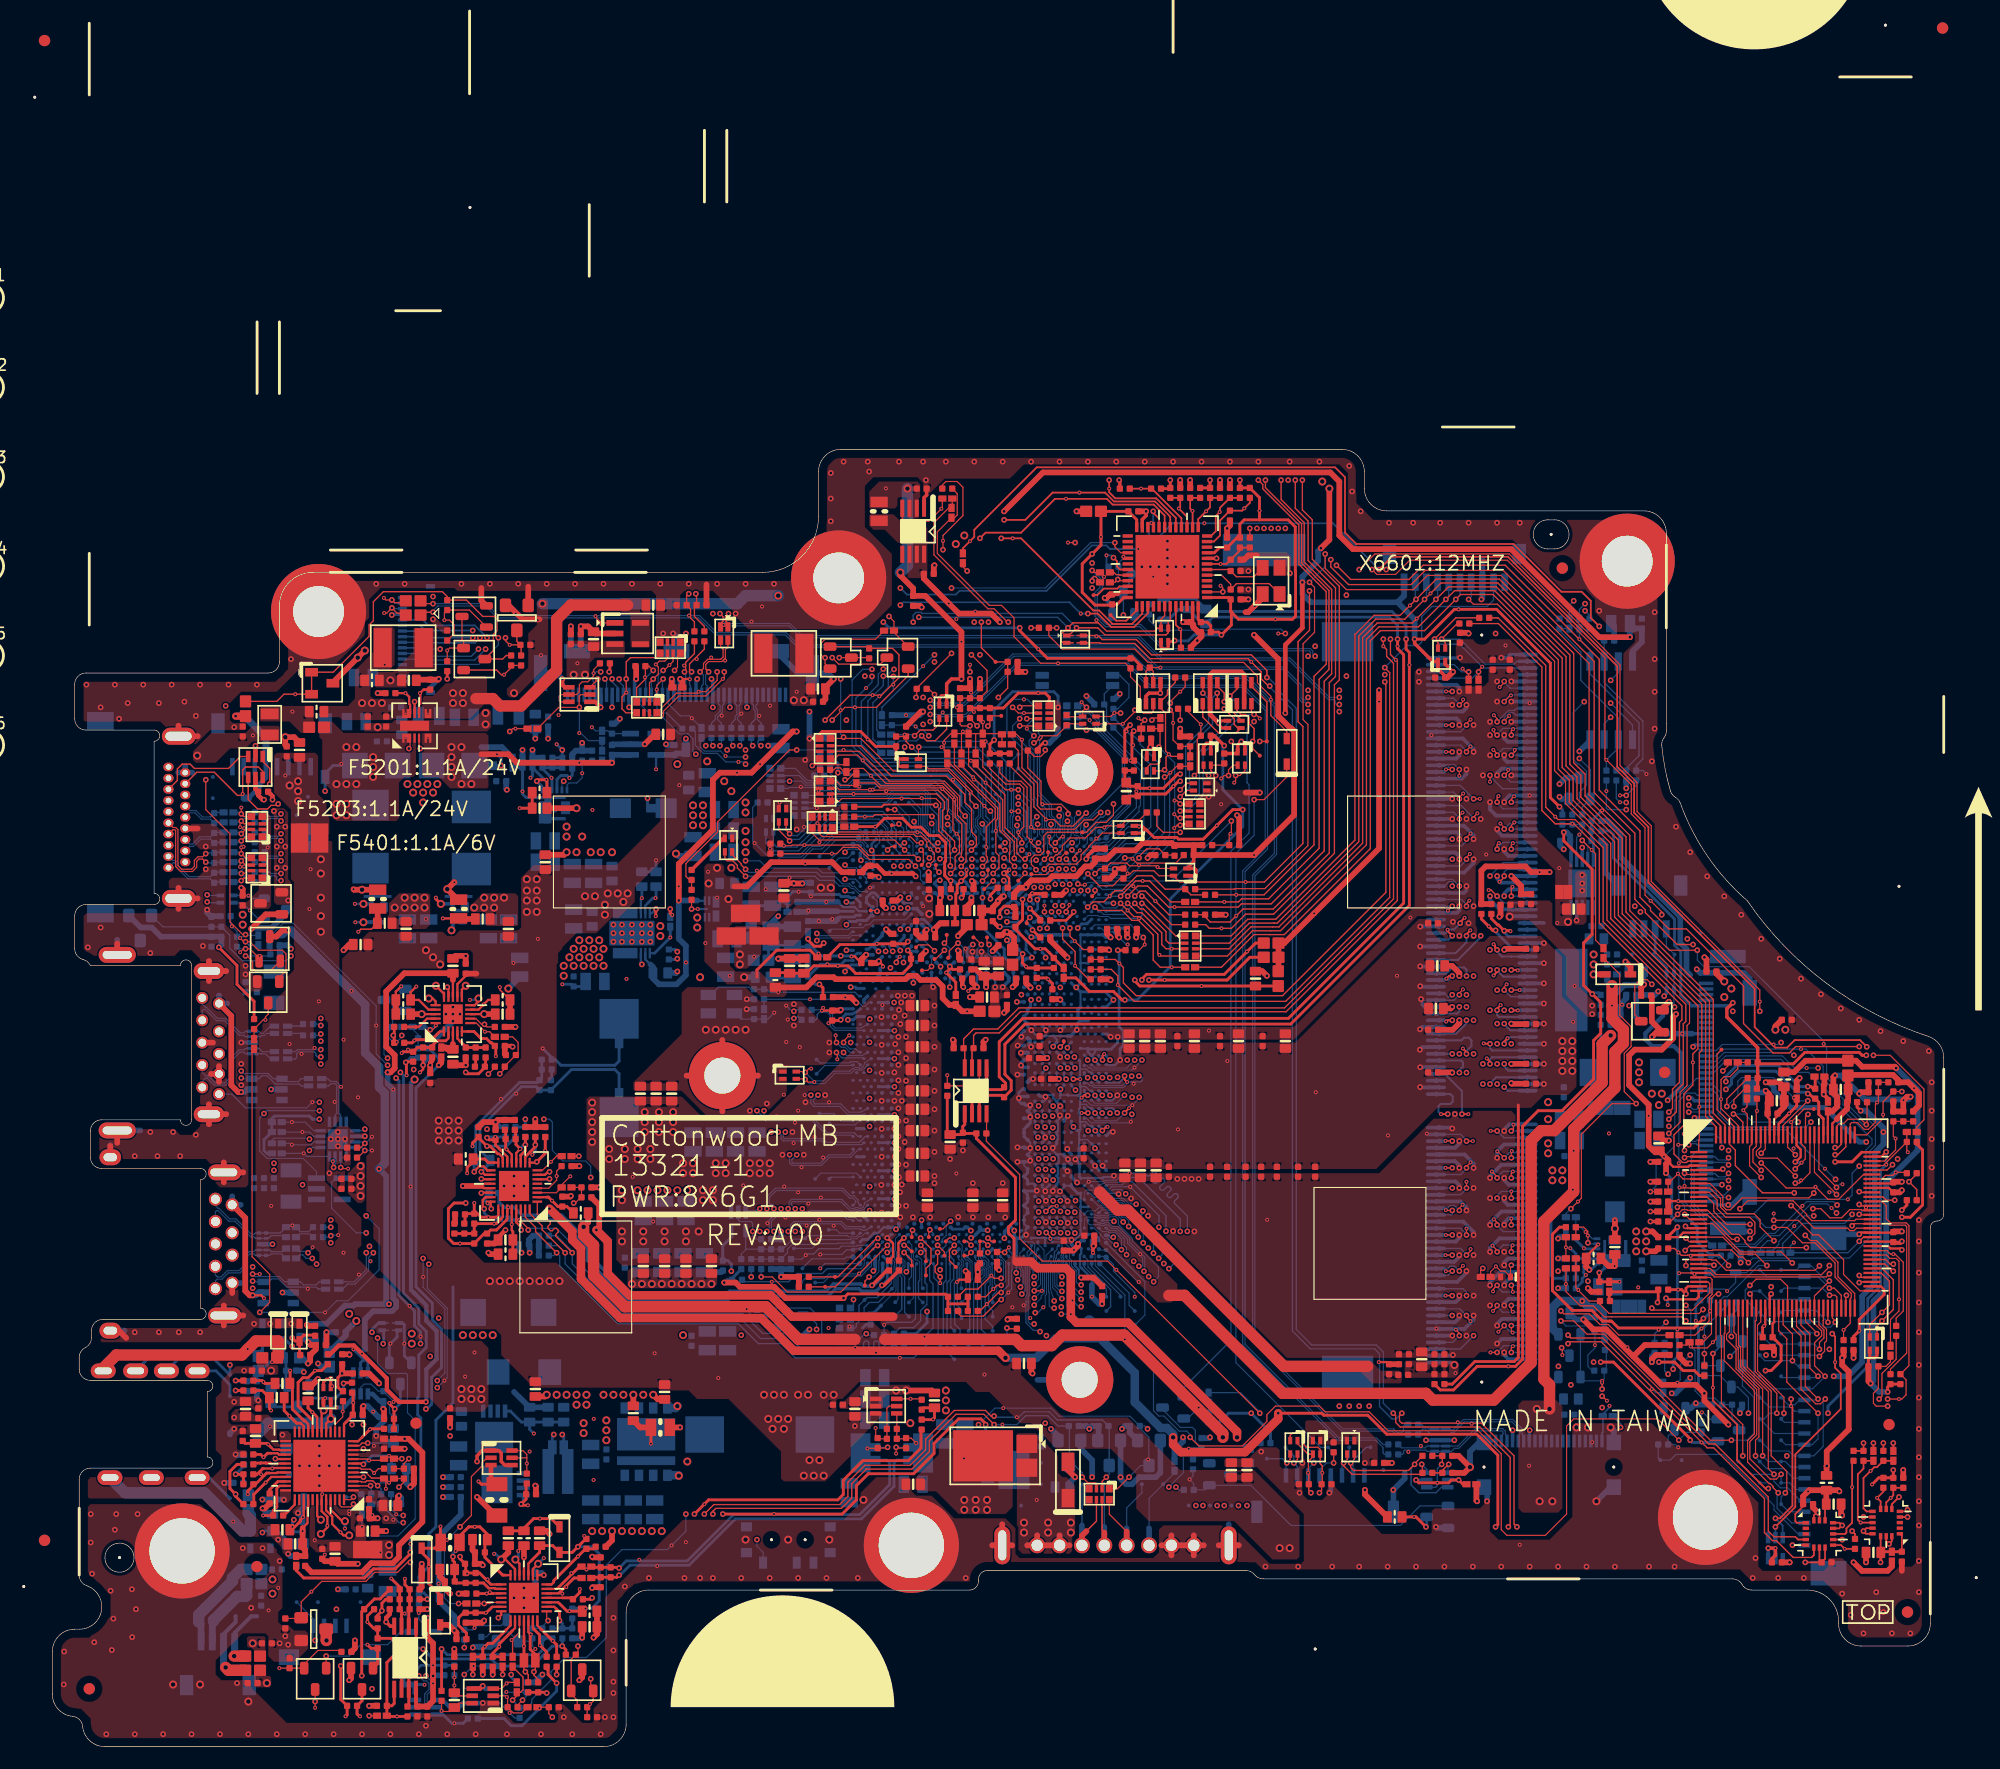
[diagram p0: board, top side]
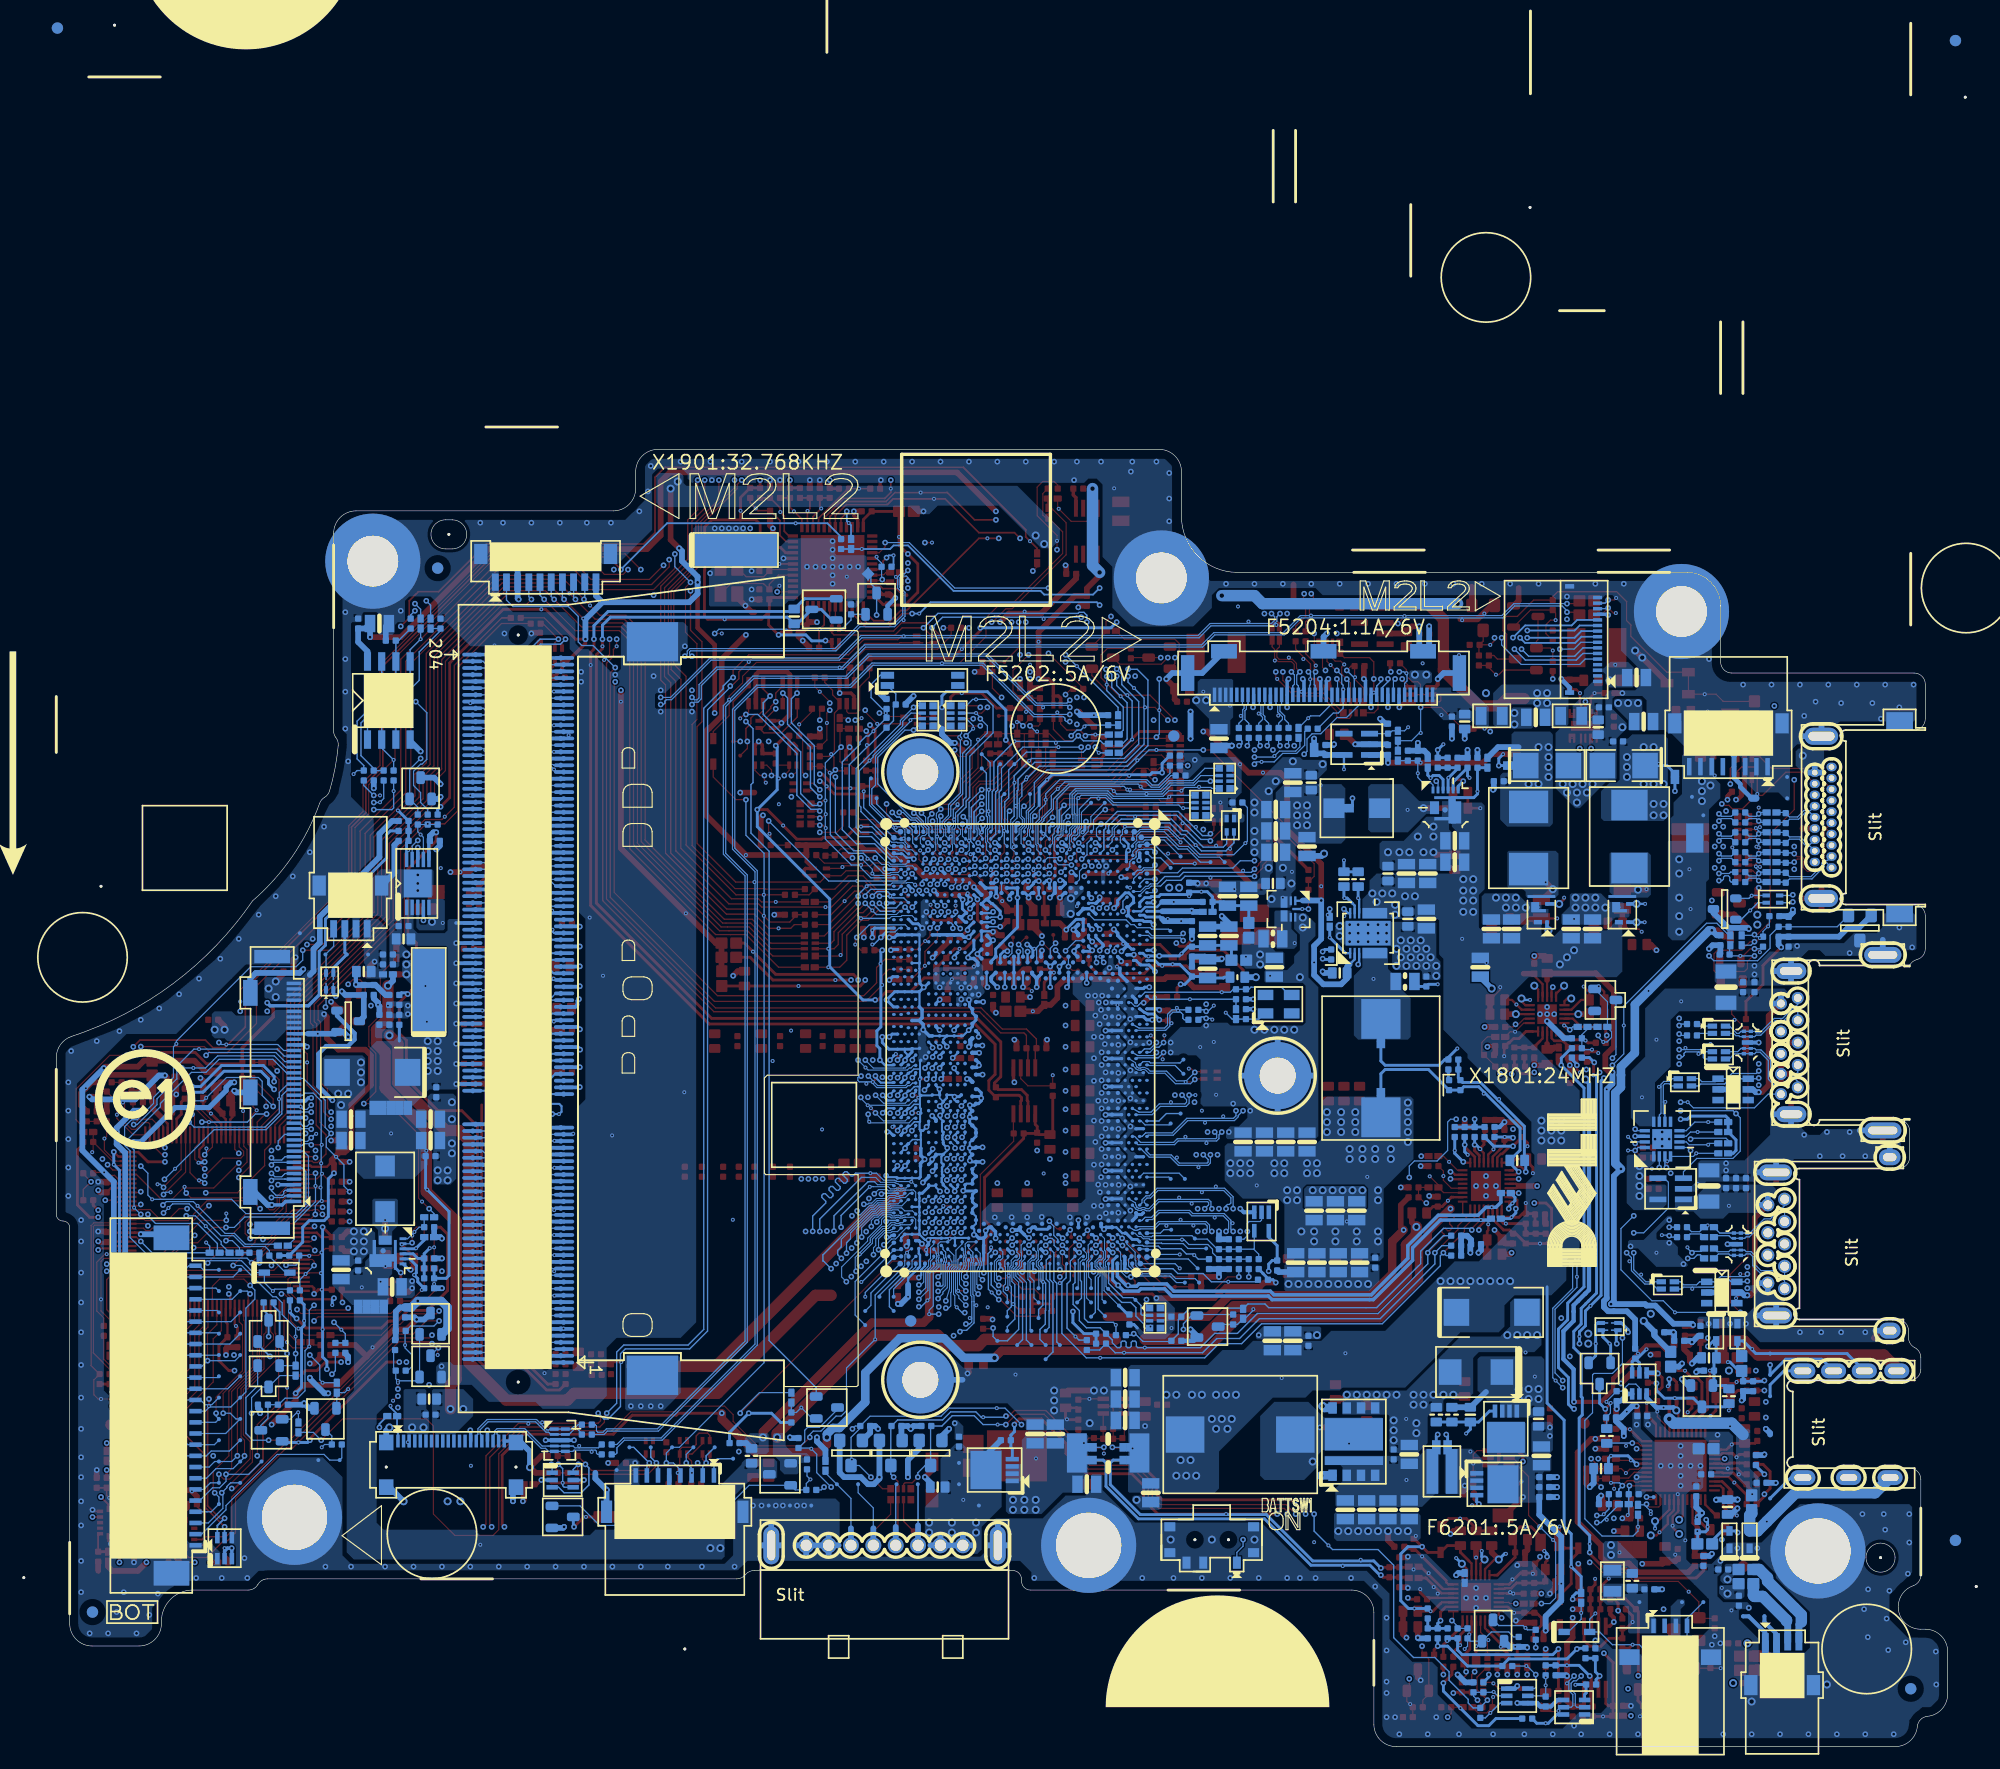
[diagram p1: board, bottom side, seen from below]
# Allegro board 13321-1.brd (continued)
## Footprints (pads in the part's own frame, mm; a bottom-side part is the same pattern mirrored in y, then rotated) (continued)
QFN48G7-G5D7H26
  rect 0.305x0.914 smd: 1(2.75,3.551) 12(-2.75,3.551) 25(-2.75,-3.551) 36(2.75,-3.551)
  rect 0.305x0.94 smd: 2(2.25,3.538) 3(1.75,3.538) 4(1.25,3.538) 5(0.75,3.538) 6(0.25,3.538) 7(-0.25,3.538) 8(-0.75,3.538) 9(-1.25,3.538) 10(-1.75,3.538) 11(-2.25,3.538) 26(-2.25,-3.538) 27(-1.75,-3.538) 28(-1.25,-3.538) 29(-0.75,-3.538) 30(-0.25,-3.538) 31(0.25,-3.538) 32(0.75,-3.538) 33(1.25,-3.538) 34(1.75,-3.538) 35(2.25,-3.538)
  rect 0.914x0.305 smd: 13(-3.551,2.75) 24(-3.551,-2.75) 37(3.551,-2.75) 48(3.551,2.75)
  rect 0.94x0.305 smd: 14(-3.538,2.25) 15(-3.538,1.75) 16(-3.538,1.25) 17(-3.538,0.75) 18(-3.538,0.25) 19(-3.538,-0.25) 20(-3.538,-0.75) 21(-3.538,-1.25) 22(-3.538,-1.75) 23(-3.538,-2.25) 38(3.538,-2.25) 39(3.538,-1.75) 40(3.538,-1.25) 41(3.538,-0.75) 42(3.538,-0.25) 43(3.538,0.25) 44(3.538,0.75) 45(3.538,1.25) 46(3.538,1.75) 47(3.538,2.25)
  rect 5.69x5.69 smd: 49(0,0)
QFN48J6-G465H40
  rect 0.203x0.965 smd: 1(2.2,3.025) 2(1.8,3.025) 3(1.4,3.025) 4(1,3.025) 5(0.6,3.025) 6(0.2,3.025) 7(-0.2,3.025) 8(-0.6,3.025) 9(-1,3.025) 10(-1.4,3.025) 11(-1.8,3.025) 12(-2.2,3.025) 25(-2.2,-3.025) 26(-1.8,-3.025) 27(-1.4,-3.025) 28(-1,-3.025) 29(-0.6,-3.025) 30(-0.2,-3.025) 31(0.2,-3.025) 32(0.6,-3.025) 33(1,-3.025) 34(1.4,-3.025) 35(1.8,-3.025) 36(2.2,-3.025)
  rect 0.965x0.203 smd: 13(-3.025,2.2) 14(-3.025,1.8) 15(-3.025,1.4) 16(-3.025,1) 17(-3.025,0.6) 18(-3.025,0.2) 19(-3.025,-0.2) 20(-3.025,-0.6) 21(-3.025,-1) 22(-3.025,-1.4) 23(-3.025,-1.8) 24(-3.025,-2.2) 37(3.025,-2.2) 38(3.025,-1.8) 39(3.025,-1.4) 40(3.025,-1) 41(3.025,-0.6) 42(3.025,-0.2) 43(3.025,0.2) 44(3.025,0.6) 45(3.025,1) 46(3.025,1.4) 47(3.025,1.8) 48(3.025,2.2)
  rect 4.648x4.648 smd: 49(0,0)
R402H14
  custom 0.14x0.14 smd: 1(0,0.445) 2(0,-0.445)
R402H16
  custom 0.14x0.14 smd: 1(0,0.445) 2(0,-0.445)
R603H22
  custom 0.197x0.197 smd: 1(0,0.66) 2(0,-0.66)
R603H24
  custom 0.197x0.197 smd: 1(0,0.66) 2(0,-0.66)
R805H24
  rect 1.549x0.94 smd: 1(0,0.838) 2(0,-0.838)
R1206H28
  rect 1.854x1.27 smd: 1(0,1.397) 2(0,-1.397)
R2512H32
  rect 3.505x1.778 smd: 1(0,2.794) 2(0,-2.794)
R3720H40
  rect 4.013x1.041 smd: 1(0,0.867) 2(0,-0.867)
SC70-5H44
  rect 0.406x1.219 smd: 1(0.65,0.826) 2(0,0.826) 3(-0.65,0.826) 4(-0.65,-0.826) 5(0.65,-0.826)
SC70-6H44
  rect 0.406x1.016 smd: 1(-0.65,-0.94) 2(0,-0.94) 3(0.65,-0.94) 4(0.65,0.94) 5(0,0.94) 6(-0.65,0.94)
SKT-HDMI23-178128-2
  oval 0.762x0.914 hole 0.508: 1(-4.5,6.08) 2(-4,7.58) 3(-3.5,6.08) 4(-3,7.58) 5(-2.5,6.08) 6(-2,7.58) 7(-1.5,6.08) 8(-1,7.58) 9(-0.5,6.08) 10(0,7.58) 11(0.5,6.08) 12(1,7.58) 13(1.5,6.08) 14(2,7.58) 15(2.5,6.08) 16(3,7.58) 17(3.5,6.08) 18(4,7.58) 19(4.5,6.08)
  oval 1.524x3.023 hole 0.813x2.362: 20(-7.25,6.98) 21(7.25,6.98)
  rect 1.6x2.388 smd: 22(-8.6,0) 23(8.6,0)
SKT-USB13-158172-1
  round 1.168 hole 0.813: 1(3.5,10.9) 2(1,10.9) 3(-1,10.9) 4(-3.5,10.9) 5(-4,9.4) 6(-2,9.4) 7(0,9.4) 8(2,9.4) 9(4,9.4)
  oval 1.422x2.972 hole 0.711x2.413: 10(6.4,10.15) 11(-6.4,10.15)
  oval 1.422x1.93 hole 0.711x1.219: 12(-7.75,0) 13(7.75,0)
SKT-USB14-160155-U
  round 1.067 hole 0.711: 1(3.5,9.1) 2(1,9.1) 3(-1,9.1) 4(-2.8,9.1) 5(-4,7.6) 6(-2,7.6) 7(0,7.6) 8(2,7.6) 9(4,7.6) D1(-4.6,9.1)
  oval 1.422x2.718 hole 0.711x2.007: 11(6.4,8.2) 12(-6.4,8.2)
  oval 1.422x3.327 hole 0.711x2.616: 13(7.85,0) 14(-7.85,0)
SMD-ARES4H18
  rect 0.356x0.66 smd: 1(-0.325,-0.599) 2(0.325,-0.599) 3(0.325,0.599) 4(-0.325,0.599)
SMD-ARES4H20
  rect 0.356x0.66 smd: 1(-0.325,-0.599) 2(0.325,-0.599) 3(0.325,0.599) 4(-0.325,0.599)
SMD-OSC2H56
  rect 1.194x0.61 smd: 1(-3.147,-0.457) 2(3.147,-0.457) 3(3.147,0.457) 4(-3.147,0.457)
SMPC4665-3P-UH48
  rect 1.626x1.854 smd: 1(1.066,0) 2(-1.066,0)
  rect 4.572x5.359 smd: 3(0,3.909)
SOD123FLAKH40
  rect 1.143x1.651 smd: A(0,1.622) K(0,-1.622)
SOD323AKH38
  rect 0.559x1.016 smd: A(0,1.143) K(0,-1.143)
SOD323AKH40
  rect 0.559x1.016 smd: A(0,1.143) K(0,-1.143)
SOD323AKH42
  rect 0.559x1.016 smd: A(0,1.143) K(0,-1.143)
SOD323AKH44
  rect 0.559x1.016 smd: A(0,1.143) K(0,-1.143)
SOD882-10D6-1H20
  custom 0.114x0.114 smd: 1(0,0.445) 2(0,-0.445)
SOD-523-4H28
  rect 0.559x0.864 smd: 1(0,0.778) 2(0,-0.778)
SOIC8-1H86
  rect 0.635x1.651 smd: 1(-1.905,-3.493) 2(-0.635,-3.493) 3(0.635,-3.493) 4(1.905,-3.493) 5(1.905,3.493) 6(0.635,3.493) 7(-0.635,3.493) 8(-1.905,3.493)
SON5Z3025H18
  rect 0.33x0.33 smd: 1(-0.923,-0.503) 4(0.713,-0.503)
  rect 0.406x0.711 smd: 2(-0.924,0.31)
  custom 0.229x0.229 smd: 3(0.417,0.254)
  rect 0.254x2.489 smd: 5(1.375,0)
SON14J3020-G2610H34
  rect 0.025x0.025 smd: 1(1.2,1.105) 6(-0.8,1.105) 9(-0.8,-1.105) 14(1.2,-1.105)
  custom 0.151x0.151 smd: 2(0.8,1.105) 7(-1.2,1.105) 8(-1.2,-1.105) 13(0.8,-1.105)
  rect 0.203x0.813 smd: 3(0.4,1.105) 4(0,1.105) 5(-0.4,1.105) 10(-0.4,-1.105) 11(0,-1.105) 12(0.4,-1.105)
  rect 2.591x0.889 smd: 15(0,0)
SOT23-2D4-312H44
  custom 0.191x0.191 smd: 1(-0.984,-0.953) 2(0.984,-0.953) 3(0,0.953)
SOT23-2D4-312H48
  custom 0.191x0.191 smd: 1(-0.984,-0.953) 2(0.984,-0.953) 3(0,0.953)
SOT23-2D8-123H52
  custom 0.254x0.254 smd: 1(0,1.118) 2(-1.016,-1.118) 3(1.016,-1.118)
SOT23-2D8-312H56
  custom 0.254x0.254 smd: 1(-1.016,-1.118) 2(1.016,-1.118) 3(0,1.118)
SOT23CBE2D4H44
  custom 0.191x0.191 smd: B(-0.984,-0.953) C(0,0.953) E(0.984,-0.953)
SOT23CBE2D6H46
  custom 0.165x0.165 smd: B(-0.95,-1.092) C(0,1.092) E(0.95,-1.092)
SOT23DGS2D4H44
  custom 0.191x0.191 smd: D(0,0.953) G(-0.984,-0.953) S(0.984,-0.953)
SOT23DGS2D4H48
  custom 0.191x0.191 smd: D(0,0.953) G(-0.984,-0.953) S(0.984,-0.953)
SOT23DGS2D8H56
  custom 0.254x0.254 smd: D(0,1.118) G(-1.016,-1.118) S(1.016,-1.118)
SOT-6H58
  rect 0.584x1.016 smd: 1(-0.953,-1.346) 2(0,-1.346) 3(0.953,-1.346) 4(0.953,1.346) 5(0,1.346) 6(-0.953,1.346)
SOT-23-5H51
  rect 0.508x1.524 smd: 1(-0.95,-1.143) 2(0,-1.143) 3(0.95,-1.143) 4(0.95,1.143) 5(-0.95,1.143)
SOT-23-5H56
  rect 0.508x1.524 smd: 1(-0.95,-1.143) 2(0,-1.143) 3(0.95,-1.143) 4(0.95,1.143) 5(-0.95,1.143)
SOT-23-5H58
  rect 0.508x1.524 smd: 1(-0.95,-1.143) 2(0,-1.143) 3(0.95,-1.143) 4(0.95,1.143) 5(-0.95,1.143)
SOT-23-9H44
  custom 0.178x0.178 smd: 1(-0.95,-0.999) 2(0.95,-0.999) 3(0,0.999)
SOT-23-10H44
  rect 0.762x1.143 smd: 1(-0.984,-0.953) 2(0.984,-0.953) 3(0,0.953)
SOT-363H44
  rect 0.406x1.016 smd: 1(-0.65,-0.94) 2(0,-0.94) 3(0.65,-0.94) 4(0.65,0.94) 5(0,0.94) 6(-0.65,0.94)
SPR7732H229
  rect 7.391x2.896 smd: 1(-1.6,0)
STF237R125H42
  round 6.02 hole 3.175: 1(0,0)
TPAD14-OP
  round 0.356 smd: 1(0,0)
TSOIC8H48
  rect 0.356x1.524 smd: 1(-0.975,-2.819) 2(-0.325,-2.819) 3(0.325,-2.819) 4(0.974,-2.819) 5(0.975,2.819) 6(0.325,2.819) 7(-0.325,2.819) 8(-0.975,2.819)
unnamed
  round 1.016 smd: (0,0)

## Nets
3V5V_CT1: C3602.1 U3601.12
3V5V_CT2: C3603.1 U3601.10
3V5V_S0_ON: R3609.2 U3601.3 U3601.5
3V_5V_EN: D3602.1 PR4506.1 PR4515.1 R3602.1 R3603.1
3V_5V_POK: PR4534.2 PU4503.7 R1728.2
3V_5V_POK#: Q1701.5 Q1701.6 R1726.1
3V_5V_POK_C: Q1701.2 R1727.2 R1728.1 R1729.1
3V_FEEDBACK: PG4535.2 PR4512.1 PR4535.1
5V_HDMI_R_S5: F5401.1 R5409.2 R5423.2
5V_HDMI_S5: C5401.1 F5401.2 HDMI1.18
5V_PWR_2: PC4524.1 PU4503.13 R2915.1
5V_S0: C3601.1 C5605.1 C5606.1 D5401.3 EC8615.1 EC8616.1 F5203.1 F6201.1 HDD1.8 HDD1.9 HDD1.10 HDD1.11 Q5403.G R2612.1 R2703.2 R2704.1 R5233.1 R5413.1 R5423.1 R6205.1 R6216.1 U3601.13 U3601.14
5V_S5: C3502.1 C3504.1 EC8612.1 EC8614.1 IOBD1.37 IOBD1.38 IOBD1.39 IOBD1.40 PC4419.1 PC4426.1 PC4518.1 PC4705.1 PG4532.1 PL4501.2 PR4203.1 PR4437.1 PR4460.1 PR4461.1 PR4624.2 PR4917.2 PT4502.1 PU4402.8 PU4701.2 Q6201.E R1208.1 R3504.1 R3505.1 R3507.1 R5409.1 U2101.1 U3502.5 U3503.1 U3601.1 U3601.2 U3601.4
+3V_1D5V_AVDD: C2715.1 HDA27.40 R2705.2 R2710.2
+3V_AVDD: C2701.1 C2716.1 C2717.1 C2719.1 HDA27.1 HDA27.9 HDA27.36 R2701.2 R2722.2 R2918.1
+5V_AVDD: C2710.1 C2711.1 HDA27.26 R2703.1
+5V_KB_BL: AFTP6248.1 C6202.1 F6201.2 KBLIT1.1 R6205.2
+5V_PVDD: C2706.1 C2707.1 C2708.1 C2709.1 HDA27.41 HDA27.46 R2704.2
+V1.05A_AOSCSUS: CPU1.AB8 TP2109.1
+V1.05A_SUS_PCH: CPU1.AD8 CPU1.AD10 TP2106.1
+V1.05A_USB2SUS: CPU1.AH13 TP2108.1
+V1.05A_VCCUSB3SUS: CPU1.J13 TP2107.1
+V1.05DX_MODPHY_PCH: C1101.1 C1102.1 CPU1.K9 CPU1.L10 CPU1.M9 R1101.2
+V1.05S_AIDLE: C2105.1 CPU1.N8 CPU1.P9 R2105.2
+V1.05S_APLLOPI: C1109.1 C1110.1 C1124.1 CPU1.AA21 CPU1.W21 R1102.2
+V1.05S_ASATA3PLL: C1105.1 C1106.1 C1107.1 CPU1.B11 L1102.2 R1904.2 R1906.2
+V1.05S_AUSB3PLL: C1103.1 C1104.1 C1123.1 CPU1.B18 CPU1.B27 L1101.2 R1601.1
+V1.05S_AXCK_DCB: C1111.1 C1112.1 C1125.1 CPU1.J18 CPU1.K19 L1103.2
+V1.05S_AXCK_LCPLL: C1113.1 C1114.1 CPU1.A20 L1104.2 R1803.2
+V1.05S_CORE_PCH: C1117.1 C1118.1 C1119.1 CPU1.AE8 CPU1.AF22 CPU1.H11 CPU1.H15 CPU1.J11 R1105.2
+V1.05S_SSCF100: C2137.1 CPU1.J17 R2117.2
+V1.05S_SSCFF: C2138.1 CPU1.R21 CPU1.T21 R2118.2
+V3.3A_1.5A_HDA: C2116.1 CPU1.AH14 R2108.2
+V3.3A_DSW_P: C2101.1 C2136.1 CPU1.AH10 R2101.2
+V3.3A_PSUS: C1108.1 CPU1.AA9 CPU1.AC9 CPU1.AE20 CPU1.AE21 R1103.2
+V3.3S_1.8S_LPSS_SDIO: C2104.1 CPU1.T9 CPU1.U8 R2103.1
+V3.3S_PCORE: C2123.1 CPU1.V8 CPU1.W9 R2112.2
+VCCIOA_OUT: CPU1.E20 R801.1
+VCCRTCEXT: C2110.1 CPU1.AE7
GND: AFTP2604.1 AFTP4204.1 AFTP4205.1 AFTP4308.1 AFTP4309.1 AFTP4310.1 AFTP6226.1 AFTP6235.1 BATSW1.2 BATSW1.3 BATSW1.4 BATSW1.5 BATSW1.6 BATSW1.7 BATT1.7 BATT1.8 BATT1.9 BATT1.10 C701.2 C702.2 C703.2 C1001.2 C1002.2 C1003.2 C1004.2 C1005.2 C1006.2 C1017.2 C1018.2 C1019.2 C1020.2 C1101.2 C1102.2 C1103.2 C1104.2 C1105.2 C1106.2 C1107.2 C1108.2 C1109.2 C1110.2 C1111.2 C1112.2 C1113.2 C1114.2 C1115.2 C1116.2 C1117.2 C1118.2 C1119.2 C1120.2 C1121.2 C1122.2 C1123.2 C1124.2 C1125.2 C1201.2 C1202.2 C1203.2 C1204.2 C1205.2 C1206.2 C1207.2 C1208.2 C1209.2 C1210.2 C1211.2 C1212.2 C1213.2 C1214.2 C1215.2 C1216.2 C1218.2 C1220.2 C1221.2 C1222.2 C1701.2 C1801.1 C1802.1 C1901.2 C1902.2 C1903.1 C1904.1 C2104.2 C2105.2 C2109.2 C2110.2 C2114.2 C2116.2 C2123.2 C2128.2 C2135.2 C2136.2 C2137.2 C2138.2 C2141.2 C2142.2 C2147.2 C2401.2 C2406.2 C2407.2 C2408.2 C2409.2 C2410.2 C2411.2 C2412.2 C2413.2 C2415.1 C2416.2 C2418.2 C2421.2 C2422.2 C2501.2 C2502.2 C2503.2 C2601.2 C2602.2 C2603.2 C2604.2 C2605.2 C2608.2 C2609.2 C2610.2 C2701.2 C2704.1 C2706.2 C2707.2 C2708.2 C2709.2 C2716.2 C2717.2 C2718.2 C2719.2 C2723.1 C2901.2 C3404.2 C3409.2 C3502.2 C3503.2 C3504.2 C3505.2 C3521.2 C3522.2 C3601.2 C3602.2 C3603.2 C3605.2 C3801.2 C3802.2 C5202.2 C5203.2 C5204.2 C5205.2 C5206.2 C5208.2 C5209.1 C5211.2 C5212.2 C5214.2 C5215.2 C5401.2 C5605.2 C5606.2 C6201.2 C6202.2 C6401.2 C6402.2 C6601.2 C6602.2 C6603.2 C6604.2 C6605.2 C6606.2 C6607.2 C6608.2 C6609.2 C6610.2 C6611.2 C6701.2 C6702.2 C6703.2 CPU1.A11 CPU1.A14 CPU1.A18 CPU1.A24 CPU1.A28 CPU1.A32 CPU1.A36 CPU1.A40 CPU1.A44 CPU1.A48 CPU1.A52 CPU1.A56 CPU1.AA1 CPU1.AA58 CPU1.AB7 CPU1.AB10 CPU1.AB20 CPU1.AB22 CPU1.AC61 CPU1.AD3 CPU1.AD21 CPU1.AD63 CPU1.AE5 CPU1.AE10 CPU1.AE58 CPU1.AF11 CPU1.AF12 CPU1.AF14 CPU1.AF15 CPU1.AF17 CPU1.AF18 CPU1.AG1 CPU1.AG11 CPU1.AG21 CPU1.AG23 CPU1.AG60 CPU1.AG61 CPU1.AG62 CPU1.AG63 CPU1.AH16 CPU1.AH17 CPU1.AH19 CPU1.AH20 CPU1.AH22 CPU1.AH24 CPU1.AH28 CPU1.AH30 CPU1.AH32 CPU1.AH34 CPU1.AH36 CPU1.AH38 CPU1.AH40 CPU1.AH42 CPU1.AH44 CPU1.AH46 CPU1.AH49 CPU1.AH51 CPU1.AH53 CPU1.AH55 CPU1.AH57 CPU1.AJ13 CPU1.AJ14 CPU1.AJ23 CPU1.AJ25 CPU1.AJ27 CPU1.AJ29 CPU1.AJ35 CPU1.AJ39 CPU1.AJ41 CPU1.AJ43 CPU1.AJ45 CPU1.AJ47 CPU1.AJ50 CPU1.AJ52 CPU1.AJ54 CPU1.AJ56 CPU1.AJ58 CPU1.AJ60 CPU1.AJ63 CPU1.AK3 CPU1.AK23 CPU1.AK52 CPU1.AL10 CPU1.AL13 CPU1.AL17 CPU1.AL20 CPU1.AL22 CPU1.AL23 CPU1.AL26 CPU1.AL29 CPU1.AL31 CPU1.AL33 CPU1.AL36 CPU1.AL39 CPU1.AL40 CPU1.AL45 CPU1.AL46 CPU1.AL51 CPU1.AL52 CPU1.AL54 CPU1.AL57 CPU1.AL60 CPU1.AL61 CPU1.AM1 CPU1.AM17 CPU1.AM23 CPU1.AM31 CPU1.AM52 CPU1.AN7 CPU1.AN17 CPU1.AN23 CPU1.AN31 CPU1.AN32 CPU1.AN35 CPU1.AN36 CPU1.AN39 CPU1.AN40 CPU1.AN42 CPU1.AN43 CPU1.AN45 CPU1.AN46 CPU1.AN48 CPU1.AN49 CPU1.AN51 CPU1.AN52 CPU1.AN60 CPU1.AN63 CPU1.AP3 CPU1.AP10 CPU1.AP17 CPU1.AP20 CPU1.AP22 CPU1.AP23 CPU1.AP26 CPU1.AP29 CPU1.AP31 CPU1.AP38 CPU1.AP39 CPU1.AP48 CPU1.AP52 CPU1.AP54 CPU1.AP57 CPU1.AR5 CPU1.AR11 CPU1.AR15 CPU1.AR17 CPU1.AR23 CPU1.AR31 CPU1.AR33 CPU1.AR39 CPU1.AR43 CPU1.AR49 CPU1.AR52 CPU1.AT13 CPU1.AT35 CPU1.AT37 CPU1.AT40 CPU1.AT42 CPU1.AT43 CPU1.AT46 CPU1.AT49 CPU1.AT61 CPU1.AT62 CPU1.AT63 CPU1.AU1 CPU1.AU16 CPU1.AU18 CPU1.AU20 CPU1.AU22 CPU1.AU24 CPU1.AU26 CPU1.AU28 CPU1.AU30 CPU1.AU33 CPU1.AU51 CPU1.AU53 CPU1.AU55 CPU1.AU57 CPU1.AU59 CPU1.AV8 CPU1.AV14 CPU1.AV16 CPU1.AV20 CPU1.AV24 CPU1.AV28 CPU1.AV33 CPU1.AV34 CPU1.AV36 CPU1.AV39 CPU1.AV41 CPU1.AV43 CPU1.AV46 CPU1.AV49 CPU1.AV51 CPU1.AV55 CPU1.AV59 CPU1.AW4 CPU1.AW16 CPU1.AW24 CPU1.AW33 CPU1.AW35 CPU1.AW37 CPU1.AW40 CPU1.AW42 CPU1.AW44 CPU1.AW47 CPU1.AW50 CPU1.AW51 CPU1.AW59 CPU1.AW60 CPU1.AY4 CPU1.AY6 CPU1.AY11 CPU1.AY16 CPU1.AY18 CPU1.AY22 CPU1.AY24 CPU1.AY26 CPU1.AY30 CPU1.AY33 CPU1.AY51 CPU1.AY53 CPU1.AY57 CPU1.AY59 CPU1.B4 CPU1.B20 CPU1.B24 CPU1.B26 CPU1.B28 CPU1.B32 CPU1.B36 CPU1.B40 CPU1.B44 CPU1.B48 CPU1.B52 CPU1.B56 CPU1.B60 CPU1.C11 CPU1.C14 CPU1.C18 CPU1.C20 CPU1.C25 CPU1.C27 CPU1.C38 CPU1.C39 CPU1.C57 CPU1.D2 CPU1.D5 CPU1.D8 CPU1.D12 CPU1.D14 CPU1.D18 CPU1.D21 CPU1.D23 CPU1.D25 CPU1.D26 CPU1.D27 CPU1.D29 CPU1.D30 CPU1.D31 CPU1.D33 CPU1.D34 CPU1.D35 CPU1.D37 CPU1.D38 CPU1.D39 CPU1.D41 CPU1.D42 CPU1.D43 CPU1.D45 CPU1.D46 CPU1.D47 CPU1.D49 CPU1.D50 CPU1.D51 CPU1.D53 CPU1.D54 CPU1.D55 CPU1.D57 CPU1.D59 CPU1.D62 CPU1.D63 CPU1.E11 CPU1.E17 CPU1.F20 CPU1.F26 CPU1.F30 CPU1.F34 CPU1.F38 CPU1.F42 CPU1.F46 CPU1.F50 CPU1.F54 CPU1.F58 CPU1.F61 CPU1.G3 CPU1.G5 CPU1.G6 CPU1.G8 CPU1.G18 CPU1.G22 CPU1.H13 CPU1.H17 CPU1.H57 CPU1.J10 CPU1.J22 CPU1.J59 CPU1.J63 CPU1.K1 CPU1.K12 CPU1.L7 CPU1.L13 CPU1.L15 CPU1.L17 CPU1.L18 CPU1.L20 CPU1.L58 CPU1.L61 CPU1.M22 CPU1.N3 CPU1.N10 CPU1.N21 CPU1.P22 CPU1.P59 CPU1.P62 CPU1.P63 CPU1.R8 CPU1.R10 CPU1.R22 CPU1.T1 CPU1.T58 CPU1.U9 CPU1.U20 CPU1.U22 CPU1.U61 CPU1.V3 CPU1.V7 CPU1.V10 CPU1.V23 CPU1.V58 CPU1.W20 CPU1.W22 CPU1.Y10 CPU1.Y59 CPU1.Y63 D2601.A D4301.1 D4302.1 D4303.1 DB1.1 DB1.3 DB1.11 DB1.12 DCIN1.1 DCIN1.2 DCIN1.3 DCIN1.9 DCIN1.10 DIMM1.2 DIMM1.3 DIMM1.8 DIMM1.9 DIMM1.11 DIMM1.13 DIMM1.14 DIMM1.19 DIMM1.20 DIMM1.25 DIMM1.26 DIMM1.28 DIMM1.31 DIMM1.32 DIMM1.37 DIMM1.38 DIMM1.43 DIMM1.44 DIMM1.46 DIMM1.48 DIMM1.49 DIMM1.54 DIMM1.55 DIMM1.60 DIMM1.61 DIMM1.63 DIMM1.65 DIMM1.66 DIMM1.71 DIMM1.72 DIMM1.127 DIMM1.128 DIMM1.133 DIMM1.134 DIMM1.136 DIMM1.138 DIMM1.139 DIMM1.144 DIMM1.145 DIMM1.150 DIMM1.151 DIMM1.153 DIMM1.155 DIMM1.156 DIMM1.161 DIMM1.162 DIMM1.167 DIMM1.168 DIMM1.170 DIMM1.172 DIMM1.173 DIMM1.178 DIMM1.179 DIMM1.184 DIMM1.185 DIMM1.187 DIMM1.189 DIMM1.190 DIMM1.195 DIMM1.196 DIMM1.205 DIMM1.206 EC701.2 EC702.2 EC1701.1 EC1702.2 EC1703.2 EC1704.2 EC1705.2 EC1706.2 EC1707.2 EC1801.2 EC1802.2 EC1901.1 EC2501.2 EC2502.2 EC2503.2 EC2701.2 EC2703.2 EC2704.2 EC2705.2 EC2706.2 EC2707.2 EC2708.2 EC2709.2 EC2901.2 EC2902.2 EC2903.2 EC2904.2 EC4201.2 EC4202.2 EC4301.2 EC4302.2 EC4303.2 EC4304.2 EC4305.1 EC4602.2 EC4701.2 EC4702.2 EC5205.2 EC5206.2 EC5207.2 EC5210.2 EC5211.2 EC6201.2 EC6202.2 EC6203.2 EC6204.2 EC8601.2 EC8602.2 EC8603.2 EC8604.2 EC8605.2 EC8606.2 EC8607.2 EC8608.2 EC8609.2 EC8610.2 EC8611.2 EC8612.2 EC8613.2 EC8614.2 EC8615.2 EC8616.2 EC8617.2 EC8618.2 EC8619.2 EC8620.2 EC8621.2 EC8622.2 EC8623.2 EC8624.2 EC8625.2 EC8626.2 EC8627.2 EC8628.2 EC8629.2 EC8630.2 EC8631.2 EC8632.2 EC8633.2 EC8634.2 EC8635.2 EC8636.2 EC8637.2 EC8638.2 ED1217.2 ED2901.1 ED2902.1 ED2903.1 ED2904.1 ED2905.1 ED2906.1 EU3401.3 EU3402.2 EU3403.3 EU3404.2 FAN1.2 FAN1.5 FAN1.6 G1901.1 H1.1 H2.1 H3.1 H4.1 H5.1 H6.1 HDA27.4 HDA27.49 HDD1.3 HDD1.4 HDD1.5 HDD1.6 HDD1.14 HDD1.17 HDD1.20 HDD1.21 HDD1.22 HDD1.23 HDD1.24 HDMI1.2 HDMI1.5 HDMI1.8 HDMI1.11 HDMI1.17 HDMI1.20 HDMI1.21 HDMI1.22 HDMI1.23 HOMBD1.13 HOMBD1.16 HOMBD1.17 HOMBD1.18 HS1.1 HS2.1 HS3.1 IOBD1.1 IOBD1.4 IOBD1.16 IOBD1.19 IOBD1.29 IOBD1.41 IOBD1.42 IOBD1.43 IOBD1.44 IOBD1.45 KB1.1 KB1.27 KB1.28 KBC24.5 KBC24.18 KBC24.45 KBC24.78 KBC24.89 KBC24.116 KBLIT1.5 KBLIT1.6 LCD1.8 LCD1.11 LCD1.14 LCD1.17 LCD1.21 LCD1.28 LCD1.29 LCD1.32 LCD1.34 LCD1.41 LCD1.42 LCD1.43 LCD1.44 LCD1.45 LIDSW1.1 PC4202.2 PC4203.2 PC4204.2 PC4205.2 PC4206.2 PC4403.2 PC4405.2 PC4406.2 PC4407.2 PC4408.2 PC4409.2 PC4411.2 PC4413.2 PC4415.2 PC4417.2 PC4419.2 PC4420.1 PC4422.2 PC4425.2 PC4426.2 PC4427.2 PC4430.2 PC4431.2 PC4434.2 PC4435.2 PC4436.2 PC4437.2 PC4438.2 PC4439.2 PC4440.2 PC4441.2 PC4442.2 PC4509.2 PC4517.2 PC4518.2 PC4519.2 PC4520.2 PC4524.2 PC4525.2 PC4526.2 PC4527.2 PC4528.2 PC4529.2 PC4530.2 PC4531.2 PC4536.2 PC4601.2 PC4602.2 PC4603.1 PC4605.2 PC4606.1 PC4607.2 PC4701.2 PC4702.2 PC4703.2 PC4704.2 PC4705.2 PC4708.2 PC4709.2 PC4710.2 PC4711.2 PC4714.2 PC4715.2 PC4716.2 PC4719.2 PC4720.2 PC4721.2 PC4722.2 PC4724.2 PC4725.2 PC4726.2 PC4727.2 PC4728.2 PC4729.2 PC4730.2 PC4731.2 PC4732.2 PC4733.2 PC4734.2 PC4735.2 PC4736.2 PC4737.2 PC4738.2 PC4739.2 PC4740.2 PC4741.2 PC4742.2 PC4743.2 PC4801.2 PC4803.2 PC4804.2 PC4805.2 PC4807.2 PC4808.2 PC4809.2 PC4810.2 PC4811.2 PC4812.2 PC4813.2 PC4901.2 PC4902.2 PC4903.2 PC4904.2 PC4905.2 PC4906.2 PC4907.2 PC4908.2 PC4909.2 PC4910.2 PC4911.2 PC4913.2 PC4914.2 PC4915.2 PC4916.2 PC4918.2 PC5101.2 PC5108.2 PC5109.2 PD4201.A PD4203.1 PD4204.3 PD4302.A PQ4202.E PQ4401.S PQ4405.1 PQ4405.4 PQ4406.S PQ4407.1 PQ4407.4 PQ4411.1 PQ4411.4 PQ4413.1 PQ4413.4 PR4202.2 PR4208.2 PR4402.1 PR4404.2 PR4405.1 PR4406.1 PR4429.2 PR4433.2 PR4440.2 PR4445.2 PR4447.2 PR4451.2 PR4471.2 PR4502.2 PR4517.2 PR4523.2 PR4526.2 PR4530.2 PR4531.2 PR4601.2 PR4607.2 PR4608.2 PR4609.2 PR4612.1 PR4626.2 PR4802.2 PR4803.2 PR4805.2 PR4904.2 PR4906.1 PT4501.2 PT4502.2 PT4702.2 PU4401.22 PU4402.4 PU4404.1 PU4404.2 PU4406.5 PU4406.6 PU4406.7 PU4501.3 PU4502.3 PU4503.21 PU4601.19 PU4601.22 PU4601.29 PU4601.33 PU4701.3 PU4701.9 PU4801.9 PU4901.9 PU4902.4 PU4902.8 PU4902.11 PU5101.2 Q1701.1 Q1701.4 Q1901.S Q2401.S Q2403.S Q2404.C Q2505.S Q3601.1 Q3601.4 Q5403.S Q5404.S Q6202.S Q6205.S Q6701.1 Q6701.4 R402.2 R405.2 R406.2 R407.1 R408.1 R409.1 R601.1 R602.2 R603.1 R604.2 R605.2 R606.2 R709.2 R712.2 R901.2 R1201.2 R1202.2 R1204.2 R1602.2 R1715.2 R1717.2 R1721.2 R1725.1 R1902.2 R1913.1 R1920.1 R2003.2 R2435.1 R2442.2 R2447.2 R2449.1 R2504.2 R2611.2 R2706.2 R2717.2 R3024.1 R3503.2 R3506.1 R3508.1 R3602.2 R3703.2 R3707.2 R3709.2 R3711.2 R4301.2 R5202.2 R5410.2 R5412.2 R5413.2 R5418.1 R6208.2 R6606.2 R6609.1 R6611.1 R6613.1 R6615.1 R6617.1 R6619.1 R6627.1 RN1703.1(A) RN1703.2(A) RN1803.1(A) RN1803.2(A) RN1804.1(A) RN1804.2(A) RN5203.1(A) RN5203.2(A) RN5203.3(A) RN5203.4(A) SPI25.4 SPK1.5 SPK1.6 SPR1.1 SPR2.1 TC1201.2 THM261.5 TP1.5 TP1.9 TP1.10 TP6604.1 U701.3 U2101.8 U2901.1 U3502.2 U3503.14 U3503.17 U3601.11 U3601.15 U3801.1 U5201.2 U5602.3 U5602.8 U6601.8 U6601.23 U6601.35 U6601.47 U6601.49 U6602.5 U6602.10 U6602.12 U6602.13 U6602.15 U6602.16 U6701.5 U6701.10 U6701.12 U6701.13 U6701.15 U6701.16 USB1.4 USB1.7 USB1.11 USB1.12 USB1.13 USB1.14 USB2.4 USB2.7 USB2.10 USB2.11 USB2.12 USB2.13 X6601.2 X6601.4
V3D3_STB: HDA27.20 R2712.1
VBAT: C2404.1 C2405.1 KBC24.102 R2402.1 R2404.1 R2405.1
VCC_BOOTR1_R: PC4706.1 PR4703.2
VCC_CORE: CPU1.AB57 CPU1.AD57 CPU1.AG57 CPU1.C24 CPU1.C28 CPU1.C32 CPU1.C36 CPU1.C40 CPU1.C44 CPU1.C48 CPU1.C52 CPU1.C56 CPU1.E23 CPU1.E25 CPU1.E27 CPU1.E29 CPU1.E31 CPU1.E33 CPU1.E35 CPU1.E37 CPU1.E39 CPU1.E41 CPU1.E43 CPU1.E45 CPU1.E47 CPU1.E49 CPU1.E51 CPU1.E53 CPU1.E55 CPU1.E57 CPU1.F24 CPU1.F28 CPU1.F32 CPU1.F36 CPU1.F40 CPU1.F44 CPU1.F48 CPU1.F52 CPU1.F56 CPU1.F59 CPU1.G23 CPU1.G25 CPU1.G27 CPU1.G29 CPU1.G31 CPU1.G33 CPU1.G35 CPU1.G37 CPU1.G39 CPU1.G41 CPU1.G43 CPU1.G45 CPU1.G47 CPU1.G49 CPU1.G51 CPU1.G53 CPU1.G55 CPU1.G57 CPU1.H23 CPU1.J23 CPU1.K23 CPU1.K57 CPU1.L22 CPU1.M23 CPU1.M57 CPU1.P57 CPU1.U57 CPU1.W57 EC4702.1 PC4709.1 PC4710.1 PC4711.1 PC4714.1 PC4715.1 PC4716.1 PC4719.1 PC4720.1 PC4721.1 PC4722.1 PC4724.1 PC4725.1 PC4726.1 PC4727.1 PC4728.1 PC4729.1 PC4730.1 PC4731.1 PC4732.1 PC4733.1 PC4734.1 PC4735.1 PC4736.1 PC4737.1 PC4738.1 PC4739.1 PC4740.1 PC4741.1 PC4742.1 PC4743.1 PG4708.2 PL4701.2 R702.1
VCC_CSN1_R: PR4706.2 PR4707.1
VCC_SENSE: CPU1.E63 PR4617.1 R702.2
VCC_VSW1_GP: PG4707.1 PR4704.1
VCC_VSW1_R: PC4701.1 PR4701.2
VSS_SENSE: CPU1.E62 PR4616.1 R901.1
0D675V_PWR: PC4914.1 PG4917.1 PG4918.1 PU4902.3 PU4902.5
0D675V_S0: C1214.1 C1215.1 C1216.1 DIMM1.203 DIMM1.204 PG4917.2 PG4918.2
1D05S_VCCST: C701.1 C703.1 CPU1.AC22 CPU1.AE22 CPU1.AE23 PC4605.1 PR4621.2 PR4622.2 PR4623.2 R401.1 R703.1 R704.1 R705.1 R706.1 R711.2 R1916.2 R1917.2 R1918.2 R1919.2 R2018.1 RN401.5(B) RN401.7(B) RN401.8(B)
1D05V_HSIO: C2142.1 L1101.1 L1102.1 R1101.1 R2114.2 R2122.2
1D5V_PWR: PC5109.1 PG5101.1 PU5101.5
1D05V_PWR_BS: PR4801.1 PU4801.6
1D05V_PWR_BS_R: PC4806.1 PR4801.2
1D05V_PWR_BYP: PC4807.1 PR4807.1 PU4801.7
1D05V_PWR_FB: PC4802.2 PR4805.1 PR4806.2 PU4801.4
1D05V_PWR_FBH: PC4802.1 PG4801.1 PR4806.1
1D05V_PWR_LDO: PC4809.1 PU4801.5
1D05V_PWR_PH: PC4806.2 PL4801.1 PU4801.10
1D05V_S0: C2135.1 C2141.1 CPU1.AG13 CPU1.AG14 CPU1.AG16 CPU1.AG17 L1103.1 L1104.1 PC4803.1 PC4805.1 PC4810.1 PC4811.1 PC4812.1 PC4813.1 PG4801.2 PL4801.2 R711.1 R1102.1 R1104.1 R1105.1 R2105.1 R2117.1 R2118.1 R2122.1 R2401.1 U2101.2 U2101.3 U2101.4
1D5V_S0: CPU1.J15 PG5101.2 R2705.1
1D05V_VTT_PWRGD: PU4801.2 R707.1 R3611.1 U701.2
1D35V_S3: C1001.1 C1002.1 C1003.1 C1004.1 C1005.1 C1006.1 C1017.1 C1018.1 C1019.1 C1020.1 C1207.1 C1208.1 C1209.1 C1210.1 C1211.1 C1212.1 C1213.1 C1220.1 C1221.1 C1222.1 CPU1.AH26 CPU1.AJ31 CPU1.AJ33 CPU1.AJ37 CPU1.AN33 CPU1.AP43 CPU1.AR48 CPU1.AY35 CPU1.AY40 CPU1.AY44 CPU1.AY50 DIMM1.75 DIMM1.76 DIMM1.81 DIMM1.82 DIMM1.87 DIMM1.88 DIMM1.93 DIMM1.94 DIMM1.99 DIMM1.100 DIMM1.105 DIMM1.106 DIMM1.111 DIMM1.112 DIMM1.117 DIMM1.118 DIMM1.123 DIMM1.124 EC8617.1 EC8618.1 EC8619.1 EC8620.1 EC8621.1 EC8622.1 EC8630.1 EC8631.1 EC8633.1 EC8634.1 EC8635.1 EC8636.1 EC8637.1 EC8638.1 PC4915.1 PC4918.1 PG4902.2 PG4904.2 PG4905.2 PG4908.2 PG4909.2 PU4902.1 PU4902.2 Q1201.G Q1202.D R410.1 R3701.1 R3706.1 TC1201.1
1D35V_VTT_PWRGD: PR4907.1 R3610.1
3D3V_AUX_KBC: D4301.2 D4302.2 D4303.2 PR4414.1 PR4432.1 Q2402.D R2402.2 R2403.2 R2413.2 R2414.2 R2418.2 R2434.1 R2436.1 R2452.1 R2454.2 R2608.1 RN2401.3(B) RN2401.4(B)
3D3V_AUX_KBC_VCC: C2406.1 C2407.1 C2408.1 C2409.1 C2410.1 C2411.1 KBC24.19 KBC24.46 KBC24.76 KBC24.88 KBC24.115 R2403.1
3D3V_AUX_S5: C2417.2 D2501.1 KBC24.75 PR4412.1 PR4428.1 PR4468.1 PR4501.1 PR4532.1 Q2402.S R1726.2 R1727.1 R2425.2 R2431.2 R2434.2 R2439.1 R2451.2 R3607.1
3D3V_CAMERA_S0: C5214.1 EC5210.1 F5202.2 LCD1.40
3D3V_GSEN2: C6610.1 C6611.1 R6622.1 R6623.1 R6626.1 U6602.1 U6602.14
3D3V_MCU: C6603.1 C6604.1 C6605.1 C6606.1 C6607.1 C6608.1 R6602.2 R6607.2 R6610.2 R6612.2 R6614.2 R6616.2 R6618.2 R6620.2 RN6601.1(A) RN6601.2(A) TP6603.1 U6601.1 U6601.9 U6601.24 U6601.36 U6601.48
3D3V_PWR_2: PC4526.1 PR4532.2 PU4503.3
3D3V_RUN_FFS: C6701.1 C6702.1 C6703.1 R6702.1 U6701.1 U6701.7 U6701.8 U6701.14
3D3V_S0: C1203.1 C2128.1 C2412.1 C2413.1 C2601.1 C2602.1 C3605.1 C5212.1 CPU1.K14 CPU1.K16 DB1.10 DIMM1.199 EC8607.1 EC8608.1 EC8613.1 F5202.1 F5204.1 IOBD1.32 IOBD1.33 IOBD1.34 IOBD1.35 KBC24.4 PR4614.1 PR4902.2 PR4909.1 Q1801.2 Q1801.5 Q2601.2 Q2601.5 Q5401.C Q5402.2 Q5402.5 R1701.1 R1714.2 R1905.1 R2006.1 R2007.2 R2011.1 R2012.1 R2013.2 R2023.1 R2024.1 R2025.1 R2103.2 R2112.1 R2415.2 R2443.2 R2446.2 R2448.2 R2603.1 R2604.1 R2607.1 R2609.1 R2701.1 R2710.1 R2916.1 R3601.1 R6211.1 R6607.1 R6622.2 R6701.1 R6702.2 RN1501.1(A) RN1501.2(A) RN1505.1(A) RN1505.2(A) RN1505.3(A) RN1505.4(A) RN1506.1(A) RN1506.2(A) RN1506.3(A) RN1506.4(A) RN1801.1(A) RN1801.2(A) RN1810.1(A) RN1810.2(A) RN1902.5(B) RN1902.6(B) RN1902.7(B) RN1902.8(B) RN2002.1(A) RN2002.2(A) RN2002.3(A) RN2002.4(A) RN2007.1(A) RN2007.2(A) RN2008.1(A) RN2008.2(A) RN2011.1(A) RN2011.2(A) RN2011.3(A) RN2011.4(A) RN2602.1(A) RN2602.2(A) THM261.1 U3601.8 U3601.9 U5201.4 U5201.5
3D3V_S5: C702.1 C2147.1 C2501.1 C2502.1 C3801.1 C6204.1 C6402.1 CPU1.Y8 EC8609.1 IOBD1.36 LIDSW1.2 PC4517.1 PC5108.1 PD4203.2 PG4535.1 PL4503.1 PR4204.1 PR4424.1 PR4431.1 PR4450.2 PR4534.1 PR4618.2 PR4807.2 PR4910.1 PR4918.2 PT4501.1 PU4601.20 PU4601.21 PU5101.1 Q6203.S R1703.1 R2101.1 R2412.2 R2421.2 R2445.2 R2450.2 R2455.2 R2501.2 R2712.2 R3801.1 R5420.1 R6401.2 RN1701.1(A) RN1701.2(A) RN1802.1(A) RN1802.2(A) RN2006.1(A) RN2006.2(A) SPI25.8 U701.5 U3601.6 U3601.7 U3801.2 U3801.3
3D3V_S5_PCH: C3802.1 R1103.1 R1724.1 R2001.1 R2004.1 R2014.1 R2017.1 R2021.1 R2022.1 R2102.2 R2108.1 R3801.2 RN1601.1(A) RN1601.2(A) RN1601.3(A) RN1601.4(A) RN1807.1(A) RN1807.2(A) RN1807.3(A) RN1807.4(A) RN1809.1(A) RN1809.2(A) RN1809.3(A) RN1809.4(A) RN1811.1(A) RN1811.2(A) RN2012.1(A) RN2012.2(A) RN2012.3(A) RN2012.4(A) U3801.6 U3801.7 U3801.8
3D3V_SEN_S0: C5215.1 EC5211.1 F5204.2 HOMBD1.1
+1.05M_ASW: C1115.1 C1116.1 CPU1.AE9 CPU1.AF9 CPU1.AG8 R1104.2
+3.3A_DSW_PRTCSUS: C2109.1 CPU1.AH11 R2102.1
+DC_IN: EC8611.1 EL4201.2 EL4203.2 EL4204.2 PC4201.1 PC4202.1 PD4201.K PR4207.1 PU4201.1 PU4201.2 PU4201.3
+DC_IN_C: AFTP4201.1 AFTP4202.1 DCIN1.6 DCIN1.7 DCIN1.8 EC4201.1 EC4202.1 EL4201.1 EL4203.1 EL4204.1
+PCH_VCCDSW: C2101.2 CPU1.AG19 CPU1.AG20 R2110.1
+RTC_VCC: D2501.2 IOBD1.31 Q2505.G R2504.1
+SDC_IN: PG4406.1 PR4426.1 PR4435.1 PR4439.1 PU4405.1 PU4405.2 PU4405.3
+V_SM_VREF_CNT: C3701.1 CPU1.AP49 R3708.2
+V_VREF_PATH1: C3702.2 R3711.1
+V_VREF_PATH3: C3701.2 R3707.1
+VCHGR: PC4415.1 PC4420.2 PC4439.1 PC4440.1 PD4402.3 PG4403.2 PG4405.2 PR4443.2 PU4403.1 PU4403.2 PU4403.3
+VCHGR_R: PG4405.1 PR4454.1
AC_IN#: PQ4413.6 PR4412.2 R2413.1 R2430.1
AC_PRESENT: CPU1.AJ8 EC1707.1 KBC24.112 RN1701.4(B)
ACAV_IN: PQ4407.2 PR4430.2
AD+: PC4203.1 PC4204.1 PC4205.1 PC4206.1 PD4406.A PR4416.1 PR4418.1 PR4444.1 PU4201.5 PU4201.6 PU4201.7 PU4201.8 PU4405.5 PU4405.6 PU4405.7 PU4405.8
AD+_G_1: PQ4407.5 PQ4407.6 PR4423.1
AD+_G_2: PR4423.2 PR4435.2 PU4405.4
AD_IA: C2414.2 KBC24.97 PR4466.2
AD_IA_HW: CPU1.AL4 PQ4411.5 R2001.2
AD_IA_HW2: CPU1.AP1 PQ4411.2 R2021.2
ALERT#: R2603.2 THM261.6
ALL_SYS_PWRGD: KBC24.10 R3601.2 R3610.2 R3611.2
ALS_INT#: CPU1.Y3 LCD1.33 RN2002.8(B) U6601.28
AMP_MUTE#: KBC24.30 R2708.1
AUD_AGND: AFTP2908.1 C2702.1 C2705.1 C2710.2 C2711.2 C2712.1 C2713.2 C2715.2 C2902.1 EC2703.1 EC2704.1 EC2705.1 EC2706.1 EC2707.1 EC2905.2 EC2906.2 EC2907.2 EC2908.2 EC8601.1 EC8602.1 EC8603.1 EC8604.1 HDA27.25 HDA27.38 HPMIC1.MS Q2901.S R2706.1 R2707.2 R2711.1 R2905.2 R2919.2 R2920.2 R2923.1 U2901.4
AUD_HP1_JACK_L: HDA27.32 R2908.1
AUD_HP1_JACK_L1: EC2907.1 R2907.1 R2908.2 R2912.2 R2919.1 R2922.2
AUD_HP1_JACK_R: HDA27.33 R2910.1
AUD_HP1_JACK_R1: EC2908.1 R2909.1 R2910.2 R2913.2 R2920.1 R2921.2
AUD_PC_BEEP: C2720.2 HDA27.12
AUD_PC_BEEP_C: C2720.1 D2701.3 R2717.1
AUD_PORTA_L_R_B: AFTP2906.1 ED2902.2 HPMIC1.1 R2907.2
AUD_PORTA_R_R_B: AFTP2907.1 ED2901.2 HPMIC1.2 R2909.2
AUD_SENSE: Q2901.D R2709.2 R2914.2
AUD_SENSE_A: HDA27.13 R2709.1 R2722.1
AUD_SPK_L+: EC2902.1 HDA27.42 R2902.1
AUD_SPK_L+_C: AFTP2902.1 R2902.2 SPK1.3
AUD_SPK_L-: EC2901.1 HDA27.43 R2901.1
AUD_SPK_L-_C: AFTP2901.1 R2901.2 SPK1.4
AUD_SPK_R+: EC2904.1 HDA27.45 R2904.1
AUD_SPK_R+_C: AFTP2904.1 R2904.2 SPK1.1
AUD_SPK_R-: EC2903.1 HDA27.44 R2903.1
AUD_SPK_R-_C: AFTP2903.1 R2903.2 SPK1.2
AUD_VREF: C2705.2 HDA27.28
BAT_IN#: D4302.3 EC4305.2 KBC24.80 PC4414.1 PR4431.2 PU4401.15 R2414.1 RN4301.1(A)
BAT_SCL: D4301.3 EC4301.1 KBC24.70 PG4401.2 PR4432.2 RN2401.1(A) RN4301.3(A)
BAT_SDA: D4303.3 EC4302.1 KBC24.69 PG4408.2 PR4414.2 RN2401.2(A) RN4301.2(A)
BATDRV#: PC4424.2 PR4409.2 PU4403.4
BATLOW#: CPU1.AN4 RN1701.3(B)
BATT_WHITE_LED#: IOBD1.21 KBC24.62
BKLT_CTRL: D5202.3 R5224.1 RN5201.5(B) RN5203.5(B)
BLON_OUT: KBC24.27 RN5201.7(B)
BLON_OUT_C: LCD1.25 RN5201.2(A) RN5203.6(B)
BLUETOOTH_EN: CPU1.J4 IOBD1.25 RN2011.5(B)
BOARD_ID1: CPU1.U4 R2023.2
BOOST_MON: KBC24.96 PR4434.2 PR4452.1
BOOST_MON_1: PC4417.1 PR4446.1 PR4452.2
BQ24770_AGND: PC4401.2 PC4402.2 PC4410.2 PC4412.2 PC4416.1 PC4418.1 PC4432.2 PC4433.2 PR4406.2 PR4411.2 PU4401.29
BQ24770_IADP: PC4435.1 PR4422.2 PR4466.1 PU4401.7 PU4402.5
BQ24770_IDCHG: PC4436.1 PR4434.1 PU4401.8
BQ24770_PMON: PC4437.1 PR4467.1 PU4401.9
BT+: AFTP4305.1 AFTP4306.1 AFTP4307.1 BATT1.1 BATT1.2 EC4303.1 EC4304.1 PC4424.1 PC4438.1 PD4302.K PD4402.1 PD4402.2 PD4405.A PR4408.1 PR4442.1 PU4403.5 PU4403.6 PU4403.7 PU4403.8
CAMERA_DET#: CPU1.J2 LCD1.27 R2013.1
CAMERA_PWR_EN: CPU1.AM4 TP2002.1
CAP_LED: AFTP6233.1 KB1.2 R6201.2
CAP_LED#: KBC24.109 R6202.1
CAP_LED_Q: Q6201.C R6201.1
CAP_LED_R#: Q6201.B R6202.2
CARD_PWR_EN: CPU1.AL2 RN1809.8(B)
CBN: C2703.1 HDA27.35
CBP: C2703.2 HDA27.37
CFG0: CPU1.AC60 TP9626.1
CFG1: CPU1.AC62 TP9627.1
CFG2: CPU1.AC63 TP9620.1
CFG3: CPU1.AA63 R604.1 TP9622.1
CFG4: CPU1.AA60 R605.1 TP9630.1
CFG5: CPU1.Y62 TP9631.1
CFG6: CPU1.Y61 TP9629.1
CFG7: CPU1.Y60 TP9628.1
CFG8: CPU1.V62 TP9633.1
CFG9: CPU1.V61 TP9632.1
CFG10: CPU1.V60 TP9637.1
CFG11: CPU1.U60 TP9639.1
CFG12: CPU1.T63 TP9640.1
CFG13: CPU1.T62 TP9643.1
CFG14: CPU1.T61 TP9642.1
CFG15: CPU1.T60 TP9641.1
CFG16: CPU1.AA62 TP9635.1
CFG17: CPU1.AA61 TP9634.1
CFG18: CPU1.U63 TP9636.1
CFG19: CPU1.U62 TP9638.1
CFG_RCOMP: CPU1.V63 R601.2
CHARGER_CELL_PIN: PR4424.2 PR4445.1 PR4449.2 PR4464.1 PR4468.2 PU4401.16
CHARGER_SRC: PC4407.1 PC4411.1 PC4413.1 PC4425.1 PC4427.1 PC4434.1 PG4402.1 PR4426.2 PU4406.2 PU4406.3 PU4406.4 PU4406.10
CHG_AMBER_LED#: IOBD1.20 KBC24.16
CHG_CMPIN_1: PR4413.2 PU4401.13
CHG_CMPOUT_1: PR4415.2 PU4401.14
CLK_PCI_KBC: EC1801.1 KBC24.2 R1805.2
CLK_PCI_KBC_R: CPU1.AP15 R1805.1
CLK_PCI_LPC: DB1.2 EC1802.1 R1804.2
CLK_PCI_LPC_R: CPU1.AN15 R1804.1
CLK_PCIE_REQ#: CPU1.N1 CPU1.T2 CPU1.U2 CPU1.U5 CPU1.Y5 RN1902.3(A)
CLK_PCIE_WLAN_N3: CPU1.C41 IOBD1.18
CLK_PCIE_WLAN_P3: CPU1.B42 IOBD1.17
CLK_PCIE_WLAN_REQ3#: CPU1.AD1 IOBD1.22 RN1801.4(B)
CODEC_BITCLK_R: HDA27.6 R2720.2
CODEC_SDOUT_R: HDA27.5 R2719.2
COLOR_ENGINE: CPU1.E3 TP2003.1
COMBO-GPI: HDA27.48 TP2702.1
CPVEE: C2704.2 HDA27.34
CTL1: R3501.2 U3503.6
CTL2: R3507.2 U3503.7
CTL3: R3504.2 U3503.8
DBC_EN: CPU1.K3 R5201.2 RN2011.6(B)
DBC_EN_R: LCD1.22 R5201.1
DC_IN_D: PQ4407.3 PR4418.2
DC_TEST_A3_B3: CPU1.A3 CPU1.B3
DC_TEST_A61_B61: CPU1.A61 CPU1.B61
DC_TEST_AY2_AW2: CPU1.AW2 CPU1.AY2
DC_TEST_AY3_AW3: CPU1.AW3 CPU1.AY3
DC_TEST_AY61_AW61: CPU1.AW61 CPU1.AY61
DC_TEST_AY62_AW62: CPU1.AW62 CPU1.AY62
DC_TEST_B62_B63: CPU1.B62 CPU1.B63
DC_TEST_C1_C2: CPU1.C1 CPU1.C2
DCBATOUT: EC4701.1 EC8605.1 EC8606.1 EC8610.1 EC8623.1 EC8624.1 EC8625.1 EC8626.1 EC8627.1 EC8628.1 EC8629.1 EC8632.1 F5201.2 PC4403.1 PC4408.1 PC4409.1 PC4430.1 PC4431.1 PC4441.1 PC4442.1 PC4509.1 PC4519.1 PC4525.1 PC4527.1 PC4528.1 PC4529.1 PC4530.1 PC4531.1 PC4702.1 PC4703.1 PC4704.1 PC4708.1 PC4804.1 PC4808.1 PG4404.2 PG4407.2 PG4901.1 PG4903.1 PG4906.1 PG4907.1 PL4401.2 PR4443.1 PR4458.1 PR4465.1 PR4613.1 PT4702.1 PU4404.3 PU4501.2 PU4502.2 PU4503.12 PU4701.5 PU4801.8
DCBATOUT_LCD: C5202.1 C5203.1 C5204.1 F5201.1 LCD1.1 LCD1.2 LCD1.3 LCD1.4
DCBATOUT_R: PG4404.1 PR4448.1
DCBATOUT_SNUB: PC4406.1 PR4427.2
DDC_CLK_HDMI: HDMI1.15 Q5402.3 RN5401.2(A)
DDC_CLK_PH1: D5401.2 RN5401.3(B)
DDC_DATA_HDMI: HDMI1.16 Q5402.6 RN5401.1(A)
DDC_DATA_PH2: D5401.1 RN5401.4(B)
DDPC_CTRLDATA: CPU1.D11 TP1502.1
DDR3_DRAMRST#: DIMM1.30 ED1217.1 R404.2
DDR_PG_CTRL: CPU1.AV61 R1205.1
DDR_PG_CTRL_R: Q1201.S R1205.2
DDR_VREF_S3: PC4916.1 PU4902.6 R3704.1 R3710.1
DDR_VTT_PG_CTRL: PR4926.1 Q1201.D Q1202.G R1204.1 R1208.2
DDR_WR_VREF01: C3702.1 CPU1.AR51 R3702.1
DIS_DTM_CELL: PR4419.1 PR4453.2 PR4460.2 PU4402.1
DMIC_CLK: C2723.2 EC5206.1 R2716.1 R5204.2
DMIC_CLK_C: LCD1.18 R5204.1
DMIC_CLK_R: HDA27.3 R2716.2
DMIC_DATA: EC5205.1 R2714.1 R5205.2
DMIC_DATA_C: LCD1.19 R5205.1
DMIC_DATA_R: EC2701.1 HDA27.2 R2714.2
DS3_PWRCTL: R3802.2 U3801.4
DSWODVREN: CPU1.AW7 R1720.1 R1721.1
E51_TXD: KBC24.111 TP2408.1
EAPD#: HDA27.47 R2708.2
EC_AGND: C2402.1 C2403.1 C2404.2 C2405.2 C2414.1 KBC24.103 R2406.2 R2407.2 R2435.2
EC_GPIO10: KBC24.124 TP2409.1
EC_SCI#: CPU1.AM2 R2408.2 RN1809.6(B)
EC_SMI#: CPU1.V1 R2409.2 RN2002.6(B)
EC_SPI_CLK_C: KBC24.92 R2420.2
EC_SPI_CS#_C: KBC24.90 R2419.2
EC_SPI_DI_C: KBC24.87 R2422.2
EC_SPI_DO_C: KBC24.86 R2423.2
EC_SWI#: CPU1.AM3 RN2012.8(B)
EC_VBKUP: KBC24.114 R2428.1
EC_VTT: C2401.1 KBC24.12 R2401.2
ECRST#: C2418.1 KBC24.85 Q2404.E R2418.1 R2424.2
ECSCI#_KBC: KBC24.29 R2408.1
ECSMI#_KBC: KBC24.6 R2409.1
EDP_AUX: C5226.1 LCD1.12
EDP_AUX#: C5225.1 LCD1.13
EDP_AUX_DN: C5225.2 CPU1.A45
EDP_AUX_DP: C5226.2 CPU1.B45
EDP_BRIGHTNESS: CPU1.A43 TP801.1
EDP_COMP: CPU1.D20 R801.2
EDP_HPD: CPU1.D6 R5203.2
EDP_HPD_CONN: LCD1.24 R5203.1 RN5203.7(B)
EDP_SPARE: CPU1.B43 TP605.1
EDP_TX0: C5229.1 LCD1.10
EDP_TX0#: C5230.1 LCD1.9
EDP_TX0_DN: C5230.2 CPU1.C45
EDP_TX0_DP: C5229.2 CPU1.B46
EDP_TX1: C5232.1 LCD1.7
EDP_TX1#: C5231.1 LCD1.6
EDP_TX1_DN: C5231.2 CPU1.A47
EDP_TX1_DP: C5232.2 CPU1.B47
EDP_VDD_EN: CPU1.C6 D5201.1
FALL_INT2: Q6701.2 Q6701.3 R6701.2
FAN_PWM1: KBC24.65 RN2601.1
FAN_PWM1_C: AFTP2602.1 FAN1.4 RN2601.4
FAN_TACH1: KBC24.31 R2415.1 RN2601.2
FAN_TACH1_C: AFTP2601.1 FAN1.3 RN2601.3
FAN_VCC_1: AFTP2603.1 C2603.1 C2604.1 C2605.1 D2601.K FAN1.1 R2612.2
FFS_INT1_D: R6706.1 U6701.11
FFS_INT2: D6701.2 R6608.1 R6705.1 R6707.2
FFS_INT2_D: R6707.1 U6701.9
FFS_INT2_Q: Q6701.6 R5601.2
FFS_INT2_Q_R: HDD1.1 R5601.1
FFS_SCL: R6708.2 U6701.4
FFS_SDA: R6709.2 U6701.6
GSEN2_INT1: R6621.2 R6628.2 U6602.11
GSEN2_INT1_C: R6628.1 U6601.17
GSEN2_INT2: R6608.2 R6629.2 U6602.9
GSEN2_INT2_C: R6629.1 U6601.38
GSEN_INT1: HOMBD1.9 U6601.18
GSEN_INT2: HOMBD1.10 U6601.19
GSENSOR_CS: R6623.2 U6602.8
GSENSOR_SDO: R6626.2 R6627.2 U6602.7
GYRO_DRDY: HOMBD1.12 U6601.39
GYRO_INT: HOMBD1.11 R6624.2 R6625.2
GYRO_INT_C: R6625.1 U6601.20
GYRO_INT_P11: D6701.1 R6624.1
H_CATERR#: CPU1.K61 TP402.1
H_CPU_SVIDALRT#: CPU1.L62 R701.2
H_CPU_SVIDCLK: CPU1.N63 PR4622.1 PU4601.31
H_CPU_SVIDDAT: CPU1.L63 PR4621.1 PU4601.1 R704.2
H_CPUPWRGD: CPU1.C61 R405.1
H_PECI: CPU1.N62 R2429.2
H_PROCHOT#: C2421.1 PR4455.2 PR4456.1 PR4457.2 PR4469.1 PU4601.30 R401.2 R403.1 R2440.2
H_PROCHOT#_EC: Q2401.D R2438.2 R2440.1
H_PROCHOT#_R: CPU1.K63 R403.2
H_RCIN#: CPU1.V4 KBC24.122 RN2002.7(B)
H_VCCST_PWRGD: CPU1.B59 EC701.1 R706.2 R707.2 R709.1 TP9648.1 U701.4
H_VR_ENABLE: CPU1.F60 PR4615.2 R710.1
HDA_BITCLK: CPU1.AW8 R1907.2
HDA_CODEC_BITCLK: EC1901.2 EC2709.1 R1907.1 R2720.1
HDA_CODEC_RST#: HDA27.11 R1911.1 R2917.1
HDA_CODEC_SDIN0: HDA27.8 R2718.2
HDA_CODEC_SDOUT: EC2708.1 R1912.1 R2719.1
HDA_CODEC_SYNC: HDA27.10 R1908.1
HDA_RST#: CPU1.AU8 R1911.2
HDA_SDIN0: CPU1.AY10 R2718.1
HDA_SDOUT: CPU1.AU11 R1909.2 R1912.2
HDA_SPKR: CPU1.V2 R2006.2 RN2701.2
HDA_SPKR_R: D2701.2 RN2701.3
HDA_SYNC: CPU1.AV11 R1908.2
HDD_DEVSLP: CPU1.P2 R2024.2
HDD_FALL_INT: R1501.1 R6621.1 R6706.2
HDMI_CLK: C5403.1 CPU1.B57
HDMI_CLK#: C5402.1 CPU1.A57
HDMI_CLK#_R: C5402.2 R5401.1 RN5402.5(B)
HDMI_CLK#_R_C: HDMI1.12 R5401.2 R5414.1
HDMI_CLK_R: C5403.2 R5402.1 RN5402.6(B)
HDMI_CLK_R_C: HDMI1.10 R5402.2 R5414.2
HDMI_DATA0: C5405.1 CPU1.A55
HDMI_DATA0#: C5404.1 CPU1.B55
HDMI_DATA0#_R: C5404.2 R5403.1 RN5403.5(B)
HDMI_DATA0#_R_C: HDMI1.9 R5403.2 R5416.1
HDMI_DATA0_R: C5405.2 R5404.1 RN5403.6(B)
HDMI_DATA0_R_C: HDMI1.7 R5404.2 R5416.2
HDMI_DATA1: C5406.1 CPU1.C58
HDMI_DATA1#: C5409.1 CPU1.B58
HDMI_DATA1#_R: C5409.2 R5407.1 RN5402.7(B)
HDMI_DATA1#_R_C: HDMI1.6 R5407.2 R5417.1
HDMI_DATA1_R: C5406.2 R5408.1 RN5402.8(B)
HDMI_DATA1_R_C: HDMI1.4 R5408.2 R5417.2
HDMI_DATA2: C5408.1 CPU1.C55
HDMI_DATA2#: C5407.1 CPU1.C54
HDMI_DATA2#_R: C5407.2 R5405.1 RN5403.7(B)
HDMI_DATA2#_R_C: HDMI1.3 R5405.2 R5415.1
HDMI_DATA2_R: C5408.2 R5406.1 RN5403.8(B)
HDMI_DATA2_R_C: HDMI1.1 R5406.2 R5415.2
HDMI_EC_DET#: KBC24.118 R5422.1
HDMI_EC_DET#_C: Q5404.D R5420.2 R5422.2
HDMI_HPD_B: Q5401.B R5411.2
HDMI_HPD_E: Q5401.E R5412.1 R5419.2
HDMI_PCH_DET: CPU1.C8 R5419.1
HDMI_PLL_GND: Q5403.D R5418.2 RN5402.1(A) RN5402.2(A) RN5402.3(A) RN5402.4(A) RN5403.1(A) RN5403.2(A) RN5403.3(A) RN5403.4(A)
HOME_BTN#: KBC24.33 R2454.1 R2457.1
HOME_BTN#_C: HOMBD1.8 R2457.2
HPD_HDMI_CON: HDMI1.19 R5410.1 R5411.1 R5421.2
HPD_HDMI_CON_C: Q5404.G R5421.1
HSIO_OUT: R2114.1 U2101.5 U2101.6 U2101.7
HSIOPC: CPU1.Y2 R2007.1 R2123.1
HSIOPC_R: R2123.2 U2101.9
HUB_PA1: R6619.2 R6620.1 U6601.11
HUB_PA2: R6617.2 R6618.1 U6601.12
HUB_PA3: R6615.2 R6616.1 U6601.13
HUB_PA4: R6613.2 R6614.1 U6601.14
HUB_PA5: R6611.2 R6612.1 U6601.15
HUB_PA6: R6609.2 R6610.1 U6601.16
HVM_CLK: CPU1.R20 TP620.1
HVM_CLK#: CPU1.P20 TP619.1
I2C0_SCL: CPU1.F3 RN2007.4(B)
I2C0_SDA: CPU1.F2 RN2007.3(B)
I2C1_SCL: CPU1.F1 EC6203.1 Q6204.1 R6212.1 RN2008.3(B)
I2C1_SCL_R: AFTP6237.1 Q6204.6 R6212.2 RN6204.3(B) TP1.6
I2C1_SDA: CPU1.G4 EC6204.1 Q6204.4 R6213.1 RN2008.4(B)
I2C1_SDA_R: AFTP6240.1 Q6204.3 R6213.2 RN6204.4(B) TP1.7
ILIM_HI: R3508.2 U3503.16
ILIM_LO: R3506.2 U3503.15
ILIM_SEL: R3505.2 U3503.4
IMVP_PWRGD: EC4602.1 KBC24.107 PR4614.2 PR4625.2 R713.1
IMVP_PWRGD_R: CPU1.C59 EC702.1 R710.2 R712.1 R713.2
IMVP_VRON: PR4615.1 PU4601.8
INT2_SELECT: CPU1.P1 D6701.3 Q6701.5 R2025.2 R6705.2
INT_SERIRQ: CPU1.T4 KBC24.125 RN1902.2(A)
INT_TP#: AFTP6241.1 D2001.K R2426.1 R6203.2 TP1.4
INT_TP#_C: D2001.A R2008.2 R2026.2 R2027.2
JACK_PLUG: AFTP2909.1 C2902.2 ED2904.2 HPMIC1.6 Q2901.G R2905.1 R2914.1
JACK_POWER: AFTP2910.1 ED2906.2 HPMIC1.5 R2916.2 R2923.2
JDREF: HDA27.15 R2707.1
KB_BL_CTRL: KBC24.22 Q6202.G R6208.1
KB_BL_CTRL#: AFTP6247.1 KBLIT1.3 Q6202.D
KB_CLOSE#_2: C6401.1 KBC24.83 LIDSW1.3 R6401.1
KB_DISABLE: KBC24.11 U6601.2
KB_LED_BL_DET: CPU1.J1 TP2015.1
KBC_BEEP: KBC24.32 RN2701.1
KBC_BEEP_R: D2701.1 RN2701.4
KBC_DPWROK: EC1705.1 KBC24.81 R1718.2 R1725.2
KBC_ON#_GATE: C2417.1 Q2402.G Q2403.G R2433.2
KBC_ON#_GATE_L: D2402.2 R2431.1 R2432.2 R2433.1
KBC_PWRBTN#: IOBD1.7 R2427.1
KBC_VCORF: C2416.1 KBC24.44
KCOL0: AFTP6217.1 KB1.20 KBC24.53
KCOL1: AFTP6219.1 KB1.16 KBC24.52
KCOL2: AFTP6216.1 KB1.14 KBC24.51
KCOL3: AFTP6214.1 KB1.9 KBC24.50
KCOL4: AFTP6210.1 KB1.13 KBC24.49
KCOL5: AFTP6215.1 KB1.17 KBC24.48
KCOL6: AFTP6212.1 KB1.10 KBC24.47
KCOL7: AFTP6211.1 KB1.12 KBC24.43
KCOL8: AFTP6213.1 KB1.11 KBC24.42
KCOL9: AFTP6223.1 KB1.23 KBC24.41
KCOL10: AFTP6225.1 KB1.4 KBC24.40
KCOL11: AFTP6224.1 KB1.5 KBC24.39
KCOL12: AFTP6218.1 KB1.8 KBC24.38
KCOL13: AFTP6221.1 KB1.7 KBC24.37
KCOL14: AFTP6222.1 KB1.6 KBC24.36
KCOL15: AFTP6220.1 KB1.3 KBC24.35
KCOL16: AFTP6229.1 KBC24.34 KBLIT1.4
KROW0: AFTP6208.1 KB1.15 KBC24.54
KROW1: AFTP6228.1 KB1.26 KBC24.55
KROW2: AFTP6206.1 KB1.19 KBC24.56
KROW3: AFTP6207.1 KB1.18 KBC24.57
KROW4: AFTP6203.1 KB1.22 KBC24.58
KROW5: AFTP6227.1 KB1.21 KBC24.59
KROW6: AFTP6202.1 KB1.24 KBC24.60
KROW7: AFTP6201.1 KB1.25 KBC24.61
L_BKLT_CTRL: CPU1.B8 D5202.1 R5224.2
L_BKLT_EN: CPU1.A9 R2444.1
L_BKLT_EN_EC: KBC24.9 R2444.2 R2447.1
LCD_BRIGHTNESS: EC5207.1 LCD1.26 RN5201.4(A)
LCD_TST: D5202.2 R2417.1 RN5201.8(B)
LCD_TST_C: LCD1.23 RN5201.1(A)
LCD_TST_EN: D5201.2 KBC24.28 R2417.2
LCDVDD: C5208.1 C5209.2 C5211.1 LCD1.37 LCD1.38 U5201.3
LDO1_CAP: C2702.2 HDA27.27 R2711.2
LDO2_CAP: C2712.2 HDA27.39
LDO3_CAP: C2718.1 HDA27.7
LID_CLOSE#: D2401.K IOBD1.26 KBC24.17 R2421.1
LINE1-L_C: C2907.2 R2922.1
LINE1-L_R: C2908.2 R2921.1
LINE1_L: C2907.1 HDA27.22
LINE1_R: C2908.1 HDA27.21
LINE1_VREFO_L: HDA27.31 R2912.1
LINE1_VREFO_R: HDA27.30 R2913.1
LPC_AD0: DB1.9 KBC24.126 RN1806.8(B)
LPC_AD1: DB1.8 KBC24.127 RN1806.7(B)
LPC_AD2: DB1.7 KBC24.128 RN1806.6(B)
LPC_AD3: DB1.6 KBC24.1 RN1806.5(B)
LPC_FRAME#: DB1.5 KBC24.3 R1801.1
LPC_LAD0_PCH: CPU1.AU14 RN1806.1(A)
LPC_LAD1_PCH: CPU1.AW12 RN1806.2(A)
LPC_LAD2_PCH: CPU1.AY12 RN1806.3(A)
LPC_LAD3_PCH: CPU1.AW11 RN1806.4(A)
LPC_LFRAME#_PCH: CPU1.AV12 R1801.2
LPSS_GSPI0_MOSI_BBS0_R: CPU1.L8 R2012.2
LPSS_SDIO_D0_CMNHDR: CPU1.D3 R2011.2
LVDS_VDD_EN_R: D5201.3 RN5203.8(B) U5201.1
M_A_A0: CPU1.AU36 DIMM1.98
M_A_A1: CPU1.AY37 DIMM1.97
M_A_A2: CPU1.AR38 DIMM1.96
M_A_A3: CPU1.AP36 DIMM1.95
M_A_A4: CPU1.AU39 DIMM1.92
M_A_A5: CPU1.AR36 DIMM1.91
M_A_A6: CPU1.AV40 DIMM1.90
M_A_A7: CPU1.AW39 DIMM1.86
M_A_A8: CPU1.AY39 DIMM1.89
M_A_A9: CPU1.AU40 DIMM1.85
M_A_A10: CPU1.AP35 DIMM1.107
M_A_A11: CPU1.AW41 DIMM1.84
M_A_A12: CPU1.AU41 DIMM1.83
M_A_A13: CPU1.AR35 DIMM1.119
M_A_A14: CPU1.AV42 DIMM1.80
M_A_A15: CPU1.AU42 DIMM1.78
M_A_B_DIMM_ODT: Q1202.S R1206.1 R1207.1
M_A_BS0: CPU1.AU35 DIMM1.109
M_A_BS1: CPU1.AV35 DIMM1.108
M_A_BS2: CPU1.AY41 DIMM1.79
M_A_CAS#: CPU1.AU34 DIMM1.115
M_A_DIMA_CKE0: CPU1.AU43 DIMM1.73
M_A_DIMA_CKE1: CPU1.AW43 DIMM1.74
M_A_DIMA_CLK_DDR0: CPU1.AV37 DIMM1.101
M_A_DIMA_CLK_DDR1: CPU1.AY36 DIMM1.102
M_A_DIMA_CLK_DDR#0: CPU1.AU37 DIMM1.103
M_A_DIMA_CLK_DDR#1: CPU1.AW36 DIMM1.104
M_A_DIMA_CS#0: CPU1.AP33 DIMM1.114
M_A_DIMA_CS#1: CPU1.AR32 DIMM1.121
M_A_DIMA_ODT0: DIMM1.116 R1206.2
M_A_DIMA_ODT1: DIMM1.120 R1207.2
M_A_DQ0: CPU1.AH63 DIMM1.129
M_A_DQ1: CPU1.AH62 DIMM1.131
M_A_DQ2: CPU1.AK63 DIMM1.141
M_A_DQ3: CPU1.AK62 DIMM1.140
M_A_DQ4: CPU1.AH61 DIMM1.132
M_A_DQ5: CPU1.AH60 DIMM1.130
M_A_DQ6: CPU1.AK61 DIMM1.143
M_A_DQ7: CPU1.AK60 DIMM1.142
M_A_DQ8: CPU1.AM63 DIMM1.7
M_A_DQ9: CPU1.AM62 DIMM1.4
M_A_DQ10: CPU1.AP63 DIMM1.17
M_A_DQ11: CPU1.AP62 DIMM1.18
M_A_DQ12: CPU1.AM61 DIMM1.6
M_A_DQ13: CPU1.AM60 DIMM1.5
M_A_DQ14: CPU1.AP61 DIMM1.15
M_A_DQ15: CPU1.AP60 DIMM1.16
M_A_DQ16: CPU1.AP58 DIMM1.159
M_A_DQ17: CPU1.AR58 DIMM1.157
M_A_DQ18: CPU1.AM57 DIMM1.146
M_A_DQ19: CPU1.AK57 DIMM1.148
M_A_DQ20: CPU1.AL58 DIMM1.149
M_A_DQ21: CPU1.AK58 DIMM1.147
M_A_DQ22: CPU1.AR57 DIMM1.158
M_A_DQ23: CPU1.AN57 DIMM1.160
M_A_DQ24: CPU1.AP55 DIMM1.24
M_A_DQ25: CPU1.AR55 DIMM1.22
M_A_DQ26: CPU1.AM54 DIMM1.36
M_A_DQ27: CPU1.AK54 DIMM1.34
M_A_DQ28: CPU1.AL55 DIMM1.23
M_A_DQ29: CPU1.AK55 DIMM1.21
M_A_DQ30: CPU1.AR54 DIMM1.33
M_A_DQ31: CPU1.AN54 DIMM1.35
M_A_DQ32: CPU1.AY58 DIMM1.166
M_A_DQ33: CPU1.AW58 DIMM1.165
M_A_DQ34: CPU1.AY56 DIMM1.175
M_A_DQ35: CPU1.AW56 DIMM1.174
M_A_DQ36: CPU1.AV58 DIMM1.163
M_A_DQ37: CPU1.AU58 DIMM1.164
M_A_DQ38: CPU1.AV56 DIMM1.177
M_A_DQ39: CPU1.AU56 DIMM1.176
M_A_DQ40: CPU1.AY54 DIMM1.42
M_A_DQ41: CPU1.AW54 DIMM1.41
M_A_DQ42: CPU1.AY52 DIMM1.50
M_A_DQ43: CPU1.AW52 DIMM1.51
M_A_DQ44: CPU1.AV54 DIMM1.39
M_A_DQ45: CPU1.AU54 DIMM1.40
M_A_DQ46: CPU1.AV52 DIMM1.52
M_A_DQ47: CPU1.AU52 DIMM1.53
M_A_DQ48: CPU1.AK40 DIMM1.69
M_A_DQ49: CPU1.AK42 DIMM1.67
M_A_DQ50: CPU1.AM43 DIMM1.59
M_A_DQ51: CPU1.AM45 DIMM1.57
M_A_DQ52: CPU1.AK45 DIMM1.56
M_A_DQ53: CPU1.AK43 DIMM1.58
M_A_DQ54: CPU1.AM40 DIMM1.68
M_A_DQ55: CPU1.AM42 DIMM1.70
M_A_DQ56: CPU1.AM46 DIMM1.192
M_A_DQ57: CPU1.AK46 DIMM1.194
M_A_DQ58: CPU1.AM49 DIMM1.183
M_A_DQ59: CPU1.AK49 DIMM1.182
M_A_DQ60: CPU1.AM48 DIMM1.191
M_A_DQ61: CPU1.AK48 DIMM1.193
M_A_DQ62: CPU1.AM51 DIMM1.181
M_A_DQ63: CPU1.AK51 DIMM1.180
M_A_DQS0: CPU1.AJ62 DIMM1.137
M_A_DQS1: CPU1.AN61 DIMM1.12
M_A_DQS2: CPU1.AN58 DIMM1.154
M_A_DQS3: CPU1.AN55 DIMM1.29
M_A_DQS4: CPU1.AW57 DIMM1.171
M_A_DQS5: CPU1.AW53 DIMM1.47
M_A_DQS6: CPU1.AL42 DIMM1.64
M_A_DQS7: CPU1.AL49 DIMM1.188
M_A_DQS#0: CPU1.AJ61 DIMM1.135
M_A_DQS#1: CPU1.AN62 DIMM1.10
M_A_DQS#2: CPU1.AM58 DIMM1.152
M_A_DQS#3: CPU1.AM55 DIMM1.27
M_A_DQS#4: CPU1.AV57 DIMM1.169
M_A_DQS#5: CPU1.AV53 DIMM1.45
M_A_DQS#6: CPU1.AL43 DIMM1.62
M_A_DQS#7: CPU1.AL48 DIMM1.186
M_A_RAS#: CPU1.AY34 DIMM1.110
M_A_WE#: CPU1.AW34 DIMM1.113
M_VREF_CA_DIMMA: C1201.1 C1202.1 C1218.1 DIMM1.126 R3703.1 R3704.2 R3706.2 R3708.1
M_VREF_DQ_DIMMA: C1204.1 C1205.1 C1206.1 DIMM1.1 R3701.2 R3702.2 R3709.1 R3710.2
MCP_GPIO0: CPU1.K4 TP2007.1
MCP_GPIO1: CPU1.G2 TP2009.1
MCP_GPIO8: CPU1.AU2 R2017.2 R2027.1
MCP_GPIO11: CPU1.AN2 RN1809.5(B)
MCP_GPIO12: CPU1.AM7 RN2006.4(B)
MCP_GPIO13: CPU1.AT3 R2019.2
MCP_GPIO14: CPU1.AH4 R2015.2
MCP_GPIO15: CPU1.AD6 R2014.2
MCP_GPIO16: CPU1.Y1 TP2008.1
MCP_GPIO17: CPU1.T3 RN1505.6(B)
MCP_GPIO26: CPU1.AN3 R2009.2
MCP_GPIO27: CPU1.AN5 R2005.2 RN2006.3(B)
MCP_GPIO28: CPU1.AD7 R2016.2
MCP_GPIO35: CPU1.U1 RN1505.5(B)
MCP_GPIO36: CPU1.V6 RN2002.5(B)
MCP_GPIO37: CPU1.AC1 RN1801.3(B)
MCP_GPIO38: CPU1.L2 TP2006.1
MCP_GPIO44: CPU1.AK4 R2002.2
MCP_GPIO45: CPU1.AG5 R2028.2
MCP_GPIO46: CPU1.AG3 R2004.2 R2026.1
MCP_GPIO47: CPU1.AB6 R2020.2
MCP_GPIO50: CPU1.P3 RN2011.8(B)
MCP_GPIO51: CPU1.R5 RN2011.7(B)
MCP_GPIO52: CPU1.L1 RN1506.6(B)
MCP_GPIO54: CPU1.L3 RN1506.7(B)
MCP_GPIO55: CPU1.U7 R2008.1 RN1902.4(A)
MCP_GPIO56: CPU1.AG6 R2010.2
MCP_GPIO59: CPU1.AT5 RN2012.5(B)
MCP_GPIO68: CPU1.C3 TP2019.1
MCP_GPIO70: CPU1.C4 TP2005.1
MCP_GPIO73: CPU1.AU4 RN1601.6(B)
MCP_GPIO90: CPU1.K2 TP2014.1
MCP_R: R2002.1 R2009.1 R2010.1 R2015.1 R2016.1 R2019.1 R2020.1 R2022.2 R2028.1
MCP_TESTLOW1: CPU1.C35 RN1803.3(B)
MCP_TESTLOW2: CPU1.C34 RN1803.4(B)
MCP_TESTLOW3: CPU1.AK8 RN1804.4(B)
MCP_TESTLOW4: CPU1.AL8 RN1804.3(B)
MCU_BOOT0: R6606.1 U6601.44
MCU_OSCI: C6601.1 U6601.5 X6601.1
MCU_OSCO: C6609.1 U6601.6 X6601.3
MCU_RST#: C6602.1 R6602.1 R6603.1 U6601.7
ME_UNLOCK: KBC24.23 R1909.1
MIC2_VREFO: HDA27.29 RN2901.1(A) RN2901.2(A)
MIC_CAP: C2713.1 HDA27.19
MIC_GND: LCD1.20 R5202.1
MODEL_ID_DET: C2403.2 KBC24.94 R2405.2 R2407.1
MPWROK: CPU1.AB5 R1707.2
MUTE_CTRL: C2901.1 R2917.2 R2918.2 U2901.2
NC#4: PR4626.1 PU4601.4
NCT7718_DXN: C2606.2 C2607.2 Q2603.E THM261.3
NCT7718_DXP: C2606.1 C2607.1 Q2603.B Q2603.C THM261.2
P_SYS: KBC24.95 PR4467.2
PANEL_SIZE: KBC24.25 LCD1.35 R2452.2
PBAT_PRES1#: AFTP4301.1 BATT1.5 RN4301.8(B)
PBAT_SMBCLK1: AFTP4303.1 BATT1.3 RN4301.6(B)
PBAT_SMBDAT1: AFTP4302.1 BATT1.4 RN4301.7(B)
PCB_VER_AD: C2402.2 KBC24.98 R2404.2 R2406.1
PCH_DPWROK: CPU1.AV5 R1704.1 R1718.1
PCH_HDMI_CLK: CPU1.B9 Q5402.4 RN1501.3(B)
PCH_HDMI_DATA: CPU1.C9 Q5402.1 RN1501.4(B)
PCH_INTVRMEN: CPU1.AV7 R1903.2 R1913.2
PCH_JTAG_TCK: CPU1.AE62 R1920.2
PCH_JTAG_TDI: CPU1.AD61 R1916.1
PCH_JTAG_TDO: CPU1.AE61 R1917.1
PCH_JTAG_TMS: CPU1.AD62 R1918.1
PCH_JTAG_TRST#: CPU1.AU62 TP1901.1
PCH_OPIRCOMP: CPU1.AW15 R2003.1
PCH_PWROK: EC1704.1 KBC24.100 Q2602.G Q3601.3 R1706.1
PCH_SLP_S0#: CPU1.AF3 TP1706.1
PCH_SLP_WLAN#: CPU1.AM5 TP1705.1
PCH_SMBCLK: DIMM1.202 Q1801.4 R6708.1 RN1810.3(B) TP9649.1
PCH_SMBDATA: DIMM1.200 Q1801.1 R6709.1 RN1810.4(B) TP9646.1
PCH_SPI_CLK: CPU1.AA3 R1806.2
PCH_SPI_CS0#: CPU1.Y7 R1807.2
PCH_SPI_DQ2: CPU1.Y6 R1811.2 RN1802.3(B)
PCH_SPI_DQ3: CPU1.AF1 R1812.2 RN1802.4(B)
PCH_SPI_SI: CPU1.AA2 R1808.2
PCH_SPI_SO: CPU1.AA4 R1809.2
PCH_THERMTRIP: CPU1.D60 R2018.2
PCH_VCCDSW_R: C2114.1 R2110.2
PCH_WAKE#: CPU1.AJ5 R1703.2 R1705.1
PCI_PLTRST#: CPU1.AG7 R1713.2
PCI_PME#: CPU1.AD4 TP1501.1
PCIE_CLK_XDP_N: CPU1.B35 TP9651.1
PCIE_CLK_XDP_P: CPU1.A35 TP9652.1
PCIE_PRX_WLANTX_N3: CPU1.G11 IOBD1.11
PCIE_PRX_WLANTX_P3: CPU1.F11 IOBD1.12
PCIE_PTX_WLANRX_N3: C1601.2 CPU1.C29
PCIE_PTX_WLANRX_N3_C: C1601.1 IOBD1.14
PCIE_PTX_WLANRX_P3: C1602.2 CPU1.B30
PCIE_PTX_WLANRX_P3_C: C1602.1 IOBD1.15
PCIE_RCOMP: CPU1.A27 R1601.2
PCIE_WAKE#: KBC24.113 R1705.2 R2005.1 R2450.1
PD4403_A: PD4403.A PQ4408.B
PD4403_K: PD4403.K PR4458.2
PECI: C2422.1 KBC24.13 R2429.1
PIRQA#: CPU1.U6 RN1902.1(A)
PIRQB#: CPU1.P4 R1501.2 RN1505.7(B)
PIRQC#: CPU1.N4 RN1506.5(B)
PIRQD#: CPU1.N2 RN1505.8(B)
PLT_RST#: C1701.1 DB1.4 EC1703.1 IOBD1.23 R1713.1 R1715.1 R2416.2
PLT_RST#_EC: C2415.2 KBC24.7 R2416.1
PM_CLKRUN#: CPU1.V5 R1709.1 R1714.1
PM_CLKRUN#_EC: KBC24.8 R1709.2
PM_PCH_PWROK: CPU1.AY7 R1706.2 R1707.1 RN1703.3(B)
PM_PWRBTN#: CPU1.AL7 KBC24.117 TP9645.1
PM_RSMRST#: CPU1.AW6 Q1701.3 R1702.1 R1704.2 RN1703.4(B)
PM_SLP_A#: CPU1.AL5 TP1704.1
PM_SLP_LAN#: CPU1.AJ7 TP1707.1
PM_SLP_S3#: CPU1.AT4 KBC24.64 PR4804.1 PR4925.1 PR5101.1 Q3601.2 R3609.1
PM_SLP_S4#: CPU1.AJ6 KBC24.21 PR4905.1 PR4914.1
PM_SLP_S5#: CPU1.AP5 TP1703.1
PM_SLP_SUS#: CPU1.AP4 KBC24.108 R1729.2 R3802.1
PM_SUS_STAT#: CPU1.AG4 R1724.2 TP1702.1
PM_SUSACK#: KBC24.91 RN1702.1(A)
PM_SUSACK#_R: CPU1.AK2 R1708.2 RN1702.4(B)
PM_SUSWARN#: KBC24.79 RN1702.2(A)
PM_SUSWARN#_R: CPU1.AV4 R1708.1 RN1601.5(B) RN1702.3(B)
PQ3802_1: PQ4202.B PR4202.1 PR4209.2
PQ4401_D: PQ4401.D PR4464.2
PQ4401_G: PQ4401.G PR4419.2
PQ4405_2: PQ4405.2 PR4462.1 PR4463.1
PQ4405_3: PQ4405.3 PR4455.1
PQ4405_5: PC4404.1 PQ4405.5 PR4405.2
PQ4405_6: PC4404.2 PQ4405.6 PR4450.1
PQ4406_D: PQ4406.D PR4456.2
PQ4406_G: PC4414.2 PQ4406.G PR4429.1
PQ4408_C: PQ4408.C PR4451.1 PR4462.2
PQ4408_E: PQ4408.E PR4416.2 PR4433.1
PQ4411_D1: PQ4411.3 PR4401.2
PQ4411_D2: PQ4411.6 PR4420.1
PQ4413_3: PQ4413.3 PR4457.1
PQ4413_5: PC4405.1 PQ4413.5 PR4436.2
PROC_OPI_COMP: CPU1.AY15 R602.1
PROC_OPI_COMP3: CPU1.Y22 R606.1
PROCHOT#_BQ24770: PR4469.2 PU4401.10
PROCHOT_EC: KBC24.24 Q2401.G R2438.1 R2442.1
PS_ID: PQ4201.S PR4205.1 PR4206.2
PS_ID_R: AFTP4203.1 DCIN1.4 PR4217.1
PS_ID_R2: PD4204.1 PD4204.2 PQ4201.D PR4206.1 PR4209.1 PR4217.2
PS_S3CNTRL: Q3601.5 Q3601.6 R3607.2
PSID_DISABLE#_R_C: PQ4201.G PQ4202.C PR4203.2
PSID_EC: KBC24.99 PD4203.3 PR4204.2 PR4205.2
PSL_IN1#: KBC24.73 R2430.2
PSL_IN2#: KBC24.93 R2425.1 R2427.2
PSL_OUT#: KBC24.74 R2432.1
PU4401_4: PC4423.2 PR4407.2 PR4454.2 PU4404.4
PU4401_5: PC4423.1 PR4407.1 PR4448.2 PU4404.5
PU4401_6: PR4446.2 PU4404.6
PU4402_1IN+: PR4440.1 PR4441.2 PR4461.2 PU4402.3
PU4402_1IN-: PR4442.2 PR4447.1 PR4465.2 PU4402.2
PU4902_S5: PR4914.2 PU4902.9
PU4902_VCNTL: PC4911.1 PR4917.1 PR4918.1 PU4902.10
PURE_HW_SHUTDOWN#: C2610.1 D3602.3 Q2404.B Q2602.D R2424.1 R2439.2
PWR_1D5V_EN: PC5101.1 PR5101.2 PU5101.3
PWR_1D05V_PWR_EN: PC4801.1 PR4803.1 PR4804.2 PU4801.1
PWR_1D05V_PWR_ILIM: PR4802.1 PU4801.3
PWR_1D35V: PC4901.1 PC4902.1 PC4903.1 PC4904.1 PC4905.1 PC4912.1 PG4902.1 PG4904.1 PG4905.1 PG4908.1 PG4909.1 PL4901.2 PR4903.1
PWR_1D35V_BOOT: PR4901.1 PU4901.6
PWR_1D35V_BOOT_R: PC4917.1 PR4901.2
PWR_1D35V_BYP: PC4910.1 PR4902.1 PU4901.7
PWR_1D35V_EN: PC4909.1 PR4905.2 PU4901.1
PWR_1D35V_IMAX: PR4906.2 PU4901.3
PWR_1D35V_LDO_P5: PC4913.1 PU4901.5
PWR_1D35V_PGOOD: PR4907.2 PR4910.2 PU4901.2
PWR_1D35V_PHASE: PC4917.2 PL4901.1 PU4901.10
PWR_1D35V_VFB: PC4912.2 PR4903.2 PR4904.1 PU4901.4
PWR_3D3V_CS2: PR4517.1 PU4503.5
PWR_3D3V_DRVH2: PU4502.1 PU4503.10
PWR_3D3V_DRVL2: PU4502.4 PU4503.11
PWR_3D3V_EN2: PR4506.2 PU4503.6
PWR_3D3V_FB2: PC4523.2 PR4512.2 PR4523.1 PU4503.4
PWR_3D3V_FB2_R: PC4523.1 PR4535.2
PWR_3D3V_LL2: PC4535.2 PL4503.2 PR4533.1 PU4502.5 PU4503.8
PWR_3D3V_SNUB: PC4520.1 PR4533.2
PWR_3D3V_VBST2: PR4528.2 PU4503.9
PWR_3D3V_VBST2_1: PC4535.1 PR4528.1
PWR_5V_CS1: PR4531.1 PU4503.1
PWR_5V_DRVH1: PU4501.1 PU4503.16
PWR_5V_DRVL1: PU4501.4 PU4503.15
PWR_5V_EN1: PR4504.2 PU4503.20
PWR_5V_EN1_R: PR4501.2 PR4504.1 PR4515.2 PR4530.1
PWR_5V_FB1: PC4522.2 PR4526.1 PR4527.2 PU4503.2
PWR_5V_FB1_R: PC4522.1 PR4525.2
PWR_5V_LL1: PC4516.2 PL4501.1 PR4529.1 PU4501.5 PU4503.18
PWR_5V_SNUB: PC4536.1 PR4529.2
PWR_5V_VBST1: PR4524.1 PU4503.17
PWR_5V_VBST1_1: PC4516.1 PR4524.2
PWR_5V_VCLK: AFTP4501.1 PR4502.1 PU4503.19
PWR_5V_VO1: PG4532.2 PR4525.1 PR4527.1 PU4503.14
PWR_CHG_1: PD4405.K PD4406.K PR4403.1
PWR_CHG_ACDET: PC4402.1 PR4411.1 PR4444.2 PU4401.6
PWR_CHG_ACN: PC4416.2 PC4428.1 PG4402.2 PR4421.1 PU4401.1
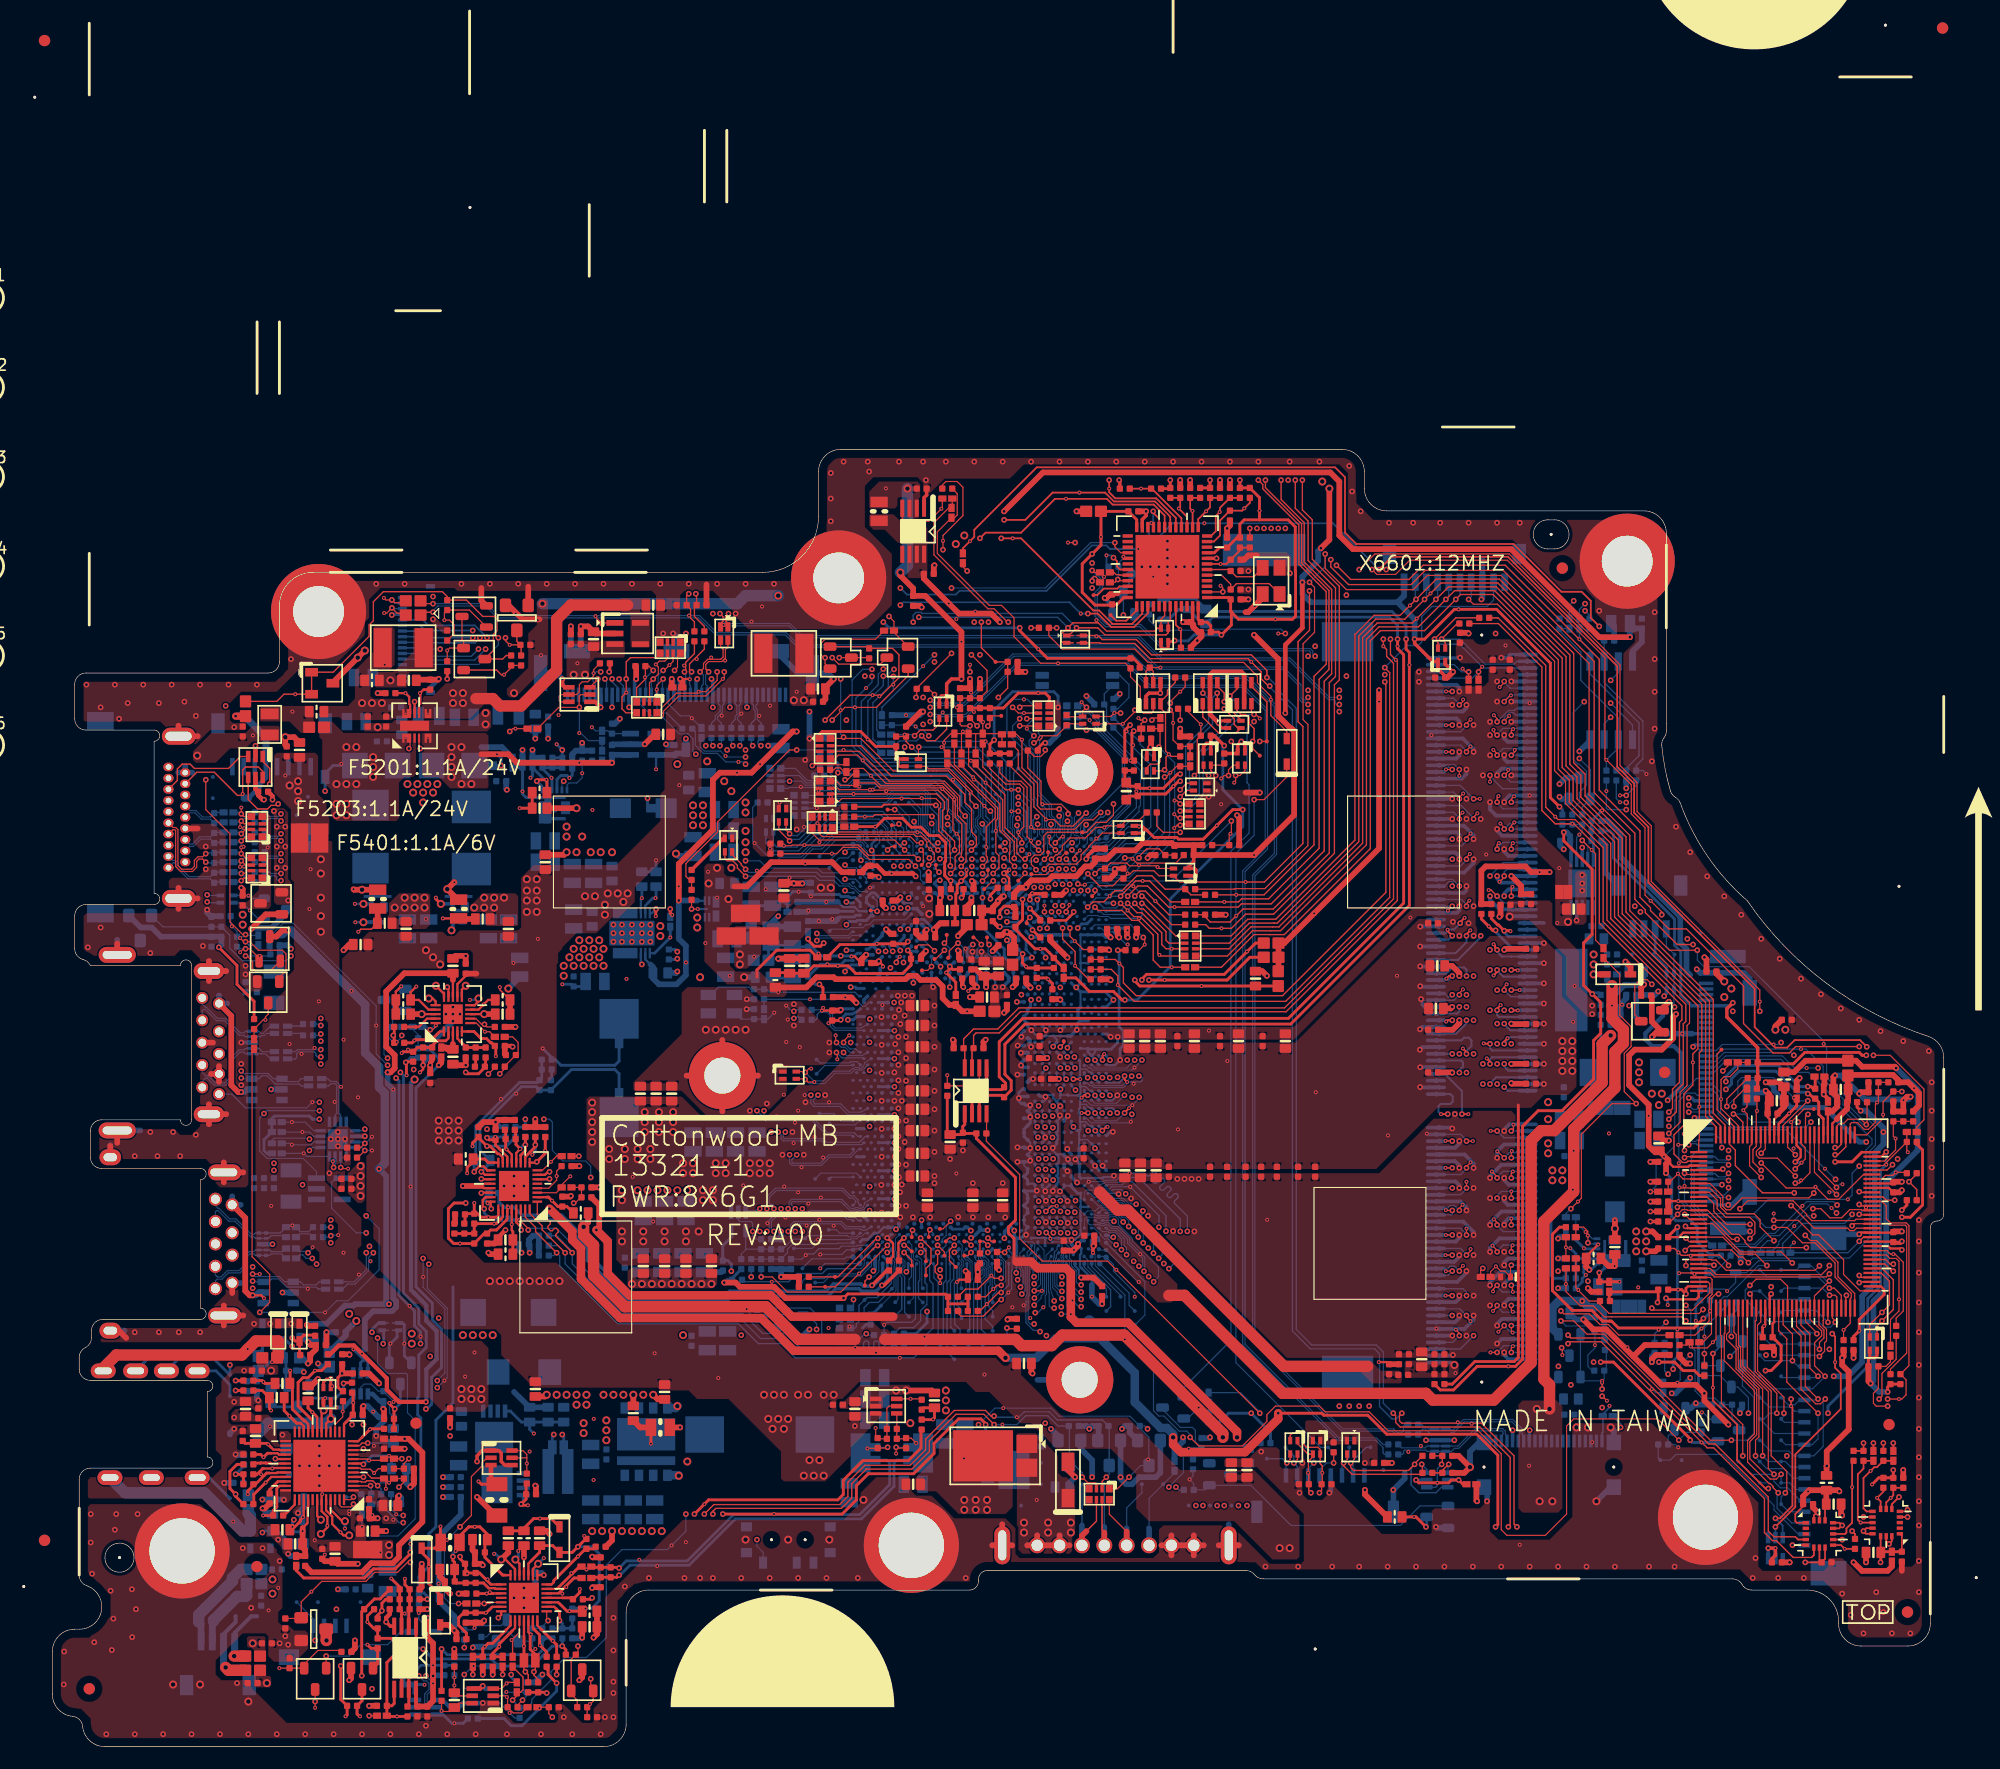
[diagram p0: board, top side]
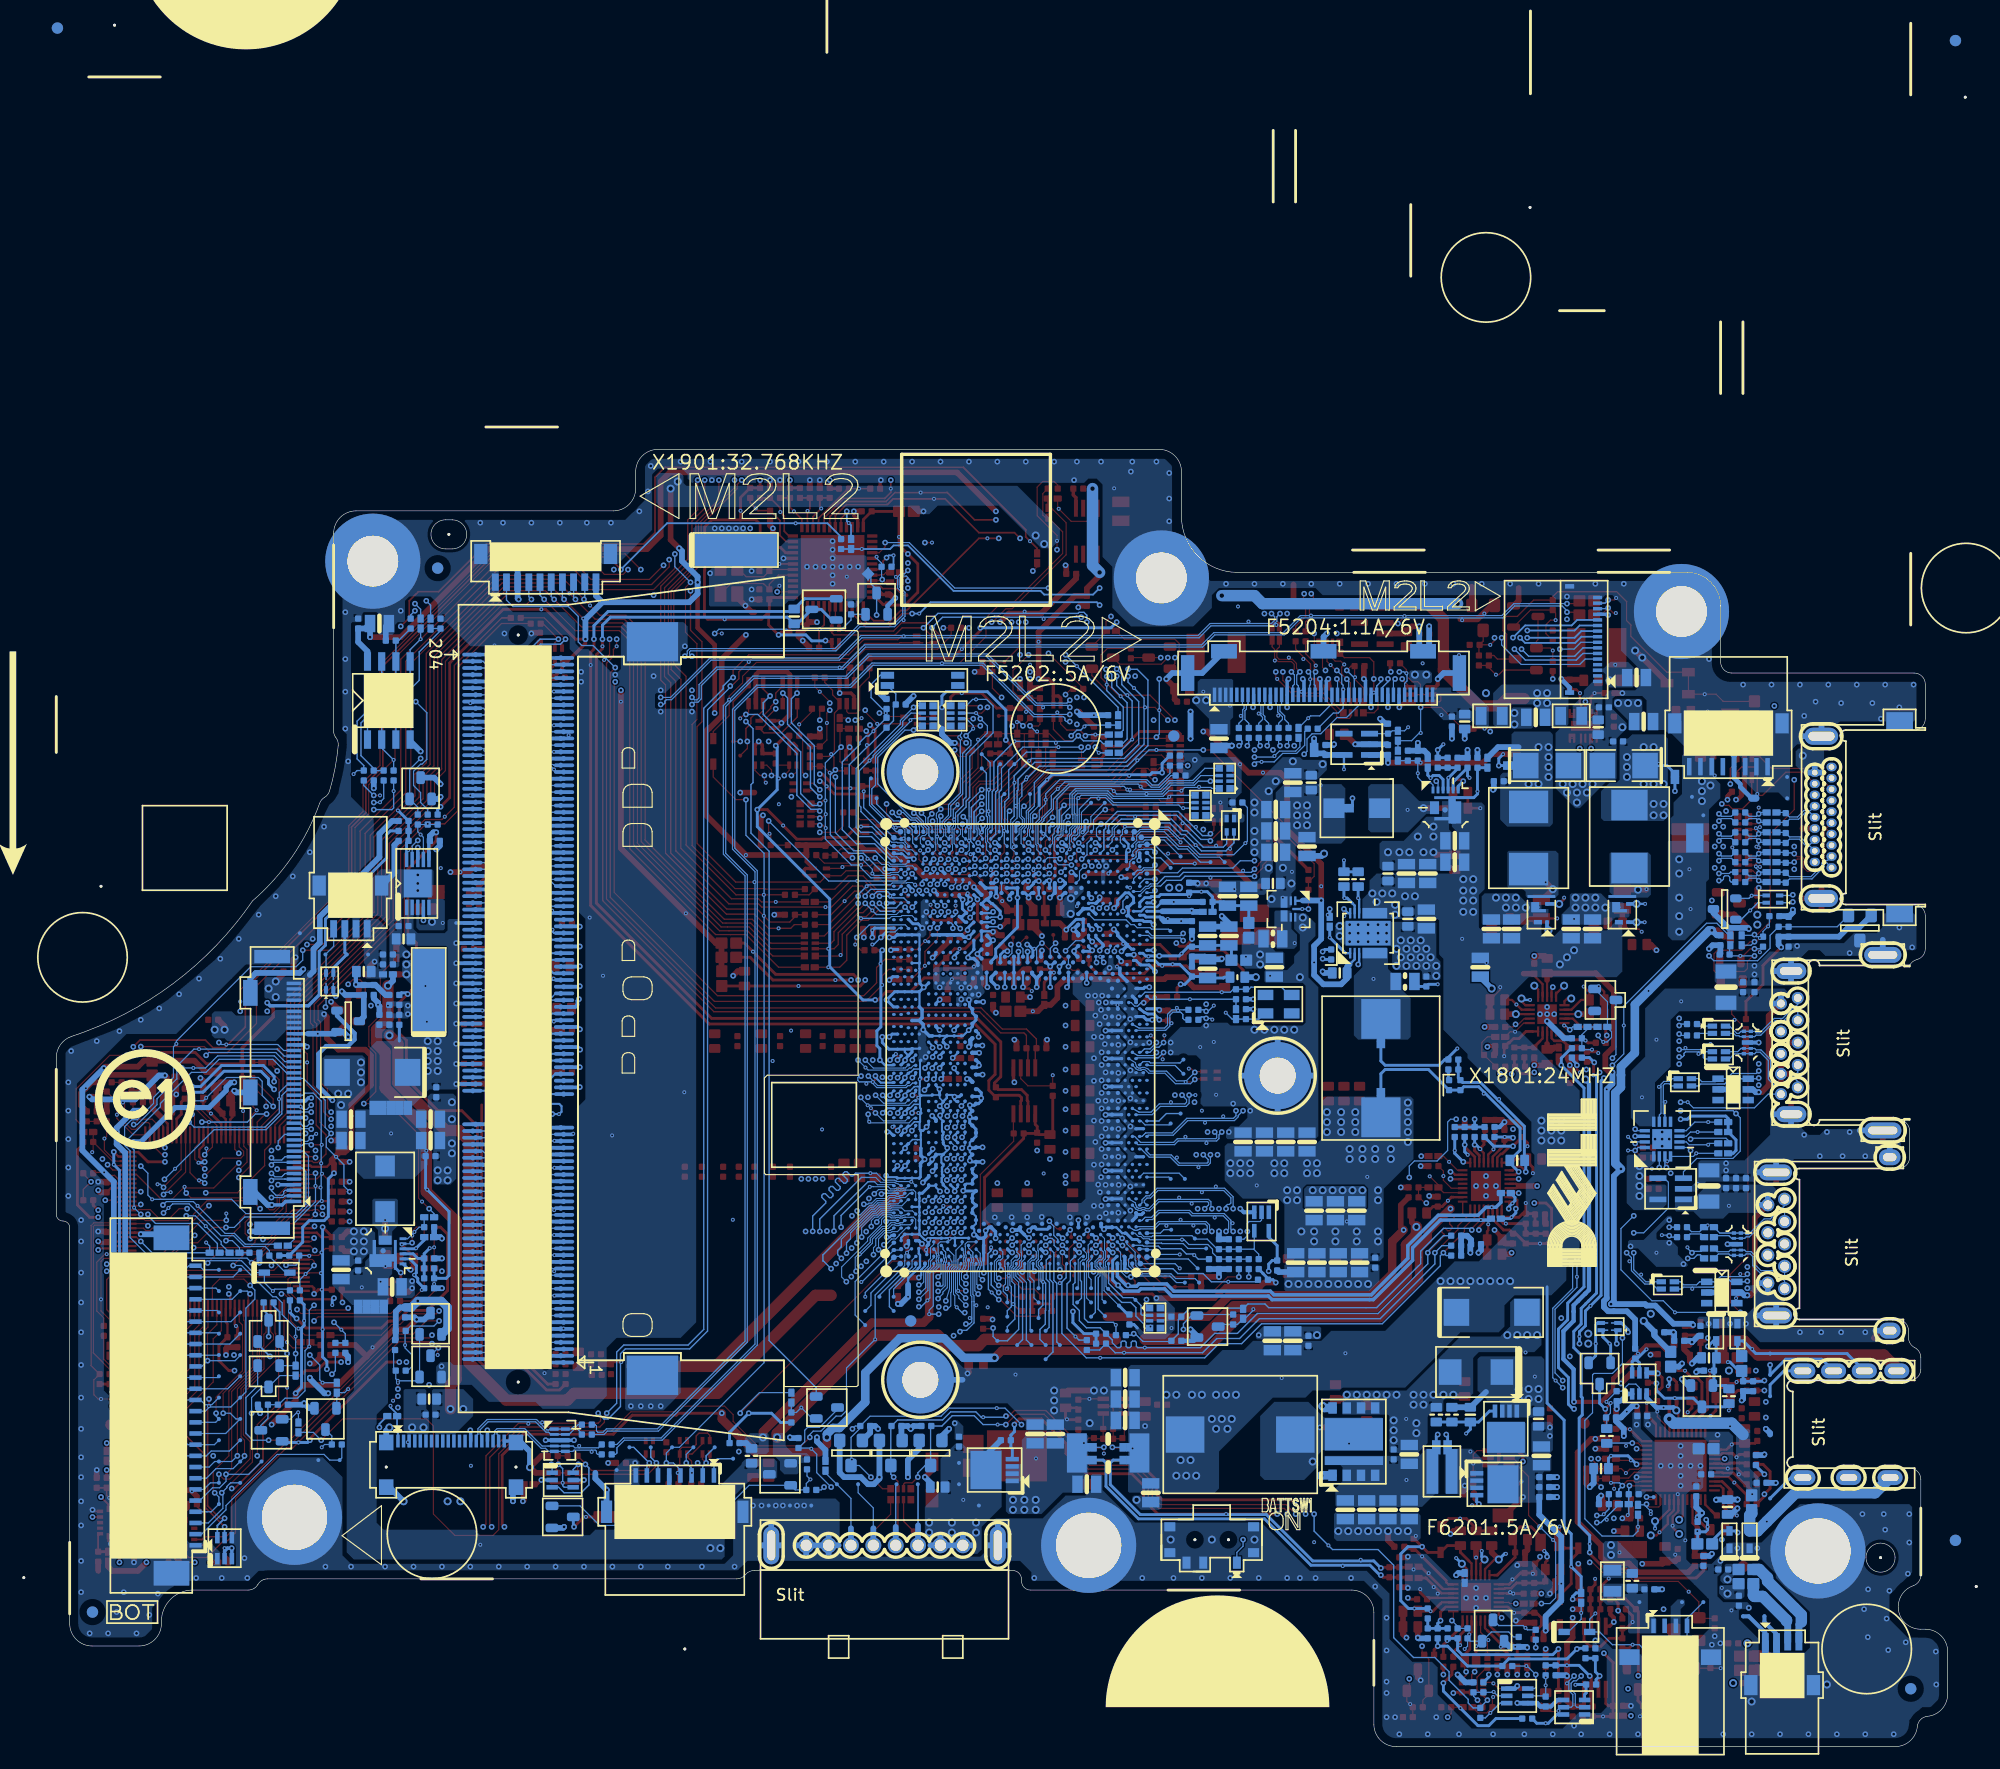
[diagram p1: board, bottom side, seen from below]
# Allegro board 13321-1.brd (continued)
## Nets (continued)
PWR_CHG_ACOK: PQ4413.2 PR4404.1 PR4410.2 PR4430.1 PR4463.2 PU4401.5
PWR_CHG_ACP: PC4418.2 PC4428.2 PC4432.1 PG4406.2 PR4421.2 PU4401.2
PWR_CHG_BAT: PR4408.2 PU4401.17
PWR_CHG_BATDRV: PR4409.1 PU4401.18
PWR_CHG_BTST: PR4425.1 PU4401.25
PWR_CHG_BTST1: PC4421.1 PD4401.K PR4425.2
PWR_CHG_CMPIN: PR4401.1 PR4402.2 PR4413.1 PR4420.2 PR4428.2 PU4402.6
PWR_CHG_CMPOUT: PR4415.1 PR4422.1 PR4436.1 PR4437.2 PU4402.7
PWR_CHG_CMSRC: PR4439.2 PU4401.3
PWR_CHG_HIDRV: PU4401.26 PU4406.1
PWR_CHG_LODRV: PU4401.23 PU4406.8
PWR_CHG_PHASE: PC4421.2 PL4401.1 PR4427.1 PU4401.27 PU4406.9
PWR_CHG_REGN: PC4422.1 PD4401.A PR4410.1 PR4441.1 PR4449.1 PR4453.1 PR4470.1 PU4401.24
PWR_CHG_SRN: PR4417.1 PU4401.19
PWR_CHG_SRN_R: PC4412.1 PC4429.2 PG4403.1 PR4417.2
PWR_CHG_SRP: PR4438.1 PU4401.20
PWR_CHG_SRP_R: PC4401.1 PC4429.1 PG4407.1 PR4438.2
PWR_CHG_VCC: PC4410.1 PC4433.1 PR4403.2 PU4401.28
PWR_DCBATOUT_1D35V: PC4906.1 PC4907.1 PC4908.1 PG4901.2 PG4903.2 PG4906.2 PG4907.2 PU4901.8
PWR_DEBUG: CPU1.H59 R705.2 TP9647.1
PWR_PG: PR4625.1 PU4601.3
PWR_SCL: PG4401.1 PU4401.12
PWR_SDA: PG4408.1 PU4401.11
PWR_VCC_B-RAMP: PR4601.1 PR4603.2 PU4601.11
PWR_VCC_BOOT1: PC4706.2 PU4701.7
PWR_VCC_BOOTR1: PR4703.1 PU4701.6
PWR_VCC_COMP: PC4604.1 PC4608.2 PR4619.2 PR4620.1 PU4601.26
PWR_VCC_COMP_1: PC4608.1 PR4627.2
PWR_VCC_CSN1: PC4707.2 PG4708.1 PR4705.2 PR4707.2 PU4601.18
PWR_VCC_CSP1: PC4707.1 PR4704.2 PR4705.1 PR4706.1 PU4601.17
PWR_VCC_DROOP: PC4604.2 PR4619.1 PR4627.1 PU4601.25
PWR_VCC_F-IMAX: PR4604.2 PR4607.1 PU4601.10
PWR_VCC_GFB: PR4616.2 PU4601.23
PWR_VCC_IMON: PC4602.1 PR4610.1 PU4601.13
PWR_VCC_O-USR: PR4605.2 PR4608.1 PU4601.9
PWR_VCC_OCP-1: PR4609.1 PR4610.2 PU4601.12
PWR_VCC_PWM1: PU4601.6 PU4701.8
PWR_VCC_SKIP#: PR4702.1 PU4601.7
PWR_VCC_SKIP#1: PR4702.2 PU4701.1
PWR_VCC_SLEWA: PR4611.2 PR4612.2 PU4601.15
PWR_VCC_THERM: PC4603.2 PR4602.2 PU4601.14 R3024.2
PWR_VCC_V5A: PC4607.1 PR4624.1 PU4601.28
PWR_VCC_VBAT: PR4613.2 PU4601.16
PWR_VCC_VDD: PC4601.1 PR4618.1 PU4601.2
PWR_VCC_VFB: PR4617.2 PU4601.24
PWR_VCC_VREF: PC4606.2 PR4602.1 PR4603.1 PR4604.1 PR4605.1 PR4611.1 PR4620.2 PU4601.27
PWR_VCC_VSW1: PG4707.2 PL4701.1 PR4701.1 PU4701.4
Q6204_G: Q6204.2 Q6204.5 R6216.2
Q6205_Q: Q6205.D R6210.2
RING2: EC2905.1 HDA27.17 R2906.1 RN2901.4(B)
RING2_R: ED2903.2 HPMIC1.3 R2906.2
RSMRST#_KBC: KBC24.15 R1702.2
RSVDA51: CPU1.A51 TP606.1
RSVDAU63: CPU1.AU63 TP602.1
RSVDAV63: CPU1.AV63 TP601.1
RSVDB51: CPU1.B51 TP607.1
RSVDC62: CPU1.C62 TP604.1
RSVDC63: CPU1.C63 TP603.1
RSVDL60: CPU1.L60 TP608.1
RSVDN59: CPU1.N59 TP704.1
RSVDN61: CPU1.N61 TP705.1
RSVDP60: CPU1.P60 TP702.1
RSVDP61: CPU1.P61 TP703.1
RTC_AUX_S5: C1120.1 C1121.1 C1122.1 C2503.1 CPU1.AG10 D2501.3 R1720.2 R1901.1 R1903.1 R2428.2 RN1901.1(A) RN1901.2(A)
RTC_DET#: CPU1.AD5 Q2505.D RN2012.6(B)
RTC_RST#: C1901.1 CPU1.AU7 G1901.2 Q1901.D RN1901.4(B)
RTC_X1: C1903.2 CPU1.AW5 R1915.1 X1901.1
RTC_X2: C1904.2 CPU1.AY5 R1915.2 X1901.4
RTCRST_ON: KBC24.120 Q1901.G R1902.1
S5_ENABLE: KBC24.14 Q2403.D R2436.2 R3603.2
SA0_DIMA: DIMM1.197 R1201.1
SA1_DIMA: DIMM1.201 R1202.1
SATA3_PRX_HDDTX_N0: C5616.1 CPU1.J5
SATA3_PRX_HDDTX_P0: C5615.1 CPU1.H5
SATA3_PTX_HDDRX_N0: C5603.1 CPU1.B15
SATA3_PTX_HDDRX_P0: C5602.1 CPU1.A15
SATA_IREF: CPU1.A12 R1904.1
SATA_LED#: CPU1.U3 R1905.2
SATA_ODD_PWRGT: CPU1.N6 TP2004.1
SATA_RCOMP: CPU1.C12 R1906.1
SATA_RXN0_R: C5616.2 HDD1.18 U5602.4 U5602.7
SATA_RXP0_R: C5615.2 HDD1.19 U5602.5 U5602.6
SATA_TXN0_R: C5603.2 HDD1.16 U5602.2 U5602.9
SATA_TXP0_R: C5602.2 HDD1.15 U5602.1 U5602.10
SENSOR_HUB_RST#: CPU1.L4 R6603.2
SENSOR_I2C_SCL: HOMBD1.7 LCD1.31 RN6601.4(B) RN6604.2 U6601.42
SENSOR_I2C_SCL_2G: RN6604.3 U6602.4
SENSOR_I2C_SDA: HOMBD1.6 LCD1.30 RN6601.3(B) RN6604.1 U6601.43
SENSOR_I2C_SDA_2G: RN6604.4 U6602.6
SLEEVE: EC2906.1 HDA27.18 R2911.1 RN2901.3(B) U2901.3
SLEEVE_CTRL: R2915.2 U2901.5 U2901.6
SLEEVE_R: ED2905.2 HPMIC1.4 R2911.2
SM_DRAMRST#: CPU1.AV15 R404.1 R410.2
SM_INTRUDER#: CPU1.AU6 R1901.2
SM_RCOMP_0: CPU1.AU60 R407.2
SM_RCOMP_1: CPU1.AV60 R408.2
SM_RCOMP_2: CPU1.AU61 R409.2
SMB_CLK: CPU1.AP2 Q1801.3 RN1807.6(B)
SMB_DATA: CPU1.AH1 Q1801.6 RN1807.5(B)
SML0_CLK: CPU1.AN1 RN1807.7(B)
SML0_DATA: CPU1.AK1 RN1807.8(B)
SML1_CLK: CPU1.AU3 KBC24.67 Q2601.3 RN1811.4(B)
SML1_DATA: CPU1.AH3 KBC24.68 Q2601.6 RN1811.3(B)
SPI_CLK_R: EC2503.1 R1806.1 R2420.1 SPI25.6
SPI_CS0#_R: R1807.1 R2419.1 R2501.1 SPI25.1
SPI_HOLD#: R1812.1 SPI25.7
SPI_SI_R: EC2501.1 R1808.1 R2422.1 SPI25.5
SPI_SO_R: EC2502.1 R1809.1 R2423.1 SPI25.2
SPI_WP#: R1811.1 SPI25.3
SRTC_RST#: C1902.1 CPU1.AV6 RN1901.3(B)
SUS_CLK: R1710.2 R2441.2
SUS_CLK_PCH: CPU1.AE6 EC1701.2 R1710.1
SUSCLK_KBC: KBC24.77 R2441.1
SWCLK: TP6602.1 U6601.37
SWDIO: TP6601.1 U6601.34
SYS_PRES1#: AFTP4304.1 BATSW1.1 BATT1.6 R4301.1
SYS_PWROK: CPU1.AG2 EC1702.1 KBC24.84 R1717.1 TP9644.1
T_CRIT#: R2601.1 R2604.2 THM261.4
TD_IREF: CPU1.B12 R603.2
THERM_SYS_SHDN#: Q2602.S R2601.2 R2602.1
THM_SML1_CLK: C2608.1 Q2601.4 RN2602.4(B) THM261.8
THM_SML1_DATA: C2609.1 Q2601.1 RN2602.3(B) THM261.7
TOUCH_PANEL_INTR#: D2401.A HOMBD1.5 R2443.1
TP_CL_CLK: CPU1.AF2 TP1801.1
TP_CL_DATA: CPU1.AD2 TP1802.1
TP_CL_RST#: CPU1.AF4 TP1803.1
TP_DC_TEST_A4: CPU1.A4 TP2202.1
TP_DC_TEST_A60: CPU1.A60 TP2203.1
TP_DC_TEST_A62: CPU1.A62 TP2205.1
TP_DC_TEST_AV1: CPU1.AV1 TP2206.1
TP_DC_TEST_AW1: CPU1.AW1 TP2207.1
TP_DC_TEST_AW63: CPU1.AW63 TP2208.1
TP_DC_TEST_AY60: CPU1.AY60 TP2201.1
TP_DC_TEST_B2: CPU1.B2 TP2204.1
TP_HDA_DOCK_EN#: CPU1.AW10 TP1902.1
TP_LOCK#: AFTP6242.1 R2437.1 TP1.3
TP_LOCK#_C: KBC24.123 R2437.2 R2455.1
TP_M_A_DIMA_ODT0: CPU1.AP32 TP501.1
TP_ON#: KBC24.119 R2445.1 R6204.1
TP_ON#_GATE: C6204.2 Q6203.G Q6205.G R6204.2
TP_V1.05S_APLLOPI: CPU1.AC20 TP2105.1
TP_V1.05S_AXCK_DCB: CPU1.M20 TP2104.1
TP_V1.05S_SSCF100: CPU1.K18 TP2103.1
TP_V1.05S_SSCFF: CPU1.V21 TP2101.1
TP_VCCAPLLOPI_VAL: CPU1.Y20 TP2102.1
TP_VCCIO_OUT: CPU1.A59 TP701.1
TP_VDD: AFTP6239.1 C6201.1 Q6203.D R6203.1 R6210.1 R6211.2 RN6201.1(A) RN6201.2(A) RN6204.1(A) RN6204.2(A) TP1.8
TP_WAKE_KBC#: KBC24.121 R2426.2
TPAN_VDD: C5205.1 C5206.1 F5203.2 HOMBD1.3 R5233.2
TPCLK: EC6201.1 KBC24.72 RN6201.4(B) RN6202.2(A)
TPCLK_C: AFTP6238.1 RN6202.3(B) TP1.1
TPDATA: EC6202.1 KBC24.71 RN6201.3(B) RN6202.1(A)
TPDATA_C: AFTP6236.1 RN6202.4(B) TP1.2
USB3_PRX_CTX_N0: CPU1.G20 R3414.1
USB3_PRX_CTX_N1: CPU1.E18 TR3405.2
USB3_PRX_CTX_P0: CPU1.H20 R3415.1
USB3_PRX_CTX_P1: CPU1.F18 TR3405.1
USB3_PTX_CRX_N0: C3407.1 CPU1.C33
USB3_PTX_CRX_N1: C3406.1 CPU1.B33
USB3_PTX_CRX_P0: C3408.1 CPU1.B34
USB3_PTX_CRX_P1: C3405.1 CPU1.A33
USB20_DN0_C: EU3404.1 TR3402.4 USB2.2
USB20_DN1_C: EU3402.1 TR3401.4 USB1.2
USB20_DP0_C: EU3404.6 TR3402.3 USB2.3
USB20_DP1_C: EU3402.6 TR3401.3 USB1.3
USB30_RXDN0_C: EU3403.1 EU3403.9 R3414.2 USB2.5
USB30_RXDN1_C: EU3401.1 EU3401.9 TR3405.3 USB1.5
USB30_RXDP0_C: EU3403.2 EU3403.8 R3415.2 USB2.6
USB30_RXDP1_C: EU3401.2 EU3401.8 TR3405.4 USB1.6
USB30_TXDN0_C: EU3403.4 EU3403.7 R3413.2 USB2.8
USB30_TXDN0_R: C3407.2 R3413.1
USB30_TXDN1_C: EU3401.4 EU3401.7 TR3404.3 USB1.8
USB30_TXDN1_R: C3406.2 TR3404.2
USB30_TXDP0_C: EU3403.5 EU3403.6 R3416.2 USB2.9
USB30_TXDP0_R: C3408.2 R3416.1
USB30_TXDP1_C: EU3401.5 EU3401.6 TR3404.4 USB1.9
USB30_TXDP1_R: C3405.2 TR3404.1
USB30_VCCA: C3404.1 C3503.1 C3505.1 EU3402.5 U3503.12 USB1.1
USB30_VCCB: C3409.1 C3521.1 C3522.1 EU3404.5 R3503.1 U3502.1 USB2.1
USB_3+: R6601.2 R6605.1 U6601.33
USB_3-: R6604.2 U6601.32
USB_CAMERA_N: LCD1.16 TR5208.3
USB_CAMERA_P: LCD1.15 TR5208.4
USB_CHG_EN: KBC24.105 U3503.5
USB_COMP: CPU1.AJ10 CPU1.AJ11 R1602.1
USB_DET#: D2402.1 KBC24.20 R2451.1 R2453.1
USB_OC#0_1: CPU1.AL3 RN1809.7(B) U3502.3 U3503.13
USB_OC#2_3: CPU1.AT1 IOBD1.28 RN1601.8(B)
USB_OC#4_5: CPU1.AH2 RN2012.7(B)
USB_OC#6_7: CPU1.AV3 RN1601.7(B)
USB_PN0: CPU1.AN8 TR3402.1
USB_PN1: CPU1.AR7 U3503.2
USB_PN1_R: TR3401.1 U3503.11
USB_PN2: CPU1.AR8 IOBD1.3
USB_PN3: CPU1.AR10 R6604.1
USB_PN4: CPU1.AM15 TR5208.2
USB_PN5: CPU1.AM13 IOBD1.9
USB_PN6: CPU1.AP11 R5230.1
USB_PN6_TPNL: HOMBD1.15 R5230.2
USB_PN7: CPU1.AR13 IOBD1.5
USB_PP0: CPU1.AM8 TR3402.2
USB_PP1: CPU1.AT7 U3503.3
USB_PP1_R: TR3401.2 U3503.10
USB_PP2: CPU1.AP8 IOBD1.2
USB_PP3: CPU1.AT10 R6601.1
USB_PP4: CPU1.AL15 TR5208.1
USB_PP5: CPU1.AN13 IOBD1.8
USB_PP6: CPU1.AN11 R5223.1
USB_PP6_TPNL: HOMBD1.14 R5223.2
USB_PP7: CPU1.AP13 IOBD1.6
USB_PWR_EN#: IOBD1.27 KBC24.101 R2412.1 U3502.4
USBCHARGER_CB0: KBC24.106 R3501.1
USBDET_CON#: D2402.3 R2453.2 USB1.D1
USBDISABLE: R6605.2 U6601.31
VD1_EN#: KBC24.66 R2449.2
VD_IN1: C2612.1 C2613.1 KBC24.104 R2608.2 R2609.2 R2610.1
VD_IN1_C: C2612.2 C2613.2 R2610.2 R2611.1
VD_OUT1#: KBC24.110 R2602.2 R2607.2
VOL_DOWN#: IOBD1.13 KBC24.26 R2448.1
VOL_UP#: IOBD1.10 KBC24.63 R2446.1
VR_SVID_ALERT#: PR4623.1 PU4601.32 R701.1 R703.2
VTT_EN: PR4909.2 PR4925.2 PR4926.2 PU4902.7
WIFI_RF_EN: IOBD1.24 KBC24.82
XCLK_BIASREF: CPU1.C26 R1803.1
XDP_BPM0: CPU1.J60 TP9612.1
XDP_BPM1: CPU1.H60 TP9613.1
XDP_BPM2: CPU1.H61 TP9614.1
XDP_BPM3: CPU1.H62 TP9615.1
XDP_BPM4: CPU1.K59 TP9616.1
XDP_BPM5: CPU1.H63 TP9617.1
XDP_BPM6: CPU1.K60 TP9618.1
XDP_BPM7: CPU1.J61 TP9619.1
XDP_DBRESET#: CPU1.AC3 EC1706.1 R1701.2 TP9653.1
XDP_PRDY#: CPU1.J62 TP9602.1
XDP_PREQ#: CPU1.K62 TP9601.1
XDP_TCK_JTAGX: CPU1.AE63 R1919.1
XDP_TCLK: CPU1.E60 R406.1 TP9650.1
XDP_TDI: CPU1.F63 RN401.2(A) TP9623.1
XDP_TDO: CPU1.F62 RN401.4(A) TP9624.1
XDP_TMS: CPU1.E61 RN401.1(A) TP9611.1
XDP_TRST#: CPU1.E59 R402.1 TP9621.1
XTAL24_IN: CPU1.A25 R1802.1 R1810.1
XTAL24_IN_R: C1801.2 R1810.2 X1801.1
XTAL24_OUT: C1802.2 CPU1.B25 R1802.2 X1801.3
N29302517: PR4470.2 PR4471.1 PU4401.21
N172633395: PC4201.2 PR4207.2 PR4208.1 PU4201.4

Pads without a net: CPU1 A5 A6 A8 A17 A21 A23 A29 A31 A37 A39 A41 A49 A53 AA23 AA59 AB21 AB23 AC2 AC4 AC58 AC59 AD23 AD59 AD60 AE59 AE60 AF20 AG58 AK18 AK20 AK21 AK22 AK25 AK26 AK28 AK29 AK32 AK33 AK35 AK36 AK38 AL1 AL11 AL18 AL21 AL25 AL28 AL32 AL35 AL38 AM10 AM11 AM18 AM20 AM21 AM22 AM25 AM26 AM28 AM29 AM32 AM33 AM35 AM36 AM38 AN10 AN18 AN20 AN21 AN22 AN25 AN26 AN28 AN29 AN38 AP7 AP18 AP21 AP25 AP28 AP40 AP42 AP45 AP46 AP51 AR18 AR20 AR21 AR22 AR25 AR26 AR28 AR29 AR40 AR42 AR45 AR46 AT2 AU10 AU12 AU15 AU17 AU19 AU21 AU23 AU25 AU27 AU29 AU31 AU44 AU46 AU47 AU49 AU50 AV2 AV10 AV17 AV18 AV19 AV21 AV22 AV23 AV25 AV26 AV27 AV29 AV30 AV31 AV44 AV47 AV50 AV62 AW14 AW17 AW18 AW19 AW21 AW22 AW23 AW25 AW26 AW27 AW29 AW30 AW31 AW46 AW49 AY8 AY14 AY17 AY19 AY21 AY23 AY25 AY27 AY29 AY31 AY42 AY43 AY46 AY47 AY49 B5 B6 B14 B17 B21 B22 B23 B29 B31 B37 B38 B39 B41 B49 B50 B53 B54 C5 C15 C17 C21 C22 C23 C30 C31 C37 C42 C43 C46 C47 C49 C50 C51 C53 D1 D9 D15 D17 D58 D61 E1 E2 E4 E5 E6 E8 E10 E13 E15 F4 F5 F6 F8 F10 F13 F15 F17 F22 G1 G10 G13 G15 G17 H6 H8 H10 H18 H22 J3 J6 J8 J20 J21 J58 K10 K21 L5 L6 L11 L59 M21 N5 N7 N23 N58 N60 R6 R7 R23 T23 T59 U10 U59 V59 W23 Y4; D3602 2; DCIN1 5; DIMM1 77 122 125 198; EU3402 3 4; EU3404 3 4; HDA27 14 16 23 24; HDD1 2 7 12 13; HDMI1 13 14; HOMBD1 2 4; IOBD1 30; KBLIT1 2; LCD1 5 36 39; PU4401 4; PU4601 5; PU5101 4; RN401 3 6; RN1506 8; RN4301 4 5; RN5201 3 6; U701 1; U3503 9; U3801 5; U6601 3 4 10 21 22 25 26 27 29 30 40 41 45 46; U6602 2 3; U6701 2 3; X1801 2 4; X1901 2 3

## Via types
v1: diameter 0.356, hole 0.178, TOP to BOTTOM, 892 vias
v2: diameter 0.508, hole 0.254, TOP to BOTTOM, 2251 vias
v3: diameter 0.711, hole 0.406, TOP to BOTTOM, 425 vias

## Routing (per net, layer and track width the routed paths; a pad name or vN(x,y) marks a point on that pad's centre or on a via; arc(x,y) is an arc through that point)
3V5V_CT1: length 2.9
  TOP w0.203: U3601.12 31.98,93.16 31.9,93.24 31.9,93.87 v1(31.57,94.2) C3602.1
3V5V_CT2: length 2.9
  TOP w0.203: 33.31,94.52 33.19,94.52 v1(32.87,94.2) 32.89,94.18 32.89,93.27 32.79,93.16 U3601.10
  TOP w0.254: C3603.1 33.31,94.52
3V5V_S0_ON: length 13.3
  TOP w0.102: U3601.5 32.79,89.36 v2(32.89,89.25) ; v2(31.88,89.25) 31.98,89.36 U3601.3 ; v2(40.89,90.77) 41.15,91.03 v1(41.4,91.03) R3609.2
  L4 w0.102: v2(31.88,89.25) v2(32.89,89.25) 34.42,90.77 v2(40.89,90.77)
3V_5V_EN: length 22.3
  TOP w0.102: PR4506.1 41.15,63.47 41.64,62.97 41.64,62.05 R3602.1 40.45,60.85 R3603.1 40.45,60.61 v2(40.01,60.17)
  L4 w0.102: v2(40.01,60.17) 39.88,60.17 39.47,60.58 38.76,60.58 38.05,59.86 36.45,59.86 34.49,61.82 33.02,61.82 v2(31.24,63.59)
  BOTTOM w0.102: v2(31.24,63.59) 31.24,63.46 v1(30.79,63.01) 30.46,63.01 30.05,63.42 30.05,63.93 30.42,64.29 PR4515.1 30.42,66.61 D3602.1
3V_5V_POK: length 118
  TOP w0.102: v2(79.63,107.03) v1(79.63,107.82) 79.63,108.3 81.41,110.08 81.41,112.62 80.9,113.12 79.88,113.12 79.57,112.81 R1728.2 ; PU4503.7 37.87,65.1 38.38,64.59 v2(38.63,64.59) 38.86,64.36 PR4534.2
  L3 w0.102: v2(38.63,64.59) 37.01,62.96 30.33,62.96 22.53,70.76 22.53,86.9 25.85,90.21 29.54,90.21 30.07,90.74 30.07,90.75 31.5,92.17 31.5,93.62 34.16,96.28 43.89,96.28 45.81,94.37 70.01,94.37 73.03,97.38 74.5,97.38 79.63,102.51 v2(79.63,107.03)
3V_5V_POK#: length 3.9
  TOP w0.102: R1726.1 97.77,96.16 Q1701.6 ; R1726.1 98.42,96.17 Q1701.5 ; R1726.1 v1(99.06,96.49)
3V_5V_POK_C: length 35.5
  TOP w0.102: R1728.1 80.9,112.05 80.9,110.13 80.66,109.89 R1729.1 79.12,108.62 79.12,106.7 83.77,102.05 84.86,102.05 85.98,100.93 85.98,99.25 88.36,96.87 v1(89.92,96.87) 95.95,96.87 R1727.2 96.39,95.66 97.27,94.79 97.27,92.69 97.55,92.41 98.28,92.41 98.42,92.55 Q1701.2
3V_FEEDBACK: length 35.2
  TOP w0.254: v2(36.96,60.29) 37.08,60.17 38.1,60.17 38.67,60.74 PR4535.1 38.73,60.86 PR4512.1
  L4 w0.254: v2(36.96,60.29) 37.03,60.29 37.16,60.42 37.59,60.42 40.51,63.34 40.51,64.99 41.53,66.01 41.53,86.58 40.39,87.72 v2(40.13,87.72)
  BOTTOM w0.254: v1(39.75,88.74) 40.13,88.36 v2(40.13,87.72) PG4535.2
5V_HDMI_R_S5:
  vias: v1(21.46,92.55)
5V_HDMI_S5: length 1.8
  BOTTOM w0.508: HDMI1.18 12.52,87.1 ; HDMI1.18 11.24,87.1 ; HDMI1.18 11.88,87.66
  vias: v1(17.93,90.42) v3(12.95,88.61)
5V_PWR_2: length 43.9
  TOP w0.203: PU4503.13 35.81,68.55
  TOP w0.508: 35.81,68.55 PC4524.1 31.47,69.16 29.84,67.53 29.84,62.59 30.61,61.83 30.61,60.66 30.24,60.29 v2(29.97,60.29)
  BOTTOM w0.508: v2(29.97,60.29) 29.97,59.28 v1(30.48,58.77) 30.48,40.09 30.73,39.83 30.73,39.31 30.36,38.93 29.84,38.93 28.68,38.93 27.94,38.19 R2915.1
5V_S0: length 55.3
  TOP w0.508: v2(17.78,73.12) 19.08,74.42 Q5403.G ; R6216.1 127.32,22 v2(127.38,21.94)
  TOP w1.016: v3(139.45,68.04) v1(139.45,66.26) 139.45,65.12 140.46,64.1 140.46,62.89 139.7,62.13 139.7,58.9 136.02,55.21 v1(136.02,53.28) 136.02,49.62 133.35,46.96 133.35,32.86 133.86,32.35 v3(133.86,30.19)
  BOTTOM w0.508: v2(17.78,73.12) 17.87,73.21 19.61,73.21 20.94,74.54 D5401.3 ; R2612.1 139,68.48 v3(139.45,68.04) ; v3(27.18,38.07) 26.23,37.12 EC8615.1 26.23,36.76 R2703.2
  vias: v1(29.34,17.37) v1(132.03,25.11) v3(17.02,74.39) v3(17.02,73.5) v3(26.54,38.7) v3(27.69,93.31) v3(28.57,93.31) v3(29.46,93.31) v3(30.1,18.03) v3(30.1,17.14) v3(32.13,36.92) v3(32.13,36.04) v3(132.72,30.19) v3(132.97,21.94) v3(134.11,21.94)
5V_S5: length 180.8
  TOP w0.254: PR4461.1 29.81,13.18 29.46,12.83 v2(29.46,12.16) 29.46,12.13 29.08,11.75 PR4460.1 ; PR4203.1 v2(35.31,95.47)
  TOP w0.356: PC4426.1 32.52,3.71 PU4402.8
  TOP w0.508: PR4624.2 39.12,44.04 v2(38.99,44.16) ; v2(66.55,90.77) 66.19,90.77 v1(63.27,87.85) 62.51,87.09 v1(61.21,87.09) 59.69,87.09 59.05,86.45 59.05,81.98 56.01,78.94 v1(56.01,76.93) v2(56.01,75.66) ; EC8614.1 145.48,34.83 146.05,34.26 v2(146.43,34.26) ; EC8612.1 148.78,69.12 v3(149.48,68.42) ; PC4426.1 PC4419.1 34.04,4.1 v1(34.04,5.66) v2(34.04,6.32) 34.04,9.24 33.53,9.75 v2(33.53,11.52)
  L3 w0.254: v3(28.68,88.49) 28.83,88.49 35.31,94.96 v2(35.31,95.47)
  L3 w0.381: v2(38.99,44.16) 38.35,43.53 36.96,43.53 31.24,49.24 v3(27.56,49.24)
  L3 w0.508: v2(34.54,38.32) 34.54,34.5 33.78,33.74 33.78,31.84 34.16,31.45 34.16,12.02 33.79,11.65 33.66,11.65 v2(33.53,11.52) 31.62,11.52 30.99,12.16 v2(29.46,12.16)
  L4 w0.508: v3(28.68,88.49) 33.53,88.49 35.18,90.14 42.16,90.14 42.9,90.87 46.89,90.87 46.99,90.77 v2(66.55,90.77)
  BOTTOM w0.203: 53.47,69.94 53.02,70.4 PU4701.2 ; 57.66,75.66 57.68,75.64 U2101.1
  BOTTOM w0.254: 26.67,87.72 25.1,87.72 PG4532.1 ; v2(23.88,56.1) 23.27,56.1 22.99,56.38 19.84,56.38 19.62,56.17 R3504.1 R3507.1 18.92,54.26 18.92,53.31 19.18,53.05 R3505.1
  BOTTOM w0.508: 57.66,75.66 v2(56.01,75.66) 56.01,72.23 56.64,71.6 v1(56.64,70.12) 56.64,68.99 55.81,68.17 54.23,68.17 53.7,68.7 PC4705.1 53.7,69.72 53.47,69.94 ; PR4917.2 139.06,82.77 140.21,81.63 140.21,79.55 145.54,74.21 145.54,71.88 146.1,71.32 146.1,69.34 146.43,69.01 ; PR4437.1 34.1,6.38 v2(34.04,6.32) ; R1208.1 147.07,30.57 v2(146.94,30.7) 146.49,30.26 Q6201.E
  vias: v1(25.83,87.88) v3(25.4,86.07) v3(25.4,84.3) v3(25.4,83.28) v3(26.29,89.38) v3(26.29,86.07) v3(26.29,84.3) v3(26.29,83.28) v3(27.18,89.38) v3(27.18,86.07) v3(27.56,51.91) v3(27.56,51.02) v3(27.56,50.13) v3(28.68,87.6) v3(28.68,86.71) v3(149.48,67.02) v3(150.11,67.79)
+3V_1D5V_AVDD: length 6.2
  TOP w0.203: 22.38,19.55 22.81,19.98 22.81,21.39 22.88,21.46 HDA27.40
  TOP w0.508: 22.38,19.55 v1(22.38,19.27) C2715.1 22.38,17.8 22.61,17.57 R2710.2 R2705.2
+3V_AVDD: length 28
  TOP w0.508: R2722.2 27.75,30.38 v2(27.81,30.45)
  L4 w0.508: v2(18.77,22.09) 19.99,23.31 23,23.31 23.82,22.5 24.89,22.5 26.47,20.92 27,20.92 28.14,19.78 29.35,19.78 29.84,20.28 v2(29.84,20.41) 29.84,25.55 29.06,26.33 29.06,27.68 v2(28.96,27.78)
  BOTTOM w0.508: v2(28.96,27.78) 28.96,28.42 29.65,29.11 R2918.1 29.21,29.43 v1(28.69,29.96) 28.19,30.45 v2(27.81,30.45) ; v2(20.7,22.07) 20.68,22.09 C2701.1 18.82,22.09 18.82,22.09 v2(18.77,22.09)
  vias: v1(28.75,26.89) v1(30.48,20.29)
+5V_AVDD: length 10.9
  L4 w0.508: v2(16.26,29.43) 19.31,29.43 23.75,33.87 v2(23.75,34.26)
  BOTTOM w0.508: R2703.1 24.03,33.98 v2(23.75,34.26)
  vias: v1(19.46,28.64)
+5V_PVDD:
  vias: v1(23.46,18.45) v1(26.54,20.8)
+V1.05A_AOSCSUS: length 1.7
  TOP w0.102: v2(83.16,77.41) 83.64,77.89 TP2109.1
  BOTTOM w0.102: CPU1.AB8 83.34,77.23 v2(83.16,77.41)
+V1.05A_SUS_PCH: length 2.6
  TOP w0.102: v2(84.12,77.42) 84.05,77.42 TP2106.1
  BOTTOM w0.102: v2(84.12,77.42) 84.31,77.23 CPU1.AD8 CPU1.AD10
+V1.05A_USB2SUS: length 1.2
  TOP w0.102: TP2108.1 87.12,73.87 v2(87.39,74.14)
  BOTTOM w0.102: v2(87.39,74.14) 87.06,74.47 CPU1.AH13
+V1.05A_VCCUSB3SUS: length 7.9
  BOTTOM w0.102: TP2107.1 69.65,73.09 71.16,73.09 71.29,73.23 72.46,73.23 72.73,73.5 73.03,73.5 73.46,73.93 76.29,73.93 CPU1.J13
+V1.05DX_MODPHY_PCH:
  vias: v1(69.72,74.01) v1(73.1,76.8) v1(77.85,75.15) v3(78.39,75.85) v3(78.41,74.47)
+V1.05S_AIDLE: length 9.1
  TOP w0.406: v2(77.19,77.82) 76.94,78.07 v1(75.03,78.07) 74.42,78.07 73.72,78.77 C2105.1
  TOP w0.508: C2105.1 72.9,78.77 R2105.2
  L3 w0.508: v2(77.19,77.82) 77.22,77.82 77.57,77.47 v2(79.35,77.47)
  BOTTOM w0.254: v2(79.35,77.47) 79.12,77.47 CPU1.N8 78.88,77.15 79.24,76.78 CPU1.P9
+V1.05S_APLLOPI: length 1.9
  BOTTOM w0.203: CPU1.AA21 v2(83.08,71.09) ; CPU1.W21 v2(82.26,71.09)
  vias: v1(81.66,71.34)
+V1.05S_ASATA3PLL: length 13.7
  BOTTOM w0.254: R1906.2 65.72,75.98 66.19,76.45 v1(66.73,76.45) 67.73,76.45 C1105.1 67.98,76.19 70.36,76.19 70.54,76.02 71.19,76.02 71.29,75.91 71.78,75.91 72.23,75.47 CPU1.B11 ; R1906.2 64.72,75.53 C1106.1 C1107.1 L1102.2 ; R1906.2 R1904.2
+V1.05S_AUSB3PLL: length 18.9
  TOP w0.254: R1601.1 70.42,64.93 v2(70.48,64.99)
  L3 w0.254: v2(70.48,64.99) 69.98,65.5 69.98,70.2 v2(70.48,70.71)
  BOTTOM w0.254: v2(70.48,64.99) 70.48,65.04 70.96,65.51 71.51,65.51 71.84,65.67 CPU1.B27 ; CPU1.B18 71.95,70.94 71.72,70.71 v2(70.48,70.71) 68.71,70.71 v1(68.5,70.91) 67.88,71.53 C1103.1 66.28,71.53 C1123.1 C1104.1 64.03,71.42 L1101.2
+V1.05S_AXCK_DCB: length 15.8
  TOP w0.254: L1103.2 65.86,69.21 C1112.1 C1125.1 67.41,69.16 68.07,69.82 v1(70.23,69.82) 71.14,69.82 71.83,69.13 76.02,69.13 76.77,69.88 C1111.1 76.77,70.9 v2(76.48,71.2)
  BOTTOM w0.254: CPU1.J18 76.81,71.53 v2(76.48,71.2) 76.56,71.12 CPU1.K19
+V1.05S_AXCK_LCPLL: length 10.7
  TOP w0.254: v2(68.58,68.17) 68.9,67.85 R1803.2
  BOTTOM w0.229: CPU1.A20 70.87,70.29
  BOTTOM w0.254: v2(68.58,68.17) 68.2,68.17 67.56,68.8 C1113.1 ; C1113.1 66.31,68.87 C1114.1 64.74,68.73 64.67,68.8 L1104.2 ; C1113.1 67.82,69.12 67.83,69.12 68.66,69.95 v1(69.29,69.95) 70.53,69.95 70.87,70.29
+V1.05S_CORE_PCH: length 19.4
  TOP w0.508: v2(75.82,75.94) 75.54,75.66 C1117.1 ; v2(85.85,67.91) 86.17,68.23 C1118.1
  L3 w0.508: v2(75.82,73.09) 75.87,73.14 75.87,73.34 76.24,73.71 80.65,73.71 81.61,72.75 81.61,70.84 82.51,69.94 83.83,69.94 85.85,67.92 v2(85.85,67.91)
  BOTTOM w0.178: CPU1.AF22 85.92,67.98 v2(85.85,67.91)
  BOTTOM w0.203: CPU1.J11 76.78,75.43 76.18,75.43 CPU1.H11
  BOTTOM w0.254: v2(75.82,73.09) 75.82,73.15 76.16,73.48 CPU1.H15
  BOTTOM w0.305: v2(85.06,77.45) 85.28,77.23 CPU1.AE8 ; CPU1.H11 75.82,75.74 v2(75.82,75.94)
  vias: v1(63.78,76.68) v1(67.82,76.04) v3(68.71,76.8) v3(69.6,76.8)
+V1.05S_SSCF100: length 8.5
  TOP w0.254: R2117.2 70.42,71.72 73.65,71.72 v1(73.71,71.79) C2137.1 76.28,71.79 v2(76.48,71.98)
  BOTTOM w0.254: v2(76.48,71.98) 76.81,72.31 CPU1.J17
+V1.05S_SSCFF: length 5.2
  TOP w0.254: C2138.1 80.49,69.5 v2(80.23,69.76) 80.23,69.53 v1(79.91,69.21) 80.77,68.34 R2118.2
  BOTTOM w0.254: CPU1.R21 79.86,70.13 v2(80.23,69.76) 80.23,69.77 80.59,70.13 CPU1.T21
+V3.3A_1.5A_HDA: length 25.9
  TOP w0.254: R2108.2 107.57,71.85 v1(106.81,71.09) 104.78,69.06 97.83,69.06 97.41,68.63 v2(97.41,68.55) ; C2116.1 88.29,72.36 v2(87.63,73.02)
  L3 w0.254: v2(87.63,73.02) 89.05,71.6 91.44,71.6 93.34,69.69 96.35,69.69 97.41,68.63 v2(97.41,68.55)
  BOTTOM w0.254: v2(87.63,73.02) 87.63,73.17 87.08,73.72 CPU1.AH14
+V3.3A_DSW_P: length 9.3
  TOP w0.254: R2101.2 C2101.1 89.53,70.58 88.77,71.34 v1(88.34,71.34) 87.85,71.34 86.11,73.09 C2136.1 86.75,73.95 v2(86.75,75.76)
  BOTTOM w0.254: CPU1.AH10 86.75,75.85 v2(86.75,75.76)
+V3.3A_PSUS: length 39.3
  TOP w0.254: R1103.2 C1108.1 v1(102.74,68.01) 97.22,68.01 96.77,68.46 v2(96.77,68.55)
  L3 w0.254: v2(96.77,68.55) 96.27,69.06 93.22,69.06 91.19,71.09 88.11,71.09 86.23,72.96 86.23,74.47 85.53,75.18 83.79,75.18 83.16,75.8 v2(83.16,75.91)
  BOTTOM w0.254: CPU1.AC9 CPU1.AA9 v2(83.16,75.91) 83.16,73.27 85.11,71.32 CPU1.AE20 85.51,70.23 CPU1.AE21
+V3.3S_1.8S_LPSS_SDIO: length 15.1
  TOP w0.254: C2104.1 80.33,77.43 v2(80.32,77.44) 80.22,77.44 79.78,77.88 79.78,78.54 79.78,78.54 79.78,79.09 79.87,79.18 79.87,80.84 79.25,81.46 78.4,81.46 77.66,82.21 76.79,82.21 76,83.01 74.41,83.01 73.66,82.26 v1(73.56,82.26) R2103.1
  BOTTOM w0.254: CPU1.T9 80.3,76.79 80.3,77.39 80.32,77.41 v2(80.32,77.44) 80.33,77.43 80.58,77.43 CPU1.U8
+V3.3S_PCORE: length 6.5
  TOP w0.178: v2(81.26,77.4) 81.26,77.4 81.74,77.88 v1(81.74,78.38)
  TOP w0.254: v2(81.26,77.4) 80.9,77.05 80.9,76.34 80.77,76.21 80.77,74.87 C2123.1 80.71,74.73 R2112.2
  BOTTOM w0.254: v2(81.26,77.4) 81.56,77.4 CPU1.V8 81.73,77.15 82.1,76.78 CPU1.W9
+VCCIOA_OUT: length 1.9
  TOP w0.203: v1(74.27,69.74) 74.27,69.84 v2(73.89,70.22)
  TOP w0.508: v2(73.89,70.22) 73.74,70.07 R801.1
  BOTTOM w0.305: v2(73.89,70.22) 73.89,70.32 CPU1.E20
+VCCRTCEXT: length 2.7
  TOP w0.203: v2(85.08,78.09) 85.1,78.09 85.54,77.65 85.54,76.93 C2110.1
  TOP w0.254: v2(85.08,78.09) 85.2,78.21 85.38,78.21 v1(85.55,78.38)
  BOTTOM w0.254: v2(85.08,78.09) 85.09,78.09 85.12,78.06 85.36,78.06 CPU1.AE7
GND: length 1158.7
  TOP w0.152: v2(161.93,20.54) 161.93,20.53 U6602.10 ; U6701.15 157.99,20.8 v2(157.86,20.92) 157.73,20.92 157.49,20.68 U6701.16 ; v2(160.02,18.51) 160.01,18.52 U6701.10 ; U6602.15 163.96,18.38 v2(164.21,18.13) 164.46,18.38 U6602.16 ; U6701.13 159.78,20.02 v2(160.02,19.78) 159.76,19.52 U6701.12 ; U6602.13 162.16,19.03 v2(161.93,19.27) 162.19,19.53 U6602.12 ; v2(165.86,21.18) 165.72,21.03 U6602.5 ; U6701.5 v2(155.57,18.02)
  TOP w0.203: KBC24.116 153.54,56.1 153.35,56.29 C2408.2 ; KBC24.5 149.27,51.56 v2(149.35,51.64) ; KBC24.18 146.18,46.36 v2(146.01,46.52) ; PU4601.22 38.39,49.53 v2(38.35,49.5) ; U3601.11 v2(32.38,93.44) ; v2(76.14,45.48) 75.99,45.33 75.94,45.33 75.64,45.03 75.64,43.51 R901.2 ; C2406.2 164.5,50.36 KBC24.89 ; C2407.2 164.55,45.96 KBC24.78 162.11,45.96 162.09,45.97 161.72,45.97 161.56,45.82 v2(161.55,45.82) ; v2(41.91,46.2) 41.91,46.45 41.47,46.89 PU4601.29 ; v2(38.35,50.77) 38.39,50.73 PU4601.19 ; KBC24.45 153.54,40.35 v2(153.67,40.48) ; v2(27.81,24.1) 27.8,24.11 HDA27.4 ; PU4401.22 v2(43.94,15.33)
  TOP w0.224: C2109.2 90.64,73.88 91.31,74.56 v2(91.31,74.65)
  TOP w0.254: v2(84.71,74.17) 84.71,74.77 85.09,75.15 85.55,75.15 85.62,75.09 C1120.2 ; v2(68.96,71.85) 68.68,71.57 68.12,71.57 67.56,72.12 v2(67.56,72.23) ; v2(83.87,75.81) 83.87,76.16 C2110.2 ; C2147.2 81.47,76.1 v2(81.28,75.91) ; PR4531.2 30.57,63.51 v2(30.48,63.59) 30.57,63.68 PR4502.2
  TOP w0.305: RN1804.1 106.62,89.56 v2(106.3,89.88) 105.97,89.56 RN1804.2 105.82,88.8 EC1707.2 ; Q1701.1 97.77,93.93 98.04,94.2 v2(99.06,94.2) 99.08,94.22 Q1701.4 ; U6601.47 101.94,100.71 C6605.2 ; C1121.2 92.99,80.07 92.94,80.07 92.56,79.68 92.56,79.5 v2(92.43,79.37) ; v2(83.44,59.4) 83.53,59.49 THM261.5 ; U6601.35 95.48,103.26 95.25,103.03 C6607.2 ; RN1703.2 97.85,89.05 v2(98.17,89.38) 98.5,89.05 RN1703.1 ; v2(97.79,110.46) 97.79,110.08 97.45,109.73 U6601.23 ; C2105.2 73.75,77.88 v2(73.89,77.74) ; v2(37.97,25.49) 37.97,26 38.45,26.48 PQ4407.1 39.91,26.48 40.13,26.26 40.13,25.49 40.45,25.17 PQ4407.4 ; PU4402.4 30.22,10.77 v2(29.84,11.14) ; v2(104.08,106.26) U6601.8 ; C3801.2 78.17,111.92 77.94,111.69 U3801.1 ; R6609.1 95.44,113.19 v2(95.38,113.25)
  TOP w0.356: R2435.1 158.75,57.94 v2(158.37,58.32) ; v2(45.59,95.47) 45.59,94.96 45.83,94.73 Q3601.4 ; Q3601.1 48.53,93.42 v2(49.02,92.93)
  TOP w0.381: PR4526.2 33.96,61.33 33.78,61.15 v2(33.78,60.93) ; PR4440.2 30.16,11.84 29.84,11.52 v2(29.84,11.14) ; C1901.2 95.02,78.52 v2(94.99,78.49) ; v2(19.68,84.68) 19.68,84.99 19.49,85.18 19.49,85.18 EC8608.2 ; PC4607.2 39.85,45.54 v2(40.51,46.2) ; C1116.2 84.58,73.32 v2(84.71,73.32) ; PR4517.2 41.07,62.66 v2(41.15,62.58) ; v2(81.45,67.91) 81.34,68.02 R606.2
  TOP w0.406: PQ4405.4 38.23,5.19 38.47,5.43 v2(38.48,5.43)
  TOP w0.508: v2(91.98,41.94) 93.09,41.94 R409.1 ; PC4607.2 39.54,44.99 PC4606.1 ; PC4436.2 v2(38.48,6.44) ; v2(94.61,68.55) 94.55,68.61 EC1802.2 ; USB1.12 14,57.44 ; USB1.12 14,55.66 ; USB1.12 15.54,56.55 ; PR4405.1 v2(35.94,8.73) ; R5418.1 17.02,76.68 v2(16.89,76.8) ; EC8625.2 26.54,71.72 v2(26.04,71.21) ; USB1.11 15.54,69.35 ; USB1.11 14,68.46 ; USB1.11 14,70.24 ; 15.33,50.46 USB2.10 ; USB2.10 17.07,51.35 ; USB2.10 15.33,52.24 ; C1124.2 C1110.2 ; C1110.2 83.19,68.9 82.6,69.5 C1109.2 ; C1110.2 83.31,68.8 83.48,68.63 v2(83.48,67.91) ; EC8629.2 44.04,31.31 v3(44.2,31.46) ; C1220.2 129.9,71.34 v2(129.8,71.25) ; USB2.11 15.33,39.44 ; USB2.11 17.07,38.55 ; USB2.11 15.33,37.66 ; BATT1.9 84.93,19.88 ; BATT1.9 85.81,18 ; BATT1.9 84.04,18 ; R2611.2 158.43,59.19 158.37,59.12 v2(158.37,58.32) ; C5203.2 69.11,93.66 C5204.2 69.11,94.71 69.85,95.45 v2(69.85,95.47) ; v2(39.62,55.85) 39.81,56.04 PC4602.2 PR4609.2 ; v2(39.62,55.85) 38.54,55.85 PR4612.1 ; v2(39.62,55.85) PC4603.1 ; R602.2 96.96,72.68 96.9,72.62 v2(96.9,72.36) ; R2449.1 v2(161.04,34.77) ; R1913.1 106.11,83.09 v2(105.92,83.28) ; v2(46.35,49.24) 46.29,49.18 PC4601.2 ; v2(80.52,63.21) 80.58,63.15 C2608.2 ; PC4437.2 v2(39.37,6.44) ; PR4523.2 v2(36.96,60.93) 35.92,60.93 PC4526.2 ; R1721.2 98.17,79.72 v2(97.92,79.47) ; C1118.2 87.06,68.27 v2(87.46,67.87) ; v2(67.06,77.18) v2(66.29,77.18) 66.27,77.21 C1119.2 ; C6611.2 v2(162.15,16.48) ; v2(129.38,74.22) 129.48,74.31 C1202.2 ; C1701.2 v2(82.93,95.47) ; v2(165.35,50.51) 164.66,50.51 C2406.2 ; v2(78.16,73.04) 78.04,72.92 C2128.2 77.6,72.36 77.22,72.74 C1102.2 ; R5202.2 55.37,94.77 v2(55.37,95.47) ; USB2.4 16.08,40.56 ; C2716.2 30.89,22.35 v2(30.99,22.45) ; v2(47.12,5.94) 47.37,6.19 Q2404.C ; PC4531.2 v2(36.96,70.71) 36.04,70.71 PC4524.2 ; v2(52.2,95.47) 52.2,96.55 EC5207.2 ; PC4910.2 137.6,40.67 v2(137.29,40.99) ; X6601.4 108.21,102.74 v2(107.49,102.03) 106.91,101.44 TP6604.1 ; v2(52.96,89.63) 53.85,90.52 EC8623.2 ; PC4422.2 44.17,19.3 v2(44.45,19.02) ; v2(90.63,76.55) 90.25,76.17 R1602.2 ; Q2505.S 143.95,66.03 v2(144.53,66.61) ; v2(26.54,5.94) 26.7,6.1 PQ4401.S ; v2(77.85,92.55) 77.66,92.55 EC1706.2 ; PD4203.1 42.55,103.73 ; C1201.2 C1218.2 131.32,76.97 v2(130.44,77.85) ; 100.05,17.11 BATT1.7 ; BATT1.7 100.94,18 ; BATT1.7 99.16,18 ; BATT1.7 100.05,18.89 ; EC2709.2 EC2708.2 32.32,23.53 v2(32,23.21) ; C2412.2 v2(142.88,52.29) ; EC8609.2 77.58,102.01 v2(77.72,101.87) ; v3(142.49,46.07) 143.07,46.07 C2409.2 ; C1216.2 126.56,99.6 v2(126.62,99.54) ; EC1704.2 98.23,89.44 v2(98.17,89.38) ; v2(34.54,95.47) 34.48,95.41 C3603.2 32.6,95.41 C5206.2 ; v2(82.04,95.47) EC1703.2 R1715.2 ; v2(143,34.38) 143,34.65 143.37,35.02 EC8614.2 ; C2104.2 79.44,75.98 v2(79.38,75.91) 79.35,75.89 C2123.2 ; v2(90.75,70.55) 89.22,72.09 C2116.2 ; PD4204.3 25.08,95.15 v3(27.3,97.38) v3(27.94,98.01) ; C1221.2 125.14,60.29 v2(125.16,60.27) ; 12.99,90.35 HDMI1.21 11.28,91.29 ; v2(119.76,25.37) C6201.2 ; v2(100.84,91.03) R1725.1 EC1705.2 ; v2(80.98,71.19) 81.04,71.12 81.04,70.5 C2138.2 ; C2137.2 74.94,72.68 v2(74.54,73.08) ; v2(125.8,68.91) 125.8,69.17 125.15,69.82 C1207.2 ; C2609.2 83.25,63.02 v2(83.44,63.21) ; EC8624.2 45.75,79.75 v3(45.97,79.98) ; v2(85.4,38.19) 85.46,38.26 R604.2 ; 106.06,18 BATT1.10 104.29,18 ; C703.2 85.34,65.88 v2(85.09,65.63) ; HS1.1 59.9,63.19 ; HS1.1 56.71,60 ; HS1.1 59.9,56.81 ; HS1.1 63.09,60 ; v3(51.94,31.46) PC4406.2 ; R605.2 82.73,43.01 v2(82.73,42.44) 82.74,42.44 R601.1 ; C701.2 v2(82.04,67.02) ; v2(65.15,42) R402.2 R406.2 ; v2(24.51,37.05) 24.51,35.97 EC2704.2 ; C2416.2 C2410.2 153.92,35.59 v2(153.92,35.02) ; v2(88.95,61.59) 88.93,61.56 C1019.2 ; 101.16,18 BATT1.8 ; BATT1.8 102.05,17.11 ; BATT1.8 102.94,18 ; BATT1.8 102.05,18.89 ; C6603.2 v2(105.03,108.93) 105.28,109.19 R6619.1 ; HDMI1.8 12.99,82.1 ; PR4471.2 50.04,18.45 v3(50.04,19.27) ; C2708.2 v2(29.84,19.27) ; R2717.2 29.65,30.13 v2(29.59,30.19) ; C3602.2 v2(29.08,94.2) ; EC4602.2 v2(48.9,50.01) ; C2135.2 84.58,71.65 v2(84.06,71.13) ; C1111.2 77.66,70.69 v2(78.1,71.13) ; EC8626.2 54.13,31.06 v3(53.72,31.46) ; 47.37,10.71 v2(47.37,9.75) ; v2(78.87,105.63) 78.8,105.57 C3802.2 ; C1222.2 130.49,59.28 v2(130.44,59.33) ; R6627.1 v2(165.48,24.73) ; EC6203.2 126.24,24.48 v3(126.75,24.99) 125.73,26 EC6204.2 ; R2504.2 142.05,67.89 v2(142.31,68.15) ; C1122.2 C1121.2 ; EC8627.2 87.53,33.47 v2(87.63,33.37) ; R2442.2 143.32,44.29 v3(142.49,44.29) ; 11.28,74.91 HDMI1.20 ; HDMI1.20 11.28,76.79 ; HDMI1.20 12.99,75.85 ; 14.19,60.15 USB1.4 ; USB1.4 14.9,59.44 ; USB1.4 14.9,60.86 ; v2(108.58,68.93) 108.18,69.34 C1108.2 ; PR4607.2 v2(43.18,56.1) ; PR4607.2 PR4608.2 ; PR4607.2 PR4601.2 ; v2(157.86,20.92) 157.42,21.37 C6701.2 ; PC4435.2 v2(28.32,3.65) ; C1101.2 78.36,78.16 v2(78.34,78.18) ; R2003.2 94.3,72.68 v2(94.61,72.36) ; USB1.7 14.36,62.95 ; C6602.2 106.55,106.14 106.93,106.52 107.7,106.52 ; USB2.13 5.18,53.72 ; R6611.1 v2(100.84,113.25) ; C5208.2 v2(46.35,100.17) ; R3602.2 40.45,61.94 PR4517.2 ; C5209.1 v2(47.24,100.17) 47.9,100.17 C5211.2 48.54,99.54 U5201.2 ; v2(160.02,20.67) 159.92,20.77 C6703.2 ; C2704.1 18.99,21.3 v2(18.8,21.3) ; D2601.A v3(137.79,69.06) ; EC8601.2 26.53,35.08 v2(26.57,35.05) ; C2136.2 86.11,74.96 C1120.2 ; PR4626.2 v2(47.12,51.91) ; v2(27.3,16.35) 25.5,16.35 C2706.2 24.35,16.58 C2707.2 ; v2(130.44,61.05) 130.44,61.05 C1211.2 ; USB1.14 5.8,53.98 ; C6607.2 94.56,103.03 94.24,102.71 v2(94.08,102.71) ; C6606.2 v2(97.79,110.46) ; R1717.2 EC1702.2 v2(87,96.11) ; C2408.2 153.35,57.59 C2411.2 153.52,58.3 v2(153.18,58.64) ; C6610.2 165.35,15.72 ; EC5206.2 58.48,103.92 ; C1020.2 v2(89.99,59.71) ; C2717.2 28.32,20.48 C2709.2 v2(29.08,20.41) ; C6604.2 v2(106.93,102.58) ; EC8604.2 28.32,33.37 v2(29.21,32.48) ; USB2.12 5.95,37.2 6.6,36.54 ; USB1.13 5.8,71.81 ; PC4417.2 78.64,31.84 v3(76.33,31.84) ; v2(94.49,71.21) 94.42,71.28 EC1801.2 ; C1209.2 125.02,66.01 v2(125.16,66.15) ; v2(74.52,74.97) 74.23,75.27 C1117.2 ; v2(130.44,64.65) 130.48,64.61 C1212.2 ; R6615.1 v2(104.39,113.25) ; EC4201.2 21.62,90.26 v3(20.83,90.26) 20.83,89.57 EC4202.2 ; EC8611.2 v2(35.56,28.54) ; v2(165.35,46.07) 164.66,46.07 C2407.2 ; R6613.1 v2(101.73,113.25) ; C1902.2 94.55,77.63 94.99,78.06 v2(94.99,78.49) ; C2413.2 144.04,54.2 v2(144.53,54.2) ; v2(91.44,24.1) 90.81,24.73 PD4302.A ; EC1901.1 v2(104.9,74.39) ; PR4447.2 v2(33.53,12.29) ; C1213.2 125.21,64.1 125.8,64.69 v2(125.8,64.95) ; v2(84.64,42.63) 84.45,42.82 R1920.1 ; v2(90.12,66.8) 90.08,66.83 C2114.2 ; 38.35,103.6 38.35,102.47 PQ4202.E ; v2(82.17,75.91) 82.17,75.53 81.76,75.13 C1115.2 ; EC8612.2 147.89,70.39 v2(147.7,70.58) ; C2719.2 v2(31.5,26.64) ; v2(64.9,70.45) 64.92,70.48 C1112.2 C1125.2 ; R6617.1 v2(105.28,113.25) ; v2(33.78,60.93) EC8610.2 ; C2401.2 v2(142.88,48.74) ; R6606.2 101.79,98.33 v2(102.36,98.9) 102.74,99.28 102.74,99.6 C6608.2 102.46,99.66 102.01,100.11 102.01,100.34 C6605.2 v2(101.09,100.55) ; C2415.1 v2(142.88,50.51)
  L3 w0.508: 14.58,45.71 USB2.7 14.58,44.19 ; 11.24,79.1 HDMI1.2 11.88,78.54 ; 16.08,40.69 USB2.4 ; USB2.4 16.08,42.21 ; USB2.4 16.84,41.45 ; BATT1.7 100.05,18.89 ; BATT1.7 100.05,17.11 ; BATT1.7 100.94,18 ; BATT1.7 99.16,18 ; 104.29,18 BATT1.10 106.06,18 ; HDMI1.5 11.06,80.6 ; 14.9,59.44 USB1.4 ; USB1.4 14.9,60.86 ; USB1.4 14.19,60.15 ; HDMI1.21 12.99,90.35 ; HDMI1.21 11.28,91.29 ; HDMI1.21 11.28,89.41 ; 15.33,37.66 USB2.11 ; USB2.11 17.07,38.55 ; USB2.11 15.33,39.44 ; 14,55.66 USB1.12 14,57.44 ; USB1.13 5.8,71.94 ; 15.33,52.24 USB2.10 15.33,50.46 ; HDMI1.17 11.16,86.6 ; USB1.14 7.86,55.1 ; 101.16,18 BATT1.8 ; BATT1.8 102.94,18 ; BATT1.8 102.05,17.11 ; BATT1.8 102.05,18.89 ; USB2.13 5.18,53.66 ; USB2.12 6.46,37.2 ; 14,68.46 USB1.11 14,70.24 ; 11.28,76.79 HDMI1.20 11.28,74.91 ; BATT1.9 85.81,18 ; BATT1.9 84.93,19.88 ; BATT1.9 84.04,18 ; USB1.7 13.4,63.66 ; HDMI1.11 11.11,83.6
  L4 w0.127: v2(67.06,46.07) v2(67.06,48.1) 66.57,47.61 65.64,47.61 v2(65.15,48.1) ; v2(129.8,71.25) 130.88,72.33 130.88,94.81 v2(130.44,95.25) 130.44,95.26 130,95.69 129.61,95.69 v2(129.17,95.25)
  L4 w0.254: 12.45,81.76 12.1,82.1 HDMI1.8 HDMI1.11
  L4 w0.508: HDMI1.8 11.56,82.1 11.22,81.76 ; 14.19,60.15 USB1.4 ; USB1.4 14.9,60.86 ; USB1.4 14.9,59.44 ; 14.58,44.19 USB2.7 14.58,45.71 ; USB1.12 15.54,56.55 ; USB1.12 14,55.66 ; USB1.12 14,57.44 ; BATT1.9 85.81,18 ; BATT1.9 84.04,18 ; BATT1.9 84.93,19.88 ; USB2.11 15.33,39.44 ; USB2.11 15.33,37.66 ; USB2.11 17.07,38.55 ; 14,68.46 USB1.11 14,70.24 ; USB2.10 15.33,52.24 ; USB2.10 17.07,51.35 ; USB2.10 15.33,50.46 ; BATT1.8 102.05,18.89 ; BATT1.8 102.94,18 ; BATT1.8 102.05,17.11 ; BATT1.8 101.16,18 ; 11.28,76.79 HDMI1.20 11.28,74.91 ; 99.16,18 BATT1.7 ; BATT1.7 100.94,18 ; BATT1.7 100.05,18.89 ; BATT1.7 100.05,17.11 ; USB1.7 14.21,62.95 ; BATT1.10 106.06,18 ; BATT1.10 105.18,19.88 ; BATT1.10 104.29,18 ; 11.88,78.54 HDMI1.2 11.24,79.1 ; USB2.12 6.46,37.2 ; HDMI1.21 12.99,90.35 ; HDMI1.21 11.28,89.41 ; HDMI1.21 11.28,91.29 ; 16.08,40.69 USB2.4 16.08,42.21 ; USB2.13 5.18,53.66 ; USB1.14 7.73,55.1 ; v2(94.87,66.77) 95.76,67.66 98.17,67.66 v2(104.9,74.39) 110.24,79.72 122.81,79.72 123.32,80.23 126.62,80.23 127.13,79.72 127.13,79.41 v2(127.07,79.35) ; HDMI1.5 11.16,80.6 ; USB1.13 5.8,72.06
  BOTTOM w0.102: CPU1.AJ63 87.54,42.69 87.69,42.55 87.69,42.1 v2(87.77,42.02) ; CPU1.AN63 90,43.48 90,42.27 v2(90.26,42.01)
  BOTTOM w0.127: 91.87,55.88 92.12,55.88 92.13,55.87 92.36,55.87 92.37,55.86 92.4,55.86 92.76,55.49 CPU1.AV43 ; v2(84.71,74.17) 85.52,74.17 85.56,74.13 CPU1.AF14 ; v2(95.33,49.41) 95.26,49.49 94.04,49.49 94.04,49.48 CPU1.AY53 ; 91.89,59.03 92.12,59.03 92.13,59.02 92.37,59.02 92.38,59.01 92.4,59.01 92.76,58.64 CPU1.AV39 ; v2(94.91,46.97) 94.83,47.05 CPU1.AY57 ; CPU1.AF15 v2(84.71,73.32) ; CPU1.AH49 86.87,52.28 86.87,51.97 CPU1.AJ50 ; 91.8,54.27 92.11,54.27 92.13,54.28 92.55,54.28 CPU1.AV46 ; CPU1.AR39 CPU1.AP39 90.12,58.27 90.12,58 CPU1.AN40 ; CPU1.AV36 92.79,60.34 92.68,60.34 92.43,60.58 91.87,60.58 91.87,60.58 ; 91.88,57.46 91.91,57.43 92.41,57.43 92.72,57.12 92.86,57.12 CPU1.AV41
  BOTTOM w0.152: CPU1.AG63 86.19,42.38 v2(86.17,42.37)
  BOTTOM w0.178: CPU1.AU59 91.93,45.82 91.93,46.22 91.92,46.23 91.92,47.03 CPU1.AU57 91.93,47.06 91.93,47.46 91.92,47.48 91.92,47.76 91.93,47.78 91.93,48.26 CPU1.AU55 ; CPU1.AU59 91.53,45.41 91.52,45.41 91.44,45.32 91.13,45.32 91.13,45.31 v2(91.12,45.31) 90.96,45.48 90.5,45.48 90.49,45.46 CPU1.AN60 89.56,45.46 89.54,45.48 89.26,45.48 89.24,45.46 CPU1.AL60 ; CPU1.AU59 CPU1.AV59 CPU1.AW59 93.56,45.49 93.56,45.49 ; CPU1.AN32 89.8,63.23 CPU1.AN31 ; 87.2,52.94 87.21,52.94 87.43,53.16 v2(87.43,53.52) 87.43,54.01 CPU1.AJ45 ; 87.2,52.94 87.2,52.94 ; 87.2,52.94 CPU1.AJ47 ; v2(89.99,59.71) 89.8,59.9 CPU1.AN36 ; CPU1.AT40 91.88,58.15 91.88,57.12 91.8,57.04 91.8,56.66 CPU1.AT42 91.87,56.59 91.87,55.88 91.91,55.84 91.91,55.19 CPU1.AT43 91.8,55.07 91.8,54.68 91.81,54.68 91.81,54.31 91.8,54.3 91.8,53.51 CPU1.AT46 ; CPU1.AT40 91.92,58.34 91.92,59 91.89,59.03 91.89,59.72 CPU1.AT37 91.87,59.87 91.87,61.31 CPU1.AT35 ; CPU1.AT40 90.82,58.23 CPU1.AR39 ; CPU1.AW4 93.45,79.84 93.1,79.49 92.56,79.49 v2(92.43,79.37) ; CPU1.AU51 CPU1.AV51 CPU1.AW51 CPU1.AY51 93.98,50.92 94.78,50.92 v2(94.91,51.05) ; CPU1.AU22 91.94,69.26 91.92,69.27 91.92,69.56 91.94,69.58 CPU1.AU20 ; CPU1.AT63 91.43,42.98 91.77,42.64 91.77,42.15 v2(91.98,41.94) ; CPU1.AV33 91.94,62.41 CPU1.AU33 ; CPU1.AU20 91.92,70.08 91.92,71.26 CPU1.AU18 91.92,71.3 91.92,72.57 CPU1.AU16 ; CPU1.AU20 CPU1.AV20 ; CPU1.AL36 88.82,60.56 v2(88.82,60.67) ; CPU1.AR52 91.08,50.23 91.01,50.15 90.53,50.15 CPU1.AP52 90.45,50.02 v2(90.09,49.65) ; CPU1.AJ60 87.57,45.49 88.73,45.49 CPU1.AL60 ; CPU1.AV36 93.21,59.92 93.21,59.85 93.23,59.83 v2(93.23,59.82) ; CPU1.AV34 93.24,62.12 CPU1.AW33 ; CPU1.AL52 88.49,50.22 88.49,50.05 88.78,49.76 v2(88.78,49.66) ; CPU1.AT61 91.28,44.76 CPU1.AT62 ; CPU1.AU55 91.94,48.75 91.92,48.77 91.92,49.06 91.94,49.07 CPU1.AU53 ; CPU1.AU55 CPU1.AV55 ; v2(84.64,42.63) 84.7,42.69 84.7,43.12 CPU1.AD63 ; CPU1.AN31 CPU1.AP31 CPU1.AR31 ; CPU1.AN31 CPU1.AM31 CPU1.AL31 88.03,63.55 v2(87.53,64.06) ; CPU1.AW42 93.56,56.31 v2(93.22,56.66) ; CPU1.Y63 82.51,43.18 82.54,43.15 82.54,42.62 82.72,42.44 v2(82.73,42.44) ; CPU1.AU24 91.92,67.48 91.92,66.16 CPU1.AU26 ; CPU1.AV39 93.21,58.34 93.21,58.23 v2(93.21,58.22) ; v2(79.12,45.46) 79.44,45.79 CPU1.P59 ; v2(88.02,49.71) 87.85,49.87 CPU1.AK52 87.75,50.34 CPU1.AJ52 ; CPU1.AH19 87.06,71.25 87.58,70.73 v2(87.58,70.55) ; CPU1.AN45 89.92,55.05 89.92,55.8 CPU1.AN43 90.08,56.2 v2(90.08,56.44) 89.8,56.72 CPU1.AN42 89.8,56.97 90.11,57.27 v2(90.12,57.27) ; CPU1.AL33 88.5,62.04 v2(88.95,61.59) ; CPU1.AN39 88.96,58.27 88.83,58.14 88.82,58.14 v2(88.79,58.12) 88.82,58.09 ; CPU1.AL61 CPU1.AL60 ; CPU1.AW47 93.56,53.1 93.56,53.17 93.24,53.49 93.23,53.49 v2(93.22,53.51) ; v2(89.44,53.54) 89.44,53.32 CPU1.AN48 89.8,52.91 89.97,52.75 89.97,52.22 CPU1.AN49 ; CPU1.AJ56 86.87,47.41 86.87,47.09 CPU1.AH57 86.87,47.08 86.87,46.77 87.2,46.44 CPU1.AJ58 87.03,46.26 87.03,45.81 v2(87.06,45.77)
  BOTTOM w0.203: CPU1.AW4 94.17,79.84 CPU1.AY4 ; v2(89.45,49.68) 89.46,49.7 89.46,49.89 CPU1.AN52 89.8,50.34 89.93,50.47 89.93,50.85 89.8,50.98 CPU1.AN51 89.8,51.07 89.91,51.17 89.91,51.42 89.91,51.43 89.91,51.8 89.8,51.91 CPU1.AN49 ; v2(73.25,80.14) 73.25,80.18 73.24,80.19 73.24,80.71 73.66,81.13 CPU1.D2 ; v2(94.86,45.55) 94.59,45.55 94.41,45.73 CPU1.AY59 ; CPU1.D8 73.81,77.66 v2(73.89,77.74) ; 88.82,58.09 88.82,57.88 88.62,57.68 CPU1.AL40 ; v2(90.78,46.84) 90.78,46.84 90.78,46.91 90.45,47.23 CPU1.AP57 ; v2(89.44,53.54) 89.45,53.54 89.8,53.89 CPU1.AN46 89.8,54.21 89.88,54.28 89.88,54.66 89.8,54.74 CPU1.AN45 ; v2(81.28,75.91) 81.25,75.94 81.25,76.54 81.26,76.54 CPU1.U9 ; CPU1.AR43 91.1,55.61 v2(91.29,55.42) 91.29,55.39 91.6,55.08 CPU1.AT43 ; CPU1.AL46 88.77,54.28 v2(88.77,54.47) 88.77,54.67 CPU1.AL45 ; v2(76.36,42.46) 76.36,42.47 76.52,42.63 CPU1.J63 ; v2(88.83,46.91) 88.5,47.23 CPU1.AL57 ; CPU1.V3 81.88,80.51 v2(82.18,80.82) ; v2(80.04,82.46) 80.31,82.19 CPU1.T1 ; CPU1.F58 74.32,46.44 74.01,46.12 73.8,45.91 CPU1.D59 73.53,45.91 ; v2(88.17,80.81) 87.87,80.51 CPU1.AK3 ; CPU1.AL51 88.5,50.99 v2(88.83,50.66) ; CPU1.AW60 93.56,45.25 93.56,45.49 ; CPU1.AL54 88.5,49.14 v2(88.83,48.81) ; v2(92.43,82.44) 92.24,82.25 CPU1.AU1 ; v2(90.13,58.78) 90.13,58.79 90.45,59.11 CPU1.AP38 ; v2(90.12,57.27) 90.12,57.3 89.8,57.62 CPU1.AN40 89.48,58.01 CPU1.AN39 ; CPU1.AM52 88.83,49.91 88.83,49.71 v2(88.78,49.66) ; CPU1.R22 v2(80.23,67.91) ; v2(52.7,69.94) 52.62,70.03 PU4701.3 ; CPU1.AE5 85.45,79.18 85.17,79.46 v2(85.09,79.46) ; CPU1.AP54 90.45,49.14 90.72,48.87 90.72,48.86 90.76,48.82 v2(90.76,48.79) ; CPU1.AN48 CPU1.AP48
  BOTTOM w0.229: v2(78.74,67.91) 78.6,68.05 78.6,68.53 78.6,68.53 78.6,68.87 78.6,68.87 78.6,69.2 CPU1.M22 ; v2(76.98,68.29) CPU1.J22 ; v2(83.48,67.91) CPU1.AB22 CPU1.AB20 ; v2(84.06,71.13) 84.37,71.13 84.7,70.8 CPU1.AD21 ; CPU1.AU51 91.83,50.94 CPU1.AT49
  BOTTOM w0.254: CPU1.AU16 CPU1.AV16 CPU1.AW16 ; CPU1.AJ14 87.85,73.72 CPU1.AL13 88.09,74.24 87.79,74.54 CPU1.AJ13 88.09,74.92 88.09,75.71 v2(88.06,75.74) ; CPU1.AW50 93.56,51.57 93.39,51.74 93.39,51.76 v2(93.22,51.93) 93.04,52.11 93.04,52.14 92.91,52.27 CPU1.AV49 ; v2(75.29,48.96) 75.26,48.98 CPU1.F54 CPU1.D54 73.86,48.98 ; v2(87.43,56.31) 87.32,56.19 CPU1.AH42 ; v2(87.43,56.31) 87.43,56.61 CPU1.AJ41 87.42,57.06 v2(87.42,57.35) 87.01,57.35 CPU1.AH40 86.65,57.49 86.4,57.74 v2(86.4,57.99) ; v2(87.43,56.31) 87.43,55.77 CPU1.AJ43 86.87,55.21 CPU1.AH44 86.87,54.56 CPU1.AJ45 ; CPU1.J59 76.44,45.79 v2(76.14,45.48) ; v2(94.61,72.36) 94.16,72.36 CPU1.AY16 ; CPU1.AW35 93.21,61.31 v2(93.21,61.38) 93.19,61.4 93.19,61.51 CPU1.AV34 92.59,62.12 CPU1.AV33 92.64,62.36 CPU1.AW33 CPU1.AY33 94.65,62.36 95.25,62.96 v2(95.25,63.47) ; v2(94.87,75.41) 94.83,75.44 CPU1.AY11 ; CPU1.AU22 91.91,68.82 91.91,68.49 91.88,68.46 91.88,68.23 v2(91.54,67.89) ; v2(75.29,64.03) 75.29,64.03 CPU1.F30 CPU1.D30 73.86,64.03 ; v2(81.26,78.07) 81.27,78.06 81.28,78.06 81.29,78.05 81.56,78.05 CPU1.V7 ; CPU1.AR23 91.5,67.89 v2(91.54,67.89) ; v2(86.25,82.37) 86.3,82.32 CPU1.AG1 ; CPU1.AJ39 86.55,58.14 v2(86.4,57.99) ; CPU1.L20 78.1,70.95 v2(78.1,71.13) 78.1,71.22 CPU1.L18 ; v2(71.37,67.91) 71.79,67.91 CPU1.A24 ; v2(87.5,66.78) 87.46,66.73 87.46,66.2 CPU1.AJ27 87.2,65.62 CPU1.AH28 86.87,64.97 CPU1.AJ29 87.2,64.39 v2(87.53,64.06) ; CPU1.AU53 91.67,49.48 91.1,50.05 CPU1.AR52 ; CPU1.AM1 89.3,82.45 v2(89.28,82.47) ; v2(82.3,71.72) 82.21,71.72 81.78,71.29 81.78,70.71 CPU1.W20 ; CPU1.N21 79.04,70.13 v2(79.41,69.75) 79.42,69.75 CPU1.P22 ; v2(75.81,71.19) 75.81,71.28 CPU1.G18 75.51,71.72 76.16,72.37 CPU1.H17 ; CPU1.AY6 94.94,78.44 v2(94.99,78.49) ; 87.2,52.94 87.43,52.71 v2(87.43,52.4) 87.32,52.29 CPU1.AH49 ; v2(94.61,68.55) 94.32,68.85 CPU1.AY22 ; CPU1.AY26 94.24,66.15 v2(94.87,66.77) 94.14,67.5 CPU1.AY24 CPU1.AW24 CPU1.AV24 CPU1.AU24 91.93,67.5 v2(91.54,67.89) ; CPU1.C18 72.97,71.31 CPU1.D18 ; v2(82.17,75.91) 82.17,76.01 ; 82.17,76.01 82.17,76.08 81.91,76.34 CPU1.V10 ; 82.17,76.01 82.5,76.34 CPU1.Y10 ; CPU1.AP3 91.06,80.82 v2(91.17,80.82) ; CPU1.AJ54 87.2,49.03 ; 87.2,49.03 87.2,49.37 CPU1.AH53 88,49.69 v2(88.02,49.71) ; 87.2,49.03 87.2,48.71 CPU1.AH55 87.2,48.07 87.2,47.74 CPU1.AJ56 ; CPU1.AJ52 87.2,50.34 87.2,50.67 CPU1.AH51 87.2,51.31 87.2,51.63 CPU1.AJ50 ; v2(87.53,72.38) 87.06,72.85 CPU1.AH16 ; CPU1.AH38 86.72,58.79 86.4,58.47 v2(86.4,57.99) ; CPU1.K1 77.14,81.98 77.14,82.62 v2(77.04,82.72) ; CPU1.AW44 93.56,54.72 93.4,54.89 93.4,54.93 v2(93.24,55.08) 93.24,55.1 93.19,55.15 93.19,55.21 CPU1.AV43 ; CPU1.AG61 CPU1.AG60 ; CPU1.AH17 CPU1.AH19 ; v2(75.29,54) 75.29,54 CPU1.F46 CPU1.D46 73.86,54 ; v2(77.64,44.19) 77.76,44.19 CPU1.L61 ; v2(93.23,59.82) 93.23,59.72 CPU1.AW37 ; CPU1.AB7 83.34,77.88 v2(83.16,78.06) ; v2(93.22,53.51) 93.21,53.51 93.21,53.62 CPU1.AV46 ; 73.86,51.49 CPU1.D50 CPU1.F50 75.29,51.49 v2(75.29,51.49) ; CPU1.A11 71.08,75.45 v2(70.99,75.53) ; CPU1.C20 72.57,70.3 CPU1.B20 72.16,69.9 71.4,69.9 70.87,69.36 v2(70.87,69.31) ; CPU1.F26 CPU1.D26 73.86,66.54 ; v2(90.66,79.35) 90.96,79.05 CPU1.AR5 ; 73.53,45.91 73.46,45.91 72.9,45.36 72.45,45.36 CPU1.B60 ; CPU1.L7 78.22,78.18 v2(78.34,78.18) ; CPU1.AP10 90.31,76.23 v2(90.63,76.55) ; v2(74.52,74.97) 74.2,75.29 CPU1.E11 74.2,75.67 73.53,76.34 73.21,76.34 72.78,75.91 CPU1.C11 72.84,75.46 73.22,75.08 CPU1.D12 73.37,75.01 73.25,74.89 73.25,74.41 CPU1.D14 73.19,74.29 CPU1.C14 72.49,73.89 72.49,73.89 71.97,73.89 71.86,73.78 CPU1.A14 71.28,73.78 v2(70.99,73.5) ; CPU1.AL39 88.2,58.27 88.36,58.12 v2(88.79,58.12) ; CPU1.AP20 90.45,70.86 v2(90.75,70.55) ; CPU1.V58 81.45,46.27 80.48,46.27 CPU1.T58 ; CPU1.AL20 88.8,70.72 v2(88.8,70.55) ; CPU1.AV14 92.51,73.58 92.05,73.58 v2(91.67,73.2) ; v2(94.61,63.47) 94.37,63.71 CPU1.AY30 ; v2(80.26,75.91) 79.84,76.34 CPU1.R10 ; CPU1.AN32 89.8,62.99 89.48,62.67 v2(89.48,62.6) ; CPU1.AF11 85.49,75.38 85.4,75.38 84.71,74.69 v2(84.71,74.17) ; CPU1.AF11 85.55,76.08 85.55,76.25 85.54,76.25 CPU1.AE10 ; CPU1.AF11 85.97,75.76 CPU1.AG11 85.97,74.94 CPU1.AF12 ; 73.86,59.01 CPU1.D38 CPU1.F38 75.29,59.01 v2(75.29,59.01) ; v2(88.83,64.06) 88.83,64.13 CPU1.AL29 ; v2(76.18,80.82) 76.18,80.81 76.07,80.81 CPU1.G3 ; CPU1.Y59 82.25,45.49 82.14,45.49 v2(82.14,45.49) ; v2(70.99,71.21) 71.5,71.21 71.51,71.21 CPU1.A18 ; v2(73.25,80.14) 73.25,80.13 73.43,79.95 CPU1.D5 ; v2(93.21,58.22) 93.21,58.16 CPU1.AW40 ; CPU1.AP26 90.45,66.46 v2(90.12,66.8) ; CPU1.AG62 CPU1.AG63 ; v2(93.22,56.66) 93.21,56.67 93.21,56.77 CPU1.AV41 ; CPU1.AA1 83.3,82.36 v2(83.15,82.52) ; CPU1.AH30 86.64,63.76 v2(86.64,63.47) ; 73.86,56.51 CPU1.D42 CPU1.F42 75.29,56.51 v2(75.29,56.5) ; v2(86.29,53.59) CPU1.AH46 ; CPU1.AY18 94.42,71.28 v2(94.49,71.21) ; v2(90.13,58.78) 90.13,58.78 CPU1.AP39 ; 73.86,61.52 CPU1.D34 CPU1.F34 75.29,61.52 v2(75.29,61.52) ; v2(90.13,60.68) 90.13,60.73 89.8,61.05 CPU1.AN35 ; v2(77.71,47.08) CPU1.L58
  BOTTOM w0.279: CPU1.AW16 93.85,72.59 CPU1.AY16 ; CPU1.A56 72.07,47.58 72.41,47.58 CPU1.B56 ; v2(92.58,76.55) 92.58,76.65 CPU1.AV8 ; v2(71.12,64.99) 71.62,64.99 CPU1.A28 CPU1.B28 ; CPU1.B24 CPU1.A24 ; CPU1.A44 CPU1.B44 ; CPU1.B48 CPU1.A48
  BOTTOM w0.305: v2(55.37,95.47) 55.55,95.29 LCD1.21 ; IOBD1.29 146.86,62.75 v2(146.69,62.58) ; LCD1.34 49.05,92.96 v2(49.02,92.93) ; HOMBD1.13 30.42,101.25 v2(30.35,101.19) ; LCD1.29 51.55,92.94 v2(51.56,92.93) ; CPU1.H57 75.69,46.51 v2(75.43,46.26) 75.25,46.43 74.71,46.43 CPU1.F58 ; CPU1.B56 72.56,47.37 CPU1.C57 ; v2(86.28,52.29) CPU1.AH49 ; HDD1.24 128.13,27.33 HDD1.20 ; v2(27.94,54.58) 27.94,54.57 U3503.14 ; CPU1.V23 81.04,69.11 CPU1.U22 ; CPU1.V23 v2(81.45,67.91) ; CPU1.V23 81.86,69.11 CPU1.W22 ; v2(59.05,92.93) 59.05,92.94 LCD1.14 59.05,95.35 v2(58.93,95.47) ; DIMM1.133 124.9,76.35 124.91,76.34 126.21,76.34 126.43,76.56 v2(126.43,76.95) ; v2(80.98,71.19) 81.04,71.12 CPU1.U20 ; v2(87.43,53.52) 86.94,53.52 CPU1.AH46 ; CPU1.C25 72.56,66.78 CPU1.B26 ; CPU1.AH34 86.61,61.13 86.61,60.92 v2(86.61,60.92) 86.63,60.92 86.8,60.74 CPU1.AJ35 ; CPU1.AU28 91.59,64.58 v2(91.59,64.1) 91.04,63.55 CPU1.AR31 ; CPU1.AU28 CPU1.AV28 ; CPU1.AU28 91.69,65.17 91.69,65.9 CPU1.AU26 ; CPU1.AP48 90.45,52.86 v2(90.8,52.52) 90.8,52.36 CPU1.AR49 ; IOBD1.19 146.81,57.75 146.55,58.01 v2(146.3,58.01) ; v2(83.63,44.19) 83.75,44.19 CPU1.AC61 ; PU4902.4 136.28,73.89 v2(136.27,73.88) ; LCD1.8 62.05,92.99 v2(62.1,92.93) ; CPU1.AD3 84.77,80.51 85.09,80.83 v2(85.18,80.83) ; CPU1.F61 75.04,44.49 74.74,44.18 v2(74.64,44.18) ; v2(50.04,92.93) 50.05,92.94 LCD1.32 ; CPU1.B4 72.24,79.31 v2(72.29,79.25) ; v2(87.06,45.77) 86.93,45.77 86.61,45.46 CPU1.AG60 86,45.65 v2(86,46.15) 85.71,46.44 CPU1.AE58 85.13,46.05 85.13,45.47 v2(85.12,45.46) ; v2(87.58,70.55) 87.5,70.47 CPU1.AH20 86.71,70.12 CPU1.AG21 ; CPU1.AH36 v2(86.28,60.09) ; v2(73.41,42.54) 73.56,42.7 CPU1.D63 73.56,43.78 CPU1.D62 ; v2(83.62,46.17) 83.42,46.17 83.39,46.19 83.16,46.19 CPU1.AA58 82.92,46.15 CPU1.Y59 ; v2(74.54,73.08) 74.2,72.74 CPU1.E17 73.37,71.71 CPU1.D18 73.37,71.61 v2(73.86,71.11) ; CPU1.AT46 91.81,52.86 v2(91.47,52.52) 91.83,52.15 CPU1.AT49 ; LCD1.11 60.55,92.96 v2(60.58,92.93) ; v2(76.56,75.89) 76.81,76.14 CPU1.J10 ; v2(122.81,27.4) U5602.8 U5602.3 v2(125.35,27.4) ; CPU1.AT61 91.12,44.91 91.12,45.31 v2(91.12,45.31) ; CPU1.AP29 90.45,64.39 v2(90.13,64.06) ; IOBD1.1 148.59,48.75 148.9,48.44 v2(149.83,48.44) ; CPU1.AN17 89.47,72.59 90.11,72.59 90.12,72.59 CPU1.AP17 CPU1.AR17 ; HDD1.14 132.05,28.26 v2(132.08,28.29) ; v2(89.99,78.48) 89.99,78.4 CPU1.AN7 ; CPU1.AG61 CPU1.AG62 ; v2(80.64,44.19) 80.77,44.19 81.05,44.48 CPU1.U61 ; v2(82.12,46.15) 81.83,46.44 CPU1.V58 ; CPU1.N10 78.95,76.34 v2(79.38,75.91) ; CPU1.AB10 83.87,76.11 v2(83.87,75.81) ; CPU1.AL10 88.36,76.04 v2(88.06,75.74) ; v2(87.53,72.38) 87.96,72.38 88.16,72.59 ; LCD1.28 52.05,95.32 v2(52.2,95.47) ; v2(149.27,50.25) IOBD1.4 ; v2(79.18,80.81) 79.03,80.67 78.93,80.67 CPU1.N3 ; CPU1.D21 74.01,69.07 CPU1.D23 ; CPU1.L13 77.29,74.89 CPU1.K12 76.53,74.93 v2(76.48,74.97) 76.48,74.77 CPU1.H13 ; CPU1.AF18 85.76,71.69 v2(85.34,72.1) 85.47,72.1 CPU1.AF17 ; HDD1.17 130.55,28.28 v2(130.56,28.29) ; IOBD1.16 146.83,56.25 v2(146.81,56.23) ; PU4902.8 v2(136.78,80.4) ; v2(57.66,95.47) 57.55,95.36 LCD1.17 ; CPU1.AH32 v2(86.3,62.69)
  BOTTOM w0.33: DIMM1.13 125.4,37.95 125.8,38.34 v2(125.8,38.55) ; v2(129.8,39.45) 129.8,39.64 130.22,40.05 DIMM1.20 ; v2(126.43,93.15) 126.43,92.87 126.11,92.55 DIMM1.187 ; DIMM1.179 126.1,90.15 127.07,89.18 v2(127.07,88.95) ; DIMM1.161 v2(125.16,84.75) ; DIMM1.66 129.79,53.85 129.17,53.23 v2(129.17,52.65) ; DIMM1.156 129.09,83.25 128.53,83.8 v2(128.53,84.45) ; CPU1.AN17 CPU1.AM17 CPU1.AL17 88.16,72.59 ; DIMM1.136 129.55,77.25 129.17,77.63 v2(129.17,77.85) ; DIMM1.54 130.21,50.25 129.8,50.65 v2(129.8,50.85) ; DIMM1.60 130.95,52.05 130.91,52.01 129.53,52.01 128.53,51.02 v2(128.53,50.85) ; v2(127.07,45.75) 127.07,46.03 126.14,46.95 DIMM1.43 ; DIMM1.26 130.26,41.85 129.8,41.39 v2(129.8,41.25) ; v2(125.8,81.15) 125.8,81.56 125.59,81.77 124.93,81.77 124.92,81.75 DIMM1.151 ; DIMM1.173 125.52,88.35 125.8,88.63 v2(125.8,88.95) ; DIMM1.38 129.38,45.45 128.53,44.6 v2(128.53,44.25) ; DIMM1.172 130.06,88.05 129.8,88.31 v2(129.8,88.65) ; v2(129.8,35.25) 129.8,35.02 130.17,34.65 DIMM1.2 ; DIMM1.184 130.45,91.65 v2(130.44,91.64) ; v2(127.07,51.75) 127.07,52.15 126.27,52.95 DIMM1.63 ; DIMM1.31 125.33,43.35 125.8,43.81 v2(125.8,43.95) ; v2(129.8,80.25) 129.8,80.02 130.18,79.65 DIMM1.144 ; v2(125.8,49.95) 125.8,50.19 125.44,50.55 DIMM1.55 ; DIMM1.190 v2(130.44,93.45) ; DIMM1.48 130.12,48.45 130.12,48.45 129.8,48.77 v2(129.8,49.05) ; DIMM1.19 125.47,39.75 125.8,40.08 v2(125.8,40.33) ; DIMM1.134 130.18,76.65 129.8,76.28 v2(129.8,76.05) ; DIMM1.196 v2(130.44,95.25) ; DIMM1.9 v2(125.16,36.75) ; DIMM1.162 130.27,85.05 129.8,84.59 v2(129.8,84.45) ; v2(129.17,86.85) 129.17,87.05 129.57,87.45 DIMM1.170 ; DIMM1.3 125.15,34.95 v2(125.22,35.02) ; DIMM1.65 125.44,53.55 125.8,53.91 v2(125.8,54.15) ; v2(126.43,47.95) 126.43,48.21 125.89,48.75 DIMM1.49 ; DIMM1.72 130.27,55.65 129.89,55.28 129.89,55.14 v2(129.8,55.05) ; DIMM1.128 130.61,74.85 130.61,74.86 130.51,74.86 130.5,74.86 129.4,74.86 128.53,75.73 v2(128.53,76.05) ; DIMM1.138 v2(130.44,77.85) ; DIMM1.139 126.21,78.15 127.07,79 v2(127.07,79.35) ; v2(129.8,90.45) 129.8,90.15 130.11,89.85 DIMM1.178 ; v2(129.8,43.05) 129.8,43.31 130.14,43.65 DIMM1.32 ; DIMM1.168 v2(130.44,86.85) ; v2(128.53,46.65) 128.53,46.83 129.56,47.85 DIMM1.46 ; DIMM1.127 125.56,74.55 125.8,74.79 v2(125.8,75.15) ; DIMM1.25 125.59,41.55 126.43,42.39 v2(126.43,42.52) ; v2(127.07,81.15) 127.07,81.49 126.2,82.35 DIMM1.153 ; v2(129.17,82.05) 129.17,81.9 129.61,81.45 DIMM1.150 ; DIMM1.195 125.54,94.95 125.8,94.7 v2(125.8,94.35) ; DIMM1.61 125.42,52.35 125.8,51.97 v2(125.8,51.75) ; DIMM1.185 125.54,91.95 125.8,91.7 v2(125.8,91.35) ; DIMM1.28 129.44,42.45 128.53,41.54 v2(128.53,41.25) ; DIMM1.71 125.08,55.35 v2(125.16,55.27) ; DIMM1.44 130.22,47.25 129.8,46.84 v2(129.8,46.65) ; DIMM1.11 126.24,37.35 127.07,38.17 v2(127.07,38.55) ; DIMM1.8 129.57,36.45 v2(129.16,36.04) ; DIMM1.14 129.61,38.25 129.17,37.81 v2(129.17,37.65) ; DIMM1.189 v2(125.16,93.15) ; DIMM1.145 125.45,79.95 125.8,79.61 v2(125.8,79.35) ; DIMM1.155 v2(125.16,82.95) ; DIMM1.167 126,86.55 126.43,86.98 v2(126.43,87.37) ; DIMM1.37 125.47,45.15 125.8,45.48 v2(125.8,45.75)
  BOTTOM w0.356: 78.16,73.12 78.11,73.12 CPU1.L15 ; 78.16,73.12 77.73,72.69 CPU1.L17 ; 78.16,73.12 v2(78.16,73.04) ; v2(63.25,48.1) 62.93,47.78 U701.3 ; PC4405.2 35.47,3.59 34.88,4.17 PQ4411.4 ; EU3401.3 v2(16.89,62.96) ; CPU1.R8 CPU1.R10
  BOTTOM w0.381: C1802.1 v2(62.08,66.83) ; C1801.1 v2(62.07,65.94) ; R3024.1 40.07,55.4 v2(39.62,55.85) ; v2(94.08,102.71) 94.77,102.02 Q1901.S ; C2604.2 142.31,69.26 v2(142.31,68.15) ; Q2401.S 67.41,36.29 C2421.2
  BOTTOM w0.406: v2(38.48,5.43) 38.48,5.41 38.7,5.19 PQ4413.1 ; v2(114.17,22.7) 114.3,22.83 TP1.5 ; C2901.2 29.27,30.89 28.63,31.54 U2901.1 ; v2(34.54,95.47) 34.54,95.45 33.8,94.71 HOMBD1.17 ; PC4405.2 36.41,3.59 36.71,3.89 PQ4413.4 38.47,3.89 v2(38.48,3.9) ; EU3403.3 v2(19.68,44.93)
  BOTTOM w0.508: PR4904.2 v2(134.62,43.66) ; R712.2 EC702.2 ; EC702.2 R405.2 ; EC702.2 v2(65.15,42) ; IOBD1.42 151.36,49.6 150.2,48.44 v2(149.83,48.44) ; PC4801.2 46.8,89.06 46.48,88.74 PR4802.2 ; PC4801.2 PR4803.2 ; PC4801.2 v2(47.37,89.76) ; PC4807.2 v2(42.04,89.12) ; BATT1.9 84.93,19.88 ; BATT1.9 84.04,18 ; BATT1.9 85.81,18 ; 14,55.66 USB1.12 15.54,56.55 ; C2723.1 31.18,22.26 v2(30.99,22.45) ; 16.84,41.45 USB2.4 16.08,40.69 ; KB1.28 159.12,45.82 v2(161.55,45.82) ; USB2.11 15.33,39.44 ; USB2.11 15.33,37.66 ; USB2.11 17.07,38.55 ; C1113.2 C1103.2 66.41,70.64 C1114.2 64.95,70.4 v2(64.9,70.45) ; R3703.2 139.66,67.21 140.55,68.1 R3707.2 C2503.2 142.27,68.1 v2(142.31,68.15) ; HS1.1 59.9,63.19 ; HS1.1 59.9,56.81 ; HS1.1 63.09,60 ; HS1.1 56.71,60 ; USB2.13 5.18,53.79 ; R1204.2 151.07,30.27 150.88,30.08 v2(150.88,29.81) ; BATT1.8 102.94,18 ; BATT1.8 102.05,18.89 ; BATT1.8 101.16,18 ; BATT1.8 102.05,17.11 ; C1903.1 93.15,93.25 v2(92.46,93.95) ; v2(127.76,102.58) 127.85,102.67 DB1.3 127.85,106.18 ; v2(103.5,27.65) 103.44,27.59 C2610.2 ; EC8615.2 v2(24.51,37.05) 24.45,36.99 EC2703.2 ; v2(67.69,37.31) 67.12,36.73 Q2401.S ; v2(55.5,99.54) 55.8,99.24 LCD1.43 ; PC4517.2 40.58,85.63 v2(40.64,85.57) ; EC1701.1 v1(76.33,92.23) 77.53,92.23 v2(77.85,92.55) ; BATT1.7 100.94,18 ; BATT1.7 100.05,17.11 ; BATT1.7 99.16,18 ; BATT1.7 100.05,18.89 ; v2(47.37,9.75) 47.31,9.68 PR4445.2 ; v2(41.95,44.16) 41.72,44.39 PC4605.2 ; PC5101.2 50.29,91.47 v2(50.74,91.92) ; v2(43.81,6.44) 43.12,5.75 PR4404.2 ; USB1.14 7.86,55.1 ; EU3402.2 v2(19.56,58.77) ; v2(134.62,45.43) 134.75,45.56 PR4906.1 PC4909.2 ; v2(143,34.38) 143,34.89 143.26,35.15 C2422.2 ; v2(69.85,95.47) 69.32,96 LCD1.41 66.65,96 LCD1.42 ; 17.07,51.35 USB2.10 15.33,52.24 ; PC4527.2 41.78,68.8 v3(40.77,67.79) ; LCD1.45 45.06,96 v2(45.59,95.47) ; D4301.1 89.92,27.78 v2(89.28,28.42) ; PC4813.2 55.96,79.65 v3(55.75,79.85) ; C1904.1 94.97,93.68 v2(95.43,94.15) ; 12.99,90.35 HDMI1.21 11.28,91.29 ; Q6205.S 123.79,19.56 v2(123.7,19.65) ; v2(32,23.21) 31.65,23.56 C2718.2 ; v2(153.18,58.64) 153.16,58.64 153.02,58.5 IOBD1.43 ; USB2.12 6.46,37.2 ; R4301.2 100.33,26.52 101.09,27.29 v2(101.09,27.65) ; BATT1.10 105.18,19.88 ; BATT1.10 106.06,18 ; BATT1.10 104.29,18 ; PC5109.2 54.93,89.57 v2(54.86,89.63) ; PC4737.2 59.8,42.44 C702.2 ; v2(151.78,46.07) 151.14,46.07 150.86,46.35 IOBD1.41 ; PQ4406.S 39.15,8.92 PR4429.2 37.66,8.92 v2(37.59,8.86) ; v2(95.63,28.42) 95.89,28.67 EC4305.1 96.33,28.07 D4302.1 ; v2(136.53,88.99) 137.46,89.93 SPI25.4 ; v3(138.05,21.94) 139.31,23.2 HDD1.21 ; PR4406.1 43.75,15.53 v2(43.94,15.33) ; v3(126.75,24.99) 126.75,26.38 127.56,27.2 HDD1.24 ; v2(18.8,21.3) 19.33,20.77 C2701.2 ; v2(128.27,21.94) 128.27,22.93 HDD1.23 ; v2(64,89.51) 64,89.51 64.01,89.5 64.95,89.5 C5202.2 ; R709.2 EC701.2 v2(65.15,46.07) ; PR4805.2 PC4809.2 v2(42.93,89.12) ; EU3404.2 v2(20.57,40.61) ; v2(67.06,77.18) 67.12,77.25 C1105.2 ; v2(47.24,100.17) 47.24,98.29 LCD1.44 46.35,98.5 v2(46.35,100.17) ; FAN1.5 138.87,78.13 138.87,80.61 PC4911.2 ; v2(13.84,74.83) 13.84,74.58 C6401.2 14.29,74.26 R5410.2 ; v2(91.44,24.1) 90.96,23.62 EC4304.2 ; EC2501.2 v2(140.72,85.69) ; v3(139.32,28.54) 139.6,28.26 HDD1.22 ; USB1.11 15.54,69.35 ; USB1.11 14,68.46 ; USB1.11 14,70.24 ; EC5210.2 v2(44.32,90.14) ; PC4203.2 v2(34.92,23.21) ; TP1.10 119.9,22.94 v2(119.89,22.95) 120.9,23.97 AFTP6235.1 ; v2(147.02,69.51) 147.35,69.18 151.26,69.18 151.75,68.69 IOBD1.44 ; C6202.2 v2(25.53,14.06) ; v2(64.9,74.26) 64.26,73.63 C1104.2 C1123.2 ; EC4301.2 92.46,28.67 v2(92.71,28.42) 92.96,28.67 EC4302.2 93.54,27.44 D4303.1 ; C2501.2 139.64,100.16 EC2503.2 ; PR4530.2 34.29,63.34 v2(35.81,64.86) ; v2(21.34,71.34) 21.02,71.66 EC8607.2 20.32,70.9 R5412.2 ; PC4913.2 v2(134.62,40.99) ; PC4205.2 v2(34.92,24.1) ; USB1.13 5.8,72.15 ; PC4705.2 55.75,69.18 v2(55.88,69.31) ; C2901.2 v2(29.59,30.19) ; C5214.2 v2(43.18,90.14) ; R2447.2 v2(150.94,43.27) ; PC4916.2 134.81,80.55 v2(135.13,80.23) ; v2(52.96,89.63) PU5101.2 50.1,89.63 PC5108.2 ; R603.1 v2(67.56,72.23) ; PC4204.2 v2(34.92,22.32) ; HS3.1 88.08,32.8
  vias: v1(19.33,12.19) v1(24.13,22.57) v1(24.36,17.16) v1(26.04,44.16) v1(33.4,74.01) v1(47.55,18.84) v1(48.06,3.8) v1(48.41,29.3) v1(56.64,18.28) v1(63.45,101.95) v1(65.41,58.29) v1(65.61,63.01) v1(66.83,62.55) v1(80.82,51.25) v1(83.34,33.27) v1(98.42,104.62) v1(103.4,64.03) v1(108.61,47.11) v1(121.41,74.14) v1(122.89,54.81) v1(123.29,90.44) v1(123.75,37.38) v1(128.19,79.77) v1(137.67,27.22) v2(1.02,5.56) v2(1.06,8.5) v2(3.05,94.96) v2(3.17,71.47) v2(3.43,20.8) v2(3.43,18.26) v2(3.56,15.46) v2(3.75,9.33) v2(4.32,92.93) v2(4.32,73.25) v2(4.83,1.11) v2(5.21,13.94) v2(5.31,8.64) v2(5.46,11.45) v2(5.59,94.96) v2(5.59,19.4) v2(5.71,20.8) v2(5.97,91.92) v2(6.73,93.31) v2(7.11,14.06) v2(7.14,9.79) v2(7.37,52.8) v2(7.37,37.05) v2(7.37,1.11) v2(7.47,12.29) v2(7.62,20.8) v2(8.13,94.96) v2(8.76,70.96) v2(8.76,54.96) v2(9.4,52.8) v2(9.53,93.31) v2(9.53,37.05) v2(9.91,1.11) v2(10.67,94.96) v2(10.79,54.96) v2(11.3,37.05) v2(11.43,52.8) v2(11.81,93.44) v2(12.45,1.11) v2(12.83,92.17) v2(12.83,54.7) v2(13.21,94.96) v2(13.21,37.05) v2(13.46,71.6) v2(13.72,80.49) v2(13.72,78.45) v2(14.99,1.11) v2(15.75,94.96) v2(16.26,91.15) v2(16.51,5.68) v2(16.89,61.05) v2(16.89,59.15) v2(17.02,17.75) v2(17.27,69.82) v2(17.27,69.06) v2(17.53,1.11) v2(17.78,12.41) v2(17.91,42.89) v2(17.91,40.99) v2(18.03,37.81) v2(18.29,94.96) v2(18.8,17.75) v2(19.46,37.81) v2(19.81,83.66) v2(19.81,52.16) v2(19.81,51.53) v2(20.07,82.26) v2(20.07,80.49) v2(20.07,78.58) v2(20.07,1.11) v2(20.32,16.6) v2(20.32,9.24) v2(20.83,82.26) v2(20.83,80.49) v2(20.83,78.58) v2(20.83,9.87) v2(21.08,75.66) v2(21.08,9.11) v2(21.34,97.25) v2(21.36,37.81) v2(22.1,25.11) v2(22.37,50.24) v2(22.61,1.11) v2(22.99,25.11) v2(23.62,43.15) v2(23.88,26.89) v2(23.88,26) v2(23.88,25.11) v2(23.88,24.22) v2(23.88,23.34) v2(24,65.12) v2(24,63.09) v2(24,61.04) v2(24.77,51.28) v2(24.77,25.11) v2(24.89,54.32) v2(24.89,47.08) v2(24.89,45.05) v2(25.15,1.11) v2(25.4,12.29) v2(25.53,54.96) v2(25.53,54.32) v2(25.53,53.69) v2(25.65,25.11) v2(26.16,54.32) v2(27.69,1.11) v2(27.81,28.8) v2(28.35,44.73) v2(28.96,103.98) v2(30.23,1.11) v2(31.5,103.98) v2(31.5,9.49) v2(32.77,1.11) v2(33.4,1.87) v2(34.04,102.84) v2(34.04,100.81) v2(35.18,65.5) v2(35.31,1.11) v2(35.56,27.78) v2(35.81,66.13) v2(35.81,65.5) v2(36.45,65.5) v2(36.58,103.98) v2(37.85,1.11) v2(39.12,103.98) v2(40.39,50.13) v2(40.64,1.11) v2(41.27,51.02) v2(41.27,50.13) v2(41.27,49.24) v2(41.66,103.98) v2(42.16,50.13) v2(43.69,1.11) v2(44.2,103.98) v2(45.72,2.63) v2(46.48,1.11) v2(46.74,103.98) v2(49.02,1.11) v2(49.28,103.98) v2(49.4,2.63) v2(50.16,73.5) v2(50.16,72.74) v2(50.16,71.98) v2(50.16,11.52) v2(50.16,8.6) v2(50.16,5.81) v2(50.16,4.79) v2(50.16,2.63) v2(50.93,73.5) v2(50.93,72.74) v2(50.93,71.98) v2(51.18,14.32) v2(51.82,103.98) v2(51.82,73.5) v2(51.82,72.74) v2(51.82,71.98) v2(52.7,73.5) v2(52.7,72.74) v2(52.7,71.98) v2(53.34,15.08) v2(53.47,73.5) v2(53.47,72.74) v2(53.47,71.98) v2(54.36,103.98) v2(54.61,99.54) v2(56.52,15.08) v2(56.9,103.98) v2(57.91,15.08) v2(58.42,89.5) v2(59.05,101.31) v2(59.05,15.08) v2(59.44,103.98) v2(60.33,89.12) v2(61.09,101.31) v2(61.59,36.8) v2(61.59,15.08) v2(61.98,103.98) v2(61.98,89.12) v2(62.36,56.86) v2(63.25,46.07) v2(63.88,57.5) v2(64.14,15.08) v2(64.26,54.96) v2(64.52,103.98) v2(66.29,66.39) v2(66.29,64.48) v2(66.67,15.08) v2(69.22,15.08) v2(69.47,62.96) v2(69.47,62.07) v2(69.6,113.89) v2(69.6,111.6) v2(69.6,109.57) v2(70.74,114.9) v2(71.37,62.96) v2(72.01,15.08) v2(72.64,95.73) v2(72.9,114.9) v2(73.03,114.01) v2(73.09,65.06) v2(73.06,62.98) v2(73.06,60.47) v2(73.06,57.96) v2(73.06,55.46) v2(73.08,50.09) v2(73.06,47.94) v2(74.93,69.64) v2(75.23,78.73) v2(75.26,66.54) v2(75.69,114.9) v2(77.85,114.9) v2(77.85,93.82) v2(77.85,91.41) v2(78.11,113.25) v2(78.87,97) v2(78.87,66.26) v2(78.87,64.48) v2(78.87,62.58) v2(78.87,60.55) v2(78.87,58.64) v2(78.87,56.99) v2(78.87,55.09) v2(78.87,53.18) v2(78.87,51.02) v2(78.87,50.39) v2(79.38,42.64) v2(79.88,114.9) v2(80.26,52.55) v2(81.41,53.31) v2(81.66,15.08) v2(82.3,50.39) v2(82.42,114.9) v2(84.96,114.9) v2(84.96,50.39) v2(86.64,67.24) v2(87.5,114.9) v2(88.18,67.87) v2(88.19,66.82) v2(88.77,28.92) v2(88.87,36.75) v2(90.04,114.9) v2(90.12,67.89) v2(90.2,39.32) v2(91.38,61.66) v2(92.58,114.9) v2(92.96,105.84) v2(92.96,103.6) v2(94.56,56.64) v2(95.12,114.9) v2(95.24,59.85) v2(96.11,61.39) v2(96.44,49.02) v2(96.54,58.07) v2(96.69,46.06) v2(96.67,43.4) v2(97.41,105.5) v2(97.66,114.9) v2(97.96,47.46) v2(97.99,44.58) v2(98.02,42.03) v2(98.17,105.5) v2(98.93,105.5) v2(99.37,43.2) v2(99.69,107.79) v2(99.69,107.03) v2(99.69,106.27) v2(99.69,105.5) v2(99.69,104.74) v2(99.69,103.98) v2(100.2,114.9) v2(100.2,46.1) v2(100.46,105.5) v2(100.58,50.77) v2(101.22,105.5) v2(101.22,50.77) v2(101.85,50.77) v2(101.98,105.5) v2(102.11,46.07) v2(102.23,21.56) v2(102.49,50.77) v2(102.74,114.9) v2(102.87,21.56) v2(104.14,21.56) v2(104.78,21.56) v2(105.28,114.9) v2(106.05,21.56) v2(106.81,21.56) v2(106.93,105.12) v2(106.93,103.47) v2(107.7,108.93) v2(107.82,114.9) v2(108.08,26.38) v2(108.33,108.93) v2(108.46,16.1) v2(108.97,108.93) v2(109.6,108.93) v2(110.24,108.93) v2(110.49,113.25) v2(110.62,114.9) v2(110.64,104.92) v2(111.38,16.1) v2(111.51,22.7) v2(111.76,25.37) v2(112.27,94.46) v2(112.27,92.55) v2(112.9,98.39) v2(113.28,114.9) v2(114.43,16.1) v2(115.06,94.46) v2(115.06,92.55) v2(115.06,30.45) v2(115.7,95.73) v2(115.95,114.52) v2(115.95,30.45) v2(116.2,112.24) v2(116.84,30.45) v2(116.84,16.1) v2(116.97,110.46) v2(117.73,30.45) v2(119.13,95.85) v2(119.38,16.1) v2(119.51,109.44) v2(121.67,109.44) v2(121.92,16.1) v2(122.17,96.11) v2(122.17,95.22) v2(124.08,109.44) v2(124.46,16.1) v2(125.22,73.75) v2(125.39,56.56) v2(125.8,72.51) v2(125.8,61.95) v2(126.43,84.75) v2(126.43,82.95) v2(126.43,67.23) v2(126.43,66.15) v2(126.43,60.27) v2(126.43,36.75) v2(126.62,109.44) v2(126.62,73.63) v2(127,16.1) v2(127.07,91.35) v2(127.07,75.15) v2(127.07,72.51) v2(127.07,68.91) v2(127.07,64.95) v2(127.07,61.95) v2(127.07,49.95) v2(127.07,43.95) v2(127.07,40.33) v2(127.7,82.95) v2(127.9,86.85) v2(127.9,61.05) v2(127.9,59.25) v2(128.53,91.64) v2(128.53,90.45) v2(128.53,88.65) v2(128.53,71.25) v2(128.53,69.45) v2(128.53,65.85) v2(128.53,49.05) v2(128.53,39.45) v2(129.03,99.54) v2(129.16,109.44) v2(129.17,93.45) v2(129.17,67.65) v2(129.17,64.65) v2(129.17,62.85) v2(129.17,61.05) v2(129.17,59.25) v2(129.54,16.1) v2(129.8,69.45) v2(129.8,65.85) v2(129.8,44.25) v2(130.44,62.85) v2(131.19,109.44) v2(132.08,16.1) v2(134.62,16.1) v2(134.65,34) v2(136.78,77.95) v2(136.78,77.18) v2(136.78,76.55) v2(137.16,16.1) v2(137.29,41.62) v2(138.3,101.57) v2(139.7,16.1) v2(140.97,66.26) v2(141.48,75.15) v2(141.99,74.64) v2(142.75,16.1) v2(143,88.11) v2(143.26,101.44) v2(143.26,97.25) v2(143.26,94.33) v2(143.26,91.03) v2(144.53,55.47) v2(145.03,16.1) v2(145.16,82.26) v2(145.92,53.31) v2(146.18,72.23) v2(146.43,79.98) v2(146.81,54.83) v2(147.96,77.82) v2(149.48,76.04) v2(149.86,53.31) v2(151,74.39) v2(152.02,15.08) v2(152.27,16.86) v2(152.78,72.23) v2(154.31,15.08) v2(154.43,70.45) v2(155.07,26) v2(156.34,68.67) v2(156.59,15.08) v2(158.12,67.28) v2(159.89,66.01) v2(160.02,13.68) v2(160.78,11.78) v2(161.54,64.99) v2(161.93,10.13) v2(163.07,13.81) v2(163.45,63.98) v2(163.7,12.03) v2(164.47,10.13) v2(164.97,52.55) v2(165.48,63.09) v2(166.12,10.13) v2(166.88,47.08) v2(166.88,45.18) v2(166.88,42.39) v2(166.88,39.72) v2(166.88,37.05) v2(166.88,34.13) v2(166.88,31.21) v2(166.88,28.42) v2(166.88,25.88) v2(166.88,24.1) v2(166.88,21.94) v2(166.88,19.78) v2(166.88,16.6) v2(166.88,13.81) v2(167.77,62.2) v2(168.02,59.4) v2(168.02,56.86) v2(168.02,54.32) v2(168.02,51.78) v2(168.02,49.24) v3(10.79,5.56) v3(13.21,5.56) v3(17.53,4.03) v3(29.08,91.15) v3(30.61,75.02) v3(31.5,75.91) v3(31.5,75.02) v3(31.75,86.07) v3(32.26,85.31) v3(32.38,75.91) v3(32.38,75.02) v3(32.64,86.07) v3(33.15,85.31) v3(33.15,84.42) v3(33.27,75.91) v3(33.27,75.02) v3(33.53,86.07) v3(34.04,85.31) v3(34.42,86.07) v3(36.7,36.8) v3(37.59,36.8) v3(37.72,75.02) v3(38.48,36.8) v3(38.61,75.91) v3(38.61,75.02) v3(38.73,92.42) v3(38.73,91.41) v3(39.37,36.8) v3(39.5,75.91) v3(39.5,75.02) v3(40.39,75.91) v3(45.09,31.46) v3(45.72,69.82) v3(45.72,68.93) v3(45.97,82.26) v3(45.97,81.37) v3(45.97,31.46) v3(46.23,70.58) v3(46.61,71.34) v3(46.61,69.82) v3(46.86,79.98) v3(46.86,31.46) v3(46.86,30.57) v3(47.12,72.1) v3(47.12,70.58) v3(47.37,81.37) v3(47.5,71.34) v3(47.5,69.82) v3(47.5,28.92) v3(47.5,28.03) v3(47.75,31.46) v3(47.75,30.57) v3(48.01,72.1) v3(48.01,70.58) v3(48.13,79.98) v3(48.26,19.27) v3(48.39,71.34) v3(48.39,69.82) v3(48.9,72.1) v3(48.9,70.58) v3(49.02,79.98) v3(49.15,19.27) v3(49.28,71.34) v3(49.28,69.82) v3(49.28,31.46) v3(49.53,29.18) v3(49.53,28.29) v3(49.53,27.4) v3(50.04,79.98) v3(50.16,31.46) v3(50.93,19.27) v3(51.05,31.46) v3(51.82,41.37) v3(51.82,19.27) v3(52.32,49.75) v3(52.7,41.37) v3(52.7,19.27) v3(52.83,31.46) v3(53.21,49.75) v3(53.59,41.37) v3(53.59,19.27) v3(54.1,49.75) v3(54.36,73.37) v3(54.36,72.48) v3(54.48,41.37) v3(54.48,19.27) v3(54.99,49.75) v3(55.37,41.37) v3(55.88,87.85) v3(55.88,49.75) v3(56.26,41.37) v3(56.39,36.8) v3(56.77,49.75) v3(57.15,41.37) v3(57.66,74.14) v3(57.66,73.25) v3(57.91,68.8) v3(58.04,41.37) v3(58.42,64.1) v3(58.55,88.11) v3(58.93,41.37) v3(59.31,64.1) v3(60.07,86.33) v3(60.2,64.1) v3(60.71,85.44) v3(60.71,78.58) v3(61.09,64.1) v3(61.98,84.42) v3(61.98,83.53) v3(61.98,81.88) v3(61.98,80.87) v3(61.98,79.98) v3(61.98,64.1) v3(61.98,18.51) v3(65.79,18.51) v3(69.47,18.51) v3(72.52,22.07) v3(75.44,31.84) v3(76.71,28.92) v3(79.88,31.84) v3(79.88,30.96) v3(79.88,30.07) v3(133.73,57.63) v3(133.73,56.1) v3(133.73,53.94) v3(133.73,53.05) v3(134.11,51.53) v3(134.11,50.64) v3(135,51.53) v3(135,50.64) v3(136.27,28.54) v3(137.29,28.54) v3(137.79,70.83) v3(137.79,69.94) v3(141.6,46.07) v3(141.6,45.18) v3(141.6,44.29) v3(141.86,61.18) v3(141.86,60.29) v3(141.86,59.4) v3(142.49,45.18) v3(143,58.39) v3(143.64,57.37) v3(143.89,58.39)
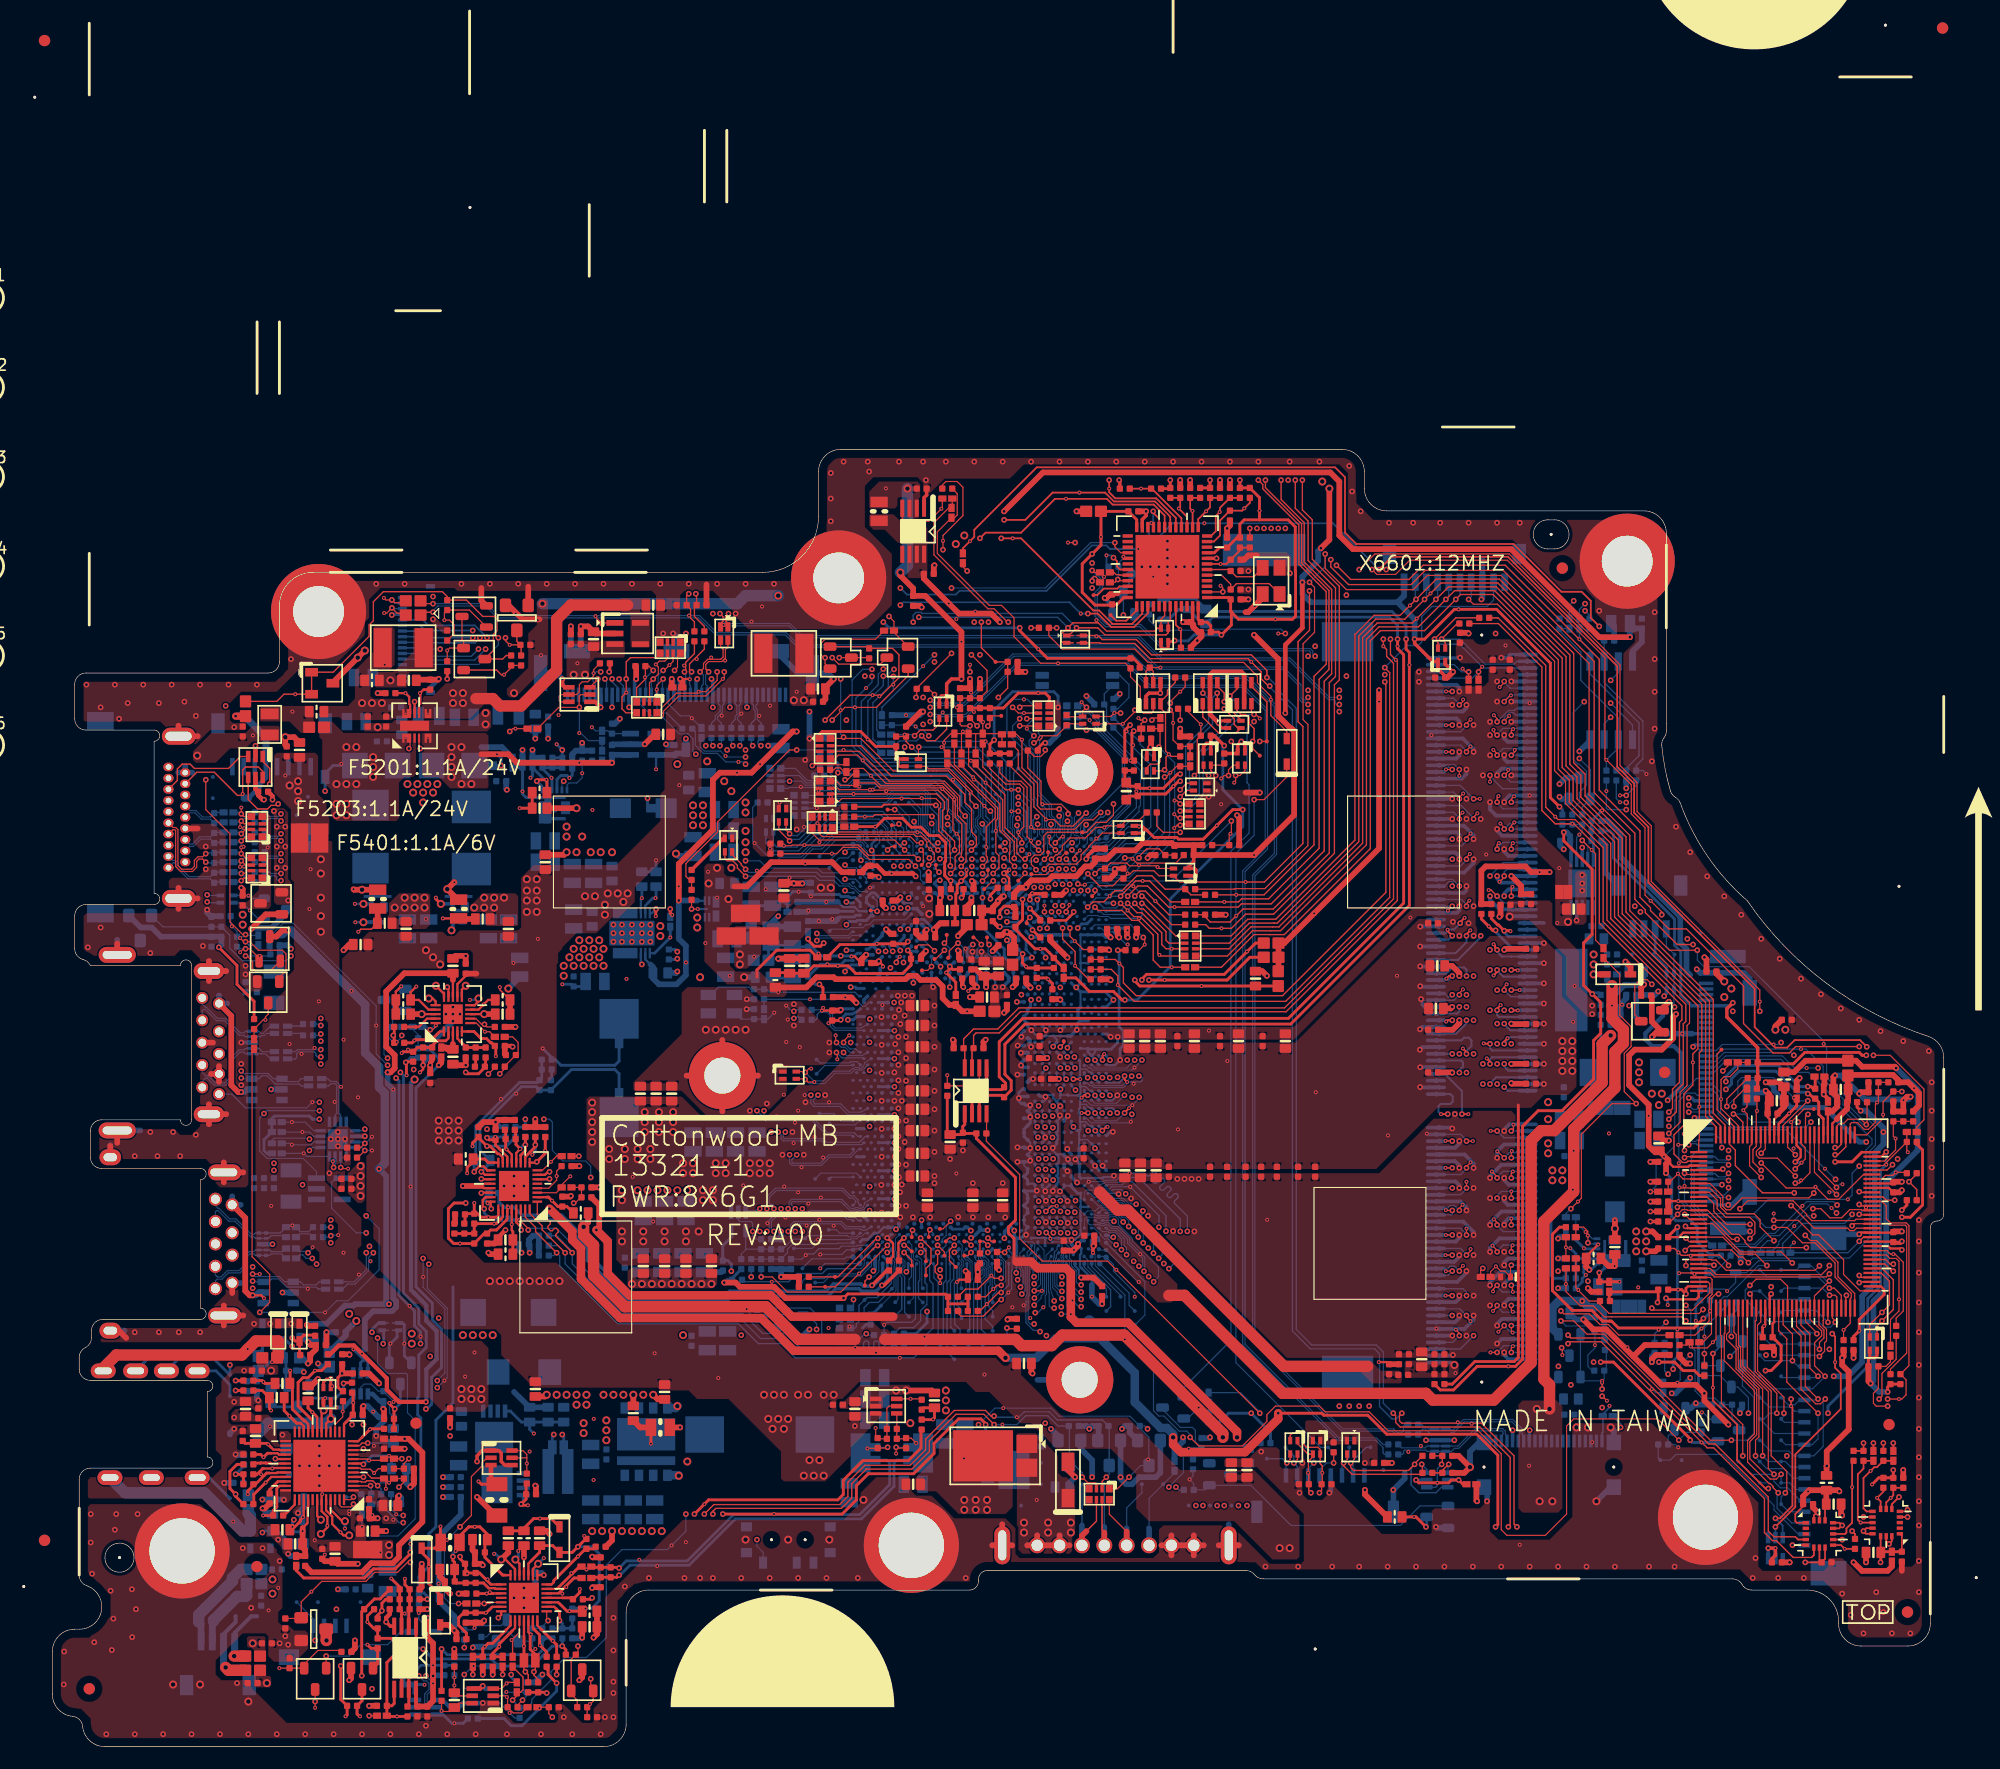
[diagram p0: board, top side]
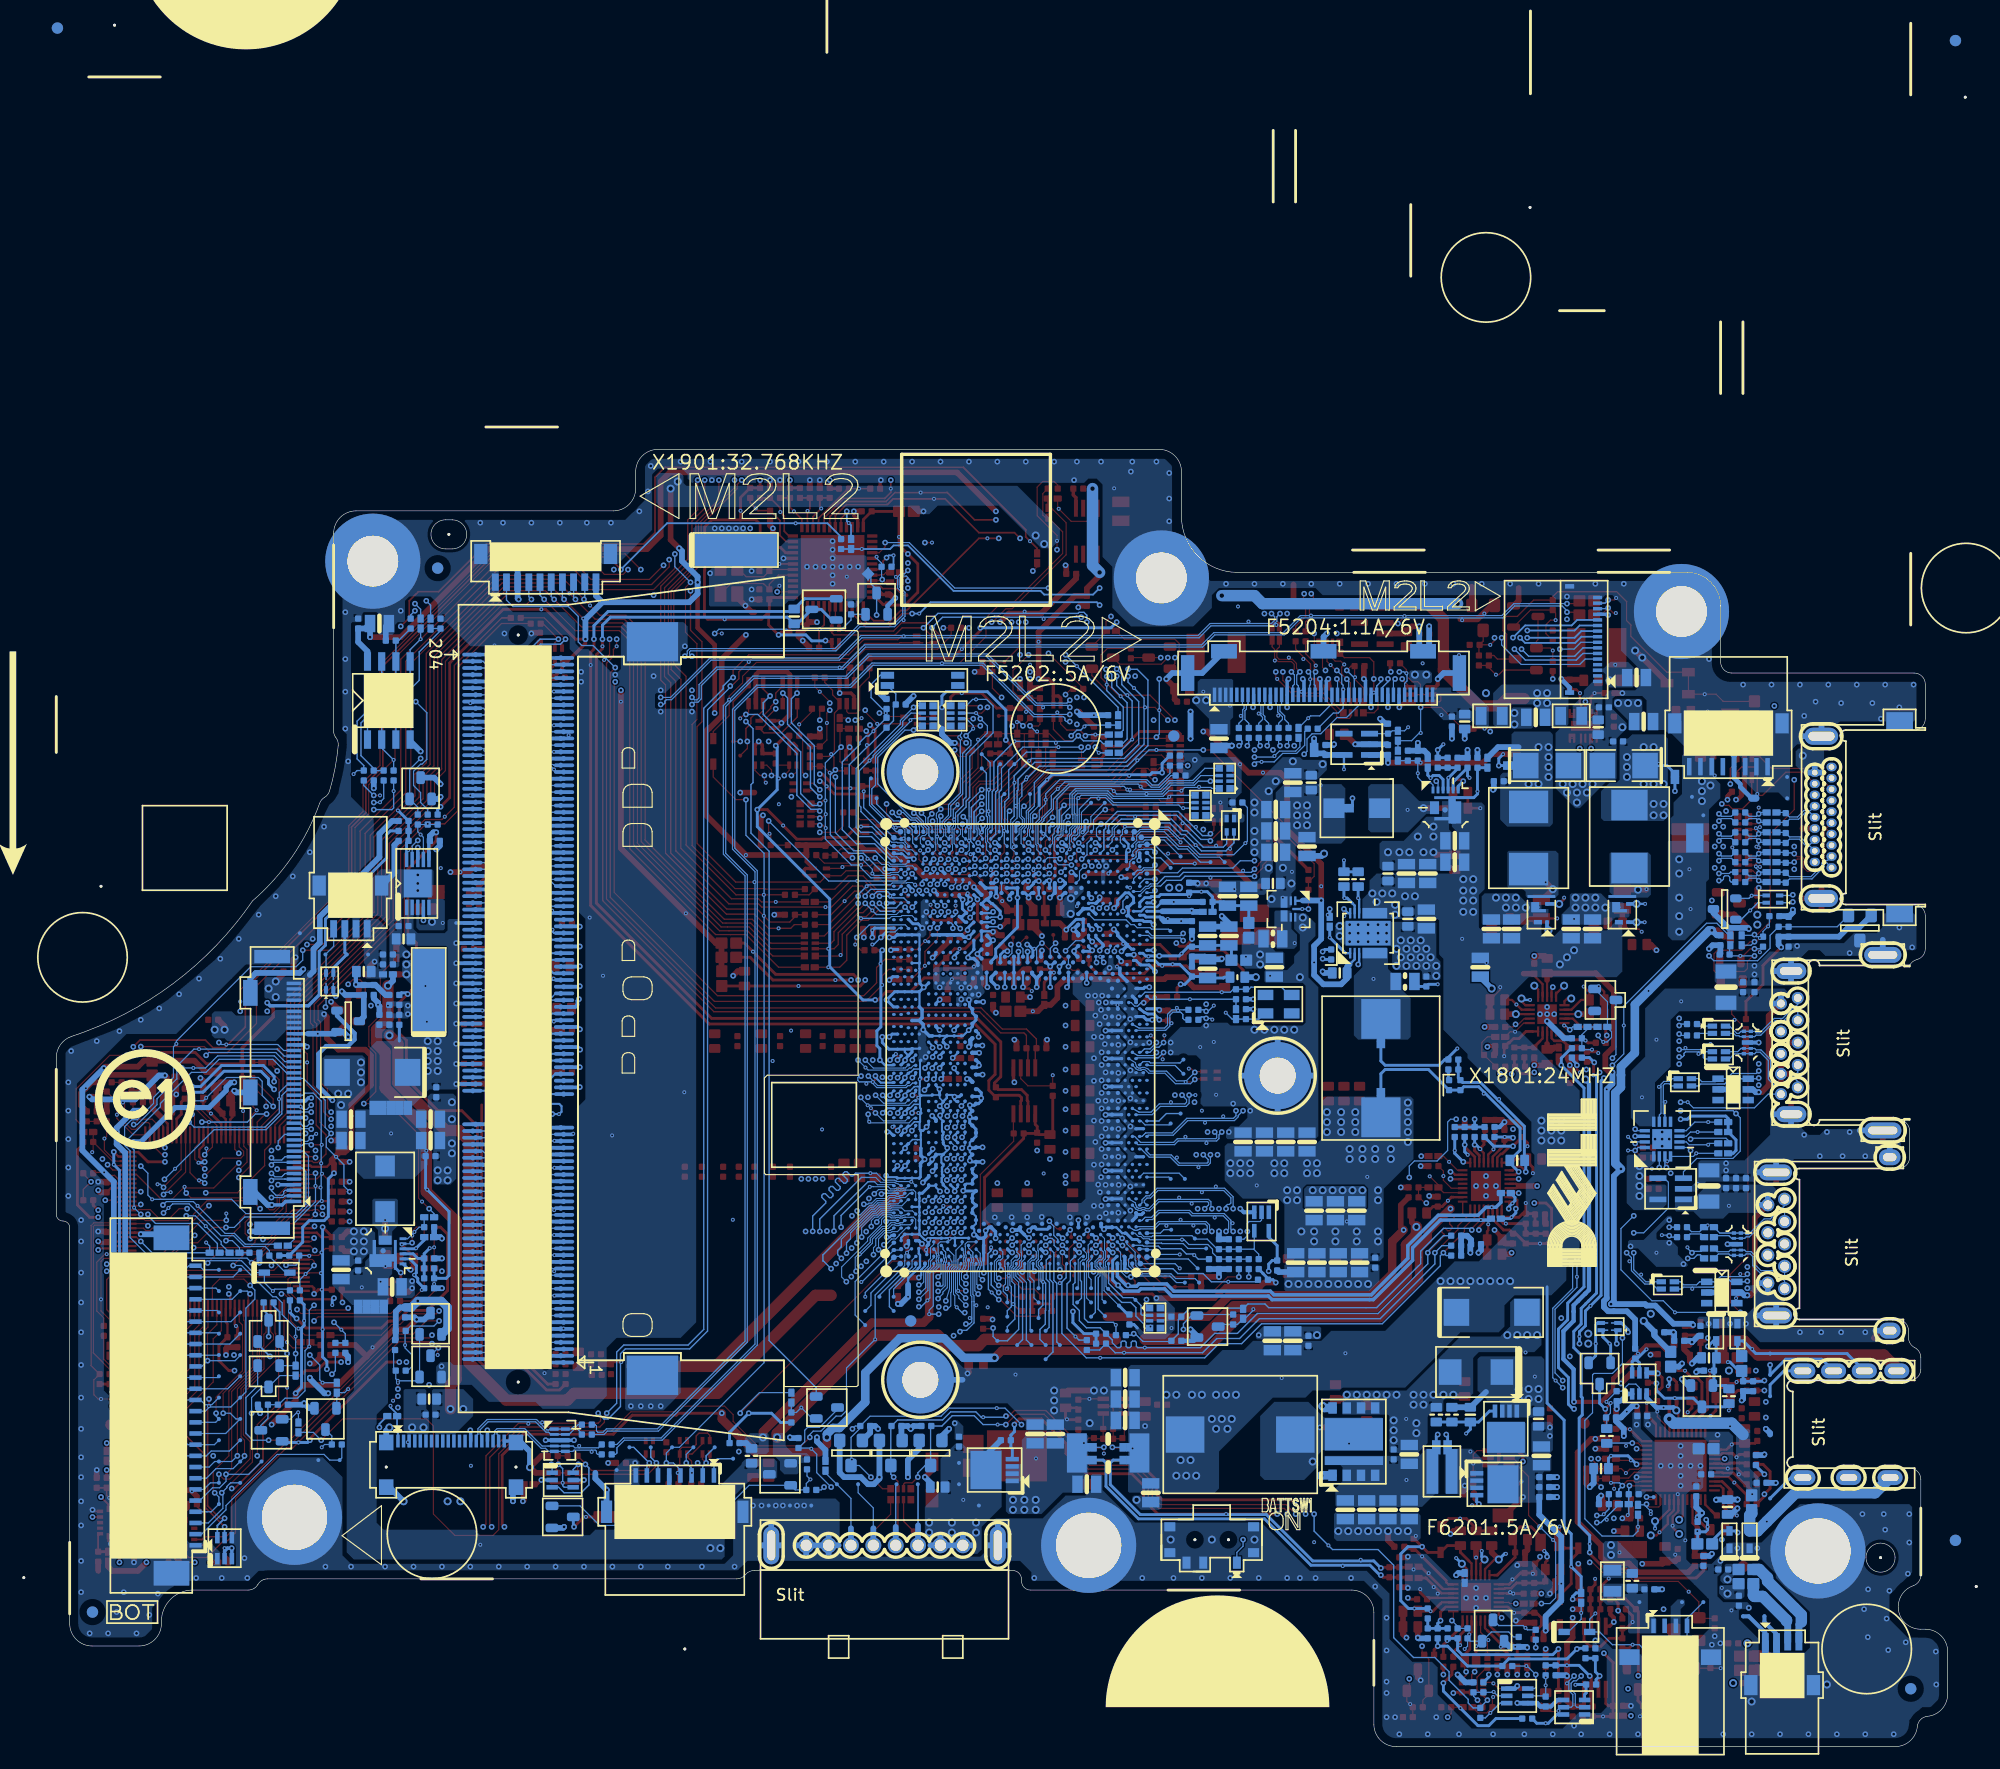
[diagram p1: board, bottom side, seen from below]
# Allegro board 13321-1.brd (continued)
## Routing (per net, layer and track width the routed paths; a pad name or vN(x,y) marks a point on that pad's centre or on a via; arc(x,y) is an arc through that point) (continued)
V3D3_STB: length 8.3
  TOP w0.203: HDA27.20 23.28,29.15 23.2,29.23
  TOP w0.254: R2712.1 24.07,33.62 23.5,33.62 v1(23.49,33.61) 22.86,32.99 22.4,32.99 21.97,32.56 21.97,30.45 23.2,29.23
VBAT: length 14.9
  TOP w0.203: KBC24.102 159.14,55.71 159.54,56.11
  TOP w0.508: 159.54,56.11 160.46,57.04 C2404.1 160.55,57.71 C2405.1 160.53,58.79 R2402.1 160.58,60.06 164.57,60.06 165.04,59.59 R2404.1 165.92,59.4 v1(166.45,58.87) 166.9,58.43 166.9,57.33 R2405.1
VCC_BOOTR1_R: length 2.3
  BOTTOM w0.254: PR4703.2 PC4706.1 v1(53.98,79.25)
VCC_CORE: length 2.9
  TOP w0.203: R702.1 75.17,43.83 75.17,45 74.83,45.33 74.8,45.33 v2(74.64,45.49)
  BOTTOM w0.254: CPU1.F59 74.94,45.79 74.64,45.49 v2(74.64,45.49)
  vias: v1(51.89,50.95) v1(53.72,46.96) v1(61.77,50.18) v1(66.67,56.86) v1(69.85,46.58) v1(74.22,66.31) v2(65.28,52.93) v2(66.17,54.96) v2(67.18,52.93) v2(67.34,57.63) v2(69.09,58.26) v2(74.13,65.24) v2(74.14,62.76) v2(74.14,60.24) v2(74.14,57.75) v2(74.14,55.24) v2(74.14,52.75) v2(74.12,50.23) v2(74.14,47.75) v2(75.31,65.25) v2(75.29,60.29) v2(75.29,57.75) v2(75.29,55.26) v2(75.31,52.75) v2(75.29,50.23) v2(75.26,47.69) v2(75.35,62.82) v2(75.59,67.15) v2(75.64,63.47) v2(75.64,62.09) v2(75.64,60.96) v2(75.64,59.58) v2(75.64,58.45) v2(75.64,57.07) v2(75.64,55.94) v2(75.64,54.56) v2(75.64,53.44) v2(75.64,52.06) v2(75.69,65.88) v2(75.69,50.92) v2(75.67,48.35) v2(75.82,64.61) v2(75.8,49.58) v2(75.82,47.34) v2(75.9,66.54) v2(75.95,57.75) v2(75.95,50.26) v2(76.23,67.15) v2(76.2,65.37) v2(76.2,54.07) v2(76.33,63.47) v2(76.33,61.56) v2(76.33,59.53) v2(76.33,55.97) v2(76.33,52.04) v2(76.33,48.35) v2(76.86,67.15) v2(76.94,47.34) v2(78.48,47.34) v2(80.99,47.37) v2(82.3,47.34) v2(83.68,47.34) v2(85.19,47.33) v3(48.26,57.59) v3(48.26,56.74) v3(48.26,55.85) v3(48.26,54.96) v3(48.26,54.07) v3(49.78,53.43) v3(49.78,52.55) v3(50.93,49.75) v3(50.93,48.86) v3(50.93,46.07) v3(50.93,45.18) v3(51.18,53.43) v3(51.18,52.55) v3(52.32,53.43) v3(52.32,52.55) v3(52.83,46.07) v3(52.83,45.18) v3(52.96,56.74) v3(52.96,55.85) v3(52.96,54.96) v3(53.47,53.43) v3(53.47,52.55) v3(54.23,56.74) v3(54.23,55.85) v3(54.23,54.96) v3(54.74,46.07) v3(54.74,45.18) v3(55.5,56.74) v3(55.5,55.85) v3(55.5,54.96) v3(56.39,52.16) v3(56.39,51.28) v3(56.64,46.07) v3(56.64,45.18) v3(57.28,52.16) v3(57.28,51.28) v3(57.78,46.07) v3(58.17,49.75) v3(58.17,48.86) v3(59.05,49.75) v3(59.05,48.86) v3(59.31,52.16) v3(59.31,51.28) v3(60.2,52.16) v3(60.2,51.28) v3(62.36,52.16) v3(62.36,51.28) v3(63.25,52.16) v3(63.25,51.28) v3(64.14,52.16) v3(64.14,51.28)
VCC_CSN1_R: length 1
  BOTTOM w0.254: PR4706.2 44.64,59.66 PR4707.1
VCC_SENSE: length 43.3
  TOP w0.305: v2(73.28,41.24) 74.61,42.58 R702.2
  BOTTOM w0.305: CPU1.E63 74.23,42.04 73.43,41.24 v2(73.28,41.24) 73.2,41.17 72.52,41.17 72.31,41.37 69.83,41.37 69.18,40.73 60.55,40.73 60.23,40.4 51.52,40.4 48.27,43.66 48.27,44.79 45.54,47.52 41.99,47.52 41.27,48.23 v1(40.77,48.23) 40.38,48.23 39.94,48.67 PR4617.1
VCC_VSW1_GP: length 9.2
  BOTTOM w0.254: PG4707.1 50.67,61.31 50.29,60.93 45.47,60.93 44.96,61.44 PR4704.1 44.64,61.63 v1(43.84,62.43)
VCC_VSW1_R: length 2.3
  BOTTOM w0.254: PR4701.2 47.23,67.98 PC4701.1 46.42,68.17 v1(45.59,68.17)
VSS_SENSE: length 42.7
  TOP w0.305: R901.1 74.36,41.24 v2(74.17,41.24)
  BOTTOM w0.254: CPU1.E62 74.65,43.46 74.65,41.73 v2(74.17,41.24)
  BOTTOM w0.305: v2(74.17,41.24) 73.66,40.73 72.34,40.73 72.13,40.94 70.01,40.94 69.36,40.29 60.73,40.29 60.41,39.97 51.7,39.97 51.34,39.97 47.83,43.48 47.83,44.61 45.36,47.08 v1(41.73,47.08) 40.96,47.08 PR4616.1
0D675V_PWR:
  vias: v1(134.54,73.65) v3(135.51,73.75)
0D675V_S0: length 4.6
  BOTTOM w0.305: v2(125.86,97.38) 125.83,97.35 DIMM1.203 ; v2(129.54,97.38) 130.05,97.38 130.32,97.65 DIMM1.204
  vias: v1(129.92,98.47) v1(132.08,93.31) v1(132.08,85.06) v1(134.72,78.56)
1D05S_VCCST: length 97.9
  TOP w0.254: 80.07,39.59 R1917.2 ; 80.07,39.59 81.85,39.59 ; 80.07,39.59 R1916.2 79.84,40.46 73.84,40.46 73.82,40.48 71.12,40.48 v2(70.74,40.1) ; 81.85,39.59 R1919.2 ; 81.85,39.59 R1918.2
  TOP w0.508: v2(70.74,40.1) 65.55,40.1 64.53,41.12 61.47,41.12 61.09,41.5 v2(60.07,41.5)
  L3 w0.508: v2(60.07,41.5) 59.44,42.13 50.93,42.13 50.29,42.77 44.07,42.77 v2(42.67,44.16)
  L4 w0.508: v2(84.29,67.91) 84.29,51.49 81.66,48.85 81.66,46.59 81.48,46.41 81.48,43.73 80.77,43.02 80.77,41.47 v2(78.21,38.91) 76.25,38.91 74.55,40.61 71.25,40.61 v2(70.74,40.1)
  BOTTOM w0.203: CPU1.AC22 v2(84.29,67.91)
  BOTTOM w0.254: v2(78.21,38.91) 78.21,37.92 77.22,36.92 R704.1 R703.1 ; R706.1 61.21,42.32 61.21,42.3 60.77,41.86 R2018.1 60.33,41.75 v2(60.07,41.5) ; R705.1 72.76,37.75 72.44,37.43
  BOTTOM w0.305: v2(84.96,67.91) 85.51,68.46 CPU1.AE23 85.51,68.8 CPU1.AE22
  BOTTOM w0.508: v2(42.67,44.16) 42.67,44.86 PC4605.1 42.61,45.33 42.96,45.69 PR4621.2 PR4623.2 PR4622.2
  vias: v1(69.39,37.43)
1D05V_HSIO:
  vias: v1(62.74,70.63) v3(61.47,70.83) v3(61.47,69.94)
1D5V_PWR: length 4
  BOTTOM w0.203: v1(53.98,87.39) PU5101.5
  BOTTOM w0.508: PG5101.1 55.77,88.82 PC5109.1 55.62,88.68 PU5101.5
1D05V_PWR_BS: length 3.1
  TOP w0.254: PR4801.1 44.22,86.4 v1(44.17,86.45) 43.43,86.45 v2(43.31,86.33)
  BOTTOM w0.254: PU4801.6 43.76,85.87 v2(43.31,86.33)
1D05V_PWR_BS_R: length 2.5
  TOP w0.254: v1(41.78,83.91) PC4806.1 PR4801.2
1D05V_PWR_BYP: length 5.2
  BOTTOM w0.254: PU4801.7 42.37,84.86 42.04,85.18 v1(42.04,85.41) PC4807.1 PR4807.1
1D05V_PWR_FB: length 4.1
  BOTTOM w0.254: PC4802.2 PR4806.2 PR4805.1 43.81,87.45 v1(44.63,86.63) 44.66,86.6 PU4801.4
1D05V_PWR_FBH: length 14.3
  L4 w0.254: v2(53.21,84.8) 53.21,87.6 51.69,89.12 v2(45.59,89.12)
  BOTTOM w0.254: v1(45.09,89.63) v2(45.59,89.12) PC4802.1 PR4806.1 ; PG4801.1 53.21,84.12 v2(53.21,84.8)
1D05V_PWR_LDO: length 3.5
  BOTTOM w0.254: PU4801.5 44.21,86.25 PC4809.1 42.93,86.81 v1(42.75,86.63)
1D05V_PWR_PH: length 2.6
  TOP w0.508: PC4806.2 v3(46.86,83.91)
  vias: v1(48.29,83.76)
1D5V_S0: length 144.3
  TOP w0.254: v2(32,17.37) 32,17.25 30.65,15.89 28.71,15.89 27.9,15.08 22.48,15.08 21.79,15.77 R2705.1
  L3 w0.381: 75.61,72.44 75.98,72.44 76.5,72.97 v2(76.5,73.08)
  L3 w0.508: v2(56.64,90.14) 56.41,89.91 56.41,88.93 58.22,87.12 60.43,87.12 64.9,82.64 66.81,82.64 67.69,81.77 67.69,76.29 69.85,74.14 71.46,74.14 73.15,72.44 75.61,72.44
  L4 w0.254: v2(56.64,90.14) 56.52,90.01 56.52,78.96 56.13,78.58 46.77,78.58 45.21,77.02 45.21,73.95 43.81,72.55 43.81,61.64 40.21,58.03 32.93,58.03 31.62,59.34 31.62,59.79 v2(31.12,60.29)
  BOTTOM w0.254: v2(32,17.37) v1(32,18.13) 32,18.89 32.94,19.83 32.94,29.38 32.66,29.66 32.66,31.2 32.77,31.3 32.77,35.02 33.43,35.68 33.43,37.13 32.77,37.79 32.77,39.18 32.37,39.58 32.37,39.59 32.11,39.84 32.11,39.84 31.39,40.56 31.39,60.01 v2(31.12,60.29) ; CPU1.J15 76.81,73.42 76.5,73.12 v2(76.5,73.08)
  BOTTOM w0.508: PG5101.2 v2(56.64,90.14)
1D05V_S0: length 250.2
  TOP w0.254: R2117.1 67.75,71.21 64.76,71.21 62.99,69.45 62.99,68.8 ; R2401.1 v2(142.88,47.85)
  TOP w0.508: R711.1 v1(81.79,65.75) 81.34,65.75 R2118.1 80.2,66.33 79.6,66.93 79.6,67.98 79.02,68.55 77.62,68.55 77.24,68.93 76.58,68.93 76.28,68.62 70.03,68.62 69.85,68.8 68.32,68.8 67.4,67.89 L1103.1 ; C2135.1 84.89,72.55 85.21,72.87 v2(85.34,72.87) 85.47,72.74 85.61,72.74 85.98,72.37 85.98,71.84 85.85,71.71 R1102.1 ; R2105.1 70.6,78.2 69.71,79.09 64.26,79.09 62.1,76.93 60.96,76.93 ; R1104.1 81.76,73.27 v2(80.98,72.48)
  L4 w0.254: v2(32.92,36.04) 33.53,36.04 34.16,35.4 67.31,35.4 71.12,39.21 75.01,39.21 78.44,35.78 82.8,35.78 89.53,29.05 109.46,29.05 110.1,28.42 121.27,28.42 121.78,28.92 128.36,28.92 134.43,34.99 134.43,36.73 135.38,37.69 138.56,37.69 143.64,42.77 143.64,47.08 v2(142.88,47.85) ; v3(59.44,78.58) 57.78,78.58 57.4,78.2 46.93,78.2 45.59,76.87 45.59,73.79 44.2,72.39 44.2,61.34 40.5,57.65 32.64,57.65 30.99,59.31 30.99,59.53 v2(30.73,59.78)
  BOTTOM w0.203: v2(85.34,72.87) 85.39,72.91 CPU1.AG16 CPU1.AG17 ; v2(85.34,73.75) 85.38,73.72 CPU1.AG14 ; CPU1.AG13 85.45,74.54 v2(85.34,74.64)
  BOTTOM w0.254: v2(30.73,59.78) 30.99,59.53 30.99,40.35 v1(31.93,39.41) 32.38,38.96 32.38,37.63 32.92,37.1 v1(32.92,36.67) v2(32.92,36.04)
  BOTTOM w0.508: v3(61.85,68.8) L1104.1
  vias: v1(58.62,78.23) v1(59.44,75.91) v1(60.58,68.93) v3(57.28,84.17) v3(57.28,83.28) v3(57.28,82.39) v3(58.17,84.17) v3(58.17,83.28) v3(58.17,82.39) v3(58.67,77.18) v3(60.45,75.79)
1D05V_VTT_PWRGD: length 199.6
  TOP w0.102: v2(146.05,38.07) 145.69,38.43 139.39,38.43 138.76,38.43 137.78,39.41 136.6,39.41 135.32,40.7 v1(135.32,41.37) R3611.1
  L3 w0.102: 78.11,40.62 79.01,39.72 79.01,36.52 89.26,26.27 97.27,26.27 99.15,24.39 107.73,24.39 108.15,23.97 121.03,23.97 121.67,23.34 125.98,23.34 126.16,23.52 126.45,23.81 128.67,23.81 131.38,26.51 134.3,26.51 134.3,26.51 141.11,26.51 145.92,31.32 145.92,37.94 v2(146.05,38.07) ; 78.11,40.62 77.03,39.54 69.14,39.54 65.79,42.89 64.52,42.89 62.61,44.8 v2(62.61,46.07) ; 78.11,40.62 78.11,45.18 78.99,46.07 78.99,48.23 77.47,49.75 77.47,67.18 76.73,67.91 73.41,67.91 71.42,69.89 71.42,71.44 71.15,71.72 69.67,71.72 69.29,71.34 66.83,71.34 61.34,76.83 61.34,83.28 55.63,88.99 48.39,88.99 v2(45.72,86.33)
  BOTTOM w0.102: PU4801.2 45.56,86.17 v2(45.72,86.33) ; U701.2 61.34,47.08 61.47,46.96 62.45,46.96 62.61,46.79 v2(62.61,46.07) 62.61,45.69 62.93,45.37 R707.1
1D35V_S3: length 135.2
  TOP w0.254: 131.06,57.37 131.06,34.8 130.7,34.44 127.18,34.44 125.16,32.42 R3701.1 ; R410.1 v2(95.25,71.21) ; v2(138.43,34.38) 139.57,34.38 146.43,27.53 v2(146.43,27.4)
  L3 w0.254: v3(135.89,60.42) 135.89,50.01 136.58,49.32 136.58,40.4 136.27,40.1 136.27,37.56 138.43,35.4 v2(138.43,34.38)
  L3 w0.508: v2(134.75,86.07) 133.22,84.55 133.22,71.98 v2(133.35,71.85)
  BOTTOM w0.203: CPU1.AY35 94.34,60.96 94.37,60.93 95.01,60.93 v2(95.47,61.39) ; v2(95.22,58.24) 94.75,57.78 94.25,57.78 CPU1.AY40
  BOTTOM w0.254: CPU1.AH26 v2(86.23,66.59) ; v2(94.82,54.98) 94.61,54.98 94.29,54.67 CPU1.AY44 ; v2(93.9,51.94) 93.9,51.9 94.21,51.58 CPU1.AY50 ; CPU1.AN33 90.1,61.79 v2(90.1,61.66) ; v2(90.75,53.45) 90.75,53.31 CPU1.AR48 ; v2(95.47,61.39) 95.47,62.41 95.73,62.68 95.73,64 95.38,64.36 95.38,71.09 v2(95.25,71.21) ; Q1201.G 148.8,27.2 v1(147.45,27.2) 146.63,27.2 v2(146.43,27.4) ; R3706.1 138.43,63.09
  BOTTOM w0.305: v2(90.79,56.4) 90.45,56.07 CPU1.AP43
  BOTTOM w0.33: DIMM1.81 122.3,60.75 v2(122.29,60.76) ; v2(122.37,66.84) 122.37,66.83 122.51,66.69 122.51,66.33 122.69,66.15 DIMM1.99 ; DIMM1.87 122.49,62.55 v2(122.26,62.32) ; DIMM1.93 122.49,64.35 v2(122.28,64.14) ; v2(122.29,73.33) 122.32,73.35 DIMM1.123 ; v2(133.35,64.65) DIMM1.94 ; v2(133.35,59.25) DIMM1.76 ; v2(133.35,66.45) DIMM1.100 ; v2(133.35,71.85) DIMM1.118 ; DIMM1.105 122.34,67.95 v2(122.29,67.99) ; v2(122.29,69.77) 122.32,69.75 DIMM1.111 ; DIMM1.106 v2(133.35,68.25) ; DIMM1.112 v2(133.35,70.05) ; DIMM1.124 133.35,73.65 ; v2(122.29,58.98) 122.32,58.95 DIMM1.75 ; DIMM1.117 v2(122.29,71.55) ; v2(133.35,62.85) DIMM1.88 ; v2(133.35,61.05) DIMM1.82
  BOTTOM w0.381: v2(87.5,62.58) 87.38,62.71 87.38,63.17 CPU1.AJ31 ; v2(87.68,59.71) 87.47,59.71 CPU1.AJ37 ; v2(86.59,62.04) CPU1.AJ33
  BOTTOM w0.508: v2(134.75,86.07) 135.32,86.65 Q1202.D
  vias: v1(100.63,55.19) v1(105.05,61.31) v1(112.95,58.51) v1(119.41,54.65) v1(120.22,68.93) v1(135.97,64.81) v3(135,63.09) v3(135,62.2) v3(135,61.31) v3(135,60.42) v3(135.89,63.09) v3(135.89,62.2) v3(135.89,61.31)
1D35V_VTT_PWRGD: length 1.9
  TOP w0.102: PR4907.1 v1(135.32,44.65) R3610.1
3D3V_AUX_KBC: length 376.9
  TOP w0.254: R2418.2 R2414.2 164.08,32.16 v2(164.08,31.72) ; R2413.2 162.37,34.64 162.49,34.76 162.49,34.77 ; v2(96.35,91.35) 95.89,90.89 R2608.1 ; 162.49,34.77 RN2401.3 ; 162.49,34.77 162.94,34.77 163.14,34.96 RN2401.4 ; PR4414.1 PR4432.1 44.13,4.86 v2(44.2,4.79)
  TOP w0.305: R2436.1 v2(142.88,46.96)
  TOP w0.508: v2(136.88,38.19) 137.76,37.31 138.93,37.31 141.35,34.89 ; 141.35,34.89 142.37,35.91 R2454.2 ; 141.35,34.89 143.89,32.35 146.94,32.35 v2(147.7,31.59) 147.7,30.94 v2(149.85,28.8) ; v2(162.56,32.48) 162.37,32.67 R2413.2 ; R2403.2 155.73,60.32 156.74,61.33 R2402.2 161.26,61.33 161.8,60.8 164.72,60.8 v2(164.85,60.67)
  L3 w0.254: v2(96.35,91.35) 98.55,93.55 98.55,94.41 98.85,94.71 98.89,94.71 103.78,99.6 103.78,104.56 106.48,107.26 111.73,107.26 114.88,104.11 128.17,104.11 135.76,96.51 135.76,91.69 137.87,89.58 137.87,82.2 138.53,81.54 138.53,74.35 139.57,73.3 139.57,69.5 140.67,68.41 140.67,67.57 141.44,66.8 141.66,66.57 142.24,66.57 145.7,63.11 149.36,63.11 151.73,60.74 151.73,48.31 152.29,47.75 152.29,38.08 149.48,35.27 149.48,33.37 v2(147.7,31.59)
  L4 w0.254: 91.95,23.46 88.9,23.46 88.37,24 80.11,24 79.04,22.93 74.3,22.93 71.65,20.29 62.23,20.29 59.72,17.77 49.81,17.77 46.48,14.45 46.48,6.36 44.91,4.79 v2(44.2,4.79) ; v2(142.88,46.96) 143.26,46.58 143.26,42.92 138.53,38.19 v2(136.88,38.19)
  L4 w0.508: v2(162.56,32.48) 158.88,28.8 v2(149.85,28.8) 143.64,28.8 141.41,26.57 135.15,26.57 132.1,23.53 126.86,23.53 125.59,22.26 116.4,22.26 115.19,23.46 101.94,23.46 101.3,24.1 98.04,24.1 97.41,23.46 95.63,23.46
  BOTTOM w0.254: R2452.1 146.94,39.53 v1(146.94,38.07) 146.94,37.66 147.17,37.43 147.17,32.12 v2(147.7,31.59)
  BOTTOM w0.508: v2(164.85,60.67) 166.77,58.75 166.77,53.33 163.96,50.51 163.96,40.99 162.81,39.85 162.81,32.73 v2(162.56,32.48) 163.32,31.72 v2(164.08,31.72) ; D4302.2 99.06,24.5 98.66,24.1 97.16,24.1 96.53,23.46 96,23.46 95.5,23.96 v2(95.5,24.1) D4303.2 ; R2434.1 137.07,38.39 v2(136.88,38.19) 136.21,38.19 Q2402.D ; D4301.2 91.95,26.64 92.96,25.62 v2(92.96,24.1)
3D3V_AUX_KBC_VCC: length 87.6
  TOP w0.203: KBC24.88 164.2,49.96 C2406.1 ; C2410.1 153.8,37.81 153.94,37.96 KBC24.46 ; C2408.1 154.24,56.4 153.94,56.1 KBC24.115 ; KBC24.76 164.55,45.16 C2407.1 ; KBC24.19 145.81,45.96 145.41,45.56 C2409.1
  TOP w0.254: C2410.1 154.05,36.35 154.06,36.35 154.56,35.85 154.56,34.51 153.67,33.62 v2(153.16,33.62) ; C2409.1 144.46,45.62 v2(145.29,46.45)
  TOP w0.356: C2407.1 164.66,45.05 165.23,45.05 v2(165.35,45.18)
  TOP w0.508: C2408.1 154.84,57.21 C2411.1 154.81,57.78 R2403.1 154.41,59.4 v2(153.18,59.4) ; v2(165.35,49.75) 165.16,49.56 C2406.1
  L3 w0.254: v2(153.16,33.62) 156.08,33.62 156.46,34 159.98,34 160.53,34.56 160.53,34.98 162.94,37.39 162.94,43.66 164.47,45.18
  L3 w0.508: 164.34,49.75 162.94,51.15 162.94,53.31 v2(162.18,54.07) ; 164.34,49.75 v2(165.35,49.75) ; 164.34,49.75 164.08,49.5 164.08,45.56 164.47,45.18 v2(165.35,45.18)
  L4 w0.254: v2(153.16,33.62) 145.03,33.62 v2(144.91,33.75)
  BOTTOM w0.254: v2(145.29,46.45) v1(145.29,37.31) 145.29,34.84 144.91,34.46 v2(144.91,33.75)
  BOTTOM w0.457: v2(153.18,59.4) 153.2,59.38 153.49,59.38 153.92,58.95 153.92,58.67 155.44,57.14 158.47,57.14 161.54,54.07 v2(162.18,54.07)
3D3V_AUX_S5: length 491.1
  TOP w0.203: v2(165.35,44.42) 165.23,44.54 164.34,44.54 164.12,44.76 KBC24.75
  TOP w0.254: R2425.2 166.69,53.88 167.21,53.36 167.21,48.43 166.12,47.34 v2(165.35,47.34) ; R2439.1 45.91,8.67 v2(45.59,8.98) ; R2451.2 147.26,33.18 146.81,33.62 145.8,33.62 145.03,34.38 v2(143.64,34.38) ; v2(129.03,19.65) 129.24,19.86 129.24,26.06 127.35,27.94 119.3,27.94 117.6,29.64 113.67,29.64 113.49,29.81 v2(109.6,29.81) ; R1726.2 97.22,96.74 96.65,97.31 R1727.1 88.96,97.31 v1(88.14,98.14) 86.49,99.79 v2(86.49,100.04) ; R3607.1 49.85,96.17 v2(49.78,96.11)
  TOP w0.508: v2(34.54,60.93) 34.77,61.16 PR4532.1
  TOP w0.762: v3(100.2,27.65) 100.2,27.02 100.89,26.33 106.63,26.33 109.6,29.3 v2(109.6,29.81) ; v2(44.45,48.1) 46.48,46.07 46.48,45.31 47.26,44.53 47.26,41.82 47.97,41.11 50.76,38.32 63.37,38.32 66.29,35.4 84.58,35.4 v3(85.22,34.77)
  L3 w0.254: v2(165.35,47.34) 165.86,46.83 165.86,44.67 165.61,44.42 v2(165.35,44.42) 165.86,43.91 165.86,38.87 160.61,33.62 156.62,33.62 156.24,33.24 154.56,33.24 152.65,31.34 152.65,29.56 151,27.91 149.1,27.91 140.34,19.14 129.54,19.14 v2(129.03,19.65) ; v2(49.78,96.11) 49.23,96.67 33.89,96.67 31.04,93.81 31.04,92.25 30.59,91.8 28.64,91.8 27.43,90.6 25.69,90.6 22.18,87.09 21.29,87.09 20.45,86.24 20.45,85.18 22.15,83.48 22.15,71.17 22.15,70.12 29.69,62.58 33.02,62.58 34.54,61.05 v2(34.54,60.93) ; v2(136.78,39.85) 136.78,39.21 140.97,35.02 143.09,35.02 143.51,34.6 143.51,34.51 v2(143.64,34.38)
  L3 w0.381: v2(144.41,57.8) 145.1,57.11 145.1,53.96 143.7,52.56 143.7,41.31 142.24,39.85 v2(136.78,39.85)
  L3 w0.762: v2(34.54,60.93) 34.54,60.04 32.26,57.75 32.26,53.56 34.42,51.4 36.64,51.4 37.47,50.58 37.47,49.31 37.72,49.06 37.72,47.91 38.29,47.34 39.56,47.34 40.32,48.1 v2(44.45,48.1)
  L4 w0.254: v2(33.15,8.73) 34.04,9.62 34.04,19.21 34.04,19.53 35.43,20.92 35.43,24.7 34.67,25.46 34.67,28.92 v2(33.4,30.19) ; v2(49.78,96.11) 51.46,97.78 58.27,97.78 59.39,98.9 72.64,98.9 v2(74.3,100.55)
  L4 w0.762: v2(109.6,29.81) 110.36,29.05 121.01,29.05 121.52,29.56 128.1,29.56 133.79,35.25 133.79,39.15 134.49,39.85 v2(136.78,39.85)
  BOTTOM w0.254: v2(33.4,30.19) 33.53,30.32 33.61,30.32 33.91,30.62 33.91,33.01 34.8,33.9 34.8,37.34 33.97,38.16 33.97,39.66 32.51,41.12 32.51,58.9 v2(34.54,60.93) 34.54,61.56 33.66,62.45 PR4501.1 ; PR4468.1 v2(45.59,8.98) 44.7,8.98 42.93,7.21 PR4412.1 39.81,7.27 39.24,7.84 34.04,7.84 v2(33.15,8.73) 33.08,8.79 PR4428.1 ; v2(74.3,100.55) 74.8,100.04 v2(86.49,100.04)
  BOTTOM w0.381: D2501.1 144,65.36 142.43,63.79 142.43,63.23 143.02,62.64 144.97,62.64 145.67,61.94 145.67,59.05 v2(144.41,57.8)
  BOTTOM w0.508: R2434.2 138.37,39.27 138.75,38.89 R2431.2 138.75,36.42 C2417.2
  BOTTOM w0.762: v3(85.22,34.77) 87.97,34.77 89.72,36.52 93.68,36.52 96.77,33.42 96.77,30.8 99.08,28.49 99.66,28.49 100.2,27.95 v3(100.2,27.65) ; R2434.2 137.35,39.27 v2(136.78,39.85) 134.69,39.85 134.11,39.27 134.11,37.4 Q2402.S
3D3V_CAMERA_S0:
  vias: v1(45.26,92.25)
3D3V_GSEN2: length 19.3
  TOP w0.152: C6611.1 163.46,17.38 U6602.14 ; C6610.1 165.35,18.86 U6602.1
  TOP w0.254: v2(163.45,16.48) 163.47,16.5 C6611.1 163.54,17.43 R6622.1 C6610.1 ; v2(164.59,24.73) R6626.1 R6623.1 163.28,24.03 v1(162.69,23.44)
  L4 w0.254: v2(163.45,16.48) 163.32,16.48 161.42,18.38 161.42,21.56 v2(164.59,24.73)
3D3V_MCU: length 86.6
  TOP w0.254: TP6603.1 105.41,100.3 v2(104.52,99.41) 104.27,99.66 C6608.1 103.57,100.23 103.25,100.55 C6605.1 102.45,100.79 U6601.48 ; TP6603.1 105.35,101.5 C6604.1 105.18,102.75 U6601.1 ; TP6603.1 106.05,100.81 v1(109.35,100.81) 110.87,100.81 111.15,101.09 111.15,105.13 111.12,105.16 111.12,109.06 110.49,109.7 107.92,109.7 ; R6610.2 99.89,112.49 R6612.2 v2(99.95,113.25) ; 107.92,109.7 v1(107.92,110.51) 107.92,111.69 R6620.2 R6618.2 v2(106.17,113.25) ; 107.92,109.7 106.55,109.7 106.17,109.31 R6602.2 105.92,108.11 C6603.1 104.35,107.22 103.89,106.75 U6601.9 ; v2(100.33,98.9) 100.24,98.81 RN6601.2 99.77,98.34 99.58,98.16 99.3,98.16 99.12,98.34 RN6601.1 ; U6601.36 95.8,102.75 95.19,102.14 C6607.1 94.57,102.14 94.51,102.08 93.22,102.08 92.08,103.22 92.08,105.76 v2(92.96,106.65) 93.75,107.44 v1(93.75,108.17) R6607.2 C6606.1 96.94,109.72 U6601.24 ; v2(103.5,113.25) R6616.2 R6614.2
  L3 w0.254: v2(100.33,98.9) 98.68,100.55 94.23,100.55 92.46,102.33 92.46,106.14 v2(92.96,106.65)
  L4 w0.254: v2(106.17,113.25) 105.66,113.76 104.01,113.76 v2(103.5,113.25) 103,113.76 100.46,113.76 v2(99.95,113.25)
  BOTTOM w0.254: v2(100.33,98.9) 100.36,98.88 101.55,98.88 102.08,99.41 v2(104.52,99.41)
3D3V_PWR_2: length 2.7
  TOP w0.203: 35.81,62.83 PU4503.3
  TOP w0.508: 35.81,62.83 PC4526.1 35.34,62.35 35.18,62.52 PR4532.2
3D3V_RUN_FFS: length 23
  TOP w0.152: C6701.1 156.53,21.49 155.83,20.8 155.83,20.16 155.97,20.02 U6701.1 ; C6702.1 158.49,16.79 U6701.8 ; C6702.1 157.99,16.67 U6701.7 ; C6702.1 v2(156.72,16.48) ; C6703.1 158.49,21.58 U6701.14
  TOP w0.508: v2(159.77,22.83) 159.66,22.93 R6702.1 ; C6701.1 156.53,22.38 v1(156.97,22.83) 157.07,22.93 R6702.1 ; C6703.1 158.6,22.9 R6702.1
  L3 w0.508: v2(159.77,22.83) 158.24,22.83 156.21,20.8 156.21,16.99 v2(156.72,16.48)
3D3V_S0: length 533
  TOP w0.203: C2412.1 144.91,51.85 146.27,51.85 146.38,51.96 KBC24.4
  TOP w0.254: R2603.1 80.01,54.98 C2601.1 81.24,54.73 C2602.1 ; 75.75,88.3 75.64,88.19 75.64,87.79 75.78,87.65 RN1801.2 ; 75.75,88.3 75.44,88.61 R1701.1 73.6,89.44 72.26,90.77 68.83,90.77 68.6,90.54 RN2002.1 ; 75.75,88.3 RN1801.1 ; THM261.1 81.57,55.63 81.39,55.45 81.39,54.91 C2602.1 ; R3601.1 139.19,39.91 PR4902.2 143.38,40.67 R2415.2 143.57,39.78 v2(143.51,39.72) ; RN2602.1 104.47,91.73 v2(104.27,91.53) 104.27,91.41 104.59,91.08 RN2602.2 ; 86.19,43.36 85.98,43.58 85.98,45.43 85.47,45.94 85.47,46.45 86.11,47.08 86.11,50.9 82.61,54.39 R2604.1 81.47,54.83 C2602.1 ; v2(121.79,99.03) 122.68,99.03 125.35,101.69 v1(125.73,101.69) 129.12,101.69 133.93,96.89 133.93,84.86 v2(134.75,84.04) ; v2(96.68,90.81) 96.52,90.65 96.52,88.35 R2609.1
  TOP w0.305: R2007.2 59.97,81.21 RN1501.2 ; C1203.1 124.52,95.73 123.88,96.37 RN1810.1 123.41,97.03 121.79,98.65 v2(121.79,99.03) ; v2(125.22,96.11) 124.53,96.8 RN1810.2
  TOP w0.406: Q1801.2 Q1801.5 106.55,95.85 106.3,96.11 103.76,96.11 103.5,95.85 Q2601.5 Q2601.2 103.5,92.3 v2(104.27,91.53) ; v2(110.24,92.42) 110.24,98.52 111.76,100.04 v2(111.76,104.11) ; v2(18.16,89.5) Q5402.2 ; Q5402.5 18.16,85.63 EC8608.1 18.4,85.07 18.8,84.68 v2(18.92,84.68)
  TOP w0.508: v2(145.16,65.5) 144.91,65.25 144.91,63.34 143.89,62.32 141.48,62.32 140.97,61.82 140.97,59.15 142.72,57.4 v1(142.72,56.41) 142.72,53.71 143.15,53.28 C2413.1 144.46,52.46 C2412.1 144.27,52.1 v2(144.27,51.28) ; R2446.2 160.15,34.89 v2(160.02,34.77) 160.02,34.12 160.6,33.54 160.6,28.37 158.64,26.4 v2(158.64,25.1) 158.62,25.08 R6702.2 ; C2128.1 78.93,72.91 v2(78.8,73.04) 79.38,73.63 R2112.1 ; R6701.1 v2(155.32,16.48) ; v2(161.04,16.48) 161.8,15.72 164.08,15.72 164.47,16.1 R6622.2 ; v2(48.64,46.2) 48.9,46.45 48.9,48.42 PR4614.1 ; v2(22.76,37.71) 22.85,37.62 R2916.1 ; R6607.1 v2(91.57,110.46) ; Q5401.C 20.02,72.43 20.57,72.99 v2(21.08,72.99) ; v3(114.17,112.49) 114.17,107.92 v2(113.41,107.16) ; v3(154.05,64.1) 154.05,64.42 EC8613.1 ; R2701.1 v2(31.5,27.53) 31.85,27.53 33.08,26.3 33.08,20.1 30.99,18 30.99,16.96 30.43,16.4 28.5,16.4 27.69,15.59 23.18,15.59 R2710.1 ; C1203.1 124.71,95.6 v2(125.22,96.11)
  TOP w0.762: v3(105.92,27.65) 105.92,28.16 96.17,37.91 91.57,37.91 91.06,38.42 91.06,42.34 90.61,42.78 88.09,42.78 87.5,43.36 86.19,43.36 ; v2(48.64,46.2) 49.66,45.18 49.66,42.3 51.6,40.35 64.22,40.35 66.12,38.45 75.18,38.45
  TOP w1.016: 37.87,93.72 39.37,93.72 40.03,93.06 41.91,93.06 45.09,96.23 45.09,100.81 46.35,102.08 51.44,102.08
  L3 w0.254: v2(143.51,39.72) 143.51,40.35 144.27,41.12 v2(144.27,51.28) ; v2(78.8,73.04) 78.67,72.92 78.67,72.83 77.22,71.38 77.22,70.52 75.83,69.13 73.88,69.13 73.27,69.74 73.27,71.29 71.56,72.99 69.87,72.99 66.19,76.68 66.08,76.68 65.79,76.97 65.79,78.2 66.87,79.28 66.87,81.31 66.55,81.62 v2(66.55,82.01)
  L3 w0.508: v2(161.04,16.48) 160.4,15.84 155.95,15.84 v2(155.32,16.48) 154.94,16.86 154.94,20.67 158.64,24.37 v2(158.64,25.1) ; v2(30.1,39.57) 30.1,36.54 30.23,36.42 30.23,35.53 31.08,34.68 31.08,31.81 31.85,31.03 31.85,27.88 v2(31.5,27.53)
  L3 w0.762: v2(29.21,51.66) 29.89,51.66 36.62,44.93 47.45,44.93 48.64,46.11 v2(48.64,46.2) ; v2(21.08,72.99) 21.08,74.58 20.32,75.34 20.32,76.42 19.3,77.44 19.3,83.09 18.92,83.47 v2(18.92,84.68)
  L4 w0.254: v2(67.31,88.23) 67.31,85.82 66.55,85.06 v2(66.55,82.01) ; v2(104.27,91.53) 104.27,91.15 103.63,90.52 96.97,90.52 v2(96.68,90.81)
  L4 w0.508: v2(104.27,91.53) 105.54,91.53 106.05,91.03 108.84,91.03 v2(110.24,92.42) ; v2(160.02,34.77) 160.02,34.89 160.32,35.19 160.32,38.78 159.64,39.46 159.64,45.38 160.27,46.02 160.27,57.38 157.24,60.42 157.24,61.66 154.94,63.96 v3(154.94,64.1)
  L4 w0.762: v2(18.92,84.68) 18.16,85.44 v2(18.16,89.5) 18.26,89.4 24.66,89.4 25.53,90.26 32.77,90.26 v3(35.81,93.31)
  BOTTOM w0.254: PR4909.1 135,83.79 v2(134.75,84.04) ; R2443.2 R2448.2 147.07,45.12 147.07,46.45 146.48,47.03 145.15,47.03 144.78,47.4 144.78,50.77 v2(144.27,51.28) ; CPU1.K16 77.28,73.02 77.28,73.97 CPU1.K14 77.91,73.97 78.8,73.09 v2(78.8,73.04)
  BOTTOM w0.33: v2(125.22,96.11) 125.18,96.15 DIMM1.199
  BOTTOM w0.508: 120.27,102.33 121.79,100.81 v2(121.79,99.03) ; 120.27,102.33 120.85,102.91 DB1.10 ; 120.27,102.33 112.51,102.33 111.76,103.08 v2(111.76,104.11) 111.76,104.62 113.16,106.01 113.16,106.9 v2(113.41,107.16) ; R2607.1 107.42,27.15 R6211.1 ; v2(67.69,90.14) v2(67.69,92.55) ; v2(22.76,37.71) 22.86,37.81 24.51,37.81 26.14,39.44 26.92,39.44 27.05,39.57 v2(30.1,39.57) 29.84,39.82 29.84,51.02 v2(29.21,51.66) ; v2(21.08,72.99) 20.64,72.55 EC8607.1
  BOTTOM w0.762: v2(29.21,51.66) 29.72,52.16 29.72,58.45 29.21,58.96 29.21,60.04 29.21,60.79 27.97,62.03 27.97,66.35 v1(26.74,67.57) 21.32,72.99 v2(21.08,72.99)
  vias: v1(65.02,84.42) v1(66.93,85.82) v1(85.83,39.29) v3(35.81,94.2) v3(36.7,94.2) v3(36.7,93.31) v3(80.77,107.54) v3(81.53,108.3) v3(113.54,113.12)
3D3V_S5: length 726.5
  TOP w0.203: PU4601.21 38.6,49.93 38.55,49.98 38.51,49.98 38.35,50.13 38.51,50.29 38.55,50.29 38.6,50.33 PU4601.20
  TOP w0.254: v2(14.89,71.47) 16.51,69.85 16.51,68.17 18.03,66.64 R5420.1 ; v2(95.89,66.77) 95.63,66.77 94.87,67.53 92.71,67.53 91.5,68.74 R2101.1 ; R2455.2 152.59,61.05 155.66,61.05 156.67,62.07 161.54,62.07 161.8,61.82 v2(162.18,61.82) ; v2(165.35,47.97) 165.8,48.42 R2501.2 ; PR4910.1 134.75,46.45 134.11,45.81 134.11,40.78 135.88,39.01 137.64,39.01 138.6,38.05 139.23,38.05 139.4,38.05 140.01,37.43 146.77,37.43 v2(147.61,38.28) ; 97.73,82.01 97.79,82.01 98.5,81.3 100.53,81.3 100.69,81.15 102.9,81.15 v1(104.11,82.37) 105.54,83.79 v2(106.43,83.79) ; 97.73,82.01 97.41,82.34 RN2006.2 ; 97.73,82.01 97.41,81.68 RN2006.1 ; PR4450.2 v2(34.8,8.73) ; v2(161.67,56.86) 161.35,57.18 R2412.2
  TOP w0.305: 103.58,89.71 103.58,90.38 R1703.1 103.89,90.39 v2(104.78,89.5) ; 103.58,89.71 RN1701.1 ; 103.58,89.71 103.18,89.71 102.93,89.45 RN1701.2 ; RN1802.2 79.3,93.75 79.5,93.95 79.95,93.95 ; R2445.2 152.46,58.9 R2450.2 R2455.2 152.46,62.49 149.71,65.25 149.71,65.98 v2(150.24,66.52) ; RN1802.1 79.95,93.95 ; 79.95,93.95 79.95,95.04 80.39,95.47 v2(81.28,95.47)
  TOP w0.381: v2(33.4,30.83) 30.99,30.83 29.91,31.91 29.91,32.92 v1(27.69,35.15) 26.96,35.87 25.62,35.87 24.83,35.08 R2712.2
  TOP w0.508: v2(81.28,95.47) v1(81.28,98.8) 81.28,99.66 78.04,102.9 EC8609.1 76.96,103.57 75.82,104.71 v3(75.82,105) ; C2147.1 82.36,77.26 v2(82.21,77.41) ; v2(85.09,110.46) 88.57,113.94 114.25,113.94 115.06,113.12 115.06,108.3 116.28,107.08 130.42,107.08 138.3,99.21 v2(141.05,99.21) ; PR4618.2 47.9,46.88 v3(47.5,46.48) ; v2(50.04,87.98) v1(47.12,87.98) 41.53,87.98 40.77,88.74 38.35,88.74 ; 43.56,100.81 42.04,100.81 40.79,102.05 40.51,102.05 ; v2(36.7,50.13) 38.35,50.13 ; v2(41.4,64.36) PR4534.1
  TOP w1.016: v3(104.65,27.65) 104.65,28 95.85,36.8 90.3,36.8 89.36,35.86 86.66,35.86 86.11,36.42 74.42,36.42 ; v3(47.5,46.48) 47.5,45.73 48.39,44.84 48.39,42.13 51.18,39.34 63.79,39.34 66.72,36.42 71.75,36.42
  L3 w0.178: v2(81.28,95.47) 81.28,84.55 82.16,83.67 82.16,82.11 82.71,81.56 82.71,79.57 82.69,79.55 82.69,77.87 82.4,77.59 82.39,77.59 v2(82.21,77.41)
  L3 w0.254: v2(163.7,54.96) 166.5,52.16 166.5,49.12 v2(165.35,47.97) ; v2(146.43,32.99) 147.07,33.62 147.07,37.73 v2(147.61,38.28) ; v3(47.5,46.48) 47.85,46.83 48.9,46.83 49.28,46.46 49.28,44.55 51.18,42.64 60.58,42.64 v2(60.71,42.51)
  L3 w0.508: v2(161.67,56.86) 162.18,57.37 v2(162.18,61.82) ; v3(104.65,27.65) 104.65,27.4 105.16,26.89 106.43,26.89 106.55,27.02 109.35,27.02 109.6,26.76 125.61,26.76 126.37,27.53 140.72,27.53 v2(144.78,31.59) ; v2(14.89,71.47) 13.21,73.15 13.21,77.44 13.08,77.56 13.08,87.6 13.78,88.3 13.78,91.34 v2(15.49,93.06)
  L4 w0.254: v2(33.4,30.83) 33.53,30.83 35.05,29.3 35.05,25.62 35.81,24.86 35.81,20.77 34.42,19.37 34.42,9.11 v2(34.8,8.73)
  L4 w0.508: v2(85.09,110.46) 81.28,110.46 v3(75.82,105) ; v2(81.28,95.47) 81.28,95.34 81.78,94.84 84,94.84 84.11,94.95 86.12,94.95 89.41,91.66 94.36,91.66 96.01,90.01 104.27,90.01 v2(104.78,89.5) ; v2(15.49,93.06) 15.94,93.5 22.16,93.5 27.61,98.95 35.53,98.95 38.79,102.2 v3(43.81,102.2) ; v2(146.43,32.99) 155.96,32.99 156.72,33.75 158.76,33.75 159.13,33.38 159.13,33.24 v2(159.26,33.11)
  L4 w1.016: v3(75.82,105) 71.63,100.81 67.01,100.81 v3(64.9,102.92) ; v3(32.38,59.66) 33.25,58.79 39.89,58.79 42.04,60.94 42.04,63.72 v2(41.4,64.36) 43.05,66.01 43.05,72.87 44.45,74.26 44.45,79.09 42.42,81.12 42.42,87.22 40.77,88.87 38.48,88.87
  BOTTOM w0.254: v2(82.21,77.41) 82.21,77.4 82.51,77.4 CPU1.Y8 ; v2(104.78,89.5) 104.65,89.38 104.65,85.57 v2(106.43,83.79) 106.43,82.26 99.95,75.79 99.95,69.73 96.98,66.77 v2(95.89,66.77) ; PR4424.1 PR4431.1 43.81,8.63 43.4,8.22 35.31,8.22 v2(34.8,8.73) ; R2421.2 v1(148.21,38.96) 148.21,38.82 147.67,38.28 v2(147.61,38.28) ; v2(60.71,42.51) 60.71,43.15 60.39,43.47 C702.1 59.94,44.8 60.69,45.55 U701.5 ; PR4918.2 139.24,81.88 139.57,81.55 139.57,79.46 145.03,74 145.03,71.66 145.59,71.1 145.59,67.21
  BOTTOM w0.305: v2(150.24,66.52) 149.98,66.25 IOBD1.36 146.56,66.25 145.59,67.21
  BOTTOM w0.381: v2(33.4,30.83) 33.44,30.87 33.44,33.74 34.35,34.66 34.35,37.15 33.44,38.07 33.44,38.91 33.44,39.46 33.04,39.86 33.04,39.87 32.39,40.51 32.39,40.51 32.07,40.84 32.07,59.34 v3(32.38,59.66)
  BOTTOM w0.508: v2(161.67,56.86) 162.16,56.86 163.7,55.32 v2(163.7,54.96) 163.7,53.87 162.93,53.1 162.93,41.4 161.8,40.27 161.8,34.38 160.53,33.11 v2(159.26,33.11) ; PU5101.1 51.69,88.68 PC5108.1 v2(50.04,87.98) ; LIDSW1.2 7.9,73.25 8.89,73.25 9.72,72.42 C6402.1 R6401.2 15.11,71.7 v2(14.89,71.47) ; PR4807.2 40.2,89.38 38.35,89.38 ; SPI25.8 141.27,97.94 142.11,98.77 C2502.1 141.49,99.98 C2501.1 v2(141.05,99.21) ; v2(146.43,32.99) 146.43,32.9 145.13,31.59 v2(144.78,31.59)
  BOTTOM w1.016: v3(64.9,102.92) 61.98,102.92 61.26,102.2 v3(43.81,102.2) ; v3(75.82,105) 76.45,105.63 v3(76.45,112.49)
  vias: v1(43.69,97.61) v1(71.27,37.56) v1(74.52,112.52) v3(35.69,89.38) v3(35.69,88.49) v3(35.69,87.6) v3(35.69,86.71) v3(36.58,89.38) v3(36.58,86.07) v3(37.47,86.07) v3(41.27,94.2)
3D3V_S5_PCH: length 109.6
  TOP w0.254: R2017.1 R2001.1 R2004.1 83.82,89.63 v2(84.2,90.01) ; RN2012.4 89.13,93.84 88.77,94.2 v1(88.14,94.2) 86.36,94.2 85.03,92.87 R1724.1 R2022.1 R2014.1 ; R2021.1 88.1,89.26 88.6,89.76 v2(88.77,89.76)
  TOP w0.508: R1103.1 109.63,69.36 R2102.2 R2108.1 110.15,71.85 v1(112.81,74.51) 118.62,80.32 v1(118.62,93.44) v2(118.62,94.46) ; v2(84.71,100.55) 83.95,101.31 81.06,101.31 v1(80.15,102.22) 77.91,104.46 C3802.1 ; 106.68,85.31 v2(107.95,85.31)
  L3 w0.508: v2(84.71,100.55) 84.71,95.75 87.53,92.93 v2(89.92,92.93) ; v2(118.62,94.46) 117.6,94.46 116.97,95.09 114.8,95.09 113.54,93.83 113.54,90.9 v2(107.95,85.31)
  L4 w0.508: v2(103.38,84.93) 102.74,85.57 102.74,87.1 101.41,88.44 96.34,88.44 95.02,89.76 v2(88.77,89.76)
  BOTTOM w0.254: v2(84.2,90.01) 84.2,92.68 85.85,94.33 89.53,94.33 89.92,93.95 v2(89.92,92.93)
  BOTTOM w0.508: 89.92,91.03 89.92,90.52 89.15,89.76 v2(88.77,89.76)
  vias: v1(104.5,84.27)
+1.05M_ASW: length 6.5
  TOP w0.508: R1104.2 C1115.1 84.01,74.77 C1116.1 84.07,75.03 84.53,75.49 v1(84.53,75.61) 84.95,76.02 v2(85.06,76.02)
  BOTTOM w0.254: CPU1.AF9 CPU1.AE9
  BOTTOM w0.305: CPU1.AE9 85.07,76.03 v2(85.06,76.02) ; CPU1.AF9 86.46,77.23 CPU1.AG8
+3.3A_DSW_PRTCSUS: length 26.8
  TOP w0.254: R2102.1 107.06,70.58 105.03,68.55 v1(99.44,68.55) v2(98.04,68.55) ; C2109.1 88.33,74.02 v2(87.41,74.94)
  L3 w0.254: v2(87.41,74.94) 87.96,74.39 87.96,74.34 88.57,73.73 89.53,73.73 89.81,73.45 89.81,72.89 90.53,72.18 91.74,72.18 93.6,70.33 96.35,70.33 98.04,68.63 v2(98.04,68.55)
  BOTTOM w0.254: CPU1.AH11 87.06,75.28 v2(87.41,74.94)
+DC_IN: length 3.6
  BOTTOM w0.508: PR4207.1 PC4201.1 42.65,30.35 41.27,31.72
  vias: v1(21.21,62.83) v1(21.46,46.6) v1(22.99,74.9) v1(23.09,78.45) v1(36.91,33.09) v1(37.74,35.25) v3(24,79.34) v3(24,78.07) v3(24,75.91) v3(24,74.26) v3(24,72.87) v3(36.58,31.97) v3(36.58,31.08) v3(37.47,31.97) v3(37.47,31.08) v3(38.35,31.97) v3(38.35,31.08)
+DC_IN_C:
  vias: v1(20.83,86.84) v3(21.21,85.95) v3(21.97,86.33) v3(21.97,85.44) v3(21.97,84.55)
+PCH_VCCDSW: length 4.9
  TOP w0.254: C2101.2 R2110.1 87.17,69.63 v1(87.06,69.74) 86.74,70.06 86.74,70.87 v2(86.75,70.88)
  BOTTOM w0.254: CPU1.AG20 86.75,70.84 v2(86.75,70.88) 86.75,70.92 CPU1.AG19
+RTC_VCC: length 9.9
  TOP w0.508: v2(143,63.47) 143.41,63.88 Q2505.G 143,64.83 143,67.09 R2504.1
  BOTTOM w0.305: IOBD1.31 146.59,63.75
  BOTTOM w0.508: 146.59,63.75 v1(145.72,63.75) 144.17,63.75 D2501.2 143.46,63.92 143.14,63.59 143.13,63.59 v2(143,63.47)
+SDC_IN: length 14.3
  TOP w0.508: v2(43.18,23.34) 43.24,23.27 PR4435.1 ; PR4439.1 v2(36.32,13.68)
  L4 w0.508: v2(43.18,23.34) 42.66,23.34 37.21,17.88 37.21,14.57 v2(36.32,13.68)
  vias: v1(42.67,26.38)
+V_SM_VREF_CNT: length 71.3
  TOP w1.016: v3(139.32,63.59) 138.56,62.83 138.56,59.37 134.27,55.09 133.1,55.09 132.21,54.2 132.21,34.32 128.87,30.99 123.41,30.99 122.81,31.59 109.98,31.59 101.22,40.35 99.82,40.35
  BOTTOM w0.305: v2(90.76,51.46) 90.45,51.76 CPU1.AP49
  vias: v1(97.26,44.04)
+V_VREF_PATH1: length 1.9
  TOP w0.203: C3702.2 119.32,34.38 v1(118.59,34.38)
  TOP w0.508: R3711.1 C3702.2
+V_VREF_PATH3: length 2
  BOTTOM w0.508: R3707.1 140.72,66.91 140.34,66.53 v1(140.34,66.34) 140.21,66.21 C3701.2
+VCHGR:
  vias: v1(81.51,25.77) v3(81.53,22.07) v3(81.53,21.18) v3(82.55,22.07) v3(82.55,21.18) v3(83.57,22.07) v3(83.57,21.18)
+VCHGR_R: length 2.4
  TOP w0.102: v1(75.44,26.21) v2(75.44,26.76) 75.5,26.7 PR4454.1
  BOTTOM w0.102: v2(75.44,26.76) PG4405.1
AC_IN#: length 159.4
  TOP w0.102: v2(164.08,30.45) 163.07,30.45 162.81,30.7 162.81,31.59 163.26,32.04 R2413.1 163.92,34 164.34,34.42 R2430.1
  L4 w0.102: v2(164.08,30.45) 163.7,30.45 159.97,26.71 144.05,26.71 138.03,20.69 112.5,20.69 110.62,22.57 101.49,22.57 100.96,22.04 88.99,22.04 87.93,23.11 80.48,23.11 79.41,22.04 74.71,22.04 69.55,16.88 50.38,16.88 49.1,15.61 49.1,6.27 46.76,3.93 44.03,3.93 43.57,3.47 38.3,3.47 36.83,4.95 v2(36.83,6.44)
  BOTTOM w0.102: PR4412.2 v1(37.67,7.21) 37.59,7.21 v2(36.83,6.44) 36.83,5.3 36.94,5.19 PQ4413.6
AC_PRESENT: length 162.6
  TOP w0.102: v2(104.01,86.84) 103.58,87.27 RN1701.4 104.62,87.76 EC1707.1 ; KBC24.112 155.14,53.62 v2(155.83,52.93)
  L3 w0.102: v2(137.79,34.38) 137.79,35.6 135.89,37.51 135.89,40.15 136.27,40.53 136.27,45.94 132.78,49.43 132.78,95.88 130.17,98.49 126.73,98.49 124.77,100.45 124.6,100.45 112.98,100.45 111.47,98.93 109.34,98.93 106.72,96.31 103.99,96.31 102.21,94.53 102.21,92.94 102.69,92.46 102.69,88.16 v2(104.01,86.84) 102.62,85.44 102.62,82.31 97.51,77.21 92.28,77.21 91.92,77.57 88.53,77.57 v2(87.78,76.83)
  L4 w0.102: v2(155.83,52.93) 155.77,52.93 153.24,50.4 153.24,49.85 147.19,43.81 147.19,42.99 145.11,40.9 145.11,39.63 140.4,34.92 138.33,34.92 v2(137.79,34.38)
  BOTTOM w0.102: v1(155.68,53.49) 155.68,53.08 v2(155.83,52.93) ; CPU1.AJ8 87.45,77.16 v2(87.78,76.83)
ACAV_IN: length 16.6
  TOP w0.102: PQ4407.2 38.86,25.83 38.43,25.39 38.43,25.11 37.47,24.15 37.47,20.67 v2(36.45,19.65) ; PR4430.2 v2(36.32,12.79)
  BOTTOM w0.102: v2(36.45,19.65) v1(35.28,18.48) 35.05,18.26 35.05,13.3 35.56,12.79 v2(36.32,12.79)
AD+: length 28.5
  TOP w0.508: PR4416.1 27.05,8.79 v2(27.05,9.49) ; PR4418.1 39.62,20.67 v2(37.97,22.32) ; PR4444.1 36.13,10.19 v2(35.94,10.38) 35.43,10.89 PD4406.A
  L3 w0.508: v2(27.05,9.49) 27.94,10.38 v2(35.94,10.38)
  BOTTOM w0.508: v2(35.94,10.38) 35.94,11.65 34.54,13.05 v1(34.54,14.57) 34.54,18.76 36.51,20.73 PC4204.1
AD+_G_1: length 4.5
  TOP w0.102: PQ4407.6 42.07,26.48 42.42,26.13 42.42,25.8 ; PQ4407.5 42.39,25.83 42.42,25.8 ; 42.42,25.8 v1(42.42,25.32) PR4423.1
AD+_G_2: length 3.6
  TOP w0.254: PR4423.2 42.35,23.46 PR4435.2 42.35,22.13 v2(41.91,21.68) 42.01,21.58 v1(42.52,21.58)
  BOTTOM w0.254: v2(41.91,21.68) 42.1,21.88 PU4405.4
AD_IA: length 193.1
  TOP w0.102: KBC24.97 162.21,54.7 163.68,56.17 163.68,56.5 v1(163.68,56.5) 163.68,56.51 163.68,57.66 C2414.2 v2(165.35,58.58) ; PR4466.2 v2(28.32,2.76)
  L4 w0.102: v2(28.32,2.76) 28.78,3.22 43.6,3.22 44.11,3.73 46.94,3.73 49.3,6.09 49.3,15.52 50.46,16.68 69.64,16.68 74.79,21.84 79.49,21.84 80.56,22.9 87.84,22.9 88.91,21.84 101.04,21.84 101.57,22.37 110.44,22.37 112.32,20.49 138.12,20.49 144.14,26.51 160.15,26.51 163.19,29.56 163.88,29.56 165.1,30.78 165.1,43.78 164.72,44.16 164.72,48.23 166.78,50.29 166.78,55.82 165.35,57.24 v2(165.35,58.58)
AD_IA_HW: length 195.5
  TOP w0.102: R2001.2 84.71,87.09 85.47,86.33 86.61,86.33 87.15,85.79 87.15,81.36 v1(87.5,81.01) 87.5,80.83 v2(88.17,80.16)
  L4 w0.102: v2(88.17,80.16) 87.94,80.16 86.86,81.25 86.48,81.25 85.17,82.56 85.17,89.97 84.45,90.68 84.45,91.57 82.51,93.52 81.58,93.52 80.49,94.61 77.37,94.61 76.33,93.57 67.94,93.57 66.79,92.42 44.83,92.42 41.15,96.11 25.95,96.11 22.45,92.6 19.01,92.6 16.27,89.86 16.27,84.37 15.77,83.87 15.77,73.62 16.76,72.63 16.76,68.8 20.02,65.55 20.02,53.77 19.28,53.03 19.28,51.07 21.15,49.2 21.15,42.58 30.73,32.99 30.73,31.97 34.37,28.34 34.37,20.62 33.66,19.91 33.66,14.06 32.26,12.67 32.26,7.59 33.4,6.44 v2(33.4,6.32)
  BOTTOM w0.102: PQ4411.5 33.66,3.52 33.51,3.67 33.51,4.65 33.87,5.01 33.87,5.85 v2(33.4,6.32) ; CPU1.AL4 88.29,80.16 v2(88.17,80.16)
AD_IA_HW2: length 191.1
  TOP w0.102: v2(88.77,89.12) 88.77,88.95 88.36,88.54 87.78,88.54 87.25,89.07 R2021.2 87.21,87.51 88.39,86.33 88.39,84.4 v1(88.52,84.27) 90.2,84.27 90.82,83.65 v2(90.82,83.41)
  L4 w0.102: v2(32.77,6.32) 32.77,6.7 32.05,7.41 32.05,12.75 33.45,14.15 33.45,19.99 34.16,20.7 34.16,28.26 30.53,31.89 30.53,32.9 20.94,42.49 20.94,49.12 19.08,50.99 19.08,53.11 19.81,53.85 19.81,56.48 19.05,57.24 19.05,66.23 16.56,68.72 16.56,72.54 15.36,73.75 15.36,83.75 16.07,84.45 16.07,89.95 18.92,92.8 22.36,92.8 25.92,96.36 41.18,96.36 43.72,93.82 53.53,93.82 53.54,93.83 60.53,93.83 61.3,94.61 67.73,94.61 68.37,93.97 76.16,93.97 77.2,95.01 80.66,95.01 81.47,94.2 84.26,94.2 84.38,94.32 84.79,94.32 85.2,93.9 85.2,92.63 85.71,92.12 85.71,91.19 87.78,89.12 v2(88.77,89.12)
  BOTTOM w0.102: PQ4411.2 33.15,3.52 33.29,3.67 33.29,4.72 33.67,5.09 33.67,5.67 33.45,5.89 33.2,5.89 v2(32.77,6.32) ; v2(90.82,83.41) 90.82,83.4 91.16,83.05 91.16,82.59 90.8,82.22 CPU1.AP1
ALERT#: length 5.1
  TOP w0.102: v1(80.01,60.04) R2603.2 82.23,59.09 82.88,59.73 THM261.6
ALL_SYS_PWRGD: length 31.6
  TOP w0.102: v2(151.76,45.43) 152.21,45.88 152.21,46.88 151.76,47.34 149.61,47.34 148.84,48.1 148.84,48.86 148.15,49.56 KBC24.10 ; v2(147.57,39.08) 147.22,38.73 145.82,38.73 145.81,38.74 139.52,38.74 139.52,38.74 139.18,38.74 138.37,39.55 R3601.2 137.39,39.85 136.42,40.81 v1(136.42,40.84) 136.21,41.05 R3611.2 R3610.2
  L3 w0.102: v2(151.76,45.43) 150.37,44.04 150.26,44.04 148.54,42.31 148.54,40.05 v2(147.57,39.08)
ALS_INT#: length 80.2
  TOP w0.102: v2(82.58,84.09) 82.03,84.64 82.03,85.33 80.12,87.24 79.06,87.24 78.76,87.24 78.76,87.24 75.18,87.24 73.71,88.72 72.28,90.15 70.85,90.15 v2(70.74,90.26) 70.62,90.15 RN2002.8 ; U6601.28 95.52,106.75 95,107.28 v2(95,107.66)
  L4 w0.102: v2(80.39,103.6) 80.39,103.24 77.06,99.92 75.49,99.92 71.04,95.47 v2(70.48,95.47) 70.05,95.9 60.91,95.9 60.03,95.03 49.87,95.03 49.43,95.47 v2(49.4,95.47)
  BOTTOM w0.089: CPU1.Y3 82.84,80.76 82.84,82 82.72,82.12 82.72,82.13 82.55,82.3 82.55,82.96 82.82,83.23 82.82,83.85 v2(82.58,84.09)
  BOTTOM w0.102: v2(70.74,90.26) 70.48,90.52 v1(70.48,92.68) v2(70.48,95.47) ; v2(80.39,103.6) 88.77,103.6 92.84,107.66 v2(95,107.66) ; v2(49.4,95.47) 49.55,95.32 LCD1.33
AMP_MUTE#: length 160
  TOP w0.102: v2(143,39.21) 143.17,39.04 145.94,39.04 145.95,39.03 146.63,39.03 148.18,40.58 148.18,41.4 148.02,41.56 KBC24.30
  L4 w0.102: v2(29.08,36.54) 29.68,36.54 31.84,34.38 34.16,34.38 34.67,34.89 67.52,34.89 71.33,38.7 74.8,38.7 78.23,35.27 81.45,35.27 89.27,27.45 97.98,27.45 99.07,28.54 109.25,28.54 109.89,27.91 121.48,27.91 121.99,28.42 128.57,28.42 131.85,31.69 133.24,31.69 137.53,35.99 139.84,35.99 143,39.15 v2(143,39.21)
  BOTTOM w0.102: R2708.1 v1(27.69,19.65) 27.69,19.27 28.13,18.83 30.9,18.83 32.44,20.37 32.44,29.17 31.75,29.86 31.75,33.24 31.62,33.37 29.97,33.37 29.08,34.27 v2(29.08,36.54)
AUD_AGND: length 20.8
  TOP w0.254: R2707.2 25.9,31.78 25.53,32.15 25.53,32.99 v2(25.91,33.37)
  TOP w0.508: v2(23.75,32.86) 23.14,32.25 C2713.2 ; v2(22.86,34.26) 23.05,34.45 R2923.1 23.56,35.53 EC2704.1 23.11,35.91 v2(22.86,36.16) ; EC8601.1 v2(25.91,33.37) EC8604.1
  BOTTOM w0.406: U2901.4 25.96,33.42 v2(25.91,33.37)
  BOTTOM w0.508: v2(21.08,17.24) 21.27,17.05 EC2706.1 ; EC2907.2 22.35,20.5 v2(21.96,20.89) 22.48,21.41 EC2707.1 ; v2(23.75,32.86) 23.18,32.29 Q2901.S ; v2(16.26,28.42) 15.88,28.03 AFTP2908.1 ; EC2705.1 22.29,36.73 v2(22.86,36.16) 22.99,36.29 EC2703.1 ; R2920.2 EC2908.2 18.29,31.08 v2(18.41,30.96) ; C2902.1 22.35,34.77 v2(22.86,34.26) ; v2(16.38,26.13) 16.45,26.07 R2919.2 ; EC2905.2 v2(15.37,23.59) ; R2905.2 22.35,33.62 v2(22.48,33.5)
  vias: v2(16.26,30.83) v2(17.14,33.62) v2(20.19,18.51) v2(20.57,27.89) v2(26.8,28.8)
AUD_HP1_JACK_L: length 4.4
  TOP w0.203: 19.41,24.46 20.06,24.46 20.12,24.51 HDA27.32
  TOP w0.254: 19.41,24.46 19.16,24.46 18.16,23.46 R2908.1 17.97,23.35 17.48,22.85 v1(17.48,22.57)
AUD_HP1_JACK_L1: length 24
  TOP w0.254: v2(16.38,24.35) R2912.2 R2908.2 ; R2922.2 v2(16.38,31.84)
  L3 w0.254: v2(21.59,20.29) 21.59,20.03 21.21,19.65 18.41,19.65 15.88,22.19 15.88,23.84 v2(16.38,24.35) 17.02,24.99 17.02,31.21 v2(16.38,31.84)
  BOTTOM w0.254: R2919.1 17.14,25.11 v2(16.38,24.35) ; v2(21.59,20.29) 21.46,20.16 v1(21.46,19.65) 21.46,19.4 21.65,19.21 EC2907.1 22.35,18.15 R2907.1
AUD_HP1_JACK_R: length 4.4
  TOP w0.203: HDA27.33 19.57,24.11 v1(19.08,23.62)
  TOP w0.254: R2910.1 18.01,21.72 18.01,22.55 v1(19.08,23.62)
AUD_HP1_JACK_R1: length 21.2
  TOP w0.254: R2921.2 v2(16.38,32.73) ; R2913.2 16.51,25.24 15.88,24.61 15.88,23.08 v2(16.38,22.57) 16.38,22.38 R2910.2
  L3 w0.254: v2(16.38,22.57) 16.38,23.63 17.53,24.78 17.53,31.59 v2(16.38,32.73)
  BOTTOM w0.254: v1(19.65,34.38) 19.46,34.38 18.67,33.6 R2909.1 18.29,33.47 EC2908.1 R2920.1 16.45,32.67 v2(16.38,32.73)
AUD_PC_BEEP: length 3.2
  TOP w0.203: 27.69,27.65 27.35,27.31 HDA27.12
  TOP w0.254: 27.69,27.65 v1(28.41,28.38) 28.45,28.42 C2720.2
AUD_PC_BEEP_C: length 5
  TOP w0.254: v1(30.12,30.73) 30.12,30.68 v2(30.61,30.19) 30.54,30.13 R2717.1 C2720.1
  BOTTOM w0.254: v2(30.61,30.19) 31.11,30.7 D2701.3
AUD_PORTA_L_R_B: length 14.5
  L4 w0.254: HPMIC1.1 17.86,19.14 v2(18.78,19.14)
  BOTTOM w0.254: AFTP2906.1 14.02,24.05 HPMIC1.1 ; v2(18.78,19.14) 18.92,19.29 ED2902.2 19.52,19.3 20.17,19.3 21.06,18.41 R2907.2
AUD_PORTA_R_R_B: length 14
  BOTTOM w0.254: R2909.2 18.41,35.15 18.8,35.53 ED2901.2 18.27,36.27 17.14,35.15 AFTP2907.1 9,35.15 HPMIC1.2
AUD_SENSE: length 8.6
  TOP w0.254: v2(26.04,32.48) 26.1,32.54 R2709.2
  BOTTOM w0.254: R2914.2 19.85,30.38 Q2901.D 22.75,31.16 v1(24.39,31.16) 25.33,31.16 26.04,31.86 v2(26.04,32.48)
AUD_SENSE_A: length 3.9
  TOP w0.203: 26.16,28.92 26.08,28.84 HDA27.13
  TOP w0.254: 26.16,28.92 26.86,29.62 R2722.1 26.9,29.72 v1(26.9,30.75) 26.9,31.55 R2709.1
AUD_SPK_L+: length 13.6
  TOP w0.203: v3(24,20.29) 23.68,20.61 HDA27.42
  L4 w1.016: v3(19.68,13.68) 22.88,13.68 25.27,16.08 25.27,19.54 24.53,20.29 v3(24,20.29)
  vias: v1(20.19,14.19)
AUD_SPK_L+_C: length 6.9
  BOTTOM w0.61: SPK1.3 14.3,11.11
  BOTTOM w0.635: 14.3,11.11 14.41,11.22
  BOTTOM w1.016: R2902.2 17.37,13.53 AFTP2902.1 16.53,13.43 14.41,11.31 14.41,11.22
AUD_SPK_L-: length 10.9
  TOP w0.203: HDA27.43 24.08,21.06 24.59,20.55 v1(24.59,19.75) 24.59,19.6 v3(24,19.02)
  L4 w1.016: v3(19.68,14.95) 22.35,14.95 24,16.6 v3(24,19.02)
AUD_SPK_L-_C: length 8.6
  BOTTOM w0.61: SPK1.4 13.3,10.92 13.08,11.14
  BOTTOM w1.016: 13.08,11.14 13.08,11.78 AFTP2901.1 16.1,14.8 16.1,15.1 16.85,15.84 R2901.2
AUD_SPK_R+: length 17.7
  TOP w0.203: v3(26.16,20.16) 25.91,20.16 24.88,21.19 HDA27.45
  L3 w1.016: v3(26.16,20.16) 26.02,20.16 25.27,19.42 25.27,17.37 17.91,10.01 v3(17.91,9.24)
  BOTTOM w0.254: v1(26.16,19.5) v3(26.16,20.16)
AUD_SPK_R+_C: length 5.7
  TOP w1.016: R2904.2 v3(16.26,8.1)
  BOTTOM w0.356: SPK1.1 16.3,10.17 17.78,11.65 AFTP2904.1
  BOTTOM w0.61: SPK1.1 16.3,8.14 v3(16.26,8.1)
AUD_SPK_R-: length 20.6
  TOP w0.203: v3(26.54,18.89) 26.04,18.89 v1(25.76,19.17) 25.02,19.91 25.02,20.58 24.48,21.13 HDA27.44
  L3 w1.016: v3(19.18,5.68) 19.18,9.48 26.54,16.85 v3(26.54,18.89)
AUD_SPK_R-_C: length 7
  TOP w1.016: v3(15.49,7.08) 15.75,6.83 R2903.2
  BOTTOM w0.356: AFTP2903.1 16.38,11.14 15.3,10.06 SPK1.2
  BOTTOM w0.61: v3(15.49,7.08) 15.3,7.27 SPK1.2
AUD_VREF: length 3.2
  TOP w0.203: 19.53,26.23 20.14,26.23 20.26,26.11 HDA27.28
  TOP w0.254: C2705.2 18.63,26.13 v1(18.88,25.88) 19.23,26.23 19.53,26.23
BAT_IN#: length 176.3
  TOP w0.102: v2(96.27,24.1) 95.23,23.06 RN4301.1 ; R2414.1 164.34,33.75 165.79,35.2 165.79,46.5 165.66,46.63 164.25,46.63 164.12,46.76 KBC24.80 161.09,46.76 v2(160.91,46.58) ; v2(44.32,11.27) 44.2,11.4 PU4401.15
  L3 w0.102: v2(138.56,30.32) 137.85,31.03 130.18,31.03 129.2,30.05 124.95,30.05 123.62,28.72 98.22,28.72 v2(97.92,28.42)
  L4 w0.102: v2(82.8,28.8) 80.77,28.8 79.55,27.58 79.55,24.41 78.76,23.62 72.77,23.62 70.12,20.97 61.95,20.97 59.43,18.46 48.58,18.46 45.8,15.67 45.8,12.74 v2(44.32,11.27) ; v2(138.56,30.32) 139.37,31.13 146.4,31.13 146.65,31.39 147.22,31.39 147.48,31.13 149.14,31.13 149.59,31.59 159.72,31.59 162.42,34.29 162.42,42.4 160.91,43.91 v2(160.91,46.58)
  BOTTOM w0.102: v2(97.92,28.42) 97.66,28.67 EC4305.2 ; v2(96.27,24.1) 97.31,25.14 D4302.3 98.04,27.65 97.22,28.48 EC4305.2 ; EC4305.2 96.34,29.55 90,29.55 89.28,30.27 v1(85.01,30.27) 84.28,30.27 v2(82.8,28.8) ; v2(44.32,11.27) 43.81,10.76 PR4431.2 PC4414.1
BAT_SCL: length 171.5
  TOP w0.114: v2(84.2,28.8) 83.28,29.72 80.78,29.72 78.42,27.35 78.42,26.39 76.84,24.82 72.78,24.82 71.47,23.51 71.47,22.24 70.54,21.3 59.31,21.3 59.05,21.05 v2(59.05,20.8) ; RN2401.1 163.14,37.63 v2(163.58,38.07) 164.59,39.08 164.59,41.75 163.58,42.76 KBC24.70 ; PG4401.2 43.18,6.83 v2(43.05,6.7) 43.05,6.39 43.43,6.01 PR4432.2 ; v2(92.08,24.1) 92.58,23.59 93.22,23.59 93.35,23.46 RN4301.3
  L3 w0.127: v2(43.05,6.7) 42.8,6.95 42.8,7.21 43.56,7.97 45.85,7.97 46.48,8.6 46.48,9.59 47.24,10.35 47.24,16.73 48.21,17.7 56.72,17.7 58.85,19.83 58.85,20.59 v2(59.05,20.8)
  L4 w0.127: v2(163.58,38.07) 163.45,37.94 163.45,34.26 159.45,30.26 149.75,30.26 149.3,29.81 142.87,29.81 140.65,27.59 134.46,27.59 132.89,26.02 126.91,26.02 125.31,24.42 102.33,24.42 101.7,25.05 88.26,25.05 84.51,28.8 v2(84.2,28.8)
  BOTTOM w0.114: v2(92.08,24.1) 92.08,24.48 91.41,25.14 D4301.3 90.93,28.61 EC4301.1 89.92,28.67 89,29.59 87.03,29.59 86.23,28.8 v1(84.94,28.8) v2(84.2,28.8)
BAT_SDA: length 174.2
  TOP w0.114: PG4408.2 42.16,6.83 v2(42.29,6.7) 42.55,6.44 PR4414.2 ; RN2401.2 162.49,37.74 v2(163.58,38.83) 164.25,39.5 164.25,41.61 163.5,42.36 KBC24.69 ; v2(94.23,24.1) 93.85,23.71 RN4301.2 ; v2(84.19,29.56) 83.92,29.56 83.42,30.06 80.64,30.06 78.07,27.49 78.07,26.53 76.7,25.16 72.64,25.16 71.13,23.65 71.13,22.38 70.39,21.65 59.14,21.65 v2(58.29,20.8)
  L3 w0.127: v2(58.29,20.8) 58.47,20.62 58.47,19.99 56.56,18.08 48.05,18.08 46.86,16.89 46.86,10.51 46.1,9.75 46.1,8.76 45.69,8.35 43.4,8.35 42.42,7.36 42.42,6.83 v2(42.29,6.7)
  L4 w0.127: v2(84.19,29.56) 84.29,29.56 88.42,25.43 101.85,25.43 102.49,24.8 125.15,24.8 126.75,26.4 132.73,26.4 134.3,27.97 140.49,27.97 142.71,30.19 149.14,30.19 149.59,30.64 159.29,30.64 163.07,34.42 163.07,38.32 v2(163.58,38.83)
  BOTTOM w0.114: v2(94.23,24.1) 94.49,24.35 D4303.3 94.49,28.61 EC4302.1 93.88,29.21 89.86,29.21 89.14,29.93 86.88,29.93 86.41,29.46 v1(86.23,29.46) 84.29,29.46 v2(84.19,29.56)
BATDRV#: length 50
  TOP w0.254: v2(48.26,13.3) 48.13,13.18 PR4409.2 ; v2(59.94,20.8) v1(64.52,20.8) 70.61,20.8 71.88,22.07 71.88,23.34 72.95,24.4 77.01,24.4 78.83,26.22 78.83,27.11 81.02,29.3 83.01,29.3 83.44,28.88 v2(83.44,28.8)
  L3 w0.254: v2(59.94,20.8) 59.94,19.53 57.66,17.24 49.91,17.24 47.75,15.08 47.75,13.81 v2(48.26,13.3)
  BOTTOM w0.254: PU4403.4 83.63,26.64 83.76,26.76 PC4424.2 83.76,27.84 83.44,28.16 v2(83.44,28.8)
BATLOW#: length 28.9
  TOP w0.102: v1(89.13,81.37) 89.13,80.73 v2(89.67,80.18) ; RN1701.3 102.93,87.16 103.25,86.84 v2(103.38,86.84)
  L3 w0.102: v2(89.67,80.18) 88.85,80.18 88.4,79.73 87.81,79.73 87.51,79.43 87.51,78.23 87.76,77.98 91.89,77.98 92.35,77.51 97.51,77.51 102.41,82.42 102.41,85.52 103.38,86.49 v2(103.38,86.84)
  BOTTOM w0.102: v2(89.67,80.18) 89.69,80.17 89.78,80.17 CPU1.AN4
BATT_WHITE_LED#: length 27.8
  TOP w0.102: KBC24.62 160.34,40.29 v2(160.4,40.35)
  L3 w0.102: v2(159.43,50.73) 160.4,49.75 160.4,43.19 160.35,43.14 160.35,40.4 v2(160.4,40.35)
  BOTTOM w0.102: v2(159.43,50.73) v1(158.48,51.67) 154.98,55.17 150.34,55.17 148.93,56.58 148.93,58.22 148.4,58.75 IOBD1.21
BKLT_CTRL: length 32.6
  TOP w0.114: v2(70.36,97.38) D5202.3 72.96,97.38 R5224.1 ; RN5203.5 53.94,97.38 51.69,97.38 51.31,97 v2(51.31,95.47) v1(51.31,94.25) 50.93,93.88 50.93,92.8 51.28,92.45 RN5201.5
  L3 w0.127: v2(51.31,95.47) 53.24,97.4 59.6,97.4 60.58,98.38 69.48,98.38 70.36,97.5 v2(70.36,97.38)
BLON_OUT: length 181
  TOP w0.102: KBC24.27 148.22,42.76 148.77,42.21 158.17,42.21 158.88,42.92 v2(158.88,43.02) ; v2(60.07,96.11) 60.07,95.6 v1(59.94,95.47) 58.42,93.95 56.01,93.95 54.64,92.57 54.64,92.16 54.42,91.94 53.5,91.94 53.39,92.05 RN5201.7
  L3 w0.102: v2(60.07,96.11) 60.33,96.11 60.71,96.49 71.13,96.49 76.89,102.24 76.89,105.95 82.24,111.3 114.45,111.3 117.65,108.1 130.19,108.1 131.39,106.92 131.47,106.85 131.57,106.75 131.57,106.75 131.75,106.58 131.97,106.36 132.47,105.83 132.51,105.79 135.85,104.28 136.45,104.03 138.32,103.04 138.74,102.82 140.96,100.59 141.74,99.82 141.74,99.65 141.74,87.11 142.37,86.48 142.37,80.36 159.82,62.91 159.82,58.64 158.55,57.37 158.55,43.35 v2(158.88,43.02)
BLON_OUT_C: length 7
  TOP w0.102: RN5201.2 53.39,95.13 v2(53.72,95.46) 54.18,95.92 54.18,96.54 v1(53.95,96.77) 53.97,96.77 54.26,97.06 54.75,97.06 54.99,97.3 RN5203.6
  BOTTOM w0.102: v2(53.72,95.46) 53.72,95.43 53.55,95.26 LCD1.25
BLUETOOTH_EN: length 158.2
  TOP w0.102: v2(76.2,80.18) 75.31,81.07 68.55,81.07 67.93,81.68 RN2011.5
  L3 w0.102: v2(76.2,80.18) 75.26,81.12 75.26,82.72 75.74,83.2 75.74,84.85 74.49,86.1 74.49,93.64 77.27,96.41 77.27,98.52 81.55,102.8 85.85,102.8 92.77,109.72 100.91,109.72 101.5,110.31 113.99,110.31 117.11,107.18 129.81,107.18 140.82,96.17 140.82,86.73 141.45,86.1 141.45,79.98 157.87,63.56 v2(157.87,60.68)
  BOTTOM w0.102: CPU1.J4 76.52,79.86 v2(76.2,80.18) ; v2(157.87,60.68) v1(156.84,60.68) 155.76,60.68 154.68,61.76 149.6,61.76 148.59,60.75 IOBD1.25
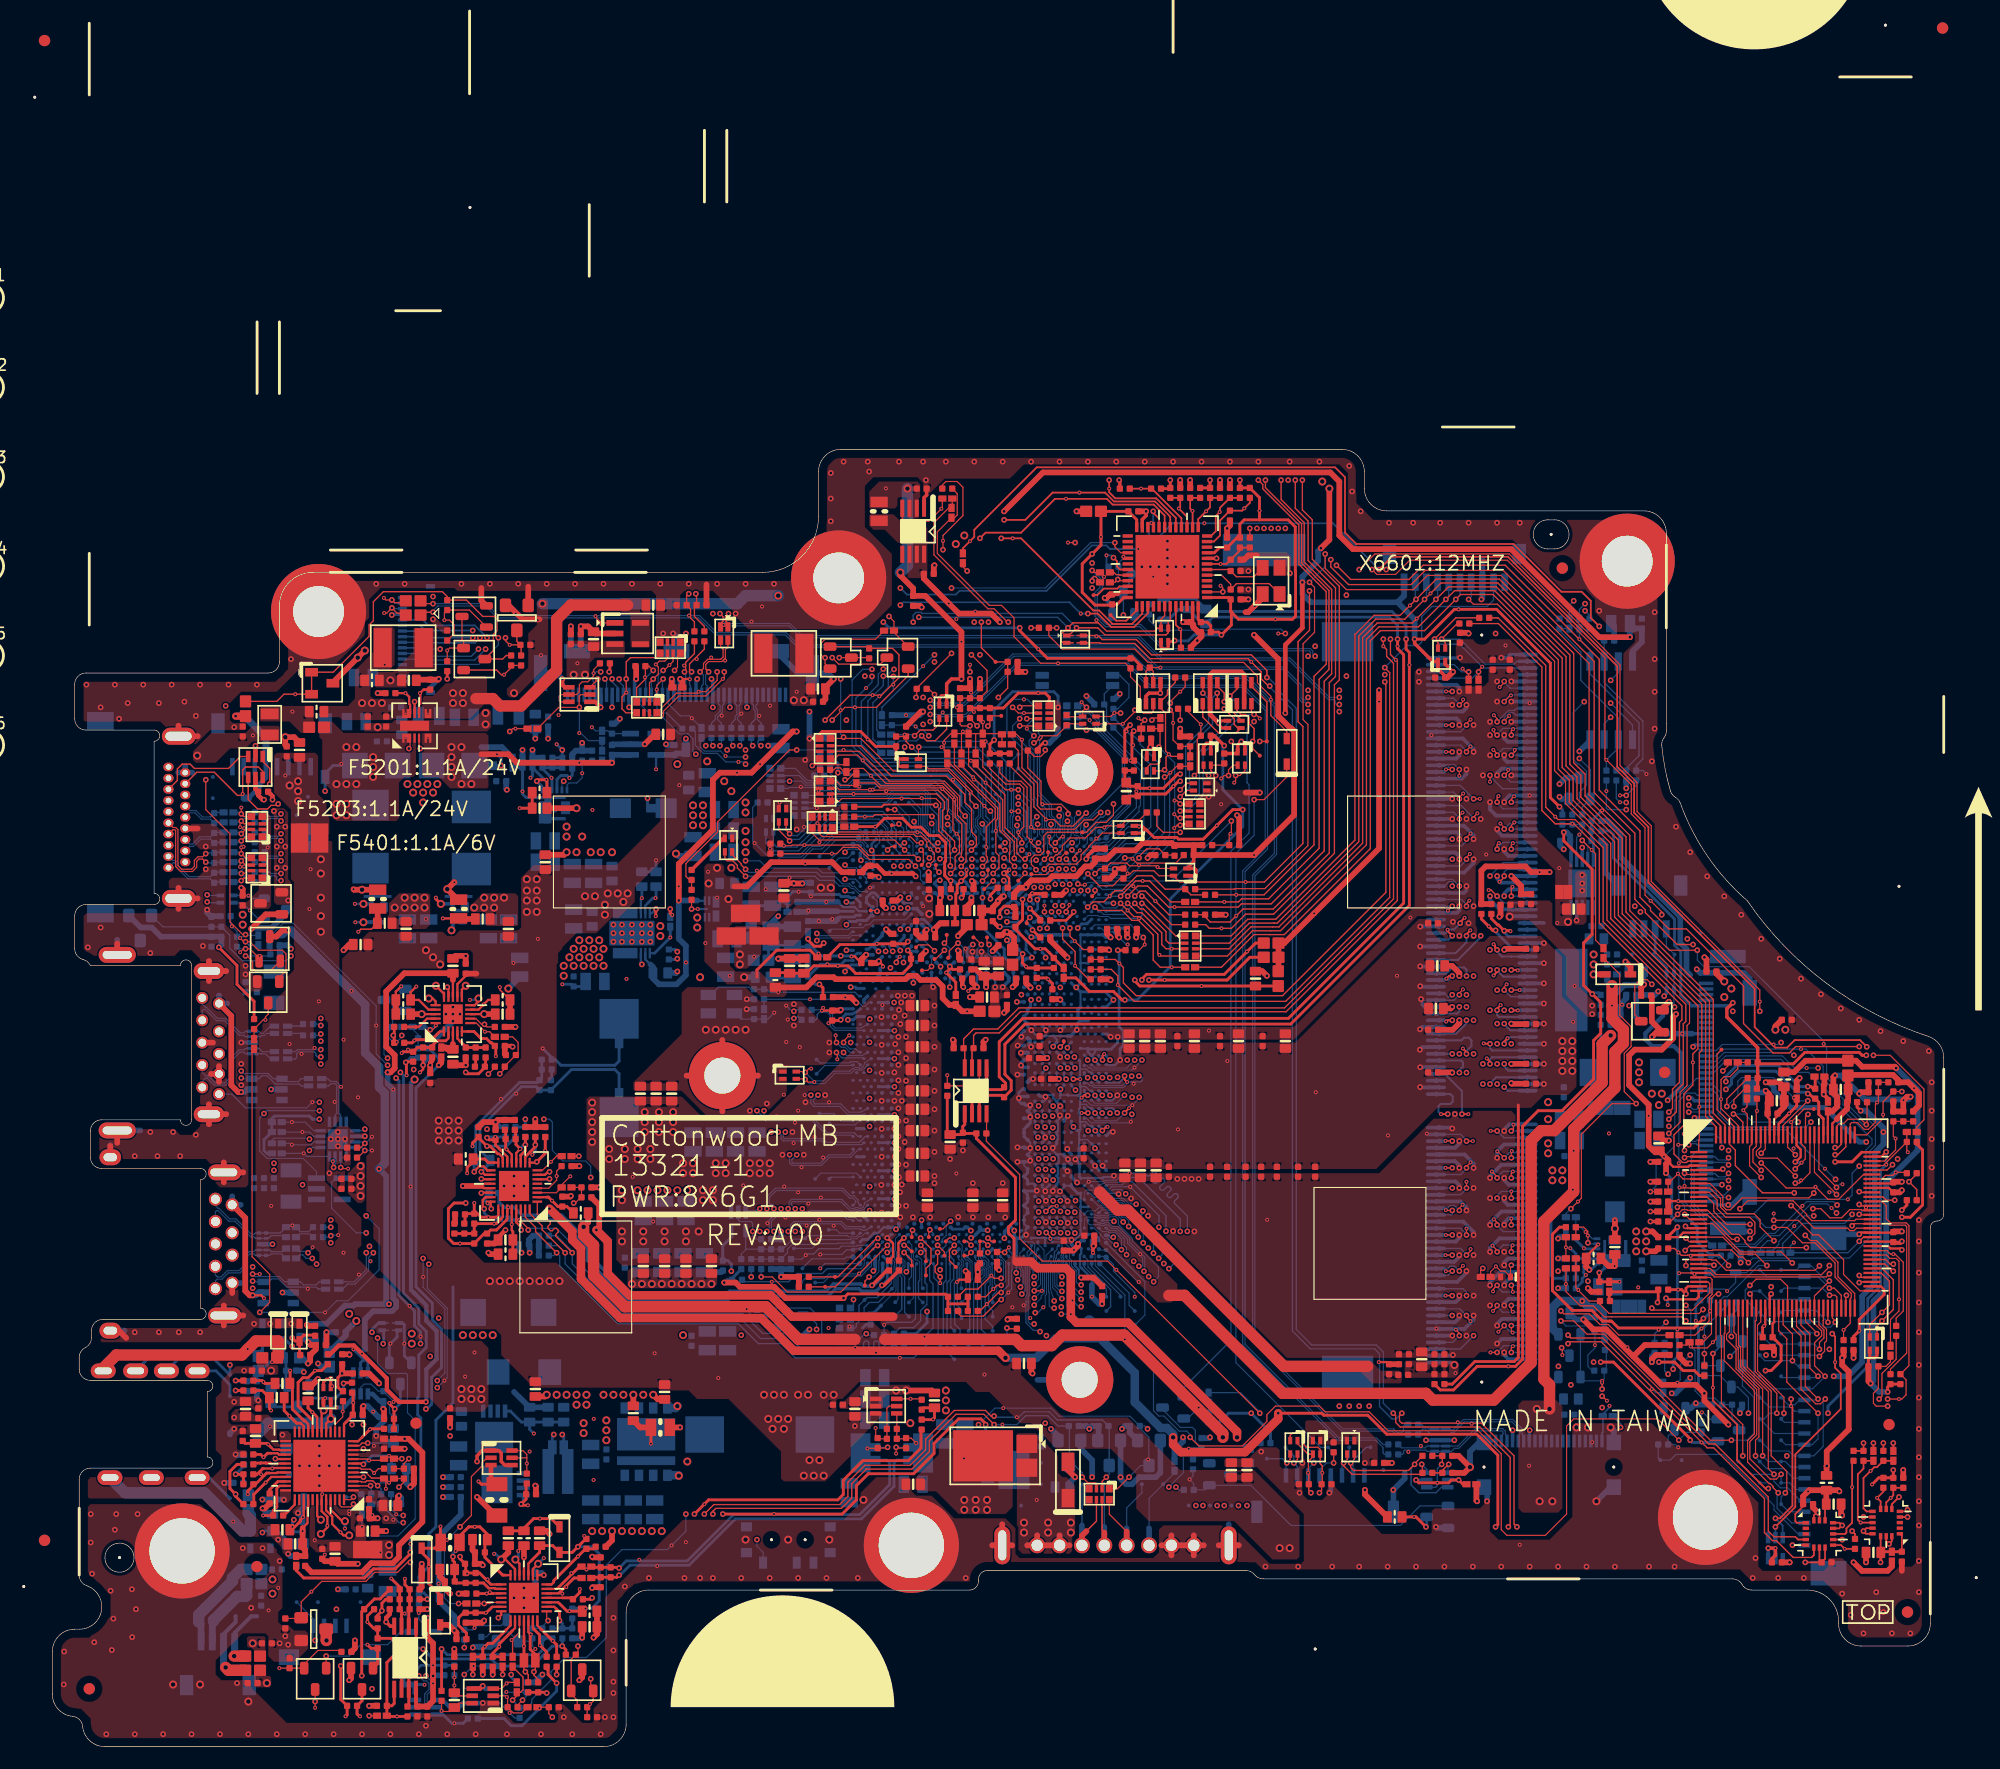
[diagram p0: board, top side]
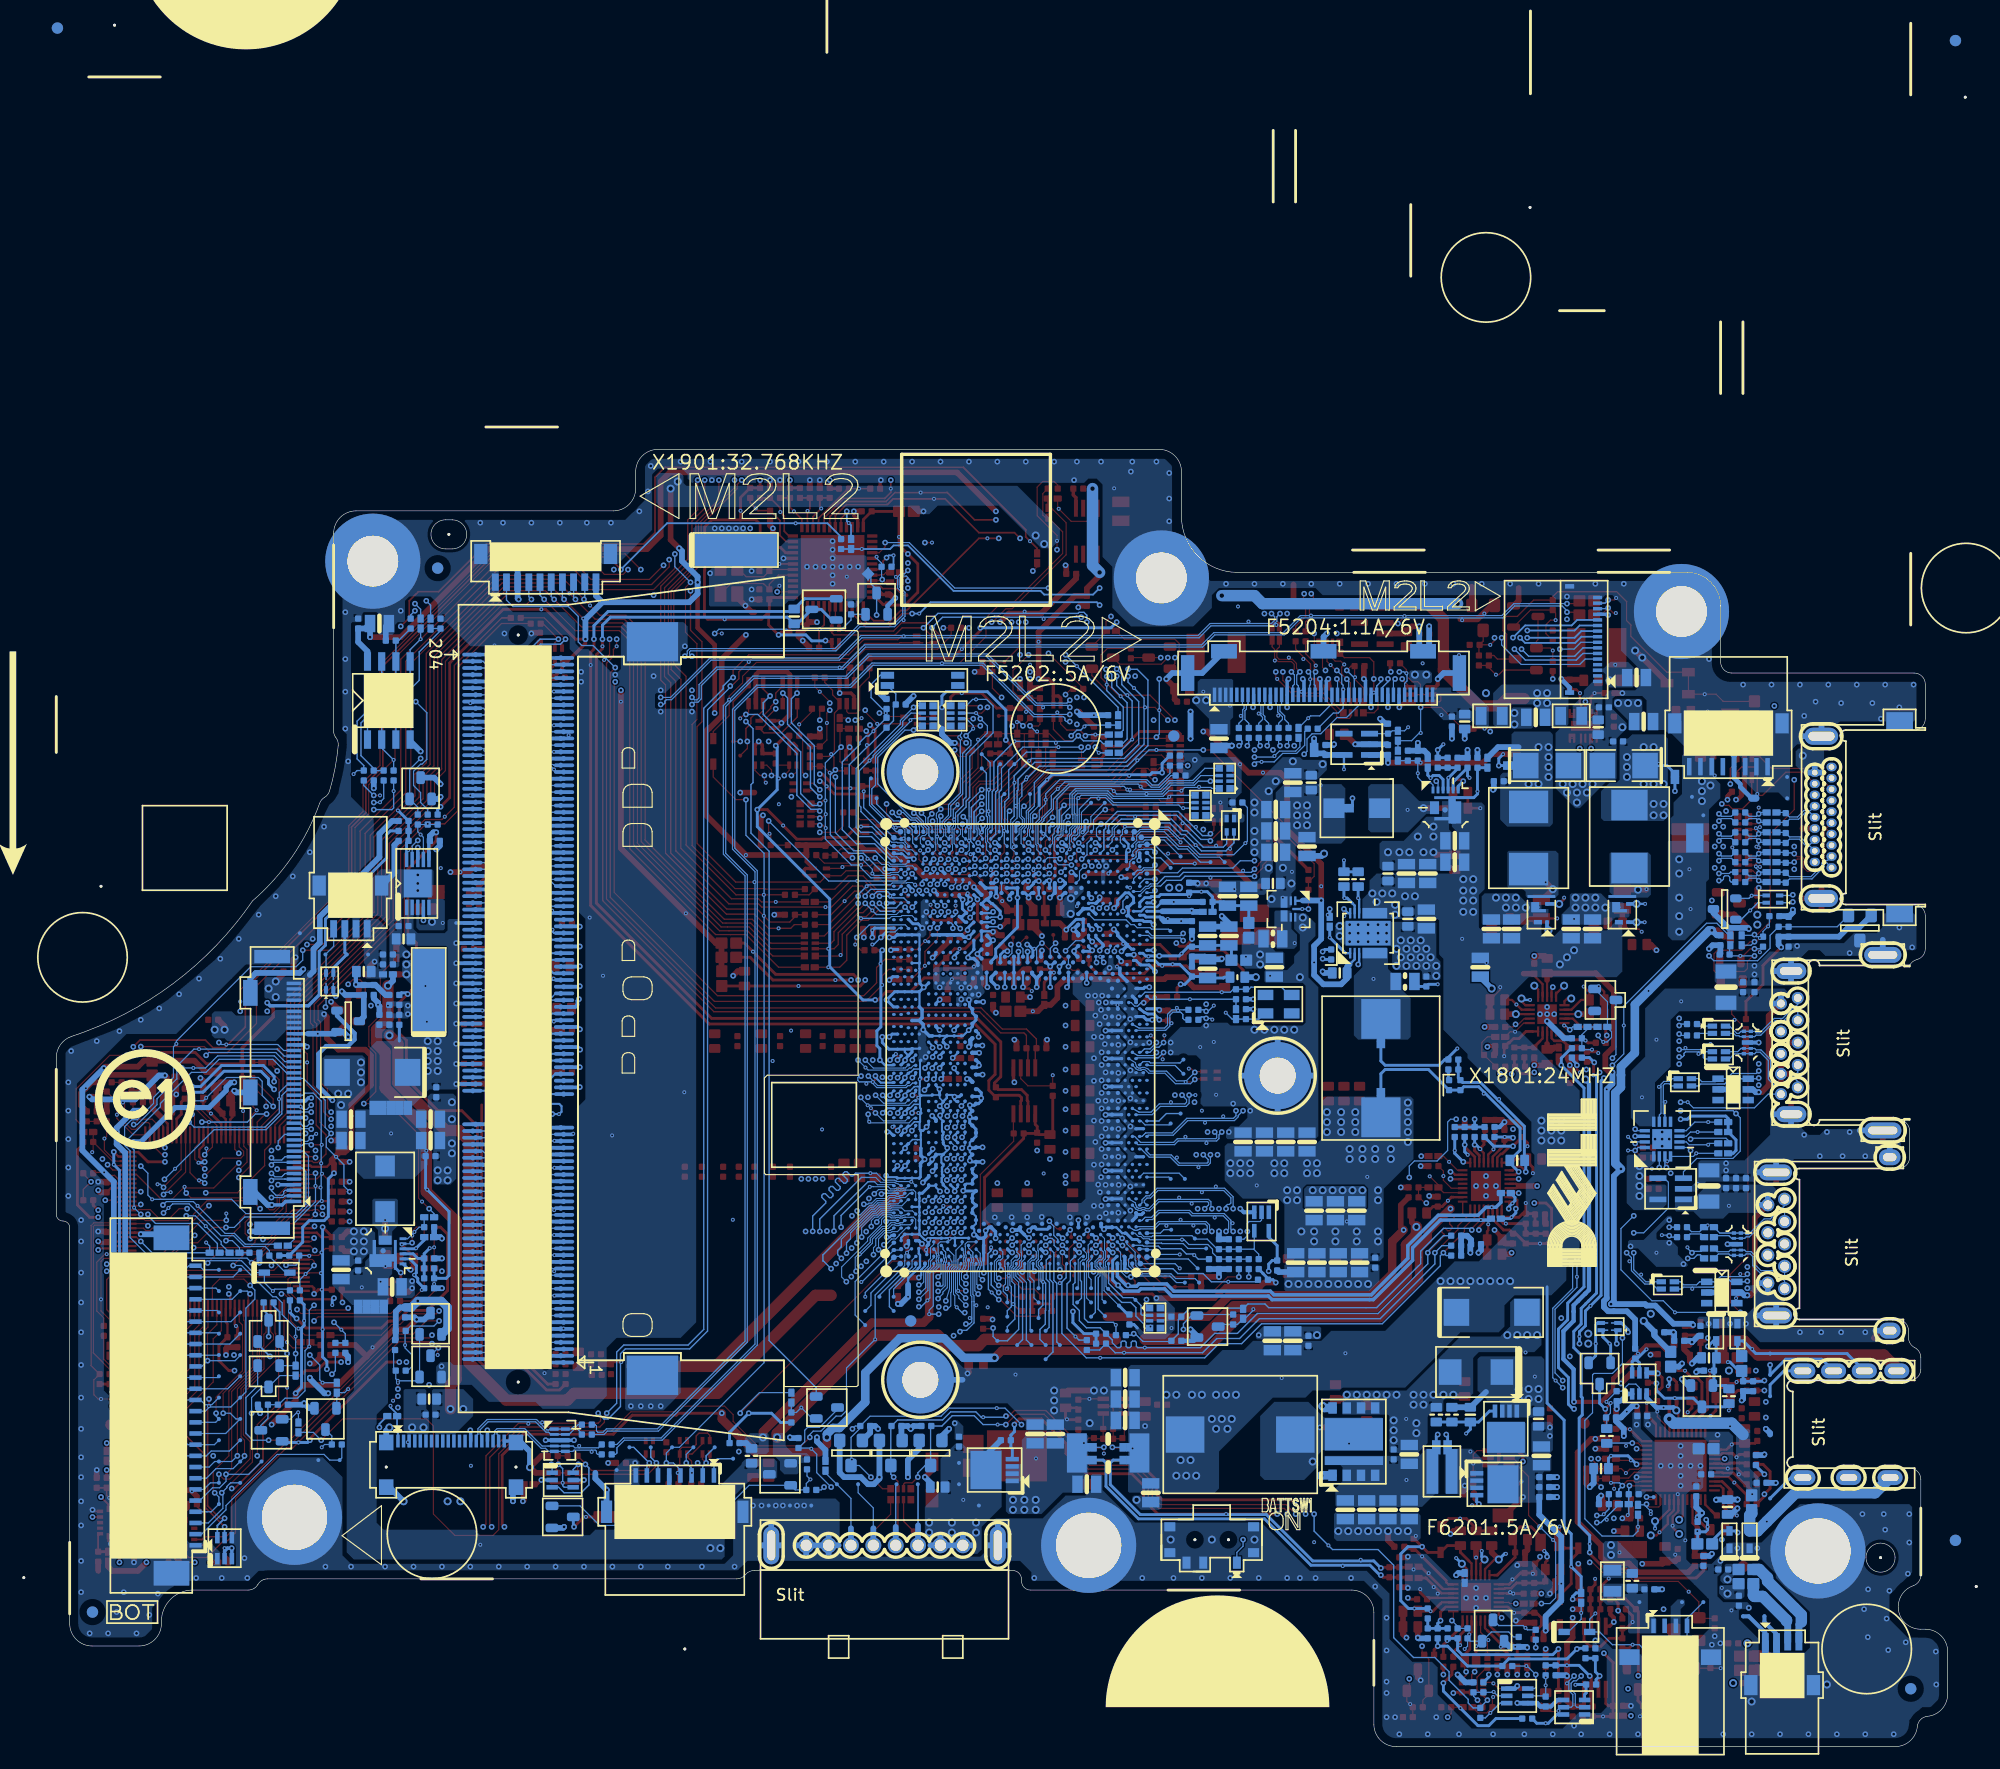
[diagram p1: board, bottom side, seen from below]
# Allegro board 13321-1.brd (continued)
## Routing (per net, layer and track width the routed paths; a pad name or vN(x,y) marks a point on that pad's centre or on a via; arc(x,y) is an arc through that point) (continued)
BOARD_ID1: length 18.8
  BOTTOM w0.089: CPU1.U4 81.43,80.2 81.43,80.58 81.52,80.67 81.52,82.63 81.21,82.93 81.21,83.73 81.15,83.79
  BOTTOM w0.102: 81.15,83.79 80.64,84.3 v1(80.64,84.68) 80.64,85.21 79.38,86.47 71.6,86.47 71.12,85.99 70.57,85.99 69.53,87.03 R2023.2
BOOST_MON: length 184
  TOP w0.203: 161.78,53.16 KBC24.96
  TOP w0.254: 161.78,53.16 160.91,52.29 v2(159.38,52.29) ; v2(57.4,20.8) v1(58.29,21.68) 58.67,22.07 70.23,22.07 70.71,22.55 70.71,23.82 72.46,25.57 76.53,25.57 77.66,26.7 77.66,28.29 PR4452.1 ; PR4434.2 v2(37.59,6.44)
  L3 w0.254: v2(57.4,20.8) 55.13,18.53 46.75,18.53 45.97,17.75 45.97,11.06 44.28,9.37 40.51,9.37 v2(37.59,6.44)
  L4 w0.254: v2(159.38,52.29) 157.99,50.89 157.99,44.54 155.12,41.68 155.12,40.61 154.05,39.54 149.94,39.54 143.27,32.87 138.58,32.87 132.55,26.84 126.41,26.84 125.44,25.88 106.73,25.88 88.6,25.88 84.29,30.19 81.66,30.19 79.25,27.78 79.25,24.54 78.67,23.96 72.68,23.96 70.02,21.3 57.91,21.3 v2(57.4,20.8)
BOOST_MON_1: length 3.3
  TOP w0.254: PR4452.2 78.71,29.24 v1(78.74,29.27) 78.87,29.39 PC4417.1 77.89,30.3 PR4446.1
BQ24770_AGND: length 8.8
  TOP w0.508: PC4410.2 37.57,17.58 PC4433.2 PC4416.1 38.35,16.35 v2(38.48,16.22) ; v2(48.26,16.99) 48.32,16.92 PC4401.2 ; v2(48.26,14.19) 48.32,14.26 PC4412.2 ; PR4411.2 PC4402.2 38.42,11.08 v2(38.61,11.27) ; PC4432.2 34.65,15.22 PC4418.1 35.09,14.15 v2(35.56,13.68)
  vias: v1(37.08,15.46) v1(39.12,13.81) v1(45.59,13.68) v1(47.75,15.84) v2(41.27,13.3) v2(42.16,14.19) v2(42.16,13.3) v2(42.16,12.41) v2(43.05,13.3)
BQ24770_IADP: length 22
  TOP w0.203: PU4401.7 40.13,11.78 v2(39.88,11.52)
  TOP w0.254: PC4435.1 PR4466.1 29.97,2.7 v1(30.81,2.7) PR4422.2 ; PC4435.1 30.35,3.65 30.57,3.86 PU4402.5 ; PC4435.1 29.91,7.52 v2(30.73,8.35)
  L3 w0.254: v2(30.73,8.35) 30.86,8.22 38.1,8.22 39.88,10 v2(39.88,11.52)
BQ24770_IDCHG: length 5.4
  TOP w0.203: 40.58,10.45 40.96,10.83 PU4401.8
  TOP w0.254: PR4434.1 PC4436.1 38.48,8.76 v1(38.66,8.93) 38.96,9.24 39.37,9.24 40.58,10.45
BQ24770_PMON: length 5
  TOP w0.203: PU4401.9 41.36,10.6 41.15,10.38
  TOP w0.254: 41.15,10.38 39.95,9.19 v1(39.95,8.93) 39.37,8.35 PC4437.1 PR4467.1
BT+: length 104
  TOP w0.508: BATT1.1 88.05,18.89 ; BATT1.1 88.94,18 ; BATT1.1 87.16,18 ; v2(48.39,9.75) 48.69,10.05 PC4438.1 PR4408.1 ; v2(33.02,16.35) PD4405.A 33.02,14.26 PR4442.1 ; 89.16,18 BATT1.2 ; BATT1.2 90.94,18 ; BATT1.2 90.05,18.89
  L3 w0.508: v3(86.87,20.03) 86.74,20.03 83.97,22.8 75.29,22.8 69.09,16.6 50.41,16.6 48.9,15.09 48.9,10.25 v2(48.39,9.75) 48.38,9.75 47.72,9.09 47.72,8.32 45.85,6.44 45.85,5.55 43.44,3.14 33.02,3.14 30.99,5.17 v2(28.57,5.17)
  L4 w0.508: v2(28.57,5.17) 29.84,6.44 29.84,9.49 31.5,11.14 31.5,13.3 33.02,14.83 v2(33.02,16.35)
  BOTTOM w0.508: PU4403.5 85.98,26.07 PC4424.1 ; 89.16,18 BATT1.2 ; BATT1.2 90.94,18 ; BATT1.2 90.05,18.89 ; 87.16,18 BATT1.1 ; BATT1.1 88.94,18 ; BATT1.1 88.05,18.89
  vias: v1(88.01,22.07) v3(86.87,19.14) v3(89.03,20.03) v3(89.03,19.14) v3(91.06,20.03) v3(91.06,19.14)
CAMERA_DET#: length 47.4
  TOP w0.102: R2013.1 65.27,80.56 66.09,80.56 66.14,80.61 v1(67.23,80.61) 72.07,80.61 72.98,79.7 77.08,79.7 v2(77.42,79.37)
  L3 w0.102: v2(77.42,79.37) 73.08,79.37 72.76,79.69 71.23,79.69 71.09,79.55 70.52,79.55 66.99,83.08 66.12,83.08 60.5,88.69 57.58,88.69 v2(57.53,88.74)
  BOTTOM w0.102: v2(57.53,88.74) 57.28,88.99 57.28,90.11 56.82,90.57 56.04,90.57 54.59,92.02 53.74,92.02 52.55,93.21 LCD1.27 ; CPU1.J2 76.95,80.78 76.95,79.75 77.33,79.37 v2(77.42,79.37)
CAMERA_PWR_EN: length 4.7
  BOTTOM w0.089: 88.9,82.69 88.88,82.67 88.88,82.3 89.01,82.17 89.01,80.68 88.97,80.64 88.97,80.15 CPU1.AM4
  BOTTOM w0.102: TP2002.1 88.9,83.79 88.9,82.69
CAP_LED: length 17.7
  BOTTOM w0.102: KB1.2 156.1,19 153.92,21.18 153.92,21.56 149.35,26.13 145.16,26.13 144.65,25.62 AFTP6233.1 143.57,25.81 R6201.2
CAP_LED#: length 34.1
  TOP w0.102: v2(155.83,51.66) 156.72,52.55 156.72,53.56 156.34,53.94 KBC24.109
  L3 w0.102: v2(153.21,35.02) 153.21,35.96 156.97,39.72 156.97,43.75 157.45,44.23 157.45,45.88 156.69,46.64 156.69,50.79 v2(155.83,51.66)
  L4 w0.102: v2(153.21,35.02) 152.65,34.46 146.99,34.46 v2(146.43,35.02)
  BOTTOM w0.102: R6202.1 v1(145.29,32.54) 145.54,32.8 145.54,34.13 v2(146.43,35.02)
CAP_LED_Q: length 2.6
  BOTTOM w0.102: Q6201.C 144.46,27.78 R6201.1 145.11,27.02 v1(145.36,26.76)
CAP_LED_R#: length 2.6
  BOTTOM w0.102: v1(143,31.97) 143.32,31.65 R6202.2 144.02,30.29 Q6201.B
CARD_PWR_EN: length 16.7
  BOTTOM w0.089: 88.49,82.78 88.49,82.22 88.26,81.99 88.26,81.59 88.55,81.3 CPU1.AL2
  BOTTOM w0.102: RN1809.8 87.75,93.07 87.17,93.64 v1(86.87,93.64) 85.93,93.64 85.34,93.06 85.34,90.65 87.43,88.56 87.43,84.88 87.76,84.55 87.76,84.02 88.49,83.28 88.49,82.78
CBN: length 4.3
  TOP w0.203: 20.07,23.07 20.31,23.31 HDA27.35
  TOP w0.254: 20.07,23.07 20.07,21.43 19.75,21.11 C2703.1 v1(18.85,20.67)
CBP: length 1.9
  TOP w0.203: HDA27.37 21.68,21.64 21.15,21.11
  TOP w0.254: C2703.2 20.7,20.67 21.15,21.11
CFG0: length 1.2
  TOP w0.114: v2(83.65,45.47) 83.94,45.18 TP9626.1
  BOTTOM w0.089: CPU1.AC60 83.71,45.47 v2(83.65,45.47)
CFG1: length 4.5
  BOTTOM w0.089: 84.33,40.61 84.44,40.72 84.44,41.17 84.24,41.37 84.24,42.88 84.3,42.94 84.3,43.41 84.01,43.7 CPU1.AC62
  BOTTOM w0.114: TP9627.1 84.07,40.35 84.33,40.61
CFG2: length 2.2
  BOTTOM w0.089: TP9620.1 84.02,41.04 84.02,42.97 84.01,42.98 CPU1.AC63
CFG3: length 10.7
  TOP w0.114: v2(85.34,37.43) 85.41,37.37 R604.1
  BOTTOM w0.089: CPU1.AA63 83.26,42.98 83.49,42.76 83.49,42.75 83.49,41.95 83.06,41.52 83.06,41.18
  BOTTOM w0.114: v2(85.34,37.43) 85.34,36.67 TP9622.1 84.07,36.29 83.06,37.31 83.06,41.18
CFG4: length 2.5
  TOP w0.114: v2(83.63,44.84) 83.29,45.18 TP9630.1 R605.1
  BOTTOM w0.089: v2(83.63,44.84) 83.33,45.14 CPU1.AA60
CFG5: length 8.7
  BOTTOM w0.089: CPU1.Y62 82.51,43.61 82.8,43.32 82.8,42.94 83.13,42.61 83.13,42.6 83.13,42.27 82.37,41.5 82.37,41.16
  BOTTOM w0.114: 82.37,41.16 82.37,36.36 TP9631.1
CFG6: length 1.3
  TOP w0.114: v2(82.14,44.19) 81.86,43.91 TP9629.1
  BOTTOM w0.102: v2(82.14,44.19) 82.14,44.19 82.43,44.49 CPU1.Y61
CFG7: length 10
  BOTTOM w0.089: CPU1.Y60 82.84,44.85 82.84,44.19 82.8,44.15 82.8,43.57 82.98,43.39 82.98,43.02 83.31,42.68 83.31,42.67 83.31,42.09 82.71,41.49 82.71,41.12
  BOTTOM w0.114: TP9628.1 82.71,36.39 82.71,41.12
CFG8: length 7
  BOTTOM w0.089: CPU1.V62 81.92,43.68 81.94,43.68 82.23,43.39 82.23,41.78 82.02,41.57
  BOTTOM w0.114: TP9633.1 82.02,37.29 82.02,41.57
CFG9: length 5.5
  BOTTOM w0.089: TP9632.1 81.69,40.13 81.69,41.66 82.05,42.01 82.05,43.32 81.87,43.5 81.68,43.5 81.48,43.7 81.48,44.24 CPU1.V61
CFG10: length 1.3
  TOP w0.114: TP9637.1 81.79,45.18 v2(82.14,44.84)
  BOTTOM w0.102: CPU1.V60 81.83,45.14 v2(82.14,44.84)
CFG11: length 4.5
  BOTTOM w0.089: CPU1.U60 81.34,44.85 81.34,44.36 81.3,44.32 81.3,43.58 81.48,43.4 81.48,42.98 81.25,42.75 81.25,41.02 TP9639.1
CFG12: length 8.9
  BOTTOM w0.114: TP9640.1 79.99,35.29 79.99,41.49 80.27,41.76 CPU1.T63
CFG13: length 7.1
  BOTTOM w0.114: TP9643.1 80.33,37.49 80.33,38.97 80.3,39 80.3,41.51 80.59,41.8 80.59,43.51 CPU1.T62
CFG14: length 8.9
  BOTTOM w0.114: TP9642.1 79.65,36.18 79.65,41.43 79.91,41.69 79.91,44.17 CPU1.T61
CFG15: length 2.9
  TOP w0.114: TP9641.1 80.21,43.46 80.21,44.4 v2(80.64,44.83)
  BOTTOM w0.114: v2(80.64,44.83) 80.33,45.14 CPU1.T60
CFG16: length 5.9
  BOTTOM w0.089: CPU1.AA62 83.38,43.84 83.73,43.49 83.73,43.02 83.84,42.9 83.84,41.27 83.71,41.14
  BOTTOM w0.114: TP9635.1 84.07,38.98 83.71,39.34 83.71,41.14
CFG17: length 8.2
  BOTTOM w0.089: CPU1.AA61 83.22,44.21 83.22,44.21 82.98,43.97 82.98,43.7 83.18,43.5 83.37,43.5 83.55,43.32 83.55,42.95 83.67,42.83 83.67,41.6 83.4,41.33
  BOTTOM w0.114: TP9634.1 84.07,37.56 83.4,38.23 83.4,41.33
CFG18: length 7.9
  BOTTOM w0.114: TP9636.1 81.15,36.42 81.15,37.31 80.68,37.78 80.68,38.97 80.64,39 80.64,41.44 80.88,41.68 80.88,42.9 81.01,43.03 CPU1.U63
CFG19: length 6
  BOTTOM w0.089: CPU1.U62 81.01,43.6 81.02,43.6 81.3,43.32 81.3,43.05 81.07,42.82 81.07,41.58 80.9,41.41
  BOTTOM w0.114: 80.9,41.41 80.9,39.46 81.28,39.08 TP9638.1
CFG_RCOMP: length 2.6
  TOP w0.203: v1(80.87,41.55) 81.08,41.75 R601.2
  TOP w0.508: R601.2 81.85,42.31 v2(81.65,42.51)
  BOTTOM w0.178: CPU1.V63 81.76,42.63 v2(81.65,42.51)
CHARGER_CELL_PIN: length 31.6
  TOP w0.203: 45.02,12.35 44.87,12.5 PU4401.16
  TOP w0.254: v2(25.78,7.21) 25.78,4.22 PR4464.1 26.35,2.85 v1(26.21,2.71) ; v2(45.34,11.27) 45.34,12.03 45.02,12.35
  L3 w0.254: v2(25.78,7.21) 26.42,7.84 38.38,7.84 40.42,9.87 43.94,9.87 v2(45.34,11.27)
  BOTTOM w0.254: v2(45.34,11.27) 45.59,11.02 PR4468.2 ; PR4449.2 PR4445.1 PR4468.2 ; PR4424.2 PR4468.2
CHARGER_SRC:
  vias: v1(48.39,23.84)
CHG_AMBER_LED#: length 14.6
  TOP w0.102: v2(145.94,47.59) 146.38,47.16 KBC24.16
  BOTTOM w0.102: IOBD1.20 147.05,58.25 146.86,58.44 146.12,58.44 145.41,57.73 v1(145.41,52.16) 145.41,48.91 145.94,48.38 v2(145.94,47.59)
CHG_CMPIN_1: length 3.7
  TOP w0.203: 43.05,10.51 42.96,10.6 PU4401.13
  TOP w0.254: 43.05,10.51 43.56,10 43.56,9.1 v1(43.59,9.07) 44.2,8.47 PR4413.2
CHG_CMPOUT_1: length 4
  TOP w0.203: PU4401.14 43.36,10.83 43.69,10.51
  TOP w0.254: PR4415.2 45.09,9.11 v1(44.75,9.45) 43.69,10.51
CLK_PCI_KBC: length 120.1
  TOP w0.114: R1805.2 EC1801.1 95.03,70.39 v1(95.4,70.02) 95.76,69.67 95.76,68.29 96.9,67.15 109.98,67.15 119.22,76.39 119.22,95.12 v2(119.13,95.22) ; v2(145.92,52.67) 146.01,52.76 KBC24.2
  L4 w0.127: v2(119.13,95.22) 119.57,95.66 128.46,95.66 128.87,96.08 130.24,96.08 131.65,94.67 131.65,73.5 132.74,72.41 132.74,60.83 134.76,58.81 142.15,58.81 142.62,59.28 144.15,59.28 145.36,58.06 145.36,53.23 v2(145.92,52.67)
CLK_PCI_KBC_R: length 3.7
  TOP w0.114: R1805.1 92.16,71.28 v1(91.41,72.03) 90.98,72.46 v2(90.98,73.2)
  BOTTOM w0.114: CPU1.AP15 90.64,73.54 v2(90.98,73.2)
CLK_PCI_LPC: length 68.1
  TOP w0.114: v2(119.13,96.49) 119.13,96.47 119.56,96.03 119.56,75.94 110.26,66.64 96.72,66.64 v1(95.26,68.1) 95.26,68.92 94.68,69.5 EC1802.1 R1804.2
  BOTTOM w0.114: DB1.2 128.85,102.53 128.27,101.95 123.32,101.95 122.43,101.06 122.43,98.77 122.12,98.46 121.1,98.46 v2(119.13,96.49)
CLK_PCI_LPC_R: length 6.4
  TOP w0.114: R1804.1 92.65,68.61 v1(91.44,69.82) 91.44,71.09 90.32,72.21 v2(90.32,73.2)
  BOTTOM w0.114: CPU1.AN15 89.99,73.53 v2(90.32,73.2)
CLK_PCIE_REQ#: length 26.7
  TOP w0.102: v2(80.03,83.09) 80.03,83.64 80.1,83.71 80.1,84.63 79.2,85.53 73.14,85.53 v1(73.1,85.57) 70.35,85.57 70.23,85.69 RN1902.3
  L3 w0.102: v2(82.21,79.36) 81.77,79.79 80.97,79.79 80.57,79.39 v2(79.36,79.39)
  L4 w0.102: v2(80.03,83.09) 79.54,83.09 78.99,82.54 v2(78.61,82.54) 78.61,80.12 79.35,79.39 v2(79.36,79.39)
  BOTTOM w0.102: v2(78.61,82.54) 78.81,82.35 CPU1.N1 ; v2(80.03,83.09) 80.63,82.49 80.63,81.49 ; v2(82.21,79.36) 82.51,79.36 CPU1.Y5 ; CPU1.T2 80.63,81.49 ; 80.63,81.49 80.96,81.16 CPU1.U2 ; CPU1.U5 80.46,79.5 79.46,79.5 v2(79.36,79.39)
CLK_PCIE_WLAN_N3: length 151.9
  L4 w0.102: v2(68.45,58.26) 68.45,58.57 68.33,58.69 68.17,58.69 68.05,58.82 68.05,60.7 67.54,61.2 67.54,63.89 70.83,67.18 71.98,67.18 73.42,68.62 73.42,71.39 74.45,72.42 76.71,72.42 76.99,72.14 76.99,69.34 77.93,68.4 92.3,68.4 92.96,69.06 98.43,69.06 118.08,88.72 118.08,96.49 118.73,97.14 119.63,97.14 120.14,96.63 130.47,96.63 132.17,94.93 132.17,73.79 132.74,73.22 133.99,71.98 133.99,65.88 138.05,61.82 143.18,61.82 146.77,58.23 146.77,57.3 146.67,57.19 146.48,57.19 v2(146.3,57.37)
  BOTTOM w0.102: 69.44,57.47 70.48,57.47 71.22,56.74 72.29,56.74 CPU1.C41 ; 69.44,57.47 68.19,57.47 68.05,57.62 68.05,57.85 v2(68.45,58.26) ; 69.44,57.47 v1(69.44,57.63) ; IOBD1.18 147.27,57.25 147,56.98 146.7,56.98 v2(146.3,57.37)
CLK_PCIE_WLAN_P3: length 152.7
  L4 w0.102: v2(146.3,56.74) 146.53,56.97 146.76,56.97 147,57.2 147,58.32 143.27,62.05 138.14,62.05 137.64,62.55 134.21,65.98 134.21,72.07 132.83,73.45 132.4,73.89 132.4,95.02 130.56,96.86 120.24,96.86 119.73,97.36 118.64,97.36 117.86,96.58 117.86,88.81 98.34,69.29 92.87,69.29 92.2,68.62 78.03,68.62 77.22,69.44 77.22,72.23 76.8,72.64 74.35,72.64 73.19,71.48 73.19,68.71 71.88,67.4 70.74,67.4 67.32,63.98 67.32,61.11 67.82,60.6 v2(67.82,58.26)
  BOTTOM w0.102: CPU1.B42 71.13,56.51 70.39,57.24 68.1,57.24 67.82,57.52 v2(67.82,58.26) v1(67.26,58.26) ; v2(146.3,56.74) 146.32,56.75 IOBD1.17
CLK_PCIE_WLAN_REQ3#: length 157.2
  TOP w0.102: RN1801.4 77.43,89.34 v2(77.47,89.38)
  L3 w0.102: v2(77.47,89.38) 76.66,90.19 76.66,94.79 78.41,96.54 78.41,98.7 81.72,102.01 86.58,102.01 93.98,109.42 101.04,109.42 101.63,110 113.86,110 116.98,106.88 129.68,106.88 140.52,96.04 140.52,86.53 141.15,85.9 141.15,79.85 157.39,63.61 157.39,56.01 v2(157.23,55.85)
  BOTTOM w0.102: CPU1.AD1 84.8,85.36 84.59,85.57 84.59,87.46 82.68,89.38 v1(79.5,89.38) v2(77.47,89.38) ; IOBD1.22 148.4,59.25 149.16,58.49 149.16,56.68 150.44,55.4 155.9,55.4 155.9,55.4 156.77,55.4 v2(157.23,55.85)
CODEC_BITCLK_R: length 3.1
  TOP w0.114: HDA27.6 27.52,24.91 27.63,24.8 28.43,24.8 v1(28.77,24.46) 29.17,24.86 R2720.2
CODEC_SDOUT_R: length 4
  TOP w0.114: HDA27.5 27.61,24.51 27.63,24.54 28.01,24.54 28.53,24.02 29.61,24.02 R2719.2 29.82,23.81 v1(29.82,23.06)
COLOR_ENGINE: length 1.3
  TOP w0.102: TP2003.1 74.98,80.49 v2(74.68,80.18)
  BOTTOM w0.102: v2(74.68,80.18) 74.34,80.51 CPU1.E3
COMBO-GPI: length 1.6
  TOP w0.102: HDA27.48 26.69,22.09 v2(26.92,22.32)
  BOTTOM w0.102: TP2702.1 v2(26.92,22.32)
CPVEE: length 2.1
  TOP w0.203: 20.16,23.71 HDA27.34
  TOP w0.254: 20.16,23.71 19.43,22.98 C2704.2
CTL1: length 3.6
  BOTTOM w0.102: U3503.6 23.37,54.07 23.11,53.82 v1(21.41,53.82) 21.29,53.94 R3501.2
CTL2: length 3.6
  BOTTOM w0.102: R3507.2 v1(22.35,54.96) 22.99,54.96 23.37,54.57 U3503.7
CTL3: length 3.8
  BOTTOM w0.102: U3503.8 23.38,55.07 22.61,55.85 v1(21.41,55.85) R3504.2
DBC_EN: length 35.6
  TOP w0.102: v2(77.69,80.81) 77.27,80.81 76.71,81.37 68.83,81.37 68.58,81.63 RN2011.6
  L3 w0.102: v2(61.98,88.49) 66.98,83.48 70.66,83.48 74.4,79.75 76.62,79.75 v2(77.69,80.81)
  BOTTOM w0.102: CPU1.K3 77.39,80.51 v2(77.69,80.81) ; v2(61.98,88.49) 60.28,88.49 v1(60.19,88.58) 59.75,89.02 58.29,89.02 57.91,89.4 57.91,90.07 R5201.2
DBC_EN_R: length 4.7
  BOTTOM w0.102: R5201.1 v1(57.17,91.96) 56.96,92.17 56.13,92.17 55.05,93.25 LCD1.22
DC_IN_D: length 3.7
  TOP w0.254: 39.75,23.46 38.35,23.46 v1(38.1,23.72)
  TOP w0.406: PQ4407.3 39.22,24 39.75,23.46
DC_TEST_A3_B3: length 5.7
  BOTTOM w0.102: v1(67.31,78.96) 69.22,78.96 70.93,80.68 CPU1.A3 72.11,80.68 CPU1.B3
DC_TEST_A61_B61: length 3.8
  BOTTOM w0.102: v1(68.66,44.01) 70.59,44.01 71,44.43 CPU1.A61 71.66,44.5 CPU1.B61
DC_TEST_AY2_AW2: length 6
  BOTTOM w0.102: CPU1.AW2 94.1,81.15 CPU1.AY2 96.91,83.97 v1(96.91,85.42)
DC_TEST_AY3_AW3: length 4.3
  BOTTOM w0.102: v1(97.16,82.26) 96.19,82.26 94.47,80.55 CPU1.AY3 93.61,80.55 CPU1.AW3
DC_TEST_AY61_AW61: length 4.8
  BOTTOM w0.102: CPU1.AW61 93.64,44.41 CPU1.AY61 97.07,41.55 v1(97.13,41.55)
DC_TEST_AY62_AW62: length 5.3
  BOTTOM w0.102: CPU1.AW62 94.13,43.84 CPU1.AY62 94.87,43.1 94.87,42.51 96.77,40.61 v1(96.77,40.23)
DC_TEST_B62_B63: length 4.4
  BOTTOM w0.102: CPU1.B62 72.31,43.32 CPU1.B63 69.08,43.19 v1(68.66,42.77)
DC_TEST_C1_C2: length 5.4
  BOTTOM w0.102: CPU1.C2 72.84,81.69 CPU1.C1 72.41,81.81 72.22,82 69.72,82 v1(68.58,80.87)
DCBATOUT: length 33.8
  TOP w0.203: PC4531.1 36.96,68.93 36.21,68.19 PU4503.12
  TOP w0.254: PR4465.1 v2(33.53,13.18)
  TOP w0.508: PC4531.1 37.91,69.12
  BOTTOM w0.254: 35.81,41.12 35.81,30.72 34.29,29.19 34.29,19.65 33.66,19.02 v1(33.66,16.1) 32.77,15.21 PR4458.1 33.21,13.75 33.53,13.43 v2(33.53,13.18)
  vias: v1(32.03,50.08) v1(41.22,70.07) v1(43.41,72.23) v1(53.85,35.17) v1(56.06,85.97) v1(59.54,32.96) v1(64.16,93.08) v1(97.97,25.67) v1(131.19,18.05) v1(140.82,35.71) v2(71.75,28.67) v3(33.4,71.21) v3(34.04,70.58) v3(34.54,55.97) v3(34.54,55.09) v3(34.54,54.2) v3(34.67,69.94) v3(35.43,55.97) v3(35.43,55.09) v3(35.43,54.2) v3(36.32,55.97) v3(36.32,55.09) v3(36.32,54.2) v3(39.12,41.62) v3(40.01,41.62) v3(40.89,41.62) v3(41.78,41.62) v3(42.42,77.56) v3(42.42,76.55) v3(42.42,75.66) v3(42.42,74.64) v3(42.67,41.62) v3(43.31,77.56) v3(43.31,76.55) v3(43.31,75.66) v3(43.31,74.64) v3(43.56,41.62) v3(44.45,41.62) v3(45.34,41.62) v3(47.62,76.04) v3(48.51,76.04) v3(49.4,75.28) v3(49.4,74.39) v3(49.66,76.29) v3(50.55,76.29) v3(51.05,75.53) v3(51.44,76.29) v3(63.63,31.46) v3(64.01,29.3) v3(64.39,28.42) v3(64.52,31.46) v3(64.9,29.3) v3(65.41,31.46) v3(65.41,28.42) v3(65.79,29.3) v3(66.67,31.46) v3(67.18,24.22) v3(67.56,31.46) v3(67.69,25.62) v3(68.07,24.22) v3(68.58,25.62) v3(68.96,31.46) v3(68.96,24.22) v3(69.85,31.46) v3(109.73,17.75) v3(110.62,17.75)
DCBATOUT_LCD:
  vias: v1(66.55,94.33) v3(66.29,93.57) v3(67.18,93.57)
DCBATOUT_R: length 2.8
  TOP w0.102: v2(74.68,26.76) 74.61,26.7 PR4448.1 73.75,26.66 v1(72.87,26.66)
  BOTTOM w0.102: v2(74.68,26.76) PG4404.1
DCBATOUT_SNUB: length 3.3
  TOP w0.254: v1(53.52,27.1) PR4427.2
  TOP w0.508: PR4427.2 52.55,28.54 PC4406.1
DDC_CLK_HDMI: length 26.1
  TOP w0.114: Q5402.3 16.81,88.54 15.75,87.47 12.7,87.47 12.32,87.85 11.6,87.85 11.18,87.43 11.18,86.4 HDMI1.15
  L4 w0.127: HDMI1.15 11.05,86.27 11.05,87.34 11.43,87.72 12.32,87.72 13.27,86.77 13.27,77.88 13.72,77.44 13.72,76.29 v2(13.84,76.17)
  BOTTOM w0.114: v2(13.84,76.17) 13.9,76.11 RN5401.2
DDC_CLK_PH1: length 2.8
  BOTTOM w0.114: D5401.2 17.77,75.85 v1(17.53,76.09) 17.51,76.11 RN5401.3
DDC_DATA_HDMI: length 24.6
  TOP w0.114: HDMI1.16 12.91,87.13 14.48,87.13 16.55,85.06 16.89,85.06 v1(17.02,85.18) 17.02,87.34 17.27,87.6 18.41,87.6 18.81,87.2 Q5402.6
  L4 w0.127: v2(13.84,75.53) 13.72,75.66 13.72,75.67 13.34,76.05 13.34,77.28 12.89,77.72 12.89,86.03 12.71,86.21 12.53,86.39 12.17,86.39 HDMI1.16
  BOTTOM w0.114: RN5401.1 13.91,75.46 v2(13.84,75.53)
DDC_DATA_PH2: length 3.3
  BOTTOM w0.114: D5401.1 18.47,73.95 17.65,74.77 v1(17.65,74.77) 17.65,74.77 16.96,75.46 RN5401.4
DDPC_CTRLDATA: length 2
  TOP w0.102: TP1502.1 73.66,74.77 v2(73.74,74.69)
  BOTTOM w0.102: CPU1.D11 73.74,75.6 v2(73.74,74.69)
DDR3_DRAMRST#: length 5.4
  TOP w0.102: R404.2 128.59,42.47 v1(129.06,42.94) 129.49,42.51 129.86,42.51 ED1217.1 130.37,42.98 v2(130.44,43.05)
  BOTTOM w0.102: DIMM1.30 v2(130.44,43.05)
DDR_PG_CTRL: length 88
  TOP w0.102: v2(145.41,27.4) 143.51,29.3 136.02,29.3 135.38,28.67 135.38,20.8 133.48,18.89 130.05,18.89 129.54,19.4 129.54,26.18 127.48,28.24 119.42,28.24 117.73,29.94 113.79,29.94 113.28,30.45 109.35,30.45 108.58,29.69 108.58,29.08 106.4,26.89 102.49,26.89 v2(101.73,27.65)
  BOTTOM w0.089: 93.62,42.64 93.24,43.02 93.24,43.45 93.23,43.47 93.23,44 92.71,44.51 CPU1.AV61
  BOTTOM w0.102: v2(145.41,27.4) 146.11,28.1 R1205.1 ; 93.62,42.64 95.89,40.38 v1(95.89,36.42) 98.45,33.85 98.45,30.04 98.93,29.56 99.38,29.56 100.73,28.21 101.42,28.21 101.73,27.91 v2(101.73,27.65)
DDR_PG_CTRL_R: length 2.6
  BOTTOM w0.102: R1205.2 147.45,29.86 v1(147.47,29.89) 147.57,29.89 148.19,29.27 Q1201.S
DDR_VREF_S3: length 66.2
  TOP w0.254: v2(135.13,81.76) 135.13,80.99 137.67,78.45 137.67,72.64 136.91,71.88 136.91,68.07 v2(137.68,67.29) 138.43,66.55 138.43,63.78 137.79,63.15 137.79,59.69 134.97,56.86 132.84,56.86 131.44,55.47 131.44,34.64 130.81,34 v1(130.18,34) 127.38,34 125.27,31.9 124.09,31.9 R3710.1
  BOTTOM w0.254: v2(137.68,67.29) 137.79,67.4 138.24,67.4 R3704.1
  BOTTOM w0.305: PC4916.1 135.79,80.9 135.79,79.96 135.78,79.95 PU4902.6
  BOTTOM w0.508: v2(135.13,81.76) 135.38,81.76 135.7,81.44 PC4916.1
DDR_VTT_PG_CTRL: length 79.4
  L3 w0.102: v2(136.53,88.36) 136.75,88.13 136.75,81.74 137.41,81.08 137.41,73.63 138.43,72.61 138.43,67.04 144.29,61.18 149.2,61.18 150.37,60.01 150.37,58.52 147.45,55.6 147.45,41.24 146.05,39.85 v2(146.05,39.46)
  BOTTOM w0.102: Q1201.D 150.81,28.72 150.18,29.36 R1204.1 R1208.2 149.22,30.57 148.64,31.16 147.52,31.16 146.86,31.82 146.86,35.4 v1(146.48,35.78) 146.48,39.03 v2(146.05,39.46) ; v2(136.53,88.36) 137.51,87.38 Q1202.G 136.78,84.01 PR4926.1
DDR_WR_VREF01: length 31.3
  TOP w1.016: 117.6,34 110.11,34 96.14,47.97 95.25,47.97 93.62,49.6
  BOTTOM w0.305: v2(91.62,50.44) 91.1,50.95 CPU1.AR51
  vias: v1(92.66,50.51)
DIS_DTM_CELL: length 8.6
  TOP w0.254: PU4402.1 32.52,9.5 32,8.98 30.99,8.98 30.29,9.68 PR4419.1 PR4460.2 28.74,10.57 v1(28.17,11.14) 28.17,11.69 PR4453.2
DMIC_CLK: length 135.4
  TOP w0.114: R5204.2 58.29,100.17 57.4,101.06 57.4,101.89 EC5206.1 57.59,103.03 v2(57.53,103.09)
  L4 w0.127: v2(31.37,20.67) 31.37,21.3 32.83,22.76 32.83,27.59 30.86,29.56 29.37,29.56 29.13,29.79 29.13,31.37 28.55,31.95 28.55,34.31 20.57,42.29 20.57,48.97 18.57,50.97 18.57,52.37 18.31,52.62 18.31,65.96 15.95,68.32 15.95,72.13 14.68,73.4 14.68,93.61 15.14,94.07 21.92,94.07 27.41,99.56 35.34,99.56 38.55,102.77 56.29,102.77 56.5,102.57 57.01,102.57 v2(57.53,103.09)
  BOTTOM w0.114: R2716.1 C2723.2 30.29,21.24 v1(30.75,20.78) 30.86,20.67 v2(31.37,20.67)
DMIC_CLK_C: length 5.7
  TOP w0.114: v2(57.15,96.11) 56.97,96.29 56.97,96.81 57.51,97.35 ; 57.51,97.35 58.29,98.14 R5204.1 ; 57.51,97.35 v1(57.61,97.25)
  BOTTOM w0.114: v2(57.15,96.11) 56.97,95.93 56.97,94.96 57.05,94.88 LCD1.18
DMIC_CLK_R: length 4.4
  TOP w0.114: HDA27.3 27.58,23.71 27.63,23.66 27.99,23.66 28.11,23.77 28.64,23.77 v2(29.08,23.34)
  BOTTOM w0.114: R2716.2 29.4,23.02 v2(29.08,23.34) 29.34,23.59 v1(30.1,23.59)
DMIC_DATA: length 136
  TOP w0.114: v2(56.9,103.09) 56.71,102.9 EC5205.1 57.06,101.72 57.06,101.14 ; R5205.2 57.4,100.57 57.06,100.92 57.06,101.14 ; v1(56.92,101.14) 57.06,101.14
  L4 w0.127: v2(56.9,103.09) 56.83,103.16 38.39,103.16 35.18,99.94 27.25,99.94 21.77,94.46 15.3,94.46 14.99,94.46 14.3,93.77 14.3,73.24 15.57,71.97 15.57,68.16 17.93,65.8 17.93,52.78 17.93,52.46 18.19,52.21 18.19,50.82 20.19,48.81 20.19,42.13 28.17,34.16 28.17,31.79 28.75,31.21 28.75,29.64 29.21,29.18 30.7,29.18 32.45,27.43 32.45,22.92 30.92,21.4 30.92,20.48 v2(31.37,20.03)
  BOTTOM w0.114: R2714.1 29.4,21.62 30.39,20.64 30.39,20.63 30.6,20.42 30.6,20.42 30.99,20.03 v2(31.37,20.03)
DMIC_DATA_C: length 5.4
  TOP w0.114: R5205.1 57.4,97.74 56.62,96.95 56.62,96.67 ; v2(56.52,96.11) 56.62,96.21 56.62,96.67 ; 56.62,96.67 v1(56.49,96.67)
  BOTTOM w0.114: LCD1.19 56.55,94.88 56.63,94.96 56.63,95.99 v2(56.52,96.11)
DMIC_DATA_R: length 4.3
  TOP w0.114: HDA27.2 27.45,23.31 27.45,23.32 28.43,23.32 v2(28.45,23.34)
  BOTTOM w0.114: v2(28.45,23.34) 28.51,23.27 EC2701.1 R2714.2 28.51,20.8 v1(28.6,20.7)
DS3_PWRCTL: length 5.9
  TOP w0.102: U3801.4 75.99,109.82 76.24,109.57 78.36,109.57 v1(79.48,110.69) 79.57,110.78 R3802.2
DSWODVREN: length 8.4
  TOP w0.102: v2(97.16,79.47) 97.16,79.6 97.84,80.28 98.95,80.28 R1721.1 100.27,79.72 R1720.1
  BOTTOM w0.089: CPU1.AW7 93.85,77.98 94.44,77.98 94.51,77.91 95.98,77.91 v1(96.14,78.07) 96.14,78.45 v2(97.16,79.47)
E51_TXD: length 3.6
  TOP w0.102: KBC24.111 155.54,55.94 156.62,57.02 TP2408.1
EAPD#: length 3.5
  TOP w0.102: v2(26.92,21.68) 26.67,21.43 25.83,21.43 25.68,21.59 HDA27.47
  BOTTOM w0.102: v1(26.54,21.05) 26.92,21.43 v2(26.92,21.68) 26.99,21.62 R2708.2
EC_AGND: length 19.1
  TOP w0.203: KBC24.103 158.74,56.79 R2435.2
  TOP w0.508: v2(159.38,60.01) 159.23,59.86 C2405.2 159.23,58.43 159.58,58.09 C2404.2 159.58,57.23 159.15,56.8 R2435.2 ; C2414.1 C2403.1 R2407.2 165.48,57.78 v1(165.51,57.8) 165.82,58.11 v2(166.14,58.11) ; R2406.2 C2402.1 161.67,58.51 v2(161.54,58.39)
  BOTTOM w0.508: v2(159.38,60.01) 159.92,60.01 v2(161.54,58.39) 162.05,57.88 165.9,57.88 v2(166.14,58.11)
EC_GPIO10: length 8.4
  TOP w0.102: KBC24.124 150.34,55.45 148.83,56.96 148.83,61.93 TP2409.1
EC_SCI#: length 142.6
  TOP w0.102: R2408.2 140.05,36.8 139.11,37.74 138.37,37.74 137.41,38.7 135.13,38.7 v2(134.87,38.96)
  L3 w0.102: v2(134.87,38.96) 134.87,39.42 136.07,40.62 136.07,45.86 132.58,49.35 132.58,95.8 130.16,98.22 126.71,98.22 124.68,100.24 113.07,100.24 111.55,98.73 109.43,98.73 106.81,96.11 104.07,96.11 102.41,94.44 102.41,93.03 102.89,92.55 102.89,90.77 103.26,90.4 104.89,90.4 v2(105.41,89.88)
  L4 w0.102: v2(87.76,90.39) 95,90.39 96.52,88.87 105.03,88.87 105.41,89.25 v2(105.41,89.88)
  BOTTOM w0.089: 89.13,83.23 89.13,83.22 89.68,82.67 89.68,82.3 89.58,82.2 89.58,81.45 CPU1.AM2
  BOTTOM w0.102: 89.13,83.23 89.13,84.12 88.06,85.18 88.06,88.82 87.33,89.55 87.33,89.96 v2(87.76,90.39) v1(87.12,91.03) 87.12,91.31 87.74,91.92 RN1809.6
EC_SMI#: length 163.1
  TOP w0.102: v2(81.62,83.21) 81.13,83.7 81.13,84.96 79.75,86.34 74.81,86.34 72.81,88.34 72.15,89 RN2002.6
  L3 w0.102: v2(81.62,83.21) 80.85,83.98 80.85,95.65 82.07,96.87 82.17,96.87 v2(82.93,97.63)
  L4 w0.102: v2(159.56,48.43) 159,49 159,51.22 159.84,52.06 159.84,56.24 157.73,58.35 157.73,59.17 153.16,63.75 153.16,65.95 139.14,79.97 139.14,89.21 138.06,90.29 138.06,96.61 130.46,104.21 121,104.21 120.37,103.58 117.13,103.58 114.23,100.68 109.86,100.68 107.27,98.09 83.39,98.09 v2(82.93,97.63)
  BOTTOM w0.102: R2409.2 149.42,44.93 152.2,44.93 153.16,45.89 154,45.89 156.46,48.35 v1(156.46,48.35) 156.84,48.74 159.26,48.74 v2(159.56,48.43) ; v2(81.62,83.21) 81.8,83.02 CPU1.V1
EC_SPI_CLK_C: length 48.4
  TOP w0.114: v2(164.52,52.04) 164.04,51.56 KBC24.92 ; v2(140.72,85.06) v1(140.16,85.06)
  L4 w0.127: v2(164.52,52.04) 164.52,55.66 162.68,57.49 161.81,57.49 160.66,58.65 160.66,59.72 139.89,80.48 139.89,84.23 v2(140.72,85.06)
  BOTTOM w0.114: R2420.2 141.6,85.95 v2(140.72,85.06)
EC_SPI_CS#_C: length 3.4
  TOP w0.114: KBC24.90 163.57,50.76 163.89,51.08 164.55,51.08 v1(164.82,51.35) 165.72,51.35 R2419.2
EC_SPI_DI_C: length 51.7
  TOP w0.114: KBC24.87 161.61,49.56 v2(161.54,49.62)
  L4 w0.127: v2(140.72,84.42) 140.27,83.98 140.27,80.64 165.65,55.27 165.65,52.49 162.78,49.62 v2(161.54,49.62)
  BOTTOM w0.114: v2(140.72,84.42) 140.18,84.42 v1(140.16,84.45) 139.83,84.78 R2422.2
EC_SPI_DO_C: length 52.4
  TOP w0.114: KBC24.86 163.66,49.16 163.96,48.86 v2(164.72,48.86)
  L4 w0.127: v2(164.72,48.86) 164.72,51.02 166.03,52.33 166.03,55.43 140.72,80.74 v2(140.72,83.79)
  BOTTOM w0.114: R2423.2 v1(138.94,85.44) 138.94,83.94 139.09,83.79 v2(140.72,83.79)
EC_SWI#: length 17.2
  TOP w0.102: v2(89.67,80.82) 90.23,81.37 v1(90.35,81.37) ; RN2012.8 86.5,91.27 v2(86.49,91.28)
  L3 w0.102: v2(89.67,80.82) 89.1,81.39 86.62,81.39 85.47,82.54 85.47,90.26 v2(86.49,91.28)
  BOTTOM w0.102: CPU1.AM3 89.37,80.51 v2(89.67,80.82)
EC_VBKUP: length 3.9
  TOP w0.203: 154.46,55.8 154.34,55.68 KBC24.114
  TOP w0.254: R2428.1 155.96,57.3 v1(155.27,56.61) 154.46,55.8
EC_VTT: length 3.7
  TOP w0.203: KBC24.12 145.39,48.76 v1(145.36,48.78) 144.51,48.78 C2401.1
  TOP w0.508: R2401.2 C2401.1
ECRST#: length 160
  TOP w0.102: v2(164.08,31.08) v1(165.1,31.08) 165.35,31.08 165.74,31.46 165.74,32.8 R2418.1 165.99,34.07 165.99,46.59 165.74,46.83 164.34,46.83 163.96,47.21 163.96,48.35 163.55,48.76 KBC24.85 ; v2(48.13,6.06) 48.13,5.21 Q2404.E 48.36,4.06 R2424.2 C2418.1
  L4 w0.102: v2(164.08,31.08) 163.96,31.08 159.79,26.92 143.97,26.92 137.97,20.92 112.56,20.92 110.7,22.78 101.41,22.78 100.88,22.25 89.07,22.25 88.01,23.31 80.39,23.31 79.33,22.24 74.63,22.24 69.47,17.09 50.29,17.09 48.89,15.69 48.89,15.35 48.9,15.35 48.9,6.83 v2(48.13,6.06)
ECSCI#_KBC: length 8.3
  TOP w0.102: KBC24.29 148.21,41.96 148.39,41.78 148.39,40.44 148.13,40.18 148.13,38.07 v1(147.45,37.38) 146.86,36.8 R2408.1
ECSMI#_KBC: length 8.8
  TOP w0.102: v2(145.92,51.28) 146.04,51.16 KBC24.6
  BOTTOM w0.102: v2(145.92,51.28) v1(145.92,50.13) 145.92,48.72 147.83,46.82 147.83,45.37 R2409.1
EDP_AUX: length 3.5
  BOTTOM w0.102: v1(59.84,92.2) 59.72,92.32 ; 59.72,92.32 59.47,92.08 59.47,91.85 59.82,91.51 C5226.1 ; 59.72,92.32 59.9,92.51 59.9,93.11 60.05,93.25 LCD1.12
EDP_AUX#: length 3.3
  BOTTOM w0.102: C5225.1 58.93,91.51 59.27,91.85 59.27,92.17 59.7,92.59 59.7,93.11 59.55,93.25 LCD1.13
EDP_AUX_DN: length 45.2
  L4 w0.114: v2(62.99,56.86) 63.2,57.07 63.2,57.88 63.48,58.17 63.48,62.12 62.64,62.96 62.64,84.61 59.46,87.78 59.46,89.1 v2(59.05,89.5)
  BOTTOM w0.102: v2(59.05,89.5) 58.93,89.63 C5225.2 ; 66.4,55.98 67.94,55.98 69.24,54.68 71.47,54.68 CPU1.A45 ; 66.4,55.98 63.77,55.98 63.42,56.32 63.42,56.43 v2(62.99,56.86) ; 66.4,55.98 v1(66.4,55.8)
EDP_AUX_DP: length 45.3
  L4 w0.114: v2(59.69,89.5) 59.69,87.88 62.87,84.7 62.87,63.06 63.71,62.21 63.71,58.07 63.42,57.79 63.42,57.07 v2(63.63,56.86)
  BOTTOM w0.102: v2(59.69,89.5) 59.82,89.63 C5226.2 ; v2(63.63,56.86) 63.63,56.41 63.85,56.18 64.77,56.18 ; CPU1.B45 72.02,54.56 71.71,54.88 69.33,54.88 68.03,56.18 64.77,56.18 ; 64.77,56.18 v1(64.77,56.36)
EDP_BRIGHTNESS: length 3.3
  BOTTOM w0.114: TP801.1 69.85,56.61 70.52,55.94 CPU1.A43
EDP_COMP: length 2.7
  TOP w0.203: R801.2 71.74,70.66 v1(71.45,70.66)
  TOP w0.508: v2(72.76,70.81) 72.33,70.38 R801.2
  BOTTOM w0.305: CPU1.D20 72.78,70.81 72.77,70.81 v2(72.76,70.81)
EDP_HPD: length 22.8
  L3 w0.102: v2(70.87,79.98) 67.56,83.28 66.9,83.28 62.32,87.85 v2(61.98,87.85)
  BOTTOM w0.102: v2(61.98,87.85) 61.77,88.06 v1(61.34,88.06) 60.21,88.06 59.45,88.82 58.21,88.82 57.48,89.54 57.48,90.76 R5203.2 ; v2(70.87,79.98) 71.14,80.25 71.85,80.25 71.89,80.21 72.35,80.21 72.55,80.01 72.55,79.57 72.73,79.39 72.86,79.39 73.12,79.13 73.12,78.69 CPU1.D6
EDP_HPD_CONN: length 8.6
  TOP w0.102: v2(54.61,96.23) 54.69,96.23 v1(55.17,96.72) 55.5,97.04 RN5203.7
  BOTTOM w0.102: v2(54.61,96.23) 54.17,95.8 54.17,95.03 54.05,94.91 LCD1.24 54.05,92.86 54.48,92.42 54.93,92.42 R5203.1
EDP_SPARE: length 3
  BOTTOM w0.102: CPU1.B43 72.11,55.94 71.76,55.59 69.6,55.59 TP605.1
EDP_TX0: length 3.2
  BOTTOM w0.102: C5229.1 60.71,91.51 61.05,91.85 61.05,92.13 61.2,92.28 61.2,93.11 61.05,93.25 LCD1.10
EDP_TX0#: length 3.4
  BOTTOM w0.102: v1(61.59,92.37) 61.4,92.37 ; 61.4,92.37 61.4,93.11 61.55,93.25 LCD1.9 ; 61.4,92.37 61.4,92.19 61.25,92.04 61.25,91.85 61.59,91.51 C5230.1
EDP_TX0_DN: length 45.8
  L4 w0.114: v2(61.47,89.5) 61.26,89.3 61.26,87.65 63.59,85.32 63.59,63.36 64.55,62.39 64.55,56.38 65.37,55.56 65.37,55.12 v2(65.53,54.96)
  BOTTOM w0.102: CPU1.C45 72.69,54.56 72.16,54.03 69.21,54.03 68.87,54.36 68.15,54.36 ; v1(68.15,54.53) 68.15,54.36 ; 68.15,54.36 65.44,54.36 65.35,54.45 65.35,54.78 v2(65.53,54.96) ; v2(61.47,89.5) 61.59,89.63 C5230.2
EDP_TX0_DP: length 45.8
  L4 w0.114: v2(64.9,54.96) 65.14,55.21 65.14,55.47 64.33,56.28 64.33,62.3 63.36,63.26 63.36,85.23 61.04,87.55 61.04,89.3 v2(60.83,89.5)
  BOTTOM w0.102: 66.27,54.16 68.79,54.16 69.12,53.83 72.39,53.83 CPU1.B46 ; 66.27,54.16 v1(66.27,53.97) ; 66.27,54.16 65.36,54.16 65.15,54.37 65.15,54.7 v2(64.9,54.96) ; v2(60.83,89.5) 60.71,89.63 C5229.2
EDP_TX1: length 3.2
  BOTTOM w0.102: C5232.1 62.48,91.51 62.83,91.85 62.83,92.63 62.7,92.76 62.7,93.11 62.55,93.25 LCD1.7
EDP_TX1#: length 3.4
  BOTTOM w0.102: 63.03,92.17 63.03,92.72 62.9,92.84 62.9,93.11 63.05,93.25 LCD1.6 ; 63.03,92.17 v1(63.2,92.17) ; 63.03,92.17 63.03,91.85 63.37,91.51 C5231.1
EDP_TX1_DN: length 47.2
  L4 w0.114: v2(63.35,89.5) 63.25,89.5 62.84,89.1 62.84,87.17 64.31,85.69 64.31,63.66 65.28,62.69 65.28,56.85 66.85,55.27 66.85,54.32 66.14,53.61 66.14,53.33 v2(66.55,52.93)
  BOTTOM w0.102: v1(68.91,52.67) 69.05,52.54 ; 69.05,52.54 68.69,52.18 66.21,52.18 66.12,52.27 66.12,52.5 v2(66.55,52.93) ; 69.05,52.54 69.42,52.91 71.29,52.91 71.66,53.28 71.66,53.36 CPU1.A47 ; C5231.2 63.09,89.92 63.09,89.66 63.25,89.5 v2(63.35,89.5)
EDP_TX1_DP: length 47.2
  L4 w0.114: v2(65.91,52.93) 65.91,53.71 66.62,54.42 66.62,55.18 65.05,56.75 65.05,62.6 64.08,63.56 64.08,85.6 62.88,86.8 62.61,87.07 v2(62.61,89.5)
  BOTTOM w0.102: 66.98,51.98 68.77,51.98 69.5,52.71 71.38,52.71 72.11,53.44 CPU1.B47 ; 66.98,51.98 66.12,51.98 65.91,52.19 v2(65.91,52.93) ; 66.98,51.98 v1(66.98,51.81) ; C5232.2 62.48,89.63 v2(62.61,89.5)
EDP_VDD_EN: length 24.7
  TOP w0.102: v2(69.72,91.79) 70.87,92.93 v1(71.75,92.93) 73.68,92.93 76.52,95.77 D5201.1
  L4 w0.102: v2(70.87,78.83) 69.71,79.99 69.71,91.78 v2(69.72,91.79)
  BOTTOM w0.102: CPU1.C6 72.45,78.37 72.1,78.37 71.89,78.58 71.12,78.58 v2(70.87,78.83)
FALL_INT2: length 4.4
  TOP w0.305: R6701.2 153.73,16.8 154.05,17.11 v1(154.05,17.75) v2(153.42,17.75)
  BOTTOM w0.305: Q6701.3 153.4,17.73 v2(153.42,17.75) 153.8,17.75 154.05,17.49 Q6701.2
FAN_PWM1: length 38.9
  TOP w0.102: v2(153.9,47.06) 156.09,47.06 157.39,45.76 157.91,45.76 160.15,43.53 160.15,42.22 161.61,40.76 KBC24.65
  L3 w0.102: v2(153.9,47.06) 153.29,47.67 153.29,53.82 152.75,54.36 152.75,61.34 149.84,64.26 147.45,64.26 145.57,66.13 v2(145.03,66.13)
  BOTTOM w0.102: v1(153.9,47.67) 153.9,47.67 v2(153.9,47.06) ; v2(145.03,66.13) 144.98,66.19 RN2601.1
FAN_PWM1_C: length 4.4
  BOTTOM w0.102: RN2601.4 144.98,70.78 AFTP2602.1 144.3,71.57 FAN1.4
FAN_TACH1: length 45.5
  TOP w0.203: KBC24.31 146.22,41.16 146.05,40.99
  TOP w0.254: 146.05,40.99 v2(146.05,40.48) 145.67,40.86 v1(145.36,40.86) R2415.1
  L3 w0.254: v2(153.67,41.12) 154.43,41.88 154.43,47.72 154,48.15 154,60.92 150.08,64.84 147.69,64.84 145.41,67.11 144.11,67.11 v2(144.11,67.11)
  L4 w0.254: v2(146.05,40.48) 147.46,41.89 152.9,41.89 v2(153.67,41.12)
  BOTTOM w0.254: RN2601.2 144.33,67.33 144.11,67.11 v2(144.11,67.11)
FAN_TACH1_C: length 4.7
  BOTTOM w0.254: RN2601.3 144.33,69.64 AFTP2601.1 143.3,71.01 FAN1.3
FAN_VCC_1: length 1.3
  TOP w0.508: D2601.K 141.1,69.74 v2(140.64,70.2)
FFS_INT1_D: length 7.9
  TOP w0.152: R6706.1 160.91,25.43 v1(160.91,23.21) 160.91,20.02 160.4,19.51 160.4,19.14 160.27,19.02 U6701.11
FFS_INT2: length 37.8
  TOP w0.152: R6707.2 161.16,19.02 v2(160.91,19.27) ; v2(148.46,35.15) v1(148.46,32.1) 148.46,30.96 150.62,28.8 150.62,25.62 153.16,23.08 v2(153.42,23.08) ; R6608.1 v2(163.7,27.15)
  L4 w0.152: 160.91,22.83 163.7,25.62 v2(163.7,27.15) ; 160.91,22.83 v2(160.91,19.27) ; 160.91,22.83 160.27,23.46 153.8,23.46 v2(153.42,23.08)
  BOTTOM w0.152: v2(148.46,35.15) 149.13,35.81 D6701.2 149.13,38.86 149.67,39.4 R6705.1
FFS_INT2_D: length 2.1
  TOP w0.152: R6707.1 v1(160.25,17.68) 159.92,18.02 U6701.9
FFS_INT2_Q: length 31.4
  TOP w0.152: v2(155.45,31.08) v1(155.45,30.45) 155.57,30.32 155.57,21.54 154.45,20.41 v2(154.05,20.41)
  L4 w0.152: v2(155.45,31.08) 149.48,31.08 149.3,30.91 147.38,30.91 147.13,31.16 146.75,31.16 146.29,30.7 142.37,30.7 v2(140.21,28.54)
  BOTTOM w0.152: Q6701.6 154.7,19.76 v2(154.05,20.41) ; v2(140.21,28.54) 140.21,28.86 R5601.2
FFS_INT2_Q_R: length 3.4
  BOTTOM w0.152: v1(139.22,30.47) 139.22,30.33 138.62,29.74 R5601.1 138.63,29.55 138.63,28.11 138.55,28.03 HDD1.1
FFS_SCL: length 111.4
  TOP w0.114: v2(144.53,56.74) 144.85,57.06 144.85,58.78 145.47,59.4 145.47,64.77 145.69,64.99 145.69,66.24 138.31,73.62 138.31,80.25 136.04,82.52 v1(135.89,82.52) 134.37,82.52 133.17,83.71 133.17,96.54 129.29,100.42 R6708.2 ; 155.96,18.64 155.83,18.76 153.92,18.76 153.42,19.27 153.42,22.32 148.67,27.06 148.09,27.06 138.61,36.54 138.32,36.54 135.76,36.54 v2(135.51,36.8)
  TOP w0.152: U6701.4 156.08,18.52 155.96,18.64
  L4 w0.127: v2(135.51,36.8) 135.83,36.48 136.2,36.48 136.96,37.24 138.74,37.24 144.08,42.58 144.08,50.07 143.38,50.77 143.38,55.75 144.37,56.74 v2(144.53,56.74)
FFS_SDA: length 112.7
  TOP w0.114: v2(135.51,36.04) 135.67,36.2 138.47,36.2 147.95,26.72 148.53,26.72 153.07,22.17 153.07,19.13 153.78,18.42 154.14,18.42 155.64,16.92 157.28,16.92 157.35,16.99 ; R6709.2 129.26,100.93 133.51,96.68 133.51,84 v1(134.37,83.15) 134.62,82.9 136.14,82.9 138.65,80.39 138.65,73.76 146.04,66.38 146.04,64.85 145.81,64.62 145.81,59.26 145.19,58.64 145.19,56.77 v2(144.53,56.1)
  TOP w0.152: 157.35,16.99 157.49,17.12 U6701.6
  L4 w0.127: v2(135.51,36.04) 135.57,36.1 136.36,36.1 137.12,36.86 138.9,36.86 144.46,42.42 144.46,50.23 143.76,50.93 143.76,55.59 144.27,56.1 v2(144.53,56.1)
GSEN2_INT1: length 7.8
  TOP w0.152: R6628.2 R6621.2 161.93,24.86 161.42,24.35 161.42,20.29 v1(161.67,20.03) U6602.11
GSEN2_INT1_C: length 150.2
  TOP w0.152: U6601.17 100.45,109.88 98.7,111.62 95.03,111.62 94.49,112.16 v1(94.49,112.49) v2(94.49,113.25) ; R6628.1 v2(162.81,27.15)
  L4 w0.152: v2(94.49,113.25) 95.36,114.13 113.79,114.13 115,112.92 115,110.93 117.24,108.69 130.29,108.69 135.23,103.75 136.88,103.75 138.93,101.71 138.93,98.9 141.91,95.92 141.91,81.03 163.56,59.38 166,59.38 167.28,58.09 167.28,49.36 166.09,48.17 166.09,30.42 v2(162.81,27.15)
GSEN2_INT2: length 6.9
  TOP w0.152: R6629.2 R6608.2 163.13,24.99 162.89,24.99 v1(162.56,24.66) 161.93,24.02 161.93,21.3 162.2,21.03 U6602.9
GSEN2_INT2_C: length 170
  TOP w0.152: U6601.38 97.45,101.31 96.52,100.39 94.79,100.39 93.59,101.59 93.07,101.59 86.61,108.04 v1(85.85,108.04) v2(84.84,108.04) ; R6629.1 v2(164.59,27.15)
  L4 w0.152: v2(84.84,108.04) 91.2,114.41 113.91,114.41 115.28,113.04 115.28,111.05 117.36,108.97 130.4,108.97 135.34,104.03 137,104.03 139.2,101.83 139.2,99.02 142.19,96.03 142.19,81.15 163.68,59.66 166.12,59.66 167.56,58.21 167.56,49.25 166.37,48.05 166.37,28.92 v2(164.59,27.15)
GSEN_INT1: length 77.5
  TOP w0.152: U6601.18 99.94,109.98 98.58,111.34 94.91,111.34 94.12,112.13 v1(91.82,112.13) 89.43,112.13 87,109.7 v2(85.09,109.7)
  L4 w0.152: v2(85.09,109.7) 85.09,109.44 78.21,102.56 75.18,102.56 72.15,99.54 59.16,99.54 58.02,98.39 42.31,98.39 41.02,99.69 38.74,99.69 38.23,99.18 v2(38.23,99.15)
  BOTTOM w0.152: HOMBD1.9 32.75,99.25 33.3,98.7 37.78,98.7 38.05,98.97 38.05,98.98 v2(38.23,99.15)
GSEN_INT2: length 76.3
  TOP w0.152: v2(82.93,108.04) 83.44,108.55 86.61,108.55 89.64,111.58 v1(90.63,111.58) 94.28,111.58 94.8,111.06 98.47,111.06 99.45,110.08 U6601.19
  L4 w0.152: v2(82.93,108.04) 77.72,102.84 75.06,102.84 72.04,99.82 59.04,99.82 57.9,98.67 42.43,98.67 41.13,99.97 38.39,99.97 37.59,99.17 v2(37.59,99.15)
  BOTTOM w0.152: v2(37.59,99.15) 33.35,99.15 32.76,99.75 HOMBD1.10
GSENSOR_CS: length 2.3
  TOP w0.152: R6623.2 163.7,22.8 v1(163.14,22.24) 163.46,21.93 U6602.8
GSENSOR_SDO: length 3
  TOP w0.152: R6627.2 R6626.2 164.59,22.47 v1(164.36,22.24) 163.96,21.84 U6602.7
GYRO_DRDY: length 71.5
  TOP w0.152: U6601.39 97.94,101.34 96.72,100.11 94.67,100.11 93.47,101.31 v2(92.58,101.31)
  L4 w0.152: v2(38.86,99.17) 39.92,98.11 58.13,98.11 59.28,99.26 72.27,99.26 75.09,102.08 v2(75.82,102.08)
  BOTTOM w0.152: v2(75.82,102.08) 76.07,102.33 90.93,102.33 v1(91.95,101.31) v2(92.58,101.31) ; v2(38.86,99.17) 37.77,100.26 33.61,100.26 33.12,100.75 HOMBD1.12
GYRO_INT: length 72.7
  L4 w0.152: v2(75.82,103.6) 75.43,103.6 71.92,100.09 58.93,100.09 57.78,98.95 42.55,98.95 41.25,100.25 38.03,100.25 v2(37.58,99.8)
  BOTTOM w0.152: v2(37.58,99.8) 33.35,99.8 32.9,100.25 HOMBD1.11 ; v2(75.82,103.6) 76.4,103.02 80.77,103.02 81.1,103.35 88.88,103.35 92.94,107.41 94.23,107.41 94.55,107.09 v1(97.08,107.09) R6625.2 R6624.2
GYRO_INT_C: length 4.3
  TOP w0.152: v2(98.42,110.46) 98.42,110.33 98.94,109.81 U6601.20
  BOTTOM w0.152: v2(98.42,110.46) 98.42,109.59 v1(98.25,109.42) 98.04,109.21 R6625.1
GYRO_INT_P11: length 139.2
  TOP w0.152: v2(118.62,105.25) 118.8,105.43 118.8,105.44 119.75,106.39 130.14,106.39 139.9,96.63 139.9,87.63 141.42,86.11 141.42,83.51 142.7,82.23 142.7,77.26 152.2,67.76 152.2,64.34 154.03,62.5 155.09,62.5 155.77,63.18 161.61,63.18 v2(162.21,62.58)
  L3 w0.152: v2(158.88,35.53) 159.77,35.53 162.43,38.19 162.43,52.67 161.72,53.38 161.72,54.37 163.91,56.56 163.91,61.37 162.7,62.58 v2(162.21,62.58)
  L4 w0.152: v2(158.88,35.53) 158.42,35.99 151.08,35.99 v2(149.99,34.89)
  BOTTOM w0.152: R6624.1 98.93,108.17 100.15,109.39 v1(103,109.39) 114.49,109.39 118.62,105.26 v2(118.62,105.25) ; v2(149.99,34.89) 151.1,36 D6701.1
H_CATERR#: length 5.4
  BOTTOM w0.089: CPU1.K61 77.23,44.35 76.98,44.11 76.98,43.7 77.16,43.52 77.35,43.52 77.55,43.32 77.55,41.7 77.51,41.66
  BOTTOM w0.114: 77.51,41.66 77.44,41.59 77.44,40.1 TP402.1
H_CPU_SVIDALRT#: length 8.9
  BOTTOM w0.114: R701.2 77.66,36.35 v1(77.98,36.67) 78.73,37.43 78.73,41.38 78.44,41.67 78.44,43.42 CPU1.L62
H_CPU_SVIDCLK: length 51.7
  TOP w0.114: PU4601.31 42.27,47.35 43.21,46.42 43.21,46.04 v2(45.09,44.16)
  BOTTOM w0.114: CPU1.N63 78.82,43.14 78.82,41.93 79.19,41.55 79.19,36.95 77.01,34.77 v1(75.77,34.77) 66.42,34.77 65.15,36.04 63.12,36.04 61.34,37.81 50.55,37.81 45.36,43 45.36,43.89 v2(45.09,44.16) 44.83,43.91 PR4622.1
H_CPU_SVIDDAT: length 53.5
  TOP w0.114: v2(46.48,44.16) 46.3,44.34 46.3,44.35 45.01,45.65 45.01,45.81 45.23,46.02 45.23,46.18 45.06,46.34 44.9,46.34 44.69,46.13 44.52,46.13 44.31,46.35 44.31,46.52 44.53,46.74 44.53,46.92 44,47.44 43.56,47.44 43.36,47.64 PU4601.1
  BOTTOM w0.114: CPU1.L63 78.02,41.5 78.19,41.33 78.19,39.55 77.63,38.99 77.63,38.08 77,37.45 75.77,37.45 R704.2 74.68,36.36 74.68,36.12 74.25,35.68 74.02,35.68 73.91,35.79 73.91,36.15 73.79,36.26 73.56,36.26 73.45,36.15 73.45,35.79 73.33,35.68 73.11,35.68 72.99,35.79 72.99,36.15 72.88,36.26 72.65,36.26 72.53,36.15 72.53,35.79 72.42,35.68 v1(71.78,35.68) 66.8,35.68 65.53,36.95 63.5,36.95 62.26,38.19 62.26,38.19 61.72,38.73 50.92,38.73 46.48,43.17 v2(46.48,44.16) 46.48,44.29 45.09,45.69 PR4621.1
H_CPUPWRGD: length 7.3
  BOTTOM w0.102: 70.57,44.76 71.91,44.76 71.98,44.83 72.81,44.83 CPU1.C61
  BOTTOM w0.114: 70.57,44.76 70.34,44.53 68.53,44.53 68.06,44.06 67.47,44.06 v1(67.36,43.95) 67,43.59 R405.1
H_PECI: length 80.4
  TOP w0.114: v1(79.38,41.45) v2(79.38,42) 78.94,42.44 78.94,42.95 79.15,43.16 v2(79.15,44.19)
  L3 w0.127: v2(79.38,42) 84.39,36.99 84.39,36.48 87.12,33.75 87.12,31.34 90.54,27.92 98.42,27.92 98.73,28.23 123.83,28.23 125.16,29.56 139.06,29.56 142.81,33.3 v2(144.46,33.3)
  BOTTOM w0.114: R2429.2 144.15,33.61 v2(144.46,33.3) ; CPU1.N62 78.79,43.84 v2(79.15,44.19)
H_PROCHOT#: length 109.9
  TOP w0.114: PU4601.30 41.87,46.99 42.55,46.32 v2(42.55,46.2) ; v2(41.15,4.16) 41.53,4.54 PR4455.2 41.85,4.86 42.08,5.09 42.08,6.21 PR4469.1
  L4 w0.127: v2(36.83,8.86) 36.83,7.97 38.04,6.76 38.04,5.24 39.12,4.16 v2(41.15,4.16) ; v2(72.77,36.92) 70.74,34.89 70.74,22.83 69.79,21.88 57.68,21.88 56.64,20.84 v2(56.64,20.8)
  BOTTOM w0.114: v2(56.64,20.8) 56.64,19.27 v1(55.36,17.99) 54.99,17.62 50.93,17.62 49.53,16.22 49.53,9.75 47.75,7.97 45.85,7.97 44.58,6.7 44.58,5.94 42.86,4.22 42.86,3.9 42.42,3.46 PR4457.2 41.78,3.52 v2(41.15,4.16) ; v2(42.55,46.2) 42.69,46.34 45.08,46.34 47.12,44.3 47.12,43.78 47.12,43.18 51.04,39.26 52,39.26 60.71,39.26 61.03,39.58 62.56,39.58 R2440.2 63.06,39.21 67.75,39.21 R401.2 68.78,38.18 68.78,36.91 C2421.1 69.47,36.23 71.95,36.23 72.64,36.92 v2(72.77,36.92) 72.9,36.8 R403.1 ; PR4456.1 v2(36.83,8.86)
H_PROCHOT#_EC: length 3.8
  BOTTOM w0.114: v1(62.08,39.12) 62.08,39.02 62.84,38.26 R2440.1 63.5,37.75 R2438.2 65.02,37.75 Q2401.D
H_PROCHOT#_R: length 8.9
  BOTTOM w0.114: CPU1.K63 77.17,43.09 77.17,38.27 76.84,37.94 74.6,37.94 v1(74.37,37.71) 74.36,37.7 R403.2
H_RCIN#: length 165.6
  TOP w0.114: RN2002.7 72.29,89.5 72.79,89 73.26,88.53 73.26,88.53 75,86.79 78.57,86.79 78.58,86.79 79.93,86.79 81.58,85.14 81.58,84.45 82.18,83.85 82.18,81.81 82.62,81.37 82.62,80.62 82.44,80.44 82.44,80.43 v2(82.17,80.17) ; v2(114.3,106.14) 114.3,105.49 115.88,103.91 121.47,103.91 122.74,105.18 129.71,105.18 137.85,97.04 137.85,85.31 141.48,81.67 141.48,75.77 142.42,74.83 142.42,74.57 145.27,71.72 v2(146.69,71.72) ; v2(150.3,56.57) 150.41,56.57 151.14,55.84 KBC24.122
  L3 w0.127: v2(82.42,100.55) 82.42,98.77 80.35,96.7 80.35,83.77 81.62,82.5 81.62,80.74 82.17,80.19 v2(82.17,80.17)
  L4 w0.127: v2(114.3,106.14) 114.3,106.91 112.77,108.44 104.38,108.44 104.06,108.76 93.61,108.76 86.66,101.8 83.54,101.8 82.42,100.68 v2(82.42,100.55) ; v2(156.08,55.85) 155.19,56.74 155.19,59.71 146.53,68.37 146.53,71.57 v2(146.69,71.72)
  BOTTOM w0.102: CPU1.V4 81.87,79.86 v2(82.17,80.17)
  BOTTOM w0.114: v2(150.3,56.57) 151.3,56.57 152.02,55.85 v1(155.45,55.85) v2(156.08,55.85)
H_VCCST_PWRGD: length 13.6
  BOTTOM w0.089: CPU1.B59 72.17,45.91 71.85,45.59 71.17,45.59
  BOTTOM w0.102: U701.4 61.99,44.53 62.04,44.48 ; 71.17,45.59 71.07,45.69 67.56,45.69 TP9648.1 67.26,45.39 66.2,45.39 65.3,44.48 EC701.1 R709.1 R707.2 62.04,44.48 ; 62.04,44.48 61.59,44.04 R706.2
H_VR_ENABLE: length 39.2
  TOP w0.102: PR4615.2 v2(47.07,52.8) ; v2(63.37,42) 64.36,42 65.71,40.66 70.5,40.66 v1(72.14,42.3) v2(74.66,44.82)
  L3 w0.102: v2(63.37,42) 62.05,43.33 51.47,43.33 49.96,44.83 49.96,47.72 47.62,50.06 47.62,52.24 v2(47.07,52.8)
  BOTTOM w0.102: CPU1.F60 74.97,45.14 v2(74.66,44.82) ; v2(63.37,42) R710.1
HDA_BITCLK: length 9.2
  TOP w0.114: R1907.2 99.83,74.39 v1(98.62,75.6) 97.73,76.5 97.23,76.5 v2(96.77,76.04)
  BOTTOM w0.114: v2(96.77,76.04) 96.77,76.17 96.29,76.66 94.43,76.66 94.41,76.64 93.86,76.64 CPU1.AW8
HDA_CODEC_BITCLK: length 234.9
  TOP w0.114: R1907.1 EC1901.2 103.06,74.2 103.52,73.74 105.29,73.74 v1(105.84,74.29) 106.45,74.9 109.16,74.9 114.17,79.91 114.17,95.13 114.72,95.69 114.72,103.62 112.27,106.07 112.27,109.59 111.12,110.73 v2(111.12,113.25) ; v2(31.88,25.75) 31.43,25.3 EC2709.1 R2720.1
  L3 w0.127: v2(111.12,113.25) 111.12,113.38 110.81,113.7 109.54,113.7 108.64,112.79 81.91,112.79 74.31,105.19 74.31,102.7 72.25,100.64 63.14,100.64 61.27,102.51 58.93,102.51 57.87,101.44 45.98,101.44 45.2,100.65 36.67,100.65 35.42,99.41 32.88,99.41 29.32,95.85 22.91,95.85 15.19,88.14 15.19,73.19 16.45,71.94 16.45,68.56 16.8,68.21 16.8,63.77 17.34,63.24 17.34,52.8 17.98,52.15 17.98,44.72 19.28,43.42 19.28,40.05 20.16,39.16 24.47,39.16 28.75,34.87 28.75,32.27 30.04,30.99 30.04,26.02 30.81,25.24 31.37,25.24 v2(31.88,25.75)
HDA_CODEC_RST#: length 235.4
  TOP w0.114: v2(28.19,27.15) 27.69,27.15 27.45,26.91 HDA27.11 ; R1911.1 103.11,73.5 103.44,73.17 v1(104.52,73.17) 105.41,73.17 106.68,74.44 109.19,74.44 114.62,79.88 114.62,94.94 115.06,95.38 115.06,103.76 112.65,106.17 112.65,109.7 111.76,110.58 v2(111.76,113.25)
  L3 w0.127: v2(111.76,113.25) 111.76,113.28 110.67,114.37 82.17,114.37 73.41,105.61 73.41,103.07 71.9,101.57 63.48,101.57 61.65,103.4 58.56,103.4 57.5,102.33 45.61,102.33 44.83,101.54 36.3,101.54 35.05,100.3 32.51,100.3 28.96,96.74 22.54,96.74 14.3,88.5 14.3,72.82 15.56,71.57 15.56,68.13 15.91,67.77 15.91,53.69 15.91,52.94 17.09,51.76 17.09,44.35 17.22,44.22 18.39,43.05 18.39,39.68 19.79,38.27 24.01,38.27 27.86,34.42 27.86,31.54 28.38,31.02 28.38,28.33 28.19,28.14 v2(28.19,27.15)
  BOTTOM w0.114: R2917.1 30.45,27.15 v2(28.19,27.15)
HDA_CODEC_SDIN0: length 2.9
  TOP w0.114: R2718.2 29.5,25.6 28.44,25.6 v1(28.32,25.6) 28.2,25.71 HDA27.8
HDA_CODEC_SDOUT: length 229.2
  TOP w0.114: v2(30.99,23.21) 31.43,23.65 EC2708.1 R2719.1 ; v2(107.82,113.25) 108.22,112.86 108.22,112.48 111.44,109.25 111.44,107.14 111.44,105.73 113.89,103.28 113.89,96.8 112.8,95.7 112.8,80.63 108.33,76.17 v1(105.84,76.17) R1912.1
  L3 w0.127: v2(30.99,23.21) 29.4,24.8 29.4,28.06 28.89,28.56 28.89,30.81 28.89,31.23 28.37,31.75 28.37,34.72 24.31,38.78 20.01,38.78 18.9,39.89 18.9,43.27 17.6,44.56 17.6,51.97 16.42,53.15 16.42,68.05 16.07,68.4 16.07,71.78 14.81,73.03 14.81,88.29 22.75,96.23 29.17,96.23 32.72,99.79 35.26,99.79 36.51,101.03 45.04,101.03 45.83,101.82 57.71,101.82 58.78,102.89 61.43,102.89 63.29,101.02 72.09,101.02 73.93,102.86 73.93,105.35 82.27,113.7 107.38,113.7 v2(107.82,113.25)
HDA_CODEC_SYNC: length 228.5
  TOP w0.114: R1908.1 v1(104.78,75.53) 106.05,75.53 106.32,75.81 108.74,75.81 113.25,80.33 113.25,95.44 114.13,96.32 114.13,103.38 111.68,105.83 111.68,109.35 108.46,112.58 v2(108.46,113.25) ; v2(27.81,26.64) 27.69,26.51 HDA27.10
  L3 w0.127: v2(108.46,113.25) 107.59,114.12 82.27,114.12 73.66,105.5 73.66,102.96 72.01,101.31 63.37,101.31 61.54,103.14 58.67,103.14 57.6,102.08 45.72,102.08 44.93,101.29 36.4,101.29 35.16,100.04 32.62,100.04 29.06,96.49 22.64,96.49 14.55,88.4 14.55,72.93 15.81,71.67 15.81,68.23 16.17,67.88 16.17,53.05 17.35,51.86 17.35,44.46 18.64,43.16 18.64,39.78 19.9,38.53 24.12,38.53 28.12,34.52 28.12,31.65 28.64,31.12 28.64,28.09 28.51,27.97 28.51,27.46 28.7,27.27 28.7,26.89 28.45,26.64 v2(27.81,26.64)
HDA_RST#: length 10.8
  TOP w0.114: v2(97.41,76.04) 97.54,76.04 100.08,73.5 R1911.2
  BOTTOM w0.089: CPU1.AU8 92.55,77.26 93.05,77.26 93.09,77.23 94.36,77.23 94.53,77.06
  BOTTOM w0.114: v2(97.41,76.04) 97.41,76.17 v1(96.65,76.93) 96.52,77.06 94.53,77.06
HDA_SDIN0: length 238
  TOP w0.114: v2(96.14,76.04) 96.14,76.05 97.04,76.96 97.91,76.96 99.8,75.07 v1(100.33,75.07) 106.02,75.07 106.3,75.36 108.97,75.36 113.71,80.1 113.71,95.26 114.38,95.93 114.38,103.48 111.93,105.93 111.93,109.45 109.86,111.52 v2(109.86,113.25) ; v2(31.24,25.75) R2718.1
  L3 w0.127: v2(109.86,113.25) 109.02,112.41 82.07,112.41 74.69,105.04 74.69,102.54 72.4,100.26 62.98,100.26 61.11,102.13 59.09,102.13 58.02,101.06 46.14,101.06 45.35,100.27 36.82,100.27 35.58,99.03 33.04,99.03 29.48,95.47 23.06,95.47 15.57,87.98 15.57,73.35 15.99,72.93 16.83,72.09 16.83,68.72 17.18,68.36 17.18,68.05 17.18,68.05 17.18,63.93 17.72,63.4 17.72,52.96 18.36,52.31 18.36,44.88 19.44,43.8 19.66,43.58 19.66,40.2 20.32,39.54 24.62,39.54 29.69,34.47 29.69,31.88 31.05,30.52 31.05,25.94 v2(31.24,25.75)
  BOTTOM w0.114: v2(96.14,76.04) 95.73,76.45 94.77,76.45 94.51,76.19 CPU1.AY10
HDA_SDOUT: length 12.9
  TOP w0.114: R1912.2 101.79,76.17 R1909.2 99.49,76.68 98.29,77.87 96.97,77.87 95.64,76.54 95.01,76.54 v1(94.54,76.07) 94.01,75.53 93.03,75.53 v2(92.56,75.07)
  BOTTOM w0.114: v2(92.56,75.07) 92.26,75.36 CPU1.AU11
HDA_SPKR: length 140.9
  L4 w0.254: v2(70.23,87.09) 70.23,92 69.93,92.3 68.71,92.3 67.82,91.41 50.53,91.41 50.27,91.66 44.83,91.66 41.66,94.84 33.66,94.84 33.53,94.71 25.16,94.71 22.62,92.17 19.56,92.17 16.7,89.31 16.7,84.19 16.31,83.8 16.31,75.99 18.29,74.01 18.29,69.06 20.45,66.9 20.45,50.51 21.72,49.24 21.72,42.64 27.3,37.05 v2(28.57,37.05)
  BOTTOM w0.089: 81.23,84.16 82.02,83.38 82.02,83.04 81.99,83.02 81.99,82.09 82.09,81.99 82.09,81.45 CPU1.V2
  BOTTOM w0.254: v2(28.57,37.05) 28.57,37.29 29.17,37.89 RN2701.2 ; R2006.2 70.23,87.92 v2(70.23,87.09) 71.12,87.09 71.3,86.91 80.07,86.91 v1(80.52,86.45) 81.23,85.74 81.23,84.16
HDA_SPKR_R: length 4.4
  BOTTOM w0.254: RN2701.3 31.3,37.89 31.47,37.71 v1(31.47,36.04) 31.47,34.95 D2701.2
HDA_SYNC: length 10
  TOP w0.114: v2(95.5,76.04) 95.68,76.22 95.68,76.24 96.85,77.41 v1(97.49,77.41) 98.1,77.41 99.98,75.53 R1908.2
  BOTTOM w0.114: CPU1.AV11 93.33,75.89 94.59,75.89 94.74,76.04 v2(95.5,76.04)
HDD_DEVSLP: length 9.6
  TOP w0.102: v2(78.64,83.18) 78.48,83.34 73.53,83.34 73.35,83.15 v1(72.64,83.15) R2024.2
  BOTTOM w0.089: CPU1.P2 79.41,81.31 79.29,81.31 79.09,81.51 79.09,81.96 79.02,82.03 79.02,82.8 v2(78.64,83.18)
HDD_FALL_INT: length 160.4
  TOP w0.152: v2(138.3,100.17) 137.54,100.93 137.54,102.46 136.73,103.27 134.92,103.27 130.65,107.54 116.59,107.54 115.57,108.55 115.57,113.51 114.68,114.39 88.01,114.39 82.42,108.81 82.42,108.17 v1(82.04,107.79) 81.41,107.16 R1501.1 ; v2(161.93,27.15) R6621.1 R6706.2
  L4 w0.152: v2(161.93,27.15) 165.81,31.03 165.81,48.3 167,49.5 167,57.98 165.88,59.1 163.45,59.1 141.63,80.92 141.63,81.18 141.63,95.8 138.3,99.13 v2(138.3,100.17)
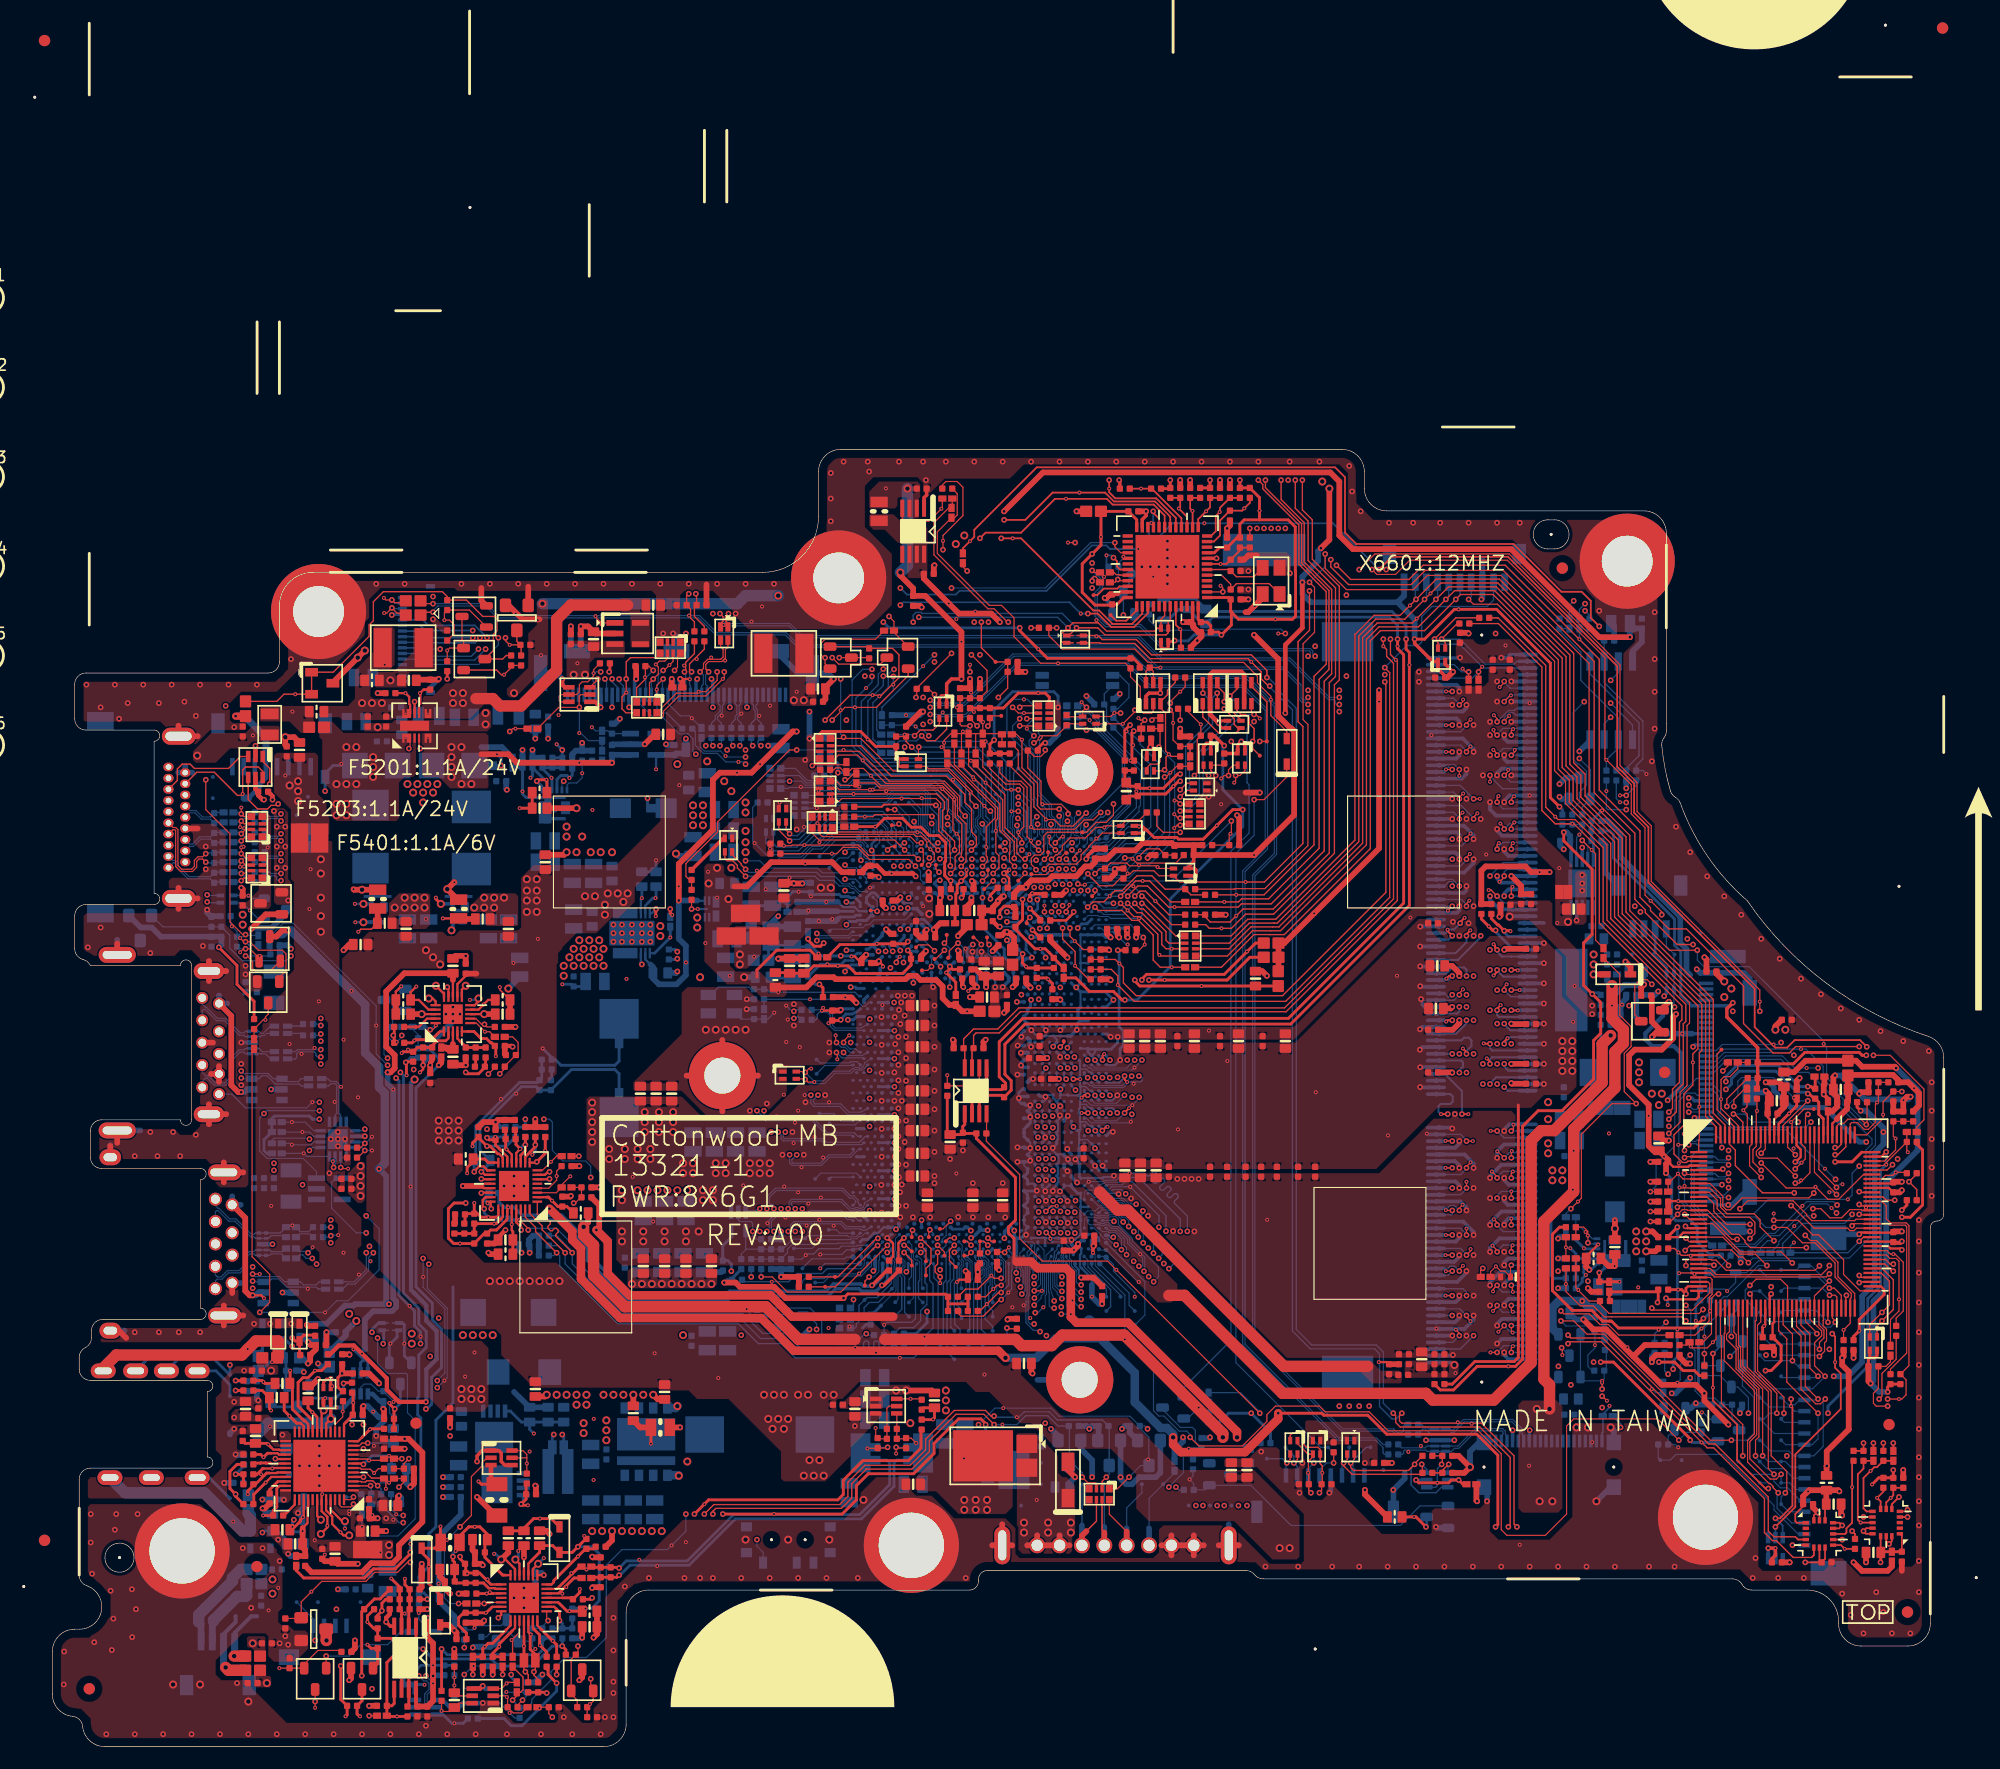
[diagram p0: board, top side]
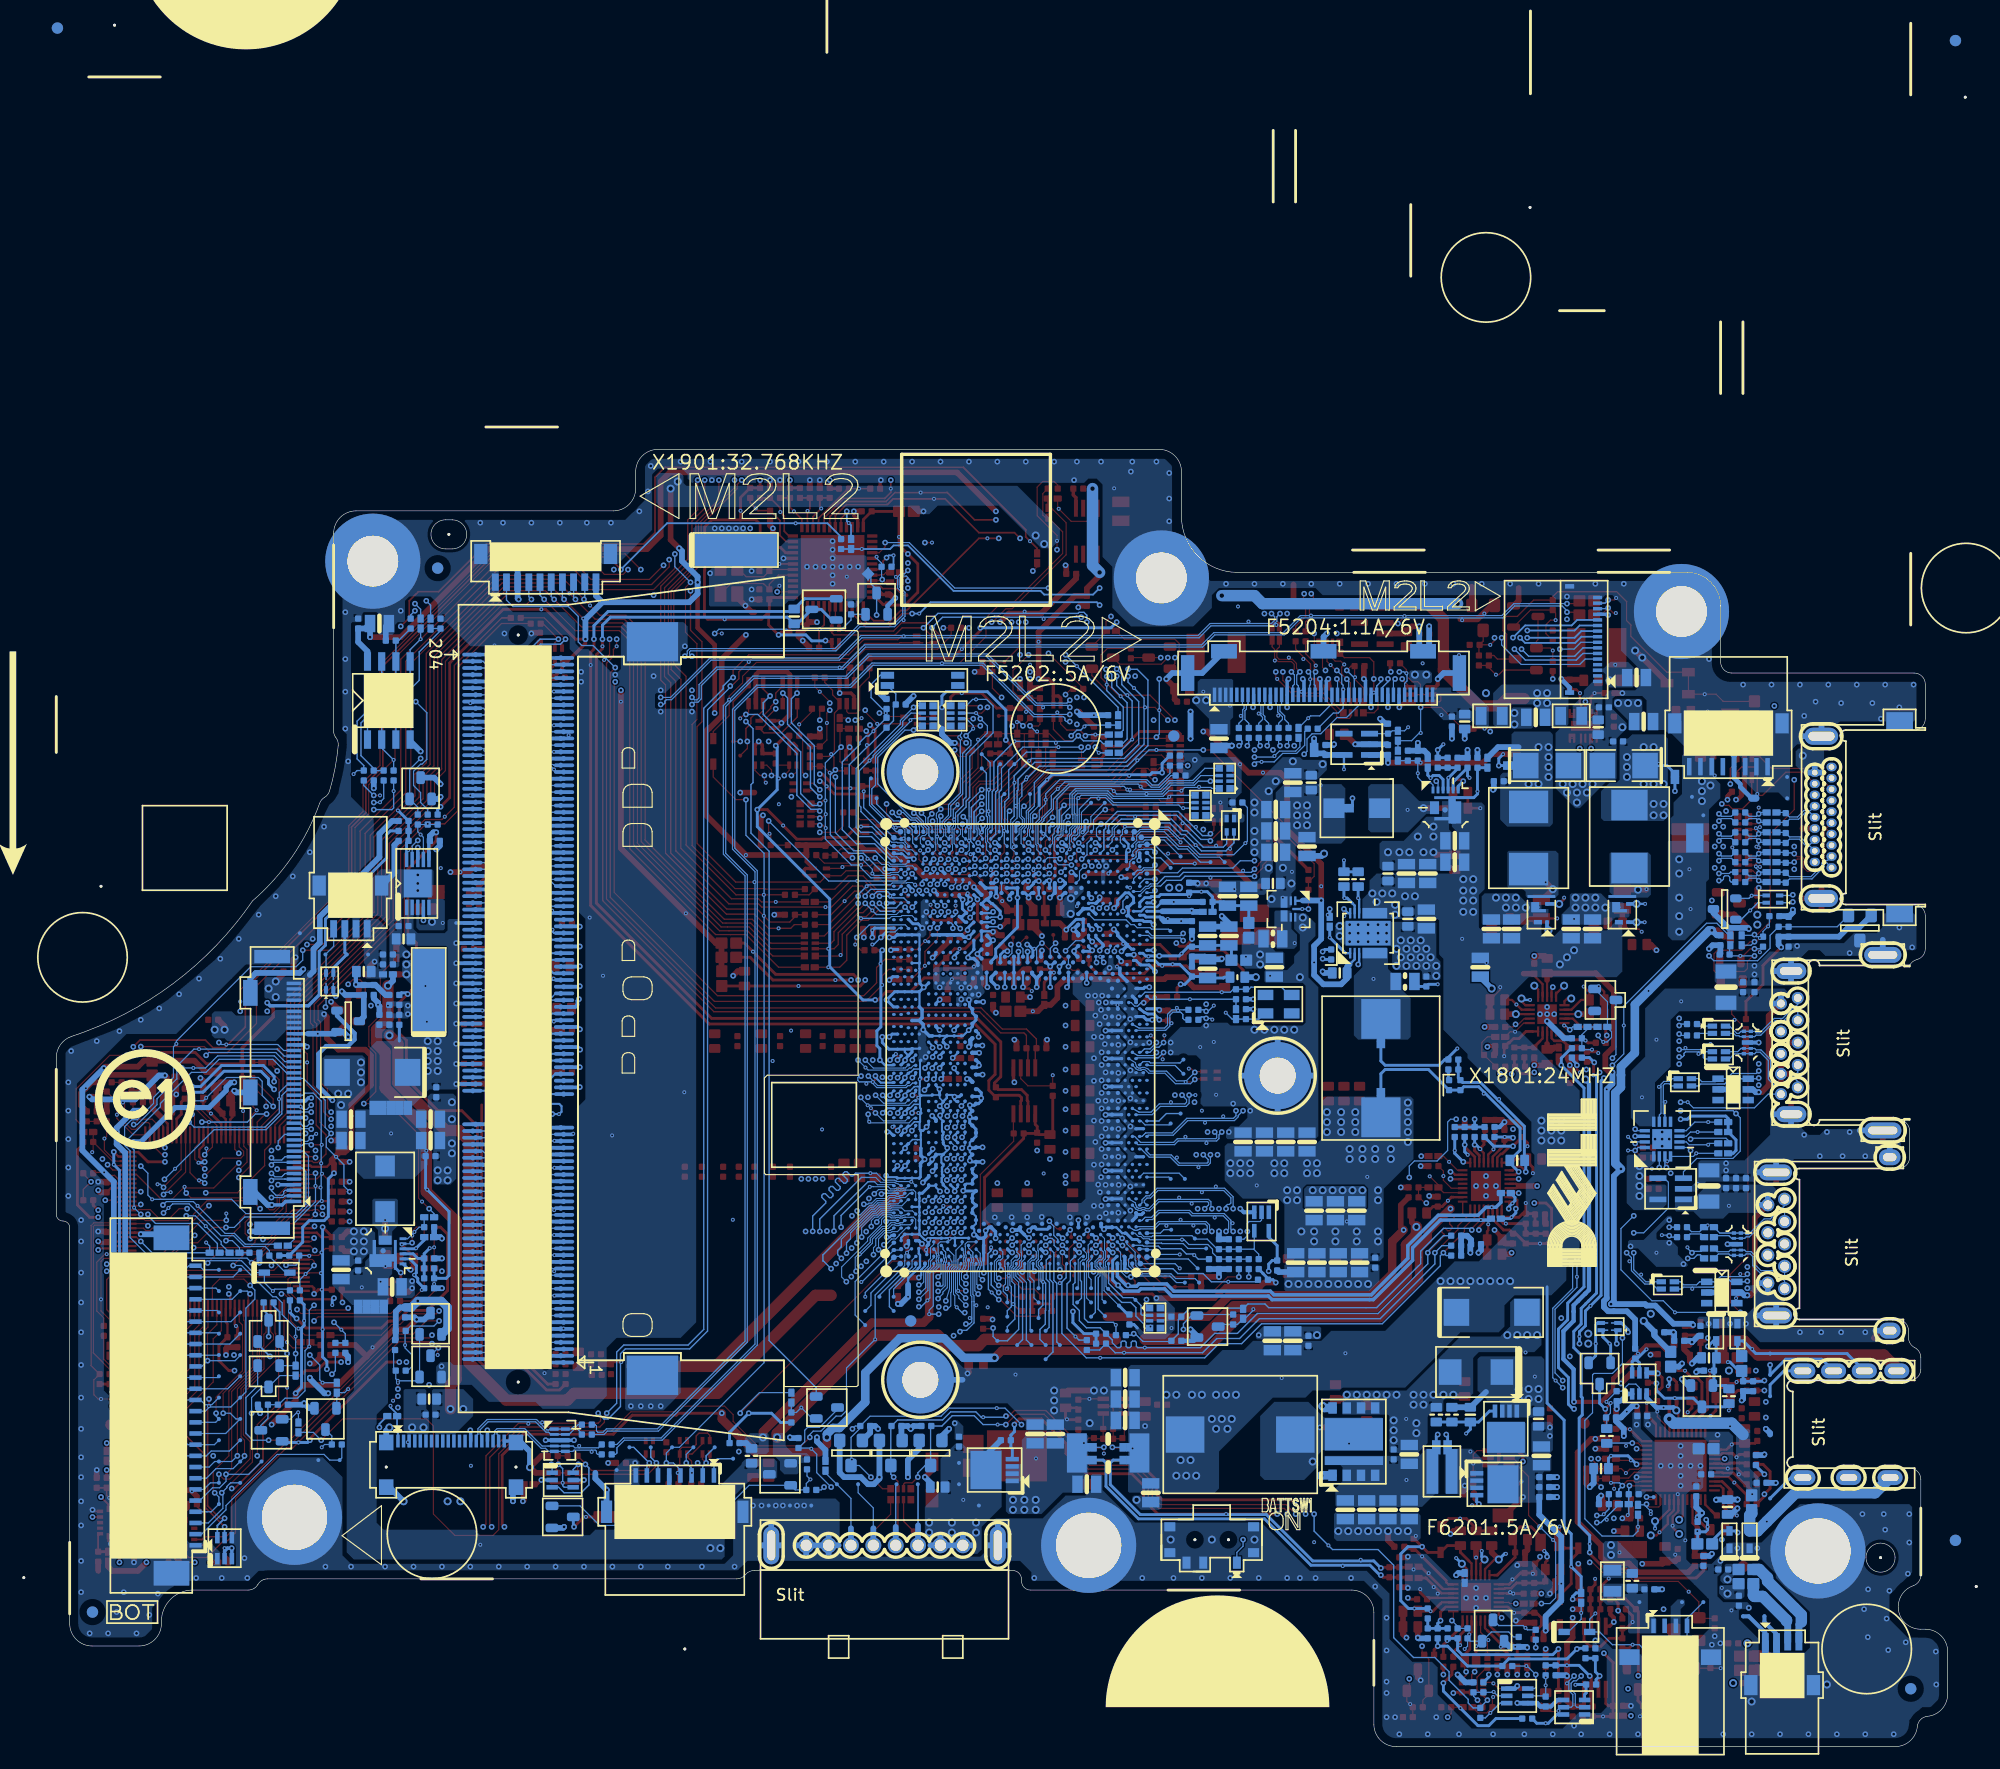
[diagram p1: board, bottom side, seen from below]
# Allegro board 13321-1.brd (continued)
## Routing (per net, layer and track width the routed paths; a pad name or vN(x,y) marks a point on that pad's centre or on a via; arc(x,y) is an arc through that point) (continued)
HDMI_CLK: length 93.2
  L4 w0.114: v2(63.88,46.07) 64.08,45.87 64.08,45.55 63.84,45.31 61.43,45.31 58.28,42.16 48.06,42.16 47.21,43 35.96,43 28.7,50.26 28.7,55.49 25.2,58.99 25.2,65.7 23.28,67.61 20.86,67.61 19.2,69.28 19.2,74.6 17.58,76.22 17.58,81.18 19.37,82.98 20.24,82.98 v2(20.45,82.77)
  BOTTOM w0.102: 64.08,46.81 64.08,47.07 64.69,47.67 67.49,47.67 67.77,47.95 70.56,47.95 71.18,47.33 71.75,47.33 72.05,47.04 CPU1.B57 ; 64.08,46.81 64.08,46.27 v2(63.88,46.07) ; 64.08,46.81 v1(63.93,46.81) ; C5403.1 19.33,82.99 20.23,82.99 v2(20.45,82.77)
HDMI_CLK#: length 93.3
  L4 w0.114: v2(64.52,46.07) 64.31,45.87 64.31,45.46 63.94,45.08 61.53,45.08 58.38,41.93 47.96,41.93 47.12,42.77 35.87,42.77 28.47,50.17 28.47,55.39 24.97,58.9 24.97,65.6 23.19,67.38 20.77,67.38 18.97,69.18 18.97,74.51 17.35,76.13 17.35,81.27 19.28,83.2 20.24,83.2 v2(20.45,83.41)
  BOTTOM w0.102: v2(64.52,46.07) 64.29,46.3 64.29,46.98 64.77,47.47 65.53,47.47 ; v2(20.45,83.41) 20.23,83.19 19.33,83.19 C5402.1 ; 65.53,47.47 67.57,47.47 67.85,47.75 70.48,47.75 71.09,47.13 71.5,47.13 CPU1.A57 ; 65.53,47.47 v1(65.53,47.31)
HDMI_CLK#_R: length 3.8
  TOP w0.102: RN5402.5 17.13,83.16 v2(16.89,83.41) v1(16.89,83.97)
  BOTTOM w0.102: C5402.2 17.75,83.19 17.11,83.19 v2(16.89,83.41) 16.76,83.53 R5401.1
HDMI_CLK#_R_C: length 4
  BOTTOM w0.102: R5401.2 14.54,83.53 R5414.1 14.14,83.13 13.42,83.13 12.85,83.7 12.28,83.7 HDMI1.12
HDMI_CLK_R: length 3.8
  TOP w0.102: v1(16.79,82.22) 16.79,82.67 v2(16.89,82.77) 17.15,82.51 RN5402.6
  BOTTOM w0.102: R5402.1 16.76,82.64 v2(16.89,82.77) 17.11,82.99 17.75,82.99 C5403.2
HDMI_CLK_R_C: length 4
  BOTTOM w0.102: HDMI1.10 12.28,83.5 12.76,83.5 13.34,82.92 14.14,82.92 R5414.2 14.54,82.64 R5402.2
HDMI_DATA0: length 87.6
  L4 w0.114: v2(64.52,48.1) 64.52,48.38 64.34,48.56 63.75,48.56 63.45,48.85 63.27,48.85 62.93,48.85 57.68,43.61 48.66,43.61 47.23,45.03 36.21,45.03 30.81,50.44 30.81,55.51 26.85,59.47 26.85,66.09 22.74,70.2 20.88,70.2 20.64,70.43 20.64,75.2 19.02,76.82 19.02,79.14 19.51,79.62 20.04,79.62 v2(20.45,79.22)
  BOTTOM w0.102: CPU1.A55 71.83,48.66 71.83,48.81 71.58,49.05 71.27,49.05 70.6,49.73 66.67,49.73 ; v2(64.52,48.1) 64.52,48.35 64.39,48.48 64.21,48.48 64.08,48.61 64.08,49.08 64.73,49.73 66.67,49.73 ; 66.67,49.73 v1(66.67,49.57) ; v2(20.45,79.22) 20.23,79.43 19.33,79.43 C5405.1
HDMI_DATA0#: length 87.7
  L4 w0.114: v2(63.88,48.1) 63.36,48.62 63.03,48.62 57.78,43.38 48.56,43.38 47.14,44.81 36.12,44.81 30.58,50.34 30.58,55.42 26.62,59.38 26.62,66 22.65,69.97 20.78,69.97 20.42,70.34 20.42,75.11 18.8,76.73 18.8,79.23 19.41,79.85 v2(20.45,79.85)
  BOTTOM w0.102: 65.43,49.93 v1(65.43,50.08) ; 65.43,49.93 70.68,49.93 71.36,49.26 71.67,49.26 72.03,48.89 72.03,48.63 CPU1.B55 ; 65.43,49.93 64.64,49.93 63.88,49.17 v2(63.88,48.1) ; v2(20.45,79.85) 20.23,79.64 19.33,79.64 C5404.1
HDMI_DATA0#_R: length 3.8
  TOP w0.102: RN5403.5 17.26,79.48 v2(16.89,79.85) v1(16.89,80.41)
  BOTTOM w0.102: C5404.2 17.75,79.64 17.11,79.64 v2(16.89,79.85) 16.76,79.98 R5403.1
HDMI_DATA0#_R_C: length 9.5
  TOP w0.102: HDMI1.9 10.79,82.19 11.03,82.19 11.23,81.99 11.23,78.78 11.56,78.45 12.45,78.45 12.7,78.71 12.7,79.25 13.02,79.57 13.44,79.57 v2(13.72,79.85)
  BOTTOM w0.102: R5403.2 14.54,79.98 R5416.1 13.78,79.91 v2(13.72,79.85)
HDMI_DATA0_R: length 3.9
  TOP w0.102: v1(16.79,78.67) 16.79,79.11 v2(16.89,79.22) 17.28,78.83 RN5403.6
  BOTTOM w0.102: C5405.2 17.75,79.43 17.11,79.43 v2(16.89,79.22) 16.76,79.09 R5404.1
HDMI_DATA0_R_C: length 9.5
  TOP w0.102: HDMI1.7 10.76,81.98 10.95,81.98 11.02,81.91 11.02,78.7 11.47,78.25 12.53,78.25 12.9,78.62 12.9,79.17 13.11,79.37 13.44,79.37 v2(13.72,79.09)
  BOTTOM w0.102: v2(13.72,79.09) 13.78,79.03 R5416.2 14.54,79.09 R5404.2
HDMI_DATA1: length 90.3
  L4 w0.114: v2(66.42,46.07) 66.22,46.27 66.22,46.67 65.78,47.11 62.21,47.11 57.98,42.88 48.36,42.88 47.51,43.73 36.3,43.73 30.07,49.95 30.07,55.18 26.11,59.14 26.11,65.8 22.44,69.48 20.4,69.48 19.92,69.96 19.92,74.9 18.3,76.52 18.3,79.92 19.58,81.2 20.24,81.2 v2(20.45,80.99)
  BOTTOM w0.102: v2(66.42,46.07) 66.19,46.3 66.19,46.55 66.4,46.75 67.44,46.75 ; CPU1.C58 72.74,46.2 72.61,46.16 72.54,46.16 72.49,46.17 72.24,46.26 72.2,46.29 70.91,46.29 70.46,46.75 67.44,46.75 ; C5406.1 19.33,81.21 20.23,81.21 v2(20.45,80.99) ; 67.44,46.75 v1(67.44,46.6)
HDMI_DATA1#: length 90.3
  L4 w0.114: v2(65.79,46.07) 65.99,46.27 65.99,46.58 65.68,46.88 62.31,46.88 58.08,42.65 48.26,42.65 47.42,43.5 36.21,43.5 29.84,49.86 29.84,55.09 25.88,59.05 25.88,65.71 22.35,69.25 20.31,69.25 19.69,69.86 19.69,74.81 18.07,76.43 18.07,80.02 19.48,81.43 20.24,81.43 v2(20.45,81.63)
  BOTTOM w0.102: 68.58,46.95 66.31,46.95 65.99,46.63 65.99,46.27 v2(65.79,46.07) ; 68.58,46.95 70.54,46.95 71,46.5 72.54,46.5 CPU1.B58 ; 68.58,46.95 v1(68.58,47.11) ; v2(20.45,81.63) 20.23,81.41 19.33,81.41 C5409.1
HDMI_DATA1#_R: length 3.9
  TOP w0.102: v2(16.89,81.63) 17.28,82.01 RN5402.7
  BOTTOM w0.102: R5407.1 16.76,81.76 v2(16.89,81.63) ; v2(16.89,81.63) 17.11,81.41 17.75,81.41 C5409.2 ; v2(16.89,81.63) 16.89,81.88 v1(17.14,82.14)
HDMI_DATA1#_R_C: length 4
  BOTTOM w0.102: R5407.2 14.54,81.76 R5417.1 14.14,81.35 13.18,81.35 12.53,80.7 12.28,80.7 HDMI1.6
HDMI_DATA1_R: length 3.9
  TOP w0.102: RN5402.8 17.26,81.36 v2(16.89,80.99)
  BOTTOM w0.102: R5408.1 16.76,80.87 v2(16.89,80.99) ; v1(17.09,80.47) 16.89,80.67 v2(16.89,80.99) ; v2(16.89,80.99) 17.11,81.21 17.75,81.21 C5406.2
HDMI_DATA1_R_C: length 4
  BOTTOM w0.102: R5408.2 14.54,80.87 R5417.2 14.14,81.15 13.27,81.15 12.62,80.5 12.28,80.5 HDMI1.4
HDMI_DATA2: length 84.5
  L4 w0.114: v2(66.42,48.1) 66.42,48.38 66.29,48.51 66.14,48.51 66.01,48.63 66.01,48.98 65.25,49.75 62.81,49.75 57.38,44.33 48.96,44.33 47.53,45.76 36.54,45.76 31.55,50.75 31.55,55.84 27.84,59.55 27.84,66.2 21.91,72.13 21.91,75.96 21.33,76.55 20.32,76.55 19.75,77.12 19.75,77.6 19.86,77.72 20.17,77.72 v2(20.45,77.44)
  BOTTOM w0.089: CPU1.C55 72.63,48.14 72.57,48.06 72.38,47.97 72.22,47.95 72.13,47.96 72.11,47.96 72.11,47.96 71.97,48.02 71.87,48.02 71.73,47.97 71.7,47.95 71.6,47.91 71.34,47.91 70.82,48.42 70.81,48.42 70.8,48.44
  BOTTOM w0.102: 67.59,48.73 70.51,48.73 70.8,48.44 ; 67.59,48.73 66.17,48.73 66.07,48.63 66.07,48.45 v2(66.42,48.1) ; 67.59,48.73 v1(67.59,48.56) ; v2(20.45,77.44) 20.17,77.44 20.04,77.56 20.04,77.74 19.91,77.87 19.61,77.87 19.48,77.74 19.48,77.44 19.35,77.31 C5408.1
HDMI_DATA2#: length 84.6
  L4 w0.114: v2(65.79,48.1) 65.79,48.89 65.15,49.52 62.9,49.52 57.48,44.1 48.86,44.1 47.44,45.53 36.44,45.53 31.32,50.65 31.32,55.75 27.61,59.45 27.61,66.11 21.69,72.03 21.69,75.87 21.23,76.32 20.23,76.32 19.52,77.03 19.52,77.7 19.77,77.95 20.32,77.95 v2(20.45,78.07)
  BOTTOM w0.089: CPU1.C54 72.63,48.63 72.53,48.3 72.49,48.25 72.45,48.2 72.33,48.14 72.29,48.14 72.15,48.14 72.01,48.2 71.83,48.2 71.66,48.13 71.59,48.1 71.42,48.1 70.96,48.56 70.96,48.57 70.94,48.58
  BOTTOM w0.102: v1(68.71,49.09) 68.71,48.93 ; 68.71,48.93 66.08,48.93 65.87,48.72 65.87,48.18 v2(65.79,48.1) ; 68.71,48.93 70.59,48.93 70.94,48.58 ; v2(20.45,78.07) 19.53,78.07 19.4,78.2 C5407.1
HDMI_DATA2#_R: length 3.9
  TOP w0.102: v2(16.89,78.07) 17.17,78.07 17.42,78.33 RN5403.7
  BOTTOM w0.102: v2(16.89,78.07) 17.11,77.86 17.75,77.86 C5407.2 ; v2(16.89,78.07) 16.89,78.33 17.14,78.58 v1(17.14,78.71) ; v2(16.89,78.07) 16.76,78.2 R5405.1
HDMI_DATA2#_R_C: length 6
  BOTTOM w0.102: HDMI1.3 10.74,79.24 11.01,79.24 11.25,79 11.25,78.77 12.22,77.79 14.14,77.79 R5415.1 14.54,78.2 R5405.2
HDMI_DATA2_R: length 3.2
  TOP w0.102: RN5403.8 17.13,77.68 v2(16.89,77.44)
  BOTTOM w0.102: C5408.2 17.75,77.65 17.11,77.65 v2(16.89,77.44) 16.76,77.31 R5406.1
HDMI_DATA2_R_C: length 6
  BOTTOM w0.102: R5406.2 14.54,77.31 R5415.2 14.14,77.59 12.13,77.59 11.04,78.68 11.04,78.92 10.92,79.04 10.82,79.04 HDMI1.1
HDMI_EC_DET#: length 209.7
  TOP w0.102: R5422.1 17.86,62.21 17.86,43.81 19.43,42.23 19.43,39.72 v2(18.54,38.83) ; KBC24.118 152.74,53.62 152.35,53.23 152.35,52.87 152.6,52.62 154.23,52.62 v2(155.83,51.02)
  L3 w0.102: v2(155.83,51.02) 156.49,50.36 156.49,46.56 157.25,45.8 157.25,44.32 156.77,43.84 156.77,40.61 151.49,35.32 151.49,34.35 151.49,33.24 146.07,27.83 145.24,27.83 138.48,21.08 98.77,21.08 97.7,22.14 87.05,22.14 78.77,30.43 78.77,32.3 75.97,35.1 66.54,35.1 61.77,39.87 38.94,39.87 31.34,47.47 v2(28.07,47.47)
  BOTTOM w0.102: v2(18.54,38.83) v1(24.38,38.83) 25.43,39.87 26.44,39.87 29.21,42.64 29.21,46.32 v2(28.07,47.47)
HDMI_EC_DET#_C: length 3.9
  TOP w0.102: R5422.2 R5420.2 18.86,64.99 v1(19.05,64.99) 19.05,65.25 19.3,65.5 Q5404.D
HDMI_HPD_B: length 3.3
  TOP w0.102: v1(16.79,71.04) 17.09,71.34 v2(17.27,71.34) 17.65,71.34 18.48,70.51 Q5401.B
  BOTTOM w0.102: v2(17.27,71.34) 16.7,71.34 R5411.2
HDMI_HPD_E: length 7.6
  TOP w0.102: Q5401.E 19.44,69.31 18.16,69.31 17.91,69.56 17.91,70.2 17.4,70.71 v2(17.27,70.71)
  BOTTOM w0.102: v2(17.27,70.71) v1(18.54,70.71) 19.37,70.71 R5412.1 19.49,71.6 R5419.2
HDMI_PCH_DET: length 108.7
  L4 w0.102: v2(29.97,60.93) 29.47,60.43 29.47,59.85 33.45,55.88 33.45,51.23 37.16,47.52 45.14,47.52 45.72,48.1 46.03,48.1 46.03,48.1 59.39,48.1 60.85,49.56 60.85,57.3 62.23,58.69 62.23,61.14 61.03,62.34 58.24,62.34 56.4,64.17 56.4,70.76 61.1,75.46 61.1,78.21 61.98,79.09 v2(61.98,79.22)
  BOTTOM w0.102: R5419.1 19.56,72.55 20.64,73.63 21.55,73.63 28.96,66.23 v1(28.96,64.48) 28.96,61.94 v2(29.97,60.93) ; CPU1.C8 72.78,77.61 72.24,78.15 72.05,78.15 71.81,78.39 70.61,78.39 70.36,78.14 68.84,78.14 68.41,78.56 63.9,78.56 63.25,79.22 v2(61.98,79.22)
HDMI_PLL_GND:
  vias: v1(19.25,80.4)
HOME_BTN#: length 6.8
  TOP w0.102: KBC24.33 148.74,36.44 v1(148.46,36.16) 147.96,35.65 146.63,35.65 146.37,35.92 R2457.1 146.11,35.91 R2454.1
HOME_BTN#_C: length 220
  TOP w0.102: R2457.2 147.57,36.16 148.33,36.92 148.33,40.1 148.72,40.48 v2(148.97,40.48)
  L3 w0.102: v2(33.15,43.66) 31.37,45.43 27.69,45.43 26.26,46.86 26.26,48.03 22.3,52 22.3,69.36 21.84,69.82 21.84,71.29 21.84,83.36 20.14,85.06 20.14,86.37 21.17,87.39 22.06,87.39 25.56,90.9 27.31,90.9 28.51,92.11 30.47,92.11 30.73,92.38 30.73,93.94 34.67,97.88 v2(34.67,98.14)
  L4 w0.102: v2(34.42,32.73) 35.51,33.83 67.96,33.83 71.77,37.64 74.35,37.64 77.78,34.21 80.99,34.21 88.81,26.38 106.52,26.38 107.23,27.1 109.19,27.1 109.57,26.71 125.56,26.71 126.2,27.35 132.33,27.35 138.37,33.38 141.11,33.38 143.89,36.16 144.91,36.16 146.69,37.94 146.69,39.34 147.83,40.48 v2(148.97,40.48)
  BOTTOM w0.102: HOMBD1.8 32.79,98.75 33.4,98.14 v2(34.67,98.14) ; v2(34.42,32.73) 35.1,33.42 35.1,39.11 33.15,41.07 v1(33.15,42) v2(33.15,43.66)
HPD_HDMI_CON: length 24.2
  TOP w0.102: v2(17.27,72.61) 17.02,72.61 15.88,73.75 15.88,81.63 13.72,83.79 v2(13.72,86.45)
  L4 w0.102: HDMI1.19 11.01,88.23 12.45,88.23 13.72,86.96 v2(13.72,86.45)
  BOTTOM w0.102: R5421.2 17.34,72.55 v2(17.27,72.61) 17.08,72.42 R5411.1 16.51,72.89 v1(16.05,73.35) 15.94,73.46 R5410.1
HPD_HDMI_CON_C: length 8.7
  TOP w0.102: Q5404.G 20.29,68.77 20.89,69.37 20.89,70.9 20.57,71.21 18.41,71.21 17.65,71.98 v2(17.27,71.98) 17.12,71.98 v1(16.79,72.31)
  BOTTOM w0.102: v2(17.27,71.98) 17.59,71.66 R5421.1
HSIO_OUT:
  vias: v1(58.38,71.85)
HSIOPC: length 39.1
  TOP w0.102: v2(66.55,89.12) 65.91,89.12 59.49,82.7 59.49,81.81 56.64,78.96 56.64,77.82 56.96,77.5 R2007.1 R2123.1
  BOTTOM w0.089: CPU1.Y2 82.27,81.45 82.27,82.06 82.17,82.16 82.17,82.94 82.19,82.97 82.19,83.57
  BOTTOM w0.102: v2(66.55,89.12) v1(70.74,89.12) 71.41,89.12 73.19,87.34 80.52,87.34 81.66,86.2 81.66,84.1 82.19,83.57
HSIOPC_R: length 2.3
  TOP w0.102: v1(57.71,74.9) v2(57.15,74.9) R2123.2
  BOTTOM w0.102: U2101.9 v2(57.15,74.9)
HUB_PA1: length 6.5
  TOP w0.152: R6620.1 107.06,111.22 v1(106.57,110.72) 106.36,110.52 R6619.2 104.39,109.63 104.39,108.3 103.85,107.75 U6601.11
HUB_PA2: length 5.3
  TOP w0.152: R6618.1 R6617.2 104.39,110.78 104.39,110.42 v1(104.37,110.39) 104.01,110.04 104.01,108.68 103.59,108.26 U6601.12
HUB_PA3: length 3.9
  TOP w0.152: R6615.2 R6616.1 103.5,110.82 v1(103.15,110.46) 102.45,109.76 U6601.13
HUB_PA4: length 3.6
  TOP w0.152: R6614.1 R6613.2 101.73,110.7 v1(101.93,110.49) 101.94,110.48 U6601.14
HUB_PA5: length 3.9
  TOP w0.152: R6612.1 R6611.2 100.84,110.84 v1(100.71,110.71) 101.45,109.98 U6601.15
HUB_PA6: length 6.5
  TOP w0.152: U6601.16 100.94,109.84 98.3,112.49 R6610.1 v1(97.33,112.49) R6609.2
HVM_CLK: length 2.2
  TOP w0.102: TP620.1 79.96,72.05 v2(79.76,71.85)
  BOTTOM w0.102: CPU1.R20 80.23,71.38 v2(79.76,71.85)
HVM_CLK#: length 1.9
  TOP w0.102: v2(79.76,71.21) 78.97,70.43 TP619.1
  BOTTOM w0.102: CPU1.P20 79.42,70.88 v2(79.76,71.21)
I2C0_SCL: length 15.1
  BOTTOM w0.089: 73.72,82.59 73.97,82.59 74.51,82.06 74.51,81.39 74.7,81.2 74.7,80.91 CPU1.F3
  BOTTOM w0.114: 64.25,80.37 63.81,80.81 RN2007.4 ; 64.25,80.37 64.53,80.09 66.71,80.09 68.17,81.56 68.51,81.56 69.54,82.59 73.72,82.59 ; 64.25,80.37 v1(64.16,80.28)
I2C0_SDA: length 14
  BOTTOM w0.089: 73.88,82.94 73.9,82.94 74.7,82.14 74.7,81.53 74.86,81.36 CPU1.F2
  BOTTOM w0.114: 73.88,82.94 69.4,82.94 68.37,81.9 68.03,81.9 66.57,80.44 65.41,80.44 ; RN2007.3 64.46,80.75 64.77,80.44 65.41,80.44 ; 65.41,80.44 v1(65.41,80.56)
I2C1_SCL: length 122.7
  TOP w0.114: R6212.1 EC6203.1 124.27,24.68 124.83,25.24 v2(124.84,25.24) ; v2(65.91,80.99) 64.95,81.95 RN2008.3
  L3 w0.127: v2(124.84,25.24) 123.95,24.35 108.67,24.35 108.11,24.91 99.15,24.91 97.43,26.64 89.41,26.64 79.38,36.67 79.38,40.07 78.47,40.97 78.47,43.04 79.18,43.75 79.34,43.75 79.81,44.22 79.81,45.88 79.36,46.34 79.36,48.38 77.91,49.83 77.91,68.33 77.5,68.74 76.8,68.74 76.34,68.28 73.56,68.28 71.79,70.05 71.79,71.6 71.3,72.09 69.6,72.09 65.84,75.85 65.74,75.85 64.96,76.63 64.96,79.41 65.91,80.36 v2(65.91,80.99)
  BOTTOM w0.114: v2(124.84,25.24) 124.76,25.16 Q6204.1 ; CPU1.F1 75.02,82.35 74.09,83.28 68.93,83.28 68.31,82.66 ; 68.31,82.66 66.77,81.12 66.04,81.12 v2(65.91,80.99) ; 68.31,82.66 v1(68.4,82.57)
I2C1_SCL_R: length 13.1
  TOP w0.114: v2(122.43,25.24) 122.49,25.18 R6212.2 122.36,24.35 116.2,24.35 115.44,25.11 v2(115.44,25.37) 115.75,25.68 RN6204.3
  BOTTOM w0.114: v2(122.43,25.24) 122.89,24.78 Q6204.6 ; TP1.6 115.3,25.22 v2(115.44,25.37) 115.95,25.88 AFTP6237.1
I2C1_SDA: length 126
  TOP w0.114: RN2008.4 65.6,81.94 v2(65.91,81.63) ; R6213.1 EC6204.1 124.27,25.3 v2(124.21,25.24)
  L3 w0.127: v2(124.21,25.24) 123.7,24.73 108.83,24.73 108.27,25.29 99.31,25.29 97.58,27.02 89.57,27.02 79.76,36.83 79.76,40.23 78.85,41.13 78.85,42.88 79.34,43.37 79.5,43.37 80.19,44.06 80.19,46.04 79.74,46.49 79.74,48.54 78.3,49.99 78.3,68.48 77.66,69.12 76.64,69.12 76.18,68.66 73.72,68.66 72.17,70.2 72.17,71.75 71.46,72.47 69.76,72.47 66,76.23 65.9,76.23 65.34,76.79 65.34,79.25 66.42,80.33 66.42,81.12 v2(65.91,81.63)
  BOTTOM w0.114: Q6204.4 123.68,23.19 123.83,23.34 123.83,24.86 v2(124.21,25.24) ; 67.3,82.14 68.78,83.62 74.23,83.62 75.28,82.58 75.28,82.12 75.44,81.96 75.44,80.2 CPU1.G4 ; 67.3,82.14 v1(67.21,82.24) ; 67.3,82.14 66.62,81.46 66.08,81.46 v2(65.91,81.63)
I2C1_SDA_R: length 17.8
  TOP w0.114: R6213.2 121.79,25.3 v2(121.79,25.24) 121.25,24.69 116.35,24.69 116.08,24.96 v2(116.08,25.37) 116.4,25.69 RN6204.4
  BOTTOM w0.114: Q6204.3 124.19,23.19 123.7,22.7 122.17,22.7 121.48,23.39 121.48,24.93 v2(121.79,25.24) ; TP1.7 116.3,25.15 v2(116.08,25.37) 117.47,26.76 AFTP6240.1
ILIM_HI: length 2.6
  TOP w0.102: R3508.2 27.3,52.67 v2(27.94,53.31)
  BOTTOM w0.102: v1(28.57,53.31) v2(27.94,53.31) 27.67,53.57 U3503.16
ILIM_LO: length 2.6
  TOP w0.102: v2(27.94,53.94) 27.56,53.56 R3506.2
  BOTTOM w0.102: v1(28.57,54.53) 27.99,53.94 v2(27.94,53.94) 27.81,54.07 U3503.15
ILIM_SEL: length 4.4
  BOTTOM w0.102: U3503.4 22.73,52.77 22.48,53.03 v1(22.48,53.05) R3505.2
IMVP_PWRGD: length 152.8
  TOP w0.102: KBC24.107 157.14,51.32 156.21,50.39 v2(155.83,50.39) ; v2(46.61,48.61) 46.74,48.61 47.24,49.12 PR4614.2 EC4602.1 PR4625.2
  L3 w0.102: v2(46.61,48.61) 48.64,48.61 49.66,47.59 49.66,44.7 51.34,43.02 61.47,43.02 v2(62.48,42) 62.48,40.56 66.95,36.09 77.37,36.09 81.36,32.1 81.36,28.97 85.42,24.91 96.72,24.91 98.98,22.65 107.64,22.65 108.33,21.96 126.45,21.96 126.99,22.51 139.05,22.51 145.01,28.47 145.85,28.47 150.88,33.5 150.88,35.58 156.16,40.86 156.16,48.05 156.18,48.07 156.18,50.03 v2(155.83,50.39)
  BOTTOM w0.102: v2(62.48,42) R713.1 ; v2(155.83,50.39) 156.08,50.64 v1(156.34,50.64)
IMVP_PWRGD_R: length 11.5
  BOTTOM w0.089: CPU1.C59 72.66,45.91 72.36,45.62 72.13,45.62 71.92,45.41 71.4,45.41 71.36,45.37
  BOTTOM w0.102: R713.2 R710.2 R712.1 EC702.1 65.72,44.16 65.72,44.48 66.15,44.9 67.84,44.9 68.27,45.33 v1(68.45,45.33) 71.32,45.33 71.36,45.37
IMVP_VRON: length 2.7
  TOP w0.102: PR4615.1 45.09,52.8 v1(44.58,52.29) 43.82,51.53 PU4601.8
INT2_SELECT: length 197.1
  TOP w0.152: v2(78.99,84.17) 78.92,84.25 74.37,84.25 74.17,84.04 R2025.2 ; v2(154.05,19.65) 155.83,21.43 155.83,26.13 159.89,30.19 159.89,33.37 159.38,33.88 v1(159.38,34.38) 159.38,36.67 v2(159.13,36.92)
  L3 w0.152: v2(159.13,36.92) 158.88,36.92 157.4,38.4 157.4,43.86 157.68,44.14 157.68,45.98 156.92,46.74 156.92,55.51 156.77,55.66 156.77,55.8 156.49,56.08 156.49,59.3 156.67,59.48 156.67,64.01 140.92,79.76 140.92,82.46 140.21,83.17 140.21,96.03 129.59,106.65 116.89,106.65 113.76,109.77 101.83,109.77 101,108.95 93.83,108.95 86.67,101.78 81.84,101.78 79.35,99.3 79.35,90.17 78.99,89.81 v2(78.99,84.17)
  L4 w0.152: v2(159.13,36.92) 158.67,36.47 150.32,36.47 v2(150.11,36.67)
  BOTTOM w0.152: v2(150.11,36.67) D6701.3 150.11,38.58 150.56,39.02 R6705.2 ; CPU1.P1 79.56,82.08 79.42,82.21 79.42,83.75 v2(78.99,84.17) ; Q6701.5 v2(154.05,19.65)
INT_SERIRQ: length 167.9
  TOP w0.114: v2(80.67,80.18) 80.67,80.95 79.59,82.03 79.59,83.68 79.76,83.85 79.76,84.49 79.06,85.19 v1(71.63,85.19) RN1902.2 ; v2(155.74,49.52) 152.9,49.52 150.47,51.95 150.47,53.33 149.94,53.86 KBC24.125
  L3 w0.127: v2(155.74,49.52) 155.38,49.87 155.38,59.98 156.15,60.74 156.15,63.97 140.53,79.59 140.53,82.3 139.81,83.01 139.81,95.66 129.22,106.25 116.73,106.25 113.6,109.38 102.04,109.38 101.22,108.55 94,108.55 86.83,101.39 82,101.39 79.74,99.13 79.74,90.01 79.58,89.85 79.58,82.28 80.67,81.2 v2(80.67,80.18)
  BOTTOM w0.114: v2(80.67,80.18) 80.35,79.86 CPU1.T4
INT_TP#: length 135.4
  TOP w0.102: R2426.1 151.32,58.83 150.34,57.85 v2(150.34,57.24) ; D2001.K 110.36,86.71 108.33,84.68 v2(107.44,84.68) ; R6203.2 v2(114.55,25.37)
  L3 w0.102: v2(114.55,25.37) 115.06,25.88 125.86,25.88 126.8,26.82 140.99,26.82 145.62,31.45 145.62,38.27 146.56,39.21 146.56,40.07 147.65,41.16 147.65,54.55 v2(150.34,57.24)
  BOTTOM w0.102: TP1.4 113.3,24.75 113.92,25.37 v2(114.55,25.37) 114.55,26.26 AFTP6241.1 113.39,26.76 105.82,34.33 105.82,79.87 107.44,81.5 v2(107.44,84.68)
INT_TP#_C: length 55.1
  TOP w0.102: v2(89.79,100.04) R2027.2 89.09,99.35 90.3,98.14 96.77,98.14 97.96,96.95 106.5,96.95 107.74,95.71 107.74,95.12 108.94,93.92 v1(108.94,93.62) 108.94,92.2 110.36,90.77 D2001.A ; R2008.2 71.66,87.03 71.09,86.45 v2(70.87,86.45) ; v2(80.39,97.76) 77.28,94.65 R2026.2 77.28,93.88 v2(77.22,93.82)
  L4 w0.102: v2(80.39,97.76) 80.39,97.88 81.66,99.15 88.9,99.15 v2(89.79,100.04) ; v2(77.22,93.82) 71.75,88.36 71.75,87.34 v2(70.87,86.45)
JACK_PLUG: length 20.5
  L3 w0.254: v2(15.88,34.13) 16.85,34.13 18.63,35.91 21.32,35.91 v2(21.44,35.78)
  BOTTOM w0.254: v2(21.44,35.78) 20.95,36.27 ED2904.2 20.7,34.79 C2902.2 20.89,34.55 R2905.1 20.89,32.38 Q2901.G 19.85,32.29 R2914.1 ; v2(15.88,34.13) AFTP2909.1 14.48,34.64 11.24,34.64 HPMIC1.6
JACK_POWER: length 17.9
  TOP w0.254: R2923.2 22.1,35.08 ED2906.2 ; R2916.2 23.43,36.8 22.48,36.8 22.1,36.42 ED2906.2 ; ED2906.2 21.71,36.27 v2(21.44,36.54)
  L3 w0.254: v2(21.44,36.54) 21.31,36.42 18.41,36.42 16.76,34.77 14.12,34.77 HPMIC1.5
  BOTTOM w0.254: AFTP2910.1 15.88,32.35 14.63,33.6 HPMIC1.5
JDREF: length 3
  TOP w0.102: R2707.1 25.98,29.99 v1(25.96,29.97) 25.96,29.48 25.28,28.8 HDA27.15
KB_BL_CTRL: length 161.4
  TOP w0.102: v2(32,16.48) 31.75,16.48 30.86,15.59 28.84,15.59 28.02,14.78 24.08,14.78 v1(23.16,13.85) 22.25,12.95 Q6202.G 22.19,11.46 R6208.1 ; KBC24.22 146.38,44.76 v2(145.99,44.37)
  L3 w0.102: v2(32,16.48) 32.73,17.2 32.73,17.91 32.97,18.15 32.97,33.83 33.78,34.64 v2(33.78,34.89)
  L4 w0.102: v2(145.99,44.37) 145.29,43.67 145.29,42.3 139.18,36.19 137.45,36.19 133.15,31.9 131.76,31.9 128.49,28.62 121.91,28.62 121.4,28.11 109.97,28.11 109.34,28.75 98.98,28.75 97.89,27.65 89.36,27.65 81.53,35.48 78.31,35.48 74.88,38.91 71.25,38.91 67.44,35.1 33.99,35.1 v2(33.78,34.89)
KB_BL_CTRL#: length 1
  TOP w1.016: v3(24.51,9.49) 24.49,9.52 Q6202.D
KB_CLOSE#_2: length 210.4
  TOP w0.102: v2(157.4,48.1) 158.12,48.1 158.93,47.29 159.97,47.29 160.71,48.02 161.72,48.02 161.79,47.96 KBC24.83
  L3 w0.102: v2(33.66,43.15) 33.02,43.15 30.94,45.23 27.6,45.23 26.06,46.77 26.06,47.95 22.1,51.91 22.1,69.26 21.34,70.02 v2(21.34,70.71)
  L4 w0.102: v2(157.4,48.1) 157.05,47.75 157.05,47.29 157.35,46.98 157.35,44.34 154.81,41.8 154.81,40.73 153.92,39.85 149.81,39.85 143.14,33.18 138.45,33.18 132.42,27.15 126.28,27.15 125.65,26.51 109.49,26.51 109.11,26.89 107.31,26.89 106.6,26.18 88.73,26.18 80.91,34 77.7,34 74.27,37.43 71.86,37.43 68.05,33.62 35.94,33.62 v2(34.42,32.1)
  BOTTOM w0.102: LIDSW1.3 9.87,73.31 C6401.1 R6401.1 15.88,72.55 15.88,71.39 16.99,70.28 20.9,70.28 v2(21.34,70.71) ; v2(34.42,32.1) v1(35.05,32.73) 35.31,32.99 35.31,39.2 33.53,40.98 33.53,43.02 v2(33.66,43.15)
KB_DISABLE: length 104.5
  TOP w0.102: U6601.2 104.64,103.26 v2(104.65,103.26) 104.65,103.61 v1(104.45,103.81) ; v2(151.78,46.7) 149.68,46.7 148.54,47.85 148.54,48.55 147.93,49.16 KBC24.11
  L3 w0.102: v2(151.78,46.7) 151.43,47.06 151.43,60.11 149.49,62.05 146.34,62.05 142.55,65.83 140.79,65.83 140.36,66.26 140.36,68.28 139.27,69.37 139.27,73.18 138.23,74.22 138.23,81.42 137.57,82.08 137.57,89.45 135.46,91.56 135.46,96.39 128.04,103.8 114.75,103.8 111.85,106.7 106.99,106.7 104.65,104.36 v2(104.65,103.26)
KB_LED_BL_DET: length 3.2
  TOP w0.102: TP2015.1 v2(75.31,83.79)
  BOTTOM w0.102: CPU1.J1 76.37,82.01 76.37,82.86 75.44,83.79 v2(75.31,83.79)
KBC_BEEP: length 133.4
  TOP w0.203: KBC24.32 147.19,40.23 146.96,40 144.37,40 v2(144.27,40.1)
  L4 w0.254: v2(29.58,36.03) 31.66,33.95 34.34,33.95 34.85,34.46 67.7,34.46 71.51,38.27 74.62,38.27 78.05,34.84 81.25,34.84 89.08,27.02 106.26,27.02 106.97,27.73 109.46,27.73 109.71,27.48 120.88,27.48 121.66,27.48 122.17,27.98 128.75,27.98 132.03,31.26 133.42,31.26 137.71,35.55 140.14,35.55 144.27,39.69 v2(144.27,40.1)
  BOTTOM w0.254: RN2701.1 29.63,36.07 v2(29.58,36.03) ; v1(144.42,39.49) 144.42,39.95 v2(144.27,40.1)
KBC_BEEP_R: length 3.2
  BOTTOM w0.254: RN2701.4 30.83,36.64 v1(30.23,36.04) 30.13,35.94 D2701.1
KBC_DPWROK: length 120.7
  TOP w0.102: v2(150.88,48.1) 151.58,48.81 155.63,48.81 156.84,47.59 156.84,47.49 157.3,47.03 161.14,47.03 161.26,47.16 161.72,47.16 161.73,47.16 KBC24.81 ; v2(99.95,92.68) 100.2,92.42 v1(100.2,91.53) 100.2,90.01 100.77,89.44 R1725.2 EC1705.1 R1718.2
  L3 w0.102: v2(150.88,48.1) 150.98,48.2 150.98,60.27 149.4,61.84 146.25,61.84 142.47,65.63 140.71,65.63 140.16,66.18 140.16,68.2 139.04,69.31 139.04,73.07 138.02,74.09 138.02,81.33 137.36,81.99 137.36,89.37 135.2,91.53 135.2,96.34 127.94,103.6 113.83,103.6 112.81,102.58 112.14,102.58 111.12,101.57 108.55,101.57 108.08,101.57 105.31,98.8 103.46,98.8 99.52,94.85 99.52,93.11 v2(99.95,92.68)
KBC_ON#_GATE: length 8.9
  BOTTOM w0.102: C2417.1 138.94,35.34 138.94,33.81 R2433.2 138.75,32.9 v1(138.56,32.71) 136.96,32.71 Q2403.G Q2402.G
KBC_ON#_GATE_L: length 57
  TOP w0.102: v2(150.11,27.4) 148.23,27.4 138.75,36.88 138.18,36.88 138.18,36.88 137.2,36.88 136.02,38.07 v2(134.87,38.07) ; v2(163.32,31.08) 163.58,31.34 163.58,33.37 164.85,34.64 R2432.2
  L4 w0.102: v2(163.32,31.08) 159.64,27.4 v2(150.11,27.4)
  BOTTOM w0.102: R2433.1 137.67,33.62 137.29,34 137.29,35.02 137.92,35.65 v1(137.92,35.91) 137.92,37.12 R2431.1 137.43,37.61 135.33,37.61 v2(134.87,38.07) ; D2402.2 151.1,32.26 152.15,31.21 152.15,28.03 151.51,27.4 v2(150.11,27.4)
KBC_PWRBTN#: length 42.8
  TOP w0.102: v2(162.81,61.82) 164.31,61.82 167.33,58.8 167.33,56.05 166.69,55.4 R2427.1
  L3 w0.102: v2(161.54,51.91) 161.09,52.37 161.09,55.15 162.81,56.87 v2(162.81,61.82)
  BOTTOM w0.102: IOBD1.7 147.12,51.75 146.78,51.4 146.78,48.52 147.63,47.67 152.15,47.67 153.42,48.94 v1(160.53,48.94) 160.91,49.32 160.91,51.28 v2(161.54,51.91)
KBC_VCORF: length 2.7
  TOP w0.203: v1(153.03,37.61) 153.14,37.72 KBC24.44
  TOP w0.254: v1(153.03,37.61) 152.91,37.48 C2416.1
KCOL0: length 6
  TOP w0.102: KBC24.53 156.74,38.02 157.73,37.02 157.73,36.95 v2(157.75,36.92)
  BOTTOM w0.102: AFTP6217.1 154.63,37 KB1.20 157.66,37 157.73,36.92 v2(157.75,36.92)
KCOL1: length 10.1
  TOP w0.102: KBC24.52 156.34,37.68 157.12,36.9 157.12,33.85 v2(157.86,33.11)
  BOTTOM w0.102: AFTP6219.1 154.67,33 KB1.16 157.75,33 v2(157.86,33.11)
KCOL2: length 12.7
  TOP w0.102: v2(157.86,31.08) 156.72,32.23 156.72,36.8 155.94,37.58 KBC24.51
  BOTTOM w0.102: AFTP6216.1 155.19,30.57 155.78,30.57 156.21,31 KB1.14 157.78,31 v2(157.86,31.08)
KCOL3: length 21.4
  TOP w0.102: v2(158.51,31.08) 158.08,30.65 157.66,30.65 156.34,31.97 156.34,36.7 155.54,37.5 KBC24.50
  BOTTOM w0.102: AFTP6214.1 153.62,26.43 155.25,26.43 155.68,26 KB1.9 157.48,26 158.32,26.84 158.32,30.89 v2(158.51,31.08)
KCOL4: length 21.1
  TOP w0.102: KBC24.49 155.14,41.17 154.51,41.8 152.32,41.8 v2(151.76,41.24)
  BOTTOM w0.102: KB1.13 155.77,30 155.4,30.37 153.49,30.37 AFTP6210.1 152.15,31.72 152.15,39.21 151.35,40.01 151.35,40.82 v2(151.76,41.24)
KCOL5: length 9.5
  TOP w0.102: v2(155.57,34.51) 155.57,36.89 154.74,37.73 KBC24.48
  BOTTOM w0.102: AFTP6215.1 152.65,34.97 153.11,34.51 v2(155.57,34.51) 156.09,34 KB1.17
KCOL6: length 16.8
  TOP w0.102: v2(157.86,29.81) 155.07,32.61 155.07,36.47 154.34,37.19 KBC24.47
  BOTTOM w0.102: v2(157.86,29.81) 157.86,27.53 157.33,27 KB1.10 154.96,27 AFTP6212.1
KCOL7: length 13.3
  TOP w0.102: v2(154.81,29.81) 154.81,31.24 152.45,33.61 152.45,37.69 152.74,37.98 KBC24.43
  BOTTOM w0.102: KB1.12 154.85,29 154.56,29.29 AFTP6211.1 154.81,29.56 v2(154.81,29.81)
KCOL8: length 16.5
  TOP w0.102: v2(154.18,29.81) 154.18,31.59 152.25,33.52 152.25,38.04 152.34,38.14 KBC24.42
  BOTTOM w0.102: v2(154.18,29.81) 153.54,29.81 153.03,29.3 AFTP6213.1 153.96,28 KB1.11
KCOL9: length 6.6
  TOP w0.102: v2(151.78,40.48) 151.94,40.32 KBC24.41
  BOTTOM w0.102: KB1.23 153.39,40 AFTP6223.1 152.03,40.73 v2(151.78,40.48)
KCOL10: length 21.6
  TOP w0.102: v2(154.94,22.7) 155.07,22.83 155.07,24.61 153.67,26 153.67,31.79 151.54,33.92 KBC24.40
  BOTTOM w0.102: KB1.4 155.63,21 155.24,21 AFTP6225.1 154.56,22.32 v2(154.94,22.7)
KCOL11: length 23.7
  TOP w0.102: KBC24.39 151.14,34.03 153.42,31.76 153.42,24.86 v2(153.92,24.35)
  BOTTOM w0.102: KB1.5 156.28,22 155.13,23.15 154.5,23.15 153.92,23.72 v2(153.92,24.35) 151.89,24.35 AFTP6224.1
KCOL12: length 18.3
  TOP w0.102: KBC24.38 150.74,36.94 150.75,36.93 150.75,35.92 150.94,35.73 150.94,33.95 152.91,31.98 v2(152.91,26)
  BOTTOM w0.102: KB1.8 155.44,25 154.94,25.49 AFTP6218.1 153.42,25.49 v2(152.91,26)
KCOL13: length 19.5
  TOP w0.102: v2(152.27,26) 152.27,27.4 152.58,27.7 152.58,32.02 150.73,33.87 150.73,35.64 150.55,35.83 150.55,36.85 150.34,37.06 KBC24.37
  BOTTOM w0.102: KB1.7 155.67,24 154.81,24.86 153.29,24.86 AFTP6221.1 152.27,25.88 v2(152.27,26)
KCOL14: length 21.8
  TOP w0.102: v2(154.56,24.35) 154.13,23.92 153.59,23.92 151.76,25.75 151.76,27.27 152.37,27.88 152.37,31.94 150.53,33.78 150.53,35.56 149.68,36.41 149.68,36.85 149.94,37.11 KBC24.36
  BOTTOM w0.102: v2(154.56,24.35) AFTP6222.1 155.32,23.59 155.91,23 KB1.6
KCOL15: length 25.6
  TOP w0.102: v2(154.31,22.7) 153.85,23.16 153.85,23.26 153.6,23.51 153.49,23.51 151.56,25.44 151.56,27.36 152.17,27.97 152.17,31.82 149.48,34.51 149.48,36.93 149.54,37 KBC24.35
  BOTTOM w0.102: AFTP6220.1 153.52,23.59 153.85,23.26 153.85,23.16 v2(154.31,22.7) 154.2,22.6 154.2,21.3 155.51,20 KB1.3
KCOL16: length 168
  TOP w0.102: v2(151.13,26) 151.13,28.8 149.22,30.7 149.22,36.71 149.14,36.8 KBC24.34
  L4 w0.102: v2(151.13,26) 143.92,26 138.2,20.29 112.23,20.29 110.35,22.17 101.7,22.17 101.17,21.64 88.82,21.64 87.76,22.7 80.64,22.7 79.58,21.63 74.88,21.63 69.72,16.48 50.55,16.48 49.53,15.46 49.53,5.94 47.12,3.52 44.2,3.52 43,2.33 28.14,2.33 23.5,6.98 v2(23.5,9.49)
  BOTTOM w0.102: v2(23.5,9.49) 23.3,9.69 KBLIT1.4 23.3,11.47 AFTP6229.1
KROW0: length 13.9
  TOP w0.102: v2(158.5,33.11) 157.56,34.05 157.56,36.11 158.19,36.74 158.19,37.18 157.14,38.23 KBC24.54
  BOTTOM w0.102: AFTP6208.1 153.77,32 KB1.15 157.38,32 v2(158.5,33.11)
KROW1: length 8
  TOP w0.102: v2(158.88,41.64) 157.54,40.3 KBC24.55
  BOTTOM w0.102: AFTP6228.1 155.96,42.64 156.32,43 KB1.26 157.25,43 158.61,41.64 v2(158.88,41.64)
KROW2: length 9.9
  TOP w0.102: v2(157.99,35.53) 157.99,36.14 158.39,36.54 158.39,37.26 157.94,37.71 KBC24.56
  BOTTOM w0.102: AFTP6206.1 153.58,36 KB1.19 157.52,36 v2(157.99,35.53)
KROW3: length 8.2
  TOP w0.102: KBC24.57 158.34,38.14 158.32,38.12 158.32,37.62 158.62,37.32 158.62,36.29 158.45,36.11 158.45,35.35 v2(157.99,34.89)
  BOTTOM w0.102: AFTP6207.1 154.58,35 KB1.18 157.88,35 v2(157.99,34.89)
KROW4: length 6
  TOP w0.102: KBC24.58 158.74,37.95 v2(158.75,37.94)
  BOTTOM w0.102: AFTP6203.1 154.73,39 KB1.22 157.69,39 v2(158.75,37.94)
KROW5: length 8.9
  TOP w0.102: v2(159.41,37.95) 159.41,38.06 159.14,38.32 KBC24.59
  BOTTOM w0.102: AFTP6227.1 153.48,38 KB1.21 157.93,38 158.42,37.51 158.97,37.51 v2(159.41,37.95)
KROW6: length 6.4
  TOP w0.102: v2(158.89,40.37) 159.38,40.37 159.54,40.21 KBC24.60
  BOTTOM w0.102: v2(158.89,40.37) 158.25,41 KB1.24 154.82,41 AFTP6202.1
KROW7: length 9.4
  TOP w0.102: KBC24.61 159.94,40.36 159.3,41 v2(158.88,41)
  BOTTOM w0.102: v2(158.88,41) 157.88,42 KB1.25 153.29,42 AFTP6201.1
L_BKLT_CTRL: length 33.4
  TOP w0.114: v2(69.09,91.79) 69.09,91.79 71.32,94.02 v1(73.34,94.02) 74.13,94.02 75.69,95.58 75.69,97.64 75.12,98.2 R5224.2 72.87,98.36 D5202.1
  L4 w0.127: v2(70.87,77.56) 69.09,79.34 v2(69.09,91.79)
  BOTTOM w0.114: CPU1.B8 72.23,77.14 71.8,77.57 70.88,77.57 v2(70.87,77.56)
L_BKLT_EN: length 165.7
  L3 w0.102: v2(157.48,47.47) 157.91,47.9 157.91,59.25 158.51,59.84 158.51,63.65 141.96,80.19 141.96,86.31 141.33,86.94 141.33,98.31 140.61,99.03 140.61,100.2 140.61,100.37 138.49,102.49 138.13,102.68 136.52,103.53 132.27,105.45 131.54,106.17 130.02,107.69 117.32,107.69 114.12,110.89 93.22,110.89 85.64,103.31 81.32,103.31 76.71,98.7 76.71,96.61 71.89,91.79 v2(70.99,91.79)
  L4 w0.102: v2(70.99,91.79) 71.25,91.53 71.25,87.5 70.43,86.68 70.43,81.68 71.3,80.82 71.3,76.98 v2(70.87,76.55)
  BOTTOM w0.102: v2(70.87,76.55) 71.05,76.36 CPU1.A9 ; v2(157.48,47.47) 156.66,47.47 v1(155.74,46.54) 154.36,45.16 154.36,44.91 R2444.1
L_BKLT_EN_EC: length 14
  TOP w0.102: v2(153.92,45.24) 152.68,46.48 152.68,47.11 152.15,47.64 149.73,47.64 149.15,48.23 149.15,48.99 148.18,49.96 KBC24.9 145.52,49.96 v1(145.48,50)
  BOTTOM w0.102: v2(153.92,45.24) 153.35,45.24 152.72,44.61 R2444.2 R2447.1
LCD_BRIGHTNESS: length 6.8
  TOP w0.114: v2(53.72,96.23) 53.34,96.61 EC5207.1 53.02,95.66 v1(52.98,95.62) 52.98,95.43 52.24,94.68 RN5201.4
  BOTTOM w0.114: v2(53.72,96.23) 53.05,95.56 LCD1.26
LCD_TST: length 26.3
  TOP w0.102: RN5201.8 55.79,94.2 57.66,94.2 v1(57.78,94.33) 58.42,94.33 59.44,95.34 v2(59.44,96.11) ; R2417.1 73.6,99.03 69.09,99.03 68.71,98.65 68.71,97.63 68.96,97.38 v2(69.09,97.38) 69.09,96.84 D5202.2
  L3 w0.102: v2(59.44,96.11) 60.71,97.38 v2(69.09,97.38)
LCD_TST_C: length 3.7
  TOP w0.102: v2(54.61,95.47) 54.04,94.9 v1(54.04,94.52) RN5201.1
  BOTTOM w0.102: LCD1.23 54.55,95.41 v2(54.61,95.47)
LCD_TST_EN: length 161.1
  TOP w0.102: v1(145.44,42.34) 145.46,42.36 KBC24.28 148.24,42.36 148.59,42 158.6,42 158.87,42.27 v2(158.88,42.27) ; v2(74.8,101.06) 75.25,100.62 R2417.2 75.25,99.63 D5201.2
  L3 w0.102: v2(74.8,101.06) 75.41,101.06 76.66,102.31 76.66,106.01 82.15,111.5 114.53,111.5 117.73,108.3 130.27,108.3 131.47,107.13 131.61,107 131.66,106.95 131.66,106.95 131.91,106.7 132.02,106.59 132.05,106.57 132.61,105.97 132.62,105.96 132.7,105.92 136.41,104.3 138.86,102.98 141.11,100.74 141.94,99.9 141.94,99.65 141.94,99.56 141.94,87.19 142.57,86.56 142.57,80.44 160.05,62.97 160.05,58.58 158.75,57.29 158.75,43.91 159.31,43.35 159.31,42.7 v2(158.88,42.27)
LCDVDD:
  vias: v1(46.94,96.87) v3(46.61,95.85) v3(47.62,95.85)
LDO1_CAP: length 4.2
  TOP w0.203: HDA27.27 20.32,26.51 20.28,26.56 19.76,26.56 19.57,26.75
  TOP w0.254: R2711.2 17.23,27.12 C2702.2 19.2,27.12 v1(19.3,27.02) 19.57,26.75
LDO2_CAP: length 3.3
  TOP w0.203: v1(22.4,20.52) 22.48,20.59 HDA27.39
  TOP w0.254: C2712.2 21.42,19.4 22.17,20.14 22.17,20.28 v1(22.4,20.52)
LDO3_CAP: length 4.8
  TOP w0.203: v2(27.81,25.24) 27.74,25.31 HDA27.7
  BOTTOM w0.254: v2(27.81,25.24) 28.57,26 v1(30.1,26) 30.33,25.77 C2718.1
LID_CLOSE#: length 46.7
  TOP w0.102: KBC24.17 148.44,46.76 150.96,44.24 154.57,44.24 v2(155.56,43.25)
  L3 w0.102: v2(155.56,43.25) 155.56,47.88 155.88,48.2 155.88,48.56 155.02,49.42 155.02,61.13 v2(155.7,61.82)
  BOTTOM w0.102: R2421.1 148.32,40.91 149.56,40.91 v1(149.73,40.73) 150.5,41.5 D2401.K 151.48,42.39 152.54,43.45 155.36,43.45 v2(155.56,43.25) ; IOBD1.26 148.66,61.25 149.47,62.07 155.45,62.07 v2(155.7,61.82)
LINE1-L_C: length 2.9
  TOP w0.254: v1(19.56,30.07) 19.41,30.22 C2907.2 18.77,31.84 R2922.1
LINE1-L_R: length 2
  TOP w0.254: C2908.2 19,32.48 v1(18.87,32.61) 18.75,32.73 R2921.1
LINE1_L: length 4
  TOP w0.203: 22.17,28.92 22.2,28.92 22.48,28.65 HDA27.22
  TOP w0.254: C2907.1 20.73,30.04 v1(21.2,29.57) 21.84,28.92 22.17,28.92
LINE1_R: length 6.2
  TOP w0.203: HDA27.21 22.88,28.83 22.58,29.13
  TOP w0.254: v1(21.26,33.62) 21.26,32.51 C2908.1 21.46,32.25 21.46,30.17 22.5,29.13 22.57,29.13 22.58,29.13
LINE1_VREFO_L: length 3.1
  TOP w0.203: 18.88,24.86 18.89,24.87 v1(19.66,24.87) 19.76,24.87 19.81,24.91 HDA27.31
  TOP w0.254: R2912.1 18.3,24.35 18.81,24.86 18.88,24.86
LINE1_VREFO_R: length 3
  TOP w0.203: HDA27.30 20.19,25.31 20.14,25.27 19.84,25.27 19.83,25.28 19.57,25.28 19.51,25.34
  TOP w0.254: 19.51,25.34 19.5,25.35 19.11,25.35 19.09,25.37 18.63,25.37 18.61,25.35 18.08,25.35 R2913.1
LPC_AD0: length 110.8
  TOP w0.114: RN1806.8 105.39,72.5 106.87,73.98 109.37,73.98 116.46,81.07 116.46,99.44 118.18,101.16 120.5,101.16 v1(121.38,102.04) v2(121.92,102.58) 123.73,104.39 129.38,104.39 136.02,97.76 136.02,87.98 137.03,86.96 137.03,85.01 140.7,81.34 140.7,74.61 148.49,66.81 148.49,56.64 149.54,55.59 KBC24.126
  BOTTOM w0.114: DB1.9 121.85,102.66 v2(121.92,102.58)
LPC_AD1: length 110.3
  TOP w0.114: RN1806.7 105.22,71.85 107.02,73.64 109.23,73.64 109.52,73.64 116.8,80.93 116.8,99.3 118.32,100.82 120.92,100.82 v2(122.68,102.58) v1(123.22,103.12) 124.15,104.05 129.24,104.05 135.67,97.61 135.67,87.84 136.65,86.86 136.65,84.9 140.35,81.2 140.35,74.47 148.15,66.67 148.15,56.5 149.14,55.51 KBC24.127
  BOTTOM w0.114: v2(122.68,102.58) 122.85,102.75 DB1.8
LPC_AD2: length 109.8
  TOP w0.114: KBC24.128 148.74,55.42 147.81,56.35 147.81,66.53 140.01,74.33 140.01,81.06 136.31,84.76 136.31,86.72 135.33,87.69 135.33,97.47 129.1,103.71 124.82,103.71 v2(123.7,102.58) v1(121.98,100.87) 121.59,100.48 118.46,100.48 117.14,99.16 117.14,80.78 109.66,73.3 109.09,73.3 107.16,73.3 105.21,71.35 RN1806.6
  BOTTOM w0.114: DB1.7 123.85,102.73 v2(123.7,102.58)
LPC_AD3: length 110.7
  TOP w0.114: RN1806.5 105.04,70.7 107.3,72.95 108.95,72.95 109.8,72.95 117.49,80.64 117.49,99.02 118.6,100.13 122.14,100.13 v2(124.59,102.58) 125.37,103.37 128.95,103.37 134.99,97.33 134.99,87.55 135.97,86.57 135.97,84.62 139.67,80.92 139.67,74.19 147.47,66.39 147.47,62.26 147.25,62.04 v1(147.25,57.22) 147.25,54.25 147.19,54.2 KBC24.1
  BOTTOM w0.114: DB1.6 124.85,102.85 v2(124.59,102.58)
LPC_FRAME#: length 114.1
  TOP w0.114: R1801.1 104.52,69.69 107.44,72.61 108.81,72.61 110.14,72.61 117.83,80.3 117.83,98.88 118.75,99.79 122.68,99.79 v2(125.48,102.58) 125.91,103.02 128.81,103.02 134.65,97.19 134.65,87.41 135.62,86.43 135.62,84.48 139.33,80.77 139.33,74.04 147.12,66.24 147.12,62.4 146.67,61.94 v1(146.67,61.18) 146.67,59.17 145.87,58.36 145.87,55.58 144.98,54.7 144.98,52.99 145.74,52.23 146.1,52.23 146.23,52.36 KBC24.3
  BOTTOM w0.114: v2(125.48,102.58) 125.85,102.96 DB1.5
LPC_LAD0_PCH: length 11.6
  TOP w0.114: RN1806.1 100.43,72.5 97.52,75.41 v2(97.41,75.41)
  BOTTOM w0.089: CPU1.AU14 92.6,74.31 93.49,74.31 93.57,74.23 94.43,74.23 94.6,74.06
  BOTTOM w0.114: 94.6,74.06 v1(97.16,74.06) 97.41,74.31 v2(97.41,75.41)
LPC_LAD1_PCH: length 10.1
  TOP w0.114: RN1806.2 99.83,71.85 99.57,72.1 99.57,72.88 97.53,74.91 97.27,74.91 v2(96.77,75.41)
  BOTTOM w0.089: 94.77,74.41 93.99,74.41 93.7,74.69 CPU1.AW12
  BOTTOM w0.114: v2(96.77,75.41) v1(96.14,74.77) 95.77,74.41 94.77,74.41
LPC_LAD2_PCH: length 9.6
  TOP w0.114: RN1806.3 v1(100.08,71.35) 99.56,71.35 99.19,71.72 99.19,72.77 97.39,74.57 96.98,74.57 v2(96.14,75.41)
  BOTTOM w0.114: v2(96.14,75.41) 95.43,74.69 CPU1.AY12
LPC_LAD3_PCH: length 11
  TOP w0.114: v2(95.5,75.41) 96.69,74.22 97.25,74.22 98.83,72.64 98.83,70.93 v1(98.98,70.79) 99.07,70.7 RN1806.4
  BOTTOM w0.114: CPU1.AW11 94.01,74.99 95.09,74.99 v2(95.5,75.41)
LPC_LFRAME#_PCH: length 12.1
  TOP w0.114: R1801.2 v1(100.08,69.69) 99.06,69.69 98.42,70.33 98.42,72.56 97.11,73.88 96.52,73.88 95.63,74.77 93.51,74.77 v2(93.22,75.06)
  BOTTOM w0.114: v2(93.22,75.06) 92.91,74.76 CPU1.AV12
LPSS_GSPI0_MOSI_BBS0_R: length 14.8
  TOP w0.102: v2(77.17,78.73) 76.57,79.33 73.06,79.33 71.98,80.41 70.69,80.41 70.13,79.85 v1(69.7,79.85) R2012.2
  BOTTOM w0.102: v2(77.17,78.73) 77.62,78.28 77.62,77.53 CPU1.L8
LPSS_SDIO_D0_CMNHDR: length 18.1
  BOTTOM w0.102: CPU1.D3 73.97,80.86 73.97,81.4 73.78,81.59 73.78,81.98 73.54,82.22 69.65,82.22 68.65,81.22 68.31,81.22 66.85,79.76 63.82,79.76 v1(62.79,80.79) 62.61,80.97 62.61,83.98 R2011.2
LVDS_VDD_EN_R: length 34.2
  TOP w0.102: v2(55.63,96.23) 55.89,96.5 55.89,97.53 RN5203.8 56.41,97.78 56.63,98 56.63,99.52 v2(56.64,99.54) ; v1(48.56,101.09) 48.56,101.01 v2(49.15,100.42) 49.21,100.49 U5201.1 ; D5201.3 74.03,96.8 70.3,96.8 v2(69.72,97.38)
  L3 w0.102: v2(69.72,97.38) 69.22,97.88 60.78,97.88 59.79,96.89 56.29,96.89 v2(55.63,96.23)
  L4 w0.102: v2(49.15,100.42) 55.75,100.42 v2(56.64,99.54)
M_A_A0: length 44
  TOP w0.178: v2(130.44,65.85) 130.46,65.83 v1(131.01,65.83)
  L4 w0.089: 100.79,59.73 100.61,59.73 100.26,59.38 93,59.38 v2(92.56,59.82)
  L4 w0.203: v2(130.44,65.85) 130.44,65.9 129.98,66.36 128.28,66.36 127.44,65.52 124.12,65.52 123.87,65.77 107.18,65.77 101.14,59.73 100.79,59.73
  BOTTOM w0.178: v2(130.44,65.85) 130.44,65.85 131.9,65.85 DIMM1.98 ; v2(92.56,59.82) 92.26,60.11 CPU1.AU36
M_A_A1: length 46.2
  TOP w0.178: v1(96.09,59.43) 95.86,59.66 v2(95.86,59.97)
  L4 w0.089: v2(95.86,59.97) 96.28,59.56 99.62,59.56 100.37,60.3 100.74,60.3
  L4 w0.203: 100.74,60.3 100.99,60.3 107.04,66.35 108.14,66.35 108.35,66.56 108.35,67.25 108.55,67.46 108.96,67.46 109.16,67.25 109.16,66.56 109.36,66.35 109.77,66.35 109.97,66.56 109.97,67.25 110.18,67.46 110.58,67.46 110.79,67.25 110.79,66.56 110.99,66.35 111.4,66.35 111.6,66.56 111.6,67.25 111.8,67.46 112.21,67.46 112.41,67.25 112.41,66.56 112.61,66.35 113.14,66.35 113.34,66.56 113.34,66.71 113.54,66.92 113.95,66.92 114.15,66.71 114.15,66.56 114.36,66.35 114.76,66.35 114.96,66.56 114.96,66.71 115.17,66.92 115.57,66.92 115.78,66.71 115.78,66.56 115.98,66.35 118.01,66.35 118.22,66.56 118.22,66.71 118.42,66.92 119.06,66.92 119.27,66.71 119.27,66.49 119.39,66.36 119.95,66.36 120.08,66.49 120.08,66.71 120.28,66.92 121.28,66.92 121.84,66.35 122.57,66.35 122.86,66.64 125.38,66.64 125.8,66.22 v2(125.8,66.15)
  BOTTOM w0.178: v2(95.86,59.97) 95.86,59.85 95.39,59.37 94.35,59.37 94.33,59.39 CPU1.AY37 ; v2(125.8,66.15) 125.8,65.74 125.6,65.55 DIMM1.97
M_A_A2: length 47.5
  TOP w0.178: v2(129.17,65.85) 129.17,65.99 v1(129.49,66.31)
  L4 w0.089: 100.49,58.02 100.3,58.02 99.5,58.82 91.68,58.82 91.56,58.71 v2(91.48,58.71)
  L4 w0.203: v2(129.17,65.85) 129.17,65.32 129.16,65.32 128.3,64.47 127.2,64.47 126.39,63.65 121.47,63.65 121.26,63.85 121.26,64.05 121.06,64.25 120.66,64.25 120.45,64.05 120.45,63.85 120.25,63.65 119.74,63.65 119.54,63.85 119.54,64.05 119.33,64.25 118.93,64.25 118.72,64.05 118.72,63.85 118.52,63.65 108.67,63.65 103.03,58.02 100.49,58.02
  BOTTOM w0.178: CPU1.AR38 91.1,59.08 v2(91.48,58.71) ; DIMM1.96 129.33,65.25 129.17,65.41 v2(129.17,65.85)
M_A_A3: length 47.2
  TOP w0.178: v2(125.16,64.95) 124.72,64.95 v1(124.61,64.84)
  L4 w0.089: v2(90.64,59.68) 91.04,60.09 91.72,60.09 92.63,59.18 100.88,59.18 100.9,59.16
  L4 w0.203: v2(125.16,64.95) 122.97,64.95 122.65,65.26 110.39,65.26 110.19,65.06 110.19,64.87 109.98,64.67 109.58,64.67 109.37,64.87 109.37,65.06 109.17,65.26 107.39,65.26 106.26,64.13 106.26,63.84 106.66,63.43 106.66,63.15 106.38,62.86 106.09,62.86 105.68,63.27 105.39,63.27 105.11,62.98 105.11,62.69 105.53,62.27 105.53,61.98 105.24,61.7 104.95,61.7 104.53,62.12 104.24,62.12 103.96,61.83 103.96,61.54 104.38,61.12 104.38,60.84 104.09,60.55 103.8,60.55 103.38,60.97 103.09,60.97 102.81,60.68 102.81,60.39 103.23,59.97 103.23,59.69 102.94,59.4 102.65,59.4 102.23,59.82 101.94,59.82 101.29,59.16 100.9,59.16
  BOTTOM w0.178: CPU1.AP36 90.45,59.87 v2(90.64,59.68) ; DIMM1.95 v2(125.16,64.95)
M_A_A4: length 47.4
  TOP w0.178: v1(92.02,58.03) 92.24,58.24 v2(92.56,58.24)
  L4 w0.089: 100.49,57.45 100.36,57.45 99.16,58.64 92.96,58.64 v2(92.56,58.24)
  L4 w0.203: v2(129.8,64.65) 129.8,64.7 130.24,65.13 130.64,65.13 130.94,64.84 130.94,64.47 130.38,63.91 127.66,63.91 126.83,63.08 108.81,63.08 103.18,57.45 100.49,57.45
  BOTTOM w0.178: v2(92.56,58.24) 92.26,58.54 CPU1.AU39 ; v2(129.8,64.65) 129.82,64.63 129.82,64.58 130.35,64.05 DIMM1.92
M_A_A5: length 47.2
  TOP w0.178: v1(91.9,59.68) 91.29,59.68 v2(91.29,59.69)
  L4 w0.089: v2(91.29,59.69) 91.72,59.69 92.41,59 99.89,59 100.3,58.59 100.49,58.59
  L4 w0.203: 100.49,58.59 102.87,58.59 107.49,63.21 107.49,64.1 108.15,64.76 108.72,64.76 109.32,64.16 111.04,64.16 111.25,64.36 111.25,64.55 111.45,64.76 111.86,64.76 112.06,64.55 112.06,64.36 112.26,64.16 112.67,64.16 112.87,64.36 112.87,64.55 113.08,64.76 113.48,64.76 113.68,64.55 113.68,64.36 113.89,64.16 114.29,64.16 114.5,64.36 114.5,64.55 114.7,64.76 115.11,64.76 115.31,64.55 115.31,64.36 115.51,64.16 115.92,64.16 116.12,64.36 116.12,64.55 116.33,64.76 116.73,64.76 116.94,64.55 116.94,64.36 117.14,64.16 117.55,64.16 117.75,64.36 117.75,64.55 117.95,64.76 122.35,64.76 122.73,64.38 125.92,64.38 126.43,64.89 v2(126.43,64.95)
  BOTTOM w0.178: DIMM1.91 125.5,63.75 126.43,64.68 v2(126.43,64.95) ; v2(91.29,59.69) 91.1,59.87 CPU1.AR36
M_A_A6: length 47.5
  TOP w0.178: v2(129.8,62.85) 129.8,63.05 v1(130.1,63.34)
  L4 w0.089: 100.49,56.87 100.31,56.87 98.72,58.47 96.07,58.47 v2(95.85,58.24)
  L4 w0.203: 100.49,56.87 103.33,56.87 109.02,62.57 121.09,62.57 121.83,61.84 122.52,61.84 123.2,62.52 127.47,62.52 128.35,63.4 130.57,63.4 130.92,63.05 130.92,62.65 130.64,62.37 130.24,62.37 129.8,62.8 v2(129.8,62.85)
  BOTTOM w0.089: v2(95.85,58.24) 95.14,57.53 93.2,57.53 CPU1.AV40
  BOTTOM w0.178: DIMM1.90 130.35,63.45 129.8,62.91 v2(129.8,62.85)
M_A_A7: length 46.7
  TOP w0.178: v1(127.97,62.88) 128,62.85 v2(128.53,62.85)
  L4 w0.089: 100.61,55.29 100.02,55.29 97.83,57.48 94.63,57.48 v2(93.87,58.24)
  L4 w0.203: 100.61,55.29 103.96,55.29 108.37,59.69 111.94,59.69 112.15,59.9 112.15,60.84 112.35,61.05 112.75,61.05 112.96,60.84 112.96,59.9 113.16,59.69 122.98,59.69 124.08,60.79 126.82,60.79 127.66,61.64 128.17,61.64 128.53,62.01 v2(128.53,62.85)
  BOTTOM w0.178: CPU1.AW39 93.87,58.33 v2(93.87,58.24) ; DIMM1.86 128.73,62.25 128.53,62.44 v2(128.53,62.85)
M_A_A8: length 45.9
  TOP w0.178: v2(126.43,61.95) 126.43,62.11 v1(126.11,62.43)
  L4 w0.089: 100.61,55.86 100.05,55.86 98.26,57.66 95.14,57.66 v2(94.56,58.24)
  L4 w0.203: 100.61,55.86 103.75,55.86 108.16,60.27 109.48,60.27 109.68,60.47 109.68,61.35 109.88,61.56 110.29,61.56 110.49,61.35 110.49,60.47 110.69,60.27 111.1,60.27 111.3,60.47 111.3,61.35 111.51,61.56 113.54,61.56 113.74,61.35 113.74,60.47 113.95,60.27 120.19,60.27 120.68,60.76 121.51,60.76 122,60.27 122.58,60.27 123.69,61.38 125.92,61.38 126.43,61.89 v2(126.43,61.95)
  BOTTOM w0.178: CPU1.AY39 94.56,58.29 v2(94.56,58.24) ; v2(126.43,61.95) 126.43,62.21 126.87,62.66 126.87,63.16 126.64,63.39 126.21,63.39 125.97,63.15 DIMM1.89
M_A_A9: length 47
  L4 w0.089: v2(97.17,58.06) 98.46,58.06 100.15,56.37 100.4,56.37
  L4 w0.203: 100.4,56.37 103.54,56.37 109.24,62.06 114.27,62.06 114.48,61.86 114.48,60.98 114.68,60.78 115.09,60.78 115.29,60.98 115.29,61.86 115.49,62.06 115.9,62.06 116.1,61.86 116.1,60.98 116.31,60.77 116.71,60.77 116.92,60.98 116.92,61.86 117.12,62.06 117.53,62.06 117.73,61.86 117.73,60.98 117.93,60.77 118.34,60.77 118.54,60.98 118.54,61.86 118.74,62.06 119.15,62.06 119.35,61.86 119.35,60.98 119.56,60.77 119.96,60.77 120.17,60.98 120.17,61.86 120.37,62.06 120.88,62.06 121.68,61.26 122.77,61.26 123.46,61.95 v2(125.16,61.95)
  BOTTOM w0.089: CPU1.AU40 92.46,57.77 92.87,57.35 v1(96.55,57.35) 97.17,57.97 v2(97.17,58.06)
  BOTTOM w0.178: DIMM1.85 v2(125.16,61.95)
M_A_A10: length 47.6
  TOP w0.178: v2(125.16,68.91) 124.87,68.91 v1(124.64,68.67)
  L4 w0.091: v2(90.78,60.68) 91.17,60.28 92.84,60.28 93.55,60.99 94.39,60.99 94.39,60.99 94.73,60.99 94.73,60.99 97.69,60.99 98.71,62.01
  L4 w0.203: v2(125.16,68.91) 125.03,69.04 123,69.04 122.81,69.23 122.14,69.23 121.81,69.56 121.81,70.55 120.48,71.88 120.16,71.88 119.95,72.08 119.95,72.54 119.75,72.74 119.34,72.74 119.14,72.54 119.14,72.08 118.94,71.88 118.53,71.88 118.33,72.08 118.33,72.54 118.12,72.74 117.72,72.74 117.51,72.54 117.51,72.08 117.31,71.88 116.9,71.88 116.7,72.08 116.7,72.54 116.5,72.74 116.09,72.74 115.89,72.54 115.89,72.08 115.69,71.88 109.59,71.88 100.13,62.42 99.12,62.42 98.71,62.01
  BOTTOM w0.178: v2(90.78,60.68) 90.78,60.76 CPU1.AP35 ; DIMM1.107 124.8,68.55 v2(125.16,68.91)
M_A_A11: length 46.1
  TOP w0.178: v1(128.24,61.54) 128.53,61.25 v2(128.53,61.05)
  L4 w0.089: v2(93.87,56.66) 94.33,57.12 97.03,57.12 100.01,54.14 100.61,54.14
  L4 w0.203: v2(128.53,61.05) 128.53,61 127.98,60.45 127.3,60.45 125.7,58.85 123.58,58.85 122.67,57.94 114.93,57.94 114.2,58.68 110.52,58.68 110.31,58.48 110.31,58.01 110.11,57.8 109.7,57.8 109.5,58.01 109.5,58.48 109.3,58.68 108.84,58.68 108.64,58.48 108.64,58.01 108.43,57.8 107.91,57.8 104.26,54.14 100.61,54.14
  BOTTOM w0.178: DIMM1.84 131.9,61.65 128.74,61.65 128.53,61.45 v2(128.53,61.05) ; CPU1.AW41 93.87,56.76 v2(93.87,56.66)
M_A_A12: length 46.4
  TOP w0.178: v1(92.02,56.66) 92.58,56.66 v2(92.59,56.67)
  L4 w0.089: v2(92.59,56.67) 93.22,57.3 97.43,57.3 100.02,54.72 100.61,54.72
  L4 w0.203: 100.61,54.72 104.11,54.72 108.58,59.19 115,59.19 115.37,58.82 115.85,58.82 116.22,59.19 116.63,59.19 116.83,58.98 116.83,58.65 117.03,58.45 117.44,58.45 117.64,58.65 117.64,58.98 117.84,59.19 118.25,59.19 118.45,58.98 118.45,58.65 118.66,58.45 119.06,58.45 119.27,58.65 119.27,58.98 119.47,59.19 119.88,59.19 120.08,58.98 120.08,58.65 120.28,58.45 120.69,58.45 120.89,58.65 120.89,58.98 121.1,59.19 121.6,59.19 121.79,59 121.79,58.67 122.01,58.45 122.46,58.45 124,59.99 124.51,59.99 125.02,59.48 125.61,59.48 125.8,59.67 v2(125.8,60.27)
  BOTTOM w0.178: v2(92.59,56.67) 92.59,56.79 CPU1.AU41 ; DIMM1.83 125.97,61.35 126.11,61.21 126.11,60.8 125.8,60.48 v2(125.8,60.27)
M_A_A13: length 47.9
  TOP w0.178: v2(125.16,72.51) 124.74,72.93 v1(124.74,73.04)
  L4 w0.203: v2(125.16,72.51) 124.9,72.51 124,73.4 124,73.97 122.19,75.79 112.75,75.79 112.55,75.99 112.55,76.47 112.35,76.68 111.94,76.68 111.74,76.47 111.74,75.99 111.53,75.79 111.05,75.79 110.85,75.99 110.85,76.5 110.65,76.7 110.24,76.7 110.04,76.5 110.04,75.99 109.83,75.79 109.18,75.79 99,65.6 97.93,65.6 96.36,64.03 94.46,64.03 94.07,63.64 93.59,63.64 93.26,63.3 93.26,62.83 92.92,62.49 92.44,62.49 92.11,62.15 92.11,61.68 91.43,61 v2(91.43,60.68)
  BOTTOM w0.178: v2(125.16,72.51) 124.8,72.15 DIMM1.119 ; CPU1.AR35 91.43,60.76 v2(91.43,60.68)
M_A_A14: length 46.7
  TOP w0.178: v1(96.27,57.09) 95.86,56.69 v2(95.86,56.67)
  L4 w0.089: 100.4,53.57 100.09,53.57 96.72,56.94 96.14,56.94 v2(95.86,56.67)
  L4 w0.203: v2(129.8,61.05) 129.8,60.12 129.57,59.88 127.54,59.88 127.03,59.37 127.03,58.57 126.8,58.35 124.15,58.35 123.1,57.29 114.82,57.29 113.94,58.17 111.21,58.17 110.34,57.29 108.12,57.29 104.4,53.57 100.4,53.57
  BOTTOM w0.089: CPU1.AV42 93.2,55.95 95.15,55.95 v2(95.86,56.67)
  BOTTOM w0.178: v2(129.8,61.05) 129.8,60.82 130.17,60.45 DIMM1.80
M_A_A15: length 46.9
  L4 w0.089: 100.52,53.05 100,53.05 v2(96.51,56.54)
  L4 w0.203: 100.52,53.05 104.6,53.05 108.34,56.79 110.55,56.79 111.42,57.66 113.73,57.66 114.61,56.79 123.31,56.79 124.36,57.84 127.17,57.84 127.36,57.65 128.63,57.65 128.83,57.85 128.83,58.4 128.53,58.69 v2(128.53,59.25)
  BOTTOM w0.089: v2(96.51,56.54) 96.51,55.97 v1(96.42,55.87) 96.32,55.78 92.86,55.78 92.45,56.19 CPU1.AU42
  BOTTOM w0.178: DIMM1.78 129.08,59.85 128.53,59.31 v2(128.53,59.25)
M_A_B_DIMM_ODT: length 18.4
  TOP w0.508: v2(133.86,78.2) v1(132.97,78.2) 132.21,78.2 131.7,78.71 128.14,78.71 127.76,78.33 R1206.1 R1207.1
  L3 w0.508: v2(134.75,84.93) 134.62,84.93 133.86,84.17 v2(133.86,78.2)
  BOTTOM w0.508: Q1202.S 134.94,84.74 v2(134.75,84.93)
M_A_BS0: length 47.4
  L4 w0.203: v2(126.43,68.91) 126.43,69.29 126.11,69.61 123.55,69.61 121.65,71.51 121.65,71.74 120.14,73.25 115.88,73.25 115.02,72.39 114.48,72.39 114.28,72.59 114.28,73.04 114.07,73.25 113.67,73.25 113.46,73.04 113.46,72.59 113.26,72.39 112.85,72.39 112.65,72.59 112.65,72.76 112.45,72.97 112.04,72.97 111.84,72.76 111.84,72.59 111.64,72.39 109.38,72.39 99.98,63 98.92,63 97.39,61.47 97.39,61.42 v2(97.42,61.39)
  BOTTOM w0.089: v2(97.42,61.39) 96.75,60.73 v1(96.75,60.72) 96.74,60.72 96.52,60.5 93.01,60.5 92.84,60.68 92.69,60.68 92.45,60.92 CPU1.AU35
  BOTTOM w0.178: DIMM1.109 124.64,69.15 125.15,69.67 126.23,69.67 126.43,69.46 v2(126.43,68.91)
M_A_BS1: length 48.7
  TOP w0.178: v1(128.85,68.95) 129.17,69.27 v2(129.17,69.45)
  L4 w0.203: v2(96.77,61.39) 96.72,61.44 96.72,61.51 98.77,63.57 99.84,63.57 109.17,72.9 111.25,72.9 112.11,73.75 120.35,73.75 121.92,72.19 122.35,72.19 124.34,70.19 126.83,70.19 127.04,69.97 127.04,69.59 127.24,69.39 127.7,69.39 127.91,69.59 127.91,69.97 128.12,70.19 128.87,70.19 129.17,69.89 v2(129.17,69.45)
  BOTTOM w0.089: v2(96.77,61.39) 96.05,60.68 93.34,60.68 93.33,60.69 93.19,60.69 CPU1.AV35
  BOTTOM w0.178: v2(129.17,69.45) 129.17,69.39 129.71,68.85 DIMM1.108
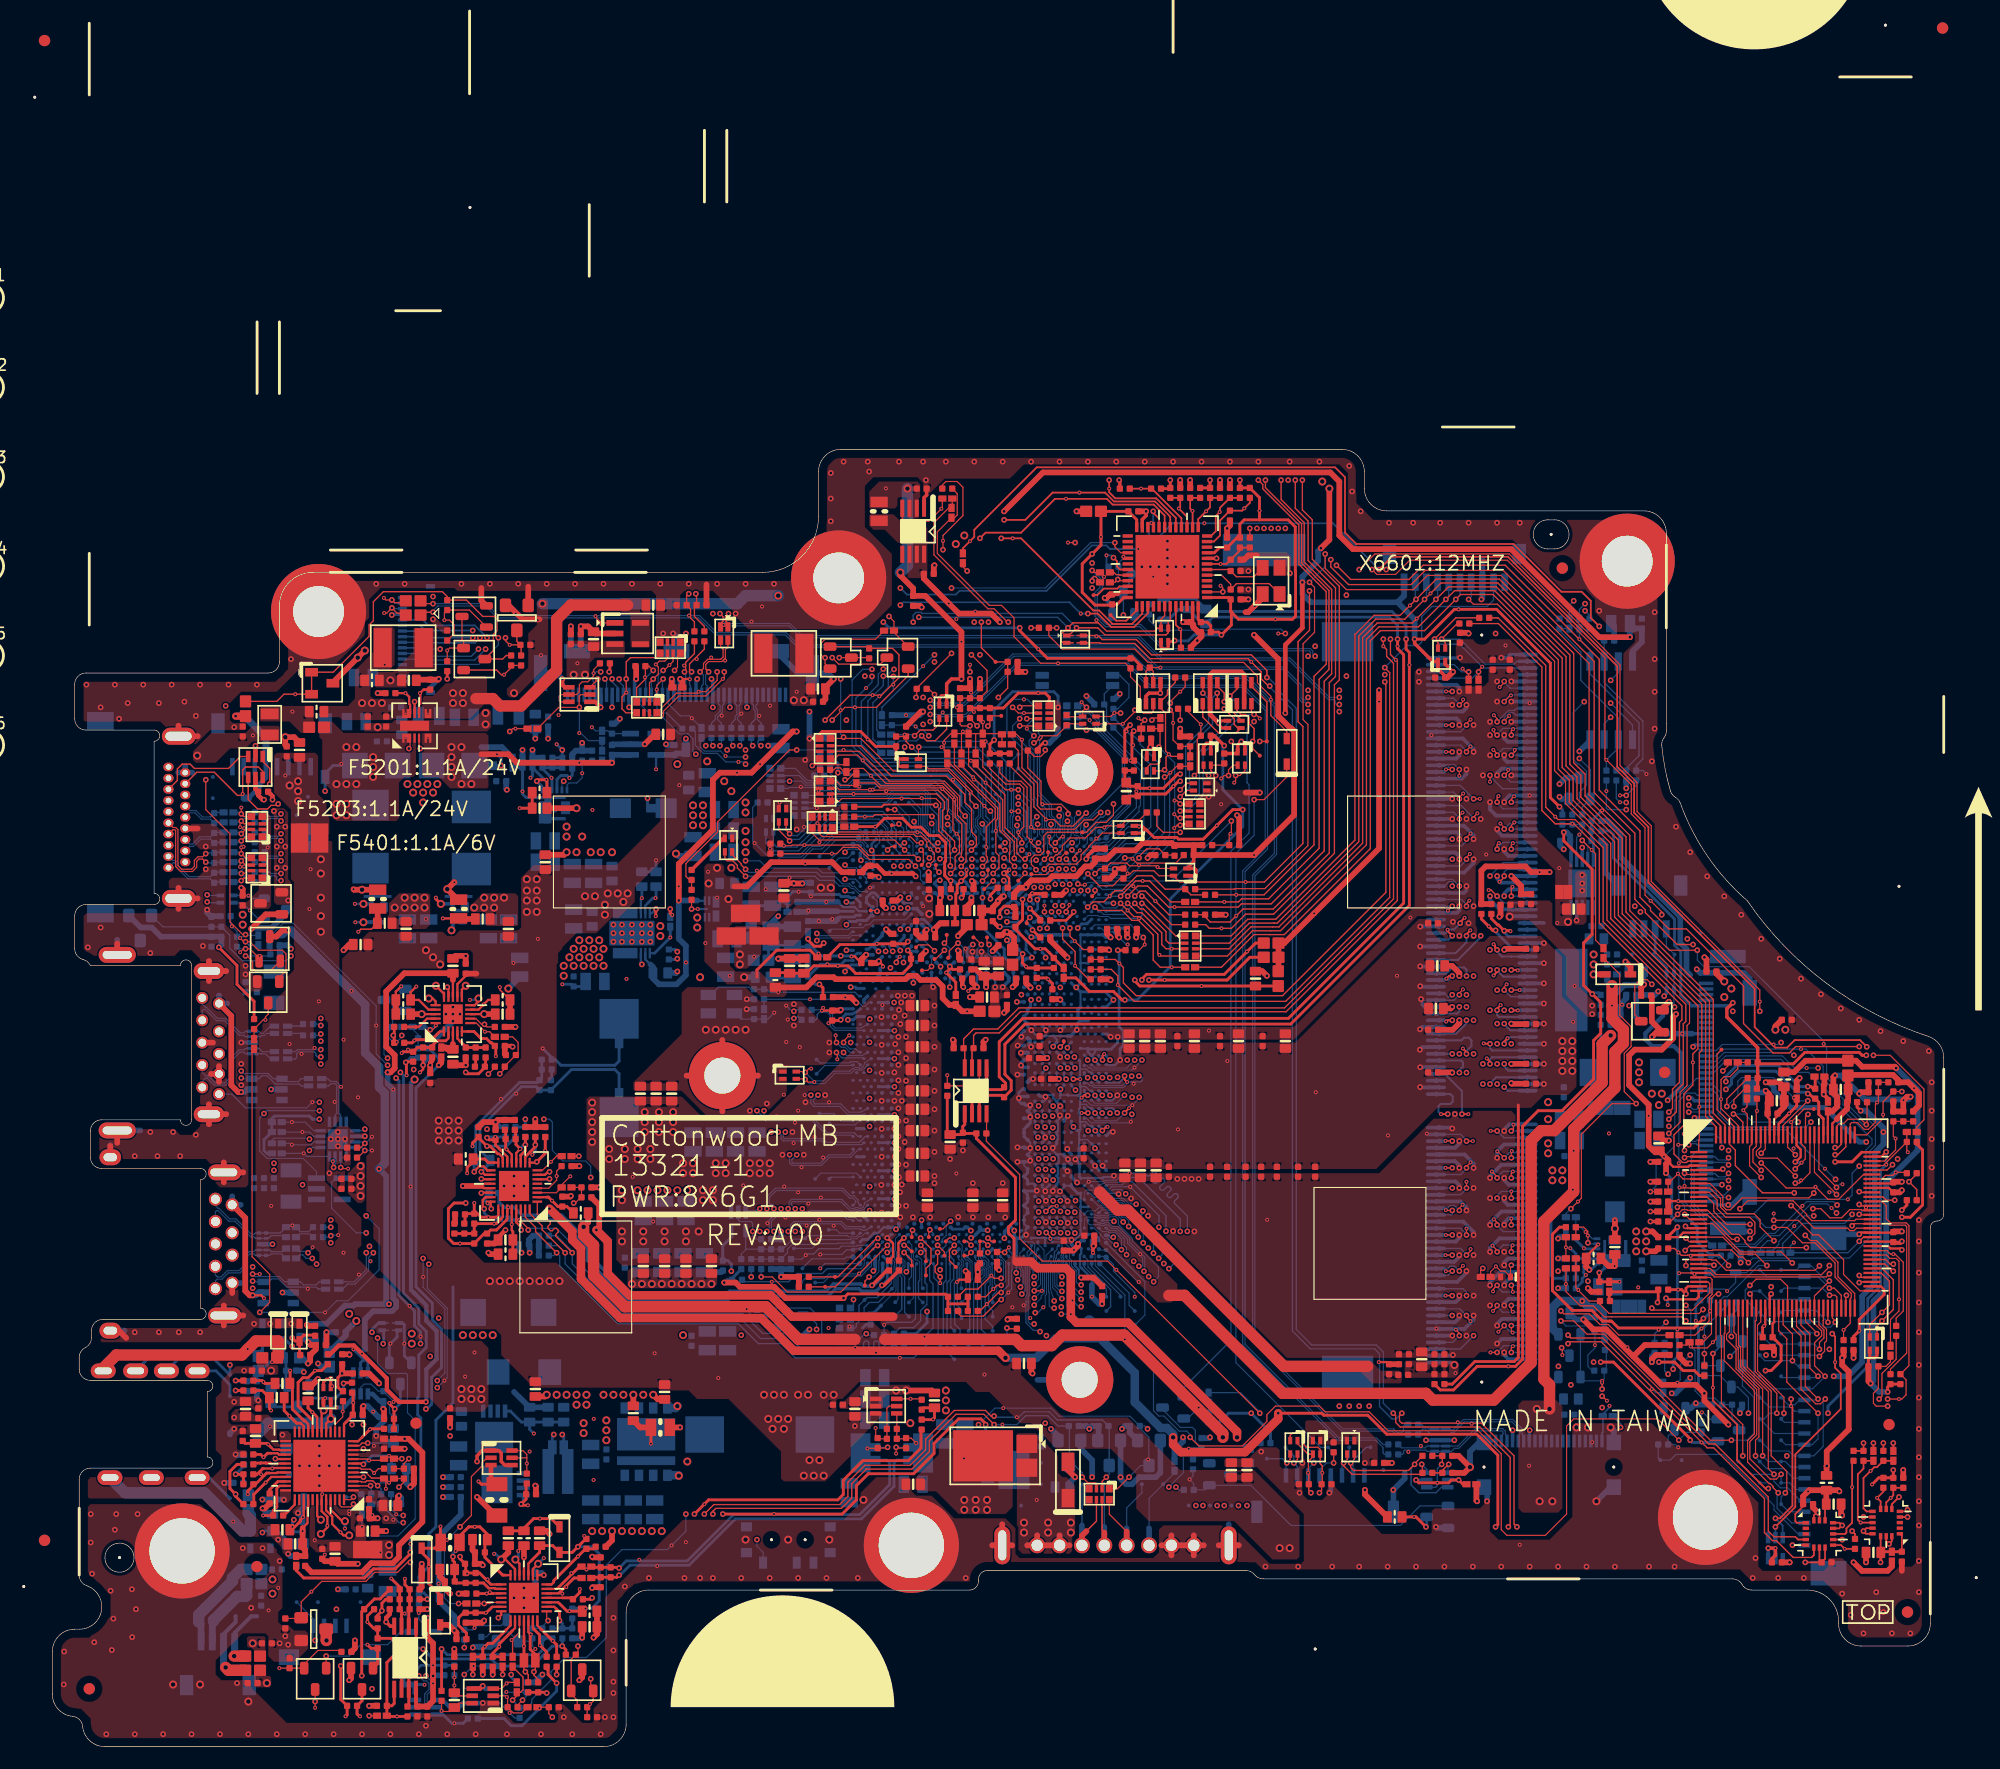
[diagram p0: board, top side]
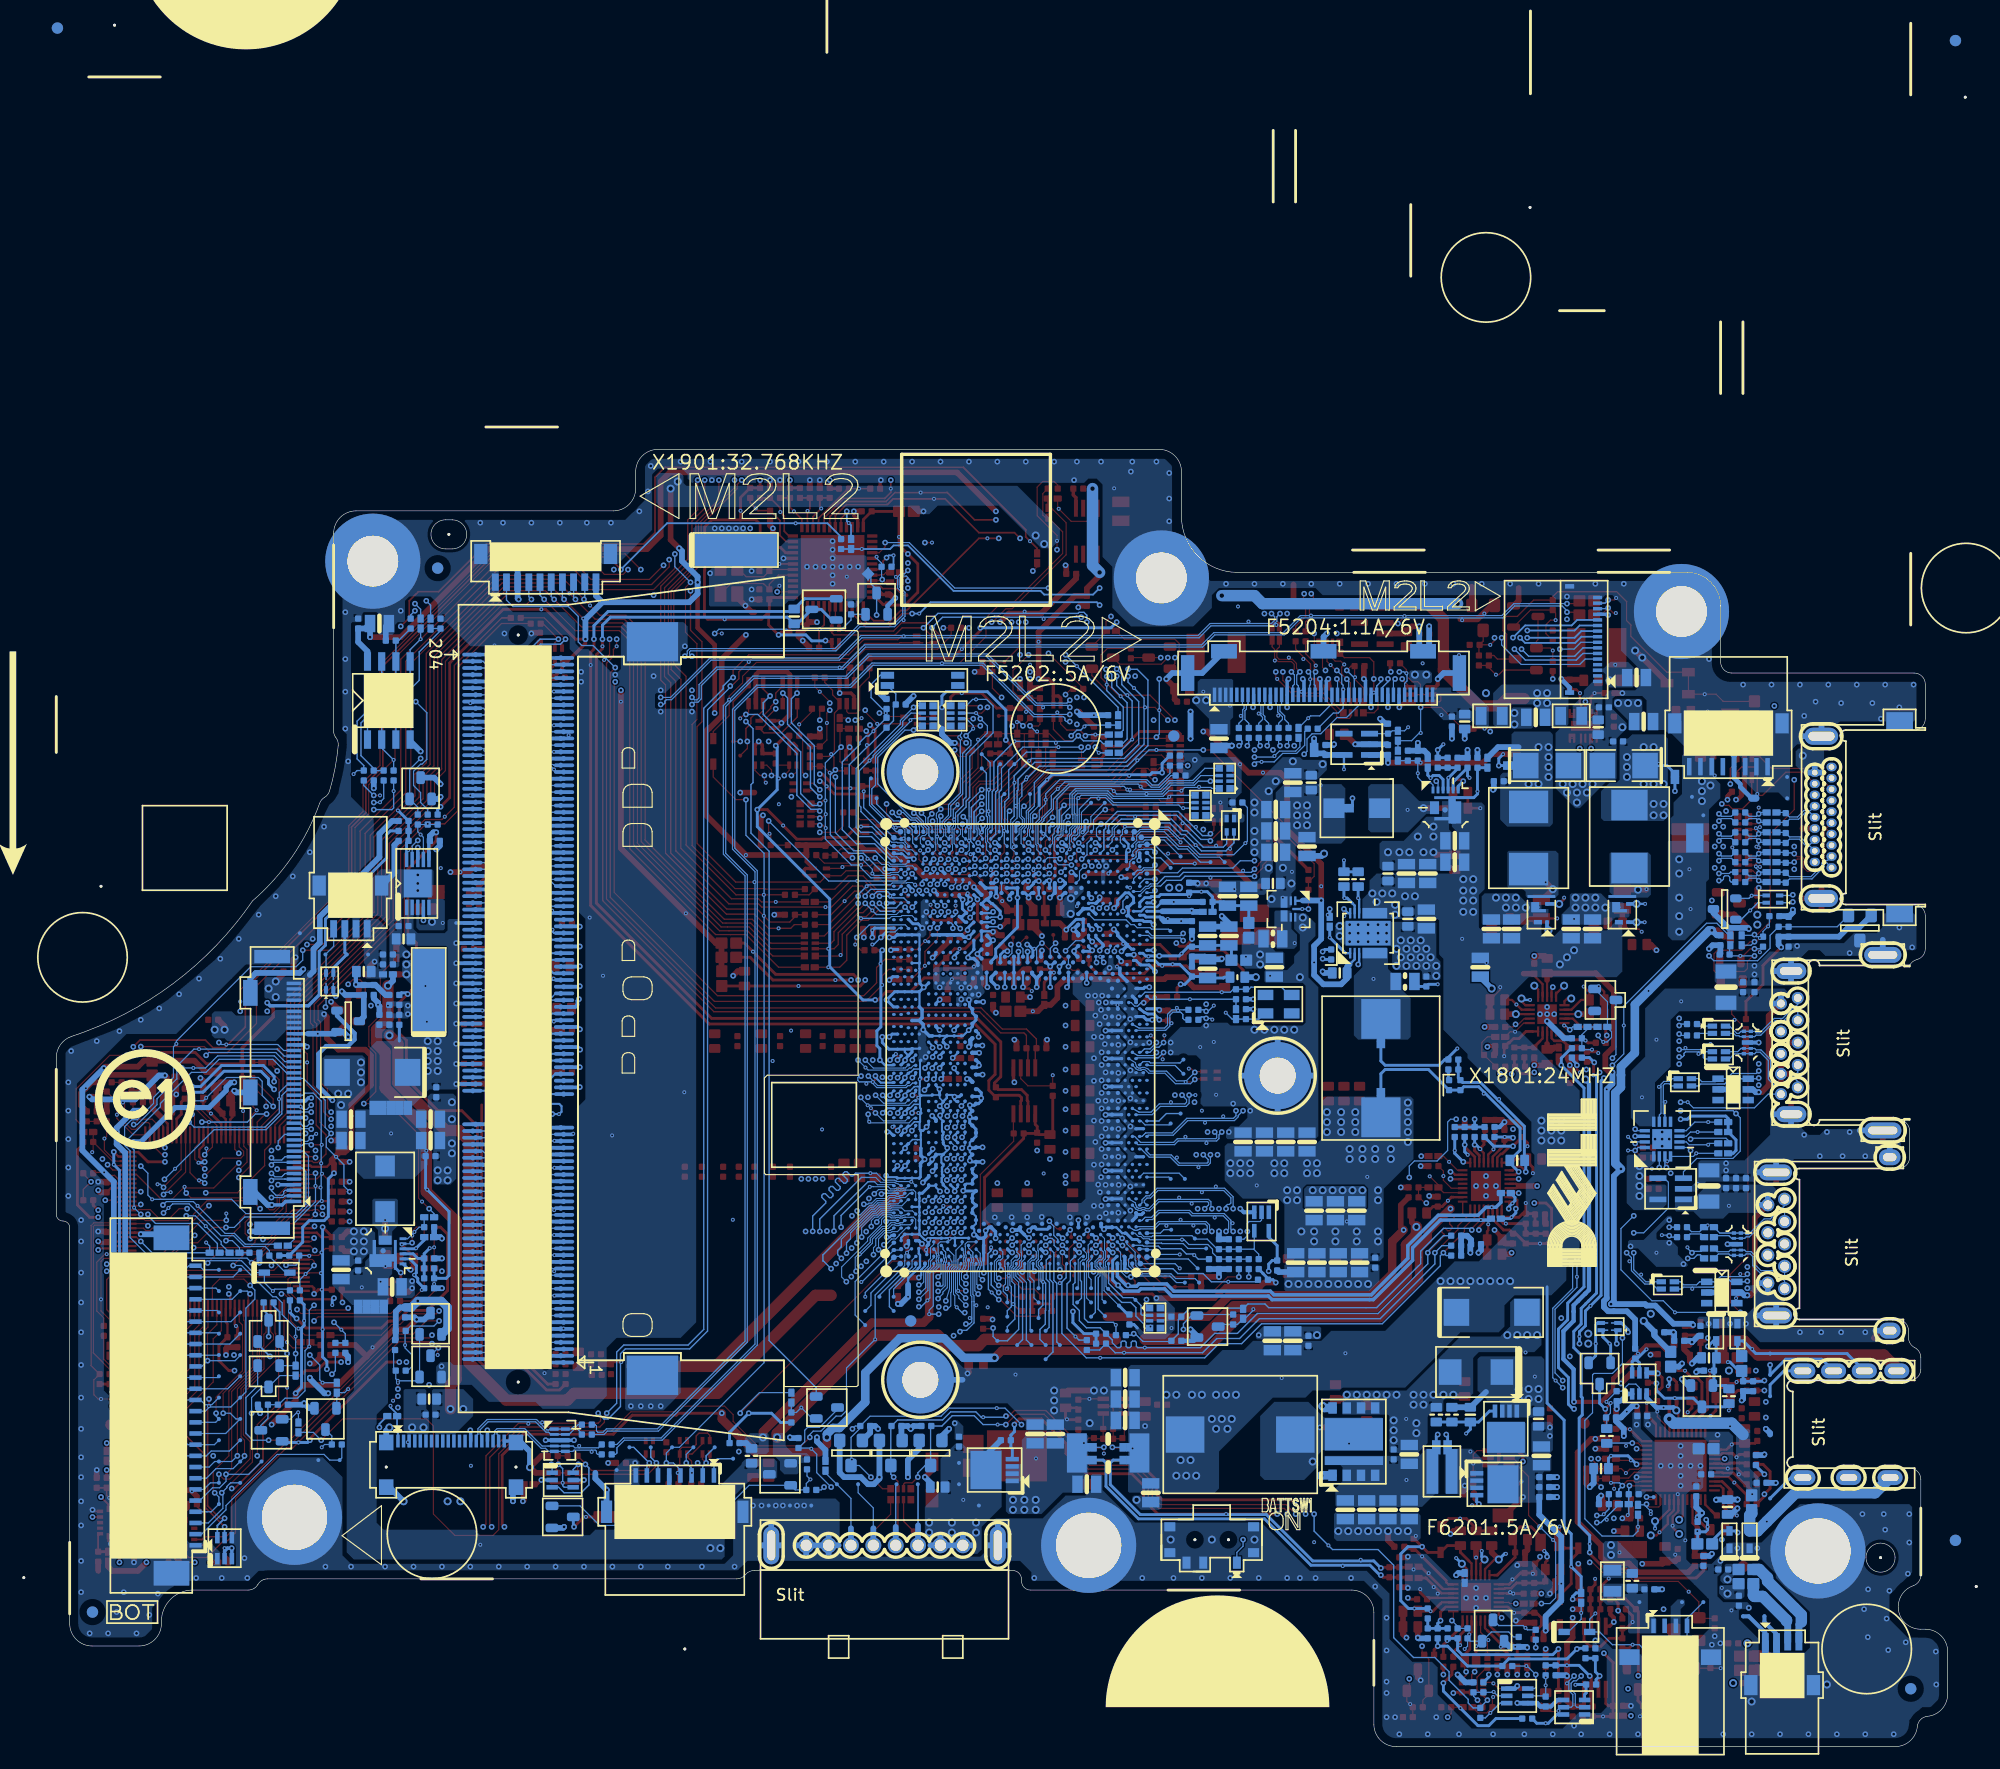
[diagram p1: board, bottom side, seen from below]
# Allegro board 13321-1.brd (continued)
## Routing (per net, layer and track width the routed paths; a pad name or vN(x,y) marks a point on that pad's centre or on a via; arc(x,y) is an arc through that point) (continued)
M_A_BS2: length 45.3
  TOP w0.178: v1(126.59,56.56) 126.03,56.56 v2(126.02,56.56)
  L4 w0.089: 100.58,52.52 99.92,52.52 96.18,56.26 95.62,56.26 v2(95.21,56.67)
  L4 w0.203: v2(126.02,56.56) 126.02,57.03 125.82,57.23 124.47,57.23 123.52,56.28 114.4,56.28 113.52,57.15 111.64,57.15 110.76,56.28 108.55,56.28 107.45,55.19 107.45,54.9 107.82,54.53 107.82,54.25 107.53,53.96 107.25,53.96 106.88,54.32 106.59,54.32 106.3,54.04 106.3,53.75 106.67,53.38 106.67,53.1 106.38,52.81 106.1,52.81 105.73,53.17 105.44,53.17 104.79,52.52 100.58,52.52
  BOTTOM w0.178: v2(95.21,56.67) 94.79,57.09 94.24,57.09 CPU1.AY41 ; DIMM1.79 124.5,60.15 126.02,58.63 v2(126.02,56.56)
M_A_CAS#: length 47.9
  TOP w0.178: v1(126.77,72.99) 126.43,72.65 v2(126.43,72.51)
  L4 w0.203: v2(92.56,61.39) 92.56,61.41 94.04,62.89 95.94,62.89 98.14,65.09 99.21,65.09 109.39,75.28 109.71,75.28 109.91,75.08 109.91,74.64 110.12,74.44 110.52,74.44 110.73,74.64 110.73,75.08 110.93,75.28 121.98,75.28 123.49,73.76 123.49,73.19 124.76,71.93 126.11,71.93 126.43,72.25 v2(126.43,72.51)
  BOTTOM w0.178: DIMM1.115 125.45,70.95 126.43,71.93 v2(126.43,72.51) ; CPU1.AU34 92.56,61.54 v2(92.56,61.39)
M_A_DIMA_CKE0: length 56.9
  TOP w0.178: v2(124.75,56.56) 124.16,56.56 v1(124.16,56.56)
  L4 w0.089: v2(92.61,55.08) 92.61,55.77 92.79,55.96 96.04,55.96 100.09,51.91 100.56,51.91
  L4 w0.203: v2(124.75,56.56) 123.86,55.67 113.67,55.67 113.46,55.87 113.46,56.34 113.26,56.54 112.04,56.54 111.85,56.36 111.85,55.87 111.65,55.67 108.8,55.67 108.58,55.46 108.58,55.01 108.76,54.83 109.22,54.83 109.88,54.18 110.17,54.18 110.78,54.79 111.07,54.79 111.35,54.5 111.35,54.21 110.74,53.6 110.74,53.31 111.44,52.62 111.44,52.33 111.15,52.04 110.87,52.04 108.91,54 108.62,54 108.33,53.71 108.33,53.43 109.25,52.51 109.25,52.22 108.96,51.93 108.67,51.93 107.77,52.84 107.48,52.84 107.14,52.5 107.14,52.09 106.96,51.91 100.56,51.91
  BOTTOM w0.089: CPU1.AU43 92.26,55.42 v2(92.61,55.08)
  BOTTOM w0.178: DIMM1.73 124.99,58.35 125.2,58.15 125.2,57.68 124.99,57.47 124.13,57.47 123.93,57.27 123.93,56.77 124.13,56.56 v2(124.75,56.56)
M_A_DIMA_CKE1: length 55.2
  TOP w0.178: v2(93.88,55.09) 94.2,55.42 v1(94.34,55.42)
  L4 w0.089: 100.19,51.3 95.93,55.57 94.08,55.57 93.88,55.37 v2(93.88,55.09)
  L4 w0.203: 100.19,51.3 111.3,51.3 113.17,53.17 113.17,53.46 111.95,54.68 111.95,54.97 112.23,55.25 112.52,55.25 113.74,54.03 114.03,54.03 115.06,55.06 124.18,55.06 125.07,55.95 126.28,55.95 127.36,57.04 131.67,57.04 132.28,57.65 132.28,59.1 132.08,59.3 131.53,59.3 131.33,59.1 131.33,58.68 130.99,58.34 130.44,58.34 v2(129.8,58.98)
  BOTTOM w0.178: v2(129.8,58.98) 130.13,58.65 DIMM1.74 ; CPU1.AW43 93.88,55.18 v2(93.88,55.09)
M_A_DIMA_CLK_DDR0: length 59.2
  TOP w0.102: v2(125.8,67.23) 125.8,67.39 v1(126.11,67.71)
  L4 w0.089: v2(96.5,59.96) 96.9,60.36 98.92,60.36 98.94,60.38
  L4 w0.114: 98.94,60.38 99.27,60.38 100,61.1 100.67,61.1 107.86,68.29 109.2,68.29 109.32,68.41 109.32,69.3 109.58,69.56 110.08,69.56 110.34,69.3 110.34,68.41 110.46,68.29 110.8,68.29 110.92,68.41 110.92,69.28 111.18,69.54 111.68,69.54 111.94,69.28 111.94,68.41 112.06,68.29 112.4,68.29 112.52,68.41 112.52,69.28 112.78,69.54 113.28,69.54 113.55,69.28 113.55,67.86 113.67,67.74 113.99,67.74 114.12,67.86 114.12,69.2 114.38,69.46 114.88,69.46 115.15,69.2 115.15,67.86 115.27,67.74 115.59,67.74 115.72,67.86 115.72,69.18 115.98,69.44 116.48,69.44 116.75,69.18 116.75,67.3 116.87,67.18 117.19,67.18 117.32,67.3 117.32,69.1 117.58,69.36 118.08,69.36 118.35,69.1 118.35,67.84 118.47,67.71 118.79,67.71 118.92,67.84 118.92,69.13 119.18,69.39 119.69,69.39 119.95,69.13 119.95,68.41 120.06,68.29 121.08,68.29 121.82,67.56 124.33,67.56 124.44,67.67 125.36,67.67 v2(125.8,67.23)
  BOTTOM w0.089: v2(96.5,59.96) 95.64,59.1 93.2,59.1 CPU1.AV37
  BOTTOM w0.102: v2(125.8,67.23) 125.31,66.75 DIMM1.101
M_A_DIMA_CLK_DDR1: length 58.2
  TOP w0.102: v1(130.02,68.17) 129.8,67.95 v2(129.8,67.65)
  L4 w0.089: 98.63,61 98.61,61.02 98.45,61.02 98.03,60.61 96.1,60.61 95.99,60.49 94.45,60.49 94.35,60.39 94.35,60.01 v2(94.54,59.82)
  L4 w0.114: 98.63,61 99.08,61 99.7,61.62 100.45,61.62 109.92,71.09 110.54,71.09 110.66,70.97 110.66,70.41 110.92,70.15 111.43,70.15 111.69,70.41 111.69,70.97 111.8,71.09 112.14,71.09 112.26,70.97 112.26,70.32 112.51,70.07 113.04,70.07 113.29,70.32 113.29,70.97 113.4,71.09 113.74,71.09 113.86,70.97 113.86,70.32 114.11,70.07 114.64,70.07 114.89,70.32 114.89,70.97 115,71.09 115.34,71.09 115.46,70.97 115.46,70.32 115.71,70.07 116.24,70.07 116.49,70.32 116.49,70.86 116.61,70.99 116.93,70.99 117.06,70.86 117.06,70.32 117.31,70.07 117.84,70.07 118.09,70.32 118.09,70.88 118.22,71.01 118.53,71.01 118.66,70.88 118.66,70.32 118.91,70.07 119.44,70.07 119.69,70.32 119.69,70.97 119.8,71.09 120.15,71.09 121.01,70.23 121.01,69.11 121.68,68.43 122.48,68.43 122.67,68.24 125.53,68.24 125.66,68.11 127,68.11 127.11,67.99 127.11,67.01 127.37,66.74 127.83,66.74 128.09,67.01 128.09,68.32 128.3,68.52 129.24,68.52 129.8,67.96 v2(129.8,67.65)
  BOTTOM w0.102: CPU1.AY36 94.21,60.14 v2(94.54,59.82) ; v2(129.8,67.65) 130.4,67.05 131.9,67.05 DIMM1.102
M_A_DIMA_CLK_DDR#0: length 58.9
  L4 w0.089: v2(97.15,59.96) 97.15,60.04 97.27,60.17 98.92,60.17 98.94,60.15
  L4 w0.114: 98.94,60.15 99.37,60.15 100.1,60.88 100.76,60.88 107.95,68.07 109.3,68.07 109.54,68.31 109.54,69.21 109.67,69.34 109.99,69.34 110.12,69.21 110.12,68.31 110.36,68.07 110.9,68.07 111.14,68.31 111.14,69.18 111.27,69.31 111.59,69.31 111.72,69.18 111.72,68.31 111.96,68.07 112.5,68.07 112.75,68.31 112.75,69.18 112.87,69.31 113.19,69.31 113.32,69.18 113.32,67.77 113.58,67.51 114.08,67.51 114.35,67.77 114.35,69.11 114.47,69.23 114.79,69.23 114.92,69.11 114.92,67.77 115.18,67.51 115.68,67.51 115.95,67.77 115.95,69.08 116.07,69.21 116.39,69.21 116.52,69.08 116.52,67.21 116.78,66.95 117.28,66.95 117.55,67.21 117.55,69.01 117.67,69.13 117.99,69.13 118.12,69.01 118.12,67.74 118.38,67.48 118.88,67.48 119.15,67.74 119.15,69.03 119.27,69.16 119.59,69.16 119.72,69.03 119.72,68.31 119.97,68.07 120.99,68.07 121.73,67.33 124.42,67.33 124.53,67.44 124.95,67.44 v2(125.16,67.23)
  BOTTOM w0.089: CPU1.AU37 92.54,59.34 92.78,59.1 92.95,59.1 93.13,58.93 95.73,58.93 96.25,59.44 96.67,59.44 ; 96.67,59.44 97.31,59.44 97.43,59.56 97.43,59.83 97.31,59.96 v2(97.15,59.96) ; 96.67,59.44 v1(96.67,59.28)
  BOTTOM w0.102: v2(125.16,67.23) 124.96,67.03 124.77,67.03 124.45,67.35 DIMM1.103
M_A_DIMA_CLK_DDR#1: length 58.4
  TOP w0.102: v2(130.44,67.65) 130.45,67.66 v1(131.19,67.66)
  L4 w0.089: 98.63,61.23 98.61,61.21 98.37,61.21 97.95,60.8 96.02,60.8 95.91,60.68 94.37,60.68 94.16,60.47 94.16,60.09 v2(93.89,59.82)
  L4 w0.114: 98.63,61.23 98.98,61.23 99.61,61.85 100.36,61.85 109.82,71.32 110.64,71.32 110.89,71.07 110.89,70.5 111.01,70.38 111.33,70.38 111.46,70.5 111.46,71.07 111.71,71.32 112.24,71.32 112.49,71.07 112.49,70.41 112.6,70.3 112.94,70.3 113.06,70.41 113.06,71.07 113.31,71.32 113.84,71.32 114.09,71.07 114.09,70.41 114.2,70.3 114.54,70.3 114.66,70.41 114.66,71.07 114.91,71.32 115.44,71.32 115.69,71.07 115.69,70.41 115.8,70.3 116.15,70.3 116.26,70.41 116.26,70.95 116.52,71.21 117.03,71.21 117.29,70.95 117.29,70.41 117.4,70.3 117.75,70.3 117.86,70.41 117.86,70.98 118.12,71.24 118.63,71.24 118.89,70.98 118.89,70.41 119,70.3 119.35,70.3 119.46,70.41 119.46,71.07 119.71,71.32 120.24,71.32 121.23,70.33 121.23,69.2 121.78,68.66 122.57,68.66 122.77,68.46 125.62,68.46 125.75,68.34 127.09,68.34 127.34,68.09 127.34,67.1 127.47,66.97 127.74,66.97 127.86,67.1 127.86,68.41 128.2,68.75 129.34,68.75 v2(130.44,67.65)
  BOTTOM w0.102: DIMM1.104 v2(130.44,67.65) ; CPU1.AW36 93.56,60.14 v2(93.89,59.82)
M_A_DIMA_CS#0: length 58.3
  TOP w0.178: v2(129.17,71.25) 128.99,71.43 128.99,71.61 v1(128.85,71.75)
  L4 w0.203: v2(90.75,61.66) 90.75,61.67 93.73,64.66 96.13,64.66 97.68,66.21 98.74,66.21 109.84,77.31 113.17,77.31 113.37,77.11 113.37,76.6 113.58,76.4 113.98,76.4 114.19,76.6 114.19,77.06 114.39,77.26 114.8,77.26 115,77.06 115,76.6 115.2,76.4 115.61,76.4 115.81,76.6 115.81,77.08 116.02,77.29 116.42,77.29 116.63,77.08 116.63,76.6 116.83,76.4 117.24,76.4 117.44,76.6 117.44,77.01 117.64,77.21 118.05,77.21 118.25,77.01 118.25,76.6 118.45,76.4 118.86,76.4 119.06,76.6 119.06,76.85 119.27,77.06 119.67,77.06 119.88,76.85 119.88,76.6 120.08,76.4 120.49,76.4 120.69,76.6 120.69,76.93 120.89,77.13 121.3,77.13 121.5,76.93 121.5,76.6 121.71,76.4 122.44,76.4 124.61,74.23 124.61,73.66 125.15,73.12 125.41,73.12 125.49,73.04 128.1,73.04 129.17,71.97 v2(129.17,71.25)
  BOTTOM w0.178: v2(129.17,71.25) 129.17,71.06 129.58,70.65 130.43,70.65 130.43,70.65 DIMM1.114 ; CPU1.AP33 90.75,61.8 v2(90.75,61.66)
M_A_DIMA_CS#1: length 59.2
  TOP w0.178: v2(125.87,73.62) 125.87,73.72 v1(126.26,74.11)
  L4 w0.203: v2(125.87,73.62) 125.87,73.7 126.61,74.44 127.25,74.44 127.74,74.92 127.76,74.92 127.76,77.41 127.25,77.92 124.45,77.92 124.25,77.72 124.25,76.4 124.04,76.19 123.64,76.19 123.43,76.4 123.43,77.72 123.23,77.92 114.8,77.92 114.6,78.12 114.6,78.45 114.4,78.66 113.99,78.66 113.79,78.45 113.79,78.12 113.58,77.92 113.18,77.92 112.98,78.12 112.98,78.45 112.77,78.66 112.37,78.66 112.16,78.45 112.16,78.12 111.96,77.92 111.55,77.92 111.35,78.12 111.35,78.38 111.15,78.58 110.74,78.58 110.54,78.38 110.54,78.12 110.33,77.92 109.59,77.92 98.49,66.82 97.42,66.82 95.88,65.27 91.9,65.27 90.75,64.13 v2(90.75,62.5)
  BOTTOM w0.178: v2(90.75,62.5) 90.75,62.64 CPU1.AR32 ; DIMM1.121 124.6,72.75 124.92,73.08 125.33,73.08 125.71,73.46 125.71,73.46 v2(125.87,73.62)
M_A_DIMA_ODT0: length 5.8
  TOP w0.254: v2(129.03,72.99) 128.78,72.99 v1(128.43,73.35) 127.76,74.01 R1206.2
  BOTTOM w0.254: v2(129.03,72.99) 129.03,72.87 130.65,71.25 DIMM1.116
M_A_DIMA_ODT1: length 5
  TOP w0.254: R1207.2 128.65,74.05 129.21,73.49 129.27,73.49 v2(129.8,72.96) 130.32,72.96 v1(130.36,72.92)
  BOTTOM w0.254: DIMM1.120 131.9,72.45 130.17,72.45 129.8,72.81 v2(129.8,72.96)
M_A_DQ0: length 91.5
  TOP w0.114: v2(125.16,75.15) 125.16,75.14 v1(124.77,74.75)
  L3 w0.127: v2(125.16,75.15) 124.89,75.15 124.36,74.62 124.18,74.62 123.8,75 123.62,75 123.44,74.82 123.44,74.64 123.82,74.26 123.82,74.08 122.61,72.87 121.49,72.87 120.98,72.35 120.98,47.05 113.08,39.16 113.08,38.93 112.77,38.62 112.54,38.62 112.36,38.44 112.36,38.26 112.46,38.16 112.46,37.98 112.28,37.8 112.1,37.8 112,37.9 111.82,37.9 111.64,37.72 111.64,37.54 111.74,37.44 111.74,37.26 111.56,37.08 111.38,37.08 111.28,37.18 111.1,37.18 110.93,37 110.93,36.82 111.02,36.72 111.02,36.54 110.84,36.36 110.66,36.36 110.57,36.46 110.39,36.46 110.21,36.28 110.21,36.1 110.3,36 110.3,35.82 110.12,35.64 109.94,35.64 109.85,35.74 109.67,35.74 109.49,35.56 109.49,35.38 109.58,35.28 109.58,35.1 109.41,34.93 109.23,34.93 109.13,35.02 108.95,35.02 108.77,34.84 108.77,34.66 108.87,34.57 108.87,34.39 108.69,34.21 108.51,34.21 108.41,34.3 108.23,34.3 108.05,34.12 108.05,33.94 108.15,33.85 108.15,33.67 107.97,33.49 107.79,33.49 107.69,33.58 107.51,33.58 107.33,33.41 107.33,33.23 107.43,33.13 107.43,32.95 107.25,32.77 107.07,32.77 106.97,32.87 106.79,32.87 106.61,32.69 106.61,32.51 106.71,32.41 106.71,32.23 106.53,32.05 106.35,32.05 106.25,32.15 106.07,32.15 105.89,31.97 105.89,31.79 105.99,31.69 105.99,31.51 105.81,31.33 105.63,31.33 105.53,31.43 105.35,31.43 105.17,31.25 105.17,31.07 105.27,30.97 105.27,30.79 105.09,30.61 104.91,30.61 104.82,30.71 104.64,30.71 104.16,30.24 90.63,30.24 89.13,31.74 89.13,34.22 86.68,36.68 v2(86.68,40.47)
  BOTTOM w0.089: CPU1.AH63 86.89,43.16 86.89,43.13 86.97,43.05 86.97,40.77 v2(86.68,40.47)
  BOTTOM w0.114: DIMM1.129 v2(125.16,75.15)
M_A_DQ1: length 92.2
  TOP w0.114: v2(126.43,75.15) 126.43,75.39 v1(126.69,75.65)
  L3 w0.127: v2(86.55,41.09) 86.23,40.78 86.23,36.56 88.74,34.05 88.74,31.57 90.46,29.86 104.88,29.86 114.52,39.5 114.52,39.83 114.72,40.03 114.88,40.03 115.05,40.03 115.44,40.42 115.44,40.6 115.34,40.7 115.34,40.88 115.53,41.06 115.7,41.06 115.8,40.96 115.98,40.96 116.25,41.23 116.25,41.41 116.15,41.51 116.15,41.69 116.33,41.87 116.51,41.87 116.61,41.77 116.79,41.77 116.97,41.95 116.97,42.13 116.87,42.23 116.87,42.41 117.05,42.59 117.23,42.59 117.33,42.49 117.51,42.49 117.69,42.67 117.69,42.85 117.59,42.95 117.59,43.13 117.77,43.31 117.95,43.31 118.05,43.21 118.23,43.21 118.41,43.39 118.41,43.57 118.31,43.67 118.31,43.85 118.49,44.02 118.67,44.02 118.77,43.93 118.95,43.93 119.27,44.25 119.27,44.42 119.17,44.52 119.17,44.7 119.35,44.88 119.53,44.88 119.62,44.78 119.8,44.78 121.37,46.35 121.37,71.35 122.01,71.99 122.83,71.99 125.48,74.65 125.93,74.65 v2(126.43,75.15)
  BOTTOM w0.089: v2(86.55,41.09) 86.79,41.34 86.79,42.57 86.66,42.87 86.66,42.88 86.58,43.1 86.58,43.24 86.61,43.31 86.66,43.45 86.75,43.6 CPU1.AH62
  BOTTOM w0.114: DIMM1.131 125.98,75.75 126.43,75.3 v2(126.43,75.15)
M_A_DQ2: length 90.5
  TOP w0.114: v2(126.43,79.35) 126.43,79.52 v1(126.73,79.82)
  L3 w0.127: v2(87.8,40.11) 88.06,40.11 88.72,39.45 88.72,38.67 90.74,36.65 93.43,36.65 96.09,33.98 103.65,33.98 108.13,38.47 108.48,38.47 108.67,38.66 108.67,39.01 108.85,39.19 109.03,39.19 109.25,38.97 109.43,38.97 109.61,39.15 109.61,39.33 109.39,39.55 109.39,39.73 109.57,39.91 109.75,39.91 109.97,39.69 110.15,39.69 110.33,39.87 110.33,40.05 110.11,40.27 110.11,40.45 110.29,40.63 110.47,40.63 110.69,40.41 110.87,40.41 111.04,40.59 111.04,40.77 110.83,40.98 110.83,41.16 111.01,41.34 111.19,41.34 111.4,41.13 111.58,41.13 111.76,41.31 111.76,41.49 111.55,41.7 111.55,41.88 111.73,42.06 111.91,42.06 112.12,41.85 112.3,41.85 112.48,42.03 112.48,42.21 112.27,42.42 112.27,42.6 112.45,42.78 112.63,42.78 112.84,42.57 113.02,42.57 113.2,42.75 113.2,42.93 112.99,43.14 112.99,43.32 113.17,43.5 113.35,43.5 113.56,43.29 113.74,43.29 113.92,43.47 113.92,43.65 113.71,43.86 113.71,44.04 113.89,44.22 114.07,44.22 114.28,44 114.46,44 114.64,44.18 114.64,44.36 114.42,44.58 114.42,44.76 114.6,44.94 114.78,44.94 115,44.72 115.18,44.72 115.36,44.9 115.36,45.08 115.14,45.3 115.14,45.48 115.32,45.66 115.5,45.66 115.72,45.44 115.9,45.44 118.54,48.09 118.54,73.45 123.7,78.61 126.27,78.61 126.43,78.77 v2(126.43,79.35)
  BOTTOM w0.089: v2(87.8,40.11) 88.53,40.84 88.53,42.5 88.3,42.74 88.3,43.11 CPU1.AK63
  BOTTOM w0.114: v2(126.43,79.35) 126.43,79.28 125.91,78.75 DIMM1.141
M_A_DQ3: length 91.3
  TOP w0.114: v2(129.8,77.85) 129.8,77.74 v1(129.39,77.33)
  L3 w0.127: v2(87.79,39.48) 87.99,39.48 88.33,39.14 88.33,38.52 90.59,36.26 93.25,36.26 95.92,33.59 104.59,33.59 105.66,34.67 105.66,34.99 105.88,35.21 106.2,35.21 106.38,35.39 106.38,35.57 106.16,35.78 106.16,35.96 106.34,36.14 106.52,36.14 106.74,35.92 106.92,35.92 107.19,36.19 107.19,36.37 106.97,36.59 106.97,36.77 107.15,36.95 107.33,36.95 107.55,36.73 107.73,36.73 118.92,47.93 118.92,73.3 123.84,78.21 127.47,78.21 127.67,78.42 127.67,79.04 127.82,79.19 128.03,79.19 128.18,79.04 128.18,78.42 128.31,78.29 128.56,78.29 128.69,78.42 128.69,78.94 128.84,79.09 129.05,79.09 129.2,78.94 129.2,78.42 129.33,78.29 129.67,78.29 129.8,78.17 129.8,77.85 v2(129.8,77.85)
  BOTTOM w0.089: v2(87.79,39.48) 88.41,40.1 88.41,40.3 88.71,40.6 88.71,42.58 88.49,42.8 88.49,43.56 CPU1.AK62
  BOTTOM w0.114: DIMM1.140 130.04,78.45 129.8,78.21 v2(129.8,77.85)
M_A_DQ4: length 92.6
  TOP w0.114: v2(130.44,76.05) 130.44,76.79 v1(130.53,76.88)
  L3 w0.127: v2(130.44,76.05) 130.43,76.05 128.5,74.11 128.5,72.48 127.76,71.75 126.01,71.75 123.06,68.8 123.06,66.62 121.79,65.35 121.79,46.22 105.04,29.46 90.27,29.46 88.35,31.38 88.35,33.87 85.84,36.38 85.84,41.29 v2(86.29,41.75)
  BOTTOM w0.089: v2(86.29,41.75) 86.59,42.04 86.59,42.53 86.49,42.82 86.4,43.07 86.4,43.27 86.44,43.38 86.49,43.5 86.49,44.11 CPU1.AH61
  BOTTOM w0.114: DIMM1.132 v2(130.44,76.05)
M_A_DQ5: length 93.5
  TOP w0.114: v1(128.42,76.6) 128.62,76.6 v2(129.17,76.05)
  L3 w0.127: v2(87.78,41.38) 87.22,40.83 87.22,36.69 89.53,34.38 89.53,31.9 90.81,30.62 93.95,30.62 94.07,30.75 94.58,30.75 94.71,30.62 104.01,30.62 120.59,47.2 120.59,72.52 123.67,75.61 128.72,75.61 129.16,76.05 v2(129.17,76.05)
  BOTTOM w0.089: v2(87.78,41.38) 88.17,41.78 88.17,42.36 87.93,42.6 87.82,42.79 87.75,43.03 87.75,43.28 87.8,43.4 87.83,43.46 87.83,43.57 87.77,43.69 87.75,43.73 87.75,43.93 87.8,44.06 87.83,44.11 87.83,44.26 87.82,44.26 87.82,44.71 87.84,44.73 87.84,44.94 87.64,45.14 CPU1.AH60
  BOTTOM w0.114: DIMM1.130 129.77,75.45 129.29,75.93 129.29,75.93 v2(129.17,76.05)
M_A_DQ6: length 91.8
  TOP w0.114: v2(87.78,40.75) 87.79,40.76 v1(88.47,40.76)
  L3 w0.127: v2(87.78,40.75) 87.98,40.75 89.12,39.61 89.12,38.81 90.9,37.03 93.62,37.03 96.27,34.38 103.5,34.38 116.25,47.12 116.55,47.12 116.79,47.36 116.79,47.66 116.97,47.84 117.15,47.84 117.36,47.63 117.54,47.63 117.72,47.81 117.72,47.98 117.51,48.2 117.51,48.38 118.16,49.03 118.16,49.43 118.03,49.56 117.88,49.56 117.75,49.68 117.75,49.94 117.88,50.07 118.03,50.07 118.16,50.19 118.16,50.45 118.03,50.57 117.88,50.57 117.75,50.7 117.75,50.95 117.88,51.08 118.03,51.08 118.16,51.21 118.16,51.46 118.03,51.59 117.88,51.59 117.75,51.72 117.75,51.97 117.88,52.1 118.03,52.1 118.16,52.22 118.16,52.48 118.03,52.61 117.88,52.61 117.75,52.73 117.75,52.99 117.88,53.11 118.03,53.11 118.16,53.24 118.16,53.49 118.03,53.62 117.88,53.62 117.75,53.75 117.75,54 117.88,54.13 118.03,54.13 118.16,54.26 118.16,54.51 118.03,54.64 117.88,54.64 117.75,54.76 117.75,55.02 117.88,55.15 118.03,55.15 118.16,55.27 118.16,55.53 118.03,55.65 117.88,55.65 117.75,55.78 117.75,56.03 117.88,56.16 118.03,56.16 118.16,56.29 118.16,56.54 118.03,56.67 117.88,56.67 117.75,56.8 117.75,57.05 117.88,57.18 118.03,57.18 118.16,57.3 118.16,57.56 118.03,57.69 117.88,57.69 117.75,57.81 117.75,58.07 117.88,58.19 118.03,58.19 118.16,58.32 118.16,58.57 118.03,58.7 117.88,58.7 117.75,58.83 117.75,59.08 117.88,59.21 118.03,59.21 118.16,59.34 118.16,59.59 118.03,59.72 117.88,59.72 117.75,59.84 117.75,60.1 117.88,60.23 118.03,60.23 118.16,60.35 118.16,60.61 118.03,60.73 117.88,60.73 117.75,60.86 117.75,61.11 117.88,61.24 118.03,61.24 118.16,61.37 118.16,61.62 118.03,61.75 117.88,61.75 117.75,61.88 117.75,62.13 117.88,62.26 118.03,62.26 118.16,62.38 118.16,62.64 118.03,62.77 117.88,62.77 117.75,62.89 117.75,63.15 117.88,63.27 118.03,63.27 118.16,63.4 118.16,63.65 118.03,63.78 117.88,63.78 117.75,63.91 117.75,64.16 117.88,64.29 118.03,64.29 118.16,64.42 118.16,64.67 118.03,64.8 117.88,64.8 117.75,64.92 117.75,65.18 117.88,65.31 118.03,65.31 118.16,65.43 118.16,65.69 118.03,65.81 117.88,65.81 117.75,65.94 117.75,66.19 117.88,66.32 118.03,66.32 118.16,66.45 118.16,66.7 118.03,66.83 117.88,66.83 117.75,66.96 117.75,67.21 117.88,67.34 118.03,67.34 118.16,67.46 118.16,67.72 118.03,67.85 117.88,67.85 117.75,67.97 117.75,68.23 117.88,68.35 118.03,68.35 118.16,68.48 118.16,68.73 118.03,68.86 117.88,68.86 117.75,68.99 117.75,69.24 117.88,69.37 118.03,69.37 118.16,69.5 118.16,69.75 118.03,69.88 117.88,69.88 117.75,70 117.75,70.26 117.88,70.39 118.03,70.39 118.16,70.51 118.16,70.74 118.01,70.89 118.01,71.33 118.16,71.48 118.16,73.61 123.55,79 124.81,79 v2(125.16,79.35)
  BOTTOM w0.089: v2(87.78,40.75) 88.35,41.31 88.35,42.44 88.07,42.71 88.03,42.79 arc(87.99,42.86) 87.97,42.94 87.95,42.99 arc(87.94,43.02) 87.94,43.05 87.94,43.27 87.97,43.34 87.99,43.4 arc(88,43.42) 88,43.45 88,43.62 87.97,43.68 arc(87.97,43.69) 87.96,43.7 87.94,43.74 arc(87.93,43.77) 87.93,43.8 87.93,43.87 arc(87.93,43.89) 87.94,43.91 87.97,43.99 87.99,44.05 arc(88,44.07) 88,44.1 88,44.31 arc(88.02,44.38) 88.06,44.43 CPU1.AK61
  BOTTOM w0.114: DIMM1.143 v2(125.16,79.35)
M_A_DQ7: length 91.9
  L3 w0.127: v2(87.88,38.81) 87.88,38.44 90.43,35.88 93.09,35.88 95.68,33.29 95.68,33.29 95.81,33.17 102.34,33.17 102.47,33.04 102.47,32.94 102.59,32.81 102.87,32.81 103,32.94 103,33.04 103.13,33.17 104.7,33.17 119.3,47.77 119.3,73.12 123.95,77.77 125.33,77.77 125.53,77.56 125.83,77.56 126.04,77.77 126.34,77.77 126.55,77.56 126.85,77.56 127.05,77.77 127.44,77.77 127.56,77.64 127.56,76.65 127.69,76.52 128.68,76.52 128.8,76.65 128.8,76.97 128.68,77.1 128.21,77.1 128.07,77.23 128.07,77.64 128.2,77.77 128.45,77.77 v2(128.53,77.85)
  BOTTOM w0.089: CPU1.AK60 88.11,44.95 88.67,44.39 88.67,42.87 88.88,42.65 88.88,40.45 88.77,40.33 88.77,39.46 v1(88.6,39.29)
  BOTTOM w0.114: v2(128.53,77.85) 129.73,79.05 DIMM1.142 ; v1(88.6,39.29) 88.12,38.81 v2(87.88,38.81)
M_A_DQ8: length 53.9
  TOP w0.114: v2(125.8,36.75) 125.8,36.96 v1(125.48,37.28)
  L4 w0.127: v2(90.26,40.06) 90.7,39.62 90.7,37.9 92.28,36.32 93.02,36.32 93.02,36.33 93.34,36.33 97.33,32.33 120.84,32.33 121.13,32.62 121.31,32.62 121.53,32.4 121.71,32.4 121.89,32.58 121.89,32.76 121.67,32.98 121.67,33.16 121.85,33.34 122.03,33.34 122.47,32.9 122.65,32.9 122.83,33.08 122.83,33.26 122.39,33.7 122.39,33.88 122.57,34.06 122.75,34.06 123.25,33.56 123.43,33.56 123.61,33.74 123.61,33.92 123.11,34.42 123.11,34.6 123.29,34.78 123.47,34.78 124.06,34.19 124.24,34.19 124.42,34.37 124.42,34.55 123.83,35.14 123.83,35.32 124.74,36.23 125.28,36.23 v2(125.8,36.75)
  BOTTOM w0.089: v2(90.26,40.06) 89.83,40.49 89.83,40.64 89.44,41.03 89.44,42.85 89.42,42.88 89.42,42.88 89.29,43 CPU1.AM63
  BOTTOM w0.114: DIMM1.7 125.2,36.15 v2(125.8,36.75)
M_A_DQ9: length 54.9
  TOP w0.114: v2(130.44,35.25) 130.44,35.67 v1(130.58,35.81)
  L4 w0.127: v2(89.57,39.86) 89.55,39.86 89.1,39.41 89.1,37.88 91.8,35.18 92.86,35.18 96.85,31.19 123.96,31.19 124.42,31.66 124.42,31.84 124.26,32 124.26,32.18 124.44,32.36 124.62,32.36 124.78,32.2 125.5,32.2 127.86,34.56 129.75,34.56 v2(130.44,35.25)
  BOTTOM w0.089: CPU1.AM62 89.02,43.34 89.02,43.02 89.24,42.8 89.24,40.93 v2(89.57,39.86)
  BOTTOM w0.114: DIMM1.4 v2(130.44,35.25)
M_A_DQ10: length 53.1
  TOP w0.114: v2(126.43,38.55) 126.43,38.41 v1(126.8,38.04)
  L4 w0.127: v2(91.98,39.99) 92.42,39.55 92.42,38.56 92.99,37.99 94.04,37.99 97.54,34.49 109.61,34.49 109.82,34.28 110.16,34.28 110.37,34.49 110.62,34.49 110.75,34.37 110.75,34.13 110.88,34 111.13,34 111.26,34.13 111.26,34.37 111.38,34.49 111.64,34.49 111.77,34.37 111.77,34.13 111.89,34 112.15,34 112.27,34.13 112.27,34.37 112.4,34.49 112.65,34.49 112.78,34.37 112.78,34.13 112.91,34 113.16,34 113.29,34.13 113.29,34.37 113.42,34.49 113.67,34.49 113.8,34.37 113.8,34.13 113.92,34 114.18,34 114.31,34.13 114.31,34.37 114.43,34.49 114.69,34.49 114.81,34.37 114.81,34.13 114.94,34 115.19,34 115.32,34.13 115.32,34.37 115.45,34.49 115.7,34.49 115.83,34.37 115.83,34.13 115.96,34 116.21,34 116.34,34.13 116.34,34.37 116.46,34.49 116.72,34.49 116.85,34.37 116.85,34.13 116.97,34 117.23,34 117.35,34.13 117.35,34.37 117.48,34.49 117.73,34.49 117.86,34.37 117.86,34.13 117.99,34 118.24,34 118.37,34.13 118.37,34.37 118.5,34.49 118.75,34.49 118.88,34.37 118.88,34.13 119,34 119.26,34 119.39,34.13 119.39,34.37 119.51,34.49 120.37,34.49 124.87,38.99 125.98,38.99 126.27,38.7 126.28,38.7 v2(126.43,38.55)
  BOTTOM w0.089: v2(91.98,39.99) 91.17,40.8 91.17,42.42 90.65,42.95 CPU1.AP63
  BOTTOM w0.114: v2(126.43,38.55) 125.83,39.15 DIMM1.17
M_A_DQ11: length 54.1
  TOP w0.114: v2(130.44,39.45) 130.44,39.02 v1(130.58,38.88)
  L4 w0.127: v2(91.98,40.64) 92.82,39.8 92.82,38.85 93.28,38.39 94.19,38.39 97.7,34.89 120.21,34.89 124.71,39.39 126.57,39.39 126.69,39.26 126.69,39.12 126.82,38.99 127.07,38.99 127.2,39.12 127.2,39.26 127.33,39.39 127.99,39.39 128.13,39.24 128.13,38.54 128.13,38.54 128.13,37.74 128.26,37.61 128.51,37.61 128.64,37.74 128.64,38.83 128.77,38.96 129.02,38.96 129.15,38.83 129.15,38.35 129.28,38.22 129.53,38.22 129.66,38.35 129.66,38.54 129.78,38.66 130.21,38.66 130.44,38.89 v2(130.44,39.45)
  BOTTOM w0.089: v2(91.98,40.64) 91.76,40.64 91.37,41.03 91.37,42.47 91.35,42.49 90.93,42.91 90.93,43.41 90.65,43.7 CPU1.AP62
  BOTTOM w0.114: DIMM1.18 v2(130.44,39.45)
M_A_DQ12: length 55
  TOP w0.114: v2(129.17,35.25) v1(128.57,35.25)
  L4 w0.127: v2(89.57,39.21) 89.57,37.95 91.96,35.56 93.02,35.56 97.01,31.57 122.74,31.57 123.14,31.97 123.32,31.97 123.4,31.88 123.58,31.88 123.76,32.06 123.76,32.24 123.68,32.33 123.68,32.51 124.14,32.98 125.69,32.98 127.97,35.25 v2(129.17,35.25)
  BOTTOM w0.089: CPU1.AM61 88.84,43.93 88.84,42.94 89.06,42.73 89.06,40.68 89.12,40.62 89.12,39.41 89.32,39.21 v2(89.57,39.21)
  BOTTOM w0.114: DIMM1.6 129.77,35.85 v2(129.17,35.25)
M_A_DQ13: length 55.5
  L4 w0.127: v2(127.07,36.75) 126.11,35.79 126.11,34.05 125.63,33.57 124.2,33.57 122.58,31.95 97.17,31.95 93.18,35.94 92.12,35.94 90.21,37.85 v2(90.21,38.67)
  BOTTOM w0.089: CPU1.AM60 90.07,45.14 90.27,44.94 90.27,44.69 90.26,44.68 90.26,44.11 90.24,44.06 90.18,43.93 90.18,43.73 90.2,43.69 90.26,43.57 90.26,43.46 90.24,43.4 90.18,43.28 90.18,42.91 90.69,42.4 90.69,39.41 91.06,39.03 v1(91.06,38.67)
  BOTTOM w0.114: v2(127.07,36.75) 125.87,35.55 DIMM1.5 ; v1(91.06,38.67) v2(90.21,38.67)
M_A_DQ14: length 53.4
  L4 w0.127: v2(91.98,39.34) 91.98,38.43 92.8,37.61 93.86,37.61 97.86,33.62 98.33,33.62 98.46,33.74 98.46,33.99 98.58,34.11 98.84,34.11 98.96,33.99 98.96,33.74 99.09,33.62 99.34,33.62 99.47,33.74 99.47,33.99 99.6,34.11 99.85,34.11 99.98,33.99 99.98,33.74 100.11,33.62 100.36,33.62 100.49,33.74 100.49,33.99 100.61,34.11 100.87,34.11 101,33.99 101,33.74 101.12,33.62 101.38,33.62 101.5,33.74 101.5,33.99 101.63,34.11 101.88,34.11 102.01,33.99 102.01,33.74 102.14,33.62 102.39,33.62 102.52,33.74 102.52,33.99 102.65,34.11 102.9,34.11 103.03,33.99 103.03,33.74 103.15,33.62 103.41,33.62 103.54,33.74 103.54,33.99 103.66,34.11 103.92,34.11 104.04,33.99 104.04,33.74 104.17,33.62 104.42,33.62 104.55,33.74 104.55,33.99 104.68,34.11 104.93,34.11 105.06,33.99 105.06,33.74 105.19,33.62 105.44,33.62 105.57,33.74 105.57,33.99 105.69,34.11 105.95,34.11 106.08,33.99 106.08,33.74 106.2,33.62 106.46,33.62 106.58,33.74 106.58,33.99 106.71,34.11 106.96,34.11 107.09,33.99 107.09,33.74 107.22,33.62 107.47,33.62 107.6,33.74 107.6,33.99 107.73,34.11 107.98,34.11 108.11,33.99 108.11,33.74 108.23,33.62 108.49,33.62 108.62,33.74 108.62,33.99 108.74,34.11 109,34.11 109.12,33.99 109.12,33.74 109.25,33.62 109.73,33.62 109.91,33.8 110.39,33.8 110.57,33.62 120.23,33.62 v2(125.16,38.55)
  BOTTOM w0.089: v1(91.21,39.9) 90.99,40.11 90.99,42.35 90.36,42.98 90.36,43.22 arc(90.36,43.24) 90.37,43.26 90.4,43.34 90.42,43.4 arc(90.43,43.42) 90.43,43.45 90.43,43.62 90.4,43.68 arc(90.4,43.69) 90.39,43.7 90.37,43.74 arc(90.36,43.77) 90.36,43.8 90.36,43.87 arc(90.36,43.89) 90.37,43.91 90.4,43.99 90.42,44.05 arc(90.43,44.07) 90.43,44.1 90.43,44.12 arc(90.46,44.26) 90.54,44.38 CPU1.AP61
  BOTTOM w0.114: DIMM1.15 v2(125.16,38.55) ; v1(91.21,39.9) 91.77,39.34 v2(91.98,39.34)
M_A_DQ15: length 55
  TOP w0.114: v1(128.8,38.96) 129.17,39.32 v2(129.17,39.45)
  L4 w0.127: v2(129.17,39.45) 128.66,39.96 128.19,39.96 128.05,39.82 124.59,39.82 120.24,35.48 119.15,35.48 118.94,35.27 118.64,35.27 118.43,35.48 118.13,35.48 117.92,35.27 117.63,35.27 117.42,35.48 117.12,35.48 116.91,35.27 116.61,35.27 116.4,35.48 116.1,35.48 115.89,35.27 115.59,35.27 115.38,35.48 115.09,35.48 114.88,35.27 114.58,35.27 114.37,35.48 114.07,35.48 113.86,35.27 113.56,35.27 113.35,35.48 113.05,35.48 112.84,35.27 112.55,35.27 112.34,35.48 112.04,35.48 111.83,35.27 111.53,35.27 111.32,35.48 111.02,35.48 110.81,35.27 110.51,35.27 110.3,35.48 110.01,35.48 109.8,35.27 109.5,35.27 109.29,35.48 108.99,35.48 108.78,35.27 108.48,35.27 108.27,35.48 107.97,35.48 107.76,35.27 107.47,35.27 107.26,35.48 106.96,35.48 106.75,35.27 106.45,35.27 106.24,35.48 105.94,35.48 105.73,35.27 105.43,35.27 105.22,35.48 104.93,35.48 104.72,35.27 104.42,35.27 104.21,35.48 103.91,35.48 103.7,35.27 103.4,35.27 103.19,35.48 102.89,35.48 102.68,35.27 102.39,35.27 102.18,35.48 101.88,35.48 101.67,35.27 101.37,35.27 101.16,35.48 100.86,35.48 100.65,35.27 100.35,35.27 100.14,35.48 99.85,35.48 99.64,35.27 99.34,35.27 99.13,35.48 98.83,35.48 98.62,35.27 98.32,35.27 98.11,35.48 97.73,35.48 97.29,35.92 97.29,36.26 97.1,36.45 96.76,36.45 96.57,36.64 96.57,36.98 96.38,37.17 96.04,37.17 95.85,37.36 95.85,37.7 95.66,37.89 95.32,37.89 95.13,38.08 95.13,38.42 94.94,38.61 94.6,38.61 94.33,38.88 93.55,38.88 93.29,39.14 93.29,39.98 92.87,40.4 92.87,40.73 92.67,40.92 92.35,40.92 v2(91.98,41.29)
  BOTTOM w0.089: CPU1.AP60 90.65,44.91 90.94,44.62 90.94,43.66 91.11,43.49 91.11,42.99 91.22,42.88 91.55,42.55 91.55,41.54 91.79,41.29 v2(91.98,41.29)
  BOTTOM w0.114: v2(129.17,39.45) 129.17,39.35 129.67,38.85 DIMM1.16
M_A_DQ16: length 85.8
  TOP w0.114: v2(127.07,82.95) 127.07,83.12 v1(127.41,83.46)
  L3 w0.127: v2(127.07,82.95) 126.62,83.39 122.68,83.39 114.25,74.96 114.25,73.52 114.12,73.39 113.87,73.39 113.74,73.27 113.74,73.01 113.87,72.89 114.12,72.89 114.25,72.76 114.25,72.51 114.12,72.38 113.82,72.38 113.69,72.25 113.69,72 113.82,71.87 114.12,71.87 114.25,71.74 114.25,71.49 114.12,71.36 113.82,71.36 113.69,71.24 113.69,70.98 113.82,70.85 114.12,70.85 114.25,70.73 114.25,70.47 114.12,70.35 113.82,70.35 113.69,70.22 113.69,69.97 113.82,69.84 114.12,69.84 114.25,69.71 114.25,69.46 114.12,69.33 113.82,69.33 113.69,69.2 113.69,68.95 113.82,68.82 114.12,68.82 114.25,68.7 114.25,68.44 114.12,68.31 113.82,68.31 113.69,68.19 113.69,67.93 113.82,67.81 114.12,67.81 114.25,67.68 114.25,67.43 114.12,67.3 113.82,67.3 113.69,67.17 113.69,66.92 113.82,66.79 114.12,66.79 114.25,66.66 114.25,66.41 114.12,66.28 113.82,66.28 113.69,66.16 113.69,65.9 113.82,65.77 114.12,65.77 114.25,65.65 114.25,65.39 114.12,65.27 113.82,65.27 113.69,65.14 113.69,64.89 113.82,64.76 114.12,64.76 114.25,64.63 114.25,64.08 113.69,63.52 113.69,50.99 101.51,38.8 97.06,38.8 94.19,41.67 94.19,42.75 92.63,44.31 92.63,45.47 91.7,46.41 91.21,46.41 90.78,45.98 v2(90.78,45.92)
  BOTTOM w0.089: CPU1.AP58 90.45,46.28 90.78,45.96 v2(90.78,45.92)
  BOTTOM w0.114: DIMM1.159 125.95,84.15 127.07,83.03 v2(127.07,82.95)
M_A_DQ17: length 85.3
  TOP w0.114: v1(126.08,83.52) 125.8,83.24 v2(125.8,82.95)
  L3 w0.127: v2(91.42,45.93) 92.24,45.11 92.24,44.15 93.8,42.59 93.8,41.5 96.88,38.42 101.67,38.42 114.63,51.39 114.63,51.77 114.5,51.89 114.2,51.89 114.07,52.02 114.07,52.28 114.2,52.4 114.5,52.4 114.63,52.53 114.63,52.78 114.5,52.91 114.2,52.91 114.07,53.04 114.07,53.29 114.2,53.42 114.5,53.42 114.63,53.55 114.63,53.8 114.5,53.93 114.2,53.93 114.07,54.05 114.07,54.31 114.2,54.43 114.5,54.43 114.63,54.56 114.63,54.82 114.5,54.94 114.2,54.94 114.07,55.07 114.07,55.32 114.2,55.45 114.5,55.45 114.63,55.58 114.63,55.83 114.5,55.96 114.2,55.96 114.07,56.09 114.07,56.34 114.2,56.47 114.5,56.47 114.63,56.59 114.63,56.85 114.5,56.97 114.2,56.97 114.07,57.1 114.07,57.36 114.2,57.48 114.5,57.48 114.63,57.61 114.63,57.86 114.5,57.99 114.2,57.99 114.07,58.12 114.07,58.37 114.2,58.5 114.5,58.5 114.63,58.63 114.63,58.88 114.5,59.01 114.2,59.01 114.07,59.13 114.07,59.39 114.2,59.51 114.5,59.51 114.63,59.64 114.63,59.9 114.5,60.02 114.2,60.02 114.07,60.15 114.07,60.4 114.2,60.53 114.5,60.53 114.63,60.66 114.63,60.91 114.5,61.04 114.2,61.04 114.07,61.17 114.07,61.42 114.2,61.55 114.5,61.55 114.63,61.67 114.63,61.93 114.5,62.05 114.33,62.05 114.2,62.18 114.2,62.44 114.33,62.56 114.5,62.56 114.63,62.69 114.63,62.94 114.5,63.07 114.33,63.07 114.2,63.2 114.2,63.45 114.33,63.58 114.5,63.58 114.63,63.71 114.63,74.77 122.36,82.51 122.88,82.51 123,82.63 123,82.89 123.13,83.01 123.38,83.01 123.51,82.89 123.51,82.63 123.64,82.51 123.89,82.51 124.02,82.63 124.02,82.89 124.15,83.01 124.4,83.01 124.53,82.89 124.53,82.63 124.65,82.51 125.35,82.51 v2(125.8,82.95)
  BOTTOM w0.089: CPU1.AR58 91.1,46.23 91.41,45.93 v2(91.42,45.93)
  BOTTOM w0.114: v2(125.8,82.95) 125.8,83.02 125.27,83.55 DIMM1.157
M_A_DQ18: length 87.6
  TOP w0.114: v2(130.44,80.25) 130.44,80.65 v1(130.58,80.79)
  L3 w0.127: v2(89.47,46.84) 89.08,46.44 87.98,46.44 87.69,46.16 87.69,44.65 89.5,42.85 90.61,42.85 91.1,42.36 91.1,42.36 91.11,42.35 91.11,38.96 91.83,38.24 94.13,38.24 96.36,36.01 103.61,36.01 116.73,49.12 116.73,73.69 123.31,80.28 126.82,80.28 127.24,80.69 130,80.69 v2(130.44,80.25)
  BOTTOM w0.089: CPU1.AM57 89.15,47.19 89.47,46.86 v2(89.47,46.84)
  BOTTOM w0.114: DIMM1.146 v2(130.44,80.25)
M_A_DQ19: length 89.1
  TOP w0.114: v2(129.17,80.25) 129.17,80.64 v1(129.33,80.8)
  L3 w0.127: v2(129.17,80.25) 127.35,80.25 126.99,79.89 123.48,79.89 117.12,73.53 117.12,48.98 103.45,35.31 100.07,35.31 99.9,35.48 99.56,35.48 99.39,35.31 99.05,35.31 98.88,35.48 98.54,35.48 98.37,35.31 97.83,35.31 97.63,35.5 97.29,35.5 97.1,35.31 96.51,35.31 93.97,37.85 91.66,37.85 90.72,38.8 90.72,42.18 90.7,42.19 90.7,42.2 90.44,42.46 89.33,42.46 86.56,45.23 86.56,46.02 87.43,46.89 v2(88.17,46.89)
  BOTTOM w0.089: v2(88.17,46.89) 88.15,46.89 87.85,47.18 CPU1.AK57
  BOTTOM w0.114: DIMM1.148 129.7,80.85 129.17,80.32 v2(129.17,80.25)
M_A_DQ20: length 88.1
  TOP w0.114: v2(88.86,45.97) 89.23,45.59 v1(89.23,45.41)
  L3 w0.127: v2(125.16,81.15) 122.84,81.15 115.94,74.24 115.94,50.09 115.67,49.82 115.49,49.82 115.28,50.04 115.1,50.04 114.92,49.86 114.92,49.68 115.46,49.13 115.46,48.95 115.28,48.77 115.1,48.77 114.56,49.32 114.38,49.32 114.2,49.14 114.2,48.96 114.41,48.74 114.41,48.56 114.23,48.38 114.05,48.38 113.84,48.6 113.66,48.6 113.48,48.42 113.48,48.24 113.69,48.03 113.69,47.85 113.51,47.67 113.33,47.67 113.12,47.88 112.94,47.88 112.76,47.7 112.76,47.52 112.97,47.31 112.97,47.13 112.79,46.95 112.61,46.95 112.4,47.16 112.22,47.16 112.04,46.98 112.04,46.8 112.25,46.59 112.25,46.41 112.07,46.23 111.89,46.23 111.68,46.44 111.5,46.44 111.32,46.26 111.32,46.08 111.53,45.87 111.53,45.69 111.36,45.51 111.18,45.51 110.96,45.72 110.78,45.72 110.6,45.54 110.6,45.36 110.82,45.15 110.82,44.97 110.64,44.79 110.46,44.79 110.24,45 110.06,45 109.88,44.82 109.88,44.64 110.1,44.43 110.1,44.25 109.92,44.07 109.74,44.07 109.52,44.29 109.34,44.29 109.17,44.11 109.17,43.93 109.38,43.71 109.38,43.53 109.2,43.35 109.02,43.35 108.81,43.57 108.63,43.57 108.45,43.39 108.45,43.21 108.66,42.99 108.66,42.81 107.26,41.42 107.26,40.74 104,37.48 103.82,37.48 103.73,37.57 103.55,37.57 103.37,37.39 103.37,37.21 103.46,37.12 103.46,36.94 103.3,36.77 99.79,36.77 99.59,36.97 99.28,36.97 99.08,36.77 98.77,36.77 98.57,36.97 98.27,36.97 98.07,36.77 96.72,36.77 94.43,39.06 92.79,39.06 92.42,39.43 92.42,42.15 90.93,43.64 89.84,43.64 88.86,44.62 v2(88.86,45.97)
  BOTTOM w0.089: v2(88.86,45.97) 88.5,46.32 CPU1.AL58
  BOTTOM w0.114: DIMM1.149 v2(125.16,81.15)
M_A_DQ21: length 88.7
  TOP w0.114: v2(126.43,81.15) 126.43,81.29 v1(126.8,81.65)
  L3 w0.127: v2(126.43,81.15) 125.96,80.68 122.93,80.68 116.33,74.08 116.33,49.27 115.16,48.1 114.98,48.1 114.89,48.19 114.71,48.19 114.53,48.01 114.53,47.83 114.62,47.74 114.62,47.56 114.44,47.38 114.26,47.38 114.1,47.54 113.92,47.54 113.74,47.36 113.74,47.18 113.9,47.02 113.9,46.84 113.72,46.66 113.54,46.66 113.38,46.82 113.2,46.82 113.02,46.64 113.02,46.46 113.18,46.3 113.18,46.12 113,45.94 112.82,45.94 112.66,46.1 112.48,46.1 112.31,45.92 112.31,45.74 112.46,45.58 112.46,45.4 112.28,45.22 112.1,45.22 111.95,45.38 111.77,45.38 111.59,45.2 111.59,45.02 111.75,44.86 111.75,44.68 111.57,44.5 111.39,44.5 111.23,44.66 111.05,44.66 110.87,44.48 110.87,44.3 111.03,44.14 111.03,43.96 110.85,43.78 110.67,43.78 110.51,43.94 110.33,43.94 110.15,43.76 110.15,43.58 110.31,43.43 110.31,43.25 110.13,43.07 109.95,43.07 109.79,43.22 109.61,43.22 109.43,43.05 109.43,42.87 109.59,42.71 109.59,42.53 109.41,42.35 109.23,42.35 109.07,42.51 108.89,42.51 108.71,42.33 108.71,42.15 108.87,41.99 108.87,41.81 108.69,41.63 108.51,41.63 108.35,41.79 108.17,41.79 107.99,41.61 107.99,41.43 108.15,41.27 108.15,41.09 103.45,36.39 96.54,36.39 94.29,38.64 91.99,38.64 91.51,39.12 91.51,42.19 91.5,42.19 91.5,42.51 90.77,43.25 89.67,43.25 88.21,44.71 v2(88.21,45.95)
  BOTTOM w0.089: CPU1.AK58 87.85,46.3 v2(88.21,45.95)
  BOTTOM w0.114: DIMM1.147 126,80.55 126.43,80.98 v2(126.43,81.15)
M_A_DQ22: length 86.1
  TOP w0.114: v1(129.29,85) 129.17,84.87 v2(129.17,84.45)
  L3 w0.127: v2(91.46,46.88) 91.93,46.88 93.73,45.08 93.73,43.77 94.59,42.91 94.59,41.83 97.23,39.19 101.35,39.19 113.31,51.14 113.31,51.91 113.18,52.04 112.93,52.04 112.8,52.16 112.8,52.42 112.93,52.55 113.18,52.55 113.31,52.67 113.31,52.93 113.18,53.05 112.93,53.05 112.8,53.18 112.8,53.43 112.93,53.56 113.18,53.56 113.31,53.69 113.31,53.94 113.18,54.07 112.93,54.07 112.8,54.2 112.8,54.45 112.93,54.58 113.18,54.58 113.31,54.7 113.31,54.96 113.18,55.09 112.93,55.09 112.8,55.21 112.8,55.47 112.93,55.59 113.18,55.59 113.31,55.72 113.31,55.97 113.18,56.1 112.93,56.1 112.8,56.23 112.8,56.48 112.93,56.61 113.18,56.61 113.31,56.74 113.31,56.99 113.18,57.12 112.93,57.12 112.8,57.24 112.8,57.5 112.93,57.63 113.18,57.63 113.31,57.75 113.31,58.01 113.18,58.13 112.93,58.13 112.8,58.26 112.8,58.51 112.93,58.64 113.18,58.64 113.31,58.77 113.31,59.02 113.18,59.15 112.93,59.15 112.8,59.28 112.8,59.53 112.93,59.66 113.18,59.66 113.31,59.78 113.31,60.04 113.18,60.17 112.93,60.17 112.8,60.29 112.8,60.55 112.93,60.67 113.18,60.67 113.31,60.8 113.31,61.05 113.18,61.18 112.95,61.18 112.83,61.31 112.83,61.56 112.95,61.69 113.18,61.69 113.31,61.82 113.31,74.56 122.53,83.79 128.51,83.79 v2(129.17,84.45)
  BOTTOM w0.089: v2(91.46,46.88) 91.46,46.89 91.1,47.24 CPU1.AR57
  BOTTOM w0.114: DIMM1.158 129.69,83.85 129.17,84.38 v2(129.17,84.45)
M_A_DQ23: length 87.6
  TOP w0.114: v2(130.44,84.45) 130.44,84.74 v1(130.68,84.98)
  L3 w0.127: v2(90.14,46.86) 90.14,46.88 90.59,47.33 92.14,47.33 92.52,46.95 92.7,46.95 92.96,47.21 93.14,47.21 93.32,47.03 93.32,46.85 93.06,46.59 93.06,46.41 93.24,46.23 93.42,46.23 93.68,46.49 93.86,46.49 94.04,46.31 94.04,46.13 93.78,45.87 93.78,45.69 94.19,45.28 94.19,43.87 94.98,43.08 94.98,41.99 97.41,39.57 101.19,39.57 112.42,50.79 112.42,65.83 112.55,65.96 112.55,66.39 112.42,66.51 112.42,66.84 112.55,66.97 112.8,66.97 112.93,67.1 112.93,67.35 112.8,67.48 112.55,67.48 112.42,67.61 112.42,67.86 112.55,67.99 112.8,67.99 112.93,68.11 112.93,68.37 112.8,68.5 112.55,68.5 112.42,68.62 112.42,68.88 112.55,69 112.8,69 112.93,69.13 112.93,69.38 112.8,69.51 112.55,69.51 112.42,69.64 112.42,69.89 112.55,70.02 112.8,70.02 112.93,70.15 112.93,70.4 112.8,70.53 112.55,70.53 112.42,70.65 112.42,70.91 112.55,71.04 112.8,71.04 112.93,71.16 112.93,71.42 112.8,71.54 112.55,71.54 112.42,71.67 112.42,71.92 112.55,72.05 112.8,72.05 112.93,72.18 112.93,72.43 112.8,72.56 112.55,72.56 112.42,72.69 112.42,72.94 112.55,73.07 112.8,73.07 112.93,73.19 112.93,73.45 112.8,73.58 112.55,73.58 112.42,73.7 112.42,74.23 122.39,84.2 127.65,84.2 128.35,84.89 130,84.89 v2(130.44,84.45)
  BOTTOM w0.089: CPU1.AN57 89.8,47.23 90.14,46.89 v2(90.14,46.86)
  BOTTOM w0.114: DIMM1.160 v2(130.44,84.45)
M_A_DQ24: length 50.8
  TOP w0.114: v1(130.58,40.66) 130.53,40.71 130.53,41.16 v2(130.44,41.25)
  L4 w0.127: v2(130.44,41.25) 130,40.8 127.59,40.8 127.23,41.17 123.91,41.17 119.62,36.87 99.01,36.87 92.23,43.65 92.23,45.08 91.9,45.41 91.9,47.1 91.66,47.34 91.22,47.34 v2(90.77,47.78)
  BOTTOM w0.089: v2(90.77,47.78) 90.77,47.78 90.77,47.94 90.45,48.25 CPU1.AP55
  BOTTOM w0.114: DIMM1.24 130.44,41.25 v2(130.44,41.25)
M_A_DQ25: length 50.3
  TOP w0.114: v1(128.8,40.71) 128.8,40.88 v2(129.17,41.25)
  L4 w0.127: v2(91.41,47.78) 91.41,47.78 91.63,47.78 92.28,47.13 92.28,45.57 92.61,45.24 92.61,43.81 99.17,37.26 119.46,37.26 123.77,41.56 126.02,41.56 126.21,41.75 128.67,41.75 v2(129.17,41.25)
  BOTTOM w0.089: v2(91.41,47.78) 91.41,47.79 91.41,47.88 91.1,48.19 CPU1.AR55
  BOTTOM w0.114: v2(129.17,41.25) 129.17,41.13 129.65,40.65 DIMM1.22
M_A_DQ26: length 53.4
  TOP w0.114: v2(129.17,44.25) 129.17,44.38 v1(128.75,44.8)
  L4 w0.089: 96.25,43.11 96.25,43.57 96.47,43.8 96.47,44.52 94.16,46.83 94.16,47.46 92.13,49.49 90.52,49.49 90.26,49.23 89.9,49.23 v2(89.48,48.81)
  L4 w0.127: v2(129.17,44.25) 129.17,43.57 128.93,43.33 128.07,43.33 127.74,43.66 127.74,44.54 127.49,44.79 124.81,44.79 123.63,43.6 122.77,43.6 119.33,40.16 99.19,40.16 96.25,43.11
  BOTTOM w0.089: CPU1.AM54 89.15,49.14 v2(89.48,48.81)
  BOTTOM w0.114: DIMM1.36 129.71,44.85 129.17,44.31 v2(129.17,44.25)
M_A_DQ27: length 54.5
  TOP w0.114: v2(130.44,44.25) 130.44,44.71 v1(130.56,44.82)
  L4 w0.089: v2(88.18,48.76) 87.6,49.34 87.6,49.9 87.81,50.11 90.27,50.11 90.63,49.75 92.2,49.75 94.41,47.54 94.41,46.88 94.89,46.4 95.33,46.4
  L4 w0.127: v2(130.44,44.25) 129.51,45.18 124.65,45.18 123.45,43.98 122.61,43.98 119.18,40.56 99.57,40.56 99.01,41.12 99.01,41.72 97.29,43.44 97.29,44.44 95.33,46.4
  BOTTOM w0.089: CPU1.AK54 88.18,48.88 v2(88.18,48.76)
  BOTTOM w0.114: DIMM1.34 v2(130.44,44.25)
M_A_DQ28: length 53.7
  TOP w0.114: v2(88.83,47.86) 89.32,48.35 v1(89.79,48.35)
  L4 w0.127: v2(88.83,47.86) 88.28,47.31 87.91,47.31 87.63,47.03 87.63,45.56 88.85,44.34 91.16,44.34 91.29,44.22 91.29,43.96 91.16,43.84 90.91,43.84 90.78,43.71 90.78,43.46 90.91,43.33 92.02,43.33 98.85,36.49 119.78,36.49 124.06,40.77 125.99,40.77 v2(126.43,40.33)
  BOTTOM w0.089: CPU1.AL55 88.5,48.19 v2(88.83,47.86)
  BOTTOM w0.114: DIMM1.23 126.11,40.95 126.43,40.63 v2(126.43,40.33)
M_A_DQ29: length 53.9
  TOP w0.114: v2(125.16,40.33) v1(124.56,40.33)
  L4 w0.127: v2(125.16,40.33) 124.15,40.33 119.94,36.11 98.48,36.11 91.74,42.85 88.29,42.85 88.16,42.98 88.16,43.23 88.29,43.36 89.84,43.36 89.97,43.49 89.97,43.74 89.84,43.87 88.28,43.87 86.61,45.54 86.61,46.7 87.72,47.81 v2(88.18,47.81)
  BOTTOM w0.089: CPU1.AK55 87.85,48.14 v2(88.18,47.81)
  BOTTOM w0.114: DIMM1.21 125.14,40.35 v2(125.16,40.33)
M_A_DQ30: length 51.3
  TOP w0.114: v1(124.56,43.95) v2(125.16,43.95)
  L4 w0.091: 94.66,43.58 94.17,44.07 94.17,45.47 93.55,46.09 93.55,47.28 92,48.83 v2(91.48,48.83)
  L4 w0.127: 94.66,43.58 99.12,39.12 109.3,39.12 109.88,38.54 110.25,38.54 110.37,38.66 110.37,39.01 110.5,39.13 110.75,39.13 110.88,39.01 110.88,38.66 111.01,38.54 111.26,38.54 111.39,38.66 111.39,39.01 111.52,39.13 111.77,39.13 111.9,39.01 111.9,38.66 112.02,38.54 112.28,38.54 112.41,38.66 112.41,39.01 112.53,39.13 112.79,39.13 112.91,39.01 112.91,38.66 113.04,38.54 113.29,38.54 113.42,38.66 113.42,39.01 113.55,39.13 113.8,39.13 113.93,39.01 113.93,38.66 114.06,38.54 114.31,38.54 114.44,38.66 114.44,39.01 114.56,39.13 114.82,39.13 114.95,39.01 114.95,38.66 115.07,38.54 115.33,38.54 115.45,38.66 115.45,39.01 115.58,39.13 115.83,39.13 115.96,39.01 115.96,38.66 116.09,38.54 116.34,38.54 116.47,38.66 116.47,39.01 116.6,39.13 116.85,39.13 116.98,39.01 116.98,38.66 117.1,38.54 117.47,38.54 117.6,38.66 117.6,38.78 117.73,38.91 117.99,38.91 118.12,38.78 118.12,38.66 118.25,38.54 118.78,38.54 123.09,42.84 124.64,42.84 125.16,43.37 v2(125.16,43.95)
  BOTTOM w0.089: v2(91.48,48.83) 91.1,49.2 CPU1.AR54
  BOTTOM w0.114: v2(125.16,43.95) DIMM1.33
M_A_DQ31: length 52.9
  TOP w0.114: v1(126.8,44.49) 126.8,44.32 v2(126.43,43.95)
  L4 w0.089: v2(90.13,48.81) 90.17,48.81 90.62,49.27 91.97,49.27 93.83,47.41 93.83,46.25 94.42,45.65 94.42,44.38 94.98,43.82
  L4 w0.127: v2(126.43,43.95) 126.21,44.17 126.21,44.17 125.98,44.39 124.98,44.39 124.64,44.06 124.64,43.4 124.46,43.22 122.93,43.22 119.49,39.78 118.5,39.78 118.38,39.65 118.38,39.41 118.25,39.29 118,39.29 117.87,39.41 117.87,39.65 117.74,39.78 117.36,39.78 117.09,39.51 116.7,39.51 116.47,39.74 116.19,39.74 115.96,39.51 115.68,39.51 115.45,39.74 115.17,39.74 114.95,39.51 114.67,39.51 114.44,39.74 114.16,39.74 113.93,39.51 113.65,39.51 113.42,39.74 113.14,39.74 112.91,39.51 112.63,39.51 112.41,39.74 112.13,39.74 111.9,39.51 111.62,39.51 111.39,39.74 111.11,39.74 110.88,39.51 110.6,39.51 110.37,39.74 110.11,39.74 109.86,39.49 109.6,39.49 109.35,39.74 109.08,39.74 108.85,39.51 108.57,39.51 108.34,39.74 108.06,39.74 107.83,39.51 107.55,39.51 107.33,39.74 107.05,39.74 106.82,39.51 106.54,39.51 106.31,39.74 106.03,39.74 105.8,39.51 105.52,39.51 105.29,39.74 105.01,39.74 104.79,39.51 104.51,39.51 104.28,39.74 104,39.74 103.77,39.51 103.49,39.51 103.26,39.74 102.98,39.74 102.75,39.51 102.47,39.51 102.25,39.74 101.97,39.74 101.74,39.51 101.46,39.51 101.23,39.74 100.95,39.74 100.72,39.51 100.44,39.51 100.21,39.74 99.93,39.74 99.71,39.51 99.28,39.51 94.98,43.82
  BOTTOM w0.089: CPU1.AN54 89.82,49.23 90.03,49.23 90.13,49.13 v2(90.13,48.81)
  BOTTOM w0.114: DIMM1.35 125.91,44.55 126.43,44.02 v2(126.43,43.95)
M_A_DQ32: length 76.3
  TOP w0.114: v1(130.16,87.34) 130.16,87.21 v2(129.8,86.85)
  L3 w0.127: v2(129.8,86.85) 128.97,86.01 121.97,86.01 111,75.04 111,65.32 110.87,65.2 110.64,65.2 110.52,65.07 110.52,64.82 110.64,64.69 110.87,64.69 111,64.56 111,64.31 110.87,64.18 110.53,64.18 110.41,64.05 110.41,63.8 110.53,63.67 110.87,63.67 111,63.55 111,63.1 110.41,62.51 110.41,50.8 100.65,41.05 98.21,41.05 96.23,43.03 96.23,43.81 v2(96.04,43.99)
  BOTTOM w0.089: v2(96.04,43.99) 96.04,44.6 95.83,44.81 95.83,45.4 95.09,46.14 94.54,46.14 94.46,46.23 94.36,46.23 CPU1.AY58
  BOTTOM w0.114: DIMM1.166 130.4,86.25 129.99,86.66 129.99,86.67 v2(129.8,86.85)
M_A_DQ33: length 77.1
  TOP w0.114: v1(127.62,84.75) 127.56,84.75 127.56,84.75 127.07,84.75 v2(127.07,84.75)
  L3 w0.127: v2(95.58,44.43) 95.58,43.8 95.83,43.56 95.83,42.87 98.04,40.66 100.8,40.66 110.79,50.65 110.79,57.98 111.38,58.57 111.38,59.13 111.25,59.26 110.92,59.26 110.79,59.39 110.79,59.64 110.92,59.77 111.25,59.77 111.38,59.9 111.38,60.15 111.25,60.28 110.92,60.28 110.79,60.4 110.79,60.66 110.92,60.78 111.25,60.78 111.38,60.91 111.38,61.17 111.25,61.29 110.97,61.29 110.85,61.42 110.85,61.67 110.97,61.8 111.25,61.8 111.38,61.93 111.38,62.28 111.25,62.41 111.25,62.82 111.38,62.94 111.38,74.88 122.12,85.62 126.2,85.62 v2(127.07,84.75)
  BOTTOM w0.089: v2(95.58,44.43) 95.58,45.4 95.02,45.96 94.48,45.96 94.39,46.05 93.89,46.05 CPU1.AW58
  BOTTOM w0.114: DIMM1.165 125.87,85.95 126.88,84.94 126.88,84.93 v2(127.07,84.75)
M_A_DQ34: length 76.7
  TOP w0.114: v2(125.16,88.95) v1(124.6,88.95)
  L3 w0.127: v2(96.23,46.51) 98.18,46.51 98.7,47.03 101.66,47.03 103.23,48.6 103.23,48.78 102.72,49.29 102.72,49.47 102.9,49.65 103.08,49.65 103.59,49.14 103.77,49.14 103.94,49.32 103.94,49.5 103.44,50.01 103.44,50.19 103.62,50.37 103.8,50.37 104.3,49.86 104.48,49.86 104.66,50.04 104.66,50.22 104.16,50.73 104.16,50.91 104.34,51.09 104.52,51.09 105.02,50.58 105.2,50.58 105.38,50.76 105.38,50.94 104.88,51.45 104.88,51.63 105.06,51.81 105.24,51.81 105.74,51.3 105.92,51.3 106.1,51.48 106.1,51.66 105.6,52.16 105.6,52.34 105.78,52.52 105.96,52.52 106.46,52.02 106.64,52.02 106.82,52.2 106.82,52.38 106.31,52.88 106.31,53.06 106.49,53.24 107.18,53.24 107.65,53.71 107.65,73.38 107.74,73.48 108.46,73.48 108.57,73.59 108.57,73.87 108.46,73.98 107.74,73.98 107.65,74.08 107.65,74.4 107.74,74.49 108.43,74.49 108.56,74.62 108.56,74.87 108.43,75 107.74,75 107.65,75.09 107.65,75.49 120.69,88.53 124.05,88.53 124.47,88.95 v2(125.16,88.95)
  BOTTOM w0.089: v2(96.23,46.51) 96.23,47.03 95.92,47.34 95.65,47.34 95.25,47.74 94.23,47.74 CPU1.AY56
  BOTTOM w0.114: DIMM1.175 v2(125.16,88.95)
M_A_DQ35: length 77.6
  TOP w0.114: v1(130.75,89.12) 130.75,88.96 v2(130.44,88.65)
  L3 w0.127: v2(130.44,88.65) 129.89,89.2 128.14,89.2 127.23,88.29 124.37,88.29 124.21,88.14 120.96,88.14 108.95,76.12 108.95,72.41 108.83,72.29 108.18,72.29 108.05,72.16 108.05,71.91 108.18,71.78 108.83,71.78 108.95,71.65 108.95,71.27 108.84,71.16 108.15,71.16 108.03,71.03 108.03,70.78 108.15,70.65 108.83,70.65 108.95,70.52 108.95,70.27 108.83,70.14 108.37,70.14 108.03,69.8 108.03,67.76 108.19,67.6 108.83,67.6 108.95,67.47 108.95,67.22 108.83,67.09 108.37,67.09 108.24,66.97 108.24,53.08 102.63,47.47 102.63,45.93 102.28,45.58 97.11,45.58 v2(97.09,45.57)
  BOTTOM w0.089: CPU1.AW56 93.84,48 94.37,48 94.45,47.92 95.33,47.92 95.72,47.52 96,47.52 97.09,46.42 v2(97.09,45.57)
  BOTTOM w0.114: v2(130.44,88.65) DIMM1.174
M_A_DQ36: length 77.4
  TOP w0.114: v1(126.14,85.23) 125.8,84.88 v2(125.8,84.75)
  L3 w0.127: v2(95.11,44.88) 95.11,43.72 95.43,43.39 95.43,42.58 97.74,40.28 100.96,40.28 111.76,51.08 111.76,51.52 111.63,51.65 111.43,51.65 111.3,51.78 111.3,52.03 111.43,52.16 111.63,52.16 111.76,52.29 111.76,52.54 111.63,52.67 111.3,52.67 111.17,52.79 111.17,53.05 111.3,53.17 111.63,53.17 111.76,53.3 111.76,53.56 111.63,53.68 111.3,53.68 111.17,53.81 111.17,54.06 111.3,54.19 111.63,54.19 111.76,54.32 111.76,54.57 111.63,54.7 111.3,54.7 111.17,54.83 111.17,55.08 111.3,55.21 111.63,55.21 111.76,55.33 111.76,55.59 111.63,55.71 111.3,55.71 111.17,55.84 111.17,56.1 111.3,56.22 111.63,56.22 111.76,56.35 111.76,56.6 111.63,56.73 111.3,56.73 111.17,56.86 111.17,57.11 111.3,57.24 111.63,57.24 111.76,57.37 111.76,57.62 111.63,57.75 111.63,58.13 111.76,58.25 111.76,74.72 122.26,85.22 125.32,85.22 v2(125.8,84.75)
  BOTTOM w0.089: CPU1.AV58 93.12,46.38 93.73,45.76 93.73,45.72 94.06,45.4 94.41,45.4 94.93,44.88 v2(95.11,44.88)
  BOTTOM w0.114: v2(125.8,84.75) 125.8,84.82 125.27,85.35 DIMM1.163
M_A_DQ37: length 78.5
  TOP w0.114: v2(128.53,86.85) v1(128.53,86.28)
  L3 w0.127: v2(98.46,41.58) 98.56,41.48 100.54,41.48 110.03,50.96 110.03,65.16 110.62,65.75 110.62,75.19 121.83,86.41 128.09,86.41 v2(128.53,86.85)
  BOTTOM w0.089: v2(98.46,41.58) 98.88,42 98.88,42.89 96.56,45.21 96.56,45.46 95.31,46.71 95.31,47.14 95.07,47.38 94.56,47.38 94.46,47.28 94.09,47.28 94,47.32 93.94,47.34 93.83,47.34 93.67,47.26 93.47,47.26 93.34,47.32 93.29,47.34 93.18,47.34 93.17,47.34 92.69,47.34 92.67,47.35 92.46,47.35 92.26,47.15 CPU1.AU58
  BOTTOM w0.114: DIMM1.164 129.66,85.65 128.53,86.78 v2(128.53,86.85)
M_A_DQ38: length 78.6
  TOP w0.114: v2(126.43,88.95) 126.43,89.08 v1(126.79,89.44)
  L3 w0.127: v2(95.74,46.92) 95.82,47 98.12,47 99,47.88 100.59,47.88 101.54,48.83 101.54,49.01 101.34,49.21 101.34,49.39 101.52,49.57 101.7,49.57 101.9,49.37 102.08,49.37 103.42,50.71 103.42,50.89 102.79,51.52 102.79,51.7 102.97,51.88 103.15,51.88 103.78,51.25 103.96,51.25 104.14,51.43 104.14,51.61 103.51,52.24 103.51,52.42 103.69,52.6 103.87,52.6 104.5,51.97 104.68,51.97 104.86,52.15 104.86,52.33 104.23,52.96 104.23,53.14 104.41,53.32 104.59,53.32 105.22,52.69 105.4,52.69 105.58,52.87 105.58,53.05 104.95,53.68 104.95,53.86 105.13,54.04 105.31,54.04 105.94,53.41 106.12,53.41 106.3,53.59 106.3,53.77 105.67,54.4 105.67,54.58 105.85,54.76 106.03,54.76 106.66,54.13 106.84,54.13 107.26,54.55 107.26,75.7 120.49,88.92 123.88,88.92 124.42,89.46 125.92,89.46 v2(126.43,88.95)
  BOTTOM w0.089: v2(95.74,46.92) 95.74,46.99 95.17,47.56 94.48,47.56 94.37,47.45 94.13,47.45 93.98,47.52 93.79,47.52 93.63,47.44 93.51,47.44 93.41,47.48 93.33,47.52 CPU1.AV56
  BOTTOM w0.114: v2(126.43,88.95) 126.43,89.02 125.91,89.55 DIMM1.177
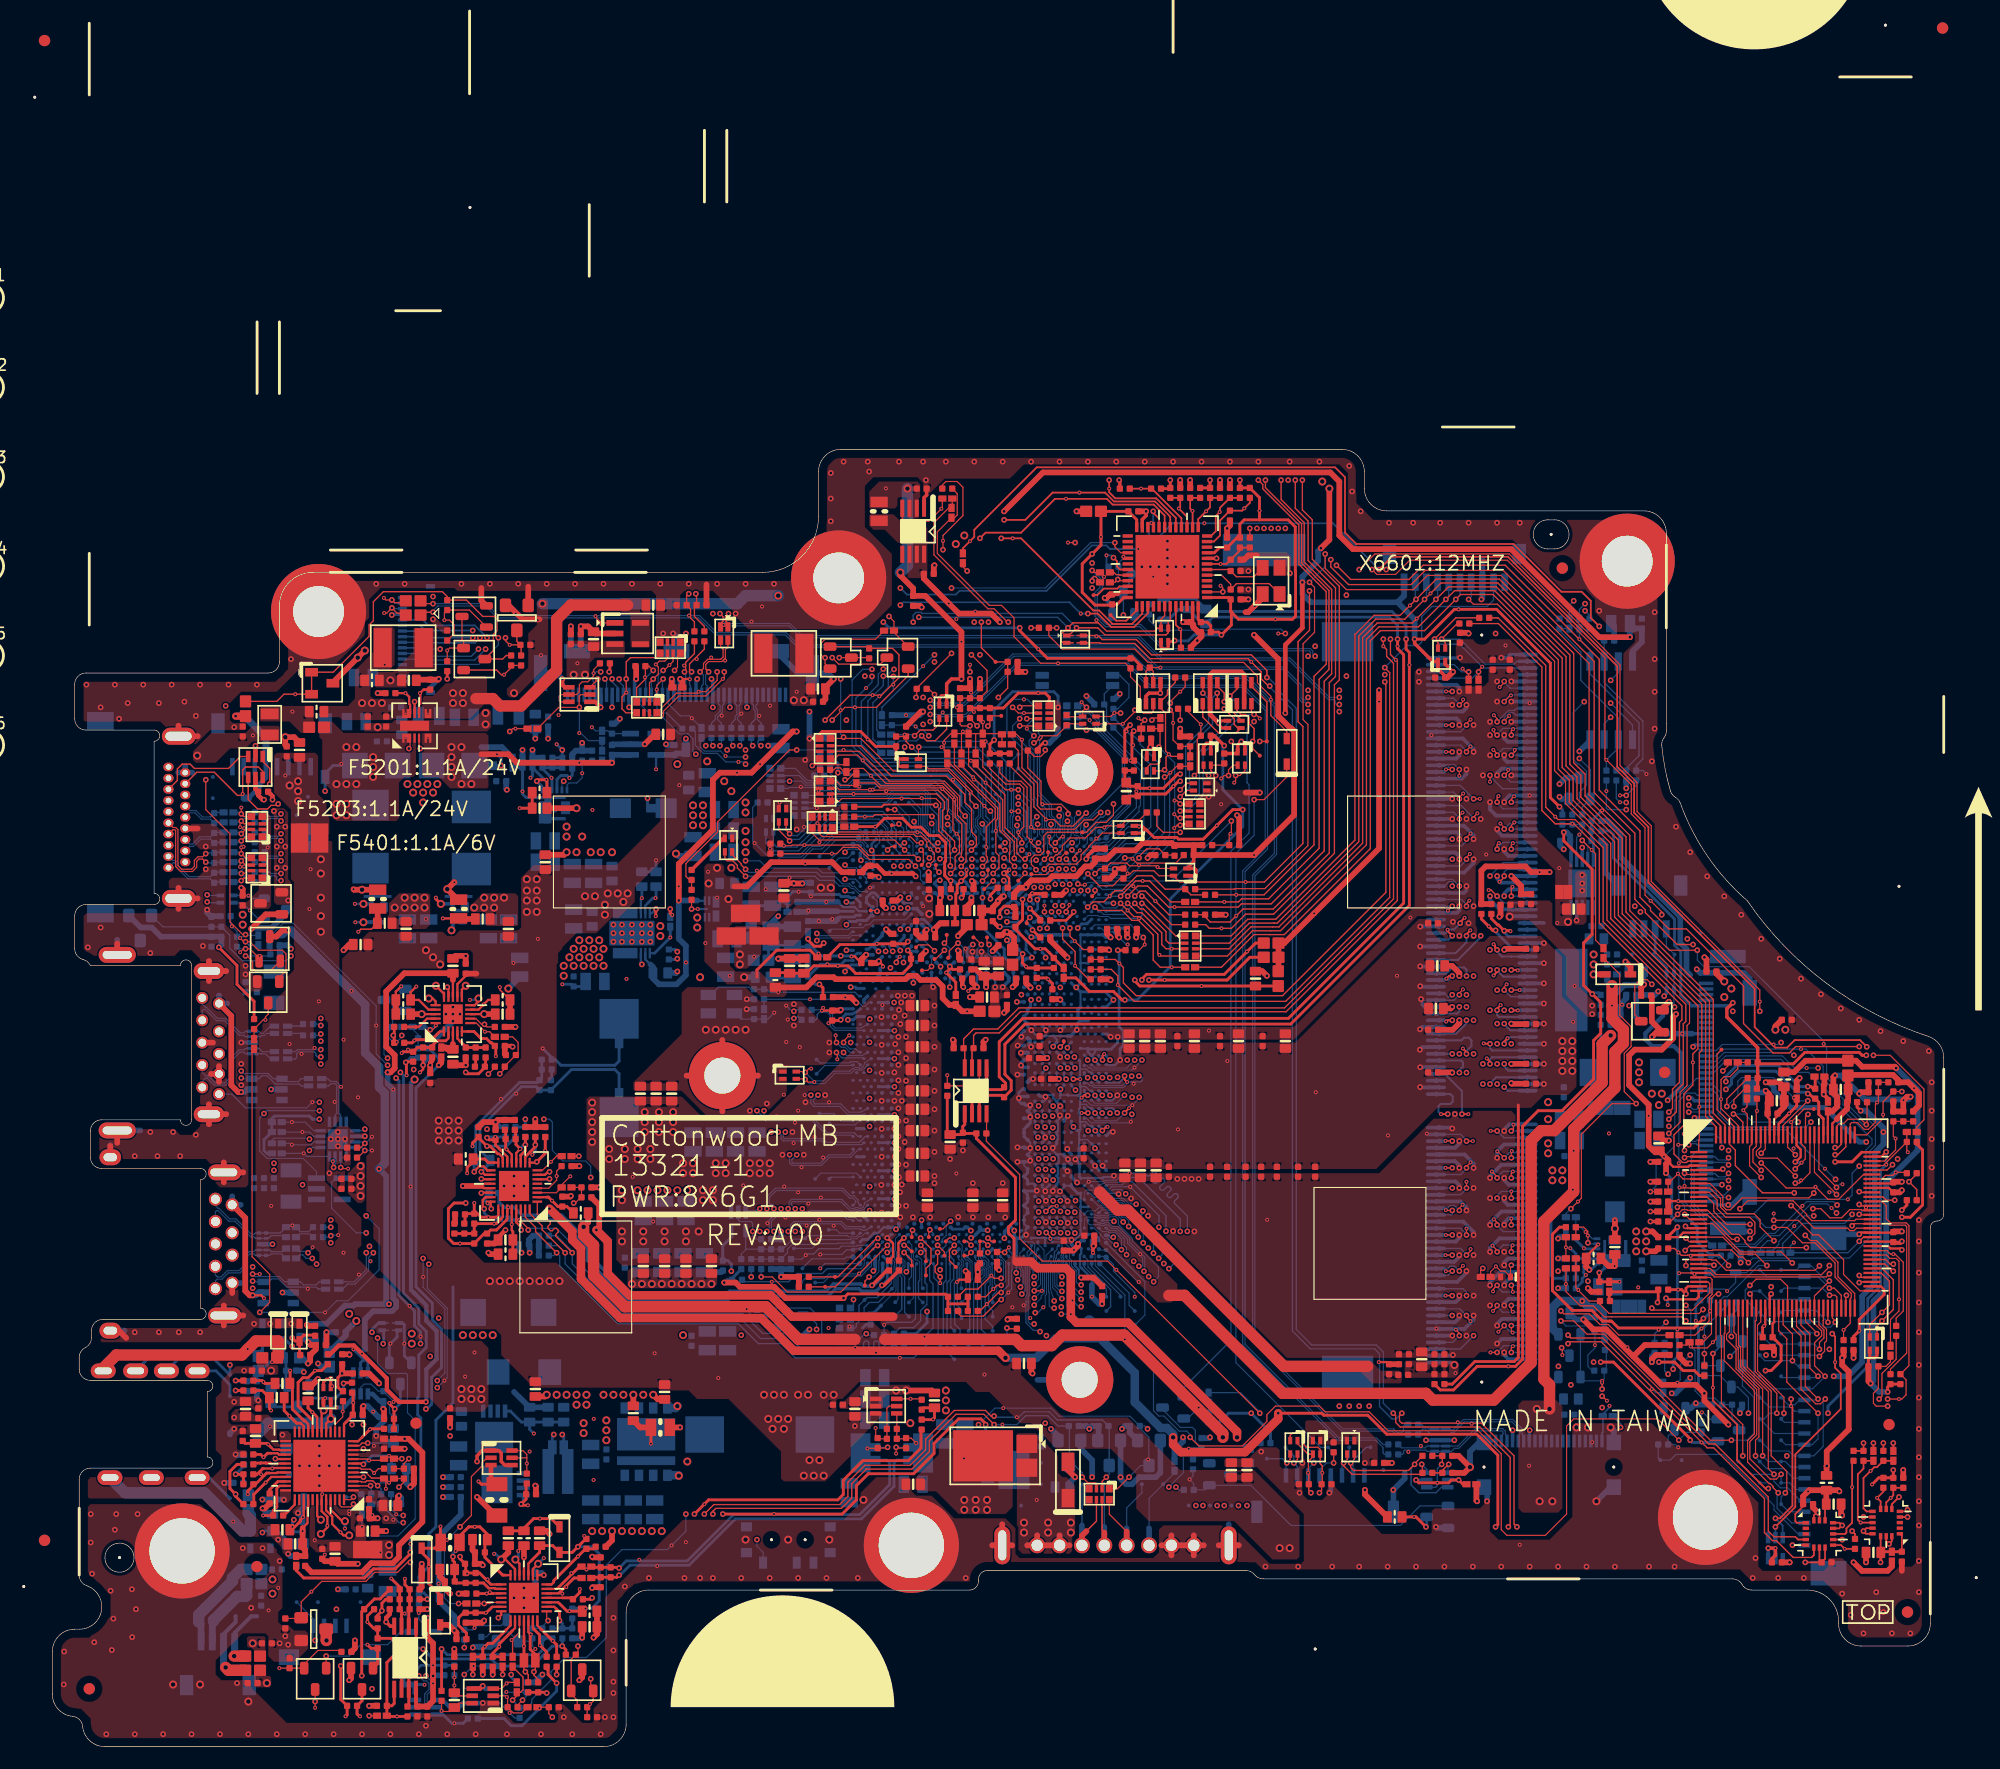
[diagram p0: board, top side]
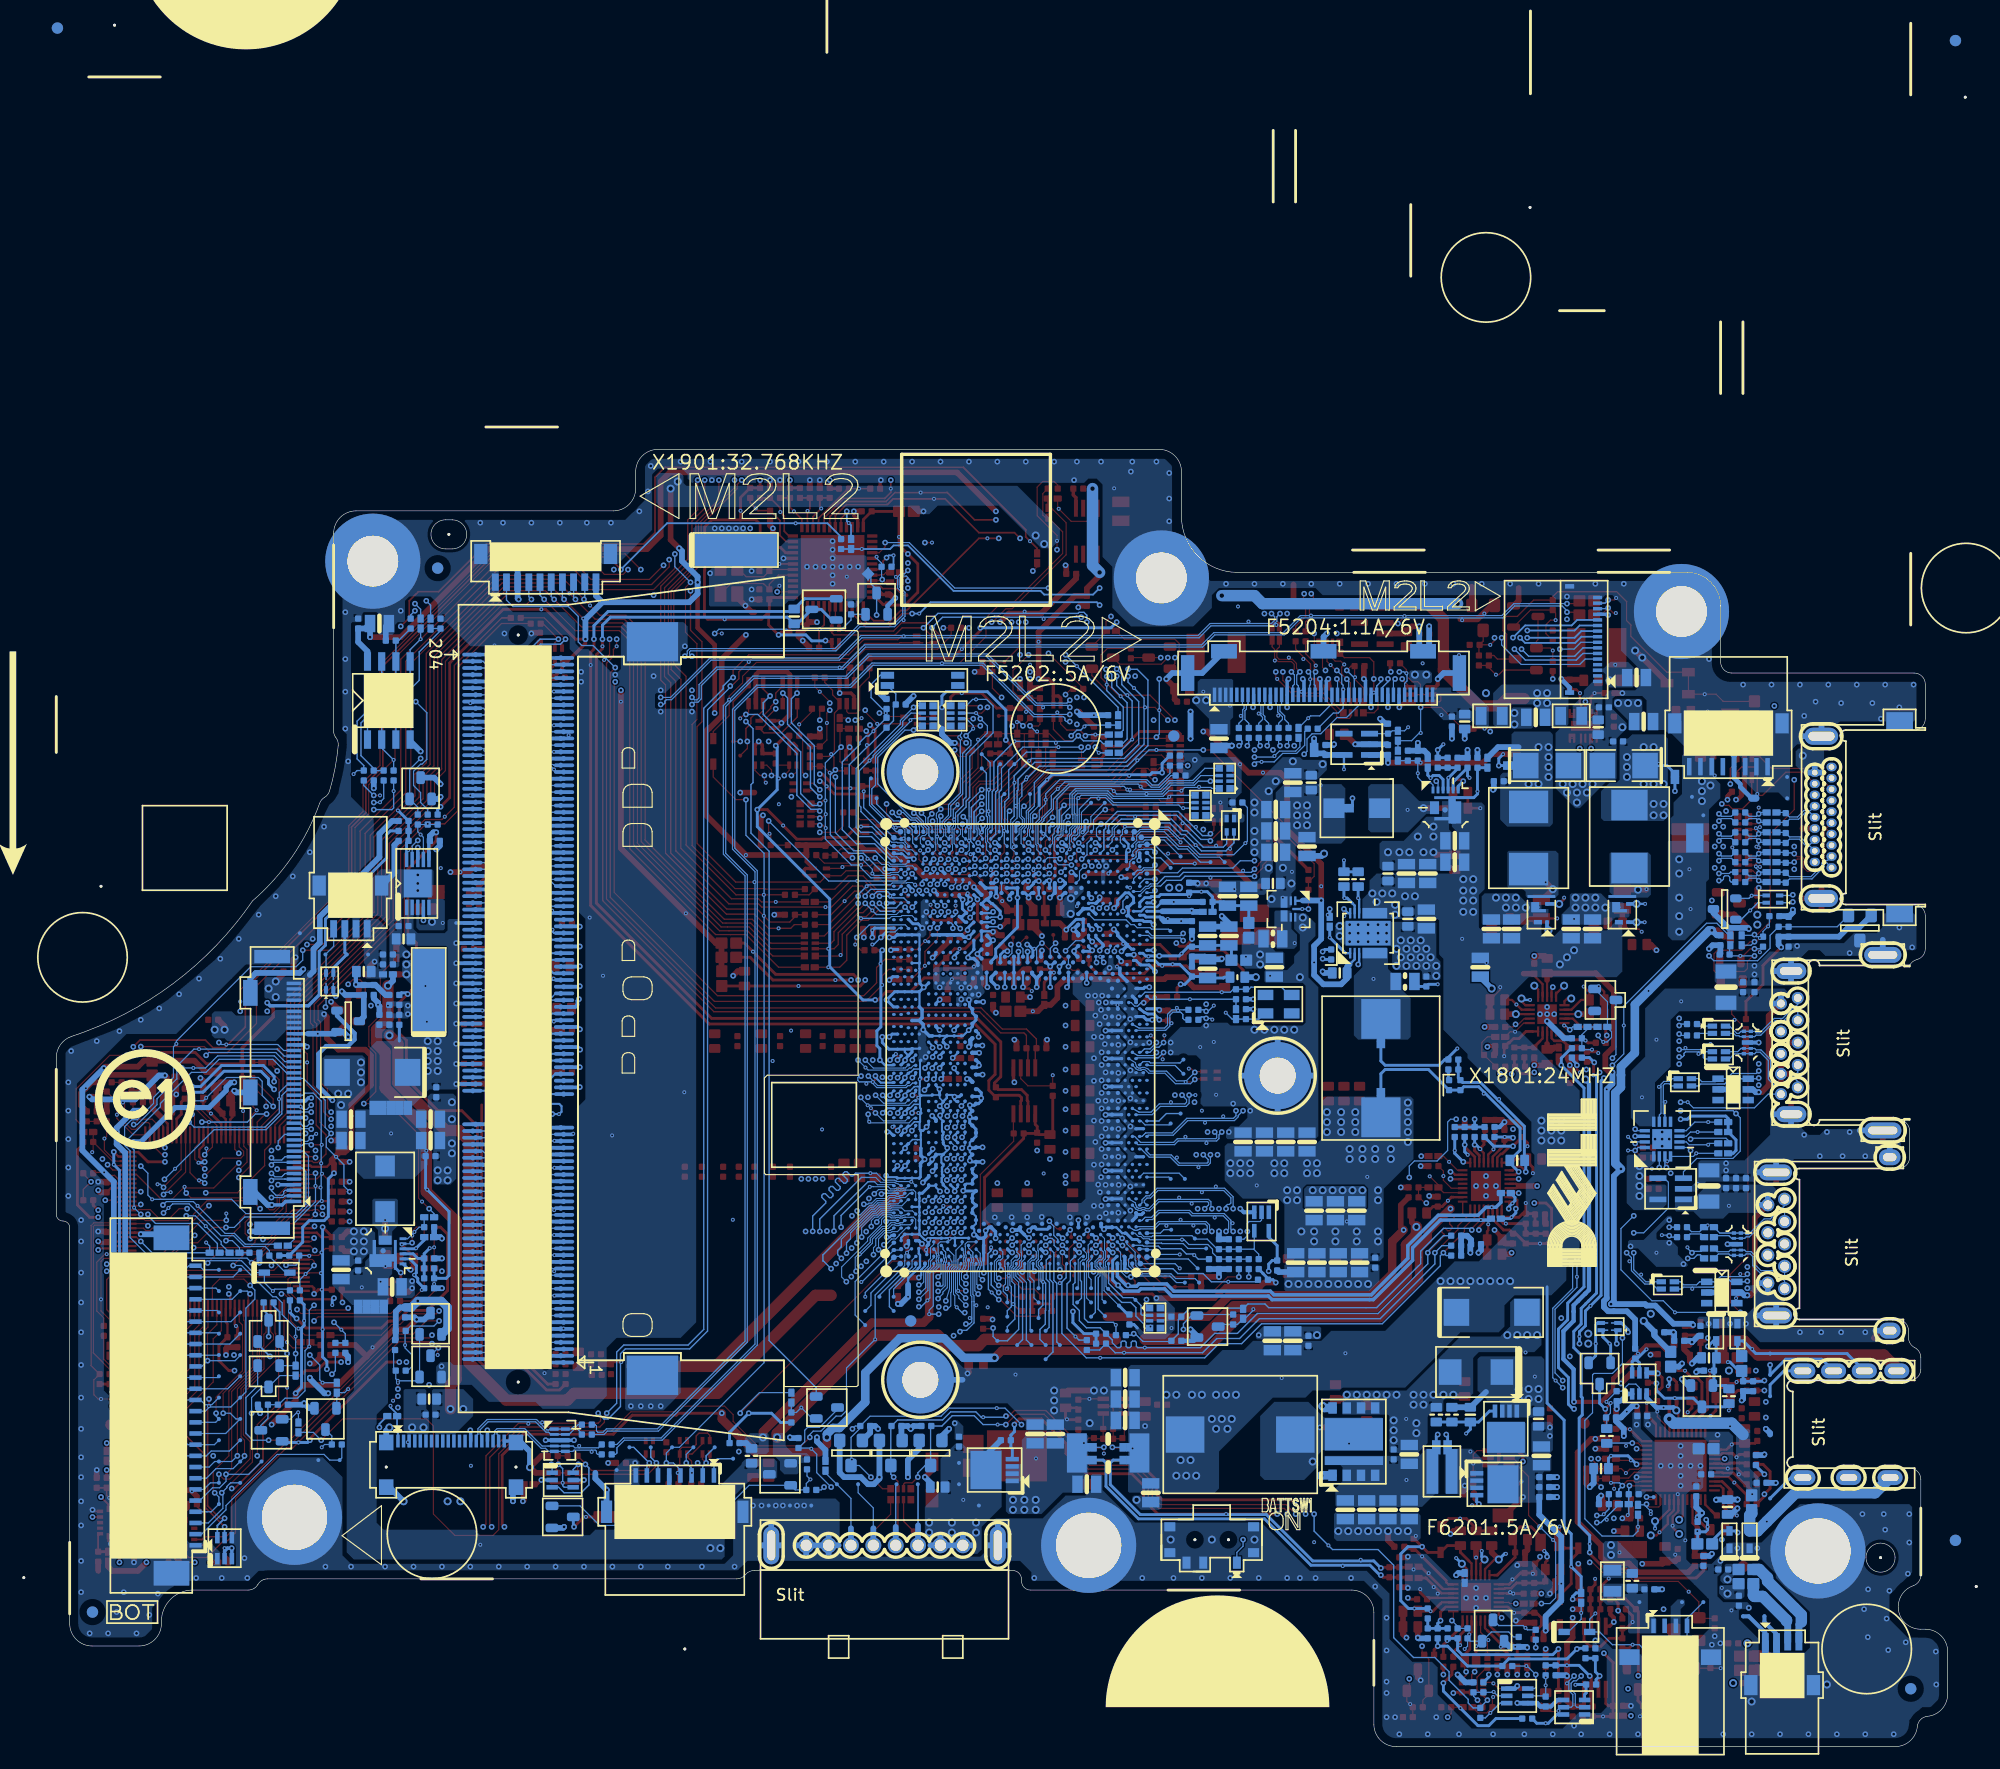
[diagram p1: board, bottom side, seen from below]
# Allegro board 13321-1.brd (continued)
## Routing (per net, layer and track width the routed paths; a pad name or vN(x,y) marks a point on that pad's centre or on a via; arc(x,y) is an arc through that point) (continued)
M_A_DQ39: length 79.5
  TOP w0.114: v1(128.83,89.12) 129.17,88.79 v2(129.17,88.65)
  L3 w0.127: v2(97.53,45.04) 98.96,45.04 99.11,44.89 99.11,44.57 99.24,44.44 99.5,44.44 99.62,44.57 99.62,44.89 99.78,45.04 102.28,45.04 103.05,45.81 103.05,47.35 106.71,51.01 106.89,51.01 107.49,50.42 107.67,50.42 107.84,50.6 107.84,50.78 107.25,51.37 107.25,51.55 107.43,51.73 107.61,51.73 108.2,51.14 108.38,51.14 108.56,51.31 108.56,51.49 107.97,52.09 107.97,52.27 108.67,52.97 108.67,65.65 109.33,66.31 109.33,75.73 121.3,87.69 124.4,87.69 124.61,87.9 128.73,87.9 129.17,88.34 v2(129.17,88.65)
  BOTTOM w0.089: v2(97.53,45.04) 97.53,46.24 96.07,47.7 95.8,47.7 95.4,48.09 94.52,48.09 94.44,48.18 93.52,48.18 93.25,47.91 92.55,47.91 CPU1.AU56
  BOTTOM w0.114: v2(129.17,88.65) 129.17,88.72 129.7,89.25 DIMM1.176
M_A_DQ40: length 45.2
  TOP w0.114: v2(130.44,46.65) v1(130.44,47.21)
  L4 w0.127: v2(130.44,46.65) 129.93,46.14 128.16,46.14 127.71,46.59 123.79,46.59 122.67,45.46 122.09,45.46 119.11,42.49 114.47,42.49 114.34,42.36 114.34,42.23 114.21,42.11 113.96,42.11 113.83,42.23 113.83,42.36 113.7,42.49 100.08,42.49 v2(99.83,42.74)
  BOTTOM w0.089: CPU1.AY54 94.56,48.81 94.74,48.63 95.64,48.63 96.04,48.23 96.29,48.23 99.14,45.38
  BOTTOM w0.114: 99.14,45.38 100.56,43.96 100.56,43.43 100.51,43.43 v2(99.83,42.74) ; DIMM1.42 v2(130.44,46.65)
M_A_DQ41: length 46
  TOP w0.114: v2(126.43,45.75) v1(126.43,46.32)
  L4 w0.127: v2(98.91,43.66) 98.91,43.03 99.83,42.11 108.8,42.11 108.93,41.98 108.93,41.73 109.06,41.6 109.31,41.6 109.44,41.73 109.44,41.98 109.56,42.11 109.82,42.11 109.94,41.98 109.94,41.73 110.07,41.6 110.33,41.6 110.45,41.73 110.45,41.98 110.58,42.11 110.83,42.11 110.96,41.98 110.96,41.73 111.09,41.6 111.34,41.6 111.47,41.73 111.47,41.98 111.6,42.11 111.85,42.11 111.98,41.98 111.98,41.8 112.1,41.67 112.36,41.67 112.48,41.8 112.48,41.98 112.61,42.11 112.9,42.11 113.03,41.98 113.03,41.8 113.23,41.6 118.76,41.6 122.24,45.07 122.81,45.07 123.94,46.19 125.99,46.19 v2(126.43,45.75)
  BOTTOM w0.089: CPU1.AW54 93.84,48.53 94.59,48.53 94.67,48.45 95.57,48.45 95.96,48.05 96.22,48.05 98.91,45.36 98.91,45.21
  BOTTOM w0.114: 98.91,45.21 98.91,44.7 99.24,44.37 99.24,43.99 v2(98.91,43.66) ; v2(126.43,45.75) 126.43,45.82 125.9,46.35 DIMM1.41
M_A_DQ42: length 45.7
  TOP w0.114: v2(130.44,49.05) v1(130.44,49.65)
  L4 w0.127: v2(130.44,49.05) 130,49.49 128.17,49.49 127.93,49.25 127.93,48.85 128.21,48.57 128.21,48.16 128.04,48 127.56,48 126.65,48.91 124.71,48.91 124.46,48.66 121.43,48.66 117.3,44.53 113.8,44.53 113.47,44.85 100.81,44.85 v2(99.57,46.09)
  BOTTOM w0.089: CPU1.AY52 94.3,50.25 95.68,50.25 95.95,50.51
  BOTTOM w0.114: DIMM1.50 v2(130.44,49.05) ; v2(99.57,46.09) 99.57,47.47 96.52,50.51 95.95,50.51
M_A_DQ43: length 46.5
  TOP w0.114: v2(126.43,49.95) v1(126.43,50.51)
  L4 w0.127: v2(100.84,46.07) 100.84,45.51 101.11,45.23 102.93,45.23 103.06,45.36 103.06,45.51 103.18,45.64 103.44,45.64 103.56,45.51 103.56,45.36 103.69,45.23 103.94,45.23 104.07,45.36 104.07,45.51 104.2,45.64 104.45,45.64 104.58,45.51 104.58,45.36 104.71,45.23 104.96,45.23 105.09,45.36 105.09,45.51 105.21,45.64 105.47,45.64 105.6,45.51 105.6,45.36 105.72,45.23 105.98,45.23 106.1,45.36 106.1,45.51 106.23,45.64 106.48,45.64 106.61,45.51 106.61,45.36 106.74,45.23 106.99,45.23 107.12,45.36 107.12,45.51 107.25,45.64 107.5,45.64 107.63,45.51 107.63,45.36 107.75,45.23 108.01,45.23 108.14,45.36 108.14,45.51 108.26,45.64 108.52,45.64 108.64,45.51 108.64,45.36 108.77,45.23 109.02,45.23 109.15,45.36 109.15,45.51 109.28,45.64 109.53,45.64 109.66,45.51 109.66,45.36 109.79,45.23 110.04,45.23 110.17,45.36 110.17,45.51 110.29,45.64 110.55,45.64 110.68,45.51 110.68,45.36 110.8,45.23 111.18,45.23 111.31,45.36 111.31,45.51 111.44,45.64 111.69,45.64 111.82,45.51 111.82,45.36 111.95,45.23 117.47,45.23 121.28,49.05 124.29,49.05 124.64,49.4 125.88,49.4 v2(126.43,49.95)
  BOTTOM w0.089: CPU1.AW52 93.84,50.32 94.04,50.4 94.11,50.43 94.17,50.46 95.41,50.46 95.84,50.89 96.41,50.89
  BOTTOM w0.114: v2(100.84,46.07) 100.84,47.18 97.12,50.89 96.41,50.89 ; v2(126.43,49.95) 126.43,49.88 125.91,49.35 DIMM1.51
M_A_DQ44: length 46.6
  TOP w0.114: v2(125.16,45.75) v1(124.59,45.75)
  L4 w0.127: v2(98.45,44.12) 98.45,42.95 100.18,41.22 100.57,41.22 100.69,41.34 100.69,41.6 100.82,41.73 101.07,41.73 101.2,41.6 101.2,41.34 101.33,41.22 101.58,41.22 101.71,41.34 101.71,41.6 101.84,41.73 102.09,41.73 102.22,41.6 102.22,41.34 102.34,41.22 102.6,41.22 102.72,41.34 102.72,41.6 102.85,41.73 103.11,41.73 103.23,41.6 103.23,41.34 103.36,41.22 103.61,41.22 103.74,41.34 103.74,41.6 103.87,41.73 104.12,41.73 104.25,41.6 104.25,41.34 104.38,41.22 104.63,41.22 104.76,41.34 104.76,41.6 104.88,41.73 105.14,41.73 105.26,41.6 105.26,41.34 105.39,41.22 105.65,41.22 105.77,41.34 105.77,41.6 105.9,41.73 106.15,41.73 106.28,41.6 106.28,41.34 106.41,41.22 106.66,41.22 106.79,41.34 106.79,41.6 106.92,41.73 107.17,41.73 107.3,41.6 107.3,41.34 107.42,41.22 107.68,41.22 107.8,41.34 107.8,41.6 107.93,41.73 108.19,41.73 108.31,41.6 108.31,41.34 108.44,41.22 118.92,41.22 122.38,44.68 123.09,44.68 124.16,45.75 v2(125.16,45.75)
  BOTTOM w0.089: 98.12,45.38 98.09,45.42 98.09,45.93 96.14,47.88 95.88,47.88 95.48,48.27 94.6,48.27 94.51,48.36 93.5,48.36 92.95,48.91 CPU1.AV54
  BOTTOM w0.114: 98.12,45.38 98.45,45.06 v2(98.45,44.12) ; DIMM1.39 125.16,45.75 v2(125.16,45.75)
M_A_DQ45: length 47.5
  TOP w0.114: v1(128.88,47.16) 129.17,46.87 v2(129.17,46.65)
  L4 w0.089: v2(95.96,49.43) 95.96,49.43 95.96,47.39 97.52,45.83 97.52,45.69 100.02,43.2
  L4 w0.127: 100.02,43.2 100.35,42.87 118.96,42.87 121.93,45.85 122.51,45.85 123.65,46.98 125.68,46.98 125.79,47.09 128.73,47.09 v2(129.17,46.65)
  BOTTOM w0.089: v2(95.96,49.43) 95.58,49.81 94.81,49.81 94.69,49.69 94.13,49.69 94,49.75 93.94,49.77 93.83,49.77 93.67,49.7 93.67,49.69 93.47,49.69 93.34,49.75 93.29,49.77 93.18,49.77 93.17,49.77 92.69,49.77 92.67,49.78 92.46,49.78 92.26,49.58 CPU1.AU54
  BOTTOM w0.114: v2(129.17,46.65) 129.17,46.59 129.71,46.05 DIMM1.40
M_A_DQ46: length 46.4
  L4 w0.127: v2(98.93,46.45) 98.93,46.1 100.56,44.47 113.32,44.47 113.64,44.15 117.46,44.15 121.57,48.26 124.62,48.26 124.88,48.52 126.5,48.52 127.46,47.57 128.96,47.57 129.17,47.78 v2(129.17,49.05)
  BOTTOM w0.089: CPU1.AV52 93.13,49.95 93.33,49.95 93.41,49.91 93.51,49.87 93.63,49.87 93.79,49.95 93.98,49.95 94.16,49.87 94.51,49.87 94.71,50.07 96.02,50.07 96.04,50.08
  BOTTOM w0.114: DIMM1.52 129.56,49.65 129.17,49.26 v2(129.17,49.05) ; v2(98.93,46.45) 98.93,47.49 v1(96.37,50.06) 96.34,50.08 96.04,50.08
M_A_DQ47: length 48.3
  L4 w0.127: v2(101.47,46.08) 101.93,45.62 102.28,45.62 102.69,46.02 112.2,46.02 112.32,45.89 112.32,45.74 112.45,45.62 112.7,45.62 112.83,45.74 112.83,45.89 112.96,46.02 113.21,46.02 113.34,45.89 113.34,45.74 113.47,45.62 113.72,45.62 113.85,45.74 113.85,45.89 113.97,46.02 114.23,46.02 114.35,45.89 114.35,45.76 114.48,45.64 114.74,45.64 114.86,45.76 114.86,45.89 114.99,46.02 115.24,46.02 115.37,45.89 115.37,45.74 115.5,45.62 115.75,45.62 115.88,45.74 115.88,45.89 116.01,46.02 116.26,46.02 116.39,45.89 116.39,45.74 116.51,45.62 116.77,45.62 116.89,45.74 116.89,45.89 117.02,46.02 117.71,46.02 121.52,49.83 121.9,49.83 122.03,49.7 122.03,49.56 122.16,49.43 122.41,49.43 122.54,49.56 122.54,49.7 122.67,49.83 122.92,49.83 123.05,49.7 123.05,49.56 123.17,49.43 123.43,49.43 123.55,49.56 123.55,49.7 123.68,49.83 125.04,49.83 v2(125.16,49.95)
  BOTTOM w0.089: CPU1.AU52 92.63,50.53 93.81,50.53 93.97,50.56 94.03,50.58 94.15,50.65 95.13,50.65 95.76,51.28
  BOTTOM w0.114: DIMM1.53 v2(125.16,49.95) ; 95.76,51.28 v1(96.32,51.28) 97.64,51.28 97.88,51.03 98.04,51.03 98.42,51.41 98.6,51.41 98.74,51.26 98.74,51.08 98.37,50.71 98.37,50.55 98.53,50.39 98.69,50.39 99.12,50.81 99.3,50.81 99.44,50.67 99.44,50.49 99.01,50.06 99.01,49.9 99.17,49.74 99.34,49.74 99.69,50.09 99.87,50.09 100.01,49.95 100.01,49.77 99.66,49.42 99.66,49.25 99.82,49.09 99.98,49.09 100.33,49.44 100.51,49.44 100.66,49.3 100.66,49.12 100.31,48.77 100.31,48.61 101.47,47.44 v2(101.47,46.08)
M_A_DQ48: length 55.9
  TOP w0.114: v1(127,54.15) 126.44,54.15 v2(126.43,54.15)
  L4 w0.089: 93.21,54.65 92.4,54.65 92.16,54.89 92.16,56.94 90.78,58.31 89.97,58.31 89.33,58.95 88.38,58.95 87.95,58.52 87.95,57.52 v2(88.17,57.29)
  L4 w0.127: v2(126.43,54.15) 128.16,55.88 128.16,56.06 127.88,56.34 127.7,56.34 125.95,54.6 124.79,54.6 124.57,54.37 115.54,54.37 111.79,50.62 103.32,50.62 102.95,50.24 100.44,50.24 96.31,54.37 94.47,54.37 94.2,54.65 93.21,54.65
  BOTTOM w0.089: v2(88.17,57.29) 87.85,57.61 CPU1.AK40
  BOTTOM w0.114: DIMM1.69 125.91,54.75 126.43,54.23 v2(126.43,54.15)
M_A_DQ49: length 55.6
  TOP w0.114: v1(124.56,54.17) 125.14,54.17 v2(125.16,54.15)
  L4 w0.089: v2(88.08,56.39) 88.08,56.63 88.26,56.81 88.85,56.81 88.98,56.93 88.98,57.47 88.85,57.6 88.57,57.6 88.29,57.88 88.29,58.38 88.52,58.6 89.17,58.6 89.76,58.01 90.68,58.01 91.93,56.76 91.93,54.79 92.41,54.31 93.25,54.31
  L4 w0.127: v2(125.16,54.15) 124.8,53.8 124.31,53.8 124.31,53.79 123.26,53.79 123.06,53.99 122.75,53.99 122.55,53.79 122.24,53.79 122.04,53.99 121.73,53.99 121.53,53.79 121.22,53.79 121.02,53.99 120.72,53.99 120.52,53.79 120.21,53.79 120.01,53.99 119.7,53.99 119.5,53.79 119.19,53.79 118.99,53.99 118.68,53.99 118.48,53.79 118.18,53.79 117.98,53.99 117.67,53.99 117.47,53.79 117.16,53.79 116.96,53.99 116.65,53.99 116.45,53.79 116.07,53.79 115.21,52.93 115.03,52.93 114.92,53.03 114.74,53.03 114.56,52.85 114.56,52.67 114.67,52.57 114.67,52.39 114.49,52.21 114.31,52.21 114.2,52.31 114.02,52.31 113.84,52.14 113.84,51.96 113.95,51.85 113.95,51.67 113.77,51.49 113.59,51.49 113.49,51.6 113.31,51.6 113.13,51.42 113.13,51.24 113.23,51.13 113.23,50.95 113.05,50.77 112.87,50.77 112.77,50.88 112.59,50.88 112.41,50.7 112.41,50.52 112.51,50.41 112.51,50.23 112.13,49.86 111.32,49.86 111.19,49.99 111.19,50.07 111.07,50.2 110.81,50.2 110.69,50.07 110.69,49.99 110.56,49.86 110.31,49.86 110.18,49.99 110.18,50.07 110.05,50.2 109.8,50.2 109.67,50.07 109.67,49.99 109.54,49.86 109.29,49.86 109.16,49.99 109.16,50.07 109.04,50.2 108.78,50.2 108.65,50.07 108.65,49.99 108.53,49.86 108.27,49.86 108.15,49.99 108.15,50.07 108.02,50.2 107.77,50.2 107.64,50.07 107.64,49.99 107.51,49.86 107.26,49.86 107.13,49.99 107.13,50.07 107,50.2 106.75,50.2 106.62,50.07 106.62,49.99 106.5,49.86 106.24,49.86 106.11,49.99 106.11,50.07 105.99,50.2 105.73,50.2 105.61,50.07 105.61,49.99 105.48,49.86 105.23,49.86 105.1,49.99 105.1,50.07 104.97,50.2 104.72,50.2 104.59,50.07 104.59,49.99 104.46,49.86 104.21,49.86 104.08,49.99 104.08,50.07 103.96,50.2 103.7,50.2 103.57,50.07 103.57,49.99 103.45,49.86 100.31,49.86 96.24,53.93 94.28,53.93 93.9,54.31 93.25,54.31
  BOTTOM w0.089: CPU1.AK42 87.85,56.61 v2(88.08,56.39)
  BOTTOM w0.114: v2(125.16,54.15) 123.7,54.15 DIMM1.67
M_A_DQ50: length 53.3
  TOP w0.114: v1(124.56,51.76) 124.57,51.75 v2(125.16,51.75)
  L4 w0.089: v2(89.45,55.35) 89.45,55.04 90.31,54.18 90.31,52.43 90.62,52.12 92.25,52.12 92.85,51.52 93.32,51.52
  L4 w0.127: v2(125.16,51.75) 125.14,51.72 120.58,51.72 119.97,51.12 119.42,51.12 118.84,51.71 118.59,51.71 118.41,51.53 118.41,51.35 118.59,51.17 118.59,50.99 118.41,50.81 118.24,50.81 117.65,51.4 117.47,51.4 117.29,51.22 117.29,51.04 117.88,50.45 117.88,50.27 117.7,50.09 117.52,50.09 116.93,50.68 116.75,50.68 116.57,50.5 116.57,50.32 117.16,49.73 117.16,49.55 116.98,49.37 116.8,49.37 116.21,49.96 116.03,49.96 115.85,49.78 115.85,49.6 116.44,49.01 116.44,48.83 116.26,48.65 116.08,48.65 115.49,49.24 115.31,49.24 115.13,49.06 115.13,48.88 115.72,48.29 115.72,48.11 115.42,47.81 115.16,47.81 114.72,48.25 114.31,48.25 113.87,47.81 99.64,47.81 95.94,51.52 93.32,51.52
  BOTTOM w0.089: v2(89.45,55.35) 89.44,55.37 89.15,55.65 CPU1.AM43
  BOTTOM w0.114: v2(125.16,51.75) DIMM1.59
M_A_DQ51: length 52.7
  TOP w0.114: v2(126.43,51.75) 126.43,51.87 v1(126.8,52.24)
  L4 w0.089: v2(89.42,54.47) 90.09,53.81 90.09,52.25 90.25,52.09
  L4 w0.127: 90.25,52.09 90.45,51.89 92.05,51.89 93.35,50.58 96.41,50.58 99.56,47.43 115.58,47.43 116.03,47.89 116.24,47.89 116.66,47.47 116.84,47.47 117.08,47.71 117.08,47.89 116.68,48.3 116.68,48.47 116.86,48.65 117.04,48.65 117.45,48.24 117.63,48.24 117.81,48.42 117.81,48.6 117.4,49.01 117.4,49.19 117.58,49.37 117.76,49.37 118.17,48.96 118.35,48.96 118.53,49.14 118.53,49.32 118.12,49.73 118.12,49.91 118.3,50.09 118.48,50.09 118.89,49.68 119.07,49.68 119.25,49.86 119.25,50.04 118.84,50.45 118.84,50.63 119.02,50.81 119.2,50.81 119.61,50.4 119.79,50.4 120.67,51.28 125.96,51.28 v2(126.43,51.75)
  BOTTOM w0.089: v2(89.42,54.47) 89.15,54.74 CPU1.AM45
  BOTTOM w0.114: DIMM1.57 125.91,51.15 126.43,51.68 v2(126.43,51.75)
M_A_DQ52: length 53.3
  TOP w0.114: v2(130.44,50.85) 130.44,51.29 v1(130.58,51.43)
  L4 w0.089: 89.9,51.92 89.9,53.65 89.56,53.98 88.62,53.98 v2(88.12,54.49)
  L4 w0.127: v2(130.44,50.85) 130.57,50.72 131.06,50.72 131.19,50.85 131.19,51.17 131.06,51.3 128.06,51.3 127.64,50.89 120.83,50.89 117,47.05 99.5,47.05 96.3,50.25 93.14,50.25 92.03,51.36 91.3,51.36 90.94,51.01 90.47,51.01 89.9,51.58 89.9,51.92
  BOTTOM w0.089: CPU1.AK45 87.85,54.75 v2(88.12,54.49)
  BOTTOM w0.114: DIMM1.56 v2(130.44,50.85)
M_A_DQ53: length 54.6
  TOP w0.114: v1(128.7,51.43) 129.17,50.96 v2(129.17,50.85)
  L4 w0.127: v2(88.05,55.43) 86.97,54.34 86.97,52.15 88.04,51.08 89.84,51.08 90.3,50.62 91.02,50.62 91.34,50.94 91.92,50.94 92.99,49.86 96.2,49.86 99.41,46.66 117.16,46.66 121,50.49 128.26,50.49 128.35,50.41 128.73,50.41 v2(129.17,50.85)
  BOTTOM w0.089: v2(88.05,55.43) 87.85,55.62 CPU1.AK43
  BOTTOM w0.114: v2(129.17,50.85) 129.17,50.92 129.7,51.45 DIMM1.58
M_A_DQ54: length 54.6
  TOP w0.114: v2(129.17,55.05) 128.61,55.05 v1(128.6,55.06)
  L4 w0.089: 93.24,53.95 92.44,53.95 91.69,54.69 91.69,56.51 90.47,57.73 89.91,57.73 v2(89.47,57.28)
  L4 w0.127: v2(129.17,55.05) 129.74,55.62 130.35,55.62 130.48,55.75 130.48,56.13 130.35,56.25 129.22,56.25 126.37,53.4 116.3,53.4 116.29,53.39 116.2,53.39 112.29,49.48 100.16,49.48 96.16,53.48 94.03,53.48 93.55,53.95 93.24,53.95
  BOTTOM w0.089: v2(89.47,57.28) 89.15,57.6 CPU1.AM40
  BOTTOM w0.114: v2(129.17,55.05) 129.77,54.45 DIMM1.68
M_A_DQ55: length 54.1
  TOP w0.114: v2(130.44,55.05) 130.63,55.24 v1(130.63,55.62)
  L4 w0.089: v2(89.43,56.38) 89.92,56.86 90.96,56.86 91.21,56.61 91.21,56.08 90.88,55.75 90.88,55.12 92.18,53.82
  L4 w0.127: v2(130.44,55.05) 130.02,54.63 130.02,54.27 130.18,54.12 131.06,54.12 131.19,53.99 131.19,53.64 131.06,53.51 129.08,53.51 128.54,54.05 127.55,54.05 127.24,53.74 126.51,53.01 116.36,53.01 112.45,49.1 99.98,49.1 96.01,53.07 92.93,53.07 92.18,53.82
  BOTTOM w0.089: CPU1.AM42 89.15,56.69 89.43,56.41 v2(89.43,56.38)
  BOTTOM w0.114: DIMM1.70 v2(130.44,55.05)
M_A_DQ56: length 81.2
  TOP w0.114: v2(129.8,93.45) 130.36,94.01 v1(130.4,94.01)
  L3 w0.127: v2(88.75,53.52) 89.26,54.03 89.6,54.03 90.19,54.61 91.34,54.61 92.41,55.68 94.82,55.68 95.58,54.92 97.7,54.92 102.44,59.66 102.44,77.97 113.71,89.23 115.19,89.23 115.46,89.5 115.46,89.68 114.9,90.25 114.9,90.43 115.08,90.61 115.26,90.61 115.82,90.04 116,90.04 116.18,90.22 116.18,90.4 115.62,90.97 115.62,91.15 115.8,91.33 115.98,91.33 116.54,90.76 116.72,90.76 116.9,90.94 116.9,91.12 116.34,91.68 116.34,91.86 116.52,92.04 116.7,92.04 117.26,91.48 117.44,91.48 117.62,91.66 117.62,91.84 117.06,92.4 117.06,92.58 117.24,92.76 117.42,92.76 117.98,92.2 118.16,92.2 119.71,93.75 123.32,93.75 124.36,94.79 128.14,94.79 128.52,94.41 128.84,94.41 v2(129.8,93.45)
  BOTTOM w0.089: CPU1.AM46 89.09,54.01 88.75,53.67 v2(88.75,53.52)
  BOTTOM w0.114: v2(129.8,93.45) 129.8,93.52 130.33,94.05 DIMM1.192
M_A_DQ57: length 80.7
  TOP w0.114: v1(129.4,94.74) 129.8,95.15 v2(129.8,95.25)
  L3 w0.127: v2(88.11,53.52) 87.37,54.26 87.37,55.46 87.84,55.93 91.09,55.93 91.24,56.08 94.98,56.08 95.74,55.32 97.54,55.32 99,56.78 99,56.96 98.71,57.25 98.71,57.43 98.89,57.61 99.07,57.61 99.36,57.32 99.54,57.32 99.72,57.5 99.72,57.68 99.43,57.97 99.43,58.15 99.61,58.33 99.79,58.33 100.08,58.04 100.26,58.04 100.44,58.22 100.44,58.4 100.15,58.69 100.15,58.86 100.33,59.04 100.51,59.04 100.8,58.76 100.98,58.76 101.16,58.94 101.16,59.11 100.87,59.4 100.87,59.58 101.05,59.76 101.23,59.76 101.51,59.47 101.69,59.47 102.06,59.84 102.06,78.12 116.79,92.86 117.08,93.14 118.56,93.14 119.57,94.15 123.16,94.15 124.26,95.25 128.33,95.25 128.78,94.81 129.36,94.81 v2(129.8,95.25)
  BOTTOM w0.089: v2(88.11,53.52) 87.85,53.78 CPU1.AK46
  BOTTOM w0.114: DIMM1.194 130.33,94.65 129.8,95.18 v2(129.8,95.25)
M_A_DQ58: length 78.2
  TOP w0.114: v2(125.16,91.35) 124.62,91.35 v1(124.6,91.33)
  L3 w0.127: v2(89.45,51.5) 89.94,51.02 93.67,51.02 94.58,51.93 99.27,51.93 104.67,57.33 104.67,65.34 104.8,65.46 105.28,65.46 105.41,65.59 105.41,65.85 105.28,65.97 104.8,65.97 104.67,66.1 104.67,66.53 104.8,66.66 105.18,66.66 105.31,66.79 105.31,67.04 105.18,67.17 104.8,67.17 104.67,67.29 104.67,67.55 104.8,67.68 105.35,67.68 105.47,67.8 105.47,68.06 105.35,68.18 104.8,68.18 104.67,68.31 104.67,68.56 104.8,68.69 105.35,68.69 105.47,68.82 105.47,69.07 105.35,69.2 104.8,69.2 104.67,69.33 104.67,69.58 104.8,69.71 105.35,69.71 105.47,69.83 105.47,70.09 105.35,70.22 104.8,70.22 104.67,70.34 104.67,70.6 104.8,70.72 105.35,70.72 105.47,70.85 105.47,71.1 105.35,71.23 104.8,71.23 104.67,71.36 104.67,71.61 104.8,71.74 105.35,71.74 105.47,71.87 105.47,72.12 105.35,72.25 104.8,72.25 104.67,72.37 104.67,72.63 104.8,72.76 105.35,72.76 105.47,72.88 105.47,73.14 105.35,73.26 104.8,73.26 104.67,73.39 104.67,73.64 104.8,73.77 105.35,73.77 105.47,73.9 105.47,75.17 105.35,75.3 104.8,75.3 104.67,75.42 104.67,75.8 120.22,91.35 120.6,91.35 120.83,91.59 121.1,91.59 121.34,91.35 121.61,91.35 121.85,91.59 122.12,91.59 122.36,91.35 122.63,91.35 122.86,91.59 123.14,91.59 123.37,91.35 123.64,91.35 123.88,91.59 124.15,91.59 124.39,91.35 v2(125.16,91.35)
  BOTTOM w0.089: CPU1.AM49 89.45,51.76 v2(89.45,51.5)
  BOTTOM w0.114: DIMM1.183 v2(125.16,91.35)
M_A_DQ59: length 77.5
  TOP w0.114: v2(129.17,90.45) 128.85,90.77 v1(128.85,90.91)
  L3 w0.127: v2(88.15,51.62) 87.57,51.04 87.57,48.63 87.88,48.32 93.42,48.32 94.99,49.89 98.89,49.89 106.62,57.61 106.62,76.13 120.49,90.01 128.72,90.01 128.83,90.11 128.83,90.11 v2(129.17,90.45)
  BOTTOM w0.089: CPU1.AK49 87.85,51.91 v2(88.15,51.62)
  BOTTOM w0.114: v2(129.17,90.45) 129.17,90.52 129.69,91.05 DIMM1.182
M_A_DQ60: length 79.9
  TOP w0.114: v1(126.13,93.62) 126.13,93.49 v2(125.8,93.15)
  L3 w0.127: v2(89.48,52.57) 89.85,52.57 90.28,53 91.34,53 92.34,54 97.96,54 103.38,59.42 103.38,76.32 103.91,76.85 103.91,77.03 103.38,77.56 103.38,77.74 103.56,77.92 103.74,77.92 104.27,77.39 104.45,77.39 104.63,77.57 104.63,77.75 104.1,78.28 104.1,78.46 104.28,78.64 104.46,78.64 104.99,78.11 105.17,78.11 105.35,78.29 105.35,78.47 104.82,79 104.82,79.18 105,79.36 105.18,79.36 105.71,78.83 105.89,78.83 106.07,79.01 106.07,79.19 105.54,79.72 105.54,79.9 105.72,80.08 105.9,80.08 106.43,79.55 106.61,79.55 106.79,79.73 106.79,79.91 106.26,80.44 106.26,80.62 106.44,80.8 106.61,80.8 107.14,80.27 107.32,80.27 107.5,80.45 107.5,80.63 106.97,81.16 106.97,81.34 107.15,81.52 107.33,81.52 107.86,80.99 108.04,80.99 108.22,81.17 108.22,81.35 107.69,81.88 107.69,82.06 107.87,82.24 108.05,82.24 108.58,81.71 108.76,81.71 108.94,81.89 108.94,82.07 108.65,82.35 108.65,82.53 108.83,82.71 109.01,82.71 109.3,82.43 109.48,82.43 120.02,92.96 124.01,92.96 124.64,93.59 125.34,93.59 125.79,93.15 v2(125.8,93.15)
  BOTTOM w0.089: v2(89.48,52.57) 89.15,52.89 CPU1.AM48
  BOTTOM w0.114: v2(125.8,93.15) 125.8,93.22 125.27,93.75 DIMM1.191
M_A_DQ61: length 79.2
  TOP w0.114: v2(125.16,94.35) v1(124.6,94.35)
  L3 w0.127: v2(88.18,52.57) 88.68,53.07 89.61,53.07 90.49,53.95 91.52,53.95 92.1,54.53 97.9,54.53 102.82,59.44 102.82,77.81 108.95,83.94 109.13,83.94 109.7,83.37 109.88,83.37 110.06,83.55 110.06,83.73 109.49,84.3 109.49,84.48 109.67,84.66 109.85,84.66 110.42,84.08 110.6,84.08 110.78,84.26 110.78,84.44 110.21,85.02 110.21,85.2 110.39,85.38 110.57,85.38 111.14,84.8 111.32,84.8 111.5,84.98 111.5,85.16 110.93,85.74 110.93,85.92 111.11,86.1 111.29,86.1 111.86,85.52 112.04,85.52 112.22,85.7 112.22,85.88 111.65,86.45 111.65,86.63 111.83,86.81 112.01,86.81 112.58,86.24 112.76,86.24 112.94,86.42 112.94,86.6 112.36,87.17 112.36,87.35 112.54,87.53 112.72,87.53 113.3,86.96 113.48,86.96 113.66,87.14 113.66,87.32 113.28,87.69 113.28,87.87 113.46,88.05 113.64,88.05 114.01,87.69 114.19,87.69 114.5,88 114.5,88.18 114.33,88.34 114.33,88.52 114.51,88.7 114.69,88.7 114.86,88.54 115.04,88.54 119.86,93.36 123.61,93.36 124.61,94.35 v2(125.16,94.35)
  BOTTOM w0.089: v2(88.18,52.57) 87.85,52.89 CPU1.AK48
  BOTTOM w0.114: DIMM1.193 v2(125.16,94.35)
M_A_DQ62: length 77.1
  TOP w0.114: v1(126.8,91.84) 126.43,91.47 v2(126.43,91.35)
  L3 w0.127: v2(126.43,91.35) 126.43,91.13 126.2,90.9 120.31,90.9 105.85,76.45 105.85,64.19 105.73,64.06 105.28,64.06 105.16,63.94 105.16,63.68 105.28,63.56 105.73,63.56 105.85,63.43 105.85,63.18 105.73,63.05 105.18,63.05 105.05,62.92 105.05,62.67 105.18,62.54 105.73,62.54 105.85,62.41 105.85,62.16 105.73,62.03 105.18,62.03 105.05,61.91 105.05,61.65 105.18,61.52 105.73,61.52 105.85,61.4 105.85,61.14 105.73,61.02 105.18,61.02 105.05,60.89 105.05,60.64 105.18,60.51 105.73,60.51 105.85,60.38 105.85,60.13 105.73,60 105.18,60 105.05,59.87 105.05,59.62 105.18,59.49 105.73,59.49 105.85,59.37 105.85,59.11 105.73,58.98 105.18,58.98 105.05,58.86 105.05,58.6 105.18,58.48 105.73,58.48 105.85,58.35 105.85,57.97 99.43,51.55 94.77,51.55 93.21,49.99 90.94,49.99 90.31,50.61 89.53,50.61 v2(89.48,50.66)
  BOTTOM w0.089: v2(89.48,50.66) 89.15,50.99 CPU1.AM51
  BOTTOM w0.114: DIMM1.181 125.91,90.75 126.43,91.28 v2(126.43,91.35)
M_A_DQ63: length 76.4
  TOP w0.114: v1(130.6,90.99) 130.44,90.83 v2(130.44,90.45)
  L3 w0.127: v2(88.18,50.66) 88.2,50.66 88.64,50.22 90.15,50.22 91.08,49.29 93.35,49.29 94.35,50.28 96.57,50.28 96.69,50.41 96.69,50.89 96.82,51.02 97.08,51.02 97.2,50.89 97.2,50.41 97.33,50.28 97.58,50.28 97.71,50.41 97.71,50.95 97.84,51.07 98.09,51.07 98.22,50.95 98.22,50.41 98.35,50.28 98.75,50.28 106.24,57.77 106.24,76.29 120.35,90.4 127.01,90.4 127.69,91.07 129.98,91.07 130.44,90.61 v2(130.44,90.45)
  BOTTOM w0.089: CPU1.AK51 87.85,50.99 v2(88.18,50.66)
  BOTTOM w0.114: DIMM1.180 v2(130.44,90.45)
M_A_DQS0: length 91.6
  L3 w0.114: v2(125.8,76.95) 125.64,76.8 125.64,76.4 125.42,76.17 123.5,76.17 120.06,72.74 120.06,47.46 104.51,31.91 102.98,31.91 102.87,31.79 102.87,31.39 102.62,31.15 102.09,31.15 101.84,31.39 101.84,31.87 101.71,32 101.4,32 101.27,31.87 101.27,31.39 101.02,31.15 100.49,31.15 100.24,31.39 100.24,31.92 100.11,32.05 99.8,32.05 99.67,31.92 99.67,31.39 99.42,31.15 98.89,31.15 98.64,31.39 98.64,32 98.51,32.12 98.2,32.12 98.07,32 98.07,31.39 97.82,31.15 97.29,31.15 97.04,31.39 97.04,32 96.91,32.12 96.6,32.12 96.47,32 96.47,31.39 96.22,31.15 95.69,31.15 95.44,31.39 95.44,31.79 95.33,31.91 94.81,31.91 94.31,32.4 94.31,33.5 92.68,35.13 89.53,35.13 87.77,36.88 v2(87.77,37.79)
  BOTTOM w0.089: CPU1.AJ62 87.33,43.95 87.33,43.75 87.29,43.66 87.25,43.57 87.25,43.45 87.33,43.29 87.34,43.26 87.34,40.34 87.24,40.24 87.24,39.8 87.25,39.8 87.25,39.77
  BOTTOM w0.102: v2(87.77,37.79) 87.43,37.79 87.25,37.98 87.25,38.32 ; 87.25,39.77 87.25,38.32 ; 87.25,38.32 v1(87.43,38.32) ; v2(125.8,76.95) 125.2,77.55 DIMM1.137
M_A_DQS1: length 54.3
  TOP w0.102: v2(130.44,37.65) 130.44,37.14 v1(130.56,37.03)
  L4 w0.114: v2(90.26,40.71) 90.86,40.71 91.22,40.35 91.22,38.12 92.49,36.85 92.8,36.85 92.8,36.85 93.55,36.85 97.54,32.86 120.63,32.86 125.13,37.37 127.32,37.37 127.97,36.72 130.03,36.72 130.3,36.98 130.3,37.51 v2(130.44,37.65)
  BOTTOM w0.089: v2(90.26,40.71) 90.12,40.71 89.62,41.21 89.62,43.07 89.58,43.25 89.57,43.28 89.51,43.41 89.51,43.6 89.56,43.73 89.58,43.78 89.58,44.21 89.82,44.46 89.82,44.67 CPU1.AN61
  BOTTOM w0.102: DIMM1.12 v2(130.44,37.65)
M_A_DQS2: length 86.8
  TOP w0.102: v2(129.8,82.05) 129.8,82.2 v1(129.46,82.54)
  L3 w0.114: v2(90.14,45.95) 89.95,45.75 89.95,44.84 90.34,44.45 91.19,44.45 93.27,42.37 93.27,41.28 97.03,37.53 97.55,37.53 97.81,37.79 101.42,37.79 101.68,37.53 102.3,37.53 102.67,37.9 102.67,38.06 102.54,38.2 102.54,38.55 102.91,38.92 103.26,38.92 103.74,38.45 103.91,38.45 104.14,38.68 104.14,38.86 103.67,39.33 103.67,39.68 104.05,40.06 104.4,40.06 104.84,39.61 105.02,39.61 105.25,39.83 105.25,40.01 104.8,40.46 104.8,40.81 105.18,41.19 105.53,41.19 105.99,40.73 106.17,40.73 106.46,41.03 106.46,41.21 106.1,41.57 106.1,41.97 106.43,42.31 107.09,42.31 107.39,42.61 107.39,43.4 115.16,51.17 115.16,74.54 122.58,81.95 127.57,81.95 127.95,81.57 129.5,81.57 129.8,81.88 v2(129.8,82.05)
  BOTTOM w0.089: v2(90.14,45.95) 89.8,46.29 CPU1.AN58
  BOTTOM w0.102: DIMM1.154 130.82,82.65 130.68,82.51 130.27,82.51 v2(129.8,82.05)
M_A_DQS3: length 51.7
  TOP w0.102: v2(125.8,42.52) 125.8,42.68 v1(126.11,43)
  L4 w0.089: v2(90.13,47.86) 90.46,48.2 91.83,48.2 92.84,47.18 92.84,45.81 93.49,45.16 93.49,44.08 93.47,44.06 93.47,44.04
  L4 w0.114: 93.47,44.04 93.47,43.7 99.39,37.78 100.1,37.78 100.35,38.03 100.35,38.25 100.46,38.37 100.8,38.37 100.92,38.25 100.92,38.03 101.17,37.78 101.7,37.78 101.95,38.03 101.95,38.25 102.06,38.37 102.4,38.37 102.52,38.25 102.52,38.03 102.77,37.78 103.3,37.78 103.55,38.03 103.55,38.25 103.66,38.37 104,38.37 104.12,38.25 104.12,38.03 104.37,37.78 105.08,37.78 105.33,38.03 105.33,38.25 105.44,38.37 105.78,38.37 105.9,38.25 105.9,38.03 106.14,37.78 106.68,37.78 106.93,38.03 106.93,38.25 107.04,38.37 107.38,38.37 107.5,38.25 107.5,38.03 107.75,37.78 108.28,37.78 108.53,38.03 108.53,38.25 108.64,38.37 108.98,38.37 109.1,38.25 109.1,38.03 109.35,37.78 119.09,37.78 123.4,42.09 125.36,42.09 v2(125.8,42.52)
  BOTTOM w0.089: v2(90.13,47.86) 90.13,47.93 CPU1.AN55
  BOTTOM w0.102: DIMM1.29 124.76,42.75 124.98,42.97 125.34,42.97 125.59,42.72 125.6,42.72 v2(125.8,42.52)
M_A_DQS4: length 77.3
  TOP w0.102: v2(125.8,87.37) v1(125.8,86.81)
  L3 w0.114: v2(125.8,87.37) 125.36,86.94 121.61,86.94 110.09,75.41 110.09,65.97 109.5,65.38 109.5,51.18 107.6,49.28 107.25,49.28 107.01,49.52 106.83,49.52 106.61,49.3 106.61,49.12 106.85,48.88 106.85,48.53 106.47,48.15 106.12,48.15 105.6,48.67 105.44,48.67 105.2,48.43 105.2,48.27 105.71,47.75 105.71,47.4 105.34,47.02 104.99,47.02 104.47,47.54 104.31,47.54 104.06,47.29 104.06,47.13 104.58,46.61 104.58,46.26 101.88,43.56 101.53,43.56 101.1,43.99 100.94,43.99 100.7,43.75 100.7,43.59 101.13,43.16 101.13,42.81 100.32,42 98.87,42 98.37,42.5 v2(97.59,42.5)
  BOTTOM w0.089: CPU1.AW57 93.45,46.84 93.65,46.84 93.74,46.81 93.83,46.77 93.95,46.77 94.13,46.85 94.46,46.85 94.8,46.52 95.25,46.52 96.32,45.45 96.32,45.29 96.32,45.1 97.67,43.75 97.67,42.58 v2(97.59,42.5)
  BOTTOM w0.102: v2(125.8,87.37) 125.35,87.82 125.34,87.82 124.69,87.82 124.62,87.75 DIMM1.171
M_A_DQS5: length 46.3
  TOP w0.102: v2(125.8,47.95) 125.8,48.17 v1(126.09,48.46)
  L4 w0.114: v2(125.8,47.95) 125.36,47.51 122.85,47.51 122.26,46.92 121.91,46.92 121.68,47.14 121.52,47.14 121.28,46.9 121.28,46.74 121.51,46.51 121.51,46.16 121.13,45.79 120.78,45.79 120.55,46.01 120.39,46.01 120.15,45.77 120.15,45.61 120.37,45.38 120.37,45.03 120,44.65 119.65,44.65 119.42,44.88 119.26,44.88 119.02,44.64 119.02,44.47 119.24,44.25 119.24,43.9 118.74,43.4 113.32,43.4 113.09,43.63 112.65,43.63 112.41,43.4 111.95,43.4 111.63,43.72 111.36,43.72 111.04,43.4 110.58,43.4 110.26,43.72 109.99,43.72 109.67,43.4 109.21,43.4 108.89,43.72 108.62,43.72 108.3,43.4 107.84,43.4 107.52,43.72 107.25,43.72 106.93,43.4 106.47,43.4 106.15,43.72 105.88,43.72 105.55,43.4 105.1,43.4 104.77,43.72 104.5,43.72 104.18,43.4 103.72,43.4 103.4,43.72 103.13,43.72 102.81,43.4 102.35,43.4 102.03,43.72 101.76,43.72 101.44,43.4 100.57,43.4 98.18,45.79 98.18,45.89 96.55,47.52 96.55,47.92 96.9,48.28 v2(96.9,48.5)
  BOTTOM w0.089: CPU1.AW53 93.45,49.27 93.65,49.27 93.74,49.24 93.83,49.2 93.95,49.2 94.13,49.28 94.67,49.28 94.94,49.01 95.78,49.01 96.19,48.6 96.44,48.6 96.55,48.5 v2(96.9,48.5)
  BOTTOM w0.102: DIMM1.47 124.74,48.15 124.98,48.39 125.35,48.39 v2(125.8,47.95)
M_A_DQS6: length 54.5
  TOP w0.102: v1(129.18,53.23) 129.22,53.23 v2(129.8,52.65)
  L4 w0.089: 91.01,54.22 91,54.23 90.97,54.23 90.74,54.47 90.1,55.11 90.1,55.58 89.7,55.98 89.12,55.98 v2(88.73,56.37)
  L4 w0.114: v2(129.8,52.65) 129.21,52.06 128.79,52.06 128.58,52.27 128.58,53.26 128.32,53.52 127.77,53.52 127.43,53.18 127.43,52.64 127.27,52.48 126.73,52.48 117.47,52.48 117.11,52.12 116.95,52.12 116.8,52.28 116.43,52.28 116.32,52.17 116.07,51.92 116.07,51.55 116.22,51.4 116.22,51.24 115.98,50.99 115.82,50.99 115.66,51.15 115.29,51.15 114.94,50.79 114.94,50.42 115.09,50.26 115.09,50.1 114.85,49.86 114.69,49.86 114.52,50.03 114.15,50.03 113.79,49.67 113.79,49.3 113.96,49.13 113.96,48.97 113.56,48.57 99.87,48.57 95.81,52.64 92.59,52.64 91.01,54.22
  BOTTOM w0.089: CPU1.AL42 88.5,56.6 v2(88.73,56.37)
  BOTTOM w0.102: DIMM1.64 130.96,53.25 130.82,53.1 130.26,53.1 v2(129.8,52.65)
M_A_DQS7: length 78.7
  TOP w0.102: v2(129.17,91.64) 129.17,91.93 v1(128.88,92.22)
  L3 w0.089: v2(88.8,51.62) 89.09,51.9 92.04,51.9 92.21,52.08 92.21,52.08 92.39,52.25 92.42,52.25 92.43,52.27
  L3 w0.114: v2(129.17,91.64) 129.36,91.83 129.36,92.13 129.29,92.2 120.32,92.2 104.13,76.01 104.13,59.1 103.03,58 103.03,57.83 103.27,57.59 103.27,57.22 102.91,56.86 102.54,56.86 102.3,57.11 102.14,57.11 101.9,56.86 101.9,56.7 102.43,56.18 102.43,55.82 102.05,55.45 101.7,55.45 101.17,55.97 101.01,55.97 100.77,55.73 100.77,55.57 101.29,55.04 101.29,54.69 100.92,54.32 100.57,54.32 100.04,54.84 99.88,54.84 99.63,54.6 99.63,54.44 100.16,53.91 100.16,53.56 99.78,53.18 99.43,53.18 98.91,53.71 98.75,53.71 97.58,52.55 92.71,52.55 92.43,52.27
  BOTTOM w0.089: CPU1.AL49 88.5,51.91 v2(88.8,51.62)
  BOTTOM w0.102: v2(129.17,91.64) 130.19,92.66 130.72,92.66 130.91,92.85 DIMM1.188
M_A_DQS#0: length 91.6
  L3 w0.114: v2(88.31,37.11) 88.31,36.67 89.62,35.36 92.78,35.36 94.54,33.59 94.54,32.5 94.9,32.14 95.42,32.14 95.67,31.89 95.67,31.49 95.78,31.37 96.13,31.37 96.24,31.49 96.24,32.09 96.5,32.35 97.01,32.35 97.27,32.09 97.27,31.49 97.38,31.37 97.73,31.37 97.84,31.49 97.84,32.09 98.1,32.35 98.61,32.35 98.87,32.09 98.87,31.49 98.98,31.37 99.33,31.37 99.44,31.49 99.44,32.02 99.7,32.28 100.21,32.28 100.47,32.02 100.47,31.49 100.58,31.37 100.93,31.37 101.04,31.49 101.04,31.97 101.3,32.23 101.81,32.23 102.07,31.97 102.07,31.49 102.18,31.37 102.53,31.37 102.64,31.49 102.64,31.89 102.89,32.14 104.42,32.14 119.83,47.55 119.83,72.83 123.4,76.4 125.32,76.4 125.42,76.49 125.42,76.69 v2(125.16,76.95)
  BOTTOM w0.089: 87.05,39.77 87.05,39.8 87.05,39.8 87.05,40.32 87.15,40.42 87.15,43.25 87.08,43.4 87.08,43.6 87.13,43.73 87.15,43.78 87.15,44.21 87.54,44.6 CPU1.AJ61
  BOTTOM w0.102: 87.05,39.46 87.05,37.89 87.71,37.23 88.19,37.23 v2(88.31,37.11) ; 87.05,39.46 87.05,39.77 ; 87.05,39.46 v1(86.84,39.46) ; v2(125.16,76.95) 125.25,77.04 125.25,77.21 125.11,77.35 124.85,77.35 124.45,76.95 DIMM1.135
M_A_DQS#1: length 54.7
  TOP w0.102: v1(129.29,37.1) 129.8,37.62 v2(129.8,37.65)
  L4 w0.114: v2(90.26,41.36) 90.57,41.67 90.76,41.67 90.84,41.59 90.84,41.06 91.45,40.44 91.45,38.22 92.59,37.08 92.71,37.08 93.65,37.08 97.64,33.09 120.53,33.09 125.04,37.6 127.42,37.6 128.06,36.95 129.94,36.95 130.07,37.08 130.07,37.39 v2(129.8,37.65)
  BOTTOM w0.089: CPU1.AN62 89.76,43.95 89.76,43.75 89.72,43.66 89.68,43.57 89.68,43.45 89.75,43.32 89.76,43.29 89.81,43.14 89.81,41.28 89.92,41.18 90.08,41.18 v2(90.26,41.36)
  BOTTOM w0.102: v2(129.8,37.65) 130.4,37.05 DIMM1.10
M_A_DQS#2: length 87
  TOP w0.102: v1(130.71,82.64) 130.44,82.38 v2(130.44,82.05)
  L3 w0.114: v2(130.44,82.05) 130,81.61 129.86,81.61 129.59,81.34 127.86,81.34 127.48,81.72 122.67,81.72 115.39,74.44 115.39,51.08 107.62,43.31 107.62,42.52 107.18,42.08 106.53,42.08 106.32,41.88 106.32,41.67 106.69,41.3 106.69,40.93 106.26,40.5 105.89,40.5 105.43,40.96 105.27,40.96 105.03,40.72 105.03,40.55 105.47,40.11 105.47,39.74 105.12,39.38 104.75,39.38 104.3,39.83 104.14,39.83 103.9,39.58 103.9,39.42 104.37,38.95 104.37,38.59 104,38.22 103.64,38.22 103.17,38.7 103.01,38.7 102.77,38.45 102.77,38.29 102.9,38.15 102.9,37.8 102.4,37.3 101.59,37.3 101.33,37.56 97.91,37.56 97.65,37.3 96.94,37.3 93.05,41.19 93.05,42.27 91.1,44.22 90.24,44.22 89.72,44.75 89.72,45.72 89.49,45.94 v2(89.49,45.95)
  BOTTOM w0.089: CPU1.AM58 89.49,46.07 v2(89.49,45.95)
  BOTTOM w0.102: v2(130.44,82.05) 130.44,82.05 DIMM1.152
M_A_DQS#3: length 51.8
  TOP w0.102: v1(124.59,42.51) 124.6,42.52 v2(125.16,42.52)
  L4 w0.089: v2(89.48,47.86) 89.41,47.86 89.13,48.14 89.13,48.29 89.23,48.39 91.91,48.39 93.03,47.26 93.03,45.89 93.68,45.24 93.68,44.08 93.7,44.06 93.7,44.04
  L4 w0.114: 93.7,44.04 93.7,43.79 99.48,38.01 100,38.01 100.12,38.13 100.12,38.35 100.37,38.59 100.9,38.59 101.15,38.35 101.15,38.13 101.26,38.01 101.6,38.01 101.72,38.13 101.72,38.35 101.97,38.59 102.5,38.59 102.75,38.35 102.75,38.13 102.86,38.01 103.2,38.01 103.32,38.13 103.32,38.35 103.57,38.59 104.1,38.59 104.35,38.35 104.35,38.13 104.46,38.01 104.98,38.01 105.1,38.13 105.1,38.35 105.34,38.59 105.88,38.59 106.13,38.35 106.13,38.13 106.24,38.01 106.58,38.01 106.7,38.13 106.7,38.35 106.94,38.59 107.48,38.59 107.73,38.35 107.73,38.13 107.84,38.01 108.18,38.01 108.3,38.13 108.3,38.35 108.55,38.59 109.08,38.59 109.33,38.35 109.33,38.13 109.44,38.01 119,38.01 123.3,42.31 124.95,42.31 v2(125.16,42.52)
  BOTTOM w0.089: CPU1.AM55 89.35,48.25 89.53,48.08 89.53,47.91 v2(89.48,47.86)
  BOTTOM w0.102: DIMM1.27 124.79,42.15 v2(125.16,42.52)
M_A_DQS#4: length 77.6
  TOP w0.102: v2(125.16,87.37) v1(124.6,87.37)
  L3 w0.114: v2(125.16,87.37) 124.95,87.16 121.52,87.16 109.86,75.51 109.86,66.07 109.27,65.48 109.27,51.28 107.51,49.51 107.35,49.51 107.11,49.75 106.74,49.75 106.38,49.39 106.38,49.02 106.62,48.78 106.62,48.62 106.37,48.38 106.21,48.38 105.69,48.9 105.34,48.9 104.97,48.52 104.97,48.17 105.49,47.65 105.49,47.49 105.24,47.25 105.08,47.25 104.56,47.77 104.21,47.77 103.83,47.39 103.83,47.04 104.35,46.52 104.35,46.36 101.79,43.79 101.63,43.79 101.2,44.22 100.85,44.22 100.47,43.84 100.47,43.49 100.9,43.06 100.9,42.9 100.23,42.23 98.96,42.23 98.46,42.73 97.99,42.73 97.69,43.03 97.69,43.22 97.57,43.35 97.27,43.35 97.14,43.22 v2(97.14,42.95)
  BOTTOM w0.089: CPU1.AV57 92.56,47.03 92.56,46.84 92.74,46.66 93.62,46.66 93.67,46.64 93.8,46.59 94,46.59 94.15,46.66 94.39,46.66 94.72,46.33 95.17,46.33 96.13,45.37 96.13,45.02 97.48,43.67 97.48,43 97.35,42.88 97.22,42.88 v2(97.14,42.95)
  BOTTOM w0.102: v2(125.16,87.37) 124.96,87.58 124.79,87.58 124.36,87.15 DIMM1.169
M_A_DQS#5: length 46.6
  TOP w0.102: v2(125.16,47.95) 124.62,47.95 v1(124.59,47.97)
  L4 w0.114: v2(97.5,47.91) 97.32,48.08 97.03,48.08 96.78,47.83 96.78,47.62 98.41,45.99 98.41,45.88 100.66,43.62 101.34,43.62 101.67,43.95 102.13,43.95 102.45,43.62 102.72,43.62 103.04,43.95 103.5,43.95 103.82,43.62 104.09,43.62 104.41,43.95 104.87,43.95 105.19,43.62 105.46,43.62 105.78,43.95 106.24,43.95 106.56,43.62 106.83,43.62 107.15,43.95 107.61,43.95 107.93,43.62 108.2,43.62 108.52,43.95 108.98,43.95 109.3,43.62 109.57,43.62 109.9,43.95 110.35,43.95 110.68,43.62 110.95,43.62 111.27,43.95 111.73,43.95 112.05,43.62 112.32,43.62 112.55,43.86 113.18,43.86 113.42,43.62 118.64,43.62 119.01,43.99 119.01,44.15 118.79,44.38 118.79,44.73 119.16,45.11 119.52,45.11 119.74,44.88 119.9,44.88 120.14,45.13 120.14,45.29 119.92,45.51 119.92,45.86 120.3,46.24 120.65,46.24 120.87,46.01 121.03,46.01 121.28,46.26 121.28,46.42 121.05,46.64 121.05,46.99 121.43,47.37 121.78,47.37 122,47.15 122.17,47.15 122.76,47.74 124.95,47.74 v2(125.16,47.95)
  BOTTOM w0.089: CPU1.AV53 92.8,49.48 93.19,49.09 93.62,49.09 93.67,49.07 93.8,49.02 94,49.02 94.15,49.09 94.59,49.09 94.86,48.82 95.7,48.82 96.11,48.41 96.37,48.41 97.23,47.55 97.38,47.55 97.5,47.67 v2(97.5,47.91)
  BOTTOM w0.102: v2(125.16,47.95) 125.16,47.64 125.07,47.55 DIMM1.45
M_A_DQS#6: length 54.3
  TOP w0.102: v1(130.48,53.26) 130.44,53.22 v2(130.44,52.65)
  L4 w0.089: v2(88.75,55.4) 88.75,55.73 88.81,55.79 89.62,55.79 89.91,55.5 89.91,55.03 90.6,54.33 90.72,54.21 90.72,54.2 90.78,54.15 90.78,54.13 90.85,54.06
  L4 w0.114: v2(130.44,52.65) 130,52.21 129.69,52.21 129.31,51.83 128.7,51.83 128.35,52.17 128.35,53.16 128.23,53.29 127.86,53.29 127.66,53.09 127.66,52.55 127.37,52.25 126.83,52.25 126.82,52.25 126.2,52.25 126.2,52.25 117.56,52.25 117.21,51.9 116.86,51.9 116.7,52.05 116.52,52.05 116.3,51.82 116.3,51.65 116.45,51.49 116.45,51.14 116.07,50.76 115.72,50.76 115.57,50.92 115.39,50.92 115.16,50.69 115.16,50.51 115.32,50.36 115.32,50.01 114.94,49.63 114.59,49.63 114.42,49.8 114.25,49.8 114.02,49.57 114.02,49.39 114.19,49.23 114.19,48.88 113.65,48.34 99.78,48.34 95.71,52.41 92.5,52.41 90.85,54.06
  BOTTOM w0.089: v2(88.75,55.4) 88.5,55.65 CPU1.AL43
  BOTTOM w0.102: DIMM1.62 v2(130.44,52.65)
M_A_DQS#7: length 79
  TOP w0.102: v2(129.8,91.64) 129.8,91.72 v1(130.25,92.17)
  L3 w0.089: v2(88.83,52.57) 88.73,52.47 88.73,52.24 88.88,52.09 91.96,52.09 92.25,52.39 92.25,52.41 92.27,52.43
  L3 w0.114: v2(129.8,91.64) 129.59,91.86 129.59,92.22 129.38,92.43 120.23,92.43 103.91,76.1 103.91,59.19 102.8,58.09 102.8,57.74 103.04,57.5 103.04,57.32 102.82,57.09 102.64,57.09 102.4,57.33 102.05,57.33 101.67,56.96 101.67,56.61 102.2,56.08 102.2,55.92 101.95,55.68 101.79,55.68 101.27,56.2 100.91,56.2 100.54,55.83 100.54,55.48 101.06,54.95 101.06,54.79 100.82,54.54 100.66,54.54 100.13,55.07 99.78,55.07 99.41,54.69 99.41,54.34 99.93,53.82 99.93,53.66 99.69,53.41 99.53,53.41 99,53.94 98.65,53.94 97.49,52.77 92.62,52.77 92.27,52.43
  BOTTOM w0.089: v2(88.83,52.57) 88.5,52.89 CPU1.AL48
  BOTTOM w0.102: v2(129.8,91.64) 129.8,91.99 130.27,92.45 130.62,92.45 130.82,92.25 DIMM1.186
M_A_RAS#: length 47.3
  TOP w0.178: v2(130.44,69.45) 130.97,69.45 v1(131.01,69.41)
  L4 w0.203: v2(130.44,69.45) 130.81,69.45 131.01,69.65 131.01,70.15 130.4,70.76 124.49,70.76 122.56,72.69 122.13,72.69 120.56,74.26 111.9,74.26 111.04,73.41 108.96,73.41 99.63,64.08 98.56,64.08 96.36,61.88 94.99,61.88 94.56,61.44 v2(94.56,61.39)
  BOTTOM w0.178: DIMM1.110 v2(130.44,69.45) ; CPU1.AY34 94.21,61.74 v2(94.56,61.39)
M_A_WE#: length 48.1
  TOP w0.178: v1(94.04,61.93) 93.89,61.79 v2(93.89,61.39)
  L4 w0.203: v2(127.7,72.51) 127.7,71.79 127.33,71.42 124.55,71.42 122.99,72.98 122.99,73.55 121.77,74.77 111.69,74.77 110.83,73.91 108.75,73.91 99.42,64.58 98.35,64.58 96.15,62.39 94.78,62.39 93.89,61.49 v2(93.89,61.39)
  BOTTOM w0.178: v2(127.7,72.51) 127.7,72.38 125.67,70.35 DIMM1.113 ; v2(93.89,61.39) 93.56,61.72 CPU1.AW34
M_VREF_CA_DIMMA: length 1.6
  BOTTOM w0.33: DIMM1.126 130.33,74.25 v3(130.3,74.22)
  vias: v1(136.09,68.01) v2(137.67,66.26) v2(137.67,65.5)
M_VREF_DQ_DIMMA: length 1.7
  BOTTOM w0.305: v3(125.35,34.13) 125.13,34.35 DIMM1.1
  vias: v1(125.45,33.39)
MCP_GPIO0: length 2
  TOP w0.102: TP2007.1 77.87,78.98 77.87,79.98 v2(77.67,80.17)
  BOTTOM w0.102: v2(77.67,80.17) 77.37,79.86 CPU1.K4
MCP_GPIO1: length 2.3
  TOP w0.102: v2(75.69,82.5) 75.58,82.39 TP2009.1
  BOTTOM w0.102: v2(75.69,82.5) 76.1,82.09 76.1,81.46 CPU1.G2
MCP_GPIO8: length 42.6
  TOP w0.102: R2017.2 85.6,87.72 87.5,85.82 v1(87.5,82.24) 87.71,82.04 91.41,82.04 92.25,82.87 93.07,82.87 v2(93.73,83.53) ; R2027.1 v2(87.5,100.04)
  L3 w0.102: v2(87.5,100.04) 85.72,98.27 85.72,95.63 87.71,93.64 90.38,93.64 90.75,93.27 90.75,92.59 89.48,91.32 89.48,85.06 90.5,84.04 93.22,84.04 v2(93.73,83.53)
  BOTTOM w0.089: 91.96,82.42 91.96,82.25 91.92,82.21 91.92,81.55 92.23,81.24 CPU1.AU2
  BOTTOM w0.102: 91.96,82.42 91.96,82.55 92.26,82.85 92.69,82.85 93.37,83.53 v2(93.73,83.53)
MCP_GPIO11: length 11
  BOTTOM w0.089: 89.9,82.14 89.76,82.01 89.76,81.45 CPU1.AN2
  BOTTOM w0.102: 89.9,82.14 89.9,82.71 89.33,83.28 89.33,84.22 88.27,85.29 v1(88.27,90.14) 88.27,90.49 88.16,90.6 RN1809.5
MCP_GPIO12: length 9
  TOP w0.102: RN2006.4 93.87,81.68 93.38,81.2 v1(93.34,81.2) 92.66,80.51 92.66,80.43 91.97,79.74 91.97,79.33 91.56,78.92 89.81,78.92 89.8,78.9 89.12,78.9 v2(88.68,78.47)
  BOTTOM w0.102: v2(88.68,78.47) 88.68,78.4 CPU1.AM7
MCP_GPIO13: length 16.3
  TOP w0.102: v2(92.43,83.48) 91.27,82.32 90.14,82.32 89.56,82.9 v1(88.82,82.9) 88.82,82.98 87.76,84.04 87.76,86.07 86.36,87.47 86.36,89.06 R2019.2
  BOTTOM w0.089: CPU1.AT3 91.84,80.77 91.84,81.29 91.67,81.46 91.45,81.46 91.26,81.65 91.26,82.09 91.38,82.21
  BOTTOM w0.102: 91.38,82.21 91.58,82.41 91.58,82.73 92.33,83.48 v2(92.43,83.48)
MCP_GPIO14: length 11.6
  TOP w0.102: v1(87.35,79.8) 87.35,79.75 v2(86.97,79.37) 86.77,79.37 86.23,79.9 86.23,81.12 85.17,82.19 85.17,85.11 82.55,87.72 R2015.2
  BOTTOM w0.102: CPU1.AH4 87.09,79.49 v2(86.97,79.37)
MCP_GPIO15: length 15.3
  TOP w0.102: v2(82.68,91.28) 82.04,91.92 R2014.2
  L3 w0.102: v2(82.68,91.28) 82.68,90.39 83.39,89.68 83.39,82.89 83.68,82.59 83.68,79.15 v2(84.11,78.72)
  BOTTOM w0.102: v1(83.21,91.62) 83.01,91.62 v2(82.68,91.28) ; CPU1.AD6 84.31,78.53 v2(84.11,78.72)
MCP_GPIO16: length 3.6
  BOTTOM w0.089: CPU1.Y1 82.55,82.04 82.37,82.22 82.37,83.49 82.38,83.49 82.38,83.66 82.04,83.99 TP2008.1
MCP_GPIO17: length 20.3
  BOTTOM w0.089: 79.63,83.93 79.63,82.3 79.88,82.05 79.88,81.63 80.02,81.49 80.02,80.76 CPU1.T3
  BOTTOM w0.102: RN1505.6 66.77,86.83 67.43,86.18 69.52,86.18 70.31,85.38 73.15,85.38 v1(73.34,85.57) 73.63,85.86 78.5,85.86 79.63,84.74 79.63,83.93
MCP_GPIO26: length 13.3
  TOP w0.102: v2(90.02,83.84) 88.34,83.84 88.09,84.09 88.09,86.12 86.69,87.52 v1(86.69,90.04) 86.21,90.52 R2009.2
  BOTTOM w0.089: CPU1.AN3 90.33,80.76 90.33,82.95 90.42,83.04 90.42,83.24 90.42,83.24 90.42,83.44 v2(90.02,83.84)
MCP_GPIO27: length 11
  TOP w0.102: R2005.2 97.22,82.9 96.1,82.9 RN2006.3 94.2,82.34 94.06,82.19 v1(94.05,82.19) 93.29,82.19 92.35,81.25 90.99,81.25 90.3,80.56 90.3,80.2 89.85,79.75 89.74,79.75 v2(89.33,79.34)
  BOTTOM w0.102: v2(89.33,79.34) 89.66,79.01 CPU1.AN5
MCP_GPIO28: length 14.2
  TOP w0.102: R2016.2 80.64,87.81 84.51,83.95 84.51,82.97 84.35,82.81 v1(84.35,81.88) 84.35,79.95 84.63,79.67 84.63,78.59 v2(84.11,78.08)
  BOTTOM w0.102: v2(84.11,78.08) 84.31,77.88 CPU1.AD7
MCP_GPIO35: length 19.7
  BOTTOM w0.102: RN1505.5 66.41,87.48 67.5,86.39 67.78,86.39 67.8,86.38 69.61,86.38 70.4,85.59 71.89,85.59 v1(72.15,85.85) 72.38,86.07 78.59,86.07 79.95,84.71 79.95,83.81 80.8,82.96 80.8,82.8 81.05,82.55 CPU1.U1
MCP_GPIO36: length 20.2
  TOP w0.102: v2(81.26,78.71) 81.69,79.14 81.69,82.52 80.92,83.29 80.92,84.85 79.63,86.14 74.51,86.14 v1(72.45,88.19) 71.98,88.66 70.28,88.66 69.97,88.35 RN2002.5
  BOTTOM w0.102: CPU1.V6 81.44,78.53 v2(81.26,78.71)
MCP_GPIO37: length 10.1
  TOP w0.102: RN1801.3 78.13,87.65 78.33,87.45 78.84,87.45 78.85,87.44 80.2,87.44 82.23,85.41 82.23,85.21 v1(83.31,84.13) 83.78,83.66 v2(83.87,83.66)
  BOTTOM w0.102: CPU1.AC1 84.05,83.48 v2(83.87,83.66)
MCP_GPIO38: length 3.9
  BOTTOM w0.089: TP2006.1 77.44,83.53 77.44,82.11 77.46,82.09 77.59,81.96 77.59,81.51 77.94,81.16 CPU1.L2
MCP_GPIO44: length 12.4
  TOP w0.102: v2(86.36,85.57) v1(85.72,85.57) 85.22,85.57 83.19,87.6 R2002.2
  BOTTOM w0.089: CPU1.AK4 87.47,80.15 87.47,80.83 87.51,80.86 87.51,82.16 87.49,82.18 87.49,83.22
  BOTTOM w0.102: v2(86.36,85.57) 87.49,84.44 87.49,83.22
MCP_GPIO45: length 12.6
  TOP w0.102: R2028.2 81.92,87.71 v1(83.43,86.19) 84.96,84.66 84.96,81.94 86,80.9 v2(86,79.43)
  BOTTOM w0.102: CPU1.AG5 86.25,79.18 v2(86,79.43)
MCP_GPIO46: length 29
  TOP w0.102: R2004.2 83.82,87.47 85.22,86.07 86.49,86.07 86.85,85.71 86.85,82.25 v1(86.36,81.76) 86.36,81.5 86.68,81.19 v2(86.68,80.81) ; v2(78.87,94.07) 78.36,94.58 R2026.1
  L4 w0.102: v2(86.68,80.81) 86.62,80.81 84.96,82.47 84.96,89.88 84.25,90.6 84.25,91.46 82.53,93.19 79.76,93.19 v2(78.87,94.07)
  BOTTOM w0.102: v2(86.68,80.81) 86.38,80.51 CPU1.AG3
MCP_GPIO47: length 12.2
  TOP w0.102: v2(83.16,78.71) 83.59,79.14 83.59,79.54 83.49,79.64 v1(83.49,80.44) 83.49,82.24 84.3,83.05 84.3,83.86 80.25,87.92 R2020.2
  BOTTOM w0.102: v2(83.16,78.71) 83.34,78.53 CPU1.AB6
MCP_GPIO50: length 10.9
  TOP w0.102: v2(79.18,80.17) 78.38,80.96 78.38,81.01 77.64,81.76 v1(77.34,81.76) 77.32,81.78 70.11,81.78 RN2011.8
  BOTTOM w0.102: v2(79.18,80.17) 79.52,80.51 CPU1.P3
MCP_GPIO51: length 14.1
  TOP w0.102: v2(78.34,78.83) 78.4,78.83 78.85,79.28 78.85,79.89 v1(78.5,80.24) 78.18,80.56 78.18,80.93 77.71,81.4 77.2,81.4 77.02,81.58 69.28,81.58 69.08,81.78 RN2011.7
  BOTTOM w0.102: v2(78.34,78.83) 78.37,78.86 79.51,78.86 CPU1.R5
MCP_GPIO52: length 13.9
  BOTTOM w0.102: RN1506.6 74.57,84.42 75.22,85.06 77.48,85.06 v1(77.73,84.81) 77.83,84.72 77.83,83.27 77.83,83.26 77.83,82.24 78.06,82.01 CPU1.L1
MCP_GPIO54: length 15.1
  BOTTOM w0.089: CPU1.L3 78.1,80.69 78.34,80.94 78.34,81.34 78.18,81.5 77.87,81.5 77.77,81.6 77.77,82.04 77.64,82.17 77.64,83.84 77.57,83.91
  BOTTOM w0.102: 77.57,83.91 76.94,84.54 76.61,84.87 75.3,84.87 74.62,84.19 68.74,84.19 68.46,83.92 v1(68.35,83.92) RN1506.7
MCP_GPIO55: length 19.5
  TOP w0.102: RN1902.4 70.09,86.34 70.48,85.95 71.69,85.95 R2008.1 71.92,86.17 73.53,86.17 73.97,85.73 79.47,85.73 80.52,84.68 80.52,81.95 v1(80.85,81.63) 81.1,81.37 81.1,79.96 80.72,79.58 80.72,78.48 v2(80.31,78.07)
  BOTTOM w0.102: v2(80.31,78.07) 80.5,77.88 CPU1.U7
MCP_GPIO56: length 11.7
  TOP w0.102: R2010.2 81.28,87.72 v1(82.32,86.69) 84.71,84.3 84.71,81.9 85.61,81 85.61,79.98 85.57,79.94 85.57,79.17 v2(86.02,78.72)
  BOTTOM w0.102: CPU1.AG6 86.21,78.53 v2(86.02,78.72)
MCP_GPIO59: length 19
  TOP w0.102: v1(91.86,80.14) 91.41,79.68 v2(91.41,79.38) ; RN2012.5 86.63,93.07 v2(86.49,92.93)
  L3 w0.102: v2(86.49,92.93) 87,92.42 87.25,92.42 88.27,91.41 88.27,86.96 88.65,86.58 88.65,82.46 90.67,80.44 90.67,80.07 91.36,79.38 v2(91.41,79.38)
  BOTTOM w0.102: v2(91.41,79.38) 91.61,79.17 CPU1.AT5
MCP_GPIO68: length 10.3
  BOTTOM w0.089: TP2019.1 65.09,79.53 66.94,79.53 67.89,80.49 68.71,80.49 70.04,81.82 72.15,81.82 72.51,81.46 72.51,81.02 72.89,80.64 CPU1.C3
MCP_GPIO70: length 5.9
  BOTTOM w0.089: CPU1.C4 72.86,80.04 72.57,80.33 72.57,80.7 72.38,80.89 72.26,80.89 71.94,80.89 71.75,81.08 70.06,81.08 TP2005.1
MCP_GPIO73: length 18.4
  BOTTOM w0.089: 94.82,81.27 94.42,80.87 93.95,80.87 93.9,80.82 93.39,80.82 93.2,80.63 93.2,80.38 93.02,80.19 92.59,80.19 CPU1.AU4
  BOTTOM w0.102: 94.82,81.27 97.16,83.61 97.16,83.62 97.16,84.01 97.29,84.14 97.29,87.27 v1(96.39,88.17) 96.06,88.5 96.06,88.63 93.43,91.27 93.43,91.67 92.68,92.42 RN1601.6
MCP_GPIO90: length 4
  BOTTOM w0.089: TP2014.1 76.61,83.15 76.61,82.49 76.84,82.25 76.84,81.85 77.31,81.38 CPU1.K2
MCP_R: length 12.7
  TOP w0.102: R2015.1 82.55,90.58 ; 82.55,90.58 R2002.1 ; 82.55,90.58 R2028.1 81.28,90.58 ; R2020.1 79.73,89.08 v1(79.73,89.76) 79.73,89.99 80.33,90.58 R2016.1 81.28,90.58 ; R2002.1 84.84,90.58 R2009.1 R2019.1 ; R2002.1 83.19,91.41 82.93,91.66 R2022.2 ; 81.28,90.58 R2010.1
MCP_TESTLOW1: length 8.2
  TOP w0.102: RN1803.3 67.25,59.71 v2(67.31,59.66) 67.54,59.43 v1(68.12,59.43)
  BOTTOM w0.089: 69.04,59.28 69.98,60.22 71.42,60.22 71.7,60.49 71.87,60.56 71.97,60.56 72.11,60.5 72.11,60.5 72.13,60.5 72.22,60.48 72.38,60.51 72.57,60.6 72.63,60.68 CPU1.C35
  BOTTOM w0.102: 69.04,59.28 67.69,59.28 v2(67.31,59.66)
MCP_TESTLOW2: length 8.6
  TOP w0.102: v1(67.84,60.62) 67.64,60.62 v2(67.31,60.29) 67.24,60.36 RN1803.4
  BOTTOM w0.089: 71.3,60.4 71.5,60.6 71.83,60.74 72.01,60.74 72.15,60.67 72.29,60.67 72.33,60.68 72.45,60.74 72.49,60.79 72.53,60.84 72.63,61.17 CPU1.C34
  BOTTOM w0.102: 71.3,60.4 69.83,60.4 68.96,59.53 68.07,59.53 v2(67.31,60.29)
MCP_TESTLOW3: length 26.6
  TOP w0.102: v1(105.67,86.2) 105.79,86.32 v2(105.79,86.84) 106.17,86.84 106.62,87.29 RN1804.4
  L3 w0.102: v2(105.79,86.84) 104.11,85.16 104.11,83.02 97.85,76.75 94.47,76.75 93.63,75.91 89.33,75.91 v2(88.42,76.83)
  BOTTOM w0.102: v2(88.42,76.83) 88.42,76.93 88.04,77.31 CPU1.AK8
MCP_TESTLOW4: length 25.3
  TOP w0.102: v1(104.5,86.57) 104.77,86.84 v2(105.16,86.84) 105.16,87.34 105.57,87.76 RN1804.3
  L3 w0.102: v2(105.16,86.84) 103.86,85.54 103.86,83.18 97.69,77.01 94.44,77.01 93.55,76.12 89.76,76.12 v2(89.05,76.83)
  BOTTOM w0.102: CPU1.AL8 88.69,77.19 v2(89.05,76.83)
MCU_BOOT0: length 3.9
  TOP w0.152: U6601.44 100.45,100.31 v1(100.84,99.92) 100.9,99.85 R6606.1
MCU_OSCI: length 7.9
  TOP w0.114: X6601.1 108.79,103.99 105.87,103.99 C6601.1 105.35,103.94 104.53,104.75 U6601.5
MCU_OSCO: length 5.6
  TOP w0.114: U6601.6 105.22,105.26 C6609.1 105.85,104.62 107.42,104.62 X6601.3
MCU_RST#: length 4.6
  TOP w0.152: U6601.7 v1(104.45,105.75) 104.96,105.75 C6602.1 106.17,106.97 R6602.1 R6603.1
ME_UNLOCK: length 151.6
  TOP w0.102: KBC24.23 148.41,44.36 148.46,44.41 150.12,44.41 150.75,43.78 151.13,43.78 v2(151.64,43.27) ; R1909.1 105.69,76.68 105.74,76.72 108.4,76.72 112.26,80.57 112.26,91.4 111.82,91.83 111.82,98.62 112.85,99.64 112.85,103.66 v2(112.39,104.11) ; v2(147.07,71.21) 144.57,71.21 141.03,74.75 141.03,81.48 137.39,85.12 137.39,96.85 129.52,104.73 122.93,104.73 121.66,103.46 115.7,103.46 113.8,105.36 v2(113.8,106.64)
  BOTTOM w0.102: v2(112.39,104.11) 113.8,105.51 v2(113.8,106.64) ; v2(147.07,71.21) 147.07,70.33 147.65,69.74 151.71,69.74 158.37,63.09 v1(158.37,62.84) 158.62,62.58 158.62,59.83 160.4,58.06 160.4,57.52 161.87,56.06 162.36,56.06 162.99,55.43 162.99,53.77 162.5,53.28 162.5,45.52 160.66,43.68 152.04,43.68 v2(151.64,43.27)
MIC2_VREFO: length 13.4
  TOP w0.203: HDA27.29 19.97,25.71 v2(19.94,25.75)
  TOP w0.254: RN2901.1 24.89,32.86 v2(24.89,32.86) 24.51,32.86 24.24,32.59 RN2901.2
  L4 w0.254: v2(24.89,32.86) 23.88,31.84 22.73,31.84 19.94,29.05 v2(19.94,25.75)
  BOTTOM w0.254: v2(24.89,32.86) 24.89,32.35 v1(25.02,32.23)
MIC_CAP: length 3.1
  TOP w0.203: HDA27.19 23.68,29.47 23.57,29.57
  TOP w0.254: 23.57,29.57 v1(23.24,29.9) 22.86,30.28 C2713.1
MIC_GND: length 3.2
  TOP w0.203: v1(57,95.45) 56.97,95.47 v2(56.13,95.47)
  TOP w0.508: v2(56.13,95.47) 56.32,95.28 R5202.1
  BOTTOM w0.305: LCD1.20 56.05,95.39 v2(56.13,95.47)
MODEL_ID_DET: length 6.9
  TOP w0.102: KBC24.94 163.8,52.36 164.8,53.35 v1(164.8,54.37) 164.59,54.58 C2403.2 R2407.1 R2405.2
MPWROK: length 41.9
  TOP w0.102: R1707.2 98.49,91.98 v2(98.3,91.79) ; v2(82.04,96.11) v1(82.04,96.74)
  L3 w0.102: v2(82.04,96.11) 82.47,95.68 82.47,94.89 81.61,94.02 81.61,85.77 83.08,84.3 83.08,83.07 82.71,82.7 82.71,81.93 83.16,81.48 v2(83.16,79.36)
  L4 w0.102: v2(98.3,91.79) 98.3,91.52 98.07,91.29 97.27,91.29 96.34,92.22 96.34,96.41 96.01,96.74 86.36,96.74 85.73,96.11 v2(82.04,96.11)
  BOTTOM w0.102: v2(83.16,79.36) 83.34,79.18 CPU1.AB5
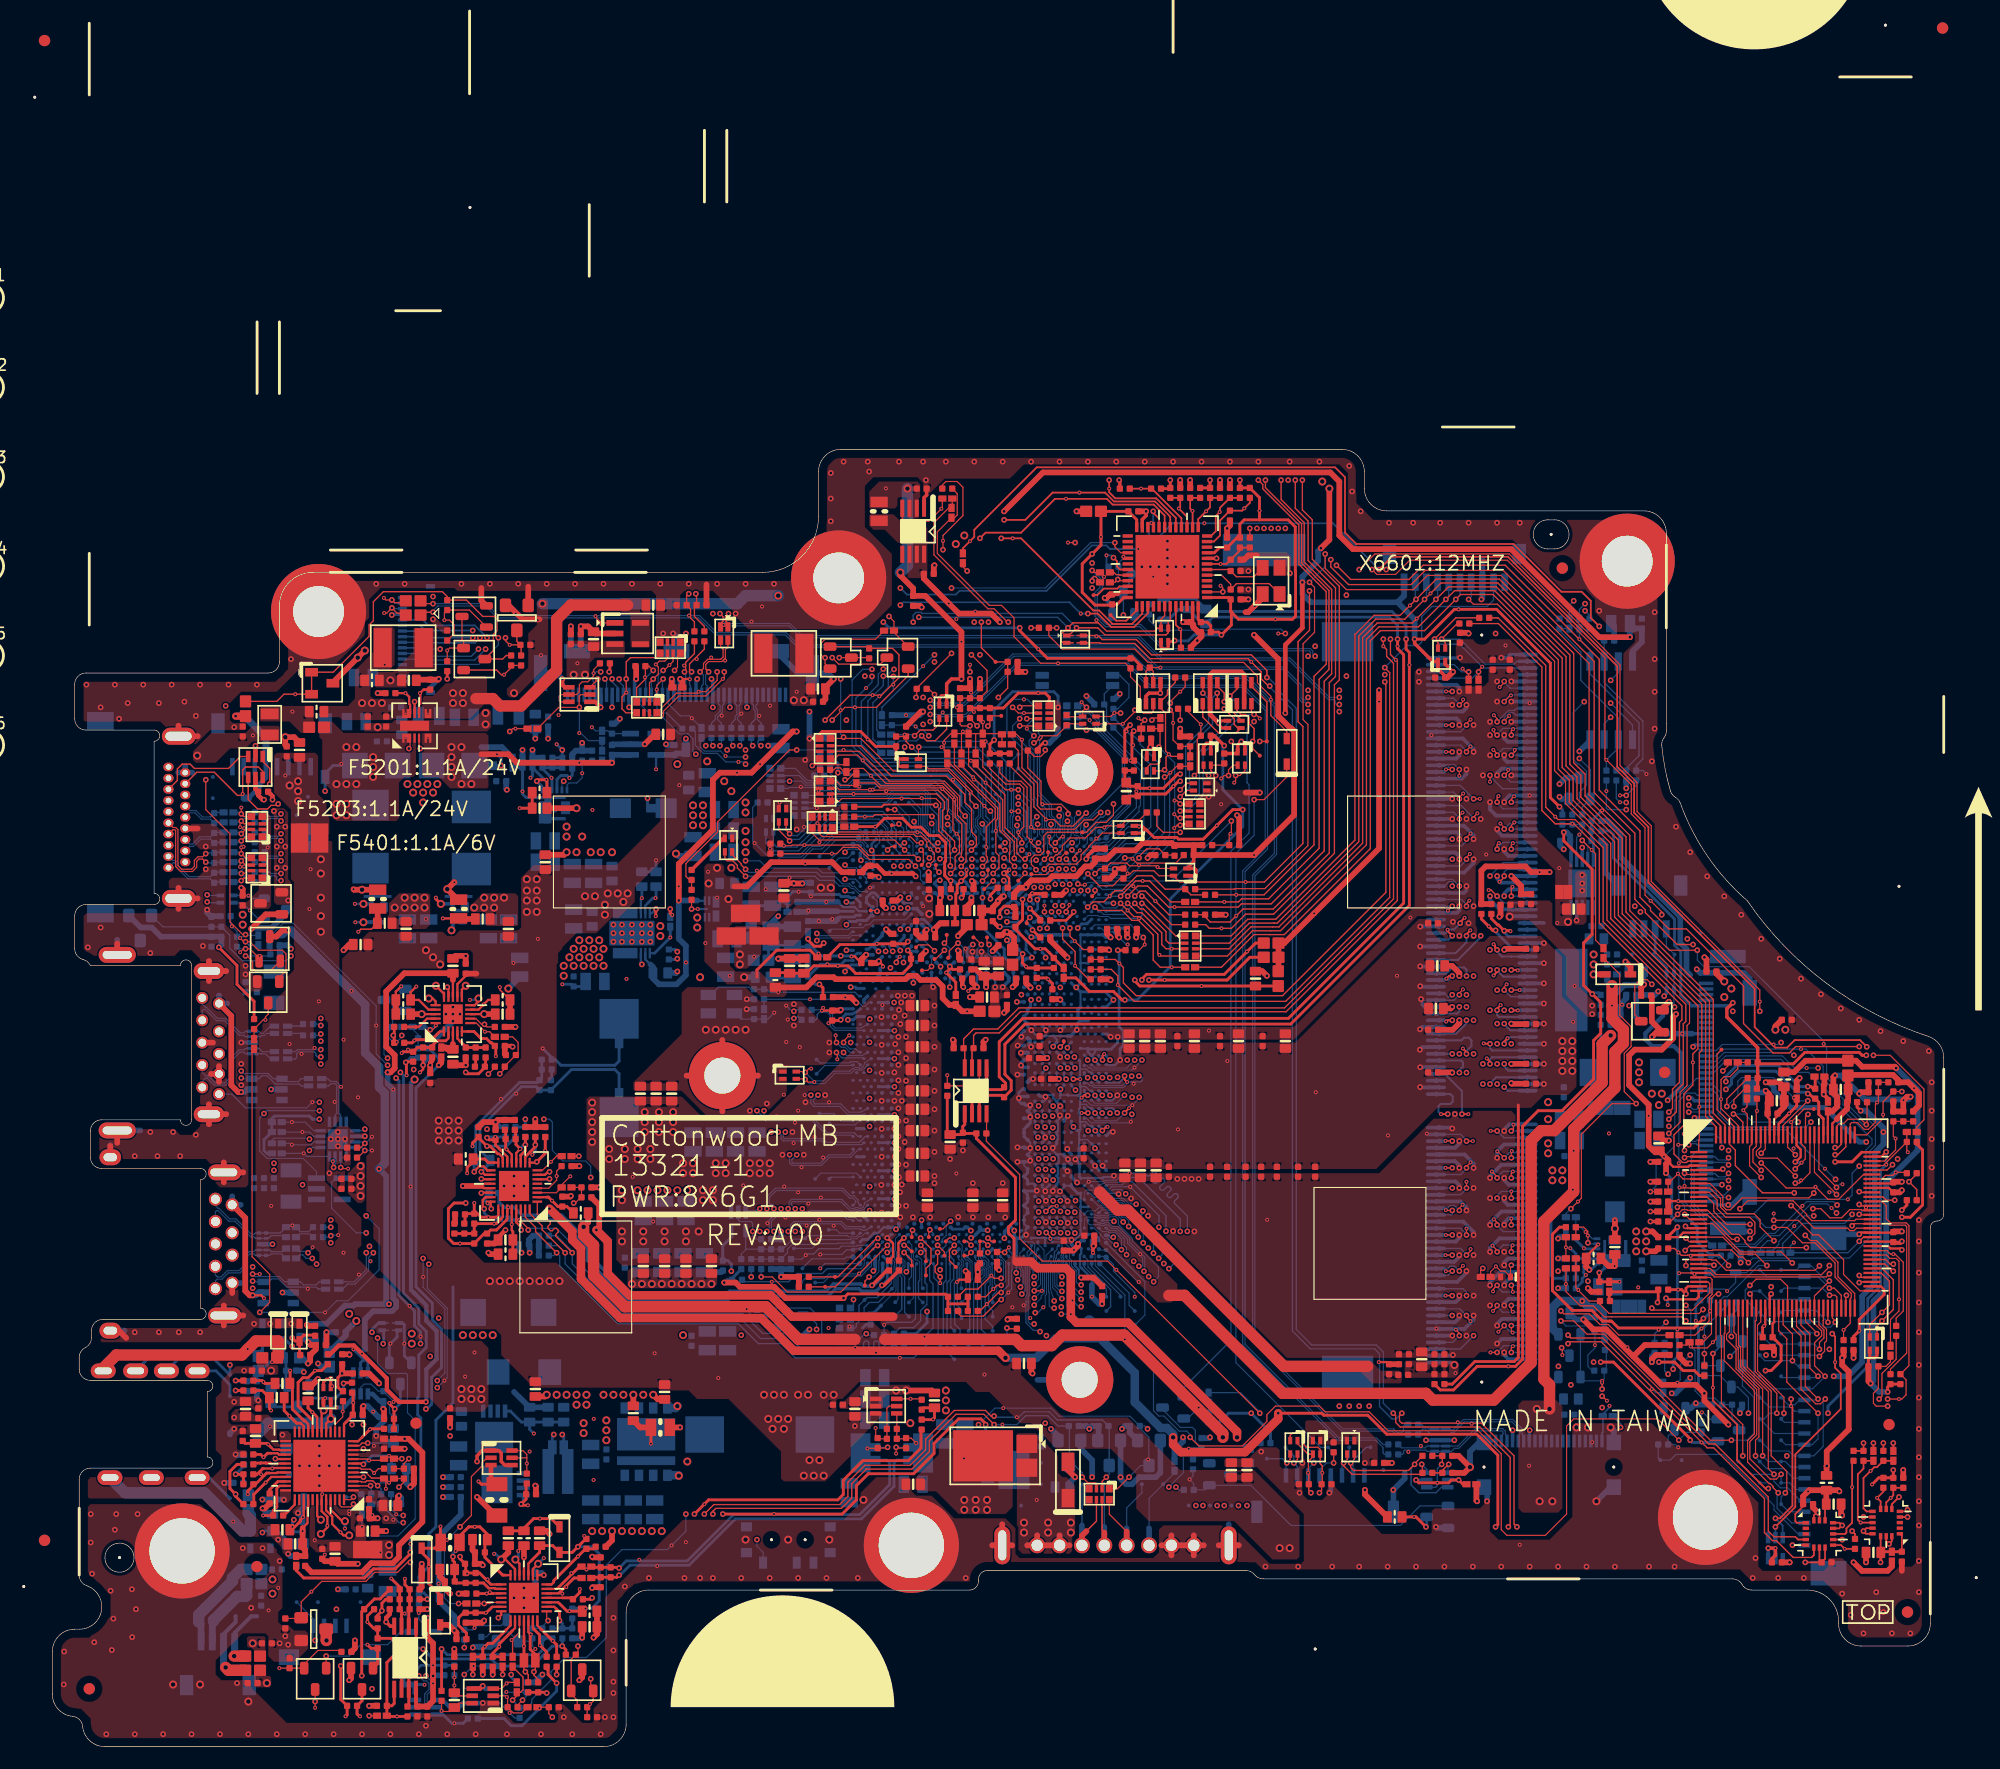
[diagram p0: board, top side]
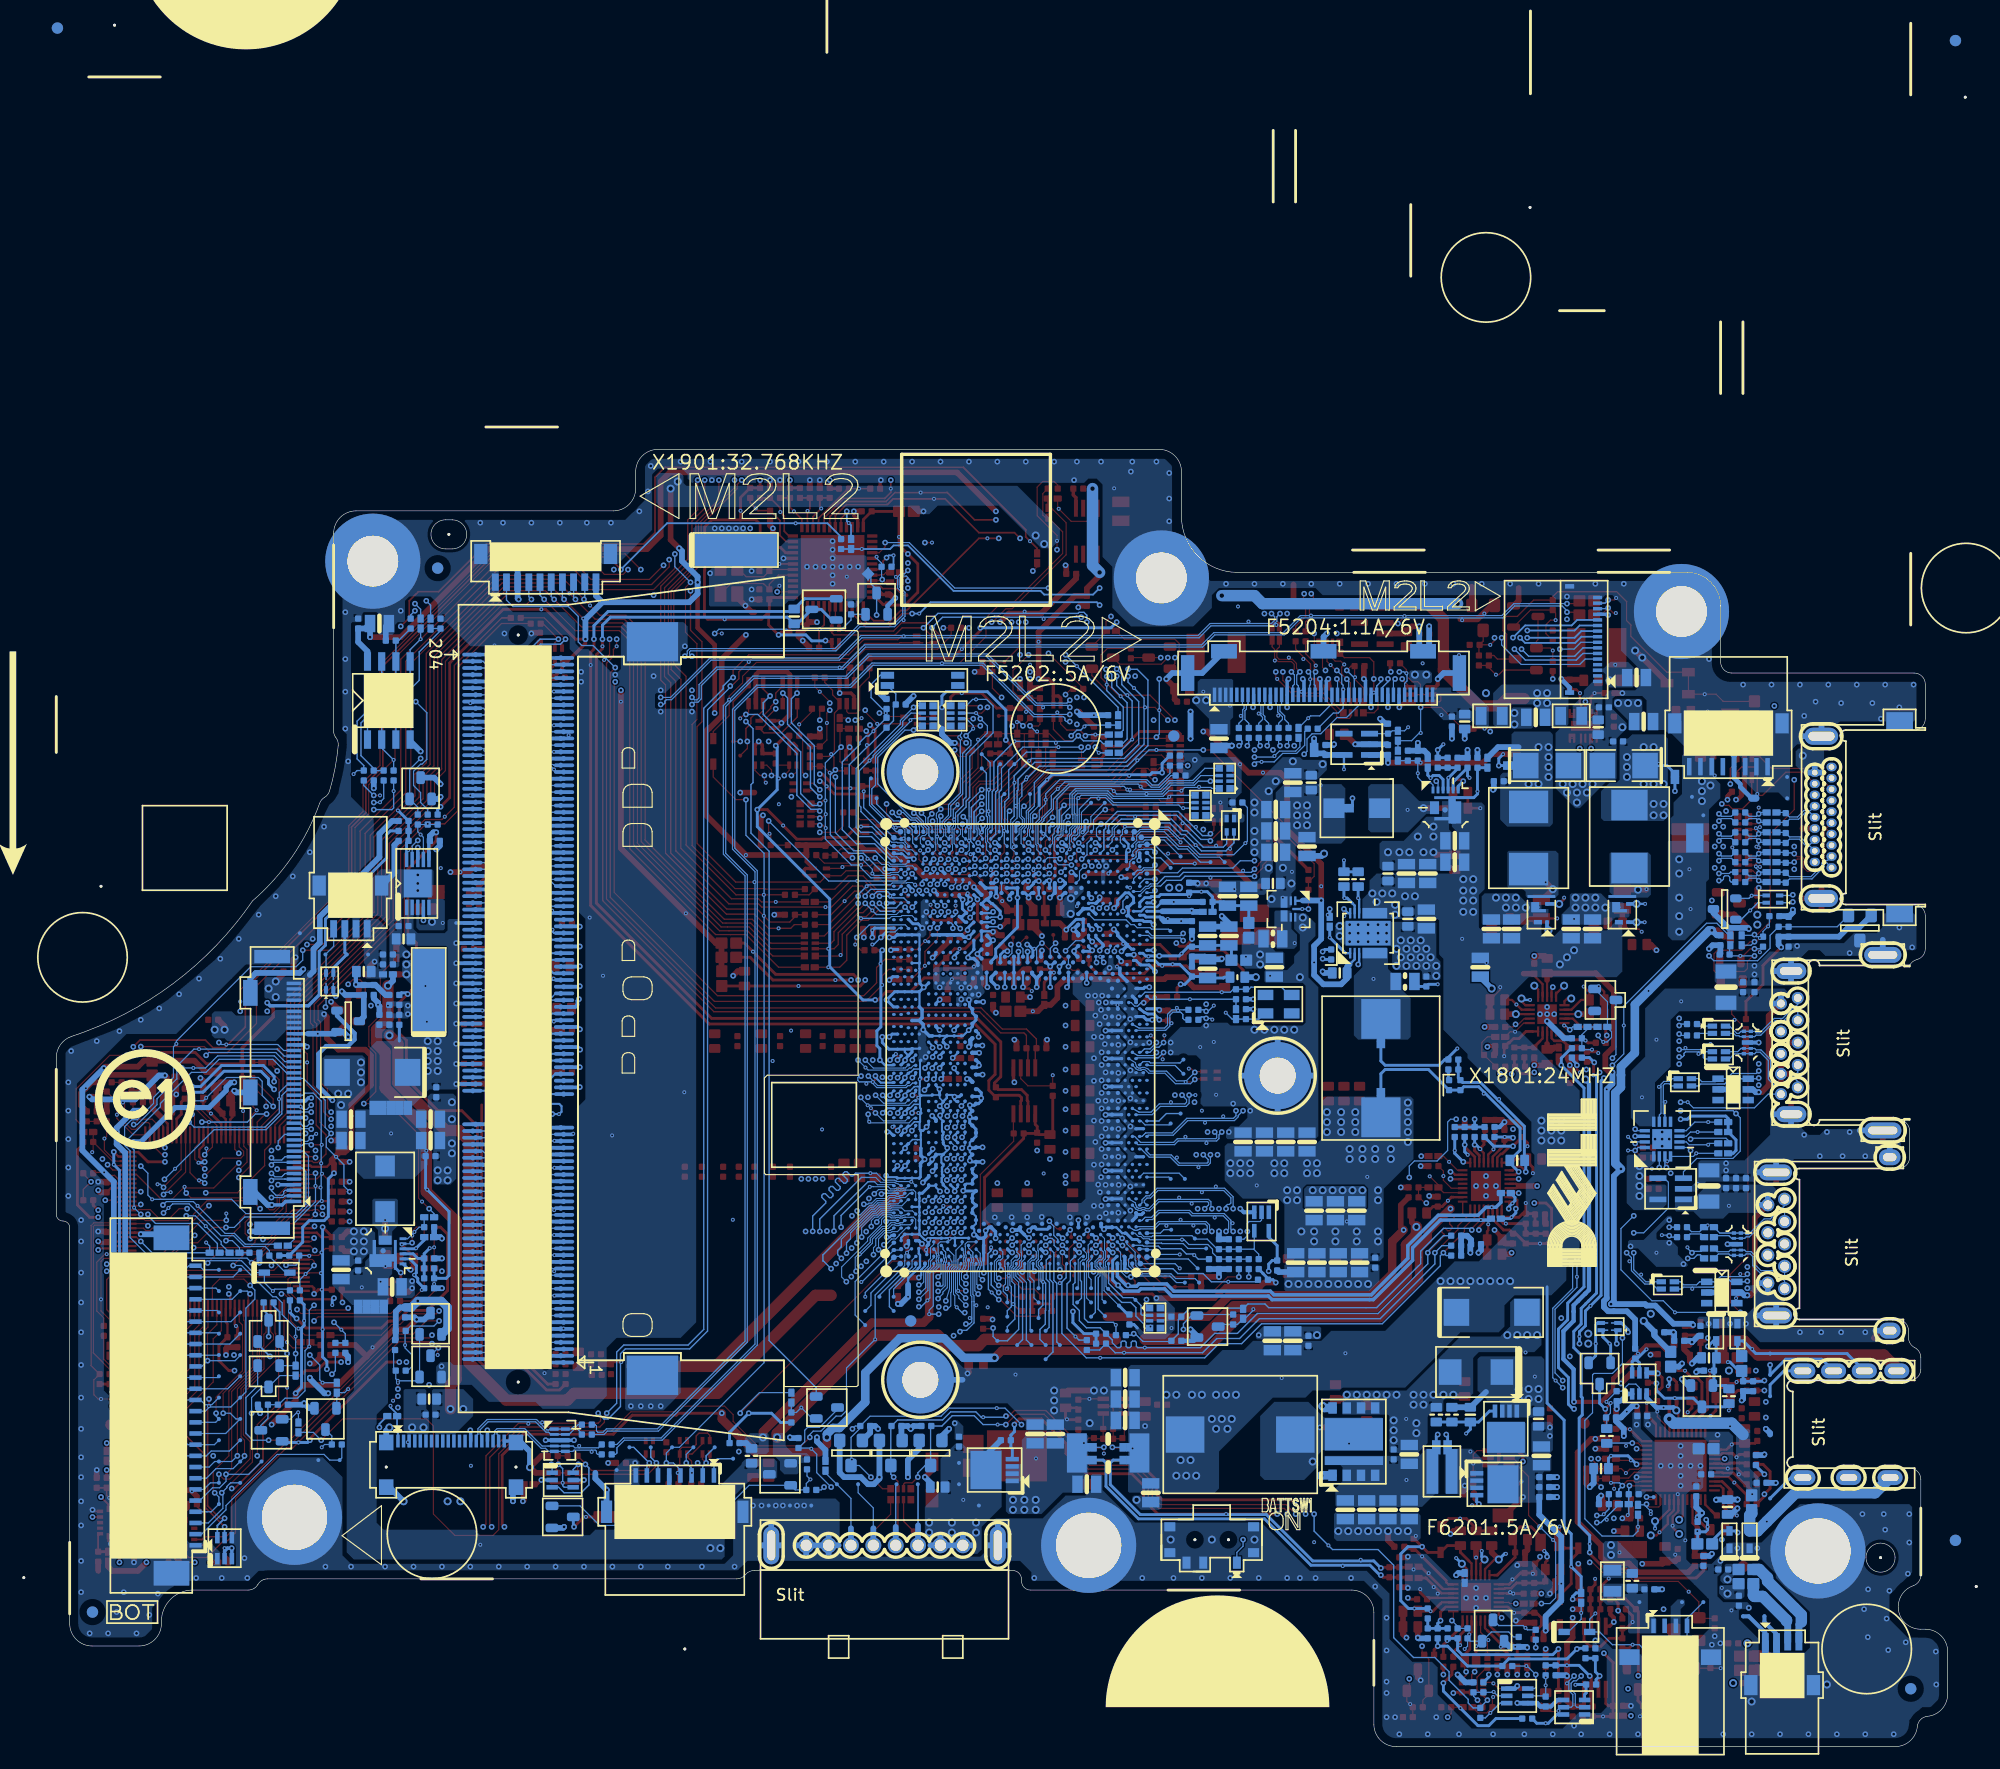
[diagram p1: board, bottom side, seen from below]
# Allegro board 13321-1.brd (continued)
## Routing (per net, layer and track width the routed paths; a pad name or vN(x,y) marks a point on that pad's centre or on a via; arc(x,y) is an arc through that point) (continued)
MUTE_CTRL: length 7
  BOTTOM w0.102: R2917.2 30.48,29.37 R2918.2 30.15,29.83 30.15,30.47 v1(30.51,30.83) 30.51,30.87 C2901.1 29.15,31.78 28.51,32.42 27.88,32.42 27.56,32.1 U2901.2
NC#4: length 3.5
  TOP w0.102: PU4601.4 44.38,49.93 45.09,50.64 v1(45.09,51.02) 45.09,51.47 PR4626.1
NCT7718_DXN: length 98.3
  TOP w0.254: v2(121.03,99.03) 121.03,98.14 121.32,97.85 v1(121.32,96.72) 121.32,75.22 110.72,64.61 86.97,64.61 85.16,62.81 85.16,60.11 85.72,59.55 85.72,58.71 C2607.2 84.92,58.24 83.01,58.24 82.8,58.04 82.8,57.78 82.88,57.71 THM261.3
  BOTTOM w0.254: Q2603.E 102.2,102.64 C2606.2 103.34,101.5 119.76,101.5 121.03,100.24 v2(121.03,99.03)
NCT7718_DXP: length 97.9
  TOP w0.254: THM261.2 82.22,57.71 82.3,57.78 82.3,58.25 82.8,58.75 84.88,58.75 C2607.1 85.22,59.09 85.22,59.34 84.66,59.9 84.66,63.02 86.76,65.12 110.51,65.12 120.82,75.43 120.82,97.64 120.27,98.18 v1(120.27,98.39) v2(120.27,99.03)
  BOTTOM w0.254: v2(120.27,99.03) 120.27,100.28 119.55,101 103.72,101 C2606.1 102.84,100.4 Q2603.C 100.71,101.69 99.76,100.75 Q2603.B
P_SYS: length 159.4
  TOP w0.203: v2(163.96,53.18) 163.53,52.76 KBC24.95
  TOP w0.254: PR4467.2 v2(40.26,6.44)
  L4 w0.254: v2(40.26,6.44) 41.27,7.46 42.25,7.46 46.1,11.31 46.1,15.55 48.71,18.15 59.56,18.15 62.07,20.67 70.25,20.67 72.89,23.31 78.88,23.31 80.18,24.61 101.51,24.61 102.15,23.97 121.07,23.97 121.71,23.34 125.95,23.34 126.65,24.03 131.64,24.03 134.75,27.15 140.84,27.15 143,29.3 158.24,29.3 v2(158.75,29.81)
  BOTTOM w0.254: v2(158.75,29.81) 158.75,30.45 162.31,34 162.31,40.06 163.45,41.2 163.45,51.53 v1(163.96,52.04) v2(163.96,53.18)
PANEL_SIZE: length 190.1
  TOP w0.102: v2(157.99,43) 157.58,42.59 149.66,42.59 148.74,43.51 148.38,43.51 148.33,43.56 KBC24.25 146.21,43.56 146.05,43.4 v2(146.05,43.02)
  L3 w0.102: v2(49.02,96.11) 48.79,96.11 48.34,95.65 48.34,95.29 48.6,95.03 68.39,95.03 69.47,96.11 71.04,96.11 77.29,102.36 77.29,106.07 82.32,111.09 114.21,111.09 117.41,107.89 130.1,107.89 131.34,106.69 131.49,106.54 131.49,106.54 131.88,106.15 132.32,105.68 132.39,105.62 136.61,103.71 136.61,103.71 138.23,102.86 138.62,102.65 140.82,100.45 141.54,99.73 141.54,87.02 142.16,86.39 142.16,80.27 158.8,63.64 158.8,57.91 158.34,57.46 158.34,43.35 v2(157.99,43)
  BOTTOM w0.102: v2(146.05,43.02) v1(146.81,42.26) 147.32,41.75 R2452.2 ; LCD1.35 48.55,95.08 48.34,95.29 48.34,95.83 48.62,96.11 v2(49.02,96.11)
PBAT_PRES1#: length 10.8
  TOP w0.102: RN4301.8 94.5,20.78 96.05,19.23
  TOP w0.508: BATT1.5 96.05,19.23
  BOTTOM w0.102: 96.05,19.53 96.05,21.34 97.41,22.7 AFTP4301.1
  BOTTOM w0.508: BATT1.5 96.05,19.53
PBAT_SMBCLK1: length 10.1
  TOP w0.114: RN4301.6 93.35,20.16 92.46,19.27
  TOP w0.508: 92.46,19.27 92.05,18.87 BATT1.3
  BOTTOM w0.114: 92.05,19.78 92.05,23.44 AFTP4303.1
  BOTTOM w0.508: BATT1.3 92.05,19.78
PBAT_SMBDAT1: length 9.7
  TOP w0.114: RN4301.7 93.85,19.35 94.05,19.14
  TOP w0.508: BATT1.4 94.05,19.14
  BOTTOM w0.114: AFTP4302.1 94.05,23.39 94.05,19.65
  BOTTOM w0.508: BATT1.4 94.05,19.65
PCB_VER_AD: length 8.4
  TOP w0.102: R2404.2 R2406.1 C2402.2 163.26,57.71 v1(163.14,57.6) 162.99,57.45 162.99,55.83 162.36,55.2 162,55.2 161.4,55.8 160.86,55.8 160.74,55.68 KBC24.98
PCH_DPWROK: length 15.5
  TOP w0.102: v2(99.44,86.71) 99.57,86.71 v1(99.95,87.09) 100.52,87.66 R1704.1 R1718.1
  BOTTOM w0.089: CPU1.AV5 93.16,78.9 94.51,78.9 94.69,79.09 94.87,79.09 95.25,79.47
  BOTTOM w0.102: v2(99.44,86.71) 99.44,81.73 97.81,80.1 95.89,80.1 95.25,79.47
PCH_HDMI_CLK: length 125.4
  TOP w0.114: v2(61.98,77.82) 61.98,77.83 61.25,78.56 61.25,78.8 60.83,79.22 60.33,79.22 60.13,79.41 RN1501.3 ; Q5402.4 17.51,84.69 18.36,83.85 19.24,83.85 19.56,84.17 20.07,84.17 v2(20.19,84.3)
  L4 w0.127: v2(61.98,77.82) 61.85,77.69 61.85,75.15 57.15,70.45 57.15,64.48 58.55,63.09 61.34,63.09 62.98,61.45 62.98,58.38 61.59,56.99 61.59,49.25 59.7,47.35 46.03,47.35 45.45,46.77 36.64,46.77 32.7,50.71 32.7,55.54 28.7,59.53 28.7,66.05 22.42,72.34 22.42,82.55 20.67,84.3 v2(20.19,84.3)
  BOTTOM w0.089: 70.05,77.26 70.36,76.96 71.21,76.96 71.42,76.74 71.63,76.74 72.23,76.14 CPU1.B9
  BOTTOM w0.114: v1(65.91,77.69) 65.91,77.83 ; 65.91,77.83 68.19,77.83 68.56,77.46 69.85,77.46 70.05,77.26 ; 65.91,77.83 61.99,77.83 v2(61.98,77.82)
PCH_HDMI_DATA: length 123.9
  TOP w0.114: v2(19.43,86.07) 19.43,87.47 18.81,88.09 Q5402.1 ; RN1501.4 60.78,79.76 61.59,78.95 61.59,78.84 v2(61.98,78.45)
  L4 w0.127: v2(19.43,86.07) 22.8,82.71 22.8,72.49 29.08,66.21 29.08,59.69 33.08,55.69 33.08,50.87 36.8,47.15 45.29,47.15 45.87,47.73 59.54,47.73 61.21,49.41 61.21,57.15 62.6,58.53 62.6,61.29 61.18,62.71 58.39,62.71 56.77,64.33 56.77,70.61 61.47,75.31 61.47,77.95 v2(61.98,78.45)
  BOTTOM w0.089: CPU1.C9 72.18,76.46 71.71,76.93 71.5,76.93 71.27,77.16 71.26,77.15 70.65,77.15 70.36,77.44
  BOTTOM w0.114: 70.36,77.44 69.99,77.8 68.7,77.8 68.33,78.17 62.99,78.17 ; v1(62.99,78.33) 62.99,78.17 ; 62.99,78.17 62.26,78.17 v2(61.98,78.45)
PCH_INTVRMEN: length 18.6
  TOP w0.102: R1903.2 R1913.2 105.22,81.51 v1(105.33,81.63) 105.41,81.71 v2(105.41,82.77)
  BOTTOM w0.089: CPU1.AV7 93.16,77.4 94.54,77.4
  BOTTOM w0.102: v2(105.41,82.77) 100.04,77.4 94.54,77.4
PCH_JTAG_TCK: length 1.8
  TOP w0.114: R1920.2 85.1,44.23 v2(85.14,44.19) 85.14,44.27 v1(85.52,44.65)
  BOTTOM w0.114: v2(85.14,44.19) 85.49,43.84 CPU1.AE62
PCH_JTAG_TDI: length 7.9
  TOP w0.114: v2(84.82,41.88) 84.19,41.88 v1(83.95,42.12) 82.75,40.91 81.65,40.91 R1916.1
  BOTTOM w0.089: v2(84.82,41.88) 85.05,42.1 85.05,43.32 84.86,43.51 84.67,43.51 84.48,43.7 84.48,44.24 CPU1.AD61
PCH_JTAG_TDO: length 9.8
  TOP w0.114: v2(84.84,39.97) 84.71,39.97 83.23,38.49 81.24,38.49 80.96,38.77 R1917.1
  BOTTOM w0.114: v2(84.84,39.97) v1(85.47,40.61) 85.76,40.9 85.76,42.54 85.81,42.59 85.81,44.07 85.55,44.33 CPU1.AE61
PCH_JTAG_TMS: length 5.5
  TOP w0.114: v2(84.84,41.24) 84.45,41.24 v1(84.12,40.91) 83.44,40.23 R1918.1
  BOTTOM w0.089: CPU1.AD62 84.78,43.84 85.22,43.39 85.22,41.63 v2(84.84,41.24)
PCH_JTAG_TRST#: length 6
  BOTTOM w0.089: CPU1.AU62 92.59,43.5 92.59,42.89
  BOTTOM w0.114: 92.59,42.89 94.61,40.86 94.61,39.34 TP1901.1
PCH_OPIRCOMP: length 4
  TOP w0.508: v2(95.38,72.36) 95.25,72.48 95.25,73.06 R2003.1
  BOTTOM w0.102: CPU1.AW15 93.76,73.19 94.11,72.85 94.88,72.85
  BOTTOM w0.127: v2(95.38,72.36) 96.01,71.72 v1(96.14,71.72)
  BOTTOM w0.254: 94.88,72.85 v2(95.38,72.36)
PCH_PWROK: length 228.4
  TOP w0.114: v1(97.1,91.97) 97.28,91.79 v2(97.66,91.79) 97.35,91.47 R1706.1 EC1704.1 ; KBC24.100 159.94,53.86 159.64,53.56 v2(159.38,53.56) ; v2(48.77,95.47) 48.64,95.34 48.64,95.31 Q3601.3
  L4 w0.127: v2(48.77,95.47) 48.91,95.33 48.91,95.27 49.64,94.53 60.24,94.53 61.01,95.31 68.02,95.31 68.53,94.8 76,94.8 77.05,95.85 80.52,95.85 81.29,96.63 85.55,96.63 86.16,97.24 96.22,97.24 97.66,95.79 v2(97.66,91.79) 97.66,91.79 97.66,91.85 98.04,92.23 106.87,92.23 v2(107.44,91.66) 109.74,93.96 109.74,99.86 110.07,100.18 114.44,100.18 117.33,103.08 120.58,103.08 121.21,103.71 130.25,103.71 137.57,96.4 137.57,90.08 138.65,89.01 138.65,76.46 140.64,74.47 140.64,73.54 154.69,59.5 154.69,56.33 157.46,53.56 v2(159.38,53.56)
  BOTTOM w0.114: Q2602.G 101.16,32.1 105.37,36.31 105.37,80.06 106.99,81.69 106.99,86.02 106.81,86.2 106.81,91.03 v2(107.44,91.66)
PCH_SLP_S0#: length 8.8
  BOTTOM w0.089: 85.63,83.2 85.63,82.17 85.84,81.97 85.84,80.94 85.59,80.69 CPU1.AF3
  BOTTOM w0.102: 85.63,83.2 85.73,83.3 85.73,85.43 85.61,85.55 85.61,87.99 TP1706.1
PCH_SLP_WLAN#: length 2.6
  TOP w0.102: v2(89.33,78.47) 88.84,77.98 87.57,77.98 TP1705.1
  BOTTOM w0.102: v2(89.33,78.47) 89.01,78.79 CPU1.AM5
PCH_SMBCLK: length 38.9
  TOP w0.114: v2(107.95,89.88) TP9649.1 108.58,93.42 107.2,94.81 Q1801.4 ; RN1810.3 124.53,98.7 v2(124.21,99.03) 125.6,100.42 R6708.1
  L3 w0.127: v2(124.21,99.03) 122.92,97.75 115.66,97.75 113.34,95.42 112.5,95.42 107.95,90.87 v2(107.95,89.88)
  BOTTOM w0.114: v2(124.21,99.03) 125.86,99.03 128.09,96.79 130.68,96.79 130.94,97.05 DIMM1.202
PCH_SMBDATA: length 41.5
  TOP w0.114: RN1810.4 123.88,98.72 v2(123.57,99.03) 125.48,100.93 R6709.1 ; Q1801.1 105.9,92.65 106.25,92.3 106.68,92.3 107,91.97 107,91.48 107.44,91.04 107.44,90.01 v2(107.31,89.88) 107.31,89.25 TP9646.1
  L3 w0.127: v2(123.57,99.03) 122.67,98.13 115.51,98.13 113.18,95.8 112.35,95.8 107.57,91.03 107.57,90.14 v2(107.31,89.88)
  BOTTOM w0.114: v2(123.57,99.03) 124.02,98.58 125.82,98.58 127.95,96.45 DIMM1.200
PCH_SPI_CLK: length 102.1
  L4 w0.127: v2(137.03,101.57) 136.53,102.08 136.53,102.68 136.25,102.95 134.93,102.95 129.97,107.92 116.92,107.92 112.64,112.2 90.41,112.2 76.09,97.88 74.93,97.88 73.79,96.74 73.79,96.21 v2(73.28,95.7)
  BOTTOM w0.089: 83.2,83.9 83.2,83.04 83.59,82.64 83.59,80.84 CPU1.AA3
  BOTTOM w0.114: v2(73.28,95.7) 73.28,95.19 v1(72.75,94.66) 71.84,93.76 71.84,89.65 73.47,88.02 81.62,88.02 83.12,86.52 83.12,85.55 83.2,85.47 83.2,83.9 ; v2(137.03,101.57) 137.41,101.19 R1806.2
PCH_SPI_CS0#: length 15.9
  L4 w0.127: v2(76.2,89.38) 76.21,89.38 81.03,84.56 81.03,82.64 81.73,81.94 81.73,78.54 v2(82.21,78.06)
  BOTTOM w0.114: v2(82.21,78.06) 82.39,77.88 CPU1.Y7 ; v2(76.2,89.38) 76.2,89.17 v1(75.9,88.87) R1807.2
PCH_SPI_DQ2: length 20
  TOP w0.114: v2(77.09,90.39) 77.6,90.9 78.74,90.9 79.3,91.46 RN1802.3
  L4 w0.127: v2(82.21,78.71) 82.65,79.15 82.65,83 81.69,83.97 81.69,85.79 v2(77.09,90.39)
  BOTTOM w0.114: R1811.2 v1(76.2,90.49) 76.99,90.49 v2(77.09,90.39) ; v2(82.21,78.71) 82.39,78.53 CPU1.Y6
PCH_SPI_DQ3: length 21.7
  TOP w0.114: RN1802.4 79.95,90.97 78.94,89.95 78.16,89.95 v2(77.72,90.39)
  BOTTOM w0.114: CPU1.AF1 85.42,81.94 85.42,85.4 85.27,85.55 85.27,88.05 v1(83.44,89.88) 78.23,89.88 v2(77.72,90.39) 77.27,89.93 75.74,89.93 75.49,89.68 R1812.2
PCH_SPI_SI: length 103
  L4 w0.127: v2(73.28,96.33) 73.28,96.77 74.77,98.27 75.93,98.27 90.25,112.58 112.8,112.58 117.08,108.3 130.12,108.3 135.09,103.33 136.41,103.33 137.03,102.71 v2(137.03,102.2)
  BOTTOM w0.089: 82.77,84.98 83,84.76 83,83.16 82.73,82.89 82.73,82.37 83.02,82.08 83.02,81.59 83.3,81.3 CPU1.AA2
  BOTTOM w0.114: R1808.2 136.53,101.69 v2(137.03,102.2) ; v2(73.28,96.33) 72.46,96.33 71.5,95.38 71.5,89.5 73.33,87.67 81.2,87.67 v1(82.4,86.48) 82.77,86.11 82.77,84.98
PCH_SPI_SO: length 101
  L4 w0.127: v2(74.3,96.36) 74.3,96.65 75.15,97.5 76.25,97.5 90.56,111.82 112.48,111.82 116.76,107.54 129.81,107.54 134.89,102.46 v2(136.02,102.46)
  BOTTOM w0.089: 83.65,83.01 83.77,82.89 83.77,80.37 CPU1.AA4
  BOTTOM w0.114: v2(74.3,96.36) 74.3,96.35 73.84,95.89 73.84,94.96 72.33,93.45 72.33,89.65 73.61,88.36 81.92,88.36 v1(82.12,88.16) 83.46,86.82 83.46,83.2 83.65,83.01 ; R1809.2 135.64,102.08 v2(136.02,102.46)
PCH_THERMTRIP: length 14
  BOTTOM w0.089: 71.84,42.73 72.29,42.73 72.58,43.02 72.58,43.45 72.65,43.52 72.65,44.21 73.39,44.95 CPU1.D60
  BOTTOM w0.114: 71.84,42.73 69.26,42.73 68.83,42.3 66.57,42.3 65.83,41.57 v1(64.32,41.57) 61.84,41.57 R2018.2
PCH_VCCDSW_R: length 2.1
  TOP w0.254: C2114.1 89.41,68.24 v1(89.03,68.62) 88.9,68.74 R2110.2
PCH_WAKE#: length 27.6
  TOP w0.102: v2(102.11,86.84) 102.36,87.09 102.36,90.07 R1703.2 v1(102.68,91.41) 101.54,92.55 R1705.1
  L4 w0.102: v2(87.96,79.27) 88.16,79.27 88.52,78.91 89.51,78.91 89.52,78.92 91.56,78.92 92,79.36 92,79.55 92.35,79.9 99.69,79.9 102.11,82.31 v2(102.11,86.84)
  BOTTOM w0.102: CPU1.AJ5 87.87,79.18 v2(87.96,79.27)
PCI_PLTRST#: length 18.1
  TOP w0.102: R1713.2 81.15,91.41 81.3,91.26 82.03,91.26 v2(82.04,91.28)
  L4 w0.102: v2(82.04,91.28) 82.04,88.99 84.56,86.47 84.56,82.22 85.85,80.93 85.85,80.4 86.45,79.8 86.45,78.54 86.02,78.11 v2(86.02,78.07)
  BOTTOM w0.102: v1(81.41,90.77) 81.53,90.77 v2(82.04,91.28) ; CPU1.AG7 86.23,77.88 86.03,78.07 v2(86.02,78.07)
PCI_PME#: length 1.1
  TOP w0.102: v2(85.18,80.16) 85.03,80.16 TP1501.1
  BOTTOM w0.102: CPU1.AD4 84.88,79.86 v2(85.18,80.16)
PCIE_CLK_XDP_N: length 4.2
  BOTTOM w0.102: CPU1.B35 71.94,61.25 71.38,61.25 71.27,61.14 68.63,61.14 TP9651.1
PCIE_CLK_XDP_P: length 3.6
  BOTTOM w0.102: CPU1.A35 71.5,60.96 71.44,60.91 69.07,60.91 TP9652.1
PCIE_PRX_WLANTX_N3: length 134.4
  TOP w0.102: v1(145.36,53.82) v2(146.3,53.82)
  L4 w0.114: v2(75.84,74.97) 76.03,74.79 76.33,74.49 77.34,74.49 78.05,73.78 82.98,73.78 85.01,71.75 86.65,70.11 91.61,70.11 92.26,70.76 97.73,70.76 116.39,89.42 116.39,97.6 118.58,99.79 125.6,99.79 127.06,98.32 128.45,98.32 128.89,98.77 130.73,98.77 133.86,95.63 133.86,79.74 134.52,79.08 134.52,73.84 136.27,72.09 136.27,66.09 137.87,64.49 143.01,64.49 148.46,59.04 148.46,55.52 147,54.07 146.55,54.07 v2(146.3,53.82)
  BOTTOM w0.102: CPU1.G11 75.51,75.31 v2(75.84,74.97) ; IOBD1.11 147.13,53.75 146.97,53.91 146.4,53.91 v2(146.3,53.82)
PCIE_PRX_WLANTX_P3: length 134.1
  L4 w0.114: v2(75.18,74.97) 75.62,74.54 75.96,74.54 76.23,74.26 77.24,74.26 77.95,73.55 82.88,73.55 86.56,69.88 91.7,69.88 92.36,70.53 97.82,70.53 116.62,89.32 116.62,97.51 118.67,99.56 125.5,99.56 126.97,98.09 128.54,98.09 128.99,98.54 130.63,98.54 133.64,95.53 133.64,79.64 134.3,78.98 134.3,73.74 136.04,71.99 136.04,65.99 137.77,64.26 142.92,64.26 148.23,58.95 148.23,55.62 146.91,54.3 146.46,54.3 v2(146.3,54.45)
  BOTTOM w0.102: IOBD1.12 147.05,54.25 146.92,54.11 146.64,54.11 v2(146.3,54.45) 146.28,54.45 145.94,54.79 v1(145.86,54.79) ; CPU1.F11 74.85,75.3 v2(75.18,74.97)
PCIE_PTX_WLANRX_N3: length 6.5
  BOTTOM w0.102: CPU1.C29 72.29,64.26 70,64.26 69.75,64.51 69.75,65.48 69.35,65.88 68.91,65.88 ; 68.91,65.88 C1601.2 ; 68.91,65.88 v1(68.91,66.06)
PCIE_PTX_WLANRX_N3_C: length 145.6
  L4 w0.114: v2(66.29,65.75) 67.97,65.75 72.06,69.84 72.06,71.82 73.99,73.75 76.8,73.75 77.97,72.59 80.06,72.59 80.52,72.13 80.52,70.52 81.66,69.38 91.5,69.38 91.5,69.38 91.91,69.38 92.56,70.03 98.03,70.03 117.11,89.12 117.11,96.89 118.46,98.24 126.08,98.24 126.72,97.6 128.75,97.6 129.19,98.04 130.43,98.04 133.14,95.33 133.14,74.2 135.48,71.85 135.48,65.85 138.54,62.79 143.68,62.79 147.74,58.73 147.74,55.91 147.12,55.29 146.38,55.29 v2(146.3,55.21)
  BOTTOM w0.102: v2(146.3,55.21) 146.35,55.26 146.99,55.26 147,55.25 IOBD1.14 ; C1601.1 66.42,65.88 v2(66.29,65.75) 66.12,65.75 v1(65.61,66.26)
PCIE_PTX_WLANRX_P3: length 6.6
  BOTTOM w0.102: C1602.2 68.25,64.99 68.38,65.12 68.38,65.47 68.58,65.68 69.27,65.68 69.55,65.4 69.55,64.69 ; CPU1.B30 72.54,64.05 69.92,64.05 69.55,64.43 69.55,64.69 ; v1(69.39,64.69) 69.55,64.69
PCIE_PTX_WLANRX_P3_C: length 145.2
  L4 w0.114: v2(66.29,65.12) 66.62,65.12 66.75,65.25 66.75,65.4 66.88,65.53 68.07,65.53 72.29,69.75 72.29,71.73 74.08,73.53 76.71,73.53 77.88,72.36 79.97,72.36 80.29,72.03 80.29,70.43 81.43,69.29 81.43,69.29 81.56,69.15 91.4,69.15 92,69.15 92.66,69.81 98.12,69.81 117.34,89.02 117.34,96.8 118.56,98.01 125.98,98.01 126.63,97.37 128.84,97.37 129.29,97.82 130.33,97.82 132.91,95.23 132.91,74.1 135.25,71.76 135.25,65.75 138.45,62.56 143.59,62.56 147.51,58.64 147.51,56.01 147.02,55.52 146.63,55.52 v2(146.3,55.85)
  BOTTOM w0.102: v1(65.75,65.01) 65.85,65.12 v2(66.29,65.12) 66.42,65.25 66.74,65.25 C1602.1 ; v2(146.3,55.85) 146.69,55.47 147.02,55.47 147.3,55.75 IOBD1.15
PCIE_RCOMP: length 2.8
  TOP w0.203: v1(68.81,65.82) R1601.2
  TOP w0.508: R1601.2 70.42,65.82 v2(70.48,65.88)
  BOTTOM w0.279: CPU1.A27 70.58,65.97 v2(70.48,65.88)
PCIE_WAKE#: length 125.2
  TOP w0.102: v2(100.84,91.79) 100.84,92.61 R1705.2 ; v2(156.95,57.75) 154.74,55.55 KBC24.113 ; v2(149.71,57.24) 149.71,57.92 R2450.1 ; v2(100.84,81.76) 99.31,81.76 98.74,82.33 R2005.1
  L3 w0.102: v2(149.71,57.24) 150.57,58.11 150.57,60.1 149.29,61.39 144.37,61.39 138.63,67.13 138.63,72.7 137.62,73.71 137.62,81.16 136.96,81.83 136.96,89.2 134.75,91.41 134.75,96.22 128.84,102.13 112.26,102.13 111.29,101.16 108.39,101.16 105.62,98.39 103.63,98.39 100.58,95.34 100.58,92.04 v2(100.84,91.79) 100.41,91.36 100.41,88.94 99.01,87.55 99.01,83.58 v2(100.84,81.76)
  BOTTOM w0.102: v2(156.95,57.75) 155.96,57.75 v1(155.7,58.01) 153.88,59.83 151.03,59.83 150.69,59.49 150.69,58.23 v2(149.71,57.24)
PD4403_A: length 11.4
  TOP w0.102: PQ4408.B v2(24.48,8.1)
  BOTTOM w0.102: v1(31.5,11.91) 32,11.4 PD4403.A 31.11,10.25 29.97,9.11 27.56,9.11 26.54,8.1 v2(24.48,8.1)
PD4403_K: length 3.5
  BOTTOM w0.102: PR4458.2 v1(32.77,11.96) 32.77,11.4 33.91,10.25 PD4403.K
PECI: length 15.8
  TOP w0.114: KBC24.13 145.42,48.36 v2(145.29,48.23)
  L3 w0.127: v2(144.27,37.94) 144.84,38.51 144.84,47.78 v2(145.29,48.23)
  BOTTOM w0.114: R2429.1 C2422.1 143.26,36.92 v1(143.61,37.28) v2(144.27,37.94)
PIRQA#: length 16.8
  TOP w0.102: RN1902.1 70.35,84.54 70.59,84.78 v1(75.92,84.78) 79,84.78 79.43,84.35 79.43,83.99 79.25,83.82 79.25,81.89 80.23,80.91 80.23,80 80.28,79.95 v2(80.28,78.75)
  BOTTOM w0.102: CPU1.U6 80.51,78.53 v2(80.28,78.75)
PIRQB#: length 47.5
  TOP w0.102: R1501.2 81.41,105.5 v2(81.79,105.12)
  L3 w0.102: v2(65.91,86.33) 65.91,89.38 68.45,91.92 68.45,92.37 73.15,97.07 74.65,97.07 81.79,104.21 v2(81.79,105.12)
  BOTTOM w0.089: CPU1.P4 79.88,80.15 79.88,80.65 79.84,80.69 79.84,81.3 79.64,81.5 79.36,81.5 79.27,81.59 79.27,82.05
  BOTTOM w0.102: RN1505.7 65.91,86.33 v2(65.91,86.33) 66.99,86.33 67.34,85.97 69.44,85.97 70.23,85.18 74.29,85.18 v1(74.55,85.44) 74.77,85.66 77.99,85.66 78.49,85.16 78.49,83.97 79.2,83.25 79.2,82.12 79.27,82.05
PIRQC#: length 16.7
  BOTTOM w0.089: CPU1.N4 78.77,80 78.48,80.29 78.48,80.7 78.52,80.74 78.52,81.42 78.34,81.59 78.34,81.99 78.02,82.31 78.02,83.41 78.08,83.47
  BOTTOM w0.102: 78.08,83.47 78.08,83.47 78.08,84.96 77.79,85.25 75.14,85.25 74.65,84.77 69.75,84.77 v1(69.6,84.93) 69.46,85.07 RN1506.5
PIRQD#: length 18.1
  BOTTOM w0.089: CPU1.N2 78.71,81.26 78.71,81.47 78.52,81.67 78.52,82.06 78.21,82.37 78.21,83
  BOTTOM w0.102: 78.21,83 78.21,83.32 78.28,83.39 78.28,85.1 77.92,85.46 75.07,85.46 74.59,84.98 70.15,84.98 69.65,85.48 v1(68.51,85.48) 68.21,85.77 65.87,85.77 65.79,85.68 RN1505.8
PLT_RST#: length 127.6
  TOP w0.102: R2416.2 v2(142.88,49.62) ; R1713.1 R1715.1 EC1703.1 C1701.1 83.57,94.39 83.57,96.23 v2(82.17,97.63) ; v2(144.53,54.83) 145.53,55.84 145.53,58.5 146.15,59.12 146.15,64.48 146.37,64.71 146.37,66.52 138.99,73.9 138.99,80.63 135.29,84.34 135.29,86.29 134.31,87.27 134.31,97.05 129.2,102.15 127.05,102.15 v2(126.62,102.58)
  L3 w0.102: v2(115.7,102.96) 115.81,103.08 126.13,103.08 v2(126.62,102.58)
  L4 w0.102: v2(115.7,102.96) 113.72,100.98 109.74,100.98 107.14,98.39 82.93,98.39 v2(82.17,97.63)
  BOTTOM w0.102: IOBD1.23 147,59.75 145.06,57.8 145.06,55.37 v2(144.53,54.83) 144.96,54.4 144.96,53.61 v1(144.09,52.74) 143.38,52.04 143.38,50.13 v2(142.88,49.62) ; v2(126.62,102.58) 126.85,102.81 DB1.4
PLT_RST#_EC: length 4.1
  TOP w0.102: KBC24.7 145.81,50.76 v1(145.34,51.23) 144.63,50.51 C2415.2 R2416.1
PM_CLKRUN#: length 18.9
  TOP w0.102: v2(81.26,79.36) 81.26,79.83 81.3,79.87 81.3,82.5 80.72,83.08 80.72,84.76 79.55,85.93 74.06,85.93 v1(73.18,86.81) 72.52,87.47 71.5,87.47 71.18,87.15 R1709.1 70.8,87.15 70.43,87.52 70.05,87.52 69.87,87.34 R1714.1
  BOTTOM w0.102: v2(81.26,79.36) 81.55,79.36 CPU1.V5
PM_CLKRUN#_EC: length 161.8
  TOP w0.102: KBC24.8 148.21,50.36 149.35,49.21 149.35,48.31 149.66,48.01 150.02,48.01 151.08,49.07 157.05,49.07 v2(157.48,49.5) ; v2(67.94,87.72) 68.02,87.8 70.75,87.8 R1709.2
  L3 w0.102: v2(67.94,87.72) 67.94,88.08 71.14,91.28 71.67,91.28 76.91,96.52 76.91,98.6 81.42,103.1 85.72,103.1 92.64,110.03 100.75,110.03 101.34,110.61 114.11,110.61 117.24,107.49 129.93,107.49 131.53,105.89 132.16,105.28 136.51,103.29 138.37,102.32 140.41,100.28 140.41,98.94 141.13,98.22 141.13,86.85 141.76,86.23 141.76,80.11 158.3,63.56 158.3,59.93 157.71,59.34 157.71,49.73 v2(157.48,49.5)
  BOTTOM w0.102: v1(157.63,50.06) 157.63,49.65 v2(157.48,49.5)
PM_PCH_PWROK: length 22.2
  TOP w0.102: R1706.2 99,91.03 R1707.1 99.06,90.8 99.03,90.77 99.03,89.48 v2(98.93,89.38) 99.03,89.27 99.03,88.08 98.81,87.85 98.17,87.85 97.85,87.53 RN1703.3
  BOTTOM w0.102: CPU1.AY7 96.26,77.69 97.16,78.58 v1(97.16,78.83) 98.02,78.83 100.34,81.16 100.34,87.97 v2(98.93,89.38)
PM_PWRBTN#: length 131.1
  TOP w0.102: v2(152.78,53.05) 153.14,53.41 KBC24.117 ; v2(87.94,78.41) 87.94,78.47 87.53,78.89 87.53,79.45 87.81,79.72 88.34,79.72 88.65,80.03 88.65,81.45 88.95,81.76 TP9645.1 92.46,81.76 93.34,82.64 94.23,82.64 94.87,83.28 v2(94.87,84.3)
  L3 w0.102: v2(94.87,84.3) 95.92,85.35 95.92,91.92 96.14,92.14 96.14,93.18 101.55,98.59 101.55,99.4 103.28,101.13 103.28,106.36 104.68,107.77 111.94,107.77 115.09,104.62 128.39,104.62 136.27,96.73 136.27,91.9 138.38,89.79 138.38,82.42 139.04,81.76 139.04,74.8 141.17,72.66 141.17,67.78 141.87,67.08 142.77,67.08 146.1,63.75 149.63,63.75 152.24,61.13 152.24,53.59 v2(152.78,53.05)
  BOTTOM w0.102: v2(87.94,78.41) 88.28,78.08 CPU1.AL7
PM_RSMRST#: length 25.2
  TOP w0.114: v1(99.82,88.74) 99.52,89.04 99.52,92.42 99.08,92.87 Q1701.3 99.08,93.44 99.69,94.06 99.69,94.46 100.39,95.15 R1702.1 ; v1(99.82,88.74) 99.57,88.49 99.57,87.47 v2(99.44,87.34) 99.35,87.25 RN1703.4 ; v1(99.82,88.74) 100.01,88.55 R1704.2
  BOTTOM w0.089: CPU1.AW6 93.85,78.15 94.51,78.15 94.58,78.09 95.15,78.09 95.51,78.45
  BOTTOM w0.114: v2(99.44,87.34) 99.45,87.34 99.45,87.34 99.89,86.89 99.89,81.55 98.23,79.88 96.95,79.88 95.51,78.45
PM_SLP_A#: length 1.3
  TOP w0.102: TP1704.1 89.03,79.67 v2(88.7,79.34)
  BOTTOM w0.102: v2(88.7,79.34) 88.36,79.01 CPU1.AL5
PM_SLP_LAN#: length 1.5
  TOP w0.102: TP1707.1 86.96,78.04 v2(86.96,78.09)
  BOTTOM w0.102: v2(86.96,78.09) 87.18,77.88 CPU1.AJ7
PM_SLP_S3#: length 219.2
  TOP w0.102: R3609.1 45.28,92.93 v2(47.12,92.93) 47.1,92.95 47.1,93.93 47.24,94.07 Q3601.2 ; KBC24.64 161.14,40.51 159.64,42.01 159.64,43.32 157.7,45.26 157.18,45.26 v2(156.72,45.72)
  L3 w0.102: v2(136.96,93.44) 136.96,96.33 128.47,104.82 116.43,104.82 113.28,107.97 104.6,107.97 103.07,106.44 103.07,101.21 101.35,99.49 101.35,98.67 95.94,93.26 95.94,92.22 95.63,91.92 95.63,86.07 94.36,84.8 94.36,84.14 94.79,83.71 94.79,83.2 91.77,80.19 v2(91.16,80.19)
  L4 w0.102: v2(91.16,80.19) 91.11,80.19 89.79,81.5 86.51,81.5 85.37,82.64 85.37,90.05 84.66,90.76 84.66,91.65 82.59,93.72 81.67,93.72 80.58,94.81 77.28,94.81 76.24,93.77 68.28,93.77 67.65,94.41 61.38,94.41 60.61,93.63 53.62,93.63 53.61,93.62 47.8,93.62 v2(47.12,92.93) ; v2(156.72,45.72) 156.72,53.59 154.13,56.18 154.13,59.35 140.14,73.34 140.14,74.2 138.15,76.19 138.15,88.8 136.96,89.99 v2(136.96,93.44)
  BOTTOM w0.102: PR4804.1 PR5101.1 47.93,89.95 47.24,90.64 v1(47.1,90.64) 47.12,90.65 v2(47.12,92.93) ; CPU1.AT4 91.47,79.86 91.16,80.18 v2(91.16,80.19) ; PR4925.1 135.89,83.79 136.53,84.42 136.53,85.31 137.16,85.95 137.16,87.22 136.53,87.85 136.4,87.85 135.97,88.28 135.97,92.45 v2(136.96,93.44)
PM_SLP_S4#: length 167.9
  TOP w0.102: v2(146.05,45.48) 146.05,45.43 146.33,45.16 KBC24.21 ; v2(135.76,48.1) v1(136.4,48.74) 136.7,49.04 136.7,54.76 139.45,57.5 v2(141.6,57.5) 140.54,58.57 140.54,62 141.15,62.61 141.15,64.39 140.13,65.4 140.13,69.07 PR4914.1
  L3 w0.102: v2(134.62,42.51) 134.49,42.51 131.46,45.55 131.46,95.33 130.63,96.16 128.55,96.16 127.76,96.95 125.56,96.95 125.18,97.33 116.11,97.33 112.75,93.97 112.75,91.37 97.91,76.52 94.84,76.52 94.03,75.71 89.01,75.71 88.32,76.4 86.89,76.4 86.53,76.76 86.53,78.28 v2(86.98,78.73) ; v2(141.6,57.5) 141.6,57.75 142.78,58.92 144.11,58.92 145.47,57.57 145.47,49.19 146.44,48.22 146.44,45.87 v2(146.05,45.48)
  L4 w0.102: v2(134.62,42.51) 134.19,42.94 134.19,46.53 135.51,47.85 135.51,47.86 135.75,48.1 v2(135.76,48.1)
  BOTTOM w0.102: v2(135.76,48.1) 135.32,47.66 PR4905.1 ; v2(86.98,78.73) 87.18,78.53 CPU1.AJ6
PM_SLP_S5#: length 1.4
  TOP w0.102: v2(90.02,79.35) 90.02,79.37 90.58,79.93 TP1703.1
  BOTTOM w0.102: v2(90.02,79.35) 90.31,79.06 CPU1.AP5
PM_SLP_SUS#: length 156.5
  TOP w0.102: R3802.1 80.45,110.84 R1729.2 80.15,110.78 78.82,109.44 78.82,106.57 83.64,101.75 84.2,101.75 85.4,100.55 v2(85.47,100.55) ; KBC24.108 156.74,56.31 v2(156.96,56.53) ; v2(152.65,65.75) v1(152.65,66.62) 152.65,67.66 142.95,77.36 142.95,82.34 141.68,83.62 141.68,86.22 140.16,87.74 140.16,96.73 130.24,106.65 118.24,106.65 v2(116.84,105.25)
  L3 w0.102: v2(90.76,82.75) 90.74,82.77 89.84,82.77 89.28,83.33 89.28,91.41 90.55,92.68 90.55,93.19 90.3,93.44 87.63,93.44 85.47,95.6 v2(85.47,100.55)
  L4 w0.102: v2(85.47,100.55) 85.6,100.68 90.93,100.68 92.25,102 105.03,102 105.41,102.38 105.41,107.03 105.82,107.44 111.59,107.44 114.02,105 116.59,105 v2(116.84,105.25) ; v2(156.96,56.53) 156.51,56.98 156.51,59.33 156.64,59.45 156.64,59.98 152.65,63.97 v2(152.65,65.75)
  BOTTOM w0.089: CPU1.AP4 90.47,80.15 90.47,80.65 90.51,80.69 90.51,82.51 v2(90.76,82.75)
PM_SUS_STAT#: length 14.8
  TOP w0.102: v2(83.64,91.26) 83.82,91.44 R1724.2 84.01,92.17 TP1702.1
  L4 w0.102: v2(86.69,80.18) 86.11,80.76 86.11,80.96 84.76,82.31 84.76,86.56 83.69,87.63 83.69,91.21 v2(83.64,91.26)
  BOTTOM w0.102: CPU1.AG4 86.37,79.86 v2(86.69,80.18)
PM_SUSACK#: length 123.3
  TOP w0.102: KBC24.91 161.93,51.16 159.71,48.94 158.75,48.94 157.74,49.96 155.02,49.96 v2(152.78,52.19) ; RN1702.1 95.7,91.46 v1(95.71,91.46) 96.77,92.53 v2(96.77,92.68)
  L3 w0.102: v2(152.78,52.19) 152.04,52.93 152.04,61.05 149.54,63.54 146.02,63.54 142.68,66.88 141.79,66.88 140.97,67.69 140.97,68.59 139.95,69.61 139.95,73.37 138.84,74.49 138.84,81.67 138.18,82.33 138.18,89.7 136.07,91.81 136.07,96.65 128.3,104.41 115,104.41 111.85,107.56 106.35,107.56 103.48,104.69 103.48,101.04 101.75,99.32 101.75,98.5 96.77,93.53 v2(96.77,92.68)
PM_SUSACK#_R: length 14.1
  TOP w0.102: v2(87.76,89.76) 87.86,89.76 v1(88.37,90.26) 88.49,90.39 89.79,90.39 90.68,91.28 R1708.2 90.8,91.46 RN1702.4
  L3 w0.102: v2(87.76,89.76) 87.58,89.58 87.58,82.97 87.83,82.72 87.85,82.72 v2(88.09,82.48)
  BOTTOM w0.089: CPU1.AK2 87.83,81.16 88.08,81.42 88.08,82.48 v2(88.09,82.48)
PM_SUSWARN#: length 123.7
  TOP w0.102: KBC24.79 161.3,46.36 161.09,46.15 160.73,46.15 160.52,46.36 157.52,46.36 155.5,48.38 v2(155.45,48.38) ; v2(95.5,92.42) v1(94.95,92.42) 94.64,92.11 RN1702.2
  L3 w0.102: v2(155.45,48.38) 154.81,49.01 154.81,61.26 151.46,64.61 151.46,67.85 139.9,79.41 139.9,82.11 139.24,82.77 139.24,90.15 138.24,91.15 138.24,96.27 128.83,105.68 115.87,105.68 113.39,108.17 104.51,108.17 102.87,106.53 102.87,101.3 101.14,99.57 101.14,98.79 95.5,93.15 v2(95.5,92.42)
PM_SUSWARN#_R: length 22.5
  TOP w0.102: R1708.1 90.82,92.09 92.09,92.09 RN1702.3 92.11,92.59 v2(92.46,92.93) 92.02,93.36 v1(92.02,93.39)
  BOTTOM w0.089: CPU1.AV4 93.02,79.84 93.35,80.17 93.82,80.17 93.87,80.22 94.61,80.22 96.14,81.76
  BOTTOM w0.102: RN1601.5 92.32,93.07 v2(92.46,92.93) 93.63,91.76 93.63,91.44 97.59,87.48 97.59,82.19 97.16,81.76 96.14,81.76
PQ3802_1: length 7.8
  TOP w0.102: PR4202.1 35.92,99.52 35.92,100.32 35.51,100.73 v1(35.05,100.73) 35.05,101.38 PR4209.2 37.29,101.63 PQ4202.B
PQ4401_D: length 2.7
  TOP w0.254: v1(27.51,2.71) 27.46,2.71 27.24,2.93 PR4464.2 27.69,4.1 PQ4401.D
PQ4401_G: length 3
  TOP w0.254: PQ4401.G 29.08,7.43 PR4419.2 28.49,8.79 v1(28.17,9.11)
PQ4405_2: length 4.4
  TOP w0.102: PQ4405.2 40.54,4.54 v1(40.64,4.44) 40.7,4.37 PR4463.1 41.21,3.02 41.97,3.02 PR4462.1
PQ4405_3: length 2.3
  TOP w0.114: PQ4405.3 40.15,5.19 v1(40.61,5.66) 40.7,5.75 PR4455.1
PQ4405_5: length 4
  TOP w0.102: PR4405.2 v1(35.94,6.19) PC4404.1 36.22,4.54 PQ4405.5
PQ4405_6: length 4
  TOP w0.102: PR4450.1 v1(34.8,3.19) 34.85,3.14 35.59,3.14 PC4404.2 36.33,3.89 PQ4405.6
PQ4406_D: length 4.2
  BOTTOM w0.114: PQ4406.D 40.13,10.83 37.95,10.83 v1(37.74,10.62) 37.57,10.45 PR4456.2
PQ4406_G: length 6.3
  BOTTOM w0.102: v1(43.18,8.73) 42.93,8.98 PC4414.2 42.67,9.43 PQ4406.G 40.8,10.25 39.24,10.25 38.8,9.81 PR4429.1
PQ4408_C: length 25.7
  TOP w0.102: PR4462.2 PR4451.1 44.39,2.95 v2(44.7,2.63) ; v1(23.5,3.47) v2(23.5,4.03) PQ4408.C
  L3 w0.102: v2(23.5,4.03) 24.26,4.03 25.96,2.33 44.4,2.33 v2(44.7,2.63)
PQ4408_E: length 6.5
  TOP w0.102: v1(20.29,7.02) PR4433.1 PQ4408.E 22.51,7.37 23.75,8.6 25.72,8.6 PR4416.2
PQ4411_D1: length 2.4
  BOTTOM w0.254: v1(33.28,5.53) 33.25,5.56 PR4401.2 32.32,4.79 32.46,4.65 PQ4411.3
PQ4411_D2: length 3.3
  BOTTOM w0.254: PQ4411.6 34.92,2.87 35.71,2.09 v1(35.94,2.09) 36.73,2.09 PR4420.1
PQ4413_3: length 2.9
  BOTTOM w0.114: PR4457.1 41.33,2.57 v1(40.89,3.02) 40.01,3.89 PQ4413.3
PQ4413_5: length 3.5
  BOTTOM w0.102: PR4436.2 v1(35.94,5.48) PC4405.1 36,4.54 PQ4413.5
PROC_OPI_COMP: length 3.4
  TOP w0.508: R602.1 96.08,72.42 v2(96.14,72.36)
  BOTTOM w0.254: CPU1.AY15 95.94,73.19 v1(96.14,72.99) v2(96.14,72.36)
PROC_OPI_COMP3: length 3.2
  TOP w0.203: v1(81.89,67.56) 82.11,67.79 82.54,67.79 v2(82.67,67.91)
  TOP w0.508: R606.1 82.23,68.35 v2(82.67,67.91)
  BOTTOM w0.203: CPU1.Y22 v2(82.67,67.91)
PROCHOT#_BQ24770: length 3.6
  TOP w0.114: PU4401.10 41.76,10.23 v1(41.07,9.53) 41.15,9.45 PR4469.2
PROCHOT_EC: length 112.3
  TOP w0.114: v2(149.86,43.02) 149.86,43.15 149.05,43.96 KBC24.24 146.22,43.96 146.19,43.93 145.65,43.93 v1(145.39,44.19) 145.03,44.54 R2442.1
  L3 w0.127: v2(68.33,37.31) 68.39,37.37 77.46,37.37 88.55,26.28 89.05,25.77 97.07,25.77 98.95,23.9 107.53,23.9 107.95,23.48 120.83,23.48 121.46,22.84 126.19,22.84 126.66,23.31 128.88,23.31 131.58,26.02 141.32,26.02 148.91,33.61 148.91,38 149.86,38.96 v2(149.86,43.02)
  BOTTOM w0.114: v2(68.33,37.31) 68.33,37.81 67.6,38.54 Q2401.G 67.02,38.64 R2438.1
PS_ID: length 5.8
  TOP w0.114: PR4205.1 PR4206.2 41.02,96.49 v1(40.39,95.85) 40.13,95.85 39.72,96.27 PQ4201.S
PS_ID_R: length 10.8
  TOP w0.635: PR4217.1 v2(16.38,92.14)
  BOTTOM w0.406: 19.1,88.69 DCIN1.4 19.1,86.63 18.54,86.07 18.54,85.82 17.53,84.8
  BOTTOM w0.635: AFTP4203.1 17.53,84.8 ; v2(16.38,92.14) 17.17,92.14 19.1,90.22 19.1,88.69
PS_ID_R2: length 37
  TOP w0.114: PR4217.2 20.07,93.47 20.71,94.11 v1(21.72,94.11) PD4204.2 PD4204.1 25.11,96.08 28.32,99.28 28.32,100.3 28.7,100.68 28.7,102.38 29.6,103.28 34.87,103.28 35.31,102.84 PR4209.1 37.02,102.52 38.48,101.06 39.5,101.06 39.75,100.81 39.75,99.79 39.43,99.47 39.43,98.01 PQ4201.D 40.26,97.25 40.58,97.57 PR4206.1
PS_S3CNTRL: length 6.9
  TOP w0.102: R3607.2 48.39,96.3 v1(48.39,95.98) 48.39,95.73 48.19,95.53 48.19,95.53 47.88,95.22 47.37,95.22 47.12,94.96 47.12,94.33 46.86,94.07 Q3601.5 45.47,94.07 45.32,93.93 45.32,93.53 45.43,93.42 Q3601.6
PSID_DISABLE#_R_C: length 5.4
  TOP w0.102: PR4203.2 v1(35.31,98.01) 35.53,98.23 PQ4201.G 36.77,98.84 36.63,98.98 PQ4202.C
PSID_EC: length 175
  TOP w0.114: KBC24.99 160.34,53.63 159.64,52.93 v2(159.38,52.93) ; PR4205.2 41.91,98.46 PR4204.2 ; PR4204.2 v1(40.89,98.52) 40.51,98.9 v2(40.51,99.15) ; PR4204.2 41.53,98.84 PD4203.3
  L3 w0.114: v2(159.38,52.93) 159.96,53.5 159.96,57.36 160.47,57.87 160.47,63.14 143,80.62 143,86.74 142.37,87.37 142.37,99.56 142.37,100.08 142.3,100.14 139.23,103.35 136.22,104.94 132.88,106.31 132.87,106.31 132.36,106.86 132.32,106.9 132.07,107.14 130.48,108.72 118.08,108.72 114.88,111.92 81.97,111.92 74.99,104.94 74.99,102.5 72.16,99.66 59.08,99.66 57.96,98.55 41.12,98.55 v2(40.51,99.15)
PSL_IN1#: length 10.5
  TOP w0.102: KBC24.73 163.98,43.96 164.28,43.66 164.85,43.66 165.1,43.4 v1(165.1,40) 165.1,38.96 164.34,38.19 R2430.2
PSL_IN2#: length 5.8
  TOP w0.102: v1(165.89,53.16) 165.8,53.24 R2425.1 ; R2427.2 R2425.1 ; R2425.1 163.69,51.96 KBC24.93
PSL_OUT#: length 9.2
  TOP w0.102: KBC24.74 164.02,44.36 164.34,44.04 v1(164.59,44.04) 164.75,44.04 165.48,43.31 165.48,38.96 164.85,38.32 R2432.1
PU4401_4: length 4.2
  TOP w0.102: PU4404.4 75.5,29.79 PC4423.2 PR4407.2 76.26,27.53 PR4454.2 76.78,27.59 v1(77.22,27.15)
PU4401_5: length 5.5
  TOP w0.102: v1(73.61,28.49) 73.61,27.77 PR4448.2 73.85,27.53 PR4407.1 PC4423.1 74.61,30.26 74.8,30.45 PU4404.5
PU4401_6: length 2.3
  TOP w0.102: PU4404.6 v1(76.73,31.1) 77.65,31.1 PR4446.2
PU4402_1IN+: length 4.6
  TOP w0.254: PU4402.3 31.22,12.12 PR4440.1 PR4461.2 PR4441.2 31.05,14.28 v1(30.3,15.03)
PU4402_1IN-: length 4.4
  TOP w0.254: v1(31.52,15) 31.52,14.48 PR4442.2 PR4465.2 PR4447.1 31.87,12.21 PU4402.2
PU4902_S5: length 12.3
  TOP w0.102: PR4914.2 137.97,72.12 137.97,79.84 v1(137.63,80.18) v2(136.78,81.03)
  BOTTOM w0.102: v2(136.78,81.03) 136.96,80.85 136.97,80.85 137.28,80.54 PU4902.9
PU4902_VCNTL: length 4.9
  BOTTOM w0.254: PU4902.10 137.78,80.82 PC4911.1 PR4918.1 PR4917.1 138.54,83.71 v1(138.56,83.71)
PURE_HW_SHUTDOWN#: length 179.8
  TOP w0.102: R2424.1 46.93,4.16 46.39,4.7 Q2404.B 46.39,7.81 R2439.2 46.99,8.41 v2(46.99,8.98)
  L3 w0.102: v2(99.82,23.21) 98.93,23.21 96.86,25.28 85.56,25.28 81.66,29.18 81.66,32.23 77.5,36.39 67.08,36.39 63.91,39.57 63.91,42.45 62.73,43.63 51.59,43.63 50.27,44.96 50.27,47.85 48.13,49.98 v2(48.13,50.89)
  L4 w0.102: v2(29.97,61.56) 30.48,61.05 30.48,60.14 30.3,59.96 30.3,59.45 32.49,57.27 42.77,57.27 v2(43.94,56.1) ; v2(46.99,8.98) 46.94,9.04 46.94,14.36 49.97,17.39 69.34,17.39 74.5,22.55 79.2,22.55 80.27,23.62 88.14,23.62 89.2,22.55 98.02,22.55 98.68,23.21 v2(99.82,23.21)
  BOTTOM w0.102: v2(48.13,50.89) 48.13,51.91 47.68,52.37 45.64,52.37 44.7,53.31 44.7,55.85 44.45,56.1 v2(43.94,56.1) ; v2(29.97,61.56) 29.65,61.88 D3602.3 ; v2(99.82,23.21) 101.11,24.5 101.11,26.15 v1(101.6,26.64) 101.66,26.7 C2610.1 102.18,27.26 102.18,28.29 101.93,28.54 100.86,28.54 99.25,30.16 Q2602.D
PWR_1D5V_EN: length 3.7
  BOTTOM w0.102: PU5101.3 50.04,90.58 PC5101.1 49.91,90.58 49.66,90.84 PR5101.2 48.55,90.84 v1(48.24,91.15)
PWR_1D05V_PWR_EN: length 5.4
  BOTTOM w0.102: PU4801.1 46.01,85.99 46.2,86.18 46.89,86.18 47.37,86.66 v1(47.37,87.04) PC4801.1 PR4803.1 PR4804.2
PWR_1D05V_PWR_ILIM: length 3.3
  BOTTOM w0.254: PU4801.3 45.11,86.48 45.47,86.84 46.01,86.84 v1(46.23,86.61) 46.48,86.87 PR4802.1
PWR_1D35V: length 13.9
  BOTTOM w0.254: PR4903.1 PC4912.1 134.24,41.88 133.99,42.13 133.99,47.85 v1(135.94,49.8) 136.08,49.94 PC4902.1
  vias: v1(139.17,54.83)
PWR_1D35V_BOOT: length 3.7
  TOP w0.203: PR4901.1 137.13,43.83 v1(138.2,44.9)
  TOP w0.508: PR4901.1 137.13,42.92 v2(137.41,42.64)
  BOTTOM w0.254: PU4901.6 137.57,42.64 v2(137.41,42.64)
PWR_1D35V_BOOT_R: length 2.6
  TOP w0.508: PR4901.2 139.14,42.97 v1(139.67,42.97) 139.7,43 PC4917.1
PWR_1D35V_BYP: length 3.7
  TOP w0.254: v2(138.3,42.39) PC4910.1 PR4902.1 139.2,41.57 v1(140.11,41.57)
  BOTTOM w0.254: v2(138.3,42.39) 138.35,42.39 138.79,42.82 PU4901.7
PWR_1D35V_EN: length 3.2
  BOTTOM w0.102: PU4901.1 137.69,45.42 v1(137.08,46.02) 136.65,46.45 PC4909.1 PR4905.2
PWR_1D35V_IMAX: length 2.5
  BOTTOM w0.254: PU4901.3 136.99,44.52 v1(136.93,44.57) 136.21,45.29 PR4906.2
PWR_1D35V_LDO_P5: length 3.9
  BOTTOM w0.254: PC4913.1 136.78,41.56 136.78,41.86 137.03,42.1 137.03,42.11 v1(137.1,42.18) 136.91,42.37 136.91,43.02 137.5,43.62 PU4901.5
PWR_1D35V_PGOOD: length 4
  TOP w0.102: v2(137.29,45.05) 137.29,45.69 v1(137.28,45.7) 137.28,46.08 136.91,46.45 PR4910.2 PR4907.2
  BOTTOM w0.102: v2(137.29,45.05) 137.37,44.97 PU4901.2
PWR_1D35V_PHASE: length 1.8
  TOP w0.508: PC4917.2 v3(139.7,46.32) v1(139.7,47.08)
PWR_1D35V_VFB: length 5
  BOTTOM w0.254: PR4904.1 136.78,43.66 137.19,44.07 PU4901.4 ; PR4904.1 PR4903.2 PC4912.2 ; PR4904.1 136.21,44.08 v1(135.71,44.57)
PWR_3D3V_CS2: length 4.4
  TOP w0.203: 37.11,63.95 PU4503.5
  TOP w0.254: v1(39.65,61.74) 39.65,62.57 PR4517.1 39.28,62.93 39.19,62.93 38.81,63.32 38.33,63.32 37.7,63.95 37.11,63.95
PWR_3D3V_DRVH2: length 10.9
  TOP w0.203: v3(38.1,66.9) 38.1,66.64 37.76,66.3 PU4503.10
  L4 w0.762: v3(38.1,66.9) 38.73,67.53 38.73,70.96 36.7,72.99 v3(35.69,72.99)
  BOTTOM w0.203: v1(37.34,66.77) 37.97,66.77 v3(38.1,66.9)
  BOTTOM w0.33: PU4502.1 35.82,73.13 v3(35.69,72.99)
PWR_3D3V_DRVL2: length 11.4
  TOP w0.203: v3(36.96,68.04) 36.61,67.7 PU4503.11
  TOP w0.254: v1(34.29,75.91) 34.29,75.8 v3(34.73,75.36)
  L4 w0.762: v3(36.96,68.04) 36.96,69.56 34.54,71.98 34.54,75.17 v3(34.73,75.36)
  BOTTOM w0.33: PU4502.4 v3(34.73,75.36)
PWR_3D3V_EN2: length 2.7
  TOP w0.102: PR4506.2 39.1,63.93 v1(38.68,63.93) 37.9,64.7 PU4503.6
PWR_3D3V_FB2: length 3.5
  TOP w0.203: PU4503.4 36.21,63.32 36.45,63.09
  TOP w0.254: 36.45,63.09 36.96,62.58 PR4523.1 PC4523.2 PR4512.2
PWR_3D3V_FB2_R: length 0.9
  TOP w0.254: PR4535.2 37.85,60.86 PC4523.1
PWR_3D3V_LL2: length 18
  TOP w0.203: v3(38.61,65.5) PU4503.8
  TOP w0.508: PR4533.1 36.25,75.74 v3(35.31,76.68) 35.92,77.29 v1(35.94,77.29) ; PC4535.2 v3(38.61,65.5)
  L4 w0.762: v3(38.61,65.5) 39.75,66.64 39.75,71.47 36.58,74.64 36.58,75.41 v3(35.31,76.68)
PWR_3D3V_SNUB: length 2.9
  TOP w0.203: v1(34.91,74.06) PR4533.2
  TOP w0.508: PR4533.2 36.37,74.01 PC4520.1
PWR_3D3V_VBST2: length 2.6
  TOP w0.203: PU4503.9 38.09,65.9 v1(38.56,66.36) 38.96,66.77 PR4528.2
PWR_3D3V_VBST2_1: length 2.8
  TOP w0.127: PR4528.1 40.01,67.68 v1(40.01,67.91)
  TOP w0.508: PR4528.1 PC4535.1
PWR_5V_CS1: length 4
  TOP w0.203: PU4503.1 34.64,63.95 34.54,63.85
  TOP w0.254: 34.54,63.85 33.91,63.21 32.45,63.21 v1(32.38,63.15) 32.17,62.93 PR4531.1
PWR_5V_DRVH1: length 12.1
  TOP w0.203: v3(33.66,66.9) 34.01,66.9 34.26,66.64 PU4503.16
  L4 w0.762: v3(33.66,66.9) 33.06,66.9 27.81,72.14 v3(27.81,73.72)
  BOTTOM w0.203: v1(27.09,73.72) v3(27.81,73.72)
  BOTTOM w0.33: v3(27.81,73.72) 27.94,73.72 27.95,73.72 PU4501.1
PWR_5V_DRVL1: length 13.3
  TOP w0.203: PU4503.15 35.01,67.32 v3(34.29,68.04)
  L4 w0.762: v3(27.81,75.36) 28.7,75.36 29.59,74.47 29.59,72.94 34.29,68.24 v3(34.29,68.04)
  BOTTOM w0.203: v3(27.81,75.36) v1(27.05,75.36)
  BOTTOM w0.33: PU4501.4 v3(27.81,75.36)
PWR_5V_EN1: length 2.4
  TOP w0.102: v2(33.78,64.1) 34.01,64.1 34.26,64.36 PU4503.20
  BOTTOM w0.102: PR4504.2 33.53,64.36 v2(33.78,64.1) 34.16,64.48 v1(34.29,64.48)
PWR_5V_EN1_R: length 4
  BOTTOM w0.102: v1(31.8,62.32) 32.58,62.32 PR4501.2 PR4530.1 32.7,63.66 32.19,64.17 PR4504.1 PR4515.2
PWR_5V_FB1: length 5.4
  TOP w0.203: 35.18,63.11 35.41,63.35 PU4503.2
  TOP w0.254: v1(31.24,62.02) 31.36,62.13 PR4527.2 32.64,62.52 PC4522.2 PR4526.1 33.96,62.68 34.39,63.11 35.18,63.11
PWR_5V_FB1_R: length 2.3
  TOP w0.203: v1(32.87,60.29) 33.15,60.57 v2(33.15,60.93)
  TOP w0.254: PC4522.1 v2(33.15,60.93)
  BOTTOM w0.254: PR4525.2 33.59,61.46 33.15,61.01 v2(33.15,60.93)
PWR_5V_LL1: length 18.7
  TOP w0.203: v3(33.02,65.5) PU4503.18
  TOP w0.508: v1(26.92,76.68) 26.97,76.63 v3(27.69,76.63) PR4529.1 ; PC4516.2 v3(33.02,65.5)
  L4 w0.762: v3(27.69,76.63) 27.3,76.63 26.8,76.12 26.8,71.72 v3(33.02,65.5)
PWR_5V_SNUB: length 3.3
  TOP w0.127: v1(27.36,72.87) 27.58,73.09 28.52,73.09 PC4536.1
  TOP w0.508: PC4536.1 29.08,73.65 PR4529.2
PWR_5V_VBST1: length 4
  TOP w0.203: PU4503.17 33.64,65.9 32.77,66.77 PR4524.1 32.03,67.46 v1(32.54,67.96)
PWR_5V_VBST1_1: length 2.7
  TOP w0.203: PR4524.2 30.71,67.51 v1(31.19,67.99)
  TOP w0.508: PR4524.2 PC4516.1
PWR_5V_VCLK: length 3.1
  TOP w0.203: AFTP4501.1 32.77,64.36 33.51,65.1 PU4503.19
  TOP w0.254: AFTP4501.1 PR4502.1
PWR_5V_VO1: length 66.4
  TOP w0.203: v2(35.31,67.91) 35.41,67.81 PU4503.14
  TOP w0.254: PR4527.1 31.66,61.25 v2(31.6,61.18) 31.65,61.13 31.65,60.06 v1(31.68,60.03)
  L3 w0.508: v2(35.31,67.91) 35.31,66.53 34.54,65.76 34.54,63.97 34.05,63.47 33.15,63.47 32.08,64.53 30.81,64.53 23.27,72.08 23.27,84.32 v2(24.38,85.44)
  L4 w0.254: v2(31.6,61.18) 31.31,61.47 31.31,61.88 29.72,63.47 29.72,66.2 23.24,72.68 23.24,84.3 v2(24.38,85.44)
  BOTTOM w0.254: PG4532.2 v2(24.38,85.44) ; v2(31.6,61.18) 32.03,61.61 PR4525.1
PWR_CHG_1: length 8.6
  TOP w0.254: PD4406.K 34.67,13.56 33.66,14.57 33.66,16.73 33.02,17.37 PD4405.K 34.21,17.75 PR4403.1 34.7,18.28 v1(34.7,19.68)
PWR_CHG_ACDET: length 6.4
  TOP w0.203: PU4401.6 39.33,12.5 39.24,12.41
  TOP w0.254: 39.24,12.41 38.8,11.97 v1(38.76,11.97) PC4402.1 PR4411.1 36.77,11.97 36.32,11.52 36.32,10.85 37.02,10.15 PR4444.2
PWR_CHG_ACN: length 21
  TOP w0.203: PU4401.1 39.22,14.5 39.19,14.52
  TOP w0.254: 39.19,14.52 38.84,14.88 ; 38.84,14.88 v1(38.91,14.95) ; 38.84,14.88 38.19,15.53 PC4428.1 PR4421.1 36.96,16.29 PC4416.2 36.45,16.8 v2(36.45,16.99)
  L3 w0.254: v2(36.45,16.99) 36.45,18 45.34,26.89 45.34,27.65 v2(45.59,27.91)
  BOTTOM w0.254: v2(45.59,27.91) 45.72,27.78 PG4402.2
PWR_CHG_ACOK: length 18.1
  TOP w0.102: PR4430.1 v2(38.61,12.79) 39.14,12.79 39.24,12.9 PU4401.5 ; v2(42.04,4.16) 41.59,3.71 PR4463.2
  L4 w0.102: v2(38.61,12.79) 38.18,12.36 38.18,8.17 38.94,7.41 38.94,6.27 39.45,5.76 40.33,5.76 41.93,4.16 v2(42.04,4.16)
  BOTTOM w0.102: v2(42.04,4.16) 42.39,4.51 PR4404.1 PR4410.2 40.63,4.86 v1(40.59,4.9) 40.23,4.54 PQ4413.2
PWR_CHG_ACP: length 23
  TOP w0.203: 38.99,14.19 39.01,14.17 39.57,14.17 39.63,14.1 PU4401.2
  TOP w0.254: v2(35.81,16.99) 35.81,16.63 35.97,16.48 PC4432.1 35.97,14.79 PC4418.2 36.12,14.64 PR4421.2 PC4428.2 38.54,14.64 38.99,14.19
  L3 w0.254: v2(35.81,16.99) 35.81,17.91 44.96,27.05 44.96,27.73 44.83,27.86 v2(44.83,27.91)
  BOTTOM w0.254: v1(36.07,17.49) 35.81,17.24 v2(35.81,16.99) ; PG4406.2 44.7,27.78 v2(44.83,27.91)
PWR_CHG_BAT: length 3.5
  TOP w0.203: 45.34,12.79 45.23,12.9 PU4401.17
  TOP w0.254: 45.34,12.79 46.02,12.11 v1(46.23,12.11) 47.37,12.11
PWR_CHG_BATDRV: length 3.6
  TOP w0.203: 45.59,13.3 PU4401.18
  TOP w0.254: 45.59,13.3 46.42,13.3 PR4409.1 47.15,13.79 v1(47.15,14.09)
PWR_CHG_BTST: length 2.6
  TOP w0.203: v1(42.16,16.91) PU4401.25
  TOP w0.508: PR4425.1 v1(42.16,16.91)
PWR_CHG_BTST1: length 5.5
  TOP w0.254: PC4421.1 PR4425.2 42.16,19.53 43.03,20.39 v1(43.59,20.39) 44.6,20.39 45.34,19.65
PWR_CHG_CMPIN: length 31.1
  TOP w0.254: PU4402.6 31.22,6.22 v2(31.11,6.32) ; PR4413.1 44.2,6.95 44.32,6.83 44.32,6.44 v2(45.09,5.68)
  L3 w0.254: v2(45.09,5.68) 44.31,5.68 43.68,5.05 39.91,5.05 39.4,4.54 33.06,4.54 31.29,6.32 v2(31.11,6.32)
  BOTTOM w0.254: v2(45.09,5.68) 45.09,4.96 v1(43.56,3.44) 41.99,1.87 41.02,1.87 40.39,2.51 PR4420.2 ; PR4401.1 31.43,6 v2(31.11,6.32) 31.5,6.7 PR4402.2 PR4428.2
PWR_CHG_CMPOUT: length 22.2
  TOP w0.254: v2(32,6.32) 31.87,6.18 PU4402.7 31.87,3.7 PR4422.1 ; v2(45.09,6.44) PR4415.1
  L3 w0.254: v2(45.09,6.44) 44.7,6.06 44.15,6.06 43.52,5.43 39.75,5.43 39.24,4.92 33.4,4.92 v2(32,6.32)
  BOTTOM w0.254: v2(32,6.32) 32.96,7.27 v1(34.04,7.27) PR4437.2 PR4436.1
PWR_CHG_CMSRC: length 2.2
  TOP w0.203: 39.37,13.68 39.39,13.7 PU4401.3
  TOP w0.254: PR4439.2 v1(38.84,13.68) 39.37,13.68
PWR_CHG_HIDRV: length 21.7
  TOP w0.203: PU4401.26 41.76,16.37 v3(41.4,16.73)
  L3 w1.016: v3(56.01,24.22) 52.07,20.29 44.07,20.29 41.4,17.62 v3(41.4,16.73)
  BOTTOM w0.254: v1(41.66,17.49) 41.66,16.99 v3(41.4,16.73)
  BOTTOM w0.762: v3(56.01,24.22) 55.97,24.26 PU4406.1
PWR_CHG_LODRV: length 26
  TOP w0.203: PU4401.23 42.96,15.88 v3(43.43,16.35)
  L4 w1.016: v3(43.43,16.35) 43.43,16.73 48.51,21.81 48.51,29.69 49.28,30.45 v3(55.88,30.45)
  BOTTOM w0.254: v1(43.94,16.86) v3(43.43,16.35)
  BOTTOM w0.762: PU4406.8 55.71,30.28 v3(55.88,30.45)
PWR_CHG_PHASE: length 26.5
  TOP w0.203: PU4401.27 41.36,15.88 40.51,16.73 v3(40.13,16.73)
  TOP w0.508: v3(40.13,16.73) 40.77,17.37 PC4421.2 ; PR4427.1 v2(56.13,28.54)
  L3 w1.016: v3(40.13,16.73) 40.13,18.15 43.54,21.56 51.54,21.56 55.48,25.5 v3(56.77,25.5)
  BOTTOM w0.254: v1(39.5,17.24) 39.62,17.24 v3(40.13,16.73)
PWR_CHG_REGN: length 56.5
  TOP w0.203: PU4401.24 42.56,16.37 42.8,16.6
  TOP w0.254: PR4470.1 47.69,18.57 v2(46.99,17.87) 46.48,17.37 PD4401.A 44.73,17.98 PC4422.1 43.56,17.37 42.8,16.6 ; v2(27.66,6.34) 27.66,12.07 PR4453.1 28.8,13.21 29.31,13.21 PR4441.1
  L3 w0.254: v2(27.66,6.34) 28.52,7.21 35.43,7.21 36.32,6.32 36.32,6.23 36.62,5.94 40.47,5.94 40.98,6.44 v2(41.02,6.44) 41.02,7.33 42.67,8.98 44.44,8.98 46.35,10.9 46.35,17.24 v2(46.99,17.87)
  BOTTOM w0.254: v2(46.99,17.87) 48.26,17.87 48.9,17.24 48.9,13.05 48.2,12.35 v1(47.68,12.35) PR4449.1 ; PR4410.1 41.02,6.23 v2(41.02,6.44)
PWR_CHG_SRN: length 3.8
  TOP w0.203: 45.35,13.8 45.26,13.7 PU4401.19
  TOP w0.254: v1(45.95,14.27) 45.89,14.33 ; 45.89,14.33 46.64,15.08 PR4417.1 ; 45.89,14.33 45.35,13.8
PWR_CHG_SRN_R: length 33.9
  TOP w0.254: PR4417.2 48.26,15.14 PC4412.1 PC4429.2 50.48,15.14 v2(50.67,15.33)
  BOTTOM w0.254: v2(50.67,15.33) 50.76,15.33 51.65,16.22 54.08,16.22 ; PG4403.1 75.5,25.62 75.25,25.37 75.25,23.27 72.34,20.37 61.07,20.37 56.93,16.22 54.08,16.22 ; v1(54.08,16.15) 54.08,16.22
PWR_CHG_SRP: length 4
  TOP w0.203: PU4401.20 45.12,14.1 45.21,14.19
  TOP w0.254: 46.47,15.45 47.12,16.1 PR4438.1 ; 46.47,15.45 v1(46.41,15.51) ; 46.47,15.45 45.21,14.19
PWR_CHG_SRP_R: length 33.1
  TOP w0.254: PR4438.2 48.26,16.03 PC4401.1 PC4429.1 50.61,16.03 v2(50.67,15.97)
  BOTTOM w0.254: 52.48,16.6 51.31,16.6 v2(50.67,15.97) ; 52.48,16.6 56.77,16.6 60.91,20.75 72.18,20.75 74.87,23.43 74.87,25.37 74.61,25.62 PG4407.1 ; 52.48,16.6 v1(52.48,16.71)
PWR_CHG_VCC: length 8.8
  TOP w0.203: PU4401.28 40.51,15.33
  TOP w0.254: PR4403.2 36.4,18.82 37.23,19.65 v1(37.77,19.65) 38.23,19.65 38.89,18.99 PC4410.1 38.67,18.29 PC4433.1 38.67,16.93 40.27,15.33 40.51,15.33
PWR_DCBATOUT_1D35V:
  vias: v1(141.78,41.07)
PWR_DEBUG: length 8.4
  BOTTOM w0.089: TP9647.1 75.42,40.77 75.42,42.87 75.48,42.93 75.48,43.44 75.31,43.61 75.31,44.31 75.38,44.39 75.38,45.43 CPU1.H59
  BOTTOM w0.254: R705.2 73.29,38.64 TP9647.1
PWR_PG: length 3.7
  TOP w0.102: PU4601.3 45.06,49.53 PR4625.1 45.53,50.22 v1(46.3,51)
PWR_SCL: length 3.5
  TOP w0.203: PU4401.12 42.56,10.25 v1(42.77,10.04)
  TOP w0.254: PG4401.1 43.18,8.25 42.72,8.71 42.72,9.99 v1(42.77,10.04)
PWR_SDA: length 3.3
  TOP w0.203: PU4401.11 42.16,9.87
  TOP w0.254: PG4408.1 42.16,8.98 v1(42.16,8.98) 42.16,8.99 42.16,9.87
PWR_VCC_B-RAMP: length 3.8
  TOP w0.203: 41.87,52.85 PU4601.11
  TOP w0.254: PR4601.1 v2(42.29,53.82) 42.29,53.29 41.87,52.87 41.87,52.85
  BOTTOM w0.254: PR4601.1 v2(42.29,53.82) 42.16,53.82 v1(41.78,53.43)
PWR_VCC_BOOT1: length 2.9
  BOTTOM w0.203: 53.21,75.41 53.02,75.21 PU4701.7
  BOTTOM w0.254: 53.21,75.41 53.68,75.88 v1(53.92,75.88) 53.98,75.93 PC4706.2
PWR_VCC_BOOTR1: length 2.4
  BOTTOM w0.203: PU4701.6 52.62,75.79 v1(52.7,75.88)
  BOTTOM w0.254: v1(52.7,75.88) PR4703.1
PWR_VCC_COMP: length 6.2
  TOP w0.203: PU4601.26 40.28,47.35 40.13,47.21
  TOP w0.254: 40.13,47.21 39.69,46.77 v1(39.5,46.77) PC4604.1 PR4620.1 PR4619.2 PC4608.2
PWR_VCC_COMP_1: length 0.9
  TOP w0.508: PC4608.1 36,46.83 PR4627.2
PWR_VCC_CSN1: length 22.3
  TOP w0.203: PU4601.18 38.67,51.13 38.4,51.4 v2(38.35,51.4)
  BOTTOM w0.254: 41.39,58.47 38.23,55.31 38.23,53.33 PC4707.2 39.14,52.19 v2(38.35,51.4) ; 41.39,58.47 41.93,59.01 43.26,59.01 PR4705.2 PR4707.2 46.42,60.55 50.29,60.55 50.67,60.17 PG4708.1 ; 41.39,58.47 v1(41.48,58.39)
PWR_VCC_CSP1: length 15.4
  TOP w0.203: v2(37.72,51.4) 37.72,51.45 38.15,51.89 38.55,51.89 38.91,51.53 PU4601.17
  BOTTOM w0.254: 40.2,57.82 37.85,55.47 37.85,52.44 PC4707.1 37.72,52.32 v2(37.72,51.4) ; 40.2,57.82 v1(40.11,57.91) ; 40.2,57.82 41.77,59.39 43.36,59.39 PR4705.1 43.75,59.78 PR4706.1 PR4704.2
PWR_VCC_DROOP: length 5.6
  TOP w0.203: 39.72,47.34 39.87,47.49 PU4601.25
  TOP w0.254: PC4604.2 38.01,47.66 38.33,47.34 39.72,47.34 ; PC4604.2 v1(37.72,48.61) ; PC4604.2 36.96,47.66 PR4627.1 36.89,46.83 PR4619.1
PWR_VCC_F-IMAX: length 4.4
  TOP w0.203: 42.27,52.73 PU4601.10
  TOP w0.254: 42.27,52.73 43.18,53.64 v2(43.18,53.82) PR4607.1
  BOTTOM w0.254: PR4607.1 v2(43.18,53.82) 43.18,53.19 v1(42.91,52.92)
PWR_VCC_GFB: length 3.6
  TOP w0.203: v2(38.61,48.1) 38.48,48.23 38.48,48.88 38.73,49.13 PU4601.23
  BOTTOM w0.254: v2(38.61,48.1) 38.61,47.72 v1(38.99,47.34) 39.12,47.21 PR4616.2
PWR_VCC_IMON: length 3.2
  TOP w0.203: v1(40.61,53.41) 41.08,52.94 PU4601.13
  TOP w0.254: v1(40.61,53.41) 40.53,53.49 PR4610.1 40.53,55.09 PC4602.1
PWR_VCC_O-USR: length 5.7
  TOP w0.203: v2(43.31,52.29) 43.23,52.22 PU4601.9
  TOP w0.254: v2(43.31,52.29) 44.07,53.05 PR4608.1
  BOTTOM w0.254: v2(43.31,52.29) 44.07,53.05 v1(44.07,53.31) PR4608.1
PWR_VCC_OCP-1: length 3.3
  TOP w0.203: v1(41.84,53.45) 41.47,53.08 PU4601.12
  TOP w0.254: v1(41.84,53.45) 41.46,53.84 41.46,54.28 PR4610.2 41.41,55.09 PR4609.1
PWR_VCC_PWM1: length 38.5
  TOP w0.203: PU4601.6 44.41,50.73 v2(44.45,50.77)
  TOP w0.254: v2(53.98,74.9) 53.95,74.87 v1(53.95,74.26)
  L4 w0.254: v2(53.98,74.9) 53.98,75.53 52.07,77.44 47.24,77.44 46.48,76.68 46.48,73.6 44.96,72.08 44.96,51.19 44.66,50.89 44.58,50.89 v2(44.45,50.77)
  BOTTOM w0.203: v2(53.98,74.9) 53.6,74.53 PU4701.8
PWR_VCC_SKIP#: length 39.4
  TOP w0.203: PU4601.7 44.05,51.13 44.32,51.4 v2(44.45,51.4)
  TOP w0.254: v2(55.24,74.9) 55.24,74.54 v1(55.42,74.36)
  L4 w0.254: v2(44.45,51.4) 44.58,51.53 44.58,72.23 45.97,73.63 45.97,76.71 47.09,77.82 52.32,77.82 v2(55.24,74.9)
  BOTTOM w0.254: PR4702.1 v2(55.24,74.9)
PWR_VCC_SKIP#1: length 3.4
  BOTTOM w0.203: PU4701.1 53.84,70.95
  BOTTOM w0.254: 53.84,70.95 v1(55.24,72.36) PR4702.2
PWR_VCC_SLEWA: length 7.4
  TOP w0.203: PU4601.15 40.28,52.68 39.95,53 39.83,53
  TOP w0.254: 39.83,53 39.14,53.69 v2(38.86,53.69) 38.1,54.45 PR4612.2 37.57,53.98 v1(37.57,53.69)
  BOTTOM w0.254: PR4611.2 40.58,53.69 v2(38.86,53.69)
PWR_VCC_THERM: length 45
  TOP w0.203: PU4601.14 40.68,52.75 40.07,53.35
  TOP w0.254: 40.07,53.35 39.62,53.8 PC4603.2 39.05,54.26 v2(38.86,54.45)
  L3 w0.203: v2(55.88,71.09) 56.01,71.09 57.33,69.77 57.33,54.63 54.1,51.4 49.15,51.4 48.68,51.87 48.68,51.88 46.7,53.87 44.02,53.87 42.29,55.59 41.02,55.59 39.88,54.45 v2(38.86,54.45)
  BOTTOM w0.254: v2(55.88,71.09) 55.69,71.28 PR4602.2 ; v2(38.86,54.45) 38.93,54.51 v1(39.6,54.51) R3024.2
PWR_VCC_V5A: length 4.1
  TOP w0.203: PU4601.28 v1(41.08,46.7) 41.08,46.17 41.17,46.07
  TOP w0.254: 41.17,46.07 PC4607.1 PR4624.1
PWR_VCC_VBAT: length 3.9
  TOP w0.203: 39.52,52.22 PU4601.16
  TOP w0.254: v1(37.08,51.28) 37.08,51.78 37.62,52.32 PR4613.2 38.66,52.55 38.99,52.22 39.52,52.22
PWR_VCC_VDD: length 3.8
  TOP w0.203: PU4601.2 44.2,49.13
  TOP w0.254: PR4618.1 46.01,48.29 PC4601.1 45.2,48.29 v1(44.68,48.81) 44.36,49.13 44.2,49.13
PWR_VCC_VFB: length 2.4
  TOP w0.203: PU4601.24 39.19,48.15 v2(39.24,48.1)
  BOTTOM w0.254: PR4617.2 39.05,49.48 38.68,49.11 38.68,48.81 v1(38.91,48.58) 39.24,48.25 v2(39.24,48.1)
PWR_VCC_VREF: length 61.5
  TOP w0.203: 40.59,47.08 40.68,47.17 PU4601.27
  TOP w0.254: v2(36.96,48.61) 35.92,48.61 35.41,48.1 35.41,45.46 35.88,44.98 v1(36.45,44.98) 37.71,44.98 PR4620.2 38.61,45.88 PC4606.2 39.18,46.2 39.7,46.2 40.59,47.08
  L3 w0.203: v2(38.86,55.21) 39.24,54.83 39.79,54.83 40.88,55.92 42.11,55.92 v2(42.29,56.1) 44.2,54.2 46.86,54.2 49.33,51.73 53.97,51.73 56.95,54.71 56.95,69.39 v2(55.88,70.45)
  L4 w0.254: v2(36.96,48.61) 37.21,48.86 37.21,52.29 37.91,52.99 37.91,54.77 38.35,55.21 v2(38.86,55.21)
  BOTTOM w0.254: PR4611.1 PR4603.1 ; PR4603.1 PR4604.1 PR4605.1 ; PR4603.1 v2(42.29,56.1) ; v2(55.88,70.45) 55.82,70.39 PR4602.1
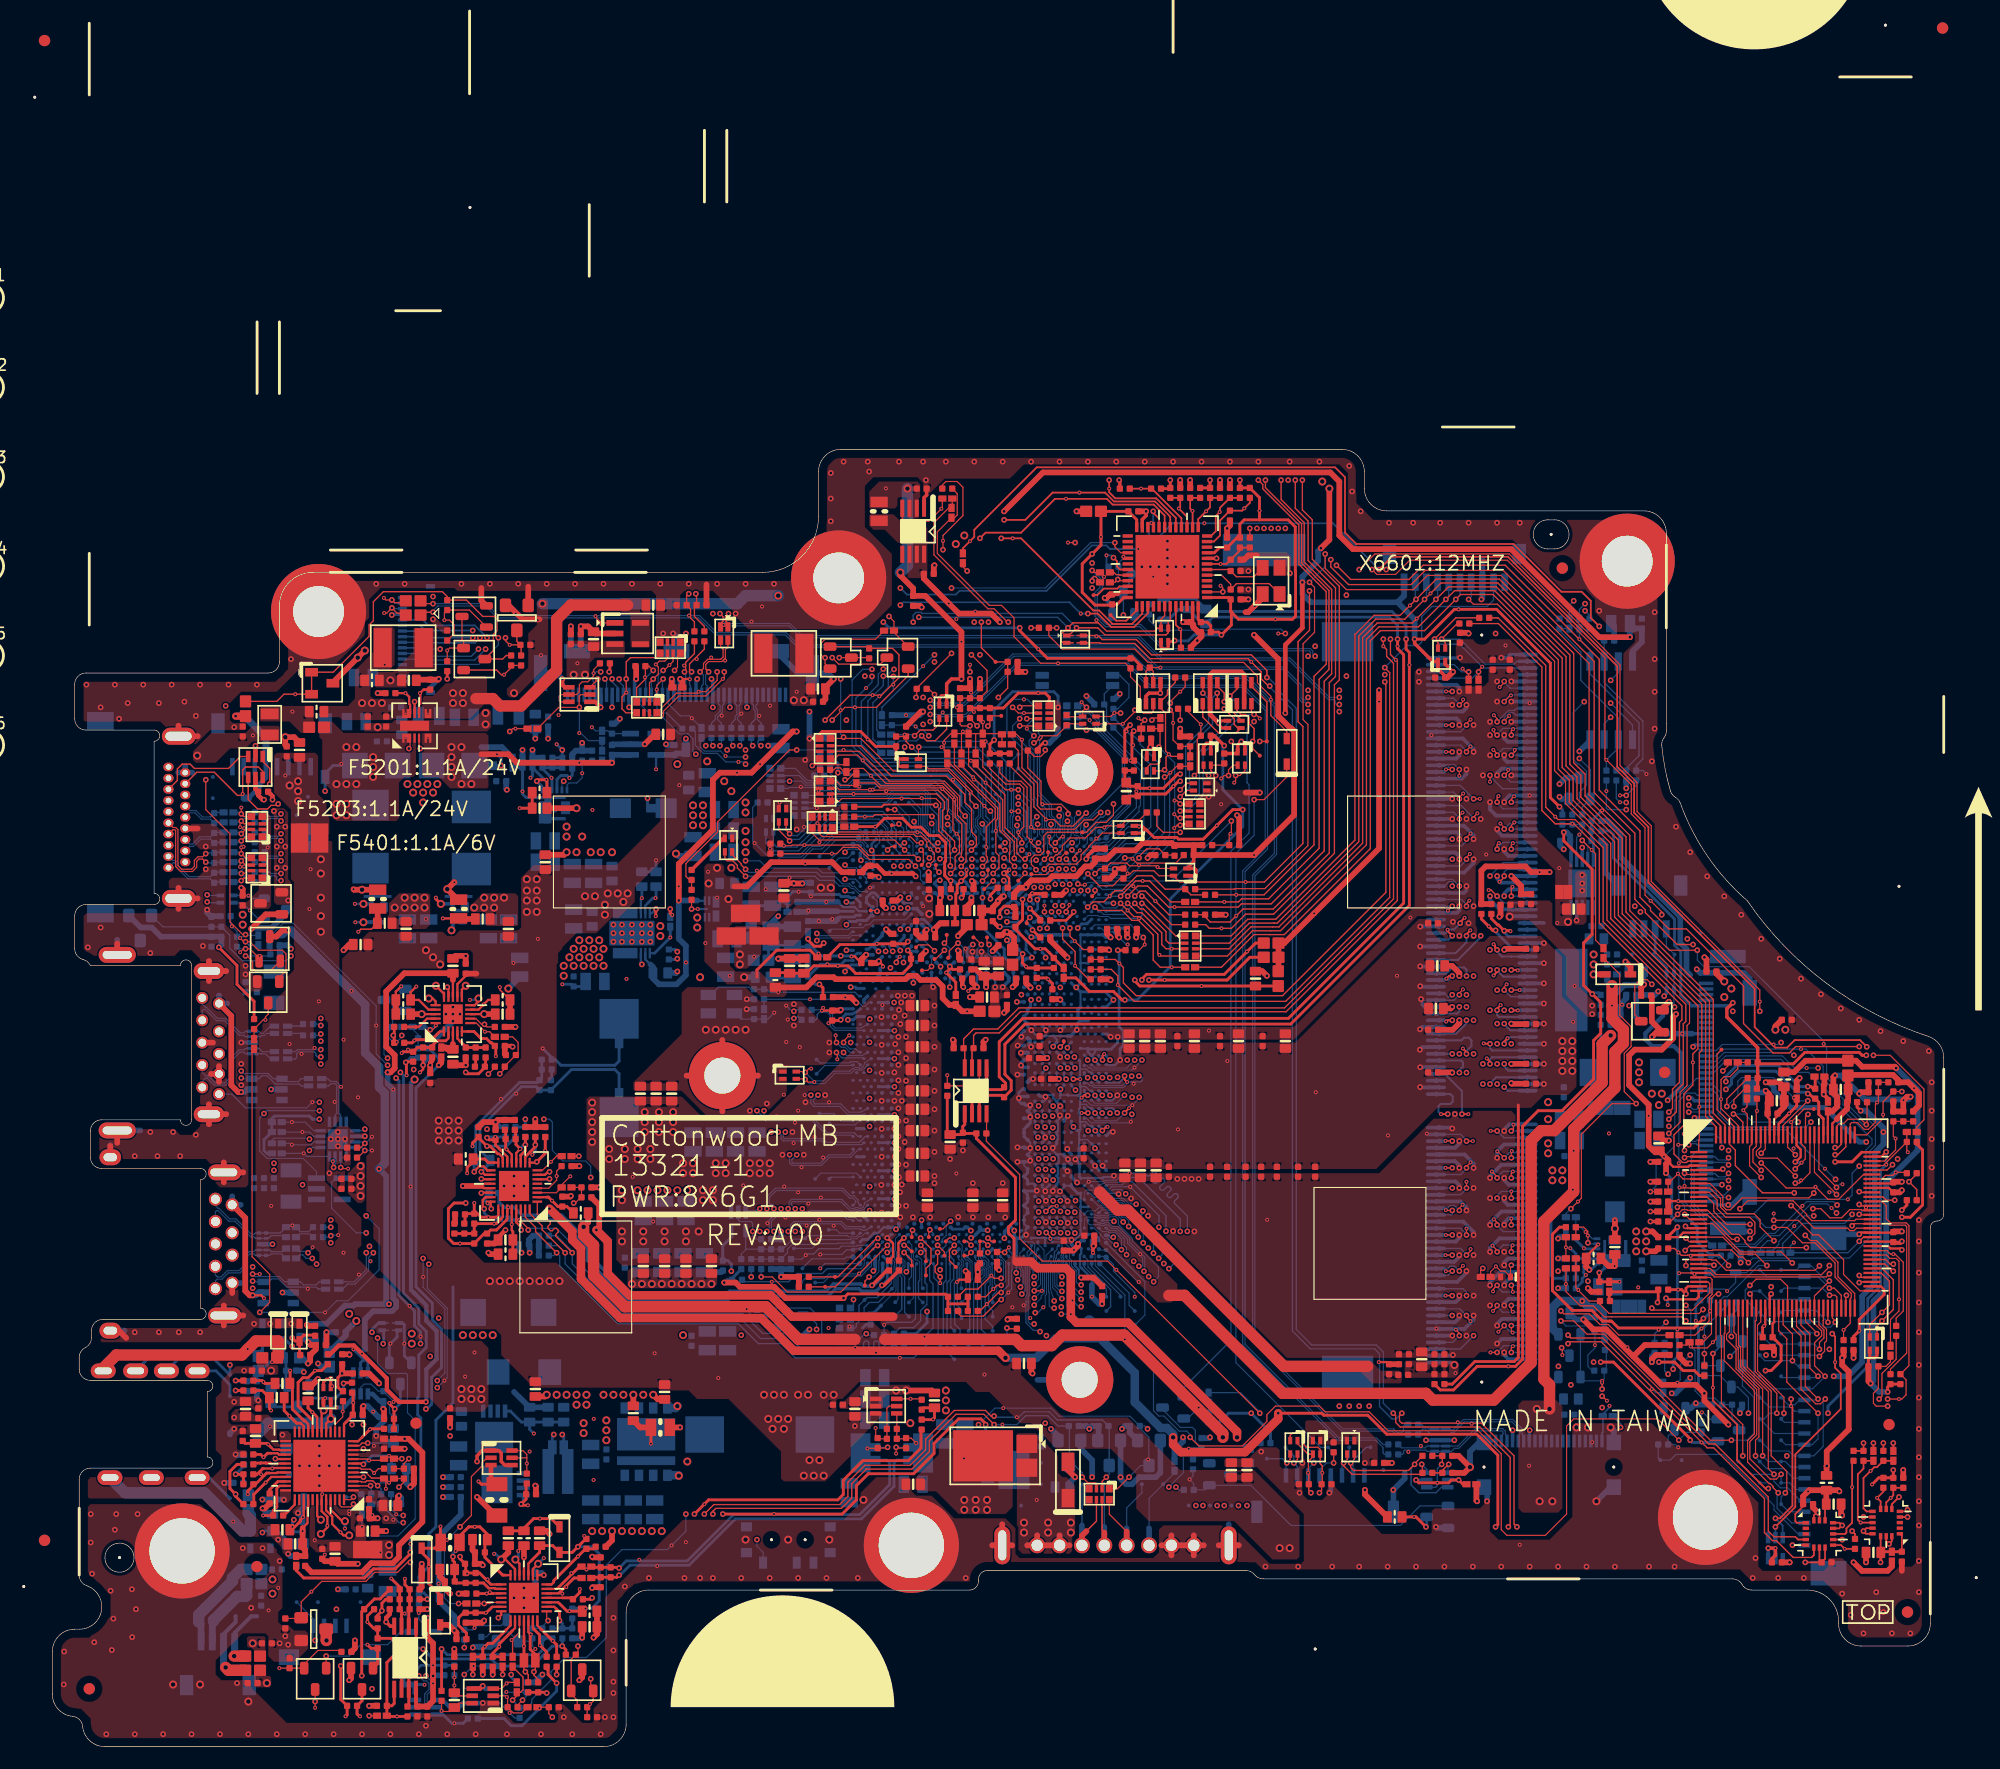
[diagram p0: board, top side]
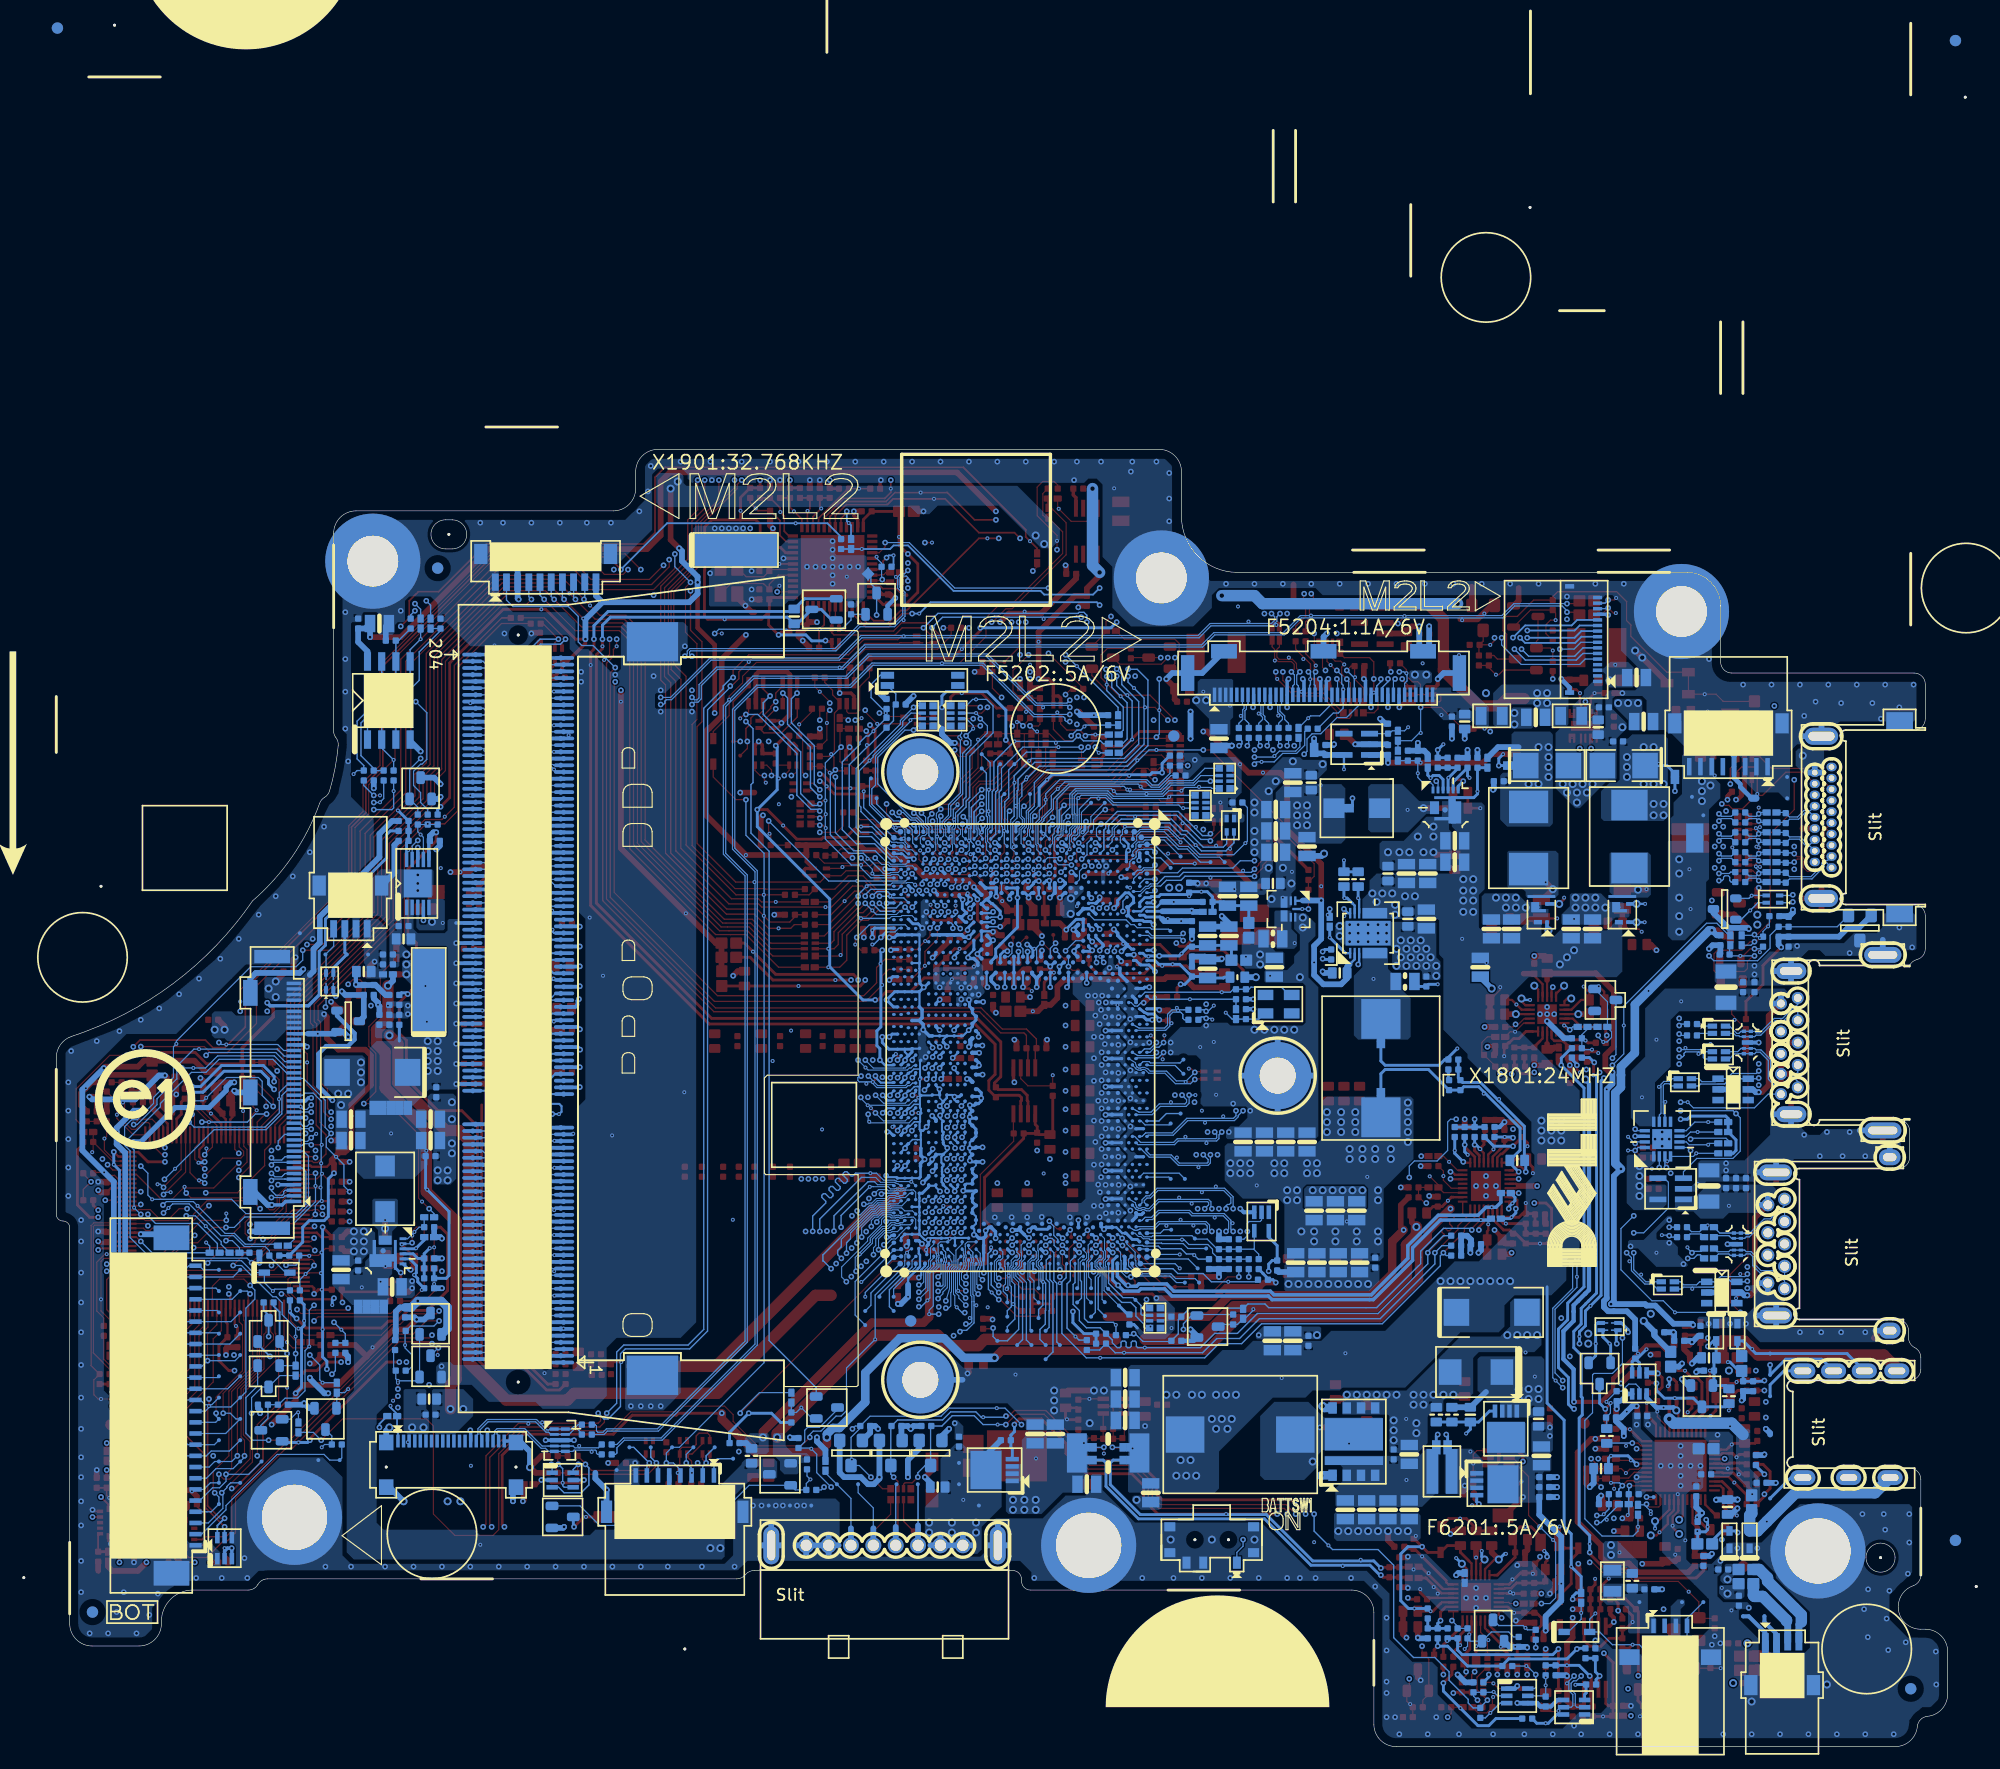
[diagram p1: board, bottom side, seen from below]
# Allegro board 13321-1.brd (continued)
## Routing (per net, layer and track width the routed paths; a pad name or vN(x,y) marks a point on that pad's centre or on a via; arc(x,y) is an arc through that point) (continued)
PWR_VCC_VSW1:
  vias: v1(51.33,68.65)
Q6204_G: length 6.8
  TOP w0.254: R6216.2 126.11,23.46 v2(125.73,23.84) 125.09,23.84 124.84,23.59 v1(123.83,23.59) 122.17,23.59 v2(121.92,23.84)
  BOTTOM w0.254: Q6204.2 v2(125.73,23.84) ; Q6204.5 v2(121.92,23.84)
Q6205_Q: length 3.4
  TOP w0.254: v2(122.81,19.65) 121.92,20.54 v1(121.74,20.54) R6210.2
  BOTTOM w0.254: v2(122.81,19.65) 122.87,19.72 Q6205.D
RING2: length 10.1
  TOP w0.203: v3(24.89,29.3) 24.48,28.89 HDA27.17
  TOP w0.305: v3(24.89,29.3) 24.89,30.33 24.89,30.34 RN2901.4
  BOTTOM w1.016: 18.29,27.91 19.3,28.92 24.51,28.92 v3(24.89,29.3)
  vias: v1(18.67,24.35)
RING2_R: length 16.5
  BOTTOM w1.016: HPMIC1.3 6.5,22.7 13.59,22.7 v1(16.17,20.12) 17,19.29 ED2903.2 17.7,20.67 17.53,20.85 R2906.2
RSMRST#_KBC: length 110.9
  TOP w0.102: R1702.2 101.28,94.77 v1(100.84,94.33) 99.95,93.44 v2(99.95,93.31) ; KBC24.15 147.97,47.56 150.17,45.36 v2(150.62,45.36)
  L3 w0.102: v2(99.95,93.31) 100.38,93.74 100.38,95.43 103.55,98.6 105.39,98.6 108.16,101.36 111.21,101.36 112.23,102.38 112.89,102.38 113.91,103.4 127.86,103.4 134.98,96.28 134.98,91.47 137.16,89.28 137.16,81.91 137.82,81.25 137.82,73.8 138.84,72.78 138.84,67.21 140.62,65.42 142.38,65.42 146.22,61.59 149.37,61.59 150.78,60.18 150.78,48.61 150.44,48.28 150.44,45.54 v2(150.62,45.36)
RSVDA51: length 2.2
  BOTTOM w0.102: CPU1.A51 69.63,50.93 TP606.1
RSVDAU63: length 3.8
  BOTTOM w0.102: TP602.1 94.23,40.91 92.26,42.89 CPU1.AU63
RSVDAV63: length 4
  BOTTOM w0.102: TP601.1 95.5,40.35 92.92,42.94 CPU1.AV63
RSVDB51: length 4.4
  BOTTOM w0.102: CPU1.B51 71.89,51.28 68.71,51.28 TP607.1
RSVDC62: length 6.6
  BOTTOM w0.102: CPU1.C62 73.23,43.57 73.23,43 72.31,42.08 69.53,42.08 68.95,41.5 TP604.1
RSVDC63: length 6.8
  BOTTOM w0.102: CPU1.C63 72.9,42.94 72.25,42.28 69.45,42.28 69.02,41.85 67.28,41.85 TP603.1
RSVDL60: length 2.2
  TOP w0.102: v2(77.64,44.82) 77.64,44.8 78.11,44.33 TP608.1
  BOTTOM w0.102: v2(77.64,44.82) 77.95,45.14 CPU1.L60
RSVDN59: length 1.2
  TOP w0.102: TP704.1 78.36,46.12 v2(78.45,46.22)
  BOTTOM w0.102: CPU1.N59 78.73,45.94 v2(78.45,46.22)
RSVDN61: length 1.7
  TOP w0.102: v2(79.15,44.83) 79.76,44.22 TP705.1
  BOTTOM w0.102: v2(79.15,44.83) 78.8,44.49 CPU1.N61
RSVDP60: length 3.4
  TOP w0.102: TP702.1 79.63,46.3 v2(80.31,46.98)
  BOTTOM w0.102: CPU1.P60 79.55,45.36 79.92,45.72 79.92,46.53 80.31,46.92 v2(80.31,46.98)
RSVDP61: length 2.7
  TOP w0.102: v2(80.64,45.49) 80.19,45.49 TP703.1
  BOTTOM w0.102: CPU1.P61 79.89,44.82 79.89,45.27 80.07,45.45 80.6,45.45 v2(80.64,45.49)
RTC_AUX_S5: length 143.2
  TOP w0.305: RN1901.1 102.11,77.87 102.23,78 102.23,78.4 102.11,78.53 RN1901.2 102.04,79.13 R1901.1
  TOP w0.508: 102.04,80.61 R1901.1 v1(107.44,79.72) 111.02,83.31 111.02,90.8 110.8,91.03 110.73,91.03 109.6,92.16 109.6,97.25 v2(107.44,99.41) ; 102.04,80.61 100.39,80.61 R1720.2 100.09,80.79 97.46,80.79 96.82,80.15 95.03,80.15 94.29,79.41 C1122.1 C1121.1 93.22,79.09 92.84,78.71 92.34,78.71 91.92,78.29 91.92,78.21 91.55,77.83 89.4,77.83 89.03,77.46 87.52,77.46 87.1,77.04 87.1,76.9 v2(87.05,76.85) 87,76.8 86.49,76.8 85.98,76.29 C1120.1 ; 102.04,80.61 R1903.1 ; R2428.2 155.96,59.53 v2(156.21,59.78)
  L3 w0.508: v2(150.24,65.75) 147.83,65.75 145.83,67.75 143.79,67.75 v2(143.57,67.53) 143.55,67.51 142.05,67.51 141.6,67.96 141.6,72.99 139.47,75.13 139.47,81.93 138.81,82.59 138.81,89.97 137.81,90.97 137.81,96.09 128.65,105.25 v2(119.25,105.25)
  L4 w0.508: v2(156.21,59.78) v2(150.24,65.75) ; v2(119.25,105.25) 119.25,104.99 118.37,104.11 115.19,104.11 112.57,101.49 109.52,101.49 v2(107.44,99.41)
  BOTTOM w0.305: CPU1.AG10 87.05,76.83 v2(87.05,76.85)
  BOTTOM w0.508: D2501.3 141.6,65.26 C2503.1 143.25,67.21 v2(143.57,67.53)
RTC_DET#: length 129.4
  TOP w0.102: v2(85.85,92.93) 86.36,92.42 RN2012.6 ; v2(143.89,74.39) 143.89,74.64 v1(142.9,75.63) 142.39,76.14 142.39,82.17 141.17,83.4 141.17,86.01 138.81,88.36 138.81,97.36 130.08,106.09 121.36,106.09 120.09,104.82 118.41,104.82 v2(117.98,105.25) ; v2(143,68.17) 142.59,68.58 141.95,68.58 141.48,68.11 141.48,65.44 Q2505.D
  L3 w0.102: v2(83.69,100.55) 83.69,95.85 85.85,93.69 v2(85.85,92.93) 85.85,92.68 84.9,91.73 84.9,88.32 84.43,87.85 84.43,79.67 v2(84.11,79.36) ; v2(143.89,74.39) 143,73.5 v2(143,68.17)
  L4 w0.102: v2(117.98,105.25) 117.53,104.79 113.94,104.79 111.5,107.23 105.9,107.23 105.61,106.94 105.61,102.3 105.11,101.8 92.34,101.8 91.02,100.48 86.21,100.48 85.85,100.12 84.12,100.12 v2(83.69,100.55)
  BOTTOM w0.102: CPU1.AD5 84.29,79.18 v2(84.11,79.36)
RTC_RST#: length 74.2
  TOP w0.102: 93.38,77.22 93.61,76.98 94.82,76.98 95.47,77.63 C1901.1 96.11,77.98 96.29,77.98 96.64,78.32 98.48,78.32 98.93,77.87 RN1901.4
  TOP w0.114: v2(112.39,103.35) 112.39,99.83 111.37,98.8 111.37,91.64 111.8,91.21 111.8,80.76 108.35,77.31 v1(106.68,77.31) 100.8,77.31 RN1901.4 ; 93.38,77.22 92.58,78.01 v2(92.58,78.06)
  L4 w0.127: v2(112.39,103.35) 111.51,103.35 111.12,103.73 111.12,106.52 110.91,106.74 106.51,106.74 106.11,106.33 106.11,102.09 105.32,101.3 95.87,101.3 v2(95.76,101.19)
  BOTTOM w0.089: CPU1.AU7 92.58,77.97 92.58,78.05 v2(92.58,78.06)
  BOTTOM w0.114: v2(95.76,101.19) Q1901.D 95.76,103.47 96.27,103.98 G1901.2
RTC_X1: length 20.7
  BOTTOM w0.089: CPU1.AW5 93.59,79.19 93.96,79.56 94.4,79.56 94.56,79.72
  BOTTOM w0.114: X1901.1 94.04,94.14 C1903.2 94.25,92.98 94.25,91.74 R1915.1 94.87,91.09 96.4,89.56 v1(96.62,89.56) 96.62,89.37 98.2,87.79 98.2,82.25 97.33,81.37 96.21,81.37 94.56,79.72
RTC_X2: length 23.1
  BOTTOM w0.114: X1901.4 95.43,95.8 96.25,94.98 96.25,93.81 95.24,92.79 C1904.2 R1915.2 96.04,90.84 v1(96.04,90.8) 96.46,90.37 96.69,90.37 97.25,89.81 97.25,89.63 98.83,88.05 98.83,87.54 98.83,81.99 97.58,80.74 95.94,80.74 94.42,79.23 CPU1.AY5
RTCRST_ON: length 103.5
  TOP w0.102: v2(152.78,50.89) 151.74,51.94 151.74,53.66 151.94,53.86 KBC24.120 ; v1(109.6,99.54) v2(110.24,99.54)
  L4 w0.102: v2(152.78,50.89) 153.8,51.91 153.8,59.4 139.94,73.25 139.94,74.12 137.95,76.11 137.95,88.72 136.53,90.14 136.53,96.74 130.05,103.22 121.41,103.22 120.78,102.59 117.54,102.59 114.64,99.69 110.39,99.69 v2(110.24,99.54)
  BOTTOM w0.102: v2(110.24,99.54) 109.86,99.92 103.79,99.92 103.71,99.83 98.96,99.83 98.04,100.74 R1902.1 Q1901.G
S5_ENABLE: length 212.4
  TOP w0.102: v2(38.99,60.14) 39.56,60.72 R3603.2 ; v1(135,35.02) 135,35.6 v2(134.94,35.67) ; v2(156.82,44.62) 151.82,44.62 151.33,45.1 151.33,45.26 150.78,45.81 150.14,45.81 148,47.96 KBC24.14 146.19,47.96 146.12,48.02 145.74,48.02 v2(145.3,47.59) 144.67,46.96 R2436.2
  L3 w0.102: v2(156.82,44.62) 156.82,44.32 156.46,43.96 156.46,40.73 151.18,35.45 151.18,34.22 151.18,34.22 151.18,33.71 151.18,33.71 151.18,33.37 145.95,28.14 145.11,28.14 138.35,21.38 108.48,21.38 107.52,22.35 98.78,22.35 96.52,24.61 85.29,24.61 81.05,28.85 81.05,31.97 77.24,35.78 66.83,35.78 62.05,40.56 39.22,40.56 31.44,48.34 27.46,48.34 27.03,48.77 27.03,55.44 32.13,60.55 v2(32.31,60.55)
  L4 w0.102: v2(145.3,47.59) 144.83,47.12 144.83,42.27 139.05,36.49 137.27,36.49 136.38,35.6 135,35.6 v2(134.94,35.67) ; v2(38.99,60.14) 38.4,59.56 33.63,59.56 32.64,60.55 v2(32.31,60.55)
  BOTTOM w0.102: Q2403.D 135.64,34.97 v2(134.94,35.67)
SA0_DIMA: length 5.3
  TOP w0.102: v1(127.84,96.56) 127.51,96.23 v2(127.51,96.11) R1201.1
  BOTTOM w0.102: DIMM1.197 126.95,95.55 v2(127.51,96.11)
SA1_DIMA: length 4.5
  TOP w0.102: R1202.1 v2(126.62,96.11) 126.36,96.11 v1(126.09,96.39)
  BOTTOM w0.102: DIMM1.201 125.34,96.75 125.98,96.11 v2(126.62,96.11)
SATA3_PRX_HDDTX_N0: length 128.5
  L4 w0.114: v2(76.52,78.73) 76.41,78.62 76.41,78.13 76.14,77.86 74.49,77.86 73.81,78.53 73.81,88.57 77.34,92.09 78.28,92.09 v2(78.49,92.3)
  BOTTOM w0.102: 79.6,92.3 v1(79.6,92.47) ; 79.6,92.3 v2(78.49,92.3) ; 79.6,92.3 81.64,92.3 86.23,96.89 96.17,96.89 98.15,94.91 106.48,94.91 108.64,92.75 108.64,80.26 106.63,78.24 106.63,35.99 115.02,27.6 118.39,27.6 118.97,27.02 C5616.1 ; v2(76.52,78.73) 76.81,79.02 CPU1.J5
SATA3_PRX_HDDTX_P0: length 128.4
  L4 w0.114: v2(75.88,78.73) 76.18,78.44 76.18,78.22 76.04,78.09 74.58,78.09 74.04,78.62 74.04,88.47 77.44,91.87 78.28,91.87 v2(78.49,91.66)
  BOTTOM w0.102: v2(78.49,91.66) 78.79,91.66 78.92,91.79 78.92,91.97 79.04,92.09 81.72,92.09 82.27,92.65 ; C5615.1 119.1,26.13 118.97,26.26 118.97,26.73 118.31,27.4 114.94,27.4 106.43,35.91 106.43,78.33 108.44,80.34 108.44,92.66 106.39,94.71 98.07,94.71 96.09,96.69 86.32,96.69 82.27,92.65 ; v2(75.88,78.73) 75.88,79.1 76,79.21 CPU1.H5 ; 82.27,92.65 v1(82.4,92.53)
SATA3_PTX_HDDRX_N0: length 140.1
  L4 w0.114: v2(78.49,92.93) 78.31,93.11 77.66,93.11 72.73,88.18 72.73,79.84 73.05,79.51 73.05,77.55 71.68,76.17 71.68,74.95 69.05,72.32 68.59,72.32 v2(68.35,72.08)
  BOTTOM w0.102: v2(78.49,92.93) 78.66,93.11 80.87,93.11 ; v2(68.35,72.08) 68.58,72.31 71.23,72.31 71.46,72.54 CPU1.B15 ; 80.87,93.11 81.56,93.11 85.95,97.5 96.43,97.5 98.41,95.52 106.73,95.52 109.25,93 109.25,79.88 107.31,77.95 107.31,36.17 115.27,28.21 119.83,28.21 120.13,27.91 C5603.1 ; 80.87,93.11 v1(80.87,92.93)
SATA3_PTX_HDDRX_P0: length 140
  L4 w0.114: v2(78.49,93.57) 78.26,93.34 77.56,93.34 72.5,88.27 72.5,79.74 72.82,79.42 72.82,77.64 71.45,76.27 71.45,75.04 68.95,72.54 68.52,72.54 v2(68.35,72.71)
  BOTTOM w0.102: C5602.1 120.93,28.8 120.8,28.67 120.8,28.24 120.68,28.11 120.22,28.11 119.91,28.42 115.36,28.42 107.52,36.25 107.52,77.86 109.46,79.8 109.46,93.08 106.81,95.73 98.49,95.73 96.51,97.71 85.87,97.71 82.28,94.12 ; 82.28,94.12 81.48,93.31 78.74,93.31 v2(78.49,93.57) ; 82.28,94.12 v1(82.14,94.25) ; CPU1.A15 71.5,72.87 71.14,72.51 68.55,72.51 v2(68.35,72.71)
SATA_IREF: length 5
  BOTTOM w0.254: CPU1.A12 70.21,74.7
  BOTTOM w0.508: 70.21,74.7 67.64,74.7 v1(67.59,74.75) 67.49,74.64 R1904.1
SATA_LED#: length 17.4
  BOTTOM w0.089: 81,83.03 81,82.88 81.34,82.54 81.34,80.76 CPU1.U3
  BOTTOM w0.102: R1905.2 69.44,86.84 70.48,85.79 71.2,85.79 71.69,86.27 78.92,86.27 v1(79.56,85.64) 80.14,85.06 80.14,83.89 81,83.03
SATA_ODD_PWRGT: length 1.3
  TOP w0.102: v2(79.27,78.19) 78.99,78.47 TP2004.1
  BOTTOM w0.102: v2(79.27,78.19) 78.94,78.53 CPU1.N6
SATA_RCOMP: length 6.5
  BOTTOM w0.203: 70.23,75.53 70.69,75.08 71.73,75.08 72.11,74.7 CPU1.C12
  BOTTOM w0.508: 70.23,75.53 v1(69.19,75.53) R1906.1
SATA_RXN0_R: length 11.6
  BOTTOM w0.102: 122.35,26.72 122.73,26.72 122.89,26.88 U5602.7 U5602.4 125.66,26.88 127.22,28.44 129.69,28.44 129.9,28.22 129.9,27.95 130.05,27.8 HDD1.18 ; 122.35,26.72 120.63,26.72 C5616.2 ; 122.35,26.72 v1(122.35,26.89)
SATA_RXP0_R: length 11.5
  BOTTOM w0.102: 121.23,26.51 122.81,26.51 122.92,26.4 U5602.6 U5602.5 125.09,26.4 125.36,26.68 125.74,26.68 127.3,28.23 129.6,28.23 129.7,28.14 129.7,27.96 129.55,27.81 HDD1.19 ; 121.23,26.51 v1(121.23,26.36) ; 121.23,26.51 120.9,26.51 120.8,26.41 120.8,26.23 120.7,26.13 C5615.2
SATA_TXN0_R: length 11.6
  BOTTOM w0.102: C5603.2 122.11,28 122.53,28.42 122.76,28.42 123.25,27.92 U5602.9 U5602.2 124.89,27.92 125.08,28.11 125.31,28.11 126.24,29.05 126.9,29.05 ; v1(126.9,28.87) 126.9,29.05 ; 126.9,29.05 130.49,29.05 131.2,28.34 131.2,27.96 131.05,27.81 HDD1.16
SATA_TXP0_R: length 11.6
  BOTTOM w0.102: 125.78,28.87 126.16,29.25 130.58,29.25 131.4,28.42 131.4,27.93 131.55,27.78 HDD1.15 ; 125.78,28.87 125.22,28.31 125.07,28.31 124.98,28.4 U5602.1 U5602.10 123.06,28.4 122.84,28.62 122.61,28.62 122.43,28.8 C5602.2 ; 125.78,28.87 v1(125.65,29)
SENSOR_HUB_RST#: length 57
  TOP w0.102: v2(91.44,107.66) v1(90.81,107.66) ; v2(107.06,108.93) R6603.2
  L3 w0.102: v2(78.41,79.46) 78.41,80.48 78.42,80.49 78.42,81.51 77.84,82.1 77.84,83.9 75.77,85.97 75.77,94.41 78.11,96.74 78.11,98.9 81.53,102.33 86.11,102.33 v2(91.44,107.66)
  L4 w0.102: v2(91.44,107.66) 93.03,109.25 104.38,109.25 104.51,109.38 106.62,109.38 v2(107.06,108.93)
  BOTTOM w0.102: v2(78.41,79.46) 78.1,79.78 CPU1.L4
SENSOR_I2C_SCL: length 79.7
  TOP w0.114: U6601.42 99.45,101.14 99.12,100.81 RN6601.4 98.81,100.01 98.55,99.75 94.25,99.75 93.51,100.49 91.25,100.49 v2(90.81,100.04) 90.76,100.04 90.17,99.45 90.17,98.9 90.37,98.7 RN6604.2
  L3 w0.127: v2(38.1,98.14) 39.12,97.12 49.4,97.12 50.23,96.29 50.23,95.66 v2(50.04,95.47)
  L4 w0.127: v2(50.04,95.47) 50.04,95.5 51.62,97.08 67.42,97.08 68.54,98.2 72.68,98.2 75.53,101.06 77.4,101.06 v2(77.47,100.99)
  BOTTOM w0.114: v1(80.82,100.83) 80.82,100.99 ; 80.82,100.99 v2(77.47,100.99) ; 80.82,100.99 89.86,100.99 v2(90.81,100.04) ; v2(50.04,95.47) 50.04,95.22 50.55,94.71 LCD1.31 ; v2(38.1,98.14) 37.47,97.5 33.34,97.5 32.6,98.25 HOMBD1.7
SENSOR_I2C_SCL_2G: length 157.8
  TOP w0.114: v2(108.84,94.84) 108.73,94.84 108.08,95.49 108.08,96.11 v1(107.19,97) 106.9,97.29 98.13,97.29 96.77,98.65 93.73,98.65 93.67,98.7 RN6604.3 ; v2(130.94,19.65) 130.68,19.91 130.68,26 127.76,28.92 120.65,28.92 120.44,29.13 120.44,29.6 v2(120.65,29.81)
  TOP w0.152: v2(165.86,20.53) U6602.4
  L4 w0.127: v2(130.94,19.65) 131.06,19.53 138.05,19.53 143.13,24.61 151.16,24.61 159.8,15.97 165.45,15.97 165.94,16.46 165.94,20.46 v2(165.86,20.53)
  BOTTOM w0.114: v2(108.84,94.84) 108.84,94.74 110.87,92.7 110.87,37.16 112.47,35.57 118.22,35.57 118.66,35.13 118.66,30.41 119.76,29.3 120.14,29.3 v2(120.65,29.81)
SENSOR_I2C_SDA: length 79.9
  TOP w0.114: U6601.43 99.94,100.73 99.77,100.55 RN6601.3 99.77,99.61 99.57,99.41 94.11,99.41 93.47,100.04 v2(91.57,100.04) 90.88,99.35 RN6604.1
  L3 w0.127: v2(50.67,95.46) 50.67,95.6 50.61,95.66 50.61,96.45 49.55,97.5 39.37,97.5 v2(38.73,98.14)
  L4 w0.127: v2(76.96,100.55) 76.83,100.68 75.69,100.68 72.83,97.82 68.7,97.82 67.58,96.7 51.78,96.7 50.67,95.6 v2(50.67,95.46)
  BOTTOM w0.114: LCD1.30 51.05,94.84 50.67,95.22 v2(50.67,95.46) ; 82.52,101.33 77.75,101.33 77.65,101.43 77.22,101.43 76.96,101.17 v2(76.96,100.55) ; 82.52,101.33 v1(82.52,101.49) ; 82.52,101.33 90.28,101.33 v2(91.57,100.04) ; HOMBD1.6 32.61,97.75 33.2,97.16 37.76,97.16 v2(38.73,98.14)
SENSOR_I2C_SDA_2G: length 161.9
  TOP w0.114: RN6604.4 93.27,99.35 v1(93.34,99.28) 93.58,99.28 93.87,98.99 96.92,98.99 98.28,97.63 107.19,97.63 108.58,96.23 v2(108.58,95.6) ; v2(130.18,19.65) 130.34,19.82 130.34,25.86 127.62,28.58 120.51,28.58 120.1,28.99 120.1,29.6 v2(119.89,29.81)
  TOP w0.152: v2(165.1,22.32) 164.46,21.68 U6602.6
  L4 w0.127: v2(165.1,22.32) 166.07,22.32 166.32,22.07 166.32,16.3 165.61,15.59 159.64,15.59 151,24.22 143.29,24.22 138.21,19.14 130.68,19.14 v2(130.18,19.65)
  BOTTOM w0.114: v2(119.89,29.81) 119,30.7 119,35.27 118.36,35.91 112.61,35.91 111.21,37.31 111.21,92.85 109.47,94.59 109.47,94.84 108.71,95.6 v2(108.58,95.6)
SLEEVE: length 12.5
  TOP w0.203: v3(24.26,30.07) 24.08,29.89 HDA27.18
  TOP w0.305: RN2901.3 24.24,30.09 v3(24.26,30.07)
  L3 w1.016: v3(24.26,30.07) 20.7,33.62 v3(19.56,33.62)
  BOTTOM w0.406: v3(24.26,30.07) 24.51,30.32 v1(25.4,30.32) 26.04,30.32 26.91,31.19 U2901.3
SLEEVE_CTRL: length 4.2
  BOTTOM w0.254: R2915.2 27.56,34.32 U2901.5 ; R2915.2 28.21,34.43 U2901.6 ; R2915.2 27.75,34.7 v1(26.92,35.53)
SLEEVE_R: length 18.5
  TOP w1.016: R2911.2 20.19,34.87 ED2905.2 18.2,36.27 v1(17.48,35.55) 16.94,35.02 5.71,35.02 4.55,33.85 HPMIC1.4
SM_DRAMRST#: length 112.1
  TOP w0.102: R404.1 127.7,42.58 v2(127.89,42.77) ; R410.2 97.16,71.21 v1(97.66,71.72) 97.66,72.23 v2(97.54,72.36)
  L3 w0.102: v2(127.89,42.77) 128.14,42.51 130.81,42.51 131.25,42.96 131.25,95.25 130.57,95.93 128.49,95.93 127.68,96.74 125.48,96.74 125.09,97.12 116.22,97.12 112.98,93.88 112.98,91.13 101.09,79.24 101.09,76.68 97.54,73.12 v2(97.54,72.36)
  BOTTOM w0.102: CPU1.AV15 92.91,73.2 93.2,73.49 96.41,73.49 v2(97.54,72.36)
SM_INTRUDER#: length 9.8
  TOP w0.102: v2(95.89,79.47) 96.49,79.47 v1(96.57,79.39) 96.96,79.01 100.44,79.01 R1901.2
  BOTTOM w0.089: CPU1.AU6 92.55,78.76 93.04,78.76 93.08,78.72 94.59,78.72 94.75,78.89 95.3,78.89 v2(95.89,79.47)
SM_RCOMP_0: length 2.3
  TOP w0.508: v2(91.71,44.96) 91.71,44.79 v1(91.34,44.42) 91.27,44.35 R407.2
  BOTTOM w0.305: v2(91.71,44.96) 91.99,45.25 CPU1.AU60
SM_RCOMP_1: length 2.1
  TOP w0.305: v1(93.04,44.16) 93.04,44.71 v2(93.08,44.76)
  TOP w0.508: v2(93.08,44.76) 93.15,44.83 R408.2
  BOTTOM w0.305: CPU1.AV60 92.91,44.92 v2(93.08,44.76)
SM_RCOMP_2: length 6.7
  TOP w0.508: R409.2 v2(93.85,39.59)
  BOTTOM w0.203: 92.94,41.3 92.94,41.86 92.03,42.78 91.88,42.93 91.88,43.97 91.99,44.08 CPU1.AU61
  BOTTOM w0.508: v2(93.85,39.59) 93.58,39.59 v1(92.94,40.23) 92.94,41.3
SMB_CLK: length 27.5
  TOP w0.114: v2(100.84,83.66) 100.84,83.66 RN1807.6 ; v1(107.95,91.94) 107.59,92.3 v2(107.44,92.3) 107.2,92.54 Q1801.3
  L4 w0.127: v2(100.84,83.66) 100.71,83.79 99.22,83.79 98.14,82.71 93.28,82.71 92.96,83.03 92.2,83.03 v2(91.74,83.48)
  BOTTOM w0.089: CPU1.AP2 91.08,81.45 91.08,82.21 91.37,82.5 91.37,83.11 v2(91.74,83.48)
  BOTTOM w0.114: v2(107.44,92.3) 106.38,92.3 102.89,88.81 102.89,85.08 101.63,83.81 100.99,83.81 v2(100.84,83.66)
SMB_DATA: length 33.7
  TOP w0.114: RN1807.5 100.85,84.31 v2(100.84,84.3) 100.53,84.6 v1(100.33,84.6) ; Q1801.6 105.9,94.57 v2(105.28,93.95)
  L4 w0.127: v2(100.84,84.3) 100.71,84.17 99.06,84.17 97.98,83.09 93.54,83.09 92.65,83.98 90.54,83.98 90.23,84.28 86.37,84.28 v2(86.36,84.27)
  BOTTOM w0.114: v2(105.28,93.95) 105.89,93.34 105.89,92.3 102.55,88.95 102.55,85.22 101.48,84.16 100.98,84.16 v2(100.84,84.3) ; CPU1.AH1 87.05,83.58 v2(86.36,84.27)
SML0_CLK: length 14.9
  TOP w0.114: v1(100.3,83.38) 100.66,83.03 v2(100.84,83.03) 100.97,83.16 RN1807.7
  L4 w0.127: v2(90.02,83.2) 90.02,82.9 90.11,82.81 90.11,82.78 90.57,82.31 91.9,82.31 92.21,82 98.51,82 99.41,82.9 100.71,82.9 v2(100.84,83.03)
  BOTTOM w0.114: v2(90.02,83.2) 90.09,83.13 90.09,81.86 CPU1.AN1
SML0_DATA: length 16.9
  TOP w0.114: v1(100.3,82.14) 100.56,82.39 v2(100.84,82.39) 100.95,82.51 RN1807.8
  L4 w0.127: v2(100.84,82.39) 100.71,82.52 99.57,82.52 98.67,81.62 98.35,81.62 92.06,81.62 91.74,81.93 90.41,81.93 89.73,82.62 89.73,82.65 89.22,83.15 v2(88.01,83.15)
  BOTTOM w0.114: CPU1.AK1 87.8,82.15 87.68,82.27 87.68,82.85 87.98,83.15 v2(88.01,83.15)
SML1_CLK: length 157.9
  TOP w0.114: v2(161.54,41.5) 161.6,41.56 KBC24.67 ; Q2601.3 104.16,94.19 v2(104.14,94.2) ; RN1811.4 101.4,85.49 v2(100.84,84.93) ; v2(138.56,31.97) v1(138.56,32.53)
  L3 w0.127: v2(138.56,31.97) 138.56,32.2 137.51,33.24 136.11,33.24 133.83,35.53 133.83,39.43 135.23,40.84 135.23,45.64 131.83,49.04 131.83,95.49 130.79,96.53 128.74,96.53 127.8,97.47 126.4,97.47 124.38,99.49 113.37,99.49 111.78,97.9 109.76,97.9 106.58,94.72 104.66,94.72 v2(104.14,94.2)
  L4 w0.127: v2(100.84,84.93) 100.71,85.06 94.71,85.06 94.07,84.42 94.07,83.82 v2(94.36,83.53) ; v2(161.54,41.5) 161.67,41.37 161.67,34.6 159.49,32.42 144.44,32.42 143.9,31.88 138.65,31.88 v2(138.56,31.97)
  BOTTOM w0.089: CPU1.AU3 92.53,80.8 92.53,81.49 92.58,81.54 92.58,82.01 93.09,82.52
  BOTTOM w0.114: v2(94.36,83.53) 93.95,83.12 93.69,83.12 93.09,82.52 ; v2(100.84,84.93) 101.67,85.76 101.67,89.37 103.72,91.42 103.72,93.78 v2(104.14,94.2)
SML1_DATA: length 169.6
  TOP w0.114: RN1811.3 101.42,86.15 v2(100.84,85.57) ; v1(138.99,30.93) 138.58,31.34 v2(138.56,31.34) ; Q2601.6 102.85,94.22 v2(102.87,94.2) ; KBC24.68 161.72,41.96 v2(161.54,42.13)
  L3 w0.127: v2(138.56,31.34) 139,31.78 139,32.29 137.67,33.62 136.27,33.62 134.21,35.69 134.21,39.28 135.61,40.68 135.61,45.79 132.21,49.2 132.21,95.64 130.94,96.91 128.9,96.91 127.96,97.85 126.56,97.85 124.54,99.87 113.21,99.87 111.62,98.28 109.6,98.28 106.43,95.1 103.77,95.1 v2(102.87,94.2)
  L4 w0.127: v2(138.56,31.34) 138.72,31.5 144.06,31.5 144.6,32.04 159.65,32.04 162.05,34.44 162.05,41.62 v2(161.54,42.13) ; v2(86.36,84.91) 90.15,84.91 90.7,84.36 93.47,84.36 94.55,85.44 100.71,85.44 v2(100.84,85.57)
  BOTTOM w0.089: 87.3,83.13 87.3,82.12 87.33,82.08 87.33,80.94 87.09,80.69 CPU1.AH3
  BOTTOM w0.114: v2(100.84,85.57) 101.33,86.05 101.33,89.51 103.38,91.56 103.38,93.69 v2(102.87,94.2) ; v2(86.36,84.91) 86.36,84.91 87.29,83.98 87.29,83.13 87.3,83.13
SPI_CLK_R: length 16.1
  BOTTOM w0.114: R1806.1 138.49,98.9 EC2503.1 138.73,98.89 SPI25.6 138.73,95.17 142.2,91.7 142.2,88.32 141.6,87.72 R2420.1 142.2,87.28 v1(142.52,86.96)
SPI_CS0#_R: length 151.5
  TOP w0.114: R2501.1 166.69,49.82 v2(165.99,50.51) 166.69,51.21 R2419.1
  L4 w0.127: v2(74.3,95.73) 74.8,96.23 74.8,96.61 75.31,97.12 76.41,97.12 90.72,111.44 112.32,111.44 116.6,107.16 129.65,107.16 140,96.8 140,94 v2(139.32,93.31) 141.22,91.41 141.22,80.77 166.41,55.58 166.41,51.19 165.99,50.77 v2(165.99,50.51)
  BOTTOM w0.114: R1807.1 v1(72.91,90.06) 72.91,93.5 74.3,94.89 v2(74.3,95.73) ; SPI25.1 141.27,91.36 v2(139.32,93.31)
SPI_HOLD#: length 87.6
  L4 w0.127: v2(75.25,96.33) 75.66,96.74 76.57,96.74 90.88,111.05 112.16,111.05 116.44,106.77 129.49,106.77 139.32,96.95 v2(139.32,95.34)
  BOTTOM w0.114: v2(75.25,96.33) 75.17,96.33 74.73,95.89 74.73,94.72 v1(73.94,93.92) 73.36,93.34 73.36,90.1 73.78,89.68 R1812.1 ; v2(139.32,95.34) 140,96.03 SPI25.7
SPI_SI_R: length 16.3
  BOTTOM w0.114: R1808.1 v1(136.53,99.03) 137.46,98.09 SPI25.5 137.46,95.93 141.86,91.53 141.86,88.61 140.72,87.47 EC2501.1 R2422.1
SPI_SO_R: length 16.2
  BOTTOM w0.114: R2423.1 v1(138.94,88.23) 140,89.3 SPI25.2 140,91.99 136.65,95.34 136.65,97.88 134.75,99.79 EC2502.1 R1809.1
SPI_WP#: length 88.4
  L4 w0.127: v2(139.32,92.04) 138.81,92.55 138.81,96.6 138.81,96.92 129.33,106.39 116.29,106.39 112.55,110.13 103.87,110.13 103.76,110.01 90.38,110.01 76.72,96.36 76.07,96.36 75.41,95.7 v2(75.18,95.7)
  BOTTOM w0.114: SPI25.3 138.73,91.46 v2(139.32,92.04) ; v2(75.18,95.7) v1(75.18,94.96) 75.18,94.43 73.7,92.95 73.7,90.89 R1811.1
SRTC_RST#: length 8.2
  TOP w0.102: RN1901.3 98.94,78.53 v1(98.81,78.65) 98.7,78.77 96.3,78.77 96.05,79.01 94.6,79.01 C1902.1 93.67,78.52 v2(93.22,78.06)
  BOTTOM w0.089: v2(93.22,78.06) 93.22,78.17 CPU1.AV6
SUS_CLK: length 144.3
  L4 w0.127: v2(78.87,97.63) 78.87,97.94 90.55,109.62 104.23,109.62 104.36,109.75 112.39,109.75 116.13,106.01 129.18,106.01 138.43,96.76 138.43,91.51 139.51,90.43 139.51,80.32 158.65,61.18 158.65,59.92 161.04,57.53 161.04,47.72 v2(160.91,47.59)
  BOTTOM w0.114: R2441.2 154.69,44.36 154.69,44.99 156.49,46.78 160.23,46.78 160.91,47.47 v2(160.91,47.59) ; R1710.2 74.17,92.93 v1(77.85,96.61) v2(78.87,97.63)
SUS_CLK_PCH: length 19.8
  L4 w0.127: v2(85.07,78.72) 84.57,79.23 84.57,81.69 84.19,82.07 84.19,82.11 83.16,83.14 83.16,85.97 78.74,90.39 v2(78.36,90.39)
  BOTTOM w0.114: CPU1.AE6 85.27,78.53 v2(85.07,78.72) ; v2(78.36,90.39) 77.85,90.9 77.5,90.9 v1(77.18,91.22) 77.06,91.34 EC1701.2 R1710.1
SUSCLK_KBC: length 8.9
  TOP w0.114: KBC24.77 161.92,45.56 v2(161.54,45.18)
  BOTTOM w0.114: v2(161.54,45.18) 160.53,44.16 R2441.1 155.38,44.76 v1(155.7,45.08)
SWCLK: length 3.3
  TOP w0.152: U6601.37 96.94,101.61 96.01,100.68 95.12,100.68 TP6602.1
SWDIO: length 3.4
  TOP w0.152: TP6601.1 93.42,102.96 94,103.55 95.21,103.55 95.41,103.75 U6601.34
SYS_PRES1#: length 50.9
  L3 w0.102: 98.05,19.27 96.4,20.91 86.47,20.91 84.15,23.23 75.11,23.23 69.11,17.24 64.26,17.24 v2(62.99,18.51)
  L3 w0.508: BATT1.6 98.05,19.27
  BOTTOM w0.102: v2(62.99,18.51) 62.99,17.93 63.55,17.37 BATSW1.1 ; R4301.1 100.33,24.48 AFTP4304.1 98.05,22.2 98.05,19.53
  BOTTOM w0.508: BATT1.6 98.05,19.53
SYS_PWROK: length 153
  TOP w0.114: v2(161.54,62.6) 155.86,62.6 155.29,62.03 153.83,62.03 151.2,64.66 151.2,68.02 146.1,73.12 144.52,73.12 142.88,74.76 142.88,75.02 141.94,75.95 141.94,81.88 138.3,85.52 138.3,97.23 129.9,105.64 122.56,105.64 121.28,104.37 116.07,104.37 v2(114.81,105.63) ; v2(83.06,100.55) 83.06,98.27 TP9644.1 R1717.1 EC1702.1 85.41,94.65 v2(84.58,93.82) ; KBC24.84 161.67,48.36 v2(161.54,48.48)
  L3 w0.127: v2(161.54,48.48) 161.04,48.99 161.04,51.02 160.59,51.47 160.59,57.28 161.04,57.73 161.04,62.09 v2(161.54,62.6)
  L4 w0.127: v2(86.33,83) 85.92,83.42 85.92,90.29 85.22,90.99 85.22,91.92 84.58,92.55 v2(84.58,93.82) ; v2(83.06,100.55) 83.8,101.29 86.87,101.29 93.82,108.25 103.85,108.25 104.17,107.93 111.79,107.93 114.09,105.63 v2(114.81,105.63)
  BOTTOM w0.089: v2(86.33,83) 86.68,82.65 86.68,82.13 86.59,82.04 86.59,81.6 86.3,81.31 CPU1.AG2
T_CRIT#: length 45.7
  TOP w0.102: THM261.4 83.53,54.85 R2604.2 83.5,54.13 86.49,51.15 86.49,45.44 88.51,43.41 94.35,43.41 v1(95.12,42.64) v2(107.95,29.81)
  BOTTOM w0.102: R2601.1 106.23,31.65 107.95,29.94 v2(107.95,29.81)
TD_IREF: length 4.9
  BOTTOM w0.254: CPU1.B12 71.84,74.35 71.68,74.19 70.41,74.19 70.23,74.01
  BOTTOM w0.508: R603.2 v1(68.53,73.82) 70.04,73.82 70.23,74.01
THERM_SYS_SHDN#: length 3.7
  BOTTOM w0.102: Q2602.S 101.5,29.34 v1(102.49,30.32) 102.93,29.88 R2602.1 R2601.2
THM_SML1_CLK: length 90.8
  TOP w0.114: Q2601.4 104.16,94.82 104.78,94.2 v2(104.78,93.44) 105.21,93 105.21,92.85 106.26,91.8 RN2602.4 ; THM261.8 81.57,62.35 C2608.1 81.47,63.28 82.36,64.17 84.52,64.17 85.85,65.5 86.41,66.06 110.16,66.06 119.91,75.8 119.91,96.87 119.29,97.49 119.29,98.1 v1(119,98.39) v2(119,99.03)
  L3 w0.127: v2(119,99.03) 118.86,98.89 114.95,98.89 112.62,96.57 112.03,96.57 108.78,93.31 104.9,93.31 v2(104.78,93.44)
THM_SML1_DATA: length 94.8
  TOP w0.114: THM261.7 82.22,62.32 C2609.1 82.36,63.59 82.59,63.82 84.66,63.82 86.19,65.35 86.55,65.72 110.31,65.72 120.25,75.66 120.25,97.04 v1(120.12,97.17) 119.63,97.66 v2(119.63,99.03) ; Q2601.1 102.85,92.06 104.27,90.65 105.83,90.65 RN2602.3 105.99,91.08 105.66,91.41 105.66,91.92 v2(104.78,92.8)
  L3 w0.127: v2(119.63,99.03) 119.11,98.51 115.11,98.51 112.78,96.18 112.19,96.18 108.94,92.93 104.9,92.93 v2(104.78,92.8)
TOUCH_PANEL_INTR#: length 199.1
  L3 w0.102: v2(39.88,99.15) 40.77,98.27 58.09,98.27 59.23,99.41 72.24,99.41 76.44,103.61 76.44,106.08 82.07,111.7 114.71,111.7 117.91,108.5 130.39,108.5 131.74,107.15 132.03,106.87 132.05,106.85 132.17,106.74 132.19,106.71 132.74,106.13 132.79,106.11 136.17,104.65 138.98,103.15 141.25,100.88 142.15,99.99 142.15,99.65 142.15,90.56 142.14,90.56 142.14,87.28 142.77,86.65 142.77,80.53 160.25,63.05 160.25,58.5 158.95,57.2 158.95,48.28 v2(159.51,47.72)
  BOTTOM w0.102: v2(159.51,47.72) v1(159.07,48.16) 158.7,48.53 157.22,48.53 154.38,45.69 153.25,45.69 152.28,44.72 150.42,44.72 150.05,44.35 R2443.1 150.05,43.85 148.59,42.39 D2401.A ; v2(39.88,99.15) 39.88,98.52 38.13,96.77 32.89,96.77 32.41,97.25 HOMBD1.5
TP_CL_CLK: length 7
  BOTTOM w0.114: CPU1.AF2 85.12,81.6 85.12,85.36 84.93,85.55 84.93,87.63 TP1801.1
TP_CL_DATA: length 4.3
  BOTTOM w0.089: 84.59,82.33 84.52,82.26 84.52,81.45 CPU1.AD2
  BOTTOM w0.114: 84.59,82.33 84.59,84.92 TP1802.1
TP_CL_RST#: length 8.1
  BOTTOM w0.089: CPU1.AF4 85.92,80.19 85.92,80.77 86.01,80.86 86.01,82.04 85.85,82.21 85.85,82.61
  BOTTOM w0.114: TP1803.1 85.94,87.05 85.94,83.22 85.85,83.12 85.85,82.61
TP_DC_TEST_A4: length 2.7
  BOTTOM w0.102: CPU1.A4 71.14,79.47 70.36,79.47 TP2202.1
TP_DC_TEST_A60: length 5.5
  BOTTOM w0.102: CPU1.A60 71.53,45.03 70.28,45.03 70.23,44.98 68.35,44.98 67.91,44.54 66.3,44.54 TP2203.1
TP_DC_TEST_A62: length 4.9
  BOTTOM w0.102: TP2205.1 67.89,43.61 70.82,43.61 70.99,43.78 CPU1.A62
TP_DC_TEST_AV1: length 4.5
  BOTTOM w0.102: TP2206.1 95.76,84.3 94.23,82.77 93.76,82.77 92.9,81.92 CPU1.AV1
TP_DC_TEST_AW1: length 6.2
  BOTTOM w0.102: TP2207.1 96.39,86.45 96.39,84.19 94.02,81.81 CPU1.AW1
TP_DC_TEST_AW63: length 5.5
  BOTTOM w0.102: CPU1.AW63 96.27,40.56 96.27,39.46 TP2208.1
TP_DC_TEST_AY60: length 9.2
  BOTTOM w0.102: CPU1.AY60 94.21,45.06 97.67,41.6 97.67,38.59 TP2201.1
TP_DC_TEST_B2: length 7.1
  BOTTOM w0.102: CPU1.B2 69.84,81.31 68.8,80.26 67.98,80.26 66.81,79.09 TP2204.1
TP_HDA_DOCK_EN#: length 1.2
  TOP w0.102: v2(93.22,76.57) 93.22,76.29 TP1902.1
  BOTTOM w0.102: CPU1.AW10 93.56,76.22 v2(93.22,76.57)
TP_LOCK#: length 70.4
  TOP w0.102: v2(149.35,60.42) 149.8,60.86 R2437.1
  L3 w0.102: v2(149.35,60.42) 149.45,60.42 150.17,59.7 150.17,58.6 147.24,55.68 147.24,42.29 145.41,40.46 145.41,31.53 140.9,27.02 126.71,27.02 125.77,26.08 113.49,26.08 v2(112.78,25.37)
  BOTTOM w0.102: AFTP6242.1 112.78,26.13 v2(112.78,25.37) 112.3,24.89 TP1.3
TP_LOCK#_C: length 8.9
  TOP w0.102: KBC24.123 150.74,55.52 149.19,57.07 v1(149.19,57.91) 149.19,59.65 149.46,59.91 149.99,59.91 150.69,60.61 R2437.2 R2455.1
TP_M_A_DIMA_ODT0: length 1.2
  TOP w0.102: TP501.1 90.42,62.87 v2(90.11,62.56)
  BOTTOM w0.102: CPU1.AP32 90.45,62.9 v2(90.11,62.56)
TP_ON#: length 82
  TOP w0.102: v2(152.78,51.53) 152.04,52.27 152.04,53.39 152.34,53.69 KBC24.119 152.34,56.78 v1(152.4,56.84) R2445.1
  L3 w0.102: v2(100.46,23.21) 107.51,23.21 108.45,22.27 126.32,22.27 126.86,22.82 138.93,22.82 144.88,28.77 145.72,28.77 150.57,33.62 150.57,35.83 152.67,37.93 152.67,47.96 152.35,48.28 152.35,51.1 v2(152.78,51.53)
  BOTTOM w0.102: R6204.1 100.71,22.95 v2(100.46,23.21)
TP_ON#_GATE: length 27.2
  BOTTOM w0.102: Q6205.G 122.27,21.53 120.52,19.78 110.74,19.78 107.16,23.37 Q6203.G 103.03,22.95 R6204.2 102.04,23.53 v1(101.68,23.89) 101.98,24.2 C6204.2
TP_V1.05S_APLLOPI: length 2.3
  TOP w0.102: TP2105.1 83.57,71.91 v2(83.75,71.72)
  BOTTOM w0.102: v2(83.75,71.72) 83.66,71.63 83.66,70.95 83.97,70.63 CPU1.AC20
TP_V1.05S_AXCK_DCB: length 1.9
  TOP w0.102: TP2104.1 78.26,69.41 v2(78.6,69.76)
  BOTTOM w0.102: v2(78.6,69.76) CPU1.M20
TP_V1.05S_SSCF100: length 3.9
  TOP w0.102: TP2103.1 77.44,71.69 78.34,71.69 v2(78.87,71.16)
  BOTTOM w0.102: v2(78.87,71.16) 77.96,72.07 CPU1.K18
TP_V1.05S_SSCFF: length 3.7
  TOP w0.102: TP2101.1 80.19,70.63 80.19,71.14 80.9,71.85 v2(80.98,71.85)
  BOTTOM w0.102: CPU1.V21 81.45,71.45 81.05,71.85 v2(80.98,71.85)
TP_VCCAPLLOPI_VAL: length 2.2
  TOP w0.102: v2(83.06,71.72) 82.42,72.36 TP2102.1
  BOTTOM w0.102: CPU1.Y20 82.67,71.33 v2(83.06,71.72)
TP_VCCIO_OUT: length 2.3
  BOTTOM w0.102: TP701.1 70.08,46.22 70.39,45.91 CPU1.A59
TP_VDD: length 3.2
  TOP w0.508: v2(117.35,22.95) 117.35,22.55 R6210.1
  vias: v2(117.35,25.37)
TP_WAKE_KBC#: length 3.5
  TOP w0.102: KBC24.121 151.54,56.54 v1(151.18,56.9) 151.51,57.23 R2426.2
TPAN_VDD:
  vias: v1(29.72,96.74) v3(30.23,95.34)
TPCLK: length 76.9
  TOP w0.114: v2(113.28,22.7) 113.47,22.89 EC6201.1 113.54,23.53 v1(113.54,24.48) 113.54,25.11 113.36,25.3 RN6201.4 113.36,26.57 113.16,26.76 112.14,26.76 111.89,27.02 111.89,27.78 111.63,28.03 110.87,28.03 110.67,27.84 RN6202.2 ; v2(164.59,43.15) 164.32,43.15 163.9,43.56 KBC24.72
  L4 w0.127: v2(113.28,22.7) 113.28,22.1 113.7,21.68 125.83,21.68 127.1,22.96 138.91,22.96 144.18,28.23 159.16,28.23 164.08,33.15 164.08,42.64 v2(164.59,43.15)
TPCLK_C: length 4
  TOP w0.114: v2(110.36,25.37) 110.67,25.68 RN6202.3
  BOTTOM w0.114: AFTP6238.1 109.98,25.75 v2(110.36,25.37) 110.3,25.3 TP1.1
TPDATA: length 75.1
  TOP w0.114: RN6202.1 111.32,27.1 112.26,26.17 RN6201.3 112.7,25.92 112.3,25.51 112.3,24.51 v1(112.27,24.48) 112.33,24.42 EC6202.1 112.33,22.89 v2(112.52,22.7) ; KBC24.71 163.82,43.16 164.47,42.51 v2(164.59,42.51)
  L4 w0.127: v2(112.52,22.7) 112.52,22.32 113.54,21.3 125.98,21.3 127.25,22.57 139.06,22.57 144.33,27.84 159.32,27.84 164.47,32.99 164.47,42.39 v2(164.59,42.51)
TPDATA_C: length 3.9
  TOP w0.114: v2(111,25.37) 111.09,25.46 111.32,25.69 RN6202.4
  BOTTOM w0.114: TP1.2 111.3,25.07 v2(111,25.37) 111,26 AFTP6236.1
USB3_PRX_CTX_N0: length 88.1
  TOP w0.102: v1(75.77,70.63) 75.46,70.32 v2(75.46,70.13)
  L4 w0.114: v2(23.24,43.66) 23.17,43.73 22.75,43.73 22.63,43.61 22.63,43.25 23.44,42.44 25.45,42.44 27.51,40.38 30.71,40.38 34.89,36.19 65.27,36.19 72.29,43.22 72.29,65.21 75.87,68.79 75.87,69.72 v2(75.46,70.13)
  BOTTOM w0.102: CPU1.G20 75.62,70.53 75.62,70.28 v2(75.46,70.13) ; R3414.1 22.09,43.97 22.39,43.97 22.7,43.66 v2(23.24,43.66)
USB3_PRX_CTX_N1: length 105.1
  L4 w0.114: v2(24,61.67) 23.58,62.1 22.78,62.1 22.4,61.72 22.4,52.39 24.23,50.56 24.23,49.96 27.43,46.75 27.43,43.54 28.42,42.55 32.46,42.55 35.88,39.13 65.13,39.13 69.62,43.62 69.62,59.85 68.06,61.41 68.06,63.65 68.95,64.54 71.32,64.54 71.56,64.79 71.56,65.51 74.18,68.12 74.18,69.87 74.81,70.5 74.81,70.81 v2(74.5,71.11)
  BOTTOM w0.102: TR3405.2 21.72,61.49 21.84,61.62 21.84,61.98 21.98,62.12 22.28,62.12 ; 22.28,62.12 23.44,62.12 23.57,61.99 23.57,61.8 23.7,61.67 v2(24,61.67) ; 22.28,62.12 v1(22.28,61.94) ; v2(74.5,71.11) 74.5,71.47 74.37,71.59 CPU1.E18
USB3_PRX_CTX_P0: length 88.2
  L4 w0.114: v2(76.1,70.12) 76.1,68.69 72.52,65.11 72.52,43.12 65.36,35.97 34.8,35.97 30.61,40.15 27.41,40.15 25.36,42.21 23.35,42.21 22.4,43.16 22.4,43.7 v2(22.86,44.16)
  BOTTOM w0.102: R3415.1 22.03,44.29 22.73,44.29 v2(22.86,44.16) 23.27,44.57 v1(23.27,44.65) ; v2(76.1,70.12) 76.16,70.18 CPU1.H20
USB3_PRX_CTX_P1: length 105.2
  L4 w0.114: v2(75.13,71.11) 75.03,71.02 75.03,70.41 74.41,69.78 74.41,68.03 71.79,65.41 71.79,64.69 71.41,64.31 69.05,64.31 68.29,63.55 68.29,61.51 69.85,59.95 69.85,43.53 65.22,38.9 35.79,38.9 32.36,42.32 28.33,42.32 27.2,43.44 27.2,46.66 24,49.86 24,50.46 22.17,52.29 22.17,61.82 22.68,62.32 v2(24,62.32)
  BOTTOM w0.102: v1(23.44,62.48) 23.44,62.32 ; 23.44,62.32 21.9,62.32 21.72,62.14 TR3405.1 ; 23.44,62.32 v2(24,62.32) ; CPU1.F18 74.85,71.39 v2(75.13,71.11)
USB3_PTX_CRX_N0: length 77.4
  L4 w0.114: v2(70.74,62.07) 70.54,61.87 70.54,61.31 71.5,60.34 71.5,43.13 65.82,37.45 34.34,37.45 30.91,40.87 27.73,40.87 25.65,42.95 25.65,45.73 25.43,45.95 25.16,45.95 v2(24.89,45.69)
  BOTTOM w0.102: C3407.1 24.77,45.56 v2(24.89,45.69) 24.94,45.74 v1(25.55,45.74) ; CPU1.C33 72.4,61.79 71.02,61.79 v2(70.74,62.07)
USB3_PTX_CRX_N1: length 99.7
  TOP w0.102: v1(71.25,63.59) 70.74,63.09 v2(70.74,62.96)
  L4 w0.114: v2(70.74,62.96) 70.07,63.63 69.18,63.63 68.78,63.23 68.78,61.71 70.38,60.11 70.38,43.36 65.43,38.4 35.58,38.4 32.16,41.83 28.12,41.83 26.67,43.28 26.67,46.43 23.24,49.86 23.24,50.48 21.34,52.39 21.34,63.25 22.35,64.26 23.6,64.26 24,63.85 v2(24,63.72)
  BOTTOM w0.102: v2(70.74,62.96) 71.31,62.39 71.82,62.39 72.12,62.09 CPU1.B33 ; v2(24,63.72) 23.88,63.59 C3406.1
USB3_PTX_CRX_P0: length 77.3
  TOP w0.102: v2(70.1,62.07) 70.18,61.99 v1(70.18,61.46)
  L4 w0.114: v2(70.1,62.07) 70.31,61.87 70.31,61.21 71.27,60.25 71.27,43.23 65.73,37.68 34.43,37.68 31.01,41.1 27.82,41.1 25.88,43.04 25.88,45.83 25.53,46.18 25.16,46.18 v2(24.89,46.45)
  BOTTOM w0.102: v2(70.1,62.07) 70.58,61.59 72.49,61.59 CPU1.B34 ; C3408.1 v2(24.89,46.45)
USB3_PTX_CRX_P1: length 99.5
  TOP w0.102: v1(70.03,63.59) 70.03,63.04 v2(70.1,62.96)
  L4 w0.114: v2(24,64.48) 22.25,64.48 21.11,63.34 21.11,52.29 23.01,50.39 23.01,49.76 26.44,46.33 26.44,43.18 28.03,41.6 32.06,41.6 35.49,38.18 65.52,38.18 70.61,43.27 70.61,60.21 69.01,61.81 69.01,63.14 69.27,63.4 69.98,63.4 70.1,63.27 v2(70.1,62.96)
  BOTTOM w0.102: v2(70.1,62.96) 70.52,62.54 70.87,62.54 71.33,62.09 CPU1.A33 ; C3405.1 23.88,64.61 v2(24,64.48)
USB20_DN0_C: length 13.2
  TOP w0.102: v2(17.91,42.26) v1(18.54,42.26)
  L4 w0.114: v2(17.91,42.26) 17.65,42 17.44,42 17.25,42.2 17.25,42.95 17.6,43.31 17.6,44.73 17.26,45.06 16.97,45.06 USB2.2
  BOTTOM w0.102: TR3402.4 23.87,41.57 23.6,41.29 22.45,41.29 22.19,41.56 EU3404.1 20.78,41.56 20.31,42.03 18.14,42.03 v2(17.91,42.26)
USB20_DN1_C: length 12.1
  L4 w0.114: v2(16.89,60.42) 16.68,60.21 16.35,60.21 16.15,60.41 16.15,61.06 16.61,61.52 16.61,62.55 16.1,63.06 15.79,63.06 USB1.2
  BOTTOM w0.102: v2(16.89,60.42) 17.12,60.19 19.29,60.19 19.76,59.72 EU3402.1 20.79,59.45 21.97,59.45 22.25,59.73 TR3401.4
USB20_DP0_C: length 12.7
  L4 w0.114: v2(17.91,41.62) 17.75,41.78 17.35,41.78 17.16,41.97 17.02,42.11 17.02,43.05 17.37,43.4 17.37,44.63 17.17,44.84 16.97,44.84 USB2.3
  BOTTOM w0.102: 22.83,41.09 20.96,41.09 20.22,41.83 19.62,41.83 19.35,41.56 EU3404.6 17.97,41.56 v2(17.91,41.62) ; 22.83,41.09 v1(22.83,40.94) ; 22.83,41.09 23.6,41.09 23.77,40.92 TR3402.3
USB20_DP1_C: length 12.1
  L4 w0.114: USB1.3 15.79,62.84 16,62.84 16.38,62.45 16.38,61.61 15.93,61.16 15.93,60.32 16.26,59.98 16.69,59.98 v2(16.89,59.78)
  BOTTOM w0.102: TR3401.3 22.25,59.08 22.07,59.25 19.94,59.25 19.2,59.99 18.75,59.99 18.48,59.72 EU3402.6 16.95,59.72 v2(16.89,59.78)
USB30_RXDN0_C: length 8.8
  BOTTOM w0.102: USB2.5 14.58,41.65 14.73,41.8 15.17,41.8 15.73,42.36 16.77,42.36 17.42,43.01 17.42,43.83 17.66,44.06 18.01,44.06 18.15,43.93 EU3403.1 EU3403.9 19.43,43.93 19.56,44.05 20.49,44.05 R3414.2
USB30_RXDN1_C: length 9.8
  BOTTOM w0.102: TR3405.3 19.53,61.49 19.08,61.94 18.69,61.94 18.67,61.96 EU3401.9 EU3401.1 17.26,61.96 17.12,62.1 16.77,62.1 16.03,61.35 16.03,59.68 15.49,59.15 14.48,59.15 13.84,59.78 13.72,59.78 13.4,59.47 USB1.5
USB30_RXDP0_C: length 8.8
  BOTTOM w0.102: USB2.6 14.58,42.18 14.76,42 15.09,42 15.65,42.56 16.69,42.56 17.22,43.1 17.22,43.91 17.58,44.26 18.01,44.26 18.15,44.4 EU3403.2 EU3403.8 19.43,44.4 19.58,44.26 20.6,44.26 R3415.2
USB30_RXDP1_C: length 9.9
  BOTTOM w0.102: TR3405.4 18.77,62.14 18.48,62.43 EU3401.8 EU3401.2 17.26,62.43 17.12,62.3 16.69,62.3 15.82,61.44 15.82,59.77 15.41,59.35 14.56,59.35 13.93,59.99 13.72,59.99 13.4,60.3 USB1.6
USB30_TXDN0_C: length 8.4
  BOTTOM w0.102: USB2.8 14.58,47.82 14.68,47.92 14.83,47.92 15.77,46.98 16.33,46.98 17.72,45.59 18.01,45.59 18.15,45.45 EU3403.4 EU3403.7 19.32,45.45 19.56,45.69 20.76,45.69 R3413.2
USB30_TXDN0_R: length 1.8
  BOTTOM w0.102: R3413.1 22.06,45.84 23.03,45.84 C3407.2
USB30_TXDN1_C: length 8.5
  BOTTOM w0.102: TR3404.3 19.14,63.78 18.93,63.57 18.67,63.57 18.58,63.49 EU3401.7 EU3401.4 17.26,63.49 17.12,63.62 16.71,63.62 15.42,64.91 14.68,64.91 13.67,65.92 13.5,65.92 13.4,65.82 USB1.8
USB30_TXDN1_R: length 1.5
  BOTTOM w0.102: C3406.2 22.23,63.78 TR3404.2
USB30_TXDP0_C: length 8.2
  BOTTOM w0.102: USB2.9 14.58,48.38 14.83,48.13 14.92,48.13 15.86,47.19 16.41,47.19 17.81,45.79 18.01,45.79 18.15,45.93 EU3403.5 EU3403.6 20.37,45.93 R3416.2
USB30_TXDP0_R: length 1.9
  BOTTOM w0.102: R3416.1 22.19,46.04 22.9,46.04 C3408.2
USB30_TXDP1_C: length 8.5
  BOTTOM w0.102: TR3404.4 19.5,64.43 18.85,63.77 18.67,63.77 18.48,63.96 EU3401.6 EU3401.5 17.26,63.96 17.12,63.82 16.79,63.82 15.5,65.11 14.76,65.11 13.75,66.13 13.65,66.13 13.4,66.38 USB1.9
USB30_TXDP1_R: length 1.5
  BOTTOM w0.102: TR3404.1 22.23,64.43 C3405.2
USB30_VCCA: length 11.4
  TOP w0.508: v2(16.89,58.51) 16.63,58.51 16,59.14 16,65.35 USB1.1
  BOTTOM w0.508: v2(16.89,58.51) 17.15,58.51 17.41,58.77 EU3402.5 ; 15.61,66.45 USB1.1 14.9,67.16
  vias: v1(23.83,66.64) v1(26.04,63.21) v1(27.33,58.06)
USB30_VCCB: length 12.7
  TOP w0.203: v1(18.92,40.1) 18.67,40.35 v2(17.91,40.35)
  TOP w0.508: v2(17.91,40.35) 17.64,40.35 17.25,40.75 17.25,47.28 USB2.1
  BOTTOM w0.508: v2(17.91,40.35) 18.17,40.35 18.42,40.61 EU3404.5 ; 16.84,48.45 USB2.1 16.08,49.21
  vias: v1(19.56,48.35)
USB_3+: length 4
  TOP w0.102: R6601.2 95,104.11 v2(95.25,104.36) 95.36,104.26 U6601.33
  BOTTOM w0.102: v1(95.76,106.39) 95.76,106.27 95.31,105.82 R6605.1 95.31,104.43 v2(95.25,104.36)
USB_3-: length 1.7
  TOP w0.102: U6601.32 95.47,104.75 95.43,104.79 95.12,104.79 94.92,105 R6604.2
USB_CAMERA_N: length 6.9
  TOP w0.102: 58.9,97.23 59.77,97.23 59.97,97.43 59.97,98.11 59.75,98.34 TR5208.3 ; 58.9,97.23 58.59,97.23 58.22,96.86 58.22,96.41 v2(57.91,96.11) ; 58.9,97.23 v1(58.9,97.38)
  BOTTOM w0.102: v2(57.91,96.11) 58.2,95.82 58.2,94.99 58.05,94.85 LCD1.16
USB_CAMERA_P: length 6.8
  TOP w0.102: 60.05,97.22 59.85,97.03 58.67,97.03 58.42,96.77 58.42,96.36 v2(58.67,96.11) ; 60.05,97.22 60.17,97.35 60.17,98.11 60.4,98.34 TR5208.4 ; 60.05,97.22 v1(60.15,97.12)
  BOTTOM w0.102: LCD1.15 58.55,94.85 58.4,94.99 58.4,95.83 v2(58.67,96.11)
USB_CHG_EN: length 180.9
  TOP w0.102: KBC24.105 157.94,51.6 159.51,50.03 v2(159.51,50.01)
  L3 w0.102: v2(159.51,50.01) 160.2,49.32 160.2,43.27 159.97,43.05 159.97,40.17 160.06,40.09 160.06,36.82 159.52,36.29 156.13,36.29 154.23,34.38 152.86,34.38 151.89,33.42 151.89,31.96 140.6,20.67 98.6,20.67 97.54,21.74 86.88,21.74 78.36,30.26 78.36,32.13 75.8,34.69 66.38,34.69 61.6,39.46 38.77,39.46 31.51,46.72 27.91,46.72 26.72,47.91 26.72,48.21 22.99,51.94 v2(22.99,53.31)
  BOTTOM w0.102: v2(22.99,53.31) 23.25,53.57 U3503.5 ; v1(160.05,50.29) 159.79,50.29 v2(159.51,50.01)
USB_COMP: length 2.9
  TOP w0.305: R1602.1 88.61,76.27 87.64,76.27 v1(87.61,76.3) 87.58,76.3 87.39,76.11 v2(87.39,75.75)
  BOTTOM w0.254: CPU1.AJ11 87.39,75.67 87.39,75.74 v2(87.39,75.75) 87.39,75.84 CPU1.AJ10
USB_DET#: length 21.5
  TOP w0.102: R2451.1 v2(147.7,35.15) ; v2(153.29,43.02) 152.27,44.04 150.88,44.04 149.35,45.56 KBC24.20
  BOTTOM w0.102: D2402.1 R2451.1 v2(147.7,35.15) v1(147.7,36.67) 147.7,37.43 148.9,38.63 148.9,39.69 149.44,40.23 149.74,40.23 152.53,43.02 v2(153.29,43.02)
USB_OC#0_1: length 148.6
  L4 w0.102: v2(18.92,56.61) 18.8,56.74 18.8,66.19 16.36,68.63 16.36,72.46 15.07,73.74 15.07,83.75 15.86,84.54 15.86,90.03 18.84,93.01 22.28,93.01 25.83,96.56 41.27,96.56 43.79,94.04 60.44,94.04 61.22,94.81 67.82,94.81 68.32,94.3 76.2,94.3 77.12,95.22 80.75,95.22 81.56,94.41 84.18,94.41 84.29,94.52 84.87,94.52 85.41,93.98 85.41,92.74 86.23,91.92 v2(86.49,91.92) ; v2(27.94,55.21) 26.04,57.12 24.13,57.12 v2(23.88,56.86)
  BOTTOM w0.089: 88.7,82.76 88.7,82.17 88.83,82.04 88.83,80.76 CPU1.AL3
  BOTTOM w0.102: v2(23.88,56.86) 19.18,56.86 v2(18.92,56.61) 18.54,56.23 18.54,53.26 19.2,52.6 22.43,52.6 23.62,51.4 U3502.3 ; 86.87,92.42 86.49,92.04 v2(86.49,91.92) 85.85,91.28 85.85,90.65 87.76,88.74 87.76,84.93 88.01,84.68 88.01,84.17 88.7,83.48 88.7,82.76 ; 86.87,92.42 v1(86.87,92.42) ; 86.87,92.42 RN1809.7 ; v2(27.94,55.21) 27.8,55.07 U3503.13
USB_OC#2_3: length 123.1
  L3 w0.102: v2(154.56,62.96) 153.67,62.96 151.66,64.97 151.66,67.94 140.16,79.44 140.16,82.15 139.45,82.86 139.45,90.8 138.61,91.64 138.61,96.28 129.01,105.89 115.96,105.89 113.47,108.38 104.43,108.38 102.67,106.61 102.67,101.38 100.94,99.65 100.94,98.9 92.94,90.9 v2(92.46,90.9)
  BOTTOM w0.102: RN1601.8 92.09,91.27 v2(92.46,90.9) 93.22,90.9 95.66,88.46 95.66,86.09 92.61,83.04 92.16,83.04 91.77,82.65 91.77,82.33 91.58,82.14 CPU1.AT1 ; v2(154.56,62.96) 154.38,62.78 v1(153.9,62.78) 149.3,62.78 148.77,62.25 IOBD1.28
USB_OC#4_5: length 13.4
  TOP w0.102: v2(87.12,91.92) 87.13,91.92 RN2012.7 ; v2(86.36,83.64) v1(85.75,83.64)
  L3 w0.102: v2(87.12,91.92) 87.12,90.77 85.93,89.58 85.93,84.07 v2(86.36,83.64)
  BOTTOM w0.089: CPU1.AH2 86.76,81.45 86.76,81.96 86.86,82.05 86.86,83.14 v2(86.36,83.64)
USB_OC#6_7: length 15.6
  BOTTOM w0.089: CPU1.AV3 92.89,80.57 93.22,80.89 93.22,81.54 93.23,81.55 93.23,81.98 93.5,82.26 94.19,82.26
  BOTTOM w0.102: RN1601.7 92.6,91.92 v1(92.74,91.79) 92.74,91.67 95.86,88.55 95.86,85.97 96.19,85.64 96.19,84.26 94.19,82.26
USB_PN0: length 107
  L4 w0.114: v2(90.32,77.11) 90.09,76.88 90.09,76.6 89.55,76.07 89.4,76.07 88.06,74.72 88.06,73.86 87.67,73.47 86.98,73.47 86.36,74.09 86.36,74.68 85.95,75.08 78,75.08 76.68,76.4 74.55,76.4 73.13,74.97 73.13,73.6 71.32,71.8 70.94,71.8 65.79,66.65 65.79,64.23 66.8,63.21 66.8,57.37 68.86,55.31 68.86,43.65 64.94,39.73 35.98,39.73 32.66,43.05 28.73,43.05 28.24,43.54 28.24,43.99 v2(28.07,44.16)
  BOTTOM w0.102: 27.52,42.1 28.07,42.65 v2(28.07,44.16) ; 27.52,42.1 26.99,41.57 TR3402.1 ; 27.52,42.1 v1(27.41,42.21) ; CPU1.AN8 89.99,77.44 90.29,77.13 90.3,77.13 v2(90.32,77.11)
USB_PN1: length 108.3
  TOP w0.102: v2(25.78,51.78) 25.88,51.68 v1(26.44,51.68)
  L4 w0.114: v2(90.63,78.47) 90.78,78.32 90.78,78.1 90.53,77.84 87.94,77.84 87.64,77.54 86.52,77.54 85.83,76.85 78.81,76.85 78.3,77.36 74.17,77.36 72.17,75.37 72.17,74 70.99,72.82 70.59,72.82 64.83,67.06 64.83,63.84 65.85,62.82 65.85,56.98 67.63,55.2 67.63,43.76 64.55,40.68 37.08,40.68 29.41,48.35 27.08,48.35 25.43,50 25.43,51.43 v2(25.78,51.78)
  BOTTOM w0.102: v2(90.63,78.47) 90.63,78.17 90.73,78.08 CPU1.AR7 ; v2(25.78,51.78) 25.78,51.79 U3503.2
USB_PN1_R: length 5.3
  BOTTOM w0.102: 25.63,59 25.63,56.63 25.78,56.48 U3503.11 ; 25.63,59 25.63,59.23 25.37,59.48 24.87,59.48 24.62,59.73 TR3401.1 ; 25.63,59 v1(25.81,59)
USB_PN2: length 121.1
  TOP w0.102: v1(92.32,77.08) 92.27,77.03 91.79,77.03 v2(91.69,77.14)
  L4 w0.114: v2(91.69,77.14) 91.52,77.31 91.52,77.49 91.7,77.67 92.03,77.67 92.31,77.39 98.23,77.39 103.51,82.67 103.51,83.56 111.04,91.08 111.04,97.54 112.42,98.93 114.9,98.93 117.84,101.87 130.37,101.87 135.81,96.43 135.81,87.94 137.23,86.52 137.23,75.77 139.17,73.84 139.17,72.84 146.64,65.37 146.64,64.9 151.92,59.62 151.92,50.79 150.57,49.44 150.14,49.44 149.86,49.73 v2(149.86,49.98)
  BOTTOM w0.102: IOBD1.3 148.64,49.75 148.77,49.62 148.77,49.43 148.89,49.3 149.45,49.3 149.86,49.71 v2(149.86,49.98) ; v2(91.69,77.14) 91.69,77.42 91.6,77.51 CPU1.AR8
USB_PN3: length 62.4
  TOP w0.102: R6604.1 93.14,105 v2(92.96,105.17)
  L4 w0.114: v2(112.9,97.5) 112.9,96.49 111.76,95.34 111.76,90.78 104.24,83.26 104.24,82.36 98.53,76.65 94.3,76.65 93.29,75.63 91.97,75.63 91.52,76.09 91.52,76.34 v2(91.29,76.56)
  BOTTOM w0.102: v2(91.29,76.56) 90.96,76.23 CPU1.AR10 ; v2(112.9,97.5) 112.69,97.72 112.69,97.97 112.47,98.19 99.48,98.19 97.32,100.35 94.23,100.35 93.42,101.16 93.42,103.13 93.88,103.59 93.88,104.6 ; 93.88,104.6 93.61,104.87 93.27,104.87 v2(92.96,105.17) ; 93.88,104.6 v1(94.03,104.6)
USB_PN4: length 101.3
  TOP w0.102: TR5208.2 59.75,100.44 59.97,100.66 59.97,101.03 v2(59.69,101.31)
  L4 w0.114: v2(88.94,73.18) 88.59,72.82 88.59,72.44 89.11,71.92 97.86,71.92 115.6,89.65 115.6,93.29 115.44,93.44 115.32,93.44 v2(115.06,93.19)
  BOTTOM w0.102: CPU1.AM15 89.12,73.67 88.94,73.49 v2(88.94,73.18) ; v2(115.06,93.19) 114.81,93.19 114.68,93.31 114.68,93.49 114.55,93.62 114.09,93.62 110.56,97.15 99.08,97.15 97.07,99.15 66.93,99.15 65.86,100.22 60.38,100.22 60.16,100.44 ; v2(59.69,101.31) 59.97,101.03 59.97,100.64 60.16,100.44 ; 60.16,100.44 v1(60.02,100.3)
USB_PN5: length 120.9
  TOP w0.102: v1(88.7,75.2) v2(88.7,74.64)
  L4 w0.114: v2(88.7,74.64) 89.1,74.24 89.1,73.84 89.44,73.5 89.44,72.83 89.85,72.41 92.35,72.41 92.78,72.84 98.01,72.84 114.53,89.36 114.53,96.45 118.51,100.42 129.77,100.42 134.36,95.83 134.36,87.15 135.19,86.33 135.19,83.72 134.36,82.89 134.36,79.94 135.02,79.28 135.02,75.89 136.91,74.01 136.91,68.8 140.72,64.99 143.26,64.99 148.96,59.29 148.96,55.09 150.41,53.64 150.41,52.7 150.24,52.53 149.99,52.53 v2(149.86,52.66)
  BOTTOM w0.102: CPU1.AM13 88.82,74.24 88.7,74.36 v2(88.7,74.64) ; IOBD1.9 148.65,52.75 148.94,52.45 149.66,52.45 v2(149.86,52.66)
USB_PN6: length 119.5
  TOP w0.102: R5230.1 33.17,102.2 v2(34.04,102.2)
  L4 w0.114: v2(90.32,75.2) 90.13,75.38 90.13,75.62 90.37,75.86 90.72,75.86 92.19,74.4 97.36,74.4 104.96,82 104.96,82.96 113.09,91.08 113.09,93.38 112.84,93.63 112.45,93.63 v2(112.27,93.82)
  BOTTOM w0.102: v1(41.43,101.31) 41.43,101.14 ; 41.43,101.14 57.87,101.14 59.39,99.61 65.61,99.61 66.7,98.52 96.85,98.52 98.83,96.54 110.05,96.54 111.63,94.96 111.63,93.77 111.81,93.6 112.04,93.6 v2(112.27,93.82) ; 41.43,101.14 39.86,101.14 38.79,102.2 v2(34.04,102.2) ; v2(90.32,75.2) 90.64,75.51 CPU1.AP11
USB_PN6_TPNL: length 3.3
  TOP w0.102: R5230.2 31.44,102.29 30.59,102.29 v2(30.35,102.53) 29.82,102.53 v1(29.64,102.71)
  BOTTOM w0.102: HOMBD1.15 30.64,102.25 v2(30.35,102.53)
USB_PN7: length 120.3
  TOP w0.102: v2(90.64,74.65) 90.64,74.84 90.93,75.13 v1(90.93,75.28)
  L4 w0.114: v2(149.86,50.62) 150.11,50.88 150.46,50.88 151.41,51.82 151.41,59.42 146.76,64.08 145.64,64.08 140.69,69.03 138.53,71.18 138.53,73.73 136.14,76.12 136.14,86.84 135.31,87.67 135.31,96.23 130.17,101.37 118.11,101.37 113.58,96.84 113.58,89.83 97.66,73.9 90.75,73.9 90.42,74.23 90.42,74.43 v2(90.64,74.65)
  BOTTOM w0.102: v2(149.86,50.62) 149.73,50.75 148.65,50.75 148.65,50.75 IOBD1.5 ; CPU1.AR13 90.96,74.33 v2(90.64,74.65)
USB_PP0: length 107.1
  L4 w0.114: v2(28.7,44.16) 28.47,43.94 28.47,43.63 28.83,43.27 32.76,43.27 36.07,39.96 64.85,39.96 68.63,43.74 68.63,55.22 66.57,57.28 66.57,63.12 65.56,64.14 65.56,66.74 70.84,72.03 71.23,72.03 72.9,73.7 72.9,75.07 74.46,76.63 76.78,76.63 78.09,75.31 86.05,75.31 86.59,74.77 86.59,74.19 87.07,73.7 87.57,73.7 87.83,73.96 87.83,74.82 89.31,76.29 89.46,76.29 89.86,76.7 89.86,76.91 v2(89.66,77.11)
  BOTTOM w0.102: CPU1.AM8 89.53,77.51 89.66,77.38 v2(89.66,77.11) ; v2(28.7,44.16) 28.27,43.73 28.27,43.4 ; TR3402.2 25.96,40.92 26.41,41.37 27.07,41.37 28.27,42.56 28.27,43.4 ; 28.27,43.4 v1(28.45,43.4)
USB_PP1: length 108.7
  TOP w0.102: v1(25.08,52.34) 25.08,51.85 v2(25.15,51.78)
  L4 w0.114: v2(91.28,78.47) 91.01,78.2 91.01,78 90.62,77.62 88.04,77.62 87.73,77.31 86.61,77.31 85.93,76.63 78.71,76.63 78.21,77.13 74.26,77.13 72.4,75.27 72.4,73.9 71.09,72.59 70.69,72.59 65.06,66.96 65.06,63.93 66.08,62.91 66.08,57.07 67.86,55.29 67.86,43.67 64.64,40.46 36.98,40.46 29.31,48.13 26.98,48.13 25.2,49.9 25.2,51.73 v2(25.15,51.78)
  BOTTOM w0.102: U3503.3 25.28,51.92 v2(25.15,51.78) ; CPU1.AT7 91.61,78.14 v2(91.28,78.47)
USB_PP1_R: length 5
  BOTTOM w0.102: U3503.10 25.28,56.48 25.43,56.63 25.43,57.65 ; 25.43,57.65 v1(25.25,57.65) ; 25.43,57.65 25.43,59.14 25.29,59.28 24.89,59.28 24.69,59.08 TR3401.2
USB_PP2: length 120.4
  L4 w0.114: v2(90.96,77.11) 91.29,77.44 91.29,77.58 91.6,77.9 92.12,77.9 92.4,77.62 98.14,77.62 103.28,82.76 103.28,83.65 110.81,91.18 110.81,97.64 112.33,99.16 114.8,99.16 117.74,102.1 130.47,102.1 136.04,96.53 136.04,88.04 137.46,86.61 137.46,75.87 139.4,73.93 139.4,72.93 146.86,65.46 146.86,64.99 152.15,59.71 152.15,50.69 150.67,49.22 149.98,49.22 v2(149.86,49.1)
  BOTTOM w0.102: v2(90.96,77.11) 90.94,77.11 90.64,77.41 CPU1.AP8 ; IOBD1.2 148.66,49.25 148.81,49.1 v2(149.86,49.1)
USB_PP3: length 62.3
  TOP w0.102: v2(92.96,104.23) 92.96,104.49 93.09,104.62 93.27,104.62 93.66,104.22 R6601.1
  L4 w0.114: v2(112.27,97.5) 112.67,97.1 112.67,96.58 111.53,95.44 111.53,90.88 104.01,83.35 104.01,82.45 98.43,76.88 94.21,76.88 93.19,75.86 92.07,75.86 91.75,76.18 91.75,76.35 v2(91.95,76.55)
  BOTTOM w0.102: 93.46,100.84 93.22,101.08 93.22,103.22 93.68,103.68 93.68,104.51 93.52,104.67 93.09,104.67 92.96,104.54 v2(92.96,104.23) ; 93.46,100.84 94.15,100.15 97.23,100.15 99.39,97.99 112.38,97.99 112.48,97.88 112.48,97.72 v2(112.27,97.5) ; 93.46,100.84 v1(93.34,100.73) ; v2(91.95,76.55) 91.95,76.55 91.95,76.27 91.83,76.16 CPU1.AT10
USB_PP4: length 101.5
  TOP w0.102: TR5208.1 60.4,100.45 60.17,100.68 60.17,101.03 v2(60.45,101.31)
  L4 w0.114: v2(88.28,73.15) 88.36,73.07 88.36,72.34 89.02,71.69 97.96,71.69 115.82,89.55 115.82,93.38 115.54,93.67 115.21,93.67 v2(115.06,93.82)
  BOTTOM w0.102: 62.51,100.43 65.95,100.43 67.01,99.36 97.16,99.36 99.16,97.35 110.64,97.35 114.17,93.82 v2(115.06,93.82) ; 62.51,100.43 60.47,100.43 60.17,100.72 60.17,101.03 v2(60.45,101.31) ; 62.51,100.43 v1(62.51,100.6) ; v2(88.28,73.15) 88.69,73.56 CPU1.AL15
USB_PP5: length 120.4
  L4 w0.114: v2(89.33,74.65) 89.33,73.93 89.67,73.6 89.67,72.92 89.95,72.64 92.26,72.64 92.68,73.07 97.92,73.07 114.31,89.46 114.31,96.54 118.41,100.65 129.87,100.65 134.59,95.93 134.59,87.25 135.41,86.42 135.41,83.62 134.59,82.8 134.59,80.04 135.25,79.38 135.25,75.99 137.13,74.1 137.13,68.9 140.81,65.22 143.35,65.22 149.19,59.38 149.19,55.19 150.64,53.73 150.64,52.61 150.34,52.3 150.14,52.3 v2(149.86,52.02)
  BOTTOM w0.102: IOBD1.8 149.63,52.25 v2(149.86,52.02) ; CPU1.AN13 89.33,74.57 v2(89.33,74.65)
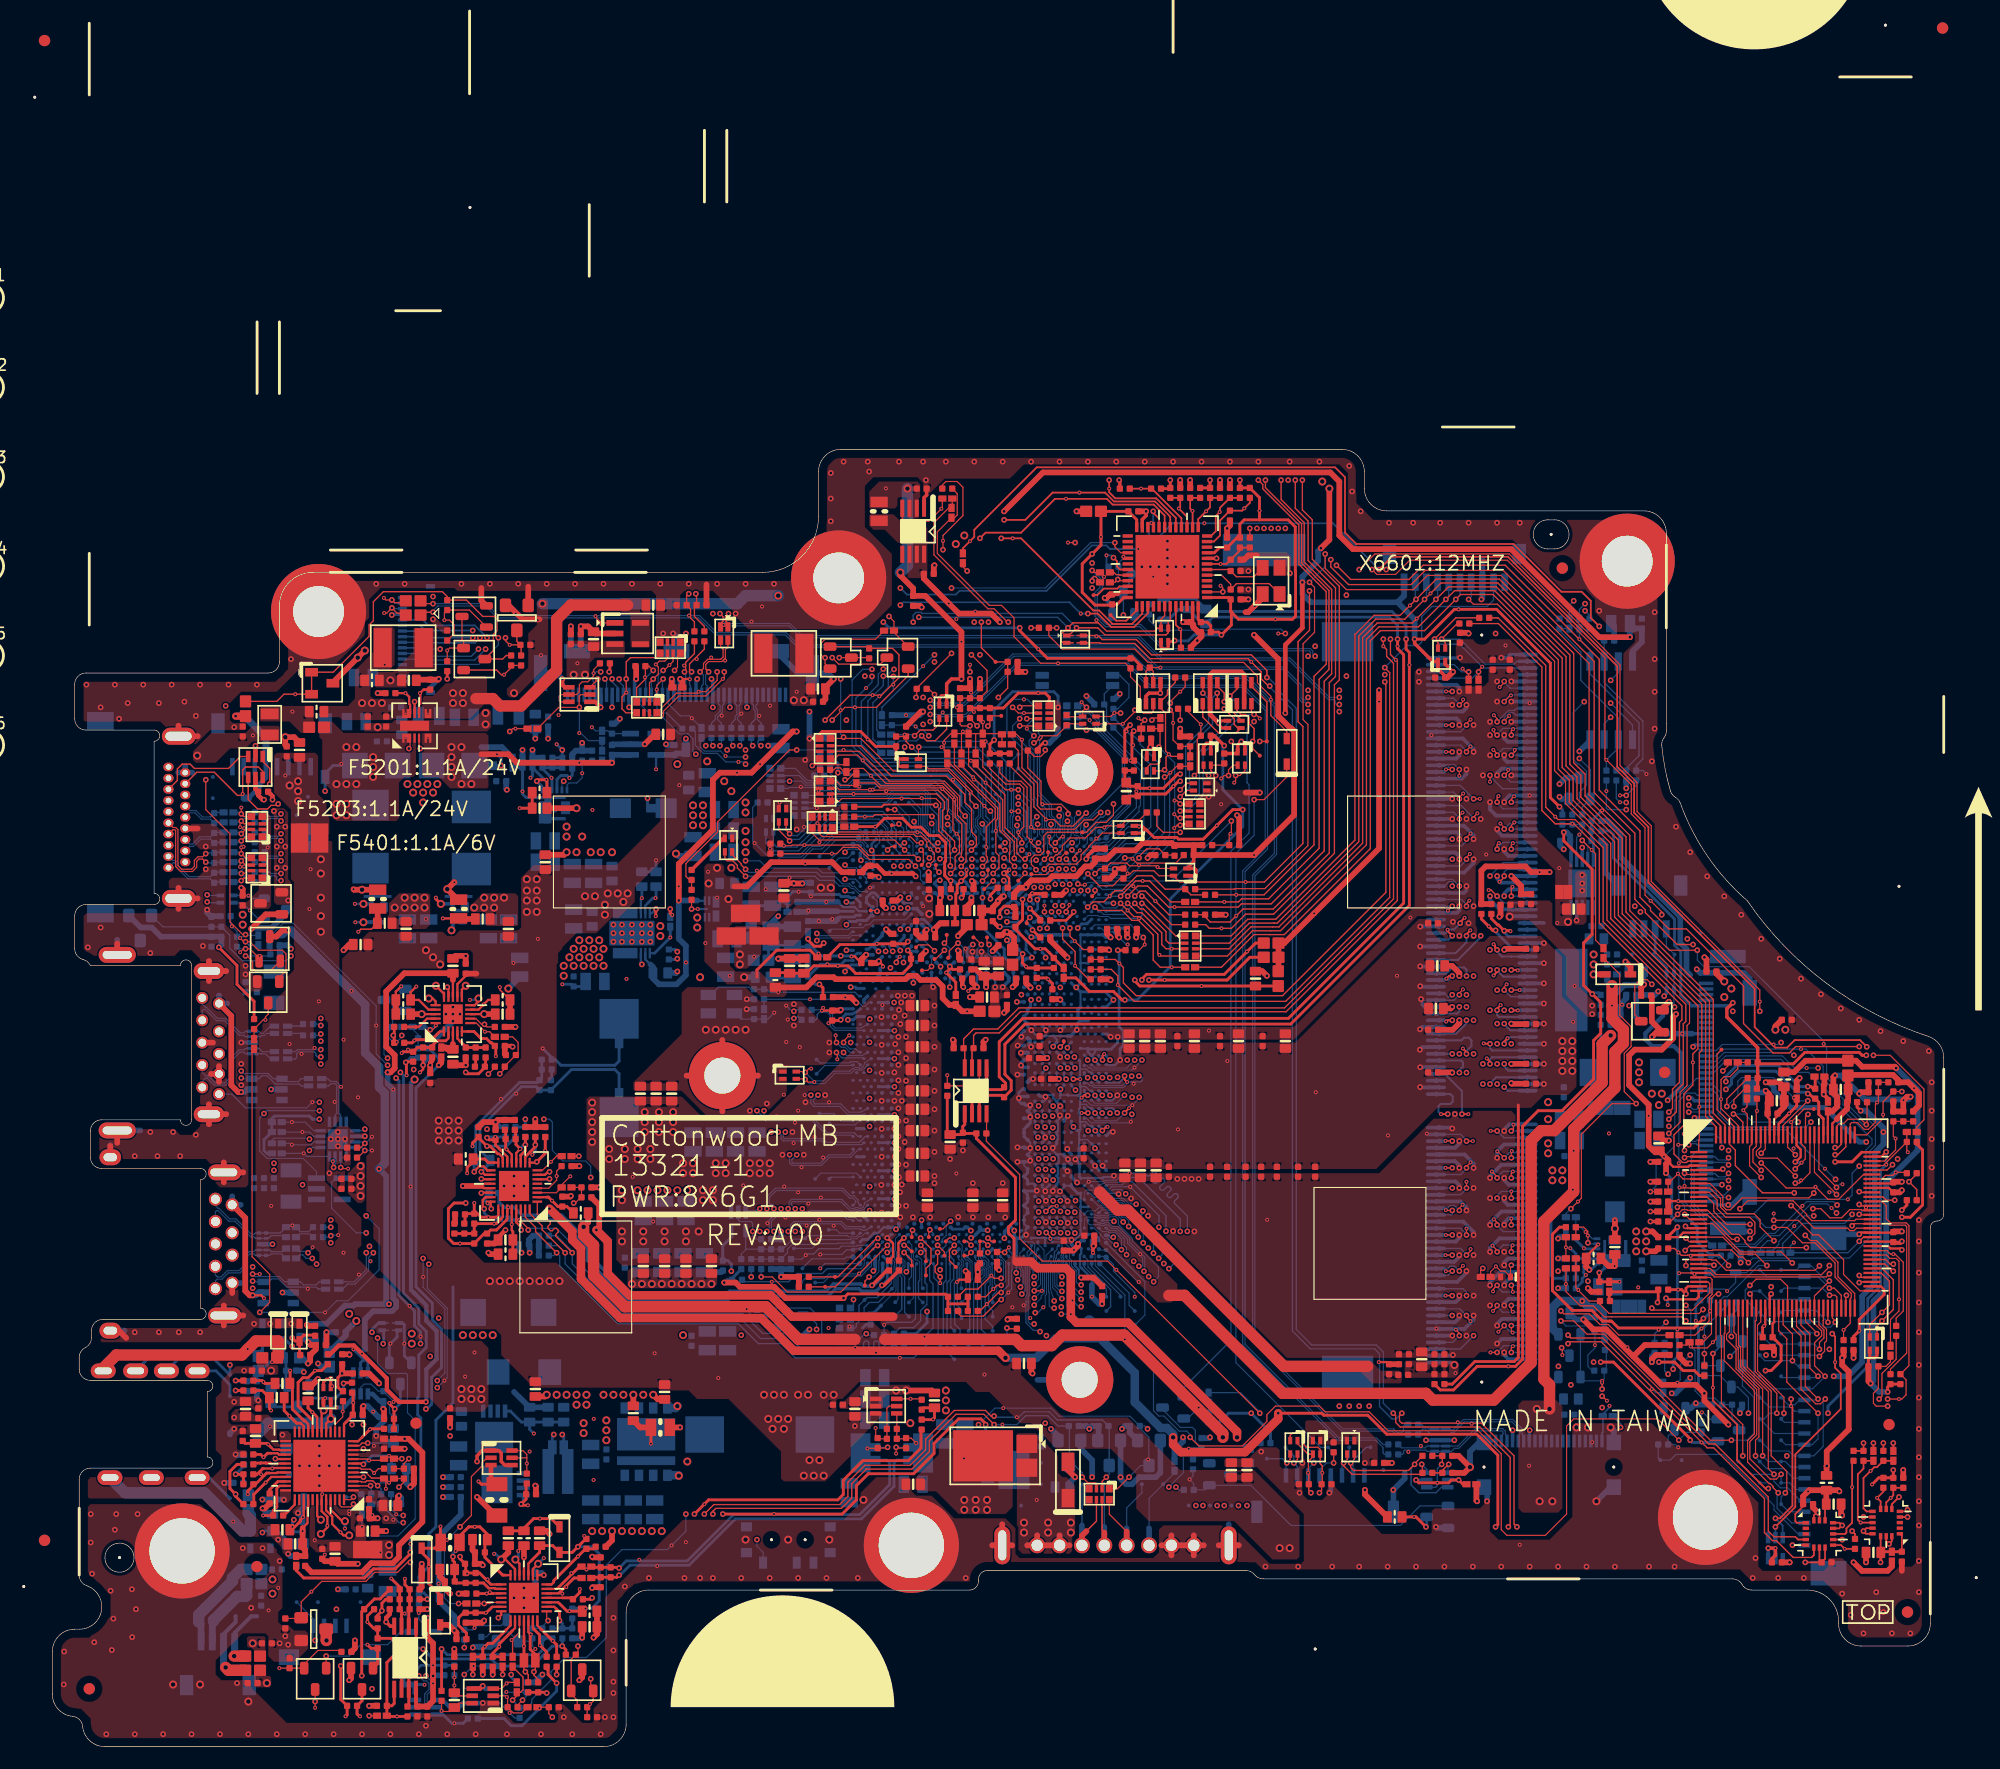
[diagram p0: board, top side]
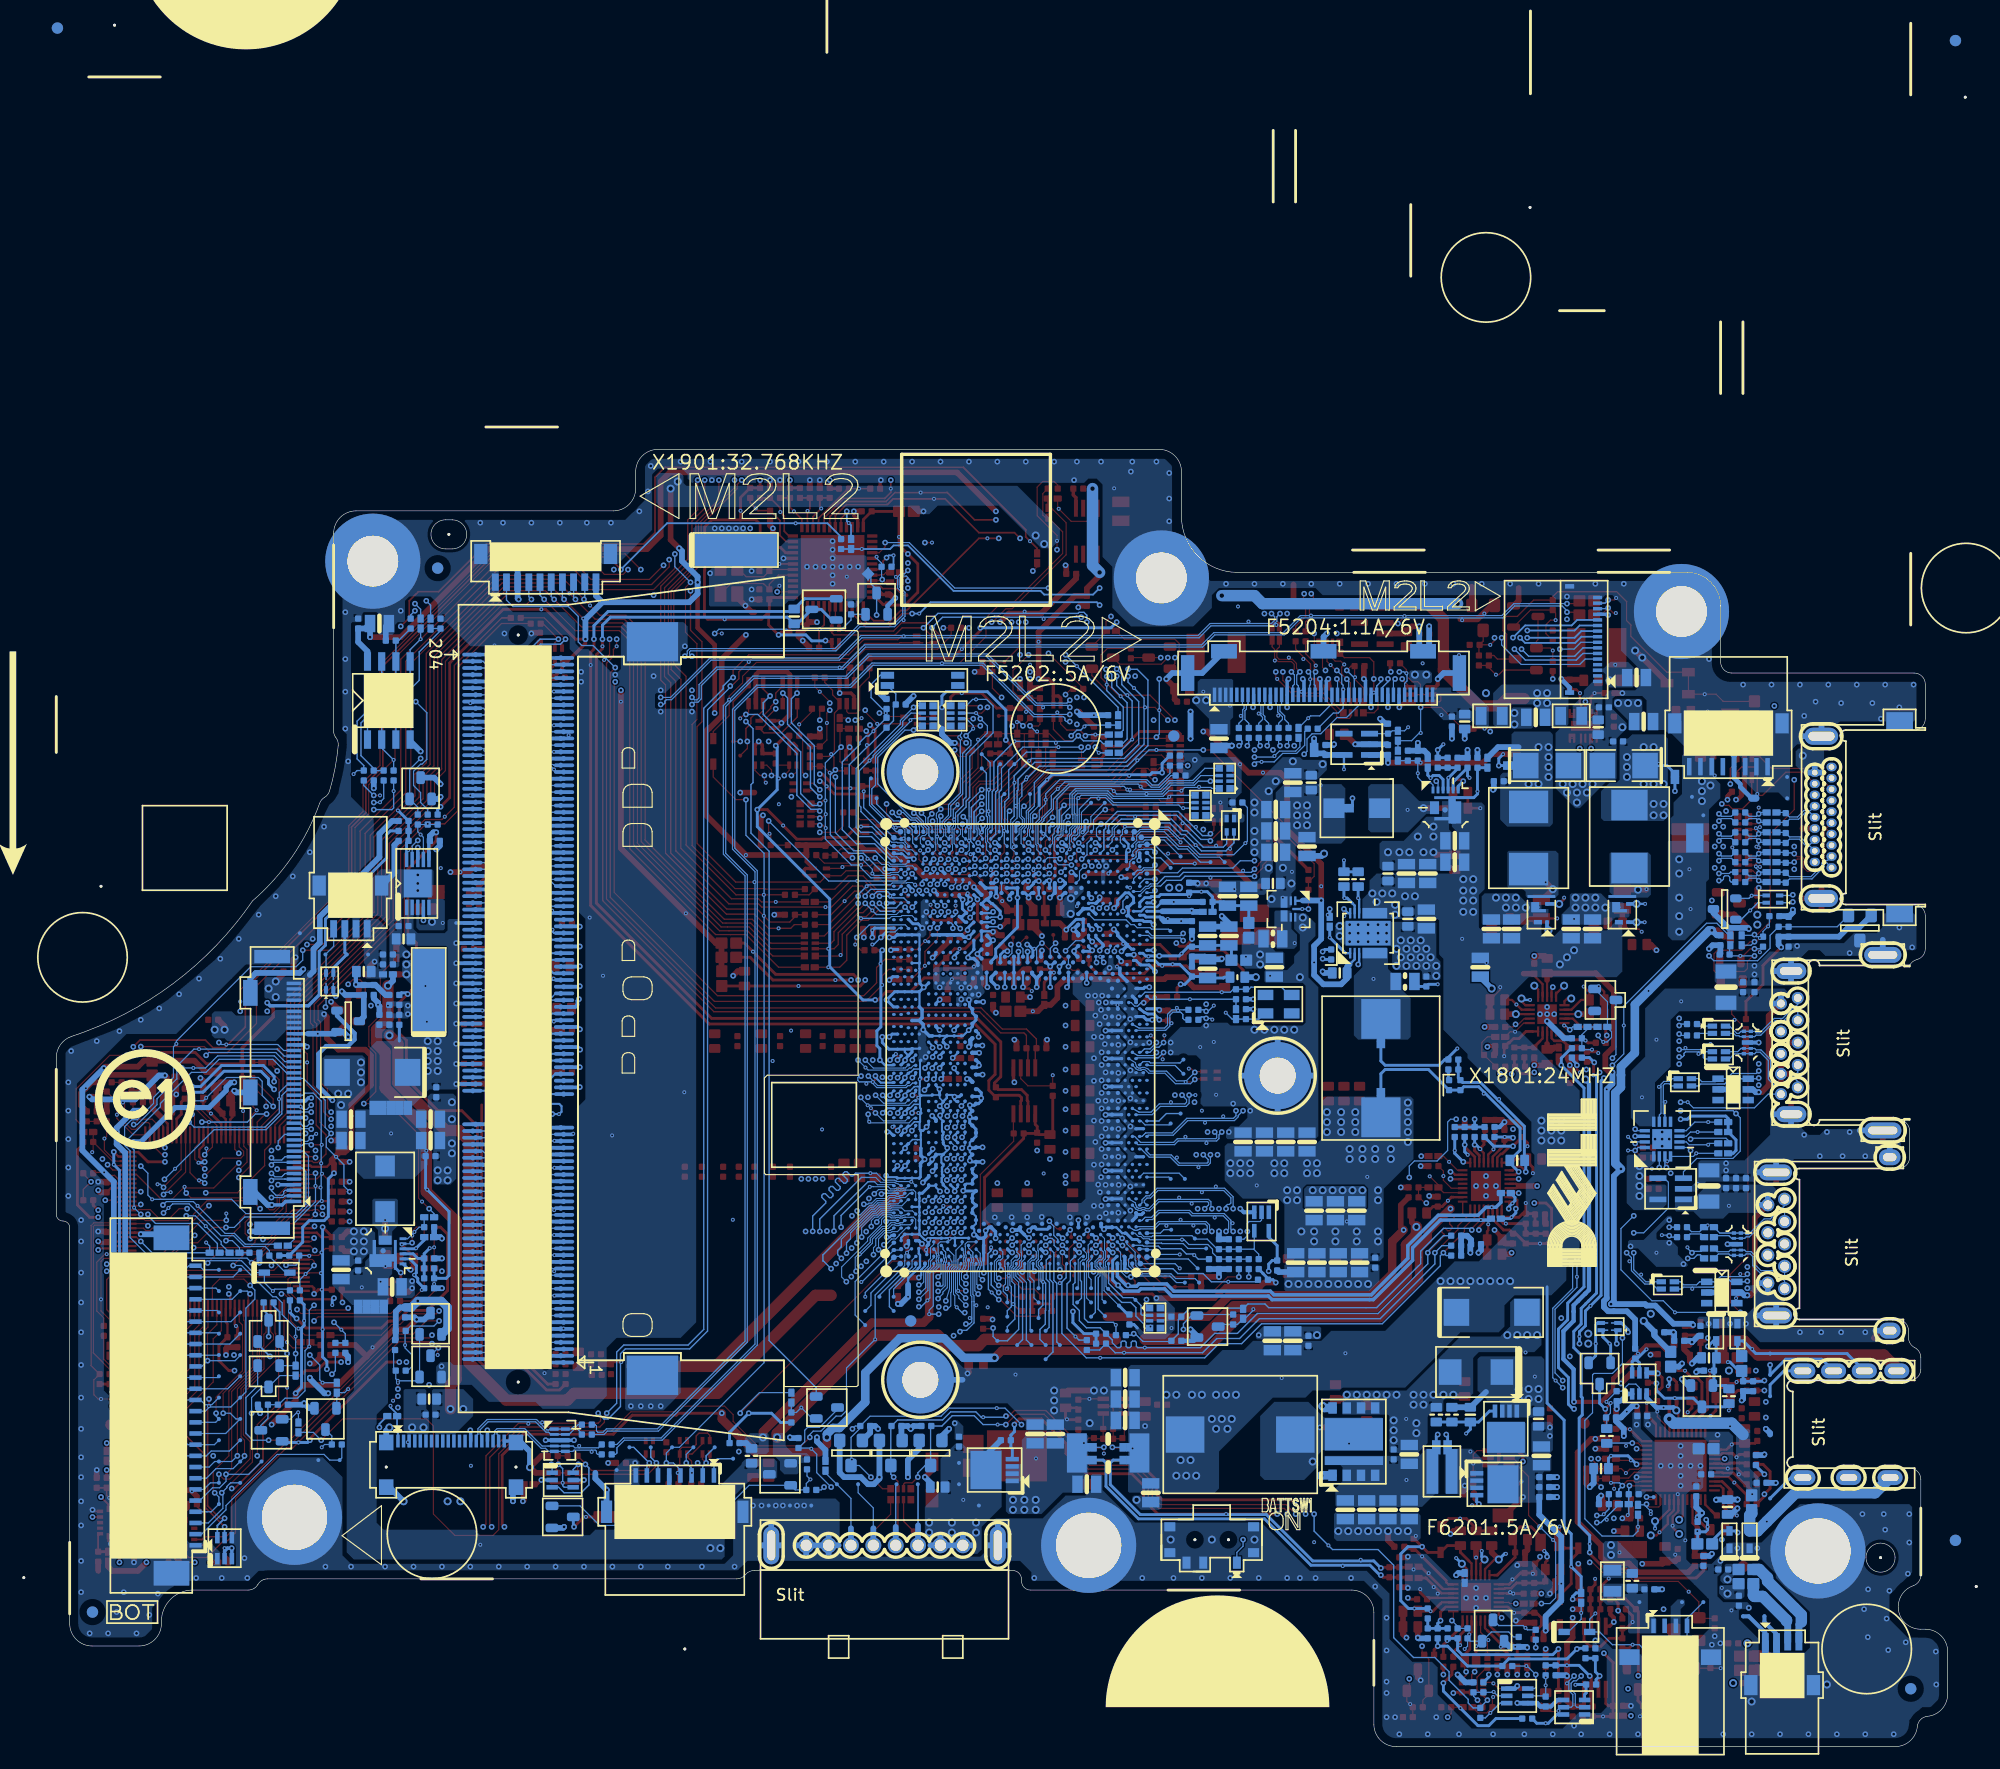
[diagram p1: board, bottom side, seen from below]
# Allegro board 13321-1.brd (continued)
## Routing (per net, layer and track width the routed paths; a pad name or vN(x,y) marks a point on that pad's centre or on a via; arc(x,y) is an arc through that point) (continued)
USB_PP6: length 119.4
  TOP w0.102: v2(34.04,101.44) 33.17,101.44 R5223.1
  L4 w0.114: v2(89.66,75.2) 89.9,75.44 89.9,75.72 90.28,76.09 90.81,76.09 92.28,74.63 97.26,74.63 104.73,82.09 104.73,83.05 112.86,91.18 112.86,93.29 112.74,93.41 112.49,93.41 v2(112.27,93.19)
  BOTTOM w0.102: v2(34.04,101.44) 34.04,101.57 34.47,102 38.71,102 39.78,100.93 43.41,100.93 ; v2(89.66,75.2) 89.99,75.53 CPU1.AN11 ; 43.41,100.93 57.79,100.93 59.31,99.41 65.52,99.41 66.62,98.32 96.76,98.32 98.74,96.34 109.97,96.34 111.43,94.88 111.43,93.69 111.73,93.39 112.06,93.39 v2(112.27,93.19) ; 43.41,100.93 v1(43.41,100.73)
USB_PP6_TPNL: length 3.4
  TOP w0.102: v1(29.67,101.36) 29.9,101.36 v2(30.35,101.82) 30.83,101.35 31.44,101.35 R5223.2
  BOTTOM w0.102: HOMBD1.14 30.42,101.75 v2(30.35,101.82)
USB_PP7: length 119.4
  L4 w0.114: v2(89.98,74.65) 90.2,74.43 90.2,74.14 90.66,73.67 97.75,73.67 113.81,89.73 113.81,96.75 118.21,101.15 130.07,101.15 135.08,96.13 135.08,87.57 135.91,86.75 135.91,76.03 138.3,73.64 138.3,71.09 145.54,63.85 146.66,63.85 151.18,59.33 151.18,51.92 150.37,51.11 150.01,51.11 v2(149.86,51.26)
  BOTTOM w0.102: v2(149.86,51.26) 149.56,50.96 148.94,50.96 148.65,51.25 IOBD1.6 ; v2(89.98,74.65) 89.98,74.35 90.09,74.24 CPU1.AP13
USB_PWR_EN#: length 204.9
  TOP w0.102: KBC24.101 159.54,55.49 159.77,55.72 160.15,55.72 160.53,56.1 161.7,56.1 v2(162.18,55.63) 162.24,55.69 R2412.1
  L3 w0.102: v2(162.18,55.63) 161.39,54.84 161.39,52.83 161.98,52.24 161.98,38.32 159.65,35.99 156.26,35.99 154.35,34.08 152.98,34.08 152.27,33.37 152.27,29.72 150.85,28.29 148.94,28.29 140.81,20.16 98.39,20.16 97.32,21.23 86.67,21.23 77.85,30.05 77.85,31.84 75.51,34.18 43.33,34.18 31.57,45.94 v2(28.07,45.94)
  BOTTOM w0.102: IOBD1.27 148.72,61.75 149.35,62.37 v1(156.34,62.37) 156.79,62.37 158.32,60.85 158.32,59.71 160.1,57.93 160.1,57.4 161.87,55.63 v2(162.18,55.63) ; v2(28.07,45.94) 27.18,45.94 24.97,48.15 24.97,50.46 25.33,50.83 U3502.4
USBCHARGER_CB0: length 184.1
  TOP w0.102: v2(159.51,49.37) 159.51,49.4 157.54,51.37 KBC24.106
  L3 w0.102: v2(22.99,54.32) 23.42,53.89 23.42,51.8 26.92,48.3 26.92,48 27.99,46.93 31.59,46.93 38.85,39.67 61.68,39.67 66.46,34.89 75.88,34.89 78.56,32.21 78.56,30.35 86.97,21.94 97.62,21.94 98.69,20.87 140.52,20.87 151.69,32.04 151.69,33.5 152.77,34.59 154.14,34.59 156.05,36.49 156.47,36.49 159.44,36.49 159.85,36.91 159.85,40 159.77,40.09 159.77,43.13 159.99,43.36 159.99,48.89 v2(159.51,49.37)
  BOTTOM w0.102: v1(158.88,49.57) 159.31,49.57 v2(159.51,49.37) ; R3501.1 19.62,54.21 19.81,54.4 22.91,54.4 v2(22.99,54.32)
USBDET_CON#: length 169.7
  L3 w0.102: v2(151.64,29.81) 151.05,29.23 149.45,29.23 140.69,20.47 98.52,20.47 97.45,21.53 86.8,21.53 78.16,30.18 78.16,32.05 75.71,34.49 66.29,34.49 61.52,39.26 38.69,39.26 31.43,46.52 27.17,46.52 26.52,47.17 26.52,48.13 22.5,52.14 22.5,56.25 v2(23.88,57.63)
  BOTTOM w0.102: v2(23.88,57.63) v1(23.24,57.63) 22.73,57.12 17.27,57.12 16.04,58.35 USB1.D1 ; R2453.2 149.1,33.18 D2402.3 150.69,32.16 151.64,31.21 v2(151.64,29.81)
USBDISABLE: length 3.8
  TOP w0.152: v2(94.87,106.32) 95.19,106 95.19,105.53 95.46,105.26 U6601.31
  BOTTOM w0.152: v2(94.87,106.32) 94.67,106.52 v1(94.25,106.52) 94.25,105.68 R6605.2
VD1_EN#: length 6.9
  TOP w0.203: KBC24.66 163.49,41.16 163.77,40.88 163.77,40.54
  TOP w0.254: R2449.2 161.04,36.67 v1(161.54,37.18) 161.54,38.19 163.77,40.42 163.77,40.54
VD_IN1: length 115.3
  TOP w0.203: 158.34,56.13 KBC24.104
  TOP w0.254: 158.34,56.13 157.93,56.55 157.93,57.63 C2613.1 157.5,57.94 157.06,58.39 v2(156.95,58.39) ; v2(100.84,86.96) 100.61,86.96 99.34,85.69 v1(98.09,85.69) 97.22,85.69 C2612.1 96.33,85.88 R2610.1 95.89,86.33 R2608.2 R2609.2
  L3 w0.254: v2(100.84,86.96) 100.78,87.02 100.78,87.71 101.98,88.91 101.98,92.38 101.65,92.71 101.65,94.76 103.76,96.87 106.49,96.87 109.72,100.09 111.84,100.09 112.78,101.03 128.42,101.03 133.65,95.79 133.65,88.44 135.64,86.45 135.64,77.16 134.39,75.91 134.39,66.48 136.39,64.48 139.48,64.48 145.09,58.87 149.52,58.87 v2(149.62,58.77)
  BOTTOM w0.254: v2(149.62,58.77) 149.64,58.77 150.13,59.26 150.13,59.72 150.8,60.39 154.11,60.39 155.98,58.51 156.82,58.51 v2(156.95,58.39)
VD_IN1_C: length 112.4
  TOP w0.254: R2610.2 96.33,84.99 C2612.2 97.22,85.18 99.54,85.18 v1(100.23,85.87) 100.24,85.87 100.7,86.33 v2(100.84,86.33) ; R2611.1 157.61,59.85 C2613.2 157.42,58.83 157.23,59.02 v2(156.95,59.02)
  L3 w0.254: v2(100.84,86.33) 100.71,86.45 100.63,86.45 100.27,86.81 100.27,87.92 101.47,89.12 101.47,92.17 101.14,92.5 101.14,94.97 103.55,97.38 106.28,97.38 109.51,100.6 111.63,100.6 112.57,101.54 128.63,101.54 134.16,96.01 134.16,88.65 136.14,86.67 136.14,76.95 134.9,75.7 134.9,66.69 136.6,64.99 139.69,64.99 145.3,59.38 149.52,59.38 149.61,59.47 v2(149.62,59.47)
  BOTTOM w0.254: v2(156.95,59.02) 156.2,59.02 154.32,60.9 150.59,60.9 149.62,59.93 v2(149.62,59.47)
VD_OUT1#: length 71.4
  TOP w0.203: v2(155.83,52.29) 155.88,52.29 156.31,52.73 156.31,53.39 155.94,53.77 KBC24.110
  L3 w0.254: v2(135.76,32.35) 134.87,31.46 129.79,31.46 128.82,30.49 124.77,30.49 123.59,29.3 107.74,29.3 107.23,29.81 v2(107.19,29.81)
  L4 w0.254: v2(155.83,52.29) 155.7,52.16 155.62,52.16 154.36,50.9 154.36,50.36 147.62,43.63 147.62,42.81 145.54,40.73 145.54,38.42 140.93,33.81 137.99,33.81 136.53,32.35 v2(135.76,32.35)
  BOTTOM w0.254: R2607.2 108.9,28.1 v2(107.19,29.81) 105.16,29.81 104.33,28.99 R2602.2 ; v2(155.83,52.29) 155.91,52.22 v1(156.39,52.22)
VOL_DOWN#: length 17.3
  TOP w0.102: KBC24.26 148.45,43.16 v2(148.56,43.05)
  L3 w0.102: v2(149.26,53.56) 149.26,53.45 148.84,53.03 148.84,43.33 v2(148.56,43.05)
  BOTTOM w0.102: IOBD1.13 148.67,54.75 149.26,54.16 v2(149.26,53.56) ; v1(146.48,43.88) 146.51,43.91 R2448.1 147.38,43.34 147.68,43.05 v2(148.56,43.05)
VOL_UP#: length 28.6
  TOP w0.102: R2446.1 v1(160.15,37.26) 160.74,37.86 KBC24.63 160.74,40.06 160.83,40.15 160.83,40.53 159.38,41.98 159.38,43.25 157.58,45.05 156.46,45.05 155.09,46.43 v2(153.92,46.43)
  BOTTOM w0.102: v2(153.92,46.43) 153.18,46.43 152.25,47.36 147.61,47.36 146.55,48.42 146.55,52.79 147.01,53.25 IOBD1.10
VR_SVID_ALERT#: length 42.9
  TOP w0.114: PU4601.32 42.68,47.68 43.78,46.57 43.78,46.23 v2(45.85,44.16)
  BOTTOM w0.114: R701.1 75.82,35.46 R703.2 74.43,35.22 v1(73.63,35.22) 66.61,35.22 65.34,36.49 63.31,36.49 61.8,38 61.53,38.27 50.74,38.27 45.85,43.16 v2(45.85,44.16) 45.21,44.8 PR4623.1
VTT_EN: length 5.1
  BOTTOM w0.102: PR4909.2 PR4925.2 PR4926.2 136.78,81.81 v1(136.53,81.55) 136.28,81.31 PU4902.7
WIFI_RF_EN: length 26.8
  TOP w0.102: v2(161.54,47.59) 161.58,47.56 KBC24.82
  BOTTOM w0.102: IOBD1.24 148.52,60.25 149.73,61.46 154.55,61.46 155.72,60.29 157.01,60.29 159.79,57.51 159.79,57.22 162.69,54.32 162.69,53.9 162.14,53.35 v1(162.14,48.19) v2(161.54,47.59)
XCLK_BIASREF: length 3.9
  TOP w0.508: v2(71.88,66.52) 71.4,67 v1(70.89,67) 70.87,67.02 R1803.1
  BOTTOM w0.102: CPU1.C26 73,66.54 72.68,66.22 72.43,66.22 72.13,66.52 v2(71.88,66.52)
XDP_BPM0: length 5.8
  BOTTOM w0.089: TP9612.1 76.98,40.12 76.98,43.41 76.8,43.59 76.8,44.18 76.84,44.22 76.84,44.85 CPU1.J60
XDP_BPM1: length 1.5
  TOP w0.114: v2(76.15,44.83) 76.3,44.83 TP9613.1
  BOTTOM w0.114: CPU1.H60 76.04,44.83 v2(76.15,44.83)
XDP_BPM2: length 6.9
  BOTTOM w0.089: 75.95,41.93 75.78,42.1 75.78,42.7 76.05,42.98 76.05,43.32 75.85,43.52 75.66,43.52 75.48,43.7 75.48,44.24 CPU1.H61
  BOTTOM w0.114: TP9614.1 75.95,39.11 75.95,41.93
XDP_BPM3: length 6
  BOTTOM w0.089: CPU1.H62 75.79,43.84 76.23,43.39 76.23,42.9 75.96,42.63 75.96,42.25 76.2,42
  BOTTOM w0.114: 76.2,42 76.2,38.83 TP9615.1
XDP_BPM4: length 1.2
  TOP w0.114: v2(76.9,46.18) 76.83,46.11 TP9616.1
  BOTTOM w0.114: v2(76.9,46.18) 77.23,45.85 CPU1.K59
XDP_BPM5: length 3.6
  BOTTOM w0.089: CPU1.H63 75.77,42.96 75.6,42.79 75.6,39.98 TP9617.1
XDP_BPM6: length 4.4
  TOP w0.114: v2(77.63,45.47) 78.56,44.54 78.56,43.22 78.11,42.76 TP9618.1
  BOTTOM w0.114: v2(77.63,45.47) 77.63,45.46 77.31,45.14 CPU1.K60
XDP_BPM7: length 2
  TOP w0.114: TP9619.1 76.83,43.49 v2(76.15,44.18)
  BOTTOM w0.114: v2(76.15,44.18) 76.45,44.49 CPU1.J61
XDP_DBRESET#: length 17.1
  TOP w0.114: R1701.2 EC1706.1 76.33,89.88 v2(76.83,89.38)
  BOTTOM w0.089: 84.3,82.08 84.34,82.04 84.34,80.76 CPU1.AC3
  BOTTOM w0.114: v2(76.83,89.38) 77.29,88.93 82.37,88.93 TP9653.1 83.95,87.34 83.95,84.83 84.3,84.47 84.3,82.08
XDP_PRDY#: length 3.1
  BOTTOM w0.089: TP9602.1 76.58,41.78 76.8,42 76.8,43.33 76.52,43.62 CPU1.J62
XDP_PREQ#: length 3.2
  BOTTOM w0.089: CPU1.K62 77.43,43.84 77.73,43.53 77.73,41.08 TP9601.1
XDP_TCK_JTAGX: length 5.6
  TOP w0.114: v2(84.84,40.61) 84.59,40.61 v1(83.55,39.57) 83.54,39.57 82.93,38.96 R1919.1
  BOTTOM w0.114: CPU1.AE63 85.51,41.28 v2(84.84,40.61)
XDP_TCLK: length 8.3
  TOP w0.114: v2(73.78,44.81) 73.68,44.81 69.99,41.12 TP9650.1 R406.1
  BOTTOM w0.114: CPU1.E60 73.9,44.81 v2(73.78,44.81)
XDP_TDI: length 7.1
  BOTTOM w0.114: RN401.2 72.01,38.57 72.12,38.68 72.12,39.45 TP9623.1 72.82,40.15 73.74,40.15 75.02,41.43 CPU1.F63
XDP_TDO: length 8.9
  BOTTOM w0.089: CPU1.F62 75.02,43.62 75.31,43.33 75.31,43 75.25,42.94 75.25,41.13 TP9624.1
  BOTTOM w0.114: RN401.4 71.74,37.42 71.88,37.55 71.88,37.8 72.57,38.49 72.57,39.26 73.04,39.72 73.84,39.72 TP9624.1
XDP_TMS: length 7.6
  TOP w0.114: TP9611.1 72.64,41.62 v2(73.03,42)
  L3 w0.127: v2(73.03,42) 71.63,40.61 v2(71.63,39.97)
  BOTTOM w0.089: CPU1.E61 73.94,44.2 73.94,43.52 73.9,43.47 73.9,42.47 73.43,42 v2(73.03,42)
  BOTTOM w0.114: v2(71.63,39.97) 71.63,39.5 RN401.1
XDP_TRST#: length 8.2
  TOP w0.114: v2(73.81,45.45) 73.68,45.45 70.23,42 TP9621.1 R402.1
  BOTTOM w0.114: v2(73.81,45.45) 74.14,45.79 CPU1.E59
XTAL24_IN: length 9
  BOTTOM w0.114: R1810.1 R1802.1 v1(67.74,66.83) 71.32,66.83 CPU1.A25
XTAL24_IN_R: length 4
  BOTTOM w0.114: v1(64.54,65.63) 64.52,65.6 63.97,65.06 R1810.2 C1801.2 61.59,65.06 61.08,65.56 X1801.1
XTAL24_OUT: length 14.2
  BOTTOM w0.114: CPU1.B25 72.12,67.1 71.76,67.46 v1(64.9,67.46) 64.14,67.46 63.87,67.72 R1802.2 C1802.2 62.47,67.72 62.28,67.91 59.56,67.91 58.86,67.21 X1801.3
N29302517: length 5.9
  TOP w0.203: PU4401.21 44.63,14.5 44.83,14.7 44.83,14.85
  TOP w0.254: PR4471.1 48.39,17.68 PR4470.2 47.67,17.68 v1(46.99,17.01) 44.83,14.85
N172633395: length 6.8
  BOTTOM w0.254: PR4208.1 PR4207.2 PC4201.2 ; PC4201.2 41.94,29.03 40.96,30 PU4201.4 ; PC4201.2 42.67,28.38 v1(43.05,28)

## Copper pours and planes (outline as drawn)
5V_HDMI_R_S5 on TOP: 22.23,90.65 21.21,91.66 18.67,91.66 18.54,91.79 18.54,92.8 18.8,93.06 23.24,93.06 23.37,92.93 23.37,90.77 23.24,90.65 ; 1 cut-out
5V_HDMI_S5 on TOP: 12.83,87.98 12.57,88.23 12.57,88.99 14.22,90.65 17.27,90.65 17.91,91.28 20.19,91.28 20.32,91.15 20.32,90.01 20.19,89.88 17.91,89.88 17.27,89.25 15.88,89.25 14.61,87.98 ; 2 cut-outs
5V_HDMI_S5 on BOTTOM: 11.18,86.71 11.05,86.84 11.05,88.99 11.3,89.25 13.34,89.25 13.59,88.99 13.59,87.72 12.57,86.71
5V_S0 on TOP: 28.52,16.78 28.45,16.86 28.45,18.38 28.57,18.51 30.35,18.51 30.48,18.38 30.48,16.99 30.28,16.78
5V_S0 on TOP: 131.44,20.92 131.06,21.3 131.06,30.57 131.44,30.96 134.49,30.96 135,30.45 135,21.3 134.62,20.92
5V_S0 on TOP: 25.91,91.79 25.65,92.04 24,92.04 23.88,92.17 23.88,92.93 24,93.06 26.42,93.06 27.05,93.69 27.05,96.23 28.7,97.88 28.7,100.04 28.83,100.17 30.35,100.17 30.61,99.92 30.61,96.74 30.23,96.36 28.83,96.36 28.45,95.98 28.45,93.95 28.7,93.69 31.37,93.69 31.75,93.31 31.75,91.92 30.48,91.92 30.35,91.79 ; 6 cut-outs
5V_S0 on BOTTOM: 133.4,26.76 133.4,27.98 131.83,29.56 131.83,31.08 132.72,31.97 135.38,31.97 135.51,31.84 135.51,28.29 135.2,27.98 135.2,26.76 134.9,26.76 134.9,27.91 134.85,27.96 134.75,27.96 134.7,27.91 134.7,26.76 134.39,26.76 134.39,27.91 134.34,27.96 134.24,27.96 134.19,27.91 134.19,26.76 133.91,26.76 133.91,27.88 133.83,27.96 133.76,27.96 133.71,27.91 133.71,26.76 ; 4 cut-outs
5V_S0 on BOTTOM: 27.43,90.9 27.3,91.03 27.3,93.57 27.43,93.69 29.72,93.69 29.84,93.57 29.84,93.06 28.57,91.79 28.57,90.9
5V_S0 on BOTTOM: 27.81,15.08 27.69,15.21 27.69,16.6 29.46,18.38 30.61,18.38 30.86,18.13 30.86,15.21 30.73,15.08 ; 1 cut-out
5V_S0 on L2VCC: 20.76,70.5 22.42,68.85 22.42,48.78 23.56,47.64 23.56,44.47 30.78,37.24 33.32,37.24 34.59,35.97 63.29,35.97 64.18,35.08 75.36,35.08 75.98,34.46 78.8,31.64 78.8,29.73 81.71,26.83 85.27,26.83 89.08,23.02 98.63,23.02 99.01,23.4 109.14,23.4 111.05,21.49 126.57,21.49 127.33,22.26 134.94,22.26 134.94,19.99 133.53,18.57 110.19,18.57 108.28,20.48 87.71,20.48 84.41,23.78 80.47,23.78 71.83,32.42 62.56,32.42 61.67,33.31 36.5,33.31 35.88,32.69 35.88,19.99 31.54,15.65 29.29,15.65 28.26,16.68 28.26,18.18 28.53,18.45 30.81,18.45 32.96,20.59 32.96,27.35 31.81,28.49 31.81,30.78 30.67,31.92 30.67,34.46 24.84,40.29 20.65,40.29 20.38,40.56 20.38,43.86 19.11,45.13 19.11,52.62 18.48,53.26 18.48,63.8 17.97,64.31 17.97,72.06 16.32,73.71 16.32,87.65 23.45,94.77 29.26,94.77 30.04,94 30.04,91.23 29,90.2 25.07,90.2 23.56,88.69 23.56,86.66 20.76,83.87
5V_S0 on L3: 26.92,37.69 27.56,37.69 28.32,38.45 28.32,38.58 29.84,40.1 30.23,40.1 30.61,39.72 30.61,36.16 31.5,35.27 33.4,35.27 34.04,35.91 34.04,41.75 32.13,43.66 25.65,43.66 24.51,44.8 24.51,49.24 21.72,52.04 21.72,69.18 20.45,70.45 20.45,74.39 19.81,75.02 19.81,76.17 18.8,77.18 18.8,82.77 18.41,83.15 18.41,84.93 18.8,85.31 18.92,85.31 21.21,87.6 21.72,87.6 25.4,91.28 27.3,91.28 28.45,92.42 29.97,92.42 30.1,92.55 30.1,94.58 29.46,95.22 23.24,95.22 15.88,87.85 15.88,74.14 17.65,72.36 17.65,64.36 18.16,63.85 18.16,53.31 18.8,52.67 18.8,45.05 19.94,43.91 19.94,40.35 20.45,39.85 24.77,39.85
5V_S0 on L4: 26.04,39.34 26.04,38.7 27.18,37.56 29.08,37.56 30.99,35.65 32.38,35.65 32.64,35.91 32.64,37.18 30.73,39.08 29.97,39.08 29.46,39.59 26.29,39.59
5V_S5 on TOP: 25.4,82.77 24.89,83.28 24.89,85.57 24.13,86.33 24.13,90.01 23.88,90.26 23.88,91.53 24,91.66 25.02,91.66 26.04,90.65 32.51,90.65 32.51,86.96 32.26,86.71 31.5,86.71 30.99,86.2 30.99,83.03 30.73,82.77
5V_S5 on TOP: 27.3,48.61 26.42,49.5 26.42,51.28 27.43,52.29 27.81,52.29 27.94,52.16 27.94,48.86 27.69,48.61 ; 3 cut-outs
5V_S5 on BOTTOM: 146.56,66.64 146.18,67.02 146.18,69.31 146.3,69.44 149.73,69.44 150.5,68.67 150.5,67.02 150.11,66.64
5V_S5 on BOTTOM: 25.4,82.77 25.02,83.15 25.02,90.14 25.4,90.52 28.19,90.52 28.57,90.14 29.21,90.14 29.34,90.01 29.34,86.45 29.59,86.2 30.23,86.2 30.99,85.44 30.99,83.03 30.73,82.77 ; 1 cut-out
5V_S5 on BOTTOM: 25.65,47.97 25.15,48.48 25.15,50.13 25.27,50.26 26.8,50.26 26.92,50.39 26.92,51.53 26.16,52.29 26.16,53.18 27.43,53.18 27.69,52.93 28.57,52.93 28.7,52.8 28.7,48.61 28.07,47.97
5V_S5 on L2VCC: 26.35,72.28 29.02,69.61 29.02,58.69 31.18,56.53 31.18,44.47 33.2,42.45 36.24,42.45 37.89,40.8 45.64,40.8 46.15,40.29 64.31,40.29 65.2,39.4 77.26,39.4 78.28,38.39 81.71,38.39 86.55,33.54 86.55,31.13 90.35,27.34 123.65,27.34 125.3,28.99 141.3,28.99 145.86,33.54 145.86,35.45 150.81,40.4 150.81,56.05 150.05,56.82 150.05,61.77 149.16,62.66 149.16,68.72 149.43,68.99 151.45,68.99 152.97,67.21 152.97,67.2 153.02,67.15 153.07,67.09 153.08,67.09 153.61,66.56 153.61,65.07 153.35,64.82 153.35,63.77 153.85,63.28 156.39,63.28 157.04,62.63 157.04,35.86 154.72,33.54 143.81,22.64 127.18,22.64 126.41,21.88 111.2,21.88 109.3,23.78 98.85,23.78 98.47,23.4 89.23,23.4 85.42,27.21 81.87,27.21 79.18,29.89 79.18,31.8 75.52,35.46 64.34,35.46 63.45,36.35 34.75,36.35 33.48,37.62 30.94,37.62 23.94,44.62 23.94,47.8 22.8,48.94 22.8,69.01 21.15,70.66 21.15,83.71 23.94,86.5 23.94,88.54 25.22,89.82 28.89,89.82 28.89,84.76 26.35,82.22
+3V_AVDD on TOP: 27.48,25.9 27.38,26 26.42,26 26.42,26.21 27.38,26.21 27.43,26.26 27.94,26.26 28.57,26.89 28.57,27.91 28.7,28.03 29.21,28.03 29.34,27.91 29.84,27.91 29.97,27.78 29.97,26.51 29.84,26.38 29.59,26.38 29.11,25.9 ; 1 cut-out
+3V_AVDD on TOP: 20.52,21.81 20.35,21.99 20.35,22.98 20.37,23.01 21.34,23.01 21.34,22.09 21.06,21.81
+3V_AVDD on TOP: 29.59,19.91 29.46,20.03 29.46,20.67 28.96,21.18 28.96,21.56 28.7,21.81 27.43,21.81 27.3,21.94 27.3,22.45 26.92,22.83 26.42,22.83 26.42,23.01 27.38,23.01 27.46,23.08 28.19,23.08 28.32,22.95 29.21,22.95 30.1,22.07 30.1,21.18 30.86,20.41 30.86,20.03 30.73,19.91 ; 3 cut-outs
+5V_AVDD on TOP: 19.89,26.82 18.92,27.78 18.92,28.8 18.67,29.05 16.13,29.05 16,29.18 16,29.81 16.38,30.19 17.53,30.19 18.03,29.69 19.3,29.69 20.07,28.92 20.07,27.27 20.32,27.02 21.34,27.02 21.34,26.82 ; 1 cut-out
+5V_KB_BL on BOTTOM: 26.04,10.13 26.04,11.4 26.8,12.16 26.8,14.45 26.92,14.57 30.73,14.57 30.86,14.45 30.86,13.05 30.48,12.67 28.96,12.67 28.57,12.29 28.57,10.25 28.45,10.13 ; 2 cut-outs
+5V_PVDD on TOP: 26.42,16.86 25.91,17.37 23.62,17.37 22.99,18 22.99,21.28 23.16,21.46 23.16,22.57 23.39,22.57 23.39,21.56 23.47,21.48 23.47,20.44 23.5,20.41 23.5,18.76 23.75,18.51 26.92,18.51 27.05,18.64 27.05,19.14 26.67,19.53 26.67,20.41 26.42,20.67 25.65,20.67 25.15,21.18 25.15,21.56 25.17,21.58 25.17,22.57 25.37,22.57 25.37,21.58 25.65,21.3 27.3,21.3 27.81,20.8 27.81,20.03 28.07,19.78 28.07,16.99 27.94,16.86 ; 4 cut-outs
+V1.05DX_MODPHY_PCH on TOP: 64.01,71.6 63.88,71.72 63.88,73.5 64.01,73.63 64.9,73.63 66.55,75.28 71.25,75.28 73.28,77.31 77.6,77.31 77.98,76.93 78.49,76.93 78.74,76.68 78.74,73.88 78.36,73.5 73.41,73.5 71.88,71.98 69.98,71.98 68.83,73.12 67.82,73.12 66.29,71.6 ; 3 cut-outs
+V1.05DX_MODPHY_PCH on BOTTOM: 78.26,74.11 78.05,74.31 78.05,75.66 77.24,76.47 77.24,76.88 77.37,77.01 77.52,77.01 77.53,76.99 78.54,76.99 78.66,76.88 78.66,76.19 79.4,75.44 79.4,74.44 79.07,74.11
+V1.05S_APLLOPI on TOP: 85.34,69.44 85.09,69.69 83.19,69.69 82.8,70.07 81.79,70.07 81.66,70.2 81.66,70.83 81.41,71.09 81.41,71.47 81.53,71.6 81.79,71.6 82.04,71.34 83.19,71.34 83.82,70.71 84.96,70.71 85.22,70.45 86.23,70.45 86.36,70.33 86.36,69.56 86.23,69.44 ; 1 cut-out
+V1.05S_CORE_PCH on TOP: 62.36,73.5 62.23,73.63 62.23,76.29 64.52,78.58 69.47,78.58 69.98,78.07 69.98,75.66 69.85,75.53 66.42,75.53 65.91,75.02 65.15,75.02 63.63,73.5 ; 4 cut-outs
+V1.05S_CORE_PCH on L3: 68.33,77.82 68.33,76.29 69.98,74.64 71.63,74.64 73.41,72.87 75.82,72.87 76.33,73.37 77.85,73.37 77.98,73.5 77.98,76.04 78.11,76.17 85.09,76.17 85.47,76.55 85.47,77.56 85.34,77.69 84.84,77.69 84.2,77.06 77.34,77.06 76.96,77.44 72.52,77.44 71.5,78.45 68.96,78.45
GND on TOP: 30.1,73.12 29.97,73.25 29.97,74.26 30.1,74.39 30.1,75.41 30.99,76.29 33.66,76.29 33.78,76.17 33.78,73.5 33.4,73.12 ; 4 cut-outs
GND on TOP: 70.48,30.19 70.36,30.32 70.36,30.7 70.48,30.83 70.74,30.83 72.26,32.35 76.58,32.35 76.71,32.23 76.71,31.59 76.58,31.46 74.55,31.46 74.3,31.21 74.3,30.32 74.17,30.19 ; 3 cut-outs
GND on TOP: 27.94,90.77 27.81,90.9 27.81,91.41 27.94,91.53 30.35,91.53 30.61,91.79 37.59,91.79 38.61,92.8 38.99,92.8 39.24,92.55 39.24,91.15 38.86,90.77
GND on TOP: 136.14,73.5 136.02,73.63 136.02,74.01 136.14,74.14 136.14,78.07 136.4,78.33 136.91,78.33 137.16,78.07 137.16,73.75 136.91,73.5
GND on TOP: 110.49,104.62 110.36,104.74 109.22,104.74 109.22,106.14 109.09,106.27 107.44,106.27 107.31,106.39 107.31,106.65 107.44,106.77 110.36,106.77 110.74,106.39 110.74,105.12 110.87,105 110.87,104.74 110.74,104.62
GND on TOP: 77.72,49.12 77.47,49.37 77.47,67.79 77.85,68.17 78.87,68.17 79.12,67.91 79.12,63.21 79.5,62.83 79.5,54.2 79.76,53.94 80.77,53.94 81.15,54.32 81.92,54.32 85.6,50.64 85.6,49.24 85.47,49.12 ; 26 cut-outs
GND on TOP: 14.99,50.01 14.61,50.39 14.61,51.66 13.72,52.55 4.45,52.55 4.19,52.8 4.19,54.96 4.45,55.21 10.92,55.21 11.43,54.7 12.45,54.7 13.21,55.47 13.21,70.45 12.45,71.21 11.43,71.21 10.92,70.71 3.43,70.71 2.79,71.34 2.79,74.26 3.05,74.52 9.65,74.52 10.41,75.28 10.41,77.44 10.67,77.69 12.95,77.69 13.46,78.2 13.46,78.58 13.59,78.71 14.22,78.71 14.35,78.83 14.35,80.1 14.22,80.23 13.21,80.23 12.57,80.87 12.57,81.63 12.45,81.76 11.81,81.76 11.56,82.01 11.56,82.39 11.68,82.52 14.48,82.52 15.49,81.5 15.49,73.5 16.64,72.36 16.64,70.71 17.53,69.82 17.53,69.44 18.03,68.93 18.67,68.93 18.8,68.8 18.8,67.79 18.54,67.53 17.4,67.53 17.14,67.28 17.14,67.02 17.53,66.64 17.53,50.26 17.27,50.01
GND on TOP: 25.53,49.62 24.51,50.64 24.51,54.45 25.53,55.47 26.42,55.47 27.05,54.83 28.07,54.83 28.19,54.7 28.19,54.45 28.07,54.32 27.05,54.32 26.67,53.94 26.67,51.91 26.16,51.4 26.16,49.75 26.04,49.62 ; 5 cut-outs
GND on TOP: 20.07,75.28 19.81,75.53 19.81,83.28 19.56,83.53 19.56,83.79 19.68,83.91 20.7,83.91 21.08,83.53 21.08,77.56 21.34,77.31 21.34,75.41 21.21,75.28
GND on TOP: 38.86,73.37 38.73,73.5 38.73,74.52 38.61,74.64 37.47,74.64 37.34,74.77 37.34,75.15 38.48,76.29 41.4,76.29 41.66,76.04 41.66,73.5 41.53,73.37 ; 3 cut-outs
GND on TOP: outline of 298 points within 0.76,0.73 168.28,115.28 ; 23 cut-outs
GND on TOP: 51.69,40.99 51.44,41.24 51.44,42.51 51.69,42.77 59.31,42.77 59.44,42.64 59.44,41.37 59.05,40.99 ; 7 cut-outs
GND on TOP: 4.45,36.16 4.32,36.29 4.32,37.31 4.45,37.43 13.84,37.43 14.48,38.07 14.48,39.46 15.49,40.48 15.49,41.75 15.75,42 16.38,42 16.64,41.75 16.64,39.97 18.29,38.32 22.23,38.32 22.35,38.19 22.35,37.56 22.23,37.43 18.03,37.43 16.76,36.16
GND on TOP: 34.92,99.54 33.78,100.68 33.78,100.93 33.91,101.06 34.16,101.06 35.05,100.17 35.43,100.17 35.56,100.04 35.56,99.66 35.43,99.54
GND on TOP: 58.42,56.48 56.26,58.64 52.07,58.64 51.94,58.77 51.94,59.4 56.26,63.72 56.26,67.4 56.77,67.91 61.98,67.91 63.25,66.64 66.93,66.64 69.72,63.85 69.72,61.69 68.96,60.93 65.91,60.93 65.66,60.67 65.66,58.51 63.63,56.48 ; 3 cut-outs
GND on TOP: outline of 94 points within 85.6,34.77 131.06,96.61 ; 43 cut-outs
GND on BOTTOM: 133.86,50.26 133.35,50.77 133.35,58.13 133.6,58.39 135.64,58.39 135.89,58.13 135.89,57.24 135.38,56.74 135.38,50.39 135.25,50.26 ; 4 cut-outs
GND on BOTTOM: 134.49,63.72 134.37,63.85 134.37,71.09 134.49,71.21 137.16,71.21 137.29,71.09 137.29,70.45 137.41,70.33 138.05,70.33 138.18,70.2 138.18,68.93 137.29,68.04 137.29,63.85 137.16,63.72
GND on BOTTOM: 13.59,68.04 13.34,68.29 13.34,70.33 12.45,71.21 11.43,71.21 10.92,70.71 4.32,70.71 4.19,70.83 4.19,71.09 4.06,71.21 2.92,71.21 2.79,71.34 2.79,74.26 3.05,74.52 5.71,74.52 5.84,74.39 5.84,73.25 6.35,72.74 8.38,72.74 9.27,71.85 14.35,71.85 14.48,71.72 14.48,71.34 14.73,71.09 16,71.09 17.02,70.07 20.7,70.07 20.83,69.94 20.83,68.42 20.45,68.04 ; 5 cut-outs
GND on BOTTOM: 88.14,27.4 88.01,27.53 88.01,28.67 88.52,29.18 88.9,29.18 89.03,29.05 89.03,28.8 88.77,28.54 88.77,27.53 88.65,27.4
GND on BOTTOM: 44.58,78.33 44.32,78.58 44.32,81.76 44.58,82.01 44.58,84.55 45.21,84.55 45.21,83.15 46.61,83.15 47.12,82.64 47.12,82.52 48.64,80.99 50.55,80.99 50.8,80.74 50.8,78.58 50.55,78.33 ; 1 cut-out
GND on BOTTOM: 142.75,42.89 142.49,43.15 141.86,43.15 141.73,43.27 141.73,43.53 141.22,44.04 139.06,44.04 139.06,44.67 140.59,44.67 140.59,45.94 141.1,46.45 143.89,46.45 144.4,45.94 144.4,43.02 144.27,42.89 ; 1 cut-out
GND on BOTTOM: 97.66,101.82 96.65,102.84 96.65,106.39 96.77,106.52 99.31,106.52 99.44,106.65 99.44,107.92 99.57,108.04 103.63,108.04 104.39,107.28 104.39,105.5 104.52,105.38 110.49,105.38 110.74,105.12 110.74,102.08 110.62,101.95 104.14,101.95 103.63,102.46 103.12,102.46 102.23,103.35 98.68,103.35 98.42,103.09 98.42,102.08 98.17,101.82 ; 1 cut-out
GND on BOTTOM: 52.07,48.1 51.94,48.23 51.94,49.88 52.2,50.13 57.28,50.13 57.53,49.88 57.53,48.23 57.4,48.1
GND on BOTTOM: 35.56,26.26 35.31,26.51 35.31,28.8 35.56,29.05 37.08,29.05 37.21,28.92 37.21,26.38 37.08,26.26 ; 1 cut-out
GND on BOTTOM: 56.52,54.32 56.26,54.58 56.26,67.91 57.15,68.8 57.15,71.85 56.52,72.48 56.52,73.63 57.4,74.52 58.42,74.52 58.42,73.12 57.91,72.61 57.91,71.21 58.42,70.71 58.42,70.07 59.05,69.44 60.96,69.44 61.09,69.31 61.09,68.42 60.96,68.29 57.66,68.29 57.4,68.04 57.4,64.74 57.66,64.48 64.14,64.48 64.39,64.74 66.42,64.74 66.8,64.36 68.58,64.36 69.72,63.21 69.72,61.94 69.6,61.82 67.18,61.82 66.8,61.44 66.8,57.5 66.55,57.24 62.74,57.24 62.61,57.12 62.61,56.23 63.37,55.47 64.14,55.47 64.52,55.09 64.52,54.45 64.39,54.32
GND on BOTTOM: 104.78,105.63 104.65,105.76 104.65,108.3 104.78,108.43 107.06,108.43 107.31,108.68 107.31,109.06 107.44,109.19 111.89,109.19 112.14,108.93 112.14,105.89 111.89,105.63
GND on BOTTOM: 138.56,69.69 138.43,69.82 138.43,70.45 138.3,70.58 137.67,70.58 137.54,70.71 137.54,71.09 138.18,71.72 138.18,75.79 137.92,76.04 135.51,76.04 135.38,76.17 135.38,78.33 135.51,78.45 140.08,78.45 142.62,75.91 142.62,72.36 142.49,72.23 142.11,72.23 141.99,72.36 141.99,74.01 141.73,74.26 140.21,74.26 139.32,73.37 139.32,69.82 139.19,69.69 ; 4 cut-outs
GND on BOTTOM: 47.37,26.26 46.48,27.15 46.48,29.56 46.1,29.94 45.21,29.94 45.09,30.07 45.09,30.96 44.96,31.08 42.93,31.08 42.42,31.59 42.42,34.77 41.91,35.27 36.96,35.27 36.32,35.91 36.32,39.97 36.45,40.1 38.73,40.1 39.12,39.72 39.12,37.56 40.01,36.67 43.56,36.67 48.39,31.84 53.85,31.84 54.1,31.59 54.1,29.69 50.04,29.69 49.91,29.56 49.91,26.38 49.78,26.26 ; 2 cut-outs
GND on BOTTOM: 91.57,72.36 91.31,72.61 91.31,73.37 91.06,73.63 91.06,73.88 91.19,74.01 91.19,74.39 91.06,74.52 91.06,75.66 91.19,75.79 91.57,75.79 91.82,75.53 91.82,73.12 92.2,72.74 92.2,72.48 92.08,72.36
GND on BOTTOM: 38.23,73.5 37.59,74.14 35.81,74.14 35.69,74.26 35.69,74.9 36.32,74.9 36.32,75.53 37.72,75.53 38.48,76.29 41.4,76.29 41.66,76.04 41.66,73.63 41.53,73.5
GND on BOTTOM: 70.48,21.18 70.23,21.43 70.23,22.32 70.36,22.45 72.77,22.45 72.9,22.32 72.9,21.94 72.14,21.18
GND on BOTTOM: 23.37,42.89 23.24,43.02 23.24,43.15 24.13,44.04 24.13,44.67 24.77,45.31 25.91,45.31 26.04,45.43 26.04,45.94 25.02,46.96 24.77,46.96 24.64,47.08 24.64,47.34 24.77,47.47 25.02,47.47 27.18,45.31 28.45,45.31 28.57,45.18 28.57,44.67 28.45,44.54 27.69,44.54 26.04,42.89
GND on BOTTOM: 75.44,77.06 75.31,77.18 75.31,78.2 74.93,78.58 74.93,78.96 75.44,79.47 75.56,79.47 75.69,79.34 75.69,79.09 75.56,78.96 75.56,78.45 75.69,78.33 75.69,77.18 75.56,77.06
GND on BOTTOM: outline of 346 points within 0.76,0.73 168.28,115.16 ; 17 cut-outs
GND on BOTTOM: 135.89,26.76 135.89,27.96 135.76,28.09 135.76,29.94 136.02,30.19 136.02,31.84 136.14,31.97 137.92,31.97 138.05,31.84 138.05,28.29 137.69,27.93 137.69,26.76 137.39,26.76 137.39,27.91 137.34,27.96 137.26,27.96 137.21,27.91 137.21,26.76 136.91,26.76 136.91,27.91 136.86,27.96 136.75,27.96 136.7,27.91 136.7,26.76 136.4,26.76 136.4,27.91 136.35,27.96 136.25,27.96 136.19,27.91 136.19,26.76 ; 4 cut-outs
GND on BOTTOM: 56.13,36.42 56.01,36.54 56.01,37.43 56.13,37.56 61.21,37.56 61.85,36.92 61.85,36.54 61.72,36.42 ; 2 cut-outs
GND on BOTTOM: 91.44,61.18 90.93,61.69 90.93,62.32 91.31,62.71 91.31,64.36 91.44,64.48 91.69,64.48 91.69,64.36 92.08,63.98 92.08,61.31 91.95,61.18
GND on BOTTOM: 143.13,53.31 143,53.43 143,56.99 141.48,58.51 141.48,61.56 141.73,61.82 145.03,61.82 145.29,61.56 145.29,59.28 144.15,58.13 144.15,53.43 144.02,53.31
GND on BOTTOM: 114.81,30.07 113.28,31.59 113.28,34.77 113.54,35.02 118.11,35.02 118.24,34.89 118.24,30.19 118.11,30.07
GND on BOTTOM: 47.37,18.38 47.12,18.64 47.12,20.67 47.37,20.92 54.74,20.92 54.86,20.8 54.86,18.64 54.61,18.38
GND on BOTTOM: 61.09,76.17 60.58,76.68 60.58,77.95 60.33,78.2 60.33,85.44 59.31,86.45 56.39,86.45 55.5,87.34 55.5,88.11 55.63,88.23 57.66,88.23 57.91,88.49 59.44,88.49 62.36,85.57 62.36,79.85 62.1,79.6 61.72,79.6 61.47,79.34 61.47,77.69 61.72,77.44 67.18,77.44 67.31,77.31 67.31,76.93 67.18,76.8 66.04,76.8 65.41,76.17 ; 3 cut-outs
GND on BOTTOM: 51.69,40.73 50.8,41.62 50.8,43.02 50.93,43.15 59.18,43.15 59.31,43.02 59.31,40.86 59.18,40.73 ; 1 cut-out
GND on BOTTOM: 45.47,68.55 45.34,68.67 45.34,70.2 45.72,70.58 45.72,73.63 45.85,73.75 54.48,73.75 54.74,73.5 54.74,72.36 54.1,71.72 49.91,71.72 49.66,71.47 49.66,69.69 49.4,69.44 47.12,69.44 46.99,69.31 46.99,68.67 46.86,68.55 ; 3 cut-outs
GND on BOTTOM: 37.21,91.03 37.08,91.15 37.08,92.8 37.21,92.93 38.86,92.93 39.12,92.68 39.12,91.15 38.99,91.03
GND on BOTTOM: 22.48,49.62 21.59,50.51 14.73,50.51 14.61,50.64 14.61,51.66 13.72,52.55 4.32,52.55 4.19,52.67 4.19,54.96 4.45,55.21 10.92,55.21 11.43,54.7 12.45,54.7 13.21,55.47 13.21,57.12 13.34,57.24 15.62,57.24 15.88,56.99 15.88,54.7 18.16,52.42 22.1,52.42 22.35,52.16 22.35,50.64 22.86,50.13 24.38,50.13 24.38,49.62 ; 4 cut-outs
GND on BOTTOM: 30.35,73.5 29.72,74.14 28.57,74.14 28.45,74.26 28.45,74.9 28.96,74.9 28.96,75.41 29.08,75.53 30.23,75.53 30.99,76.29 33.66,76.29 33.78,76.17 33.78,75.15 34.54,74.39 34.54,73.63 34.42,73.5
GND on BOTTOM: 88.27,66.13 87.88,66.52 87,66.52 86.11,67.4 86.11,68.93 86.23,69.06 86.23,69.82 86.49,70.07 87,70.07 87.38,69.69 90.55,69.69 90.68,69.56 90.68,67.79 90.55,67.66 88.9,67.66 88.65,67.4 88.65,66.26 88.52,66.13
GND on BOTTOM: 75.18,69.01 74.78,69.41 73.94,69.41 73.83,69.52 73.83,69.71 73.9,69.78 74.35,69.78 74.59,70.02 74.59,70.62 74.75,70.78 74.88,70.78 75.06,70.6 75.06,69.95 75.56,69.44 75.56,69.11 75.46,69.01
GND on BOTTOM: 73.91,28.29 73.79,28.42 73.79,33.75 73.91,33.88 88.01,33.88 90.04,35.91 92.84,35.91 94.36,34.38 94.36,31.34 93.09,30.07 90.04,30.07 89.41,30.7 84.07,30.7 82.42,29.05 82.42,28.42 82.3,28.29
GND on BOTTOM: 137.29,40.1 137.03,40.35 137.03,41.75 137.16,41.88 138.68,41.88 138.81,41.75 138.81,40.23 138.68,40.1
GND on BOTTOM: 4.45,36.16 4.32,36.29 4.32,37.31 4.45,37.43 13.84,37.43 14.61,38.19 14.61,39.85 15.62,40.86 15.62,41.62 15.88,41.88 16.76,41.88 17.4,41.24 18.03,41.24 18.16,41.12 18.16,40.86 18.03,40.73 17.53,40.73 17.27,40.48 17.27,39.34 18.16,38.45 22.23,38.45 22.35,38.32 22.35,37.56 22.23,37.43 18.03,37.43 16.76,36.16 ; 1 cut-out
GND on BOTTOM: outline of 158 points within 71.15,46.86 75.56,68.63
GND on L2VCC: outline of 167 points within 0.51,0.51 168.59,115.49 ; 5 cut-outs
GND on L3: 62.99,46.2 62.99,45.69 63.25,45.43 67.18,45.43 67.31,45.56 67.31,46.2 67.18,46.32 63.12,46.32
GND on L3: 106.68,106.14 106.68,102.2 106.93,101.95 110.62,101.95 110.74,102.08 110.74,106.39 110.62,106.52 107.06,106.52
GND on L3: outline of 237 points within 0.64,0.73 168.4,115.16
GND on L3: 23.88,65.5 24.26,65.5 24.77,64.99 24.77,60.8 24.51,60.55 23.75,60.55 23.62,60.67 23.62,61.18 23.75,61.31 24.26,61.31 24.38,61.44 24.38,62.71 24.26,62.83 23.88,62.83 23.75,62.96 23.75,63.21 23.88,63.34 24.26,63.34 24.38,63.47 24.38,64.61 24.13,64.86 23.88,64.86 23.75,64.99 23.75,65.37
GND on L4: 107.06,106.52 110.62,106.52 110.74,106.39 110.74,102.08 110.62,101.95 106.93,101.95 106.68,102.2 106.68,106.14
GND on L4: 4.45,36.16 16.64,36.16 17.91,37.43 21.59,37.43 22.35,38.19 23.11,38.19 24.26,37.05 24.26,34.89 24.38,34.77 26.67,34.77 26.8,34.89 26.8,35.15 19.94,42 19.94,48.35 17.65,50.64 17.65,65.25 15.37,67.53 15.37,71.47 14.1,72.74 14.1,74.9 13.84,75.15 13.34,75.15 12.95,75.53 12.95,76.93 12.7,77.18 12.7,82.26 12.45,82.52 11.56,82.52 9.91,80.87 9.91,76.93 10.41,76.42 10.41,75.28 9.65,74.52 3.05,74.52 2.79,74.26 2.79,71.34 3.05,71.09 3.56,71.09 3.94,70.71 10.79,70.71 11.18,71.09 12.83,71.09 13.34,70.58 13.34,55.47 12.57,54.7 11.43,54.7 10.92,55.21 4.32,55.21 4.19,55.09 4.19,52.67 4.45,52.42 13.97,52.42 14.61,51.78 14.61,50.77 14.1,50.26 14.1,39.72 14.61,39.21 14.61,38.19 13.84,37.43 4.57,37.43 4.32,37.18 4.32,36.29 ; 2 cut-outs
GND on L4: outline of 149 points within 0.76,0.73 168.28,115.16 ; 1 cut-out
GND on L5GND: outline of 167 points within 0.51,0.51 168.59,115.49
VCC_CORE on TOP: 50.93,43.02 50.42,43.53 50.42,49.88 47.75,52.55 47.75,57.88 48.01,58.13 56.26,58.13 58.17,56.23 63.75,56.23 66.67,59.15 68.45,59.15 71.88,62.58 71.88,65.75 73.79,67.66 76.96,67.66 77.22,67.4 77.22,48.99 77.47,48.74 85.47,48.74 85.6,48.61 85.6,47.34 85.22,46.96 76.71,46.96 75.06,45.31 74.42,45.31 73.91,45.81 73.53,45.81 70.74,43.02 ; 35 cut-outs
VCC_CORE on BOTTOM: 50.8,43.4 50.42,43.78 50.42,49.88 47.75,52.55 47.75,57.88 48.01,58.13 55.5,58.13 55.88,57.75 55.88,54.45 56.39,53.94 64.39,53.94 64.64,53.69 64.64,50.64 62.99,48.99 59.82,48.99 59.31,48.48 59.31,43.66 59.05,43.4 ; 2 cut-outs
VCC_CORE on BOTTOM: outline of 168 points within 73.42,46.53 86.36,69.42
VCC_CORE on L2VCC: 50.62,43.34 50.36,43.61 50.36,49.96 47.69,52.62 47.69,57.8 47.96,58.07 51.26,58.07 56.47,63.28 62.56,63.28 63.07,63.79 66.75,63.79 67.13,64.17 71.2,64.17 74.63,67.6 76.76,67.6 77.15,67.2 77.15,49.04 77.52,48.67 85.39,48.67 85.66,48.4 85.66,47.29 85.27,46.89 76.63,46.89 75.87,46.13 73.45,46.13 70.66,43.34
VCC_CORE on L3: 64.39,61.56 70.87,61.56 73.53,64.23 73.53,65.75 75.31,67.53 76.83,67.53 77.09,67.28 77.09,49.62 78.74,47.97 78.74,47.08 77.22,45.56 77.22,43.4 76.83,43.02 70.74,43.02 67.18,46.58 62.23,46.58 59.56,43.91 51.69,43.91 50.55,45.05 50.55,50.51 50.8,50.77 54.36,50.77 57.91,54.32 57.91,55.09
0D675V_PWR on TOP: 134.49,73.37 134.37,73.5 134.37,76.17 134.49,76.29 135.76,76.29 135.89,76.17 135.89,73.5 135.76,73.37 ; 2 cut-outs
0D675V_PWR on BOTTOM: 134.49,72.99 134.37,73.12 134.37,75.66 134.49,75.79 135.89,75.79 135.89,73.63 136.02,73.5 136.53,73.5 136.65,73.63 136.65,75.79 136.91,75.79 136.91,73.25 136.65,72.99
0D675V_S0 on TOP: 134.49,76.55 134.37,76.68 134.37,78.33 131.44,81.25 131.44,95.98 130.56,96.87 125.98,96.87 125.48,97.38 125.48,98.9 125.6,99.03 130.3,99.03 132.72,96.61 132.72,82.01 135.89,78.83 135.89,76.68 135.76,76.55 ; 5 cut-outs
1D05S_VCCST on TOP: 83.95,65.12 83.82,65.25 83.82,67.4 83.95,67.53 83.95,68.04 84.07,68.17 85.09,68.17 85.6,67.66 85.6,67.02 85.47,66.9 84.84,66.9 84.71,66.77 84.71,65.25 84.58,65.12 ; 2 cut-outs
1D05S_VCCST on BOTTOM: 69.98,36.42 69.09,37.31 69.09,39.21 70.23,40.35 70.87,40.35 70.99,40.23 70.99,39.85 70.74,39.59 70.74,37.05 70.87,36.92 71.75,36.92 72.64,37.81 72.64,37.18 71.88,36.42
1D05V_HSIO on TOP: 61.21,69.56 60.96,69.82 60.96,73.25 61.09,73.37 63.25,73.37 63.37,73.25 63.37,70.83 62.1,69.56
1D05V_HSIO on BOTTOM: 61.34,69.56 61.21,69.69 59.44,69.69 59.31,69.82 59.31,70.96 59.44,71.09 60.07,71.09 60.58,71.6 60.58,72.99 60.71,73.12 61.59,73.12 61.98,72.74 62.99,72.74 63.12,72.61 63.12,69.94 62.74,69.56
1D05V_PWR_PH on BOTTOM: 48.26,81.76 46.61,83.41 45.47,83.41 45.47,84.55 47.24,84.55 48.77,86.07 51.56,86.07 51.82,85.82 51.82,82.01 51.56,81.76
1D05V_S0 on TOP: 63.37,67.02 62.23,68.17 60.33,68.17 58.29,70.2 58.29,78.71 58.55,78.96 59.82,78.96 60.07,78.71 60.07,78.07 60.33,77.82 60.96,77.82 61.72,77.06 61.72,73.75 61.59,73.63 60.83,73.63 60.58,73.37 60.58,69.82 61.09,69.31 63.25,69.31 64.14,68.42 65.41,68.42 65.66,68.17 65.66,67.28 65.41,67.02 ; 2 cut-outs
1D05V_S0 on BOTTOM: 58.8,75.02 58.67,75.15 58.67,76.29 58.29,76.68 58.29,80.49 58.04,80.74 54.23,80.74 53.85,81.12 53.85,85.69 54.23,86.07 59.31,86.07 60.07,85.31 60.07,76.68 60.83,75.91 60.83,75.15 60.71,75.02 ; 4 cut-outs
1D05V_S0 on L2VCC: 60.15,68.36 56.71,71.8 56.71,84.6 56.85,84.74 69.14,84.74 76.63,77.25 85.39,77.25 86.04,76.6 86.04,69.77 85.27,68.99 63.17,68.99 62.53,68.36
1D35V_S3 on TOP: 93.85,51.66 93.6,51.91 93.6,52.42 92.84,53.18 90.55,53.18 90.42,53.31 90.42,55.59 90.55,55.72 90.55,57.5 90.17,57.88 89.79,57.88 89.03,58.64 87.38,58.64 87.12,58.9 87.12,61.05 86.36,61.82 86.36,62.2 87.12,62.96 88.52,62.96 89.15,63.59 93.73,63.59 94.36,62.96 111.12,62.96 122.17,74.01 123.19,74.01 123.32,73.88 123.32,72.87 124.21,71.98 128.02,71.98 128.52,72.48 133.1,72.48 135,70.58 135,67.02 136.27,65.75 136.27,59.02 135.51,58.26 133.35,58.26 132.21,57.12 123.83,57.12 118.36,51.66 ; 64 cut-outs
1D35V_S3 on BOTTOM: 137.29,57.24 135.76,58.77 133.35,58.77 133.1,59.02 133.1,73.88 133.22,74.01 133.99,74.01 134.11,73.88 134.11,72.99 134.37,72.74 136.78,72.74 137.16,73.12 137.16,75.79 137.92,75.79 137.92,71.85 137.67,71.6 134.24,71.6 134.11,71.47 134.11,63.59 134.24,63.47 138.56,63.47 138.94,63.09 140.46,63.09 141.1,62.45 141.1,57.37 140.97,57.24 ; 2 cut-outs
1D35V_S3 on L3: 85.6,66.9 87.38,66.9 89.03,65.25 89.03,62.45 89.28,62.2 90.17,62.2 90.42,61.94 90.42,61.56 88.27,59.4 85.72,59.4 85.34,59.78 85.34,66.64
3D3V_AUX_KBC on L4: 92.58,24.35 95.63,24.35 96.01,23.97 96.01,23.21 95.89,23.08 92.08,23.08 91.95,23.21 91.95,23.72
3D3V_CAMERA_S0 on BOTTOM: 41.15,91.15 41.02,91.28 41.02,92.93 42.8,94.71 46.23,94.71 46.23,92.93 45.09,91.79 42.67,91.79 42.04,91.15 ; 4 cut-outs
3D3V_S0 on TOP: 51.82,98.27 51.69,98.39 51.69,101.31 51.56,101.44 50.93,101.44 50.8,101.57 50.8,102.58 50.93,102.71 53.34,102.71 53.47,102.58 53.47,98.39 53.34,98.27 ; 1 cut-out
3D3V_S0 on TOP: 63.37,79.6 62.61,80.36 62.61,82.39 62.48,82.52 61.59,82.52 61.34,82.26 61.34,81.12 61.09,80.87 59.94,80.87 59.82,80.99 59.82,81.88 60.96,83.03 62.74,83.03 62.99,83.28 62.99,85.69 65.79,88.49 67.31,88.49 67.44,88.61 67.44,90.39 67.56,90.52 68.83,90.52 68.96,90.39 68.96,84.3 69.22,84.04 70.23,84.04 70.48,84.3 70.99,84.3 71.12,84.17 71.12,82.14 70.99,82.01 70.61,82.01 70.48,82.14 70.48,82.64 70.36,82.77 67.44,82.77 67.31,82.64 67.31,81.88 67.18,81.76 66.42,81.76 66.29,81.88 66.29,83.15 65.91,83.53 64.77,83.53 64.52,83.28 64.52,79.72 64.39,79.6 ; 4 cut-outs
3D3V_S0 on TOP: 75.31,37.31 74.93,37.69 74.17,37.69 74.04,37.81 74.04,38.58 74.17,38.7 77.85,38.7 78.23,38.32 83.44,38.32 84.71,39.59 84.96,39.59 85.22,39.85 85.22,43.4 85.72,43.91 86.87,43.91 87.5,43.27 87.5,39.21 87.12,38.83 85.47,38.83 83.95,37.31
3D3V_S0 on TOP: 33.02,91.92 33.02,93.69 33.27,93.95 34.04,93.95 35.18,95.09 35.69,95.09 36.32,95.73 38.73,95.73 38.86,95.6 38.86,93.44 37.34,91.92
3D3V_S0 on BOTTOM: 62.99,82.64 62.87,82.77 62.87,83.28 63.63,84.04 63.63,84.8 63.12,85.31 63.12,87.98 63.63,88.49 66.67,88.49 67.06,88.87 68.83,88.87 68.96,88.74 68.96,87.47 68.45,86.96 68.45,86.71 68.33,86.58 67.82,86.58 66.42,87.98 64.64,87.98 64.52,87.85 64.52,85.31 64.64,85.18 65.79,85.18 66.04,85.44 66.55,85.44 66.67,85.31 66.67,82.9 66.42,82.64 ; 3 cut-outs
3D3V_S0 on BOTTOM: 39.37,91.15 39.24,91.28 39.24,93.06 39.12,93.19 37.08,93.19 36.58,92.68 36.58,91.41 36.45,91.28 34.04,91.28 33.91,91.41 33.91,94.33 34.54,94.96 39.88,94.96 40.64,94.2 40.64,91.41 40.39,91.15
3D3V_S0 on BOTTOM: 149.48,63.09 148.46,64.1 146.3,64.1 146.18,64.23 145.92,64.23 144.91,65.25 144.91,65.63 145.03,65.75 145.16,65.75 145.29,65.88 149.48,65.88 149.99,65.37 153.03,65.37 153.42,65.75 154.94,65.75 155.19,65.5 155.19,63.59 154.94,63.34 154.05,63.34 153.8,63.09
3D3V_S0 on BOTTOM: 105.66,26.13 105.41,26.38 105.41,27.91 105.54,28.03 107.06,28.03 107.57,27.53 107.57,26.38 107.31,26.13 ; 1 cut-out
3D3V_S0 on BOTTOM: 80.14,107.16 79.38,107.92 79.38,108.93 83.19,112.74 112.78,112.74 113.03,113 113.03,113.63 113.28,113.89 115.19,113.89 115.44,113.63 115.44,111.22 115.06,110.84 92.71,110.84 92.08,110.2 91.06,110.2 90.3,110.97 84.84,110.97 81.03,107.16
3D3V_S0 on L2VCC: 40.97,91.85 39.58,93.25 38.28,93.25 37.64,92.61 35.64,92.61 35.24,93.01 35.24,94.76 36.53,96.04 42.85,96.04 44.12,94.77 64.34,94.77 69.17,99.6 74.37,99.6 80.33,105.55 80.33,108.22 80.85,108.74 81.84,108.74 82.99,107.59 82.99,103.93 76.12,97.06 73.07,97.06 67.87,91.85
3D3V_S0 on L2VCC: 154,63.66 153.73,63.93 153.73,64.66 153.99,64.91 153.99,66.72 153.3,67.41 141.41,81.32 141.41,85.9 140.02,87.3 140.02,100.12 137.45,102.69 137.44,102.72 137.4,102.74 137.37,102.77 137.33,102.77 129.27,106.43 129.24,106.46 129.2,106.46 129.17,106.47 129.12,106.46 116.66,106.46 113.22,109.9 113.22,113.68 113.49,113.95 115.11,113.95 115.51,113.55 115.51,110.89 117.65,108.74 130,108.74 137.44,105.09 142.18,101.1 142.18,87.9 142.96,87.12 143.44,84.95 143.43,84.94 143.45,84.88 143.47,84.81 143.48,84.81 143.95,83.5 143.95,81.64 143.95,81.57 143.95,81.55 144,81.5 147,77.76 147,77.75 147.05,77.7 147.09,77.64 147.1,77.64 155.51,67.97 155.51,67.96 155.56,67.91 155.61,67.86 155.62,67.85 156.27,67.2 156.27,63.66
3D3V_S5 on TOP: 76.58,109.82 76.45,109.95 76.45,111.6 76.33,111.73 75.69,111.73 75.56,111.6 75.56,110.97 75.31,110.71 73.15,110.71 73.03,110.84 73.03,112.24 73.91,113.12 77.34,113.12 77.6,112.87 77.6,111.73 77.47,111.6 77.47,109.95 77.34,109.82 ; 2 cut-outs
3D3V_S5 on TOP: 40.89,93.82 40.64,94.07 40.64,94.58 42.55,96.49 42.55,99.54 43.31,100.3 43.31,102.33 43.56,102.58 44.2,102.58 44.32,102.46 44.32,96.74 41.4,93.82 ; 2 cut-outs
3D3V_S5 on TOP: 70.1,35.91 69.98,36.04 69.98,37.43 70.48,37.94 73.41,37.94 74.04,37.31 74.68,37.31 75.18,36.8 75.18,36.04 75.06,35.91
3D3V_S5 on TOP: 35.56,85.69 34.54,86.71 33.27,86.71 33.02,86.96 33.02,90.65 38.73,90.65 38.99,90.39 38.99,85.82 38.86,85.69
3D3V_S5 on BOTTOM: 102.87,24.35 102.74,24.48 102.74,25.24 102.62,25.37 101.85,25.37 101.73,25.49 101.73,26 101.98,26.26 103.25,26.26 103.89,26.89 103.89,27.78 104.14,28.03 104.9,28.03 105.03,27.91 105.03,26.13 104.39,25.49 104.39,24.73 104.01,24.35 ; 1 cut-out
3D3V_S5 on BOTTOM: 35.56,82.26 35.31,82.52 35.31,90.52 35.56,90.77 38.73,90.77 38.99,90.52 38.99,87.34 39.24,87.09 39.75,87.09 40.01,86.84 40.01,82.9 39.37,82.26 ; 2 cut-outs
3D3V_S5 on L3: 38.86,94.84 41.53,94.84 41.78,94.58 41.78,93.95 41.53,93.69 39.37,93.69 37.85,92.17 37.85,85.82 37.72,85.69 35.43,85.69 34.92,86.2 34.92,90.9
3D3V_S5 on L3: 37.59,46.96 39.88,46.96 40.51,47.59 46.99,47.59 47.88,46.7 47.88,46.07 47.24,45.43 36.83,45.43 34.67,47.59 34.67,47.97 30.23,52.42 30.23,58.39 32,60.17 32.51,60.17 33.02,59.66 33.02,59.28 31.75,58.01 31.75,53.18 34.29,50.64 36.7,50.64 36.96,50.39 36.96,49.62 36.45,49.12 36.45,48.1
3D3V_S5 on L4: 35.56,89.76 38.61,89.76 38.86,89.5 38.86,85.95 38.61,85.69 35.43,85.69 35.18,85.95 35.18,89.38
3D3V_S5_PCH on TOP: 76.58,104.49 76.45,104.62 76.45,107.54 76.33,107.66 75.56,107.66 74.42,108.81 73.41,108.81 73.03,109.19 73.03,110.08 73.15,110.2 75.18,110.2 76.07,109.31 77.85,109.31 78.23,108.93 78.23,104.62 78.11,104.49 ; 1 cut-out
3D3V_S5_PCH on TOP: 88.9,90.77 88.77,90.9 88.77,93.44 88.9,93.57 89.92,93.57 90.17,93.31 90.17,91.15 89.79,90.77
3D3V_S5_PCH on TOP: 102.49,82.01 102.36,82.14 102.36,84.8 102.87,85.31 102.87,86.33 103,86.45 104.01,86.45 104.9,85.57 106.93,85.57 107.44,85.06 107.44,84.42 107.31,84.3 105.41,84.3 103.12,82.01
3D3V_S5_PCH on BOTTOM: 88.9,90.77 88.77,90.9 88.77,93.44 88.9,93.57 90.93,93.57 91.06,93.44 91.06,90.9 90.93,90.77
3D3V_SEN_S0 on BOTTOM: 30.99,91.28 30.86,91.41 30.86,95.34 31.62,95.34 32.51,94.46 32.51,94.07 33.53,93.06 33.53,91.41 33.4,91.28 ; 3 cut-outs
+DC_IN on TOP: 34.92,29.94 33.66,31.21 31.11,31.21 30.23,32.1 30.23,33.11 27.05,36.29 25.78,36.29 18.16,43.91 18.16,63.47 18.8,64.1 18.8,64.61 20,65.82 20,66.83 20.95,67.79 20.95,68.8 21.59,69.44 21.59,77.31 21.34,77.56 21.34,80.87 21.46,80.99 24.89,80.99 25.02,80.87 25.02,72.48 25.65,71.85 25.65,55.97 24.38,54.7 24.38,50.51 27.62,47.28 27.62,44.8 27.3,44.48 27.3,43.66 29.08,41.88 29.59,41.88 32.19,39.27 32.7,39.27 35.69,36.29 38.35,36.29 38.99,35.65 38.99,30.45 38.48,29.94 ; 5 cut-outs
+DC_IN on BOTTOM: 23.5,72.1 21.59,74.01 21.59,77.31 21.34,77.56 21.34,80.87 21.46,80.99 24.89,80.99 25.02,80.87 25.02,72.48 24.64,72.1
+DC_IN on BOTTOM: 36.2,29.43 36.07,29.56 36.07,34.64 36.32,34.89 41.78,34.89 42.04,34.64 42.04,31.84 41.15,30.96 40.13,30.96 40.01,30.83 40.01,29.43 ; 1 cut-out
+DC_IN_C on TOP: 21.46,81.5 21.34,81.63 21.34,83.79 19.81,85.31 19.81,88.61 20.07,88.87 23.5,88.87 23.75,88.61 23.75,85.18 24.51,84.42 24.51,83.28 24.77,83.03 24.77,81.63 24.64,81.5 ; 3 cut-outs
+DC_IN_C on BOTTOM: 21.46,81.5 21.34,81.63 21.34,83.79 20.32,84.8 20.32,86.07 20.83,86.58 20.83,88.74 20.95,88.87 23.5,88.87 23.75,88.61 23.75,85.18 24.51,84.42 24.51,83.28 24.77,83.03 24.77,81.63 24.64,81.5
+SDC_IN on BOTTOM: 43.18,22.57 42.8,22.95 41.53,22.95 41.53,25.62 42.55,26.64 44.83,26.64 44.96,26.51 44.96,22.7 44.83,22.57
+V_SM_VREF_CNT on TOP: 98.81,39.72 93.6,44.93 93.6,46.07 93.09,46.58 93.09,47.85 91.69,49.24 91.06,49.24 90.04,50.26 90.04,51.66 90.17,51.78 90.93,51.78 91.19,51.53 91.19,50.26 91.44,50.01 92.2,50.01 94.49,47.72 94.49,46.83 94.74,46.58 95.38,46.58 100.58,41.37 100.58,40.23 100.08,39.72
+V_SM_VREF_CNT on BOTTOM: 139.06,63.34 138.94,63.47 138.94,64.74 139.06,64.86 140.46,64.86 140.59,64.74 140.59,63.47 140.46,63.34 ; 1 cut-out
+VCHGR on TOP: 81.03,20.8 78.99,22.83 77.34,22.83 77.09,23.08 77.09,23.97 79.25,26.13 79.25,27.02 80.52,28.29 85.72,28.29 85.85,28.16 85.85,21.43 85.22,20.8 ; 1 cut-out
+VCHGR on BOTTOM: 81.03,20.8 79.12,22.7 77.22,22.7 76.83,23.08 76.83,27.78 77.09,28.03 82.17,28.03 82.8,27.4 82.8,25.37 82.93,25.24 84.2,25.24 84.2,21.05 83.95,20.8
AD+ on BOTTOM: 36.45,21.81 36.2,22.07 36.2,24.48 36.07,24.61 35.56,24.61 35.43,24.73 35.43,25.75 35.56,25.88 37.34,25.88 37.72,26.26 37.72,28.92 37.85,29.05 41.15,29.05 41.15,21.81 ; 3 cut-outs
AUD_AGND on TOP: 20.35,27.22 20.29,27.27 20.29,28.14 20.4,28.24 21.06,28.24 21.34,27.96 21.34,27.25 21.31,27.22
AUD_AGND on TOP: 20.95,16.99 20.57,17.37 20.57,17.75 19.56,18.76 16.76,18.76 13.34,22.19 3.3,22.19 3.17,22.32 3.17,23.84 3.43,24.1 14.35,24.1 15.11,24.86 15.11,26 14.61,26.51 14.61,31.21 15.11,31.72 15.11,32.73 16.38,34 18.03,34 18.16,33.88 18.16,33.5 18.03,33.37 16.26,33.37 15.88,32.99 15.88,31.59 16.13,31.34 18.41,31.34 18.8,30.96 18.8,30.07 18.67,29.94 18.16,29.94 17.65,30.45 16.26,30.45 15.75,29.94 15.75,29.05 16,28.8 18.54,28.8 18.67,28.67 18.67,28.03 18.54,27.91 16.64,27.91 16.51,27.78 16.51,26.64 16.64,26.51 17.27,26.51 17.4,26.38 17.4,26 17.27,25.88 16.64,25.88 15.62,24.86 15.62,22.32 16.76,21.18 17.53,21.18 18.8,19.91 20.19,19.91 20.32,19.78 20.32,19.02 20.7,18.64 21.34,18.64 21.46,18.51 21.46,17.49 21.34,17.37 21.34,17.11 21.21,16.99 ; 3 cut-outs
AUD_AGND on TOP: 21.77,20.62 21.49,20.9 21.49,21.2 21.97,21.68 21.97,22.57 22.17,22.57 22.17,21.58 22.25,21.51 22.25,20.69 22.17,20.62
AUD_AGND on BOTTOM: 19.56,24.1 19.18,24.48 19.18,27.78 19.56,28.16 24.89,28.16 25.65,28.92 25.65,29.56 26.04,29.94 27.05,29.94 27.18,29.81 27.18,28.67 26.16,27.65 21.84,27.65 21.34,27.15 21.34,24.22 21.21,24.1 ; 2 cut-outs
AUD_AGND on L2VCC, L5GND: 21.15,16.76 20.47,17.43 20.47,17.81 19.62,18.66 16.83,18.66 13.4,22.09 2.91,22.09 2.91,23.9 3.05,24.25 3.4,24.39 13.85,24.39 14.82,25.14 14.36,26.27 14.36,31.38 14.82,32.51 13.85,33.26 3.4,33.26 3.05,33.4 2.91,33.75 2.91,34.79 2.98,35.05 3.18,35.23 3.51,35.45 3.77,35.76 16.83,35.76 18.1,37.03 23.69,37.03 23.85,36.86 23.85,34.7 24.07,34.49 26.61,34.49 27.15,33.94 27.15,28.61 26.1,27.55 21.78,27.55 21.44,27.21 21.44,24.16 21.27,24 19.75,24 18.14,22.38 18.14,20.61 18.73,20.01 20.89,20.01 21.62,20.73 21.62,20.99 22,21.37 22,22.51 22.16,22.68 22.8,22.68 22.96,22.51 22.96,16.92 22.8,16.76
AUD_SPK_L+ on BOTTOM: 18.41,13.18 18.16,13.43 18.16,14.95 18.29,15.08 19.05,15.08 19.18,14.95 19.18,14.57 19.3,14.45 20.32,14.45 20.45,14.32 20.45,13.68 19.94,13.18 ; 1 cut-out
AUD_SPK_L- on BOTTOM: 19.43,14.57 19.3,14.7 19.3,15.08 19.05,15.33 18.29,15.33 18.16,15.46 18.16,16.22 18.29,16.35 19.81,16.35 19.94,16.22 19.94,15.59 20.32,15.21 20.32,14.83 20.07,14.57 ; 1 cut-out
AUD_SPK_R+ on TOP: 18.16,7.59 18.03,7.71 18.03,8.6 17.78,8.86 17.53,8.86 17.4,8.98 17.4,9.75 17.53,9.87 18.92,9.87 19.05,9.75 19.05,7.71 18.92,7.59 ; 2 cut-outs
AUD_SPK_R- on TOP: 18.16,5.3 18.03,5.43 18.03,7.21 18.16,7.33 18.92,7.33 19.05,7.21 19.05,6.44 19.18,6.32 19.43,6.32 19.56,6.19 19.56,5.43 19.43,5.3 ; 1 cut-out
BQ24770_AGND on BOTTOM: 38.48,11.02 36.96,12.54 36.96,12.92 36.58,13.3 35.56,13.3 35.31,13.56 35.31,14.7 37.21,16.6 38.61,16.6 40.26,14.95 44.32,14.95 46.61,17.24 48.39,17.24 48.51,17.11 48.51,14.06 48.39,13.94 47.12,13.94 45.34,12.16 39.88,12.16 38.73,11.02
BT+ on TOP: 86.74,17.24 86.36,17.62 86.36,19.65 86.23,19.78 86.23,27.91 86.36,28.03 87.88,28.03 89.92,26 89.92,24.48 90.3,24.1 90.68,24.1 91.44,23.34 91.44,19.02 91.19,18.76 91.19,17.49 90.93,17.24
BT+ on BOTTOM: 86.74,17.24 86.36,17.62 86.36,19.65 84.58,21.43 84.58,26.51 84.71,26.64 87.63,26.64 88.14,27.15 88.65,27.15 90.04,25.75 90.04,22.83 91.44,21.43 91.44,19.02 91.19,18.76 91.19,17.49 90.93,17.24 ; 4 cut-outs
CHARGER_SRC on BOTTOM: 46.99,21.43 45.85,22.57 45.59,22.57 45.47,22.7 45.47,26.51 45.59,26.64 46.61,26.64 47.24,26 55.63,26 55.63,25.24 54.36,25.24 54.1,24.99 54.1,23.72 54.74,23.08 54.74,21.56 54.61,21.43 ; 2 cut-outs
DCBATOUT on TOP: outline of 122 points within 25.91,16.73 111.51,99.54 ; 30 cut-outs
DCBATOUT on BOTTOM: 65.53,22.7 65.15,23.08 65.15,26.38 60.33,31.21 57.4,31.21 56.77,31.84 54.36,31.84 54.1,32.1 48.51,32.1 43.56,37.05 40.13,37.05 39.62,37.56 39.62,39.46 38.73,40.35 35.43,40.35 34.1,41.69 34.1,43.47 32.89,44.67 32.89,58.64 38.23,63.98 38.61,63.98 39.5,64.86 39.5,66.77 37.47,68.8 29.59,68.8 29.08,69.31 29.08,73.88 29.59,73.88 30.48,72.99 34.67,72.99 35.31,72.36 35.94,72.36 36.32,72.74 36.32,73.88 37.47,73.88 38.35,72.99 41.66,72.99 41.91,73.25 41.91,76.17 41.4,76.68 41.4,84.17 41.66,84.42 44.2,84.42 44.32,84.3 44.32,82.26 43.94,81.88 43.94,78.45 44.32,78.07 51.05,78.07 51.69,77.44 51.69,76.42 52.32,75.79 52.32,74.01 45.59,74.01 45.47,73.88 45.47,70.83 45.09,70.45 45.09,64.1 42.93,61.94 42.93,61.56 37.21,55.85 37.21,53.18 36.96,52.93 36.96,51.15 37.72,50.39 37.72,47.59 41.91,43.4 44.07,43.4 50.29,37.18 55.12,37.18 56.01,36.29 62.1,36.29 62.93,35.46 64.83,35.46 66.17,34.13 73.03,34.13 73.28,33.88 73.28,22.83 73.15,22.7 ; 10 cut-outs
DCBATOUT on BOTTOM: 109.6,16.73 109.35,16.99 109.35,19.14 109.6,19.4 120.9,19.4 121.4,18.9 121.41,18.92 131.22,18.92 131.7,19.4 139.83,19.4 140.46,20.03 140.46,29.69 139.45,30.7 139.45,39.08 139.57,39.21 142.37,39.21 142.49,39.08 142.49,31.84 143.13,31.21 143.13,17.37 142.49,16.73
DCBATOUT on L2VCC: 33.48,53.88 33.21,54.15 33.21,57.17 35.38,59.34 40.21,59.34 42.1,61.23 42.1,67.74 40.97,68.87 31.7,68.87 31.05,69.52 31.05,72.79 31.7,73.44 32.81,73.44 34.34,71.91 36.15,71.91 37.16,72.93 38.56,72.93 41.47,75.84 41.47,78.38 42.24,79.15 51.23,79.15 52.01,78.38 52.01,74.47 51.74,74.2 49.96,74.2 48.69,72.93 46.92,72.93 46.9,72.94 46.84,72.93 46.78,72.93 46.77,72.91 46.75,72.91 46.71,72.86 46.67,72.82 46.67,72.8 44.81,69.94 44.77,69.9 44.77,69.87 44.76,69.86 44.77,69.8 44.77,58.72 42.85,56.8 39.42,56.8 36.5,53.88
DCBATOUT_LCD on TOP: 66.17,93.06 65.91,93.31 65.91,99.54 66.04,99.66 68.2,99.66 68.33,99.54 68.33,93.19 68.2,93.06 ; 3 cut-outs
DCBATOUT_LCD on BOTTOM: 64.26,90.39 64.14,90.52 64.14,91.79 63.88,92.04 63.88,95.34 64.01,95.47 66.8,95.47 67.06,95.22 67.06,94.2 67.56,93.69 67.56,93.44 66.04,91.92 66.04,90.52 65.91,90.39
DDR_WR_VREF01 on TOP: 117.98,32.48 116.97,33.5 116.97,34.38 117.09,34.51 117.86,34.51 118.75,33.62 120.4,33.62 120.65,33.37 120.65,32.61 120.52,32.48 ; 2 cut-outs
DDR_WR_VREF01 on TOP: 93.34,49.12 92.2,50.26 91.44,50.26 91.31,50.39 91.31,51.15 91.44,51.28 92.71,51.28 94.11,49.88 94.11,49.62 93.6,49.12
FAN_VCC_1 on BOTTOM: 139.7,68.67 139.57,68.8 139.57,73.25 140.34,74.01 141.48,74.01 141.6,73.88 141.6,70.07 141.48,69.94 141.48,68.8 141.35,68.67 ; 4 cut-outs
